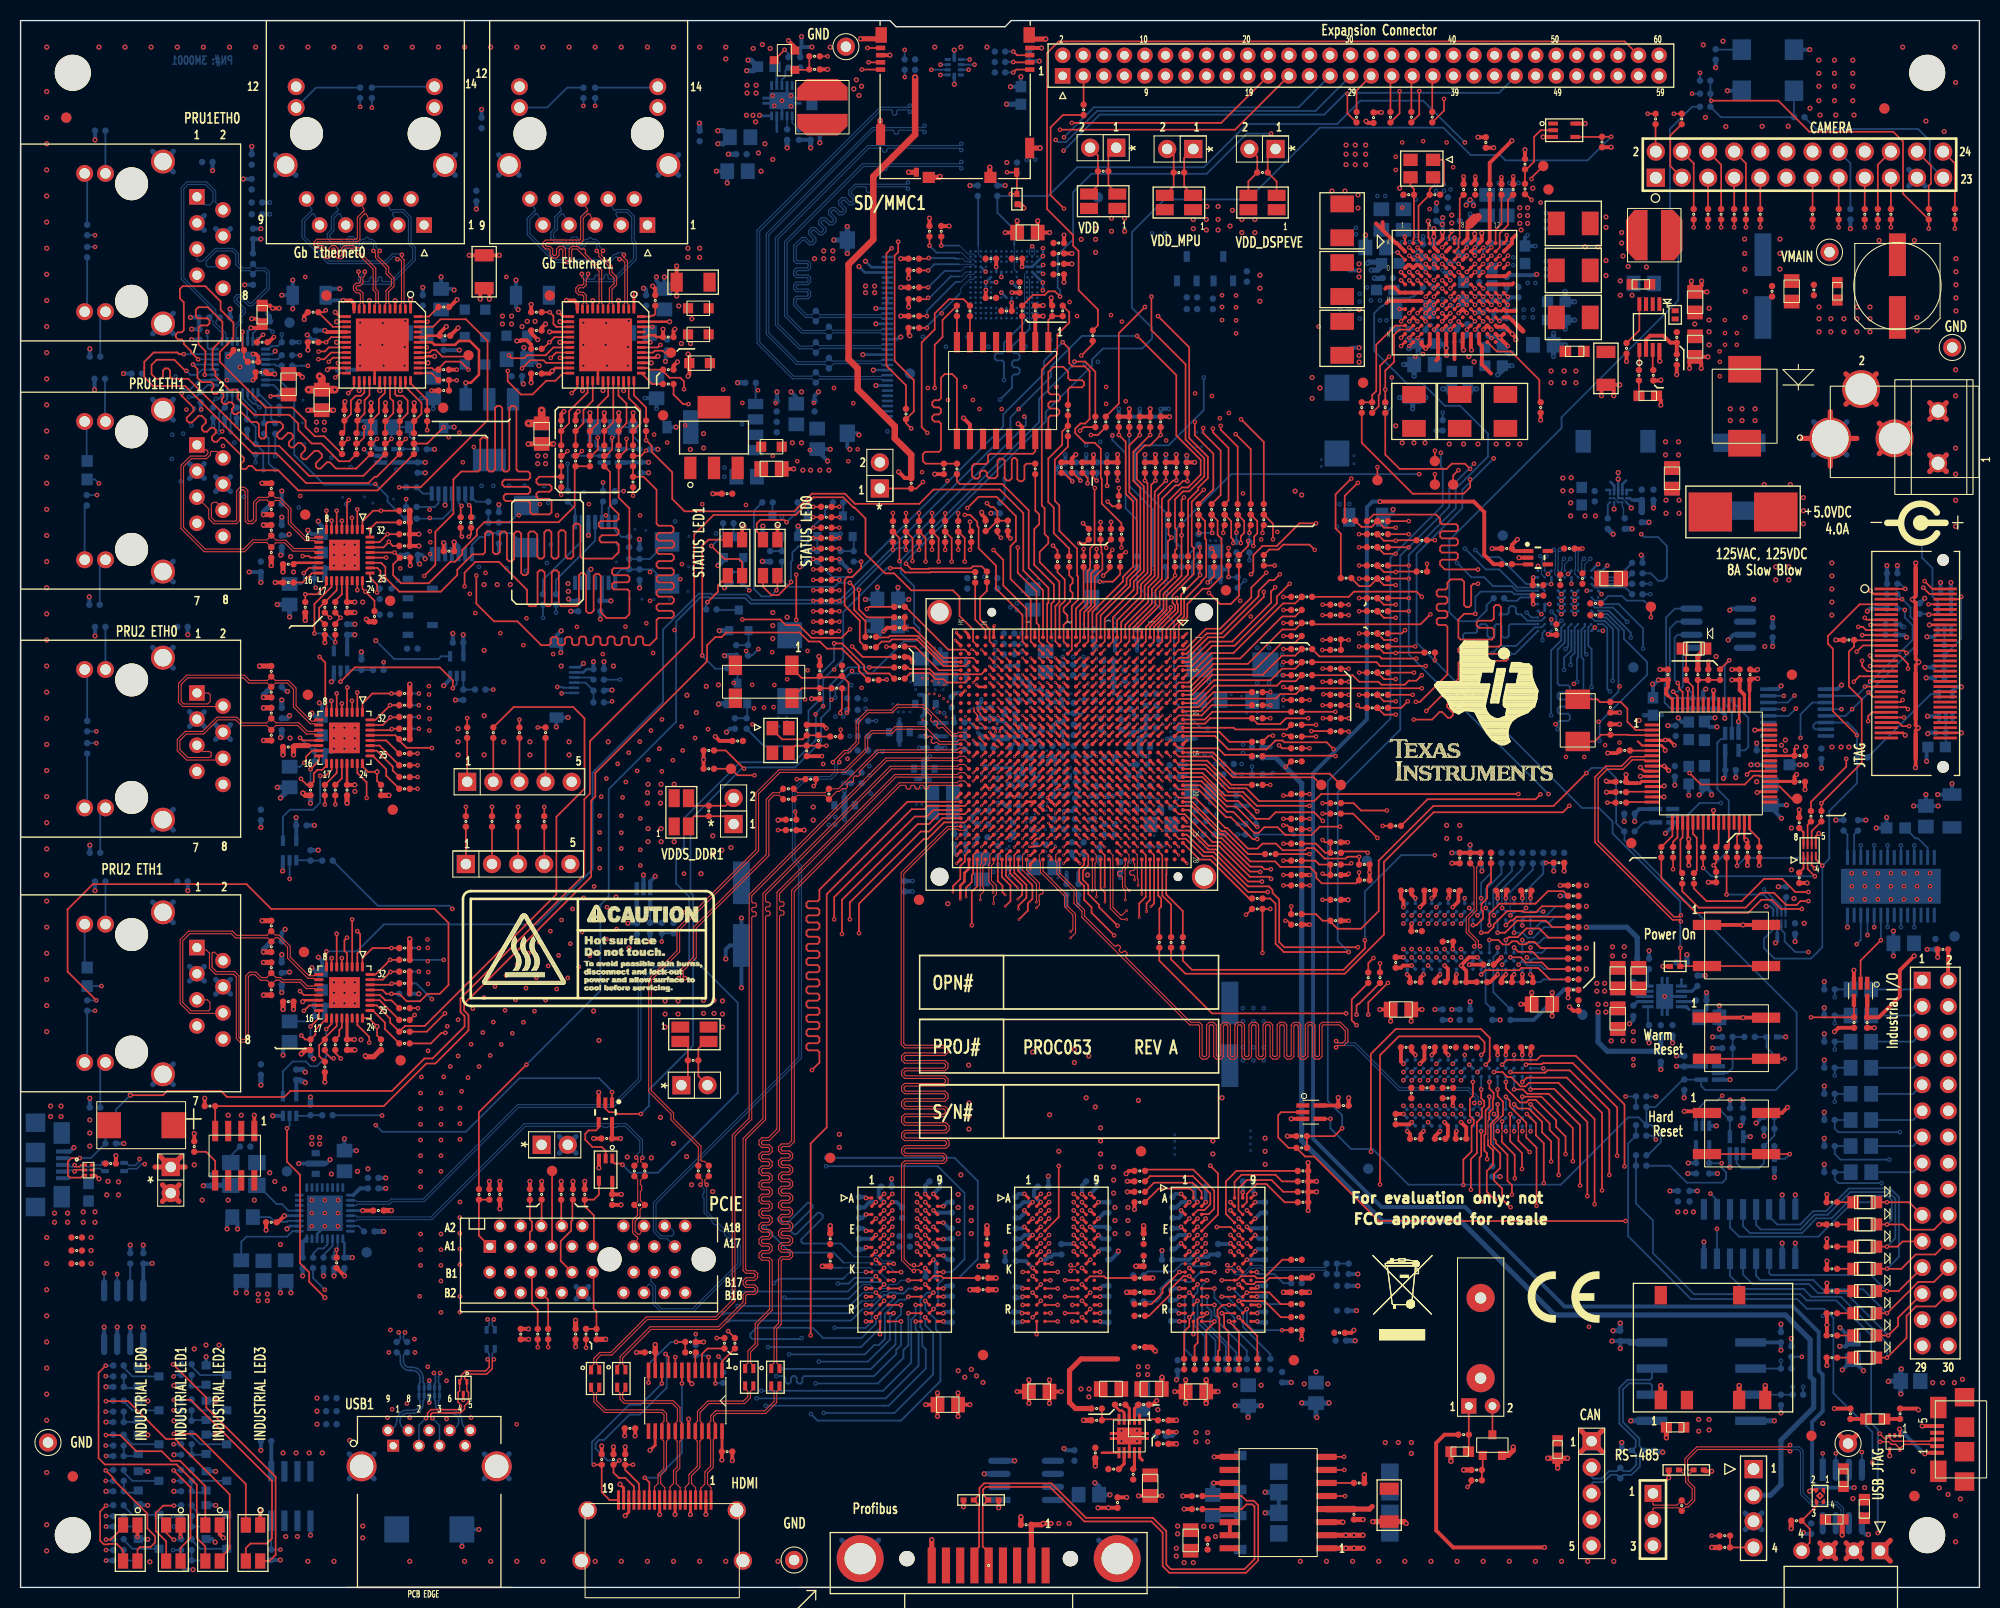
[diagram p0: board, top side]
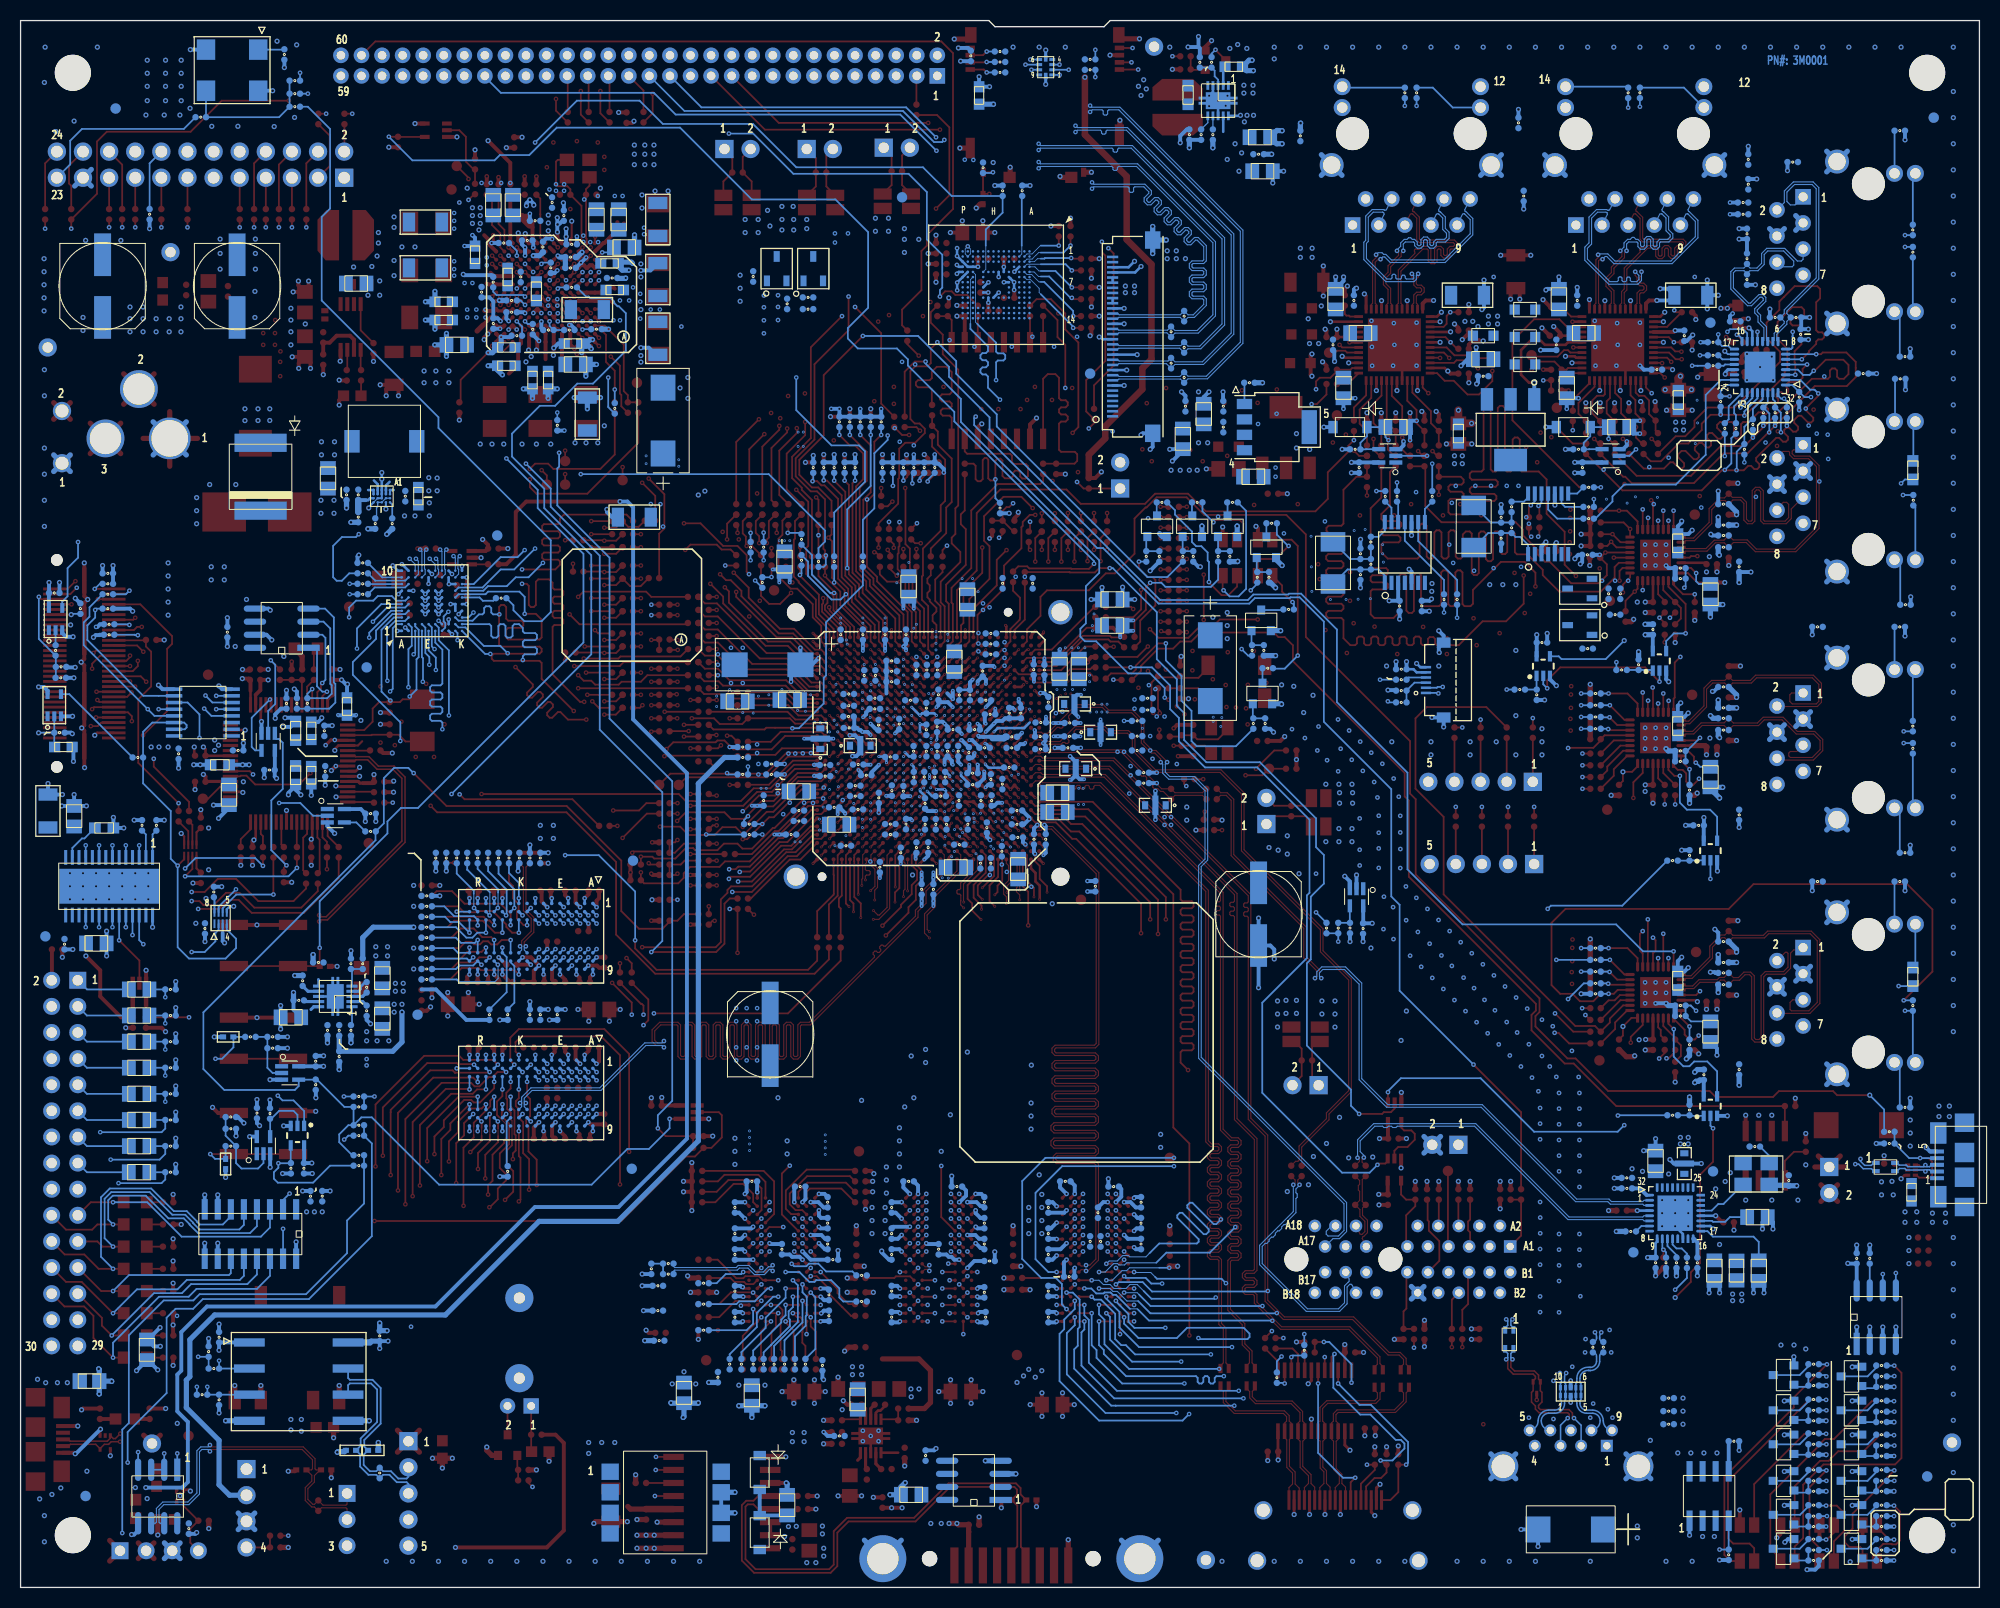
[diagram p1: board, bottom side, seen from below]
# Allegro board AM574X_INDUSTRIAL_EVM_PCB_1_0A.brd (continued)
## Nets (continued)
DGND: C1_1.2 C2_1.2 C3.2 C4.2 C5.2 C6.2 C7.2 C8.2 C9.2 C10.2 C11.2 C12.2 C13.2 C14.2 C15.2 C16.2 C17.2 C20.2 C21.2 C22.2 C23.2 C24.2(NEG) C25.1 C26.1 C27.1 C28.2 C29.2 C30.2 C31.2 C32.2 C33.2 C34.2 C35.2 C36.2 C37.2 C38.2 C39.2 C40.2 C41.2 C42.2 C43.2 C45.2 C46.2 C48.2 C49.2 C50.2 C51.2 C52.2 C53.2 C54.2 C55.2 C56.2 C57.2 C58.2 C59.2 C60.2 C61.2 C62.2 C63.2 C64.2 C65.2 C66.2 C67.2 C68.2 C69.2 C70.2 C71.2 C72.2 C73.2 C74.2 C75.2 C76.2 C77.2 C78.2 C79.2 C81.2 C82.2 C83.2 C84.2 C86.2 C88.2 C90.2 C91.2 C92.2 C93.2 C94.2 C95.2 C96.2 C97.2 C98.2 C99.2 C100.2 C101.2 C102.2 C103.2 C104.2 C105.2 C106.1 C107.2 C108.2 C109.2 C110.2 C111.2 C112.2 C113.2 C114.2 C115.2 C116.2 C117.2 C118.2 C119.2 C120.2 C121.1 C122.2 C123.2 C124.2 C125.2 C126.2 C127.2 C128.2 C129.2 C130.2 C131.1 C132.2 C133.2 C134.2 C135.2 C136.2 C137.2 C138.2 C139.2 C140.2 C141.2 C142.2 C143.2 C144.2 C145.2 C146.1 C147.2 C148.2 C149.2 C150.2 C151.2 C152.2 C153.2 C154.2 C155.2 C156.2 C157.2 C158.2 C159.2 C160.2 C161.2 C162.2 C163.2 C164.2 C165.2 C166.1 C167.1 C168.2 C169.2 C170.2 C171.2 C172.1 C173.1 C174.2 C175.2 C176.2 C177.2 C178.2 C179.2 C180.2 C181.2 C182.2 C183.2 C184.2 C185.2 C186.2 C187.1 C188.1 C189.2 C190.2 C191.2 C192.2 C193.1 C194.1 C195.2 C196.2 C197.2 C198.2 C199.2 C200.2 C201.2 C202.2 C203.2 C204.2 C205.2 C206.2 C207.2 C208.2 C209.2 C210.2 C211.2 C212.2 C213.2 C214.2 C215.2 C216.2 C217.2 C218.2 C219.2 C220.2 C221.2 C222.2 C223.2 C224.2 C225.2 C226.2 C227.2 C228.1 C229.2 C230.1 C231.1 C232.2 C233.2 C234.1 C235.2 C236.2 C237.1 C238.2 C239.2 C240.1 C241.2 C242.1 C243.2 C244.2 C245.2 C246.2 C247.2 C248.2 C249.2 C251.2 C253.2 C254.2 C255.2 C256.2 C257.2 C258.2 C261.2 C262.2 C263.2 C264.2 C265.2 C266.2 C267.2 C268.2 C269.2 C270.2 C271.2 C272.2 C273.2 C274.2 C275.2 C276.2 C277.2 C278.2 C279.2 C280.2 C281.2 C282.2 C283.2 C284.2 C285.2 C286.2 C287.2 C288.2 C289.2 C290.2 C291.2 C292.2 C293.2 C294.2 C295.2 C296.2 C297.2 C298.2 C299.2 C300.2 C301.2 C302.2 C303.2 C304.2 C305.2 C306.2 C307.2 C308.2 C309.2 C310.2 C311.2 C313.2 C315.2 C316.2 C317.2 C318.2 C319.2 C320.2 C321.2 C322.2 C324.2 C326.2 C327.2 C328.2 C329.2 C330.2 C331.2 C332.2 C333.2 C334.2 C335.2 C336.2 C337.2 C338.2 C339.2 C340.2 C341.2 C342.2 C343.2 C344.2 C345.2 C346.2 C347.2 C348.2 C349.2 C350.2 C351.2 C352.2 C353.2 C354.2 C355.2 C356.2 C357.2 C358.2 C359.2 C360.2 C361.2 C362.2 C363.2 C364.2 C365.2 C367.2 C368.2 C369.2 C370.2 C371.2 C372.2 C373.2 C374.2 C375.2 C376.2 C377.2 C378.2 C379.2 C380.2 C381.2 C382.2 C383.2 C384.2 C385.2 C386.2 C387.2 C388.2 C389.2 C390.2 C391.2 C392.2 C393.2 C394.2 C395.2 C396.2 C399.2 C400.2 C401.2 C402.2 C403.2 C404.2 C405.2 C406.2 C407.2 C408.2 C409.2 C410.2 C411.2(NEG) C412.2(NEG) C413.2 C414.2 C415.2 C416.2 C417.2 C418.2 C419.2 C420.2 C421.2 C422.2 C423.2 C424.2 C425.2 C426.2 C427.2 C428.2 C429.2 C432.2 C435.2 C440.2(NEG) C441.2(NEG) C442.2 C443.2 C444.2 C445.2 C446.2 C447.2 C448.2 C449.2 C450.2 C451.2 C452.2 C453.2 C458.2 C459.2 C460.2 C461.2 C462.2 C463.2 C464.2 C465.2 C466.1 C467.1 C468.2 C469.2 C470.2 C471.2 C472.2 C473.2 C474.2 C475.2 C476.2 C479.2 C480.2 C481.2 C482.2 C483.2 C484.2 C485.2 C486.2 C487.2 C488.2 C489.2 C490.2 C491.2 C492.2 C493.2 C494.2 C495.2 C496.2 C497.2 C498.2 C499.2 C500.2 C501.2 C502.2 C504.2 C505.2 C506.2 C507.2 C508.2 C509.2 C510.2 C511.2 C512.2 C513.2 C514.2 C515.2 C516.2 C517.2 C518.2 C519.2 C520.2 C522.2 C523.2 C524.2 C525.2 C527.2 C528.2 C530.2 C531.2 C532.2 C533.2 C534.2 C535.2 C536.2 C537.2 C540.2 C541.2 C542.2 C543.2 C544.2 C545.2 C546.2 C547.2 C548.2 C550.2 C551.2 C552.2 C553.2 C556.2 C557.1 C558.1 C559.1 C560.1 C562.2 C563.2 C564.2 C565.2 C566.2 C567.2 C568.2 C569.2 C570.2 C571.2 C572.2 C573.2 C574.2 C575.2 C576.2 C577.2 C578.2 D2.2 FB12.2 J1.2 J1.3 J1_1.1 J2.2 J3.8 J4.5 J5.8 J6.8 J7.5 J8.8 J9.11 J9.12 J9.21 J10.1 J10.12 J10.13 J12.1 J12.12 J12.13 J15.6(VSS) J15.9(GND) J15.11(GND3) J15.12(GND4) J15.13(GND5) J15.14(GND6) J15.15(GND7) J15.16(GND8) J16.7 J16.10 J16.13 J16.16 J16.19 J16.22 J16.MNT1 J16.MNT2 J17.6 J17.MNT1 J17.MNT2 J18.16(GND#16) J18.57(GND#57) J18.61(GND#61) J18.62(GND#62) J18.63(GND#63) J18.64(GND#64) J19.5(GND) J21.22 J21.39 J21.40 J21.59 J21.60 J22.A4 J22.A12 J22.A15 J22.A18 J22.B4 J22.B7 J22.B13 J22.B16 J22.B17 J22.B18 J23.4(GND) J23.7(GND_DRAIN) J24.2(DAT2_S) J24.5(DAT1_S) J24.8(DAT0_S) J24.11(CLK_S) J24.17(DDC/CEC GND) J24.MTG1 J24.MTG2 J24.MTG3 J24.MTG4 J37.17 J37.29 J37.30 J39.3 J44.2 J45.5(GND) J46.1 L3.2(GND) L21.2(GND) L24.2(GND) L25.2(GND) L26.2(GND) L34.2(GND) L35.2(GND) Q1.S(SOURCE) Q2.S(SOURCE) Q3.S(SOURCE) Q4.S(SOURCE) Q5.S(SOURCE) Q6.S(SOURCE) Q9.S(SOURCE) Q10.S(SOURCE) Q11.S(SOURCE) Q12.S(SOURCE) Q13.S(SOURCE) Q14.S(SOURCE) Q15.S(SOURCE) Q16.S(SOURCE) Q20.S(SOURCE) Q21.S(SOURCE) Q22.S(SOURCE) Q23.S(SOURCE) Q24.S(SOURCE) Q25.S(SOURCE) R2_1.2 R13.2(P2) R16.2(P2) R32.2 R33.2 R34.2 R35.2 R37.2 R38.2 R39.2 R40.2 R41.1(P1) R42.1(P1) R44.1(P1) R48.1 R103.1(P1) R104.1(P1) R108.1(P1) R109.1(P1) R110.1(P1) R111.1(P1) R116.1(P1) R147.1(P1) R155.1(P1) R156.1(P1) R157.1(P1) R158.1(P1) R186.1(P1) R187.1(P1) R191.1(P1) R192.1(P1) R193.1(P1) R194.1(P1) R228.1(P1) R235.1(P1) R236.1(P1) R237.1(P1) R238.1(P1) R245.1(P1) R246.1(P1) R251.1(P1) R252.1(P1) R255.1(P1) R256.1(P1) R298.2 R304.1(P1) R317.1(P1) R319.1(P1) R321.1(P1) R341.2 R348.1(P1) R361.1(P1) R363.1(P1) R380.1(P1) R381.1(P1) R382.1(P1) R414.1(P1) R415.1 R417.1 R425.2 R427.1(P1) R430.2 R431.2 R432.2 R433.1(P1) R453.1 R454.1 R455.1 R456.1 R457.1 R458.1 R459.1 R460.1 R461.1 R462.1 R463.1 R464.1 R465.1 R466.1 R467.1 R468.1 R479.2(P2) R484.1(P1) R489.1(P1) R494.1 R515.1(P1) R539.1 R542.1 R547.2(P2) R550.2(P2) R553.2 R561.1 R569.2(P2) R570.2 R571.2 R579.1(P1) R587.2(P2) R591.1(P1) R592.1(P1) R595.1(P1) R597.1(P1) R599.1(P1) R643.2(P2) R648.1(P1) R680.1 R695.1(P1) R697.1(P1) R700.1(P1) R704.1(P1) R706.1(P1) R709.1(P1) R754.1(P1) R755.1(P1) R785.1 R791.2 R793.1(P1) R798.1 R810.2 R812.2(P2) R813.2(P2) R912.1 R913.1 R923.2(P2) R924.2(P2) R925.2(P2) R927.1(P1) R928.1(P1) R934.2(P2) SCKT1.MCH2 SCKT1.MCH4 SW1.1 SW1.2 SW2.1 SW2.2 SW3.1 SW3.2 TP1_1.1 TP8.1 TP9.1 TP10.1 TP11.1 U1.A1(VSS#A1) U1.A2(VSS#A2) U1.A6(VSS#A6) U1.A14(VSS#A14) U1.A23(VSS#A23) U1.A28(VSS#A28) U1.AA8(VSS#AA8) U1.AA9(VSS#AA9) U1.AA10(VSS#AA10) U1.AA11(VSSA_USB#AA11) U1.AA14(VSS#AA14) U1.AA15(VSS#AA15) U1.AA20(VSS#AA20) U1.AB11(VSSA_USB#AB11) U1.AB14(VSS#AB14) U1.AB20(VSS#AB20) U1.AC14(VSSA_OSC1) U1.AD1(VSS#AD1) U1.AD10(VSSA_USB3) U1.AD13(VSSA_PCIE#AD13) U1.AD19(VSSA_HDMI#AD19) U1.AD24(VSS#AD24) U1.AE10(VSSA_SATA) U1.AE13(VSSA_PCIE#AE13) U1.AE19(VSSA_HDMI#AE19) U1.AG1(VSS#AG1) U1.AH1(VSS#AH1) U1.AH2(VSS#AH2) U1.AH8(VSS#AH8) U1.AH20(VSS#AH20) U1.AH28(VSS#AH28) U1.B1(VSS#B1) U1.D13(VSS#D13) U1.D19(VSS#D19) U1.E13(VSS#E13) U1.E19(VSS#E19) U1.F1(VSS#F1) U1.F7(VSS#F7) U1.G7(VSS#G7) U1.G8(VSS#G8) U1.G9(VSS#G9) U1.H12(VSS#H12) U1.J12(VSS#J12) U1.J15(VSS#J15) U1.J28(VSS#J28) U1.K1(VSS#K1) U1.K4(VSS#K4) U1.K5(VSS#K5) U1.K15(VSS#K15) U1.K24(VSS#K24) U1.K25(VSS#K25) U1.L13(VSS#L13) U1.L14(VSS#L14) U1.M19(VSS#M19) U1.N14(VSS#N14) U1.N15(VSS#N15) U1.N19(VSS#N19) U1.N24(VSS#N24) U1.N25(VSS#N25) U1.P28(VSS#P28) U1.R1(VSS#R1) U1.R12(VSS#R12) U1.R13(VSS#R13) U1.R15(VSS#R15) U1.R21(VSS#R21) U1.T10(VSS#T10) U1.T11(VSS#T11) U1.T12(VSS#T12) U1.T14(VSS#T14) U1.T15(VSS#T15) U1.T17(VSS#T17) U1.T18(VSS#T18) U1.T21(VSS#T21) U1.U14(VSSA_VIDEO) U1.U15(VSS#U15) U1.U17(VSS#U17) U1.U20(VSS#U20) U1.U21(VSS#U21) U1.V15(VSS#V15) U1.V17(VSS#V17) U1.W1(VSS#W1) U1.W15(VSS#W15) U1.W24(VSS#W24) U1.W25(VSS#W25) U1.W28(VSS#W28) U1_1.2(GND) U1_1.TPAD U2.3(GND) U3.A1(PKG_GND_A1) U3.A4(REFGND1) U3.A7(GNDANA#A7) U3.A13(PKG_GND#A13) U3.B2(GPADC_IN0) U3.B8(SYNCDCDC) U3.B10(PKG_GND#B10) U3.B11(PKG_GND#B11) U3.C2(GPADC_IN1) U3.C3(GPADC_IN2) U3.C12(SMPS12_FBK_GND) U3.D4(SMPS7_GND#D4) U3.D5(SMPS7_GND#D5) U3.D6(PKG_GND#D6) U3.D7(PKG_GND#D7) U3.D10(SMPS1_GND#D10) U3.E4(SMPS7_GND#E4) U3.E7(GNDANA#E7) U3.E8(PKG_GND#E8) U3.E9(SMPS1_GND#E9) U3.E10(SMPS1_GND#E10) U3.F4(SMPS4_GND#F4) U3.F5(GNDANA#F5) U3.F6(PKG_GND#F6) U3.F7(PKG_GND#F7) U3.F9(SMPS2_GND#F9) U3.F10(SMPS2_GND#F10) U3.G4(SMPS4_GND#G4) U3.G5(SMPS4_GND#G5) U3.G7(PKG_GND#G7) U3.G10(SMPS2_GND#G10) U3.H4(SMPS5_GND#H4) U3.H5(SMPS5_GND#H5) U3.H6(PKG_GND#H6) U3.H7(PKG_GND#H7) U3.H10(SMPS3_GND#H10) U3.J4(SMPS5_GND#J4) U3.J6(PKG_GND#J6) U3.J9(SMPS3_GND#J9) U3.J10(SMPS3_GND#J10) U3.K3(SMPS45_FDBK_GND) U3.L5(SMPS6_GND#L5) U3.L6(SMPS6_GND#L6) U3.L7(SMPS9_GND#L7) U3.L8(SMPS9_GND#L8) U3.L9(SMPS8_GND#L9) U3.L10(SMPS8_GND#L10) U3.M1(PKG_GND#M1) U3.M2(PKG_GND#M2) U3.M12(GNDDIG) U3.M13(GNDANA#M13) U3.N1(PKG_GND#N1) U3.N2(VIO_GND) U3.N13(PKG_GND#N13) U4.10(VSS) U5.A9(VSS#A9) U5.B1(VSSQ#B1) U5.B3(VSS#B3) U5.B9(VSSQ#B9) U5.D1(VSSQ#D1) U5.D8(VSSQ#D8) U5.E1(VSS#E1) U5.E2(VSSQ#E2) U5.E8(VSSQ#E8) U5.F9(VSSQ#F9) U5.G1(VSSQ#G1) U5.G8(VSS#G8) U5.G9(VSSQ#G9) U5.J2(VSS#J2) U5.J8(VSS#J8) U5.M1(VSS#M1) U5.M9(VSS#M9) U5.P1(VSS#P1) U5.P9(VSS#P9) U5.T1(VSS#T1) U5.T9(VSS#T9) U6.A9(VSS#A9) U6.B1(VSSQ#B1) U6.B3(VSS#B3) U6.B9(VSSQ#B9) U6.C7(UDQS) U6.D1(VSSQ#D1) U6.D3(UDM) U6.D8(VSSQ#D8) U6.E1(VSS#E1) U6.E2(VSSQ#E2) U6.E8(VSSQ#E8) U6.F9(VSSQ#F9) U6.G1(VSSQ#G1) U6.G8(VSS#G8) U6.G9(VSSQ#G9) U6.J2(VSS#J2) U6.J8(VSS#J8) U6.M1(VSS#M1) U6.M9(VSS#M9) U6.P1(VSS#P1) U6.P9(VSS#P9) U6.T1(VSS#T1) U6.T9(VSS#T9) U7.A9(VSS#A9) U7.B1(VSSQ#B1) U7.B3(VSS#B3) U7.B9(VSSQ#B9) U7.D1(VSSQ#D1) U7.D8(VSSQ#D8) U7.E1(VSS#E1) U7.E2(VSSQ#E2) U7.E8(VSSQ#E8) U7.F9(VSSQ#F9) U7.G1(VSSQ#G1) U7.G8(VSS#G8) U7.G9(VSSQ#G9) U7.J2(VSS#J2) U7.J8(VSS#J8) U7.M1(VSS#M1) U7.M9(VSS#M9) U7.P1(VSS#P1) U7.P9(VSS#P9) U7.T1(VSS#T1) U7.T9(VSS#T9) U8.4(PGND) U8.8(GND) U8.11(PWRPD) U9.TPAD U13.TPAD U15.TPAD U17.TPAD U18.M1 U18.M2 U19.3(GND) U21.13(VSS_PS) U21.29(VSS) U21.49(P_GND) U22.3(GND) U23.5(GND1) U23.10(GND2) U24.13(VSS_PS) U24.29(VSS) U24.49(P_GND) U25.5(GND1) U25.10(GND2) U26.3(GND) U28.3(GND) U30.5(GND) U32.4(GND) U32.8(PGND) U32.PAD(TPAD) U33.1(A0) U33.2(A1) U33.3(A2) U33.4(VSS) U34.3(GND) U35.3(GND) U36.4(GND) U37.1(GND.1) U37.5(GND.2) U37.10(AGND) U37.11(GND.3) U37.13(TEST) U37.15(GND.4) U37.25(GND.5) U37.35(GND.6) U37.47(GND.7) U37.51(GND.8) U38.5(VSS) U38.7(NC1) U39.3(GND) U40.1(VIN-) U41.4(GND1) U43.C4(VSSQ#C4) U43.E7(VSS#E7) U43.G5(VSS#G5) U43.H10(VSS#H10) U43.K8(VSS#K8) U43.N2(VSSQ#N2) U43.N5(VSSQ#N5) U43.P4(VSSQ#P4) U43.P6(VSSQ#P6) U44.3(GND) U45.14(GND#14) U45.22(GND#22) U45.TPAD(PWRPAD) U46.6(GND#6) U46.14(GND#14) U46.19(GND#19) U47.3(GND) U48.2 U49.2 U50.2 U62.B4(SYNC) U62.C1(PGND#C1) U62.C2(PGND#C2) U62.C3(GND#C3) U62.D3(GND#D3) U62.E4(GND#E4) U63.8(GND#8) U63.9(GND#9) U64.3(GND) U65.5(GND) U66.1(GND) U68.3(GND) U69.3(GND) U70.3(GND) U71.3(GND) U72.28(GND) U72.TH_PD(THRM) U73.7(A2) U73.8(G\) U73.9(A0) U73.10(A1) U73.16(GND) U74.3(GND1) U75.5(GND) U76.2(GND) U77.5(GND) U78.3(GND) U79.4(GND) U82.2 U83.2 U84.2 U85.3(GND) U86.5(GND) U89.A1(VSS#A1) U89.A10(VSS#A10) U89.B7(VSS#B7) U89.D4(VSS#D4) U89.D5(VSS#D5) U89.D6(VSS#D6) U89.D7(VSS#D7) U89.E4(VSS#E4) U89.E5(VSS#E5) U89.E6(VSS#E6) U89.E7(VSS#E7) U89.E9(VSS#E9) U89.F4(VSS#F4) U89.F5(VSS#F5) U89.F6(VSS#F6) U89.F7(VSS#F7) U89.G4(VSS#G4) U89.G5(VSS#G5) U89.G6(VSS#G6) U89.G7(VSS#G7) U89.H2(VSS#H2) U89.H9(VSS#H9) U89.J4(VSS#J4) U89.J5(VSS#J5) U89.J8(CS) U89.K10(VSS#K10) U90.A9(VSS#A9) U90.B1(VSSQ#B1) U90.B3(VSS#B3) U90.B9(VSSQ#B9) U90.D1(VSSQ#D1) U90.D8(VSSQ#D8) U90.E1(VSS#E1) U90.E2(VSSQ#E2) U90.E8(VSSQ#E8) U90.F9(VSSQ#F9) U90.G1(VSSQ#G1) U90.G8(VSS#G8) U90.G9(VSSQ#G9) U90.J2(VSS#J2) U90.J8(VSS#J8) U90.M1(VSS#M1) U90.M9(VSS#M9) U90.P1(VSS#P1) U90.P9(VSS#P9) U90.T1(VSS#T1) U90.T9(VSS#T9) U91.A9(VSS#A9) U91.B1(VSSQ#B1) U91.B3(VSS#B3) U91.B9(VSSQ#B9) U91.D1(VSSQ#D1) U91.D8(VSSQ#D8) U91.E1(VSS#E1) U91.E2(VSSQ#E2) U91.E8(VSSQ#E8) U91.F9(VSSQ#F9) U91.G1(VSSQ#G1) U91.G8(VSS#G8) U91.G9(VSSQ#G9) U91.J2(VSS#J2) U91.J8(VSS#J8) U91.M1(VSS#M1) U91.M9(VSS#M9) U91.P1(VSS#P1) U91.P9(VSS#P9) U91.T1(VSS#T1) U91.T9(VSS#T9) U92.4(PGND) U92.8(GND) U92.11(PWRPD) U93.4(GND) U94.1(GND) U95.3(GND#3) U95.8(GND#8) U96.3(GND) U97.3(GND) U98.3(GND) X1.2(GND) Y7.2(GND)
GND_CAN1: C250.2 C252.2 J38.4 U40.4(VOUT-#4) U40.5(VOUT-#5) U41.5(GND2) U87.2 U88.2
GND_OSC0: C1.2 C2.2 R13.1(P1) U1.AF15(VSSA_OSC0)
GNDPROFI: C323.2(NEG) C325.2(NEG) C430.2 C431.2 C433.2 C434.2 J14.5 L2.6 L2.7 R573.1(P1) R578.1(P1) U52.3(GND) U52.4(E\N\) U74.9(GND2#9) U74.11(GND2#11) U74.14(GND2#14) U74.15(GND2#15) U80.2 U81.2
GNDUSB1: C557.2 C558.2 J23.S1 J23.S2 R812.1(P1)
GNDUSB2: C559.2 C560.2 J45.S1 J45.S2 J45.S3 J45.S4 R813.1(P1)
GNDUSBJ: FB12.1 J19.S1 J19.S2 J19.S3 J19.S4
V1_2D: C480.1 C481.1 C484.1 FB19.1 U76.5(OUT) U89.A7(VDDC#A7) U89.B1(VDDC#B1) U89.K4(VDDC#K4)
V1_2D_EN: R451.1(P1) U76.3(EN)
V1_8D: C1_1.1 C169.1 C190.1 C368.1 C372.1 C373.1 C374.1 C375.1 C376.1 C377.1 C378.1 C379.1 C405.1 C406.1 D24.3(ANODE) D25.3(ANODE) Q26.3(COLLECTOR) Q27.3(COLLECTOR) R1_1.2(P2) R451.2(P2) R658.1(P1) R897.1 R901.1 R933.1(P1) U1.AA7(VDDS_MLBP#AA7) U1.AA18(VDDS18V_DDR1#AA18) U1.AA19(VDDS18V_DDR1#AA19) U1.G18(VDDS18V#G18) U1.H17(VDDS18V#H17) U1.J21(VDDS18V_DDR2#J21) U1.J22(VDDS18V_DDR2#J22) U1.M8(VDDS18V#M8) U1.M9(VDDS18V#M9) U1.N8(VDDS18V#N8) U1.N21(VDDS18V_DDR2#N21) U1.P8(VDDS18V#P8) U1.P20(VDDS18V_DDR2#P20) U1.P21(VDDS18V_DDR2#P21) U1.R8(VDDS18V#R8) U1.T8(VDDS18V#T8) U1.V21(VDDS18V#V21) U1.V22(VDDS18V#V22) U1.W17(VDDS18V#W17) U1.W18(VDDS18V#W18) U1.W21(VDDS18V_DDR1#W21) U1.Y7(VDDS_MLBP#Y7) U1.Y21(VDDS18V_DDR1#Y21) U1_1.1(OUT) U23.3(VDD) U25.3(VDD)
V1_8D_OUT: J1_1.2 R1_1.1(P1)
V1_8FTDI: C227.1 C232.1 C235.1 C238.1 C241.1 U37.12(VCORE.1) U37.37(VCORE.2) U37.49(VREGOUT) U37.64(VCORE.3)
V1_8PHY_HDMI: C566.1 C567.1 C568.1 L35.3(OUT) U1.Y17(VDDA_HDMI)
V1_8PHY_LDO3: C392.1 L25.1(IN) L34.1(IN) U3.K11(LDO3_OUT)
V1_8PHY_LDO4: L26.1(IN) L35.1(IN) R854.1(P1)
V1_8PHY_PCIE: C393.1 C394.1 C447.1 L26.3(OUT) U1.AA16(VDDA_PCIE1) U1.AA17(VDDA_PCIE0) U1.W14(VDDA_PCIE)
V1_8PHY_SATA: C563.1 C564.1 C565.1 L34.3(OUT) U1.V13(VDDA_SATA)
V1_8PHY_USB: C390.1 C391.1 C446.1 L25.3(OUT) U1.AA13(VDDA_USB1) U1.AB12(VDDA_USB2) U1.W12(VDDA_USB3)
V1_8PLL: C382.1 L21.1(IN) L24.1(IN) U1.AD16(VDDA_OSC#AD16) U1.AE16(VDDA_OSC#AE16) U3.B5(LDOLN_OUT)
V1_8PLLA: C380.1 C381.1 C442.1 L21.3(OUT) U1.M14(VDDA_ABE_PER) U1.N16(VDDA_MPU) U1.R14(VDDA_GPU) U1.R17(VDDA_IVA)
V1_8PLLB: C388.1 C389.1 C445.1 L24.3(OUT) U1.N11(VDDA_DEBUG) U1.N12(VDDA_DSP_EVE) U1.P14(VDDA_VIDEO) U1.P15(VDDA_GMAC_CORE) U1.P16(VDDA_DDR)
V3_3ACDCM: C320.1 C321.1 C322.1 C324.1 L3.3(OUT) U45.1(VDD2_OUT1) U45.4(VDD1_OUT0)
V3_3APCIE: C307.1 C308.1 C309.1 C310.1 C326.1 FB13.1 R546.2 R548.2 R549.2 U45.9(VDD#9) U45.16(VDD#16) U45.18(VDD#18) U45.20(VDD#20) Y7.4(VCC)
V3_3AUX_PCIE: C556.1 J22.B10 J49.2 R654.2
V3_3D: C2_1.1 C3.1 C28.1 C88.1 C104.1 C105.1 C107.1 C113.1 C119.1 C120.1 C122.1 C127.1 C130.1 C132.1 C133.1 C139.1 C143.1 C144.1 C145.1 C151.1 C170.1 C191.1 C209.1 C210.1 C211.1 C212.1 C214.1 C219.1 C220.1 C221.1 C248.1 C249.1 C251.1 C255.1 C256.1 C257.1 C258.1 C261.1 C262.1 C263.1 C264.1 C319.1 C350.1 C360.1 C361.1 C362.1 C363.1 C364.1 C365.1 C367.1 C384.1 C385.1 C386.1 C408.1 C409.1 C410.1 C420.1 C426.1 C428.1 C432.1 C435.1 C444.1 C449.1 C450.1 C451.1 C469.1 C470.1 C479.1 C532.1 C569.1 C571.1 D16.1(A) D17.1(A) D18.1(A) D19.1(A) D22.1(A) D23.1(A) FB1.1 FB5.1 FB13.2 J1_1.3 J15.4(VDD) J17.5 J21.1 J22.A9 J22.A10 J22.B8 J46.3 J49.1 L2.2 L2.3 L3.1(IN) Q26.2(EMMITTER) R2.2 R8.2(P2) R10.2 R18.2 R22.2 R56.2(P2) R67.2(P2) R76.2(P2) R77.2(P2) R78.2(P2) R89.2(P2) R97.1(P1) R99.1(P1) R100.1(P1) R101.1(P1) R102.1(P1) R107.2 R120.2(P2) R121.2(P2) R122.2(P2) R131.2(P2) R134.2(P2) R141.1(P1) R143.1(P1) R144.1(P1) R145.1(P1) R146.1(P1) R149.2 R152.2(P2) R153.2 R159.2(P2) R160.2(P2) R161.2(P2) R172.2(P2) R180.1(P1) R182.1(P1) R183.1(P1) R184.1(P1) R185.1(P1) R190.2 R200.2(P2) R201.2(P2) R202.2(P2) R203.2(P2) R214.2(P2) R222.1(P1) R224.1(P1) R225.1(P1) R226.1(P1) R227.1(P1) R232.2(P2) R233.2 R259.2 R278.2(P2) R322.2(P2) R366.2 R383.2(P2) R384.2(P2) R410.2(P2) R412.2 R417.2 R419.2(P2) R420.1 R421.2 R422.2(P2) R423.2(P2) R434.2(P2) R435.2(P2) R436.2(P2) R437.2(P2) R438.2(P2) R439.2(P2) R440.2(P2) R441.2(P2) R442.2(P2) R443.2(P2) R444.2(P2) R445.2(P2) R446.2(P2) R447.2(P2) R448.2(P2) R449.2(P2) R450.2(P2) R472.2(P2) R498.2 R505.2(P2) R506.2(P2) R507.2(P2) R508.2(P2) R509.2(P2) R510.2(P2) R511.2(P2) R512.2(P2) R513.2(P2) R543.1 R544.1 R545.2 R551.2 R556.2(P2) R559.2(P2) R563.2(P2) R637.1 R649.2 R678.2(P2) R679.2(P2) R730.2(P2) R731.2(P2) R741.2 R742.1(P1) R782.2(P2) R783.2(P2) R790.2 R799.2 R800.2 R804.2 R805.2 R808.2 R811.1 R814.1 R894.2 R896.2 R902.2 R914.2 R917.2 U1.AB6(VDDSHV7#AB6) U1.AB7(VDDSHV7#AB7) U1.AD5(VDDSHV6#AD5) U1.AD7(VDDSHV6#AD7) U1.AE7(VDDSHV6#AE7) U1.AF5(VDDSHV6#AF5) U1.B6(VDDSHV2#B6) U1.B23(VDDSHV3#B23) U1.C24(VDDSHV4) U1.D10(VDDSHV2#D10) U1.D16(VDDSHV3#D16) U1.D22(VDDSHV3#D22) U1.E3(VDDSHV1#E3) U1.E5(VDDSHV1#E5) U1.E10(VDDSHV2#E10) U1.E16(VDDSHV3#E16) U1.E22(VDDSHV3#E22) U1.G4(VDDSHV1#G4) U1.G5(VDDSHV1#G5) U1.G15(VDDSHV3#G15) U1.H8(VDDSHV1#H8) U1.H9(VDDSHV1#H9) U1.H10(VDDSHV2#H10) U1.H11(VDDSHV2#H11) U1.H15(VDDSHV3#H15) U1.H16(VDDSHV3#H16) U1.H18(VDDSHV3#H18) U1.H19(VDDSHV3#H19) U1.J8(VDDSHV11#J8) U1.K8(VDDSHV11#K8) U1.N4(VDDSHV10#N4) U1.N5(VDDSHV10#N5) U1.P10(VDDSHV10#P10) U1.R7(VDDSHV10#R7) U1.R10(VDDSHV10#R10) U1.T4(VDDSHV10#T4) U1.T5(VDDSHV10#T5) U1.U10(VDDSHV9#U10) U1.V12(VDDSHV5) U1.W4(VDDSHV9#W4) U1.W5(VDDSHV9#W5) U1_1.4(IN) U2.5(VCC) U3.D9(VIO_IN) U3.J8(SMPS9_FBK) U4.2(VCC) U4.14(VIO/RFU) U8.10(VIN) U9.21(VDD33_IO) U13.21(VDD33_IO) U15.21(VDD33_IO) U17.21(VDD33_IO) U19.5(VCC) U23.6(VDDOUT1) U23.7(VDDOUT2) U25.6(VDDOUT1) U25.7(VDDOUT2) U30.10(VCC) U33.8(VCC) U39.2(A) U39.5(VCC) U40.2(VIN+) U41.1(VCC1) U43.C6(VCCQ#C6) U43.E6(VCC#E6) U43.F5(VCC#F5) U43.J10(VCC#J10) U43.K9(VCC#K9) U43.M4(VCCQ#M4) U43.N4(VCCQ#N4) U43.P3(VCCQ#P3) U43.P5(VCCQ#P5) U44.5(VCC) U46.24(VCCA) U47.5(VCC) U63.16(VCCB) U65.8(VCCB) U68.5(VCC) U69.5(VCC) U70.5(VCC) U71.5(VCC) U73.1(VCC) U74.4(VCC1) U75.1(VCCA) U75.3(A2) U77.8(VCC) U78.5(VCC) U85.5(VCC) U89.B10(VDDIO#B10) U89.H1(VDDIO#H1) U89.K5(VDDIO#K5) U89.K9(VDDIO#K9) U92.10(VIN) U97.5(VCC) U98.5(VCC) X1.4(VCC)
V3_3D_PROFIA: L2.4 U74.1(D1)
V3_3D_PROFIB: L2.1 U74.2(D2)
V3_3D_PRU1ETH0JCK: C102.1 C103.1 J3.3 J3.4 R77.1(P1)
V3_3D_PRU1ETH1JCK: C116.1 C117.1 J5.3 J5.4 R121.1(P1)
V3_3D_PRU2ETH0JCK: C128.1 C129.1 J6.3 J6.4 R160.1(P1)
V3_3D_PRU2ETH1JCK: C140.1 C141.1 J8.3 J8.4 R202.1(P1)
V3_3FTDI: C224.1 C228.2 C229.1 C230.2 C233.1 C236.1 C239.1 C242.2 C245.1 C425.1 C443.1 C448.1 FB10.2 FB11.2 R472.1(P1) R485.2 R496.2 U34.5(VCC) U35.5(VCC) U37.20(VCCIO.1) U37.31(VCCIO.2) U37.42(VCCIO.3) U37.50(VREGIN) U37.56(VCCIO.4) U38.6(NC2) U38.8(VCC) U63.1(VCCA) U63.2(1DIR) U63.3(2DIR) U65.1(VCCA) U75.8(VCCB)
V3_3USB: C399.1 C400.1 C401.1 U1.AA12(VDDA33V_USB1) U1.Y12(VDDA33V_USB2) U3.B9(LDOUSB_OUT)
V3_7LCD: C222.1 C315.1 C472.1 J16.3 J16.4 J16.5 R681.1 U86.3(VOUT)
V5_0D: C208.1 C418.1 C419.1 C427.1 C476.1 J21.2 J37.27 J37.28 R386.1(P1) R388.1(P1) R389.1(P1) R390.1(P1) R391.1(P1) R392.1(P1) R395.1(P1) R396.1(P1) R424.2(P2) R560.2(P2) R562.2(P2) U46.11(VCC5V) U62.E1(VOUT#E1) U62.E2(VOUT#E2) U66.2(IN#2) U66.3(IN#3) U94.2(IN#2) U94.3(IN#3)
V5_0D_EN: R419.1(P1) U62.A4(EN)
V5_0DFB: R424.1(P1) R427.2(P2) U62.E3(FB)
V5_0HDMICONN: C429.1 J24.18(+5V) U46.13(5V_OUT)
V5_0VOP: C195.1 C205.1 C207.1 U28.5(VCC) U72.15(5VOP)
V12_0D: C196.1 C303.1 C304.1 C461.1 C462.1 D20.1(CATHODE) J22.A2 J22.A3 J22.B1 J22.B2 J22.B3 J37.2 J37.4 J37.6 J37.8 J37.10 J37.12 J37.14 J37.16 R379.1 R647.2(P2)
VDD_CORE: C339.1 C340.1 C341.1 C342.1 C343.1 C344.1 C345.1 C387.1 C473.1 C572.1 C573.1 C574.1 C575.1 C576.1 C577.1 R640.2(I2) R931.1(P1) U1.H13(VDD#H13) U1.H14(VDD#H14) U1.J17(VDD#J17) U1.J18(VDD#J18) U1.L7(VDD#L7) U1.L8(VDD#L8) U1.N10(VDD#N10) U1.N13(VDD#N13) U1.P11(VDD#P11) U1.P12(VDD#P12) U1.P13(VDD#P13) U1.R11(VDD#R11) U1.R16(VDD#R16) U1.R19(VDD#R19) U1.T13(VDD#T13) U1.T16(VDD#T16) U1.T19(VDD#T19) U1.U8(VDD#U8) U1.U9(VDD#U9) U1.U13(VDD#U13) U1.U16(VDD#U16) U1.V8(VDD#V8) U1.V16(VDD#V16) U3.B1(SMPS7_FDBK)
VDD_DSPEVE: C353.1 C354.1 C355.1 C356.1 C357.1 C358.1 C359.1 C414.1 C422.1 C423.1 C475.1 R642.2(I2) U1.J13(VDD_DSPEVE#J13) U1.K10(VDD_DSPEVE#K10) U1.K11(VDD_DSPEVE#K11) U1.K12(VDD_DSPEVE#K12) U1.K13(VDD_DSPEVE#K13) U1.L10(VDD_DSPEVE#L10) U1.L11(VDD_DSPEVE#L11) U1.L12(VDD_DSPEVE#L12) U1.M10(VDD_DSPEVE#M10) U1.M11(VDD_DSPEVE#M11) U1.M12(VDD_DSPEVE#M12) U1.M13(VDD_DSPEVE#M13) U3.K2(SMPS45_FDBK)
VDD_GPU: C266.1 C267.1 C268.1 C327.1 C328.1 C329.1 C330.1 C331.1 C396.1 L17.2 U1.U11(VDD_GPU#U11) U1.U12(VDD_GPU#U12) U1.V10(VDD_GPU#V10) U1.V11(VDD_GPU#V11) U1.V14(VDD_GPU#V14) U1.W10(VDD_GPU#W10) U1.W11(VDD_GPU#W11) U1.W13(VDD_GPU#W13) U3.K6(SMPS6_FBK)
VDD_IVA: C270.1 C346.1 C347.1 C348.1 C349.1 C351.1 C413.1 L19.2 U1.U18(VDD_IVA#U18) U1.U19(VDD_IVA#U19) U1.V18(VDD_IVA#V18) U1.V19(VDD_IVA#V19) U3.L11(SMPS8_FDBK)
VDD_MIPI: C424.1 C482.1 FB19.2 U89.E10(VDD_MIPI#E10) U89.H10(VDD_MIPI#H10)
VDD_MPU: C332.1 C333.1 C334.1 C335.1 C336.1 C337.1 C338.1 C352.1 C369.1 C370.1 C371.1 C395.1 C474.1 R641.2(I2) U1.K17(VDD_MPU#K17) U1.K18(VDD_MPU#K18) U1.L15(VDD_MPU#L15) U1.L16(VDD_MPU#L16) U1.L17(VDD_MPU#L17) U1.L18(VDD_MPU#L18) U1.L19(VDD_MPU#L19) U1.M15(VDD_MPU#M15) U1.M16(VDD_MPU#M16) U1.M17(VDD_MPU#M17) U1.M18(VDD_MPU#M18) U1.N17(VDD_MPU#N17) U1.N18(VDD_MPU#N18) U1.P17(VDD_MPU#P17) U1.P18(VDD_MPU#P18) U1.R18(VDD_MPU#R18) U3.B13(SMPS12_FBK)
VDD_RTC: C402.1 R930.1(P1) U3.A5(LDO9_OUT)
VDDR2_VREF: C503.2 C504.1 C505.1 C521.2 C522.1 C523.1 C524.1 C531.1 U1.N22(DDR2_VREF) U90.H1(VREFDQ) U90.M8(VREFCA) U91.H1(VREFDQ) U91.M8(VREFCA) U92.6(REFOUT)
VDDR2_VTT: C525.1 C526.1 C527.1 C528.1 C530.1 C534.1 C535.1 C536.1 C537.1 C538.1 C539.1 R756.1(P1) R757.1(P1) R758.1(P1) R759.1(P1) R760.1(P1) R761.1(P1) R762.1(P1) R763.1(P1) R764.1(P1) R765.1(P1) R766.1(P1) R767.1(P1) R768.1(P1) R769.1(P1) R770.1(P1) R771.1(P1) R772.1(P1) R773.1(P1) R774.1(P1) R775.1(P1) R776.1(P1) R777.1(P1) R778.1(P1) R779.1(P1) R784.2(P2) R807.1(P1) U92.3(VO)
VDDR_VREF: C44.2 C45.1 C46.1 C47.2 C53.1 C54.1 C80.2 C81.1 C82.1 C83.1 C99.1 U1.Y18(DDR1_VREF) U5.H1(VREFDQ) U5.M8(VREFCA) U6.H1(VREFDQ) U6.M8(VREFCA) U7.H1(VREFDQ) U7.M8(VREFCA) U8.6(REFOUT)
VDDR_VTT: C87.1 C89.1 C93.1 C94.1 C95.1 C96.1 C97.1 C98.1 C100.1 C313.1 C314.1 R49.1(P1) R50.1(P1) R51.1(P1) R52.1(P1) R53.1(P1) R54.1(P1) R55.1(P1) R57.1(P1) R58.1(P1) R59.1(P1) R60.1(P1) R61.1(P1) R62.1(P1) R63.1(P1) R64.1(P1) R65.1(P1) R66.1(P1) R68.1(P1) R69.2(P2) R70.1(P1) R71.1(P1) R72.1(P1) R73.1(P1) R74.1(P1) R75.1(P1) R806.1(P1) U8.3(VO)
VDDS_DDR: C29.1 C30.1 C31.1 C32.1 C33.1 C34.1 C35.1 C36.1 C37.1 C38.1 C39.1 C40.1 C41.1 C42.1 C43.1 C44.1 C47.1 C48.1 C49.1 C50.1 C51.1 C52.1 C55.1 C56.1 C57.1 C58.1 C59.1 C60.1 C61.1 C62.1 C63.1 C64.1 C65.1 C66.1 C67.1 C68.1 C69.1 C70.1 C71.1 C72.1 C73.1 C74.1 C75.1 C76.1 C77.1 C78.1 C79.1 C80.1 C84.1 C85.2 C87.2 C89.2 C90.1 C91.1 C92.1 C314.2 C488.1 C489.1 C490.1 C491.1 C492.1 C493.1 C494.1 C495.1 C496.1 C497.1 C498.1 C499.1 C500.1 C501.1 C502.1 C503.1 C506.1 C507.1 C508.1 C509.1 C510.1 C511.1 C512.1 C513.1 C514.1 C515.1 C516.1 C517.1 C518.1 C519.1 C520.1 C521.1 C526.2 C529.2 C538.2 C539.2 C540.1 C541.1 C542.1 C543.1 R45.2 R639.1(I1) R656.1(P1) R786.2 R801.1(I1) U3.K13(SMPS3_FDBK) U5.A1(VDDQ#A1) U5.A8(VDDQ#A8) U5.B2(VDD#B2) U5.C1(VDDQ#C1) U5.C9(VDDQ#C9) U5.D2(VDDQ#D2) U5.D9(VDD#D9) U5.E9(VDDQ#E9) U5.F1(VDDQ#F1) U5.G7(VDD#G7) U5.H2(VDDQ#H2) U5.H9(VDDQ#H9) U5.K2(VDD#K2) U5.K8(VDD#K8) U5.N1(VDD#N1) U5.N9(VDD#N9) U5.R1(VDD#R1) U5.R9(VDD#R9) U6.A1(VDDQ#A1) U6.A8(VDDQ#A8) U6.B2(VDD#B2) U6.B7(UDQSN) U6.C1(VDDQ#C1) U6.C9(VDDQ#C9) U6.D2(VDDQ#D2) U6.D9(VDD#D9) U6.E9(VDDQ#E9) U6.F1(VDDQ#F1) U6.G7(VDD#G7) U6.H2(VDDQ#H2) U6.H9(VDDQ#H9) U6.K2(VDD#K2) U6.K8(VDD#K8) U6.N1(VDD#N1) U6.N9(VDD#N9) U6.R1(VDD#R1) U6.R9(VDD#R9) U7.A1(VDDQ#A1) U7.A8(VDDQ#A8) U7.B2(VDD#B2) U7.C1(VDDQ#C1) U7.C9(VDDQ#C9) U7.D2(VDDQ#D2) U7.D9(VDD#D9) U7.E9(VDDQ#E9) U7.F1(VDDQ#F1) U7.G7(VDD#G7) U7.H2(VDDQ#H2) U7.H9(VDDQ#H9) U7.K2(VDD#K2) U7.K8(VDD#K8) U7.N1(VDD#N1) U7.N9(VDD#N9) U7.R1(VDD#R1) U7.R9(VDD#R9) U8.2(VLDOIN) U90.A1(VDDQ#A1) U90.A8(VDDQ#A8) U90.B2(VDD#B2) U90.C1(VDDQ#C1) U90.C9(VDDQ#C9) U90.D2(VDDQ#D2) U90.D9(VDD#D9) U90.E9(VDDQ#E9) U90.F1(VDDQ#F1) U90.G7(VDD#G7) U90.H2(VDDQ#H2) U90.H9(VDDQ#H9) U90.K2(VDD#K2) U90.K8(VDD#K8) U90.N1(VDD#N1) U90.N9(VDD#N9) U90.R1(VDD#R1) U90.R9(VDD#R9) U91.A1(VDDQ#A1) U91.A8(VDDQ#A8) U91.B2(VDD#B2) U91.C1(VDDQ#C1) U91.C9(VDDQ#C9) U91.D2(VDDQ#D2) U91.D9(VDD#D9) U91.E9(VDDQ#E9) U91.F1(VDDQ#F1) U91.G7(VDD#G7) U91.H2(VDDQ#H2) U91.H9(VDDQ#H9) U91.K2(VDD#K2) U91.K8(VDD#K8) U91.N1(VDD#N1) U91.N9(VDD#N9) U91.R1(VDD#R1) U91.R9(VDD#R9) U92.2(VLDOIN)
AM57XX_CLKOUT3: R905.2(P2) U1.C23(XREF_CLK3/CLKOUT3)
AM57XX_GPIO6_14: R685.2(P2) U1.E21(GPIO6_14)
AM57XX_GPIO6_15: R661.2(P2) U1.F20(GPIO6_15)
AM57XX_GPIO6_16: R666.2(P2) U1.F21(GPIO6_16)
AM57XX_GPIO_IND_LDN: R371.2(P2) R800.1 U1.AF4(VIN1A_D15/GPIO)
AM57XX_GPIO_RS485: R584.2(P2) U1.AA3(MCASP5_ACLKX/PR2_PRU1_R30_1)
AM57XX_GPMC_AD0: R434.1(P1) R453.2 R861.2(P2) U1.M6(GPMC_AD0/GPIO)
AM57XX_GPMC_AD1: R435.1(P1) R454.2 R862.2(P2) U1.M2(GPMC_AD1/GPIO)
AM57XX_GPMC_AD2: R436.1(P1) R455.2 R863.2(P2) U1.L5(GPMC_AD2/GPIO)
AM57XX_GPMC_AD3: R437.1(P1) R456.2 R864.2(P2) U1.M1(GPMC_AD3/GPIO)
AM57XX_GPMC_AD4: J21.51 R438.1(P1) R457.2 U1.L6(GPMC_AD4/GPIO)
AM57XX_GPMC_AD5: J21.53 R439.1(P1) R458.2 U1.L4(GPMC_AD5/GPIO)
AM57XX_GPMC_AD6: J21.55 R440.1(P1) R459.2 U1.L3(GPMC_AD6/GPIO)
AM57XX_GPMC_AD7: J21.57 R441.1(P1) R460.2 U1.L2(GPMC_AD7/GPIO)
AM57XX_GPMC_AD8: J21.32 R442.1(P1) R461.2 U1.L1(GPMC_AD8)
AM57XX_GPMC_AD9: J21.34 R443.1(P1) R462.2 U1.K2(GPMC_AD9)
AM57XX_GPMC_AD10: J21.36 R444.1(P1) R463.2 U1.J1(GPMC_AD10)
AM57XX_GPMC_AD11: J21.38 R445.1(P1) R464.2 U1.J2(GPMC_AD11)
AM57XX_GPMC_AD12: J21.42 R446.1(P1) R465.2 U1.H1(GPMC_AD12)
AM57XX_GPMC_AD13: J21.44 R447.1(P1) R466.2 U1.J3(GPMC_AD13)
AM57XX_GPMC_AD14: J21.46 R448.1(P1) R467.2 U1.H2(GPMC_AD14)
AM57XX_GPMC_AD15: J21.48 R449.1(P1) R468.2 U1.H3(GPMC_AD15)
AM57XX_HDMI_CLK+: L29.4 U1.AH16(HDMI1_CLOCKY)
AM57XX_HDMI_CLK-: L29.1 U1.AG16(HDMI1_CLOCKX)
AM57XX_HDMI_TX0+: L30.4 U1.AH17(HDMI1_DATA0Y)
AM57XX_HDMI_TX0-: L30.1 U1.AG17(HDMI1_DATA0X)
AM57XX_HDMI_TX1+: L31.4 U1.AH18(HDMI1_DATA1Y)
AM57XX_HDMI_TX1-: L31.1 U1.AG18(HDMI1_DATA1X)
AM57XX_HDMI_TX2+: L32.4 U1.AH19(HDMI1_DATA2Y)
AM57XX_HDMI_TX2-: L32.1 U1.AG19(HDMI1_DATA2X)
AM57XX_I2C1_SCL: R384.1(P1) R385.2(P2) R393.2(P2) U1.C20(I2C1_SCL)
AM57XX_I2C1_SDA: R383.1(P1) R387.2(P2) R394.2(P2) U1.C21(I2C1_SDA)
AM57XX_INDETHER_LED0_GRN: R247.1(P1) R803.2(P2)
AM57XX_INDETHER_LED0_RED: R241.2(P2) U1.B26(XREF_CLK2)
AM57XX_INDETHER_LED0_YEL: R253.1(P1) U1.D15(MCASP2_AXR4)
AM57XX_INDETHER_LED1_GRN: R248.1(P1) U1.B17(MCASP2_AXR6)
AM57XX_INDETHER_LED1_RED: R243.2(P2) U1.B16(MCASP2_AXR5)
AM57XX_INDETHER_LED1_YEL: R254.1(P1) U1.A17(MCASP2_AXR7)
AM57XX_INDETHER_LED2_GRN: R590.1(P1) U1.F16(SPI1_D1)
AM57XX_INDETHER_LED2_RED: R600.2(P2) U1.B25(SPI1_D0)
AM57XX_INDETHER_LED2_YEL: R594.1(P1) U1.A24(SPI1_CS0)
AM57XX_INDETHER_LED3_GRN: R593.1(P1) U1.AF6(VIN1A_D13)
AM57XX_INDETHER_LED3_RED: R514.2(P2) U1.A22(SPI1_CS1)
AM57XX_INDETHER_LED3_YEL: R598.1(P1) U1.AF3(VIN1A_D14)
AM57XX_LCD_DE: R634.2(P2) U1.B10(VOUT1_DE)
AM57XX_LCD_HSYNC: R636.2(P2) U1.C11(VOUT1_HSYNC)
AM57XX_LCD_PCLK: R565.2(P2) U1.D11(VOUT1_CLK)
AM57XX_LCD_VSYNC: R635.2(P2) U1.E11(VOUT1_VSYNC)
AM57XX_MCASP1_AXR4: R673.2(P2) U1.E12(MCASP1_AXR4)
AM57XX_MCASP1_AXR5: R674.2(P2) U1.F13(MCASP1_AXR5)
AM57XX_MCASP1_AXR6: R675.2(P2) U1.C12(MCASP1_AXR6)
AM57XX_MCASP1_AXR7: R676.2(P2) U1.D12(MCASP1_AXR7)
AM57XX_MMC1_CLK: R405.2(P2) U1.W6(MMC1_CLK)
AM57XX_MMC1_CMD: R404.2(P2) U1.Y6(MMC1_CMD)
AM57XX_MMC1_DAT0: R406.2(P2) U1.AA6(MMC1_DAT0)
AM57XX_MMC1_DAT1: R407.2(P2) U1.Y4(MMC1_DAT1)
AM57XX_MMC1_DAT2: R402.2(P2) U1.AA5(MMC1_DAT2)
AM57XX_MMC1_DAT3: R403.2(P2) U1.Y3(MMC1_DAT3)
AM57XX_MMC1_SDCD: R409.2(P2) U1.W7(MMC1_SDCD)
AM57XX_MMC1_SDWP: J44.1 R644.1 U1.Y9(MMC1_SDWP)
AM57XX_OSC0_IN: C2.1 R4.2(P2) U1.AE15(XI_OSC0) Y1.3
AM57XX_OSC0_OUT: R5.1(P1) U1.AD15(XO_OSC0)
AM57XX_PCIE_PERN0: J22.A17 U1.AG13(PCIE_RXN0)
AM57XX_PCIE_PERP0: J22.A16 U1.AH13(PCIE_RXP0)
AM57XX_PCIE_PETN0: C477.1 U1.AG14(PCIE_TXN0)
AM57XX_PCIE_PETP0: C478.1 U1.AH14(PCIE_TXP0)
AM57XX_PCIE_REF_CLKN: C438.2 R581.1(P1) U1.AH15(LJCB_CLKN)
AM57XX_PCIE_REF_CLKP: C439.2 R581.2(P2) U1.AG15(LJCB_CLKP)
AM57XX_PORZN: R6.1(P1) U1.F22(PORZ)
AM57XX_PR1_UART0_RXD: J21.47 R575.2(P2) U1.F2(VIN2A_D0/PR1_UART0_RXD)
AM57XX_PR1_UART0_TXD: J21.45 R199.2(P2) R574.2(P2) U1.F3(VIN2A_D1/PR1_UART0_TXD)
AM57XX_PR2_PROFI_TXEN: J21.49 U1.U3(RMII50MHZCLK/PR2_GPIO)
AM57XX_PRU1ETH0_MRCLK: R83.2(P2) U1.Y1(UART3_TXD/PR1_MII0_MR0CLK)
AM57XX_PRU1ETH0_RXDV: R86.2(P2) U1.V2(UART3_RXD/PR1_MII0_RXDV)
AM57XX_PRU1ETH1_MRCLK: R129.2(P2) R332.2 U1.C3(VIN2A_D14/RGMII1_TXD3)
AM57XX_PRU1ETH1_TXCLK: R123.2(P2) R746.2(P2) U1.C1(VIN2A_D6/PR1_MII_MT1_CLK)
AM57XX_PRU1ETH1_TXD0: R125.2(P2) R326.2 U1.C2(VIN2A_D13/RGMII1_TXCTL)
AM57XX_PRU1ETH1_TXD1: R126.2(P2) R325.2 U1.D5(VIN2A_D12/RGMII1_TXC)
AM57XX_PRU1ETH1_TXD2: R127.2(P2) U1.E6(VIN2A_D9/PR1_MII1_TXD2)
AM57XX_PRU1ETH1_TXD3: R128.2(P2) R747.2(P2) U1.F5(VIN2A_D8/PR1_MII1_TXD3)
AM57XX_PRU1ETH1_TXEN: R124.2(P2) U1.E4(VIN2A_D7/PR1_MII1_TXEN)
AM57XX_PRU1ETH_MDCLK: R96.2(P2) R140.2(P2) R748.2(P2) U1.D3(VIN2A_D10/PR1_MDIO_MDCLK)
AM57XX_PRU1ETH_MDDATA: R98.2(P2) R142.2(P2) U1.F6(VIN2A_D11/PR1_MDIO_DATA)
AM57XX_PRU2ETH0_COL: R178.2(P2) U1.F15(MCASP3_FSX/PR2_MII0_COL)
AM57XX_PRU2ETH0_CRS: R177.2(P2) U1.B18(MCASP3_ACLKX/PR2_MII0_CRS)
AM57XX_PRU2ETH0_MRCLK: R165.2(P2) U1.A13(MCASP1_AXR13/PR2_MII_MR0_CLK)
AM57XX_PRU2ETH0_RXD0: R171.2(P2) U1.C15(MCASP2_AXR2/PR2_MII0_RXD0)
AM57XX_PRU2ETH0_RXD1: R173.2(P2) U1.A18(MCASP2_FSX/PR2_MII0_RXD1)
AM57XX_PRU2ETH0_RXD2: R174.2(P2) U1.A19(MCASP2_ACLKX/PR2_MII0_RXD2)
AM57XX_PRU2ETH0_RXD3: R175.2(P2) U1.F14(MCASP1_AXR15/PR2_MII0_RXD3)
AM57XX_PRU2ETH0_RXDV: R166.2(P2) R197.2(P2) U1.G14(MCASP1_AXR14/PR2_MII0_RXDV)
AM57XX_PRU2ETH0_RXER: R170.2(P2) U1.G12(MCASP1_AXR0/PR2_MII0_RXER)
AM57XX_PRU2ETH0_RXLINK: R188.2(P2) U1.A16(MCASP2_AXR3/PR2_MII0_RXLINK)
AM57XX_PRU2ETH0_TXCLK: R162.2(P2) U1.F12(MCASP1_AXR1/PR2_MII_MT0_CLK)
AM57XX_PRU2ETH0_TXD0: R163.2(P2) U1.E14(MCASP1_AXR12/PR2_MII0_TXD0)
AM57XX_PRU2ETH0_TXD1: R164.2(P2) U1.A12(MCASP1_AXR11/PR2_MII0_TXD1)
AM57XX_PRU2ETH0_TXD2: R168.2(P2) U1.B13(MCASP1_AXR10/PR2_MII0_TXD2)
AM57XX_PRU2ETH0_TXD3: R169.2(P2) U1.A11(MCASP1_AXR9/PR2_MII0_TXD3)
AM57XX_PRU2ETH0_TXEN: R167.2(P2) R196.2(P2) U1.B12(MCASP1_AXR8/PR2_MII0_TXEN)
AM57XX_PRU2ETH1_MRCLK: R209.2(P2) U1.AC9(MMC3_DAT2/PR2_MII_MR1_CLK)
AM57XX_PRU2ETH1_RXD0: R213.2(P2) U1.AB5(MMC3_DAT7/PR2_MII1_RXD0)
AM57XX_PRU2ETH1_RXD1: R215.2(P2) U1.AB8(MMC3_DAT6/PR2_MII1_RXD1)
AM57XX_PRU2ETH1_RXD2: R216.2(P2) U1.AD6(MMC3_DAT5/PR2_MII1_RXD2)
AM57XX_PRU2ETH1_RXD3: R217.2(P2) U1.AC8(MMC3_DAT4/PR2_MII1_RXD3)
AM57XX_PRU2ETH1_RXDV: R211.2(P2) U1.AC3(MMC3_DAT3/PR2_MII1_RXDV)
AM57XX_PRU2ETH1_RXER: R212.2(P2) U1.B19(MCASP3_AXR0/PR2_MII1_RXER)
AM57XX_PRU2ETH1_TXCLK: R204.2(P2) U1.AC5(GPIO6_10/PR2_MII_MT1_CLK)
AM57XX_PRU2ETH1_TXD0: R206.2(P2) U1.AC6(MMC3_DAT1/PR2_MII1_TXD0)
AM57XX_PRU2ETH1_TXD1: R208.2(P2) U1.AC7(MMC3_DAT0/PR2_MII1_TXD1)
AM57XX_PRU2ETH1_TXD2: R210.2(P2) U1.AC4(MMC3_CMD/PR2_MII1_TXD2)
AM57XX_PRU2ETH1_TXD3: R207.2(P2) U1.AD4(MMC3_CLK/PR2_MII1_TXD3)
AM57XX_PRU2ETH1_TXEN: R205.2(P2) U1.AB4(GPIO6_11/PR2_MII1_TXEN)
AM57XX_PRU2ETH_MDCLK: R179.2(P2) R221.2(P2) U1.C14(MCASP1_ACLKX/PR2_MDIO_MDCLK)
AM57XX_PRU2ETH_MDDATA: R181.2(P2) R223.2(P2) U1.D14(MCASP1_FSX/PR2_MDIO_DATA)
AM57XX_RGMII0_RD0: R81.2(P2) R289.2 U1.W2(RGMII0_RXD0)
AM57XX_RGMII0_RD1: R84.2(P2) R290.2 U1.Y2(RGMII0_RXD1)
AM57XX_RGMII0_RD2: R80.2(P2) R291.2 U1.V3(RGMII0_RXD2)
AM57XX_RGMII0_RD3: R85.2(P2) R292.2 U1.V4(RGMII0_RXD3)
AM57XX_RGMII0_RXCLK: R79.2(P2) R288.2 U1.U5(RGMII0_RXC)
AM57XX_RGMII0_RXCTL: R82.2(P2) R285.2 U1.V5(RGMII0_RXCTL)
AM57XX_RGMII0_TD0: R88.2(P2) R282.2 U1.U6(RGMII0_TXD0)
AM57XX_RGMII0_TD1: R90.2(P2) R287.2 U1.V6(RGMII0_TXD1)
AM57XX_RGMII0_TD2: R87.2(P2) R283.2 U1.U7(RGMII0_TXD2)
AM57XX_RGMII0_TD3: R94.2(P2) R284.2 U1.V7(RGMII0_TXD3)
AM57XX_RGMII0_TXCLK: R92.2(P2) R281.2 U1.W9(RGMII0_TXC)
AM57XX_RGMII0_TXCTL: R91.2(P2) R286.2 U1.V9(RGMII0_TXCTL)
AM57XX_RGMII1_RD0: R139.2(P2) R333.2 U1.A4(VIN2A_D23/RGMII1_RXD0)
AM57XX_RGMII1_RD1: R148.2(P2) R334.2 U1.B5(VIN2A_D22/RGMII1_RXD1)
AM57XX_RGMII1_RD2: R150.2(P2) R335.2 U1.B4(VIN2A_D21/RGMII1_RXD2)
AM57XX_RGMII1_RD3: R132.2(P2) R336.2 U1.B3(VIN2A_D20/RGMII1_RXD3)
AM57XX_RGMII1_RXCLK: R135.2(P2) R328.2 U1.C5(VIN2A_D18/RGMII1_RXC)
AM57XX_RGMII1_RXCTL: R133.2(P2) R329.2 U1.A3(VIN2A_D19/RGMII1_RXCTL)
AM57XX_RGMII1_TD0: R136.2(P2) R330.2 U1.D6(VIN2A_D17/RGMII1_TXD0)
AM57XX_RGMII1_TD1: R137.2(P2) R331.2 U1.B2(VIN2A_D16/RGMII1_TXD1)
AM57XX_RGMII1_TD2: R130.2(P2) R327.2 U1.C4(VIN2A_D15/RGMII1_TXD2)
AM57XX_RSTOUTN: R36.2(P2) R922.2(P2) U1.F23(RSTOUTN) U47.2(A)
AM57XX_RTCK: R426.2 U1.E18(RTCK)
AM57XX_SPI1_CS0: R369.2(P2) U1.D17(MCASP4_AXR1/SPI3_CS0)
AM57XX_SPI1_D1: R377.2(P2) U1.A21(MCASP4_FSX/SPI3_D1)
AM57XX_SPI1_SCLK: R367.2(P2) U1.C18(MCASP4_ACLKX/SPI3_SCLK)
AM57XX_SPI2_SCLK: R684.1(P1) U1.A26(SPI2_SCLK)
AM57XX_STATUSLED0_GRN: R701.1(P1) R736.2(P2)
AM57XX_STATUSLED0_RED: R698.2(P2) R735.2(P2)
AM57XX_STATUSLED0_YEL: R694.1(P1) R737.2(P2)
AM57XX_STATUSLED1_GRN: R710.1(P1) R739.2(P2)
AM57XX_STATUSLED1_RED: R707.2(P2) R738.2(P2)
AM57XX_STATUSLED1_YEL: R703.1(P1) R740.2(P2)
AM57XX_UART2_RXD: R583.2(P2) U1.D28(UART2_RXD)
AM57XX_UART2_TXD: R582.2(P2) U1.D26(UART2_TXD)
AM57XX_UART3_RXD: R487.1(P1) U1.D27(UART2_CTSN/UART3_RXD)
AM57XX_UART3_TXD: R486.1(P1) U1.C28(UART2_RTSN/UART3_TXD)
AM57XX_VIN2A_CLK0: R669.1(P1) U1.E1(VIN2A_CLK0)
AM57XX_VIN2A_DE0: R119.2(P2) R670.1(P1) U1.G2(VIN2A_DE0)
AM57XX_VIN2A_FLD0: R671.1(P1) U1.H7(VIN2A_FLD0)
AM57XX_VIN2A_HSYNC0: R118.2(P2) R672.1(P1) U1.G1(VIN2A_HSYNC0)
AM57XX_VIN2A_VSYNC0: R198.2(P2) R735.1(P1) U1.G6(VIN2A_VSYNC0)
AM57XX_VOUT1_D0: R605.2(P2) U1.F11(VOUT1_D0)
AM57XX_VOUT1_D1: R606.2(P2) U1.G10(VOUT1_D1)
AM57XX_VOUT1_D2: R607.2(P2) R711.2(P2) U1.F10(VOUT1_D2)
AM57XX_VOUT1_D3: R608.2(P2) R714.2(P2) U1.G11(VOUT1_D3)
AM57XX_VOUT1_D4: R609.2(P2) R715.2(P2) U1.E9(VOUT1_D4)
AM57XX_VOUT1_D5: R610.2(P2) R716.2(P2) R910.2(P2) U1.F9(VOUT1_D5)
AM57XX_VOUT1_D6: R612.2(P2) R717.2(P2) R911.2(P2) U1.F8(VOUT1_D6)
AM57XX_VOUT1_D7: R611.2(P2) R718.2(P2) R908.2(P2) U1.E7(VOUT1_D7)
AM57XX_VOUT1_D8: R613.2(P2) R909.2(P2) U1.E8(VOUT1_D8)
AM57XX_VOUT1_D9: R614.2(P2) U1.D9(VOUT1_D9)
AM57XX_VOUT1_D10: R616.2(P2) R712.2(P2) U1.D7(VOUT1_D10)
AM57XX_VOUT1_D11: R615.2(P2) R719.2(P2) U1.D8(VOUT1_D11)
AM57XX_VOUT1_D12: R617.2(P2) R720.2(P2) U1.A5(VOUT1_D12)
AM57XX_VOUT1_D13: R619.2(P2) R721.2(P2) R906.2(P2) U1.C6(VOUT1_D13)
AM57XX_VOUT1_D14: R620.2(P2) R722.2(P2) R907.2(P2) U1.C8(VOUT1_D14)
AM57XX_VOUT1_D15: R618.2(P2) R723.2(P2) U1.C7(VOUT1_D15)
AM57XX_VOUT1_D16: R621.2(P2) U1.B7(VOUT1_D16)
AM57XX_VOUT1_D17: R622.2(P2) U1.B8(VOUT1_D17)
AM57XX_VOUT1_D18: R624.2(P2) R713.2(P2) U1.A7(VOUT1_D18)
AM57XX_VOUT1_D19: R623.2(P2) R724.2(P2) U1.A8(VOUT1_D19)
AM57XX_VOUT1_D20: R625.2(P2) R725.2(P2) U1.C9(VOUT1_D20)
AM57XX_VOUT1_D21: R627.2(P2) R726.2(P2) U1.A9(VOUT1_D21)
AM57XX_VOUT1_D22: R628.2(P2) R727.2(P2) U1.B9(VOUT1_D22)
AM57XX_VOUT1_D23: R626.2(P2) R728.2(P2) U1.A10(VOUT1_D23)
AM57XX_VOUT1_FLD: R564.1(P1) U1.B11(VOUT1_FLD)
AM572X_DCAN1_RX: C253.1 R502.1 U1.G19(DCAN1_RX)
AM572X_DCAN1_TX: R504.1 U1.G20(DCAN1_TX)
AM572X_HAPTICS_TRIG: R114.1(P1) U1.A25(SPI1_SCLK)
AM572X_HDMI_CEC: R683.2(P2) R805.1 U1.B20(SPI1_CS3/HDMI_CEC)
AM572X_HDMI_DDC_SCL: R358.2(P2) R556.1(P1) R795.2(P2) U1.C25(I2C2_SDA/HDMI1_DDC_SCL)
AM572X_HDMI_DDC_SDA: R356.2(P2) R563.1(P1) R796.2(P2) U1.F17(I2C2_SCL/HDMI1_DDC_SDA)
AM572X_HDMI_HPD: R682.2(P2) R804.1 U1.B21(SPI1_CS2/HDMI_HPD)
AM572X_QSPI_CLK: R24.2(P2) U1.R2(GPMC_A18/QSPI1_SCLK)
AM572X_QSPI_CSN: R30.2(P2) U1.P2(GPMC_CS2/QSPI1_CS0)
AM572X_QSPI_D0: R25.2(P2) U1.U1(GPMC_A16/QSPI1_D0)
AM572X_QSPI_D1: R26.2(P2) U1.P3(GPMC_A17/QSPI1_D1)
AM572X_QSPI_D2: R27.2(P2) U1.U2(GPMC_A15/QSPI_D2)
AM572X_QSPI_D3: R28.2(P2) U1.T2(GPMC_A14/QSPI_D3)
AM572X_QSPI_RTCLK: R23.2(P2) U1.R3(GPMC_A13/QSPI_RTCLK)
AM572X_USB1_3_0_STDA_SSTX+: C555.1 U1.AD11(USB_TXP0)
AM572X_USB1_3_0_STDA_SSTX-: C554.1 U1.AC11(USB_TXN0)
AM572X_USB1_DM: L11.1 U1.AC12(USB1_DM)
AM572X_USB1_DP: L11.2 U1.AD12(USB1_DP)
AM572X_USB1_DRVVBUS: R557.2(P2) U1.AB10(USB1_DRVVBUS)
AM572X_USB2_DM: L33.2 U1.AF11(USB2_DM)
AM572X_USB2_DP: L33.1 U1.AE11(USB2_DP)
AM572X_USB2_DRVVBUS: R787.2(P2) U1.AC10(USB2_DRVVBUS)
AM572X_VIN4B_DATA0: R260.2(P2) U1.R6(GPMC_A0/VIN4B_D0)
AM572X_VIN4B_DATA1: R261.2(P2) U1.T9(GPMC_A1/VIN4B_D1)
AM572X_VIN4B_DATA2: R263.2(P2) U1.T6(GPMC_A2/VIN4B_D2)
AM572X_VIN4B_DATA3: R267.2(P2) U1.T7(GPMC_A3/VIN4B_D3)
AM572X_VIN4B_DATA4: R269.2(P2) U1.P6(GPMC_A4/VIN4B_D4)
AM572X_VIN4B_DATA5: R271.2(P2) U1.R9(GPMC_A5/VIN4B_D5)
AM572X_VIN4B_DATA6: R262.1(P1) U1.R5(GPMC_A6/VIN4B_D6)
AM572X_VIN4B_DATA7: R264.1(P1) U1.P5(GPMC_A7/VIN4B_D7)
AM572X_VIN4B_DE: R273.2(P2) U1.P9(GPMC_A11/VIN4B_DE1)
AM572X_VIN4B_FLD: R274.1(P1) U1.P4(GPMC_A12/VIN4B_FLD1)
AM572X_VIN4B_HSYNC: R258.1(P1) U1.N7(GPMC_A8/VIN4B_HSYNC1)
AM572X_VIN4B_PCLK: R265.2(P2) U1.N9(GPMC_A10/VIN4B_CLK1)
AM572X_VIN4B_VSYNC: R257.1(P1) U1.R4(GPMC_A9/VIN4B_VSYNC1)
BKLT_EN: Q9.G(GATE) R412.1 R416.1(P1)
BKLT_L: L1.1 U32.1(L)
BKLT_SW: L1.2 U32.10(SW)
CAM1_DATA0: J9.3 R260.1(P1)
CAM1_DATA1: J9.5 R261.1(P1)
CAM1_DATA2: J9.7 R263.1(P1)
CAM1_DATA3: J9.13 R267.1(P1)
CAM1_DATA4: J9.15 R269.1(P1)
CAM1_DATA5: J9.17 R271.1(P1)
CAM1_DATA6: J9.6 R262.2(P2)
CAM1_DATA7: J9.8 R264.2(P2)
CAM1_FIELD: J9.20 R274.2(P2)
CAM1_GIO0: J9.16 R259.1
CAM1_HSYNC: J9.4 R258.2(P2)
CAM1_PCLK: J9.9 R265.1(P1)
CAM1_VSYNC: J9.2 R257.2(P2)
CAM1_WEN: J9.19 R273.1(P1)
CAM_ENN: J9.18 R685.1(P1)
CAN1_H: J38.2 R503.2(P2) U41.7(CANH) U88.1
CAN1_L: J38.3 R503.1(P1) U41.6(CANL) U87.1
CAN1_RXDF: J21.41 R502.2 U41.2(RXD)
CAN1_TXDF: C254.1 J21.43 R504.2 U41.3(TXD)
DDR2_A0: R761.2(P2) U1.R25(DDR2_A0) U90.N3(A0) U91.N3(A0)
DDR2_A1: R763.2(P2) U1.R26(DDR2_A1) U90.P7(A1) U91.P7(A1)
DDR2_A2: R762.2(P2) U1.R28(DDR2_A2) U90.P3(A2) U91.P3(A2)
DDR2_A3: R765.2(P2) U1.R27(DDR2_A3) U90.N2(A3) U91.N2(A3)
DDR2_A4: R764.2(P2) U1.P23(DDR2_A4) U90.P8(A4) U91.P8(A4)
DDR2_A5: R766.2(P2) U1.P22(DDR2_A5) U90.P2(A5) U91.P2(A5)
DDR2_A6: R768.2(P2) U1.P25(DDR2_A6) U90.R8(A6) U91.R8(A6)
DDR2_A7: R767.2(P2) U1.N20(DDR2_A7) U90.R2(A7) U91.R2(A7)
DDR2_A8: R770.2(P2) U1.P27(DDR2_A8) U90.T8(A8) U91.T8(A8)
DDR2_A9: R769.2(P2) U1.N27(DDR2_A9) U90.R3(A9) U91.R3(A9)
DDR2_A10: R771.2(P2) U1.N23(DDR2_A10) U90.L7(A10/AP) U91.L7(A10/AP)
DDR2_A11: R773.2(P2) U1.P26(DDR2_A11) U90.R7(A11) U91.R7(A11)
DDR2_A12: R772.2(P2) U1.N28(DDR2_A12) U90.N7(A12/B\C\) U91.N7(A12/B\C\)
DDR2_A13: R775.2(P2) U1.T22(DDR2_A13) U90.T3(A13) U91.T3(A13)
DDR2_A14: R774.2(P2) U1.R22(DDR2_A14) U90.T7(A14) U91.T7(A14)
DDR2_A15: R807.2(P2) U1.U22(DDR2_A15) U90.M7(NU4) U91.M7(NU4)
DDR2_BA0: R777.2(P2) U1.U23(DDR2_BA0) U90.M2(BA0) U91.M2(BA0)
DDR2_BA1: R776.2(P2) U1.U27(DDR2_BA1) U90.N8(BA1) U91.N8(BA1)
DDR2_BA2: R779.2(P2) U1.U26(DDR2_BA2) U90.M3(BA2) U91.M3(BA2)
DDR2_CASN: R759.2(P2) U1.U28(DDR2_CASN) U90.K3(CASN) U91.K3(CASN)
DDR2_CKE: R756.2(P2) U1.U24(DDR2_CKE) U90.K9(CKE) U91.K9(CKE)
DDR2_CLK: R780.2(P2) U1.T28(DDR2_CK) U90.J7(CK) U91.J7(CK)
DDR2_CLKN: R781.2(P2) U1.T27(DDR2_CKN) U90.K7(CKN) U91.K7(CKN)
DDR2_CS0N: R757.2(P2) U1.P24(DDR2_CSN0) U90.L2(CSN) U91.L2(CSN)
DDR2_D0: U1.E26(DDR2_D0) U90.E3(DQ0)
DDR2_D1: U1.G25(DDR2_D1) U90.F2(DQ2)
DDR2_D2: U1.F25(DDR2_D2) U90.G2(DQ6)
DDR2_D3: U1.F24(DDR2_D3) U90.H3(DQ4)
DDR2_D4: U1.F26(DDR2_D4) U90.F7(DQ1)
DDR2_D5: U1.F27(DDR2_D5) U90.H8(DQ5)
DDR2_D6: U1.E27(DDR2_D6) U90.F8(DQ3)
DDR2_D7: U1.E28(DDR2_D7) U90.H7(DQ7)
DDR2_D8: U1.H23(DDR2_D8) U90.D7(DQ8)
DDR2_D9: U1.H25(DDR2_D9) U90.A2(DQ13)
DDR2_D10: U1.H24(DDR2_D10) U90.C3(DQ9)
DDR2_D11: U1.H26(DDR2_D11) U90.A3(DQ15)
DDR2_D12: U1.G26(DDR2_D12) U90.C2(DQ11)
DDR2_D13: U1.J25(DDR2_D13) U90.B8(DQ14)
DDR2_D14: U1.J26(DDR2_D14) U90.A7(DQ12)
DDR2_D15: U1.J24(DDR2_D15) U90.C8(DQ10)
DDR2_D16: U1.L22(DDR2_D16) U91.E3(DQ0)
DDR2_D17: U1.K20(DDR2_D17) U91.H8(DQ5)
DDR2_D18: U1.K21(DDR2_D18) U91.H3(DQ4)
DDR2_D19: U1.L23(DDR2_D19) U91.F7(DQ1)
DDR2_D20: U1.L24(DDR2_D20) U91.F8(DQ3)
DDR2_D21: U1.J23(DDR2_D21) U91.F2(DQ2)
DDR2_D22: U1.K22(DDR2_D22) U91.G2(DQ6)
DDR2_D23: U1.J20(DDR2_D23) U91.H7(DQ7)
DDR2_D24: U1.L27(DDR2_D24) U91.D7(DQ8)
DDR2_D25: U1.L26(DDR2_D25) U91.A3(DQ15)
DDR2_D26: U1.L25(DDR2_D26) U91.C2(DQ11)
DDR2_D27: U1.L28(DDR2_D27) U91.A7(DQ12)
DDR2_D28: U1.M23(DDR2_D28) U91.C8(DQ10)
DDR2_D29: U1.M24(DDR2_D29) U91.A2(DQ13)
DDR2_D30: U1.M25(DDR2_D30) U91.C3(DQ9)
DDR2_D31: U1.M26(DDR2_D31) U91.B8(DQ14)
DDR2_DQM0: U1.F28(DDR2_DQM0) U90.E7(LDM)
DDR2_DQM1: U1.G24(DDR2_DQM1) U90.D3(UDM)
DDR2_DQM2: U1.K23(DDR2_DQM2) U91.E7(LDM)
DDR2_DQM3: U1.M22(DDR2_DQM3) U91.D3(UDM)
DDR2_DQS0: U1.G28(DDR2_DQS0) U90.F3(LDQS)
DDR2_DQS1: U1.H27(DDR2_DQS1) U90.C7(UDQS)
DDR2_DQS2: U1.K27(DDR2_DQS2) U91.F3(LDQS)
DDR2_DQS3: U1.M28(DDR2_DQS3) U91.C7(UDQS)
DDR2_DQSN0: U1.G27(DDR2_DQS0N) U90.G3(LDQSN)
DDR2_DQSN1: U1.H28(DDR2_DQS1N) U90.B7(UDQSN)
DDR2_DQSN2: U1.K28(DDR2_DQS2N) U91.G3(LDQSN)
DDR2_DQSN3: U1.M27(DDR2_DQS3N) U91.B7(UDQSN)
DDR2_ODT: R778.2(P2) U1.R23(DDR2_ODT0) U90.K1(ODT) U91.K1(ODT)
DDR2_RASN: R758.2(P2) U1.T23(DDR2_RASN) U90.J3(RASN) U91.J3(RASN)
DDR2_RESETN: R913.2 U1.R24(DDR2_RST) U90.T2(RESETN) U91.T2(RESETN)
DDR2_WEN: R760.2(P2) U1.U25(DDR2_WEN) U90.L3(WEN) U91.L3(WEN)
DDR_A0: R54.2(P2) U1.AD20(DDR1_A0) U5.N3(A0) U6.N3(A0) U7.N3(A0)
DDR_A1: R57.2(P2) U1.AC19(DDR1_A1) U5.P7(A1) U6.P7(A1) U7.P7(A1)
DDR_A2: R55.2(P2) U1.AC20(DDR1_A2) U5.P3(A2) U6.P3(A2) U7.P3(A2)
DDR_A3: R58.2(P2) U1.AB19(DDR1_A3) U5.N2(A3) U6.N2(A3) U7.N2(A3)
DDR_A4: R59.2(P2) U1.AF21(DDR1_A4) U5.P8(A4) U6.P8(A4) U7.P8(A4)
DDR_A5: R60.2(P2) U1.AH22(DDR1_A5) U5.P2(A5) U6.P2(A5) U7.P2(A5)
DDR_A6: R61.2(P2) U1.AG23(DDR1_A6) U5.R8(A6) U6.R8(A6) U7.R8(A6)
DDR_A7: R62.2(P2) U1.AE21(DDR1_A7) U5.R2(A7) U6.R2(A7) U7.R2(A7)
DDR_A8: R63.2(P2) U1.AF22(DDR1_A8) U5.T8(A8) U6.T8(A8) U7.T8(A8)
DDR_A9: R64.2(P2) U1.AE22(DDR1_A9) U5.R3(A9) U6.R3(A9) U7.R3(A9)
DDR_A10: R66.2(P2) U1.AD21(DDR1_A10) U5.L7(A10/AP) U6.L7(A10/AP) U7.L7(A10/AP)
DDR_A11: R65.2(P2) U1.AD22(DDR1_A11) U5.R7(A11) U6.R7(A11) U7.R7(A11)
DDR_A12: R68.2(P2) U1.AC21(DDR1_A12) U5.N7(A12/B\C\) U6.N7(A12/B\C\) U7.N7(A12/B\C\)
DDR_A13: R70.2(P2) U1.AF18(DDR1_A13) U5.T3(A13) U6.T3(A13) U7.T3(A13)
DDR_A14: R71.2(P2) U1.AE17(DDR1_A14) U5.T7(A14) U6.T7(A14) U7.T7(A14)
DDR_A15: R806.2(P2) U1.AD18(DDR1_A15) U5.M7(NU4) U6.M7(NU4) U7.M7(NU4)
DDR_BA0: R72.2(P2) U1.AF17(DDR1_BA0) U5.M2(BA0) U6.M2(BA0) U7.M2(BA0)
DDR_BA1: R73.2(P2) U1.AE18(DDR1_BA1) U5.N8(BA1) U6.N8(BA1) U7.N8(BA1)
DDR_BA2: R74.2(P2) U1.AB18(DDR1_BA2) U5.M3(BA2) U6.M3(BA2) U7.M3(BA2)
DDR_CASN: R52.2(P2) U1.AC18(DDR1_CASN) U5.K3(CASN) U6.K3(CASN) U7.K3(CASN)
DDR_CKE: R49.2(P2) U1.AG22(DDR1_CKE) U5.K9(CKE) U6.K9(CKE) U7.K9(CKE)
DDR_CLK: R46.2(P2) U1.AG24(DDR1_CK) U5.J7(CK) U6.J7(CK) U7.J7(CK)
DDR_CLKN: R47.2(P2) U1.AH24(DDR1_CKN) U5.K7(CKN) U6.K7(CKN) U7.K7(CKN)
DDR_CS0N: R50.2(P2) U1.AH23(DDR1_CSN0) U5.L2(CSN) U6.L2(CSN) U7.L2(CSN)
DDR_D0: U1.AF25(DDR1_D0) U5.E3(DQ0)
DDR_D1: U1.AF26(DDR1_D1) U5.F7(DQ1)
DDR_D2: U1.AG26(DDR1_D2) U5.F8(DQ3)
DDR_D3: U1.AH26(DDR1_D3) U5.H8(DQ5)
DDR_D4: U1.AF24(DDR1_D4) U5.F2(DQ2)
DDR_D5: U1.AE24(DDR1_D5) U5.G2(DQ6)
DDR_D6: U1.AF23(DDR1_D6) U5.H3(DQ4)
DDR_D7: U1.AE23(DDR1_D7) U5.H7(DQ7)
DDR_D8: U1.AC23(DDR1_D8) U5.D7(DQ8)
DDR_D9: U1.AF27(DDR1_D9) U5.C3(DQ9)
DDR_D10: U1.AG27(DDR1_D10) U5.A3(DQ15)
DDR_D11: U1.AF28(DDR1_D11) U5.A7(DQ12)
DDR_D12: U1.AE26(DDR1_D12) U5.A2(DQ13)
DDR_D13: U1.AC25(DDR1_D13) U5.C8(DQ10)
DDR_D14: U1.AC24(DDR1_D14) U5.B8(DQ14)
DDR_D15: U1.AD25(DDR1_D15) U5.C2(DQ11)
DDR_D16: U1.V20(DDR1_D16) U7.E3(DQ0)
DDR_D17: U1.W20(DDR1_D17) U7.H8(DQ5)
DDR_D18: U1.AB28(DDR1_D18) U7.H3(DQ4)
DDR_D19: U1.AC28(DDR1_D19) U7.G2(DQ6)
DDR_D20: U1.AC27(DDR1_D20) U7.F2(DQ2)
DDR_D21: U1.Y19(DDR1_D21) U7.F7(DQ1)
DDR_D22: U1.AB27(DDR1_D22) U7.H7(DQ7)
DDR_D23: U1.Y20(DDR1_D23) U7.F8(DQ3)
DDR_D24: U1.AA23(DDR1_D24) U7.D7(DQ8)
DDR_D25: U1.Y22(DDR1_D25) U7.C3(DQ9)
DDR_D26: U1.Y23(DDR1_D26) U7.B8(DQ14)
DDR_D27: U1.AA24(DDR1_D27) U7.A2(DQ13)
DDR_D28: U1.Y24(DDR1_D28) U7.C2(DQ11)
DDR_D29: U1.AA26(DDR1_D29) U7.A7(DQ12)
DDR_D30: U1.AA25(DDR1_D30) U7.C8(DQ10)
DDR_D31: U1.AA28(DDR1_D31) U7.A3(DQ15)
DDR_DQM0: U1.AD23(DDR1_DQM0) U5.E7(LDM)
DDR_DQM1: U1.AB23(DDR1_DQM1) U5.D3(UDM)
DDR_DQM2: U1.AC26(DDR1_DQM2) U7.E7(LDM)
DDR_DQM3: U1.AA27(DDR1_DQM3) U7.D3(UDM)
DDR_DQS0: U1.AH25(DDR1_DQS0) U5.F3(LDQS)
DDR_DQS1: U1.AE27(DDR1_DQS1) U5.C7(UDQS)
DDR_DQS2: U1.AD27(DDR1_DQS2) U7.F3(LDQS)
DDR_DQS3: U1.Y28(DDR1_DQS3) U7.C7(UDQS)
DDR_DQSN0: U1.AG25(DDR1_DQS0N) U5.G3(LDQSN)
DDR_DQSN1: U1.AE28(DDR1_DQS1N) U5.B7(UDQSN)
DDR_DQSN2: U1.AD28(DDR1_DQS2N) U7.G3(LDQSN)
DDR_DQSN3: U1.Y27(DDR1_DQS3N) U7.B7(UDQSN)
DDR_ODT: R75.2(P2) U1.AE20(DDR1_ODT0) U5.K1(ODT) U6.K1(ODT) U7.K1(ODT)
DDR_RASN: R51.2(P2) U1.AF20(DDR1_RASN) U5.J3(RASN) U6.J3(RASN) U7.J3(RASN)
DDR_RESETN: R912.2 U1.AG21(DDR1_RST) U5.T2(RESETN) U6.T2(RESETN) U7.T2(RESETN)
DDR_WEN: R53.2(P2) U1.AH21(DDR1_WEN) U5.L3(WEN) U6.L3(WEN) U7.L3(WEN)
DDRECC_D0: U1.W22(DDR1_ECC_D0) U6.E3(DQ0)
DDRECC_D1: U1.V23(DDR1_ECC_D1) U6.F7(DQ1)
DDRECC_D2: U1.W19(DDR1_ECC_D2) U6.H8(DQ5)
DDRECC_D3: U1.W23(DDR1_ECC_D3) U6.F8(DQ3)
DDRECC_D4: U1.Y25(DDR1_ECC_D4) U6.F2(DQ2)
DDRECC_D5: U1.V24(DDR1_ECC_D5) U6.H7(DQ7)
DDRECC_D6: U1.V25(DDR1_ECC_D6) U6.H3(DQ4)
DDRECC_D7: U1.Y26(DDR1_ECC_D7) U6.G2(DQ6)
DDRECC_DQM: U1.V26(DDR1_ECC_DQM) U6.E7(LDM)
DDRECC_DQS: U1.V27(DDR1_ECC_DQS) U6.F3(LDQS)
DDRECC_DQSN: U1.V28(DDR1_ECC_DQSN) U6.G3(LDQSN)
DRAIN0: D5.1(CATHODE) J37.19 U73.3(DRAIN0)
DRAIN1: D6.1(CATHODE) J37.20 U73.4(DRAIN1)
DRAIN2: D7.1(CATHODE) J37.21 U73.5(DRAIN2)
DRAIN3: D8.1(CATHODE) J37.22 U73.6(DRAIN3)
DRAIN4: D9.1(CATHODE) J37.23 U73.11(DRAIN4)
DRAIN5: D10.1(CATHODE) J37.24 U73.12(DRAIN5)
DRAIN6: D11.1(CATHODE) J37.25 U73.13(DRAIN6)
DRAIN7: D12.1(CATHODE) J37.26 U73.14(DRAIN7)
EECS: U37.63(EECS) U38.1(CS)
EEDATA: R495.1(P1) U37.61(EEDATA) U38.3(DI)
EESK: U37.62(EESK) U38.2(CLK)
EMMC_RSTN: R564.2(P2) R741.1 U43.K5(RSTN)
EMU2: J18.13(TR_CLK0) R711.1(P1)
EMU3: J18.17(TRD0.0) R712.1(P1)
EMU4: J18.23(TRD0.3) R713.1(P1)
EMU5: J18.25(TRD0.4) R714.1(P1)
EMU6: J18.27(TRD0.5) R715.1(P1)
EMU7: J18.29(TRD0.6) R716.1(P1)
EMU8: J18.31(TRD0.7) R717.1(P1)
EMU9: J18.33(TRD0.8) R718.1(P1)
EMU10: J18.35(TRD0.9) R719.1(P1)
EMU11: J18.37(TRD3.0) R720.1(P1)
EMU12: J18.39(TRD3.1) R721.1(P1)
EMU13: J18.41(TRD3.2) R722.1(P1)
EMU14: J18.43(TRD3.3) R723.1(P1)
EMU15: J18.45(TRD3.4) R724.1(P1)
EMU16: J18.47(TRD3.5) R725.1(P1)
EMU17: J18.49(TRD3.6) R726.1(P1)
EMU18: J18.51(TRD3.7) R727.1(P1)
EMU19: J18.53(TRD3.8) R728.1(P1)
EMU_RSTN: C223.1 J18.6(RESETN) R429.2(P2) R450.1(P1)
EMU_USB_DM: J19.2(DM) U36.5(IO2) U37.7(DM)
EMU_USB_DP: J19.3(DP) U36.3(IO1) U37.8(DP)
ETH0_LDO_O: Q7.G(GATE) U21.43(LDO_O)
ETH0_MDC: R294.1(P1) U21.36(MDC)
ETH0_MDIO: R295.1(P1) U21.37(MDIO)
ETH0_RXCLK: R288.1 R317.2(P2) U21.35(RX_CLK)
ETH0_RXD0: R289.1 R299.2 U21.32(RXD0)
ETH0_RXD1: R290.1 R301.2 U21.31(RXD1)
ETH0_RXD2: R291.1 R306.2 U21.28(RXD2)
ETH0_RXD3: R292.1 R309.2 U21.27(RXD3)
ETH0_RXDV: R285.1 R304.2(P2) U21.33(RX_DV)
ETH0_TXCLK: R281.1 U21.24(GTX_CLK)
ETH0_TXD0: R282.1 U21.19(TXD0)
ETH0_TXD1: R287.1 U21.20(TXD1)
ETH0_TXD2: R283.1 U21.21(TXD2)
ETH0_TXD3: R284.1 U21.22(TXD3)
ETH0_TXEN: R286.1 U21.25(TX_EN)
ETH0GB_25MHZCLK: R315.2 U21.46(XI)
ETH1_LDO_O: Q8.G(GATE) U24.43(LDO_O)
ETH1_MDC: R338.1(P1) U24.36(MDC)
ETH1_MDIO: R339.1(P1) U24.37(MDIO)
ETH1_RESETN: C189.1 D4.2(ANODE) R324.1(P1) U24.42(RESET_N) U26.4(Y)
ETH1_RXCLK: R328.1 R361.2(P2) U24.35(RX_CLK)
ETH1_RXD0: R333.1 R343.2 U24.32(RXD0)
ETH1_RXD1: R334.1 R345.2 U24.31(RXD1)
ETH1_RXD2: R335.1 R352.2 U24.28(RXD2)
ETH1_RXD3: R336.1 R353.2 U24.27(RXD3)
ETH1_RXDV: R329.1 R348.2(P2) U24.33(RX_DV)
ETH1_TXCLK: R325.1 U24.24(GTX_CLK)
ETH1_TXD0: R330.1 U24.19(TXD0)
ETH1_TXD1: R331.1 U24.20(TXD1)
ETH1_TXD2: R327.1 U24.21(TXD2)
ETH1_TXD3: R332.1 U24.22(TXD3)
ETH1_TXEN: R326.1 U24.25(TX_EN)
ETH1GB_25MHZCLK: R359.2 U24.46(XI)
ETH_MDIO_CLK: R95.2(P2) R294.2(P2) R338.2(P2) U1.V1(MDIO_MCLK)
ETH_MDIO_DATA: R105.2(P2) R279.1 R295.2(P2) R339.2(P2) U1.U4(MDIO_D)
ETHER0_D0N: J10.10 U21.3(TXRXM_A)
ETHER0_D0P: J10.9 U21.2(TXRXP_A)
ETHER0_D1N: J10.8 U21.6(TXRXM_B)
ETHER0_D1P: J10.7 U21.5(TXRXP_B)
ETHER0_D2N: J10.6 U21.8(TXRXM_C)
ETHER0_D2P: J10.5 U21.7(TXRXP_C)
ETHER0_D3N: J10.4 U21.11(TXRXM_D)
ETHER0_D3P: J10.3 U21.10(TXRXP_D)
ETHER1_D0N: J12.10 U24.3(TXRXM_A)
ETHER1_D0P: J12.9 U24.2(TXRXP_A)
ETHER1_D1N: J12.8 U24.6(TXRXM_B)
ETHER1_D1P: J12.7 U24.5(TXRXP_B)
ETHER1_D2N: J12.6 U24.8(TXRXM_C)
ETHER1_D2P: J12.5 U24.7(TXRXP_C)
ETHER1_D3N: J12.4 U24.11(TXRXM_D)
ETHER1_D3P: J12.3 U24.10(TXRXP_D)
F_ADBUS0: R474.2(P2) U37.16(ADBUS0)
F_ADBUS1: R475.2(P2) U37.17(ADBUS1)
F_ADBUS2: R480.2(P2) U37.18(ADBUS2)
F_ADBUS3: R481.2(P2) U37.19(ADBUS3)
F_ADBUS4: R476.2(P2) U37.21(ADBUS4)
F_ADBUS5: R478.2(P2) U37.26(ACBUS0)
F_ADBUS6: R477.2(P2) U37.23(ADBUS6)
F_ADBUS7: R483.2(P2) U37.30(ACBUS4)
FT_SRESET: R478.1(P1) R484.2(P2) U34.1(A)
FT_SRESETB: R473.2(P2) U35.4(Y)
FT_SRESETN: U34.4(Y) U35.2(A)
FT_VBUS: R492.1(P1) U34.2(B)
FTDI_REF: R479.1(P1) U37.6(REF)
FTDI_VPHY: C231.2 C234.2 FB10.1 U37.4(VPHY)
FTDI_VPLL: C237.2 C240.2 FB11.1 U37.9(VPLL)
GB_ETH0_INTN: R297.1(P1) R662.1(P1) U21.38(INT_N / PME_N2)
GB_ETH1_INTN: R342.1(P1) R663.1(P1) U24.38(INT_N / PME_N2)
GBETH0_RESETN: C168.1 D3.2(ANODE) R280.1(P1) U21.42(RESET_N) U22.4(Y)
GPIO_AM572X_USB2_ID: R788.2(P2) U1.AF2(VIN1A_D12/GPIO)
GPIO_PCIE_RSTDRVN: R659.1(P1) U44.1(O\E\)
GPIO_PCIE_SWRSTN: R660.1(P1) U85.2(B)
GPIO_PRU1_ETH0_RESETN: R112.2(P2) R673.1(P1)
GPIO_PRU1_ETH1_RESETN: R154.2(P2) R674.1(P1)
GPIO_PRU2_ETH0_RESETN: R195.2(P2) R675.1(P1)
GPIO_PRU2_ETH1_RESETN: R234.2(P2) R676.1(P1)
GPIO_TOUCH_RESETN: R661.1(P1) R792.2(P2)
GPIO_USB2_VBUS_DET: R809.1(P1) R811.2 U96.4(Y)
GPIO_VPP_PWR_EN: R638.2(P2) U1.AE3(VIN1A_D17)
GPMC_CLK: J21.58 R689.1(P1)
GPMC_CS0: J21.4 R686.1(P1)
GPMC_CS3: J21.6 R688.1(P1)
HAPTICS_N: Q16.D(DRAIN) U18.2(N-)
HAPTICS_P: C316.1 R113.1 U18.1(P+)
HDMI_CEC: R683.1(P1) U46.1(CEC_A)
HDMI_CLK+: J24.10(CLK+) L29.3 U46.16(TMDS_CK+)
HDMI_CLK-: J24.12(CLK-) L29.2 U46.15(TMDS_CK-)
HDMI_CT_HPD: R558.2(P2) R559.1(P1) U46.12(CT_HPD)
HDMI_DDC_SCL: R795.1(P1) U46.2(SCL_A)
HDMI_DDC_SDA: R796.1(P1) U46.3(SDA_A)
HDMI_HPLG: R682.1(P1) U46.4(HPD_A)
HDMI_LSOE: R558.1(P1) U46.5(LS_OE)
HDMI_TX0+: J24.7(DAT0+) L30.3 U46.18(TMDS_D0+)
HDMI_TX0-: J24.9(DAT0-) L30.2 U46.17(TMDS_D0-)
HDMI_TX1+: J24.4(DAT1+) L31.3 U46.21(TMDS_D1+)
HDMI_TX1-: J24.6(DAT1-) L31.2 U46.20(TMDS_D1-)
HDMI_TX2+: J24.1(DAT2+) L32.3 U46.23(TMDS_D2+)
HDMI_TX2-: J24.3(DAT2-) L32.2 U46.22(TMDS_D2-)
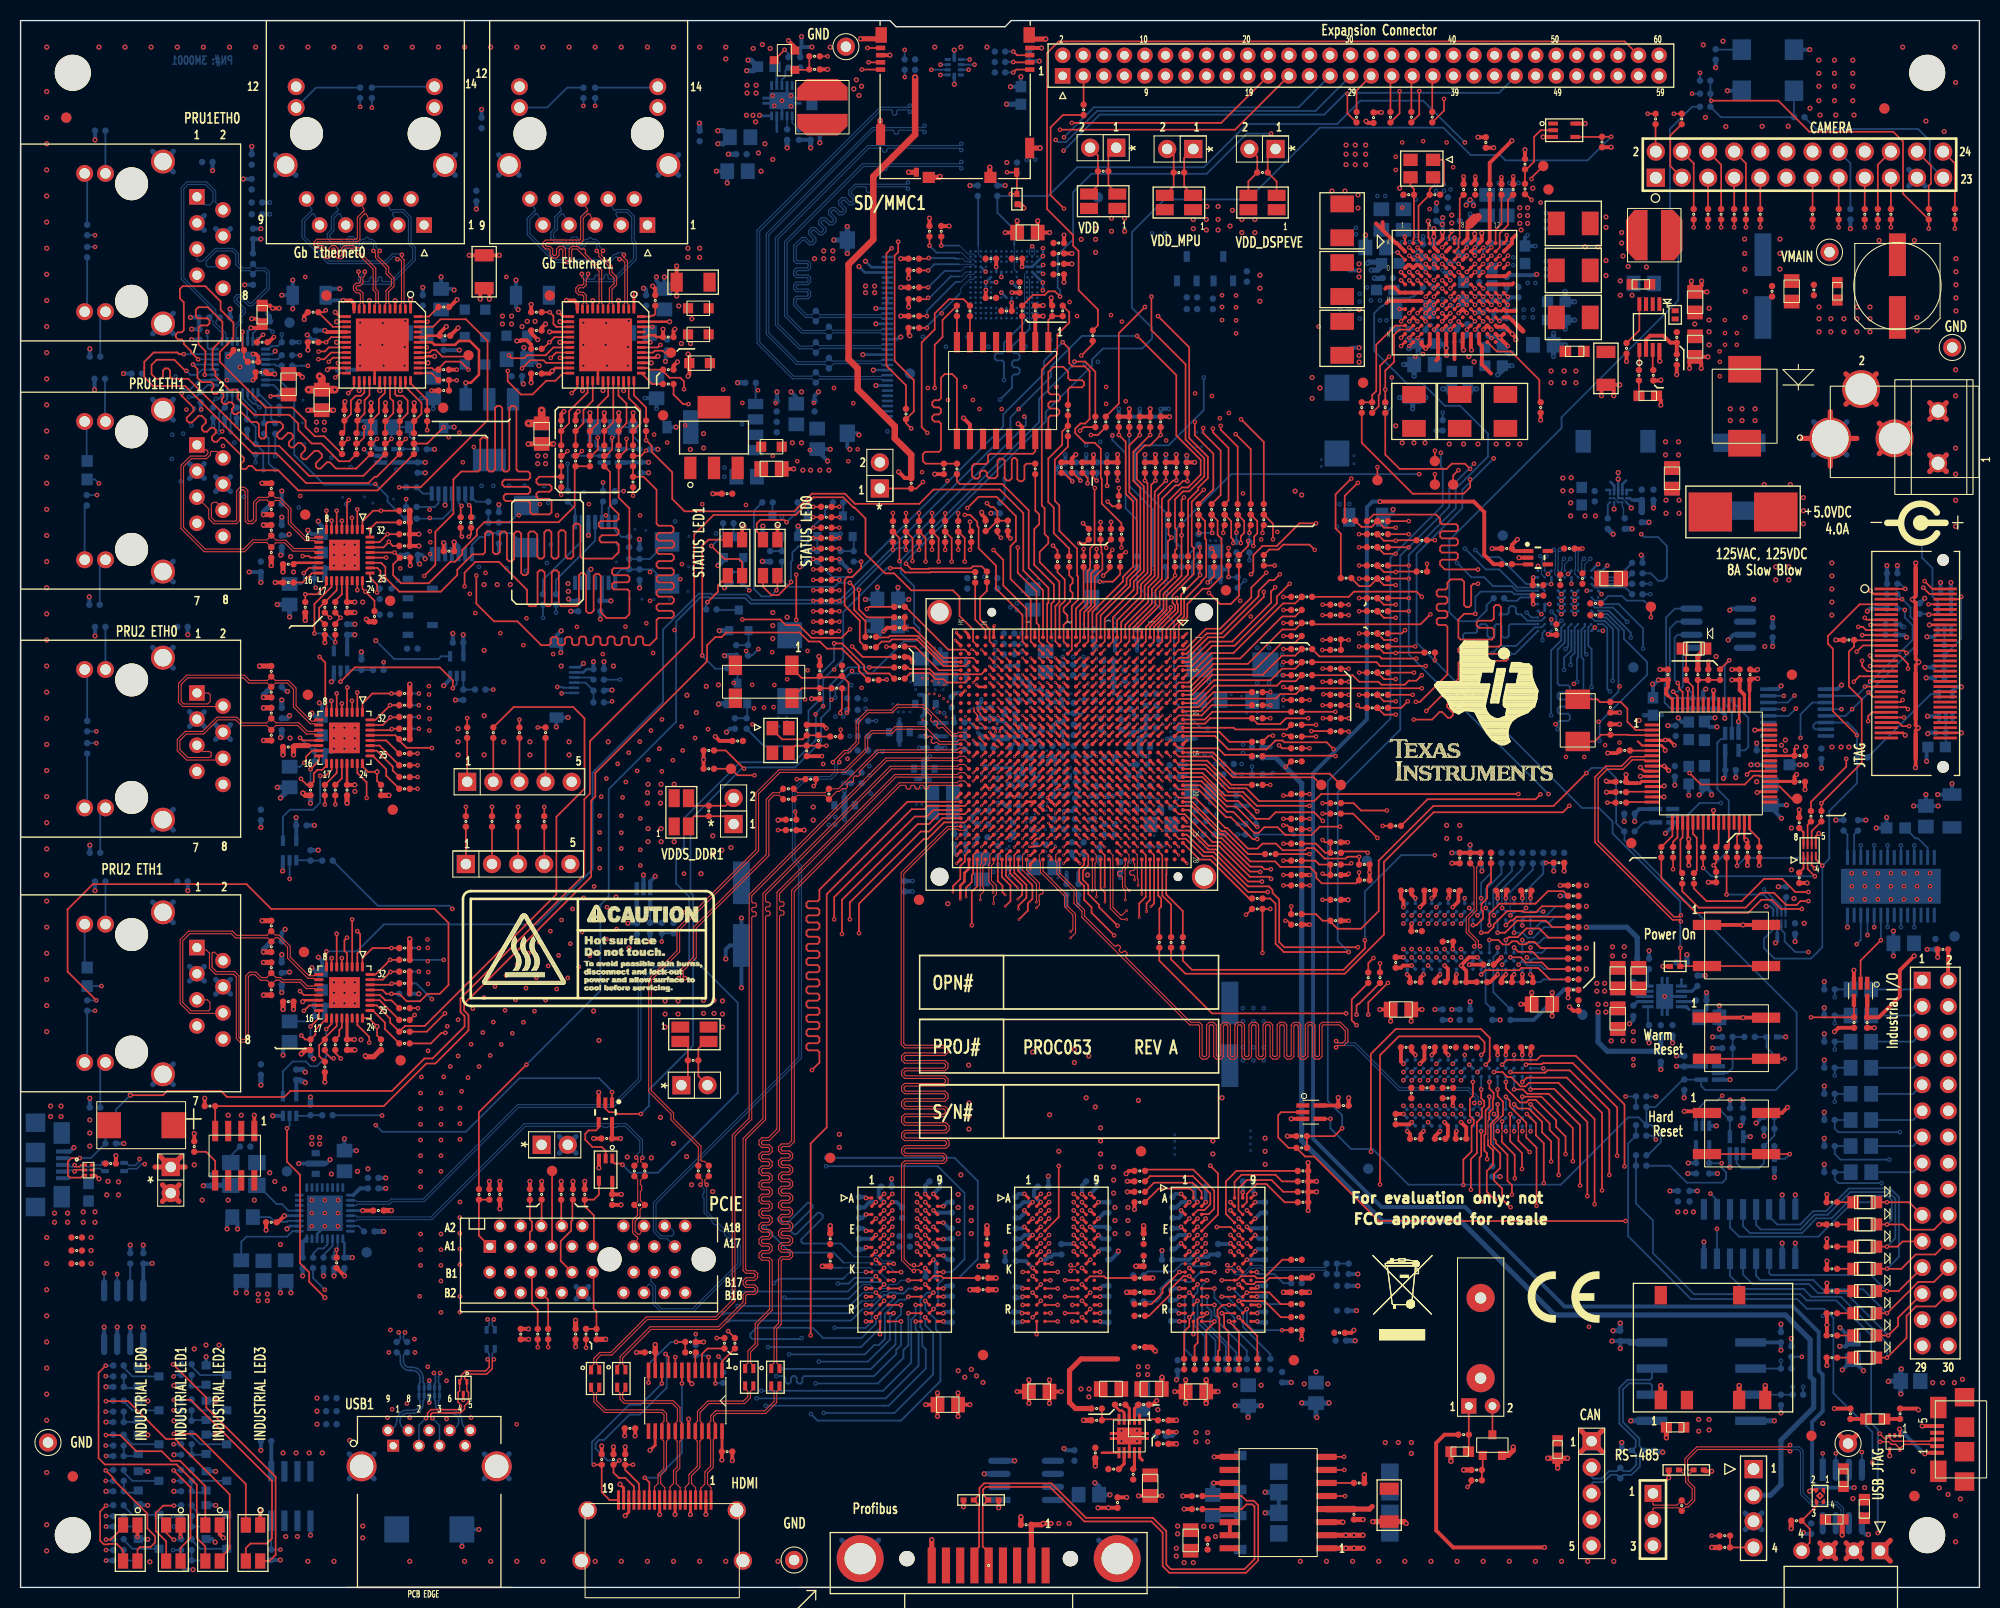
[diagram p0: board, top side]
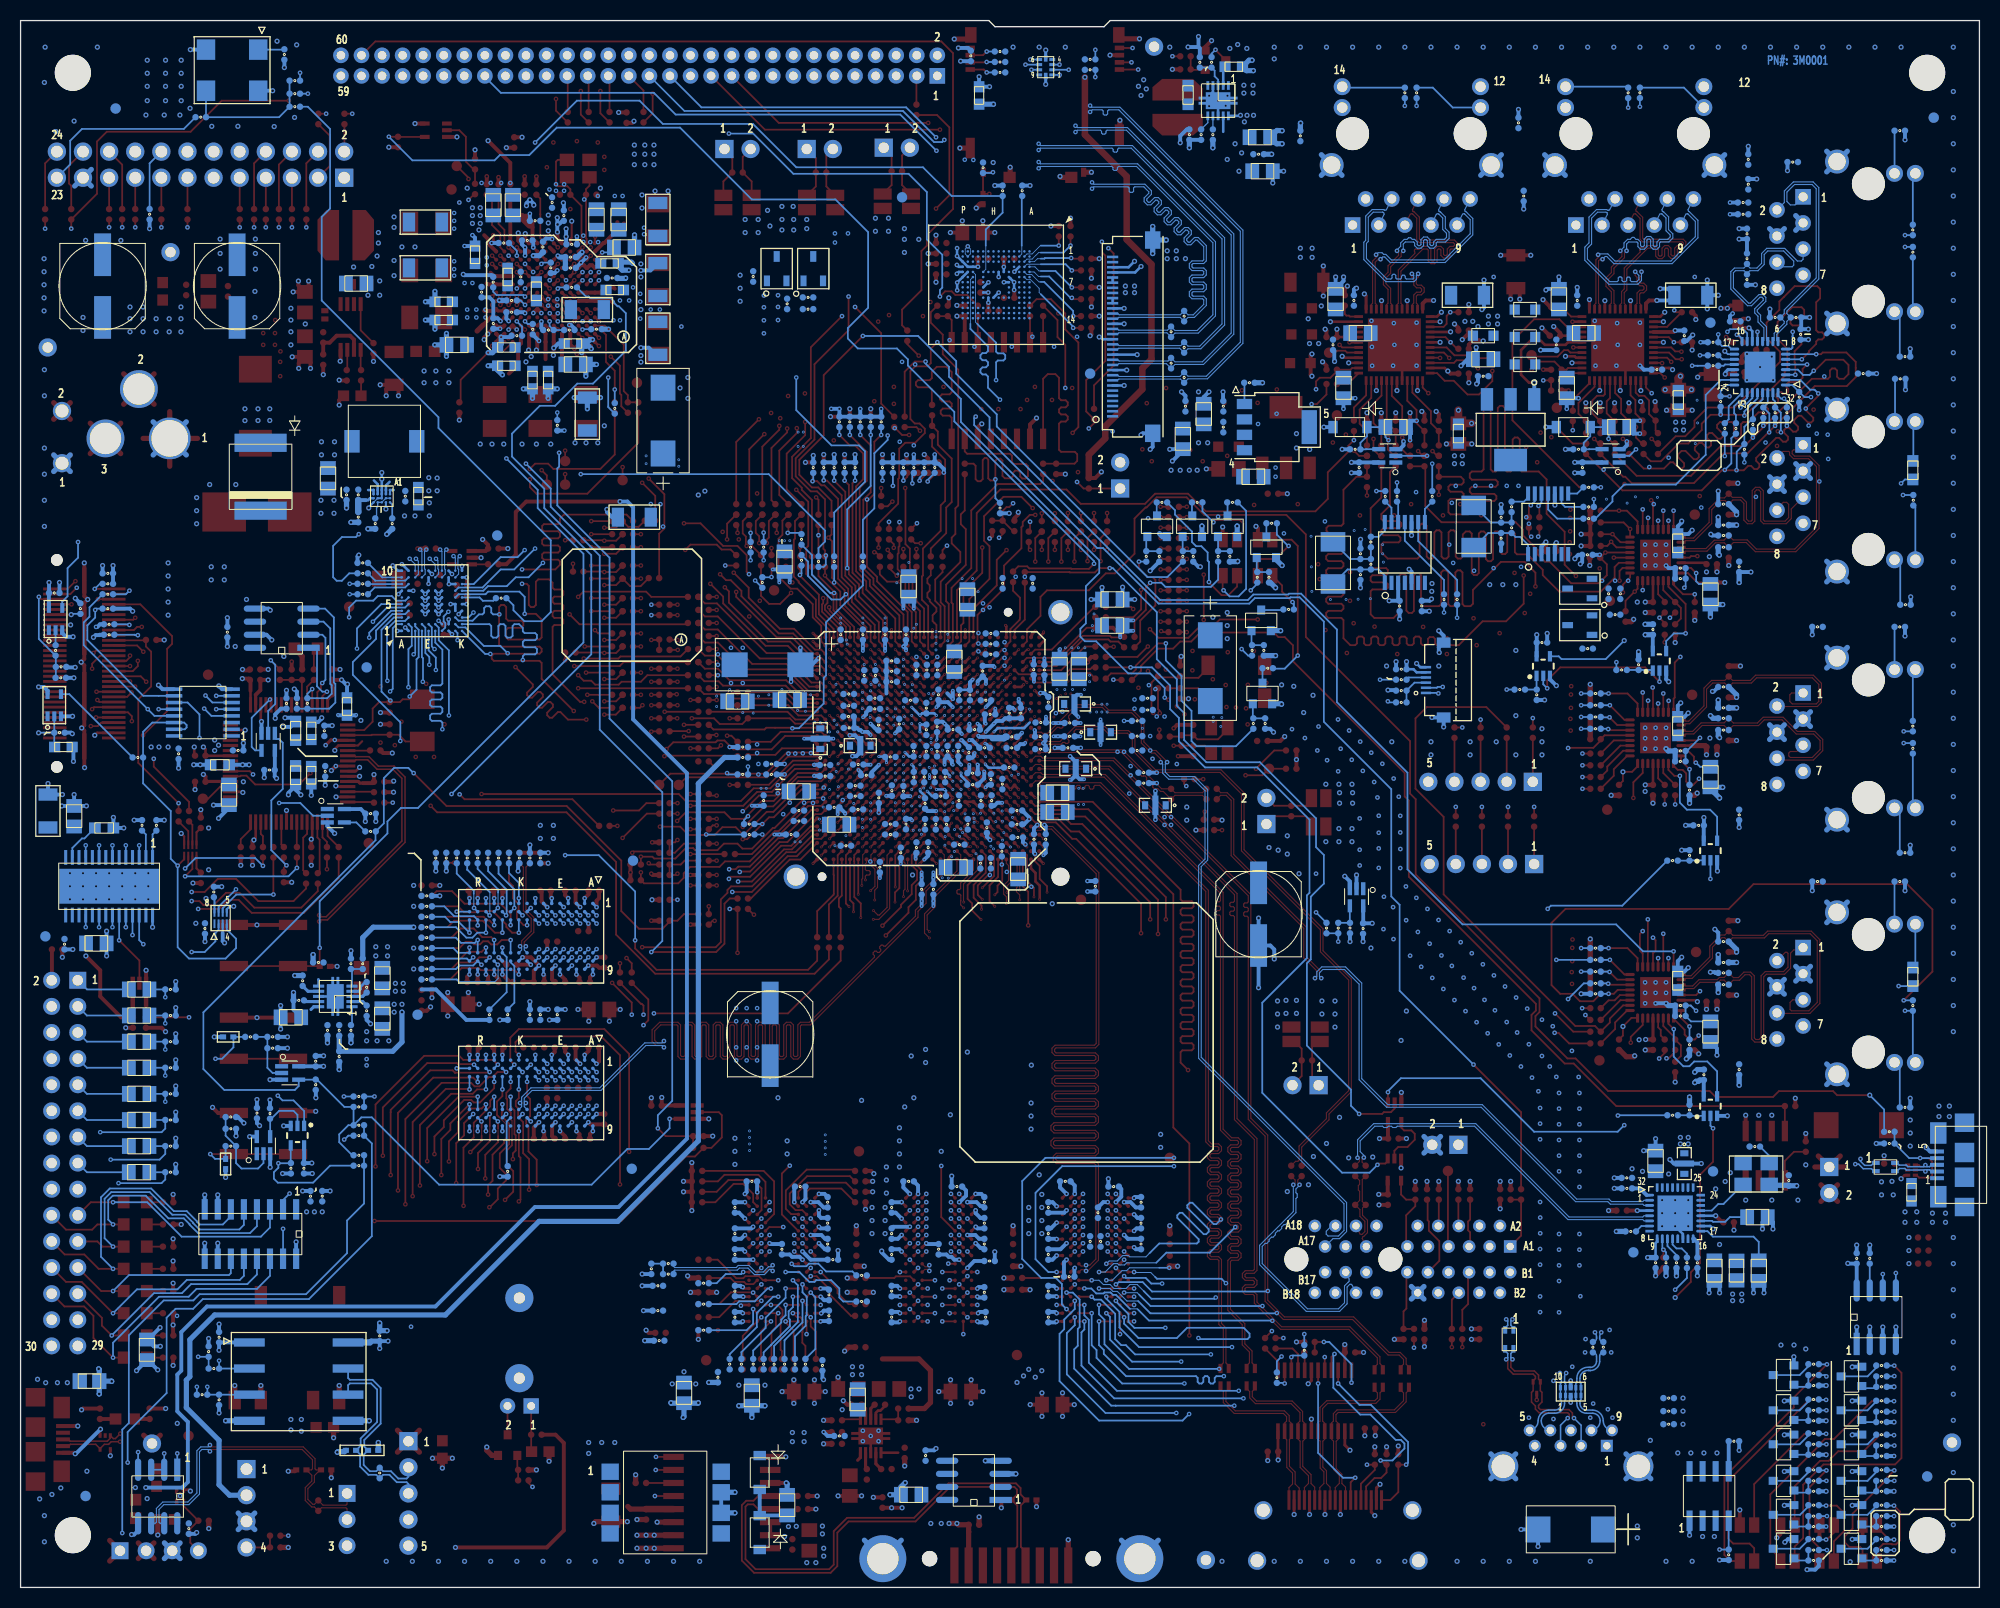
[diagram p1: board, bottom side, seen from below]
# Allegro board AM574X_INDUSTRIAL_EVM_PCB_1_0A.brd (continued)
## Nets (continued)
HDMICONN_CEC: J24.13(CEC) U46.7(CEC_B)
HDMICONN_HPLG: J24.19(HPLG) R561.2 U46.10(HPD_B)
HDMICONN_I2CSCL: J24.15(SCL) R560.1(P1) U46.8(SCL_B)
HDMICONN_I2CSDA: J24.16(SDA) R562.1(P1) U46.9(SDA_B)
HDQ: J21.50 R300.1(P1)
IND_I2C_SCL: J17.2 J21.27 R14.2(P2) R275.1(P1) R314.2(P2) R393.1(P1) R567.2(P2) R652.2(P2) U33.6(SCL)
IND_I2C_SDA: J17.1 J21.29 R15.2(P2) R277.1(P1) R312.2(P2) R394.1(P1) R585.2(P2) R653.2(P2) U33.5(SDA)
INDUS_INPUT0: J37.1 R368.2
INDUS_INPUT1: J37.3 R370.2
INDUS_INPUT2: J37.5 R372.2
INDUS_INPUT3: J37.7 R374.2
INDUS_INPUT4: J37.9 R373.2
INDUS_INPUT5: J37.11 R375.2
INDUS_INPUT6: J37.13 R376.2
INDUS_INPUT7: J37.15 R378.2
INDUS_INPUTCLK: R367.1(P1) U72.25(CLK)
INDUS_INPUTCSN: R369.1(P1) U72.24(C\E\)
INDUS_INPUTLDN: R371.1(P1) U72.26(L\D\)
INDUS_INPUTSO: U28.2(A) U72.23(SOP)
JTAG_EMU0: J18.19(TRD0.1) R422.1(P1) R554.1(P1) U1.G21(EMU0)
JTAG_EMU1: J18.21(TRD0.2) R423.1(P1) R555.1(P1) U1.D24(EMU1)
JTAG_TCK: R3.2 U1.E20(TCK) U63.13(1B1)
JTAG_TDI: J18.5(TDI) U1.D23(TDI) U63.12(1B2)
JTAG_TDO: J18.4(TDO) U1.F19(TDO) U75.2(A1)
JTAG_TMS: J18.2(TMS) U1.F18(TMS) U63.11(2B1)
JTAG_TRSTN: J18.8(TRSTPD) R433.2(P2) U1.D20(TRSTN) U63.10(2B2)
JTAGPOD_PRES: R677.1(P1) U19.4(Y)
LCD_B0: R605.1(P1) U89.J3(PD0)
LCD_B1: R606.1(P1) U89.K3(PD1)
LCD_B2: R607.1(P1) U89.J2(PD2)
LCD_B3: R608.1(P1) U89.K2(PD3)
LCD_B4: R609.1(P1) U89.J1(PD4)
LCD_B5: R610.1(P1) U89.K1(PD5)
LCD_B6: R612.1(P1) U89.G2(PD6)
LCD_B7: R611.1(P1) U89.G1(PD7)
LCD_BACKLIGHT: R416.2(P2) U1.D1(VIN2A_D2/ECAP1_IN_PWM1)
LCD_CLKN: J16.20 R632.1(P1) U89.F10(MIPI_CN)
LCD_CLKP: J16.21 R632.2(P2) U89.F9(MIPI_CP)
LCD_DEN: R634.1(P1) U89.J7(DE)
LCD_G0: R613.1(P1) U89.F2(PD8)
LCD_G1: R614.1(P1) U89.F1(PD9)
LCD_G2: R616.1(P1) U89.E2(PD10)
LCD_G3: R615.1(P1) U89.E1(PD11)
LCD_G4: R617.1(P1) U89.D2(PD12)
LCD_G5: R619.1(P1) U89.D1(PD13)
LCD_G6: R620.1(P1) U89.C2(PD14)
LCD_G7: R618.1(P1) U89.C1(PD15)
LCD_HS: R636.1(P1) U89.K8(HSYNC)
LCD_MIPI0N: J16.17 R630.2(P2) U89.J10(MIPI_D0N)
LCD_MIPI0P: J16.18 R630.1(P1) U89.J9(MIPI_D0P)
LCD_MIPI1N: J16.14 R631.2(P2) U89.G10(MIPI_D1N)
LCD_MIPI1P: J16.15 R631.1(P1) U89.G9(MIPI_D1P)
LCD_MIPI2N: J16.11 R633.1(P1) U89.D10(MIPI_D2N)
LCD_MIPI2P: J16.12 R633.2(P2) U89.D9(MIPI_D2P)
LCD_MIPI3N: J16.8 R687.1(P1) U89.C10(MIPI_D3N)
LCD_MIPI3P: J16.9 R687.2(P2) U89.C9(MIPI_D3P)
LCD_PCLK: R565.1(P1) U89.J6(PCLK)
LCD_R0: R621.1(P1) U89.B2(PD16)
LCD_R1: R622.1(P1) U89.A2(PD17)
LCD_R2: R624.1(P1) U89.B3(PD18)
LCD_R3: R623.1(P1) U89.A3(PD19)
LCD_R4: R625.1(P1) U89.B4(PD20)
LCD_R5: R627.1(P1) U89.A4(PD21)
LCD_R6: R628.1(P1) U89.B5(PD22)
LCD_R7: R626.1(P1) U89.A5(PD23)
LCD_VS: R635.1(P1) U89.K7(VSYNC)
MMC2_CLK: U1.J7(GPMC_A23/MMC2_CLK) U43.M6(CLK)
MMC2_CMD: R513.1(P1) U1.H6(GPMC_CS1/MMC2_CMD) U43.M5(CMD)
MMC2_DAT0: R505.1(P1) U1.J4(GPMC_A24/MMC2_DAT0) U43.A3(DAT0)
MMC2_DAT1: R506.1(P1) U1.J6(GPMC_A25/MMC2_DAT1) U43.A4(DAT1)
MMC2_DAT2: R507.1(P1) U1.H4(GPMC_A26/MMC2_DAT2) U43.A5(DAT2)
MMC2_DAT3: R508.1(P1) U1.H5(GPMC_A27/MMC2_DAT3) U43.B2(DAT3)
MMC2_DAT4: R509.1(P1) U1.K7(GPMC_A19/MMC2_DAT4) U43.B3(DAT4)
MMC2_DAT5: R510.1(P1) U1.M7(GPMC_A20/MMC2_DAT5) U43.B4(DAT5)
MMC2_DAT6: R511.1(P1) U1.J5(GPMC_A21/MMC2_DAT6) U43.B5(DAT6)
MMC2_DAT7: R512.1(P1) U1.K6(GPMC_A22/MMC2_DAT7) U43.B6(DAT7)
MMC_CD: J15.10(CD) R408.1(P1) R409.1(P1) U84.1
MMC_CLK: J15.5(CLOCK) R405.1(P1) U30.1(IO1)
MMC_CMD: J15.3(CMD) R398.1 R404.1(P1) U30.7(IO5)
MMC_D0: J15.7(DAT0) R399.1 R406.1(P1) U30.2(IO2)
MMC_D1: J15.8(DAT1) R400.1 R407.1(P1) U30.3(IO3)
MMC_D2: J15.1(DAT2) R401.1 R402.1(P1) U30.6(IO4)
MMC_D3: J15.2(CD/DAT3) R397.1 R403.1(P1) U30.8(IO6)
OSC0_OUT: C1.1 R4.1(P1) R5.2(P2) Y1.1
PCI_CONN_REFN: C436.1 U45.5(OUT0N)
PCI_CONN_REFP: C437.1 U45.6(OUT0P)
PCIE_CRDPRESENT: R650.1(P1) R664.1(P1)
PCIE_PERSTN: J22.A11 R545.1 U44.4(Y)
PCIE_REFCLKN: C436.2 J22.A14 R580.2(P2)
PCIE_REFCLKP: C437.2 J22.A13 R580.1(P1)
PCIE_RESETN: R568.2(P2) R919.1(P1) R920.1(P1) U85.1(A)
PCIE_SMB_CLK: J22.B5 R652.1(P1)
PCIE_SMB_DATA: J22.B6 R653.1(P1)
PCIE_TCK: J22.A5 R542.2
PCIE_TDI: J22.A6 R543.2
PCIE_TDO: J22.A7 TP20.1
PCIE_TMS: J22.A8 R544.2
PCIE_TRSTN: J22.B9 R539.2
PCIE_WAKEN: R655.1(P1) R665.1(P1)
PCIECONN_PETN0: C477.2 J22.B15
PCIECONN_PETP0: C478.2 J22.B14
PHY0_LED_ACTN: R293.1 R321.2(P2) U21.17(LED1 / PME_N1)
PHY0_LED_LINKN: R296.1 R319.2(P2) U21.15(LED2)
PHY1_LED_ACTN: R337.1 R364.2 U24.17(LED1 / PME_N1)
PHY1_LED_LINKN: R340.1 R363.2(P2) U24.15(LED2)
PHY_RESETN: R915.1(P1) R921.1(P1) U22.2(A) U26.2(A) U68.2(B) U69.2(B) U70.2(B) U71.2(B)
PMIC_EN: R645.1 R928.2(P2) R929.1(P1) U3.E5(NSLEEP)
PMIC_INT: R666.1(P1) U3.K1(INT)
PMIC_RESET_IN: R794.1(P1) U3.K9(RESET_IN)
PMIC_RESET_OUTN: R9.1(P1) R814.2 U3.G6(RESET_OUT)
PORZN: C213.1 R6.2(P2) R499.1(P1) R920.2(P2) R921.2(P2) R926.1(P1) U98.4(Y)
PR1_EDC_LATCH0: R743.2(P2) U1.E2(VIN2A_D3)
PR1_EDC_SYNC0: R744.2(P2) U1.D2(VIN2A_D4)
PR1_EDIO_DATA_OUT1: J4.4 R119.1(P1)
PR1_EDIO_DATA_OUT3: J4.3 R118.1(P1)
PR1_EDIO_DATA_OUT4: J7.3 R198.1(P1)
PR1_EDIO_DATA_OUT6: J7.4 R199.1(P1)
PR2_EDC_LATCH0: J21.13 R748.1(P1) R910.1(P1)
PR2_EDC_LATCH1: J21.15 R749.1(P1) R911.1(P1)
PR2_EDC_SYNC0: J21.17 R750.1(P1) R908.1(P1)
PR2_EDC_SYNC1: J21.19 R751.1(P1) R909.1(P1)
PR2_MII0_RXDV: J7.2 R197.1(P1)
PR2_MII0_TXEN: J7.1 R196.1(P1)
PR2_MII1_RXDV: J4.2 R117.1(P1)
PR2_MII1_TXEN: J4.1 R115.1(P1)
PR2_UART0_RXD: J21.54 R906.1(P1)
PR2_UART0_TXD: J21.56 R907.1(P1)
PROFIBUS_A: J14.3 R577.1(P1) U74.12(A) U81.1
PROFIBUS_B: J14.8 R578.2(P2) U74.13(B) U80.1
PRU1ETH0_25MHZCLK: R310.2 U9.23(XI)
PRU1ETH0_COL: R95.1(P1) R104.2(P2) R105.1(P1) R106.2(P2) U9.29(COL)
PRU1ETH0_CRS: R94.1(P1) U9.27(CRS)
PRU1ETH0_INTN: R669.2(P2) U9.8(PWRDNN/INTN)
PRU1ETH0_LINKLED: R76.1(P1) R93.2(P2) U9.17(LED_LINK)
PRU1ETH0_MDC: R96.1(P1) U9.20(MDC)
PRU1ETH0_MDIO: R98.1(P1) U9.19(MDIO)
PRU1ETH0_RESETN: U9.18(RESET_N) U68.4(Y)
PRU1ETH0_RXCLK: R83.1(P1) U9.25(RX_CLK)
PRU1ETH0_RXD0: R88.1(P1) R111.2(P2) U9.30(RXD_0)
PRU1ETH0_RXD1: R90.1(P1) R110.2(P2) U9.31(RXD_1)
PRU1ETH0_RXD2: R91.1(P1) R109.2(P2) U9.32(RXD_2)
PRU1ETH0_RXD3: R92.1(P1) R108.2(P2) U9.1(RXD_3)
PRU1ETH0_RXDV: R86.1(P1) U9.26(RX_DV)
PRU1ETH0_RXERR: R87.1(P1) U9.28(RX_ERR)
PRU1ETH0_TXCLK: R79.1(P1) U9.2(TX_CLK)
PRU1ETH0_TXD0: R81.1(P1) U9.4(TXD_0)
PRU1ETH0_TXD1: R84.1(P1) U9.5(TXD_1)
PRU1ETH0_TXD2: R85.1(P1) U9.6(TXD_2)
PRU1ETH0_TXD3: R82.1(P1) U9.7(TXD_3)
PRU1ETH0_TXEN: R80.1(P1) U9.3(TX_EN)
PRU1ETH1_25MHZCLK: R313.2 U13.23(XI)
PRU1ETH1_COL: R148.1(P1) R150.1(P1) R151.2(P2) R152.1(P1) U13.29(COL)
PRU1ETH1_CRS: R139.1(P1) U13.27(CRS)
PRU1ETH1_INTN: R670.2(P2) U13.8(PWRDNN/INTN)
PRU1ETH1_LINKLED: R131.1(P1) R138.2(P2) U13.17(LED_LINK)
PRU1ETH1_MDC: R140.1(P1) U13.20(MDC)
PRU1ETH1_MDIO: R120.1(P1) R142.1(P1) U13.19(MDIO)
PRU1ETH1_RESETN: U13.18(RESET_N) U69.4(Y)
PRU1ETH1_RXCLK: R129.1(P1) R750.2(P2) U13.25(RX_CLK)
PRU1ETH1_RXD0: R133.1(P1) R158.2(P2) U13.30(RXD_0)
PRU1ETH1_RXD1: R135.1(P1) R157.2(P2) R752.2(P2) U13.31(RXD_1)
PRU1ETH1_RXD2: R136.1(P1) R156.2(P2) U13.32(RXD_2)
PRU1ETH1_RXD3: R137.1(P1) R155.2(P2) R751.2(P2) U13.1(RXD_3)
PRU1ETH1_RXDV: R130.1(P1) U13.26(RX_DV)
PRU1ETH1_RXERR: R132.1(P1) R753.2(P2) U13.28(RX_ERR)
PRU1ETH1_TXCLK: R123.1(P1) U13.2(TX_CLK)
PRU1ETH1_TXD0: R125.1(P1) U13.4(TXD_0)
PRU1ETH1_TXD1: R126.1(P1) R749.2(P2) U13.5(TXD_1)
PRU1ETH1_TXD2: R127.1(P1) U13.6(TXD_2)
PRU1ETH1_TXD3: R128.1(P1) U13.7(TXD_3)
PRU1ETH1_TXEN: R124.1(P1) U13.3(TX_EN)
PRU1ETHER0_RDN: J3.2 R99.2(P2) U9.9(RD-)
PRU1ETHER0_RDP: J3.1 R100.2(P2) U9.10(RD+)
PRU1ETHER0_TDN: J3.6 R101.2(P2) U9.11(TD-)
PRU1ETHER0_TDP: J3.5 R102.2(P2) U9.12(TD+)
PRU1ETHER1_RDN: J5.6 R143.2(P2) U13.9(RD-)
PRU1ETHER1_RDP: J5.5 R144.2(P2) U13.10(RD+)
PRU1ETHER1_TDN: J5.2 R145.2(P2) U13.11(TD-)
PRU1ETHER1_TDP: J5.1 R146.2(P2) U13.12(TD+)
PRU2ETH0_25MHZCLK: R354.2 U15.23(XI)
PRU2ETH0_COL: R187.2(P2) R188.1(P1) R189.2(P2) U15.29(COL)
PRU2ETH0_CRS: R177.1(P1) U15.27(CRS)
PRU2ETH0_INTN: R671.2(P2) U15.8(PWRDNN/INTN)
PRU2ETH0_LINKLED: R159.1(P1) R176.2(P2) U15.17(LED_LINK)
PRU2ETH0_MDC: R179.1(P1) U15.20(MDC)
PRU2ETH0_MDIO: R181.1(P1) U15.19(MDIO)
PRU2ETH0_RESETN: U15.18(RESET_N) U70.4(Y)
PRU2ETH0_RXCLK: R165.1(P1) U15.25(RX_CLK)
PRU2ETH0_RXD0: R171.1(P1) R194.2(P2) U15.30(RXD_0)
PRU2ETH0_RXD1: R173.1(P1) R193.2(P2) U15.31(RXD_1)
PRU2ETH0_RXD2: R174.1(P1) R192.2(P2) U15.32(RXD_2)
PRU2ETH0_RXD3: R175.1(P1) R191.2(P2) U15.1(RXD_3)
PRU2ETH0_RXDV: R166.1(P1) U15.26(RX_DV)
PRU2ETH0_RXERR: R170.1(P1) U15.28(RX_ERR)
PRU2ETH0_TXCLK: R162.1(P1) U15.2(TX_CLK)
PRU2ETH0_TXD0: R163.1(P1) U15.4(TXD_0)
PRU2ETH0_TXD1: R164.1(P1) U15.5(TXD_1)
PRU2ETH0_TXD2: R168.1(P1) U15.6(TXD_2)
PRU2ETH0_TXD3: R169.1(P1) U15.7(TXD_3)
PRU2ETH0_TXEN: R167.1(P1) U15.3(TX_EN)
PRU2ETH1_25MHZCLK: R357.2 U17.23(XI)
PRU2ETH1_COL: R220.1(P1) R231.1(P1) R232.1(P1) U17.29(COL)
PRU2ETH1_CRS: R219.1(P1) U17.27(CRS)
PRU2ETH1_INTN: R672.2(P2) U17.8(PWRDNN/INTN)
PRU2ETH1_LINKLED: R200.1(P1) R218.2(P2) U17.17(LED_LINK)
PRU2ETH1_MDC: R221.1(P1) U17.20(MDC)
PRU2ETH1_MDIO: R201.1(P1) R223.1(P1) U17.19(MDIO)
PRU2ETH1_RESETN: U17.18(RESET_N) U71.4(Y)
PRU2ETH1_RXCLK: R209.1(P1) U17.25(RX_CLK)
PRU2ETH1_RXD0: R213.1(P1) R238.2(P2) U17.30(RXD_0)
PRU2ETH1_RXD1: R215.1(P1) R237.2(P2) U17.31(RXD_1)
PRU2ETH1_RXD2: R216.1(P1) R236.2(P2) U17.32(RXD_2)
PRU2ETH1_RXD3: R217.1(P1) R235.2(P2) U17.1(RXD_3)
PRU2ETH1_RXDV: R117.2(P2) R211.1(P1) U17.26(RX_DV)
PRU2ETH1_RXERR: R212.1(P1) U17.28(RX_ERR)
PRU2ETH1_TXCLK: R204.1(P1) U17.2(TX_CLK)
PRU2ETH1_TXD0: R206.1(P1) U17.4(TXD_0)
PRU2ETH1_TXD1: R208.1(P1) U17.5(TXD_1)
PRU2ETH1_TXD2: R210.1(P1) U17.6(TXD_2)
PRU2ETH1_TXD3: R207.1(P1) U17.7(TXD_3)
PRU2ETH1_TXEN: R115.2(P2) R205.1(P1) U17.3(TX_EN)
PRU2ETHER0_RDN: J6.2 R182.2(P2) U15.9(RD-)
PRU2ETHER0_RDP: J6.1 R183.2(P2) U15.10(RD+)
PRU2ETHER0_TDN: J6.6 R184.2(P2) U15.11(TD-)
PRU2ETHER0_TDP: J6.5 R185.2(P2) U15.12(TD+)
PRU2ETHER1_RDN: J8.6 R224.2(P2) U17.9(RD-)
PRU2ETHER1_RDP: J8.5 R225.2(P2) U17.10(RD+)
PRU2ETHER1_TDN: J8.2 R226.2(P2) U17.11(TD-)
PRU2ETHER1_TDP: J8.1 R227.2(P2) U17.12(TD+)
QSPI_CLK: R23.1(P1) R24.1(P1) R31.2(P2)
RS485_A: J39.1 R729.2(P2) U77.6(A) U82.1
RS485_B: J39.2 R729.1(P1) U77.7(B) U83.1
RSTOUTTOPMIC: R36.1(P1) R793.2(P2) U3.E6(NRESWARM)
RTCK: J18.7(RTCK) R426.1
SERDES_REF_CLKN: C438.1 U45.2(OUT1N)
SERDES_REF_CLKP: C439.1 U45.3(OUT1P)
SPI2_CS0N: J21.30 U1.B24(SPI2_CS0)
SPI2_DIN: J21.26 U1.G17(SPI2_D0)
SPI2_DOUT: J21.28 U1.B22(SPI2_D1)
SPI2_SCLK: J21.24 R684.2(P2)
SPIMEM_CLK: R31.1(P1) U4.16(SCK)
SPIMEM_CSN: R30.1(P1) U4.7(C\S\)
SPIMEM_D0: R25.1(P1) U4.15(SI/IO0)
SPIMEM_D1: R26.1(P1) U4.8(SO/IO1)
SPIMEM_D2: R22.1 R27.1(P1) U4.9(W\P\/IO2)
SPIMEM_D3: R28.1(P1) R799.1 U4.1(H\O\L\D\/IO3)
SRCCLK: R276.1 R586.2(P2)
SYS_RESETN: J21.25 R29.2(P2) R566.2(P2) R918.1(P1) R922.1(P1)
SYS_WARMRESETN: C570.1 R2.1 R7.2(P2) R473.1(P1) R915.2(P2) R918.2(P2) R919.2(P2) U47.4(Y) U78.4(Y) U97.4(Y)
TCK: J18.3(TCK) R3.1
TOUCH_INT: R418.2(P2) R802.2(P2)
TSC_INT: J17.4 R418.1(P1)
TSC_RESETN: J17.3 R420.2 R792.1(P1)
UARTX_RXD: R487.2(P2) U37.38(BDBUS0)
UARTX_TXD: R486.2(P2) U37.39(BDBUS1)
USB1_3_0_STDA_SSRX+: J23.6(STDA_SSRX+) U1.AE12(USB_RXP0) U95.2(D1-)
USB1_3_0_STDA_SSRX-: J23.5(STDA_SSRX-) U1.AF12(USB_RXN0) U95.1(D1+)
USB1_3_0_STDA_SSTX+: C555.2 J23.9(STDA_SSTX+) U95.5(D2-)
USB1_3_0_STDA_SSTX-: C554.2 J23.8(STDA_SSTX-) U95.4(D2+)
USB1_CONN_DM: J23.2(DM) L11.4 U64.2(D-)
USB1_CONN_DP: J23.3(DP) L11.3 U64.1(D+)
USB1_OVRCURN: R551.1 U66.5(O\C\)
USB1_VBUS_EN: R553.1 R557.1(P1) U66.4(EN)
USB2_CONN_DM: J45.2(DM) L33.3 U93.2(D-)
USB2_CONN_DP: J45.3(DP) L33.4 U93.1(D+)
USB2_ID: J45.4(ID) R788.1(P1) R808.1 U93.3(ID)
USB2_OVRCURN: R790.1 U94.5(O\C\)
USB2_VBUS_EN: R787.1(P1) R791.1 U94.4(EN)
USBJTAG_ENN: R677.2(P2) U63.14(2O\E\) U63.15(1O\E\) U65.4(O\E\) U75.4(O\E\)
VADD33_PRU1ETH0: C112.1 R97.2(P2) U9.14(AVDD33)
VADD33_PRU1ETH1: C118.1 R141.2(P2) U13.14(AVDD33)
VADD33_PRU2ETH0: C137.1 R180.2(P2) U15.14(AVDD33)
VADD33_PRU2ETH1: C142.1 R222.2(P2) U17.14(AVDD33)
VAM572X_DDR1: C6.1 C7.1 C8.1 C9.1 C10.1 C11.1 C12.1 C114.1 C115.1 C441.1(POS) R639.2(I2) U1.AA21(VDDS_DDR1#AA21) U1.AA22(VDDS_DDR1#AA22) U1.AB21(VDDS_DDR1#AB21) U1.AB22(VDDS_DDR1#AB22) U1.AB24(VDDS_DDR1#AB24) U1.AB25(VDDS_DDR1#AB25) U1.AC22(VDDS_DDR1#AC22) U1.AD26(VDDS_DDR1#AD26) U1.AG20(VDDS_DDR1#AG20) U1.AG28(VDDS_DDR1#AG28) U1.AH27(VDDS_DDR1#AH27) U1.W16(VDDS_DDR1#W16) U1.W27(VDDS_DDR1#W27)
VAM572X_DDR2: C13.1 C14.1 C15.1 C16.1 C17.1 C440.1(POS) C550.1 C551.1 C552.1 C553.1 R801.2(I2) U1.E24(VDDS_DDR2#E24) U1.G22(VDDS_DDR2#G22) U1.G23(VDDS_DDR2#G23) U1.H20(VDDS_DDR2#H20) U1.H21(VDDS_DDR2#H21) U1.H22(VDDS_DDR2#H22) U1.J27(VDDS_DDR2#J27) U1.L20(VDDS_DDR2#L20) U1.L21(VDDS_DDR2#L21) U1.M20(VDDS_DDR2#M20) U1.M21(VDDS_DDR2#M21) U1.T24(VDDS_DDR2#T24) U1.T25(VDDS_DDR2#T25)
VANA_OUT: C302.1 U3.C8(LDOVANA_OUT)
VCAN1: C250.1 C252.1 J38.1 U40.7(VOUT+) U41.8(VCC2)
VETH0_AVDDH: C153.1 C154.1 C157.1 FB1.2 Q7.S(SOURCE) U21.1(AVDDH#1) U21.12(AVDDH#12) U21.47(AVDDH#47)
VETH0_AVDDL: C161.1 C162.1 FB4.2 U21.4(AVDDL#4) U21.9(AVDDL#9)
VETH0_AVDDL_PLL: C163.1 C164.1 C165.1 FB2.2 U21.44(AVDDL_PLL)
VETH0_AVDDL_PMOS: C158.1 FB2.1 FB3.1 FB4.1 Q7.D1(DRAIN1) Q7.D2(DRAIN2)
VETH0_DVDDH: C155.1 C156.1 C171.1 D3.1(CATHODE) R278.1(P1) R279.2 R280.2(P2) R297.2(P2) R299.1 R301.1 R306.1 R309.1 U21.16(DVDDH#16) U21.34(DVDDH#34) U21.40(DVDDH#40) U22.5(VCC)
VETH0_DVDDL: C159.1 C160.1 FB3.2 U21.14(DVDDL#14) U21.18(DVDDL#18) U21.23(DVDDL#23) U21.26(DVDDL#26) U21.30(DVDDL#30) U21.39(DVDDL#39)
VETH1_AVDDH: C176.1 C177.1 C178.1 FB5.2 Q8.S(SOURCE) U24.1(AVDDH#1) U24.12(AVDDH#12) U24.47(AVDDH#47)
VETH1_AVDDL: C182.1 C183.1 FB8.2 U24.4(AVDDL#4) U24.9(AVDDL#9)
VETH1_AVDDL_PLL: C184.1 C185.1 C186.1 FB6.2 U24.44(AVDDL_PLL)
VETH1_AVDDL_PMOS: C179.1 FB6.1 FB7.1 FB8.1 Q8.D1(DRAIN1) Q8.D2(DRAIN2)
VETH1_DVDDH: C174.1 C175.1 C192.1 D4.1(CATHODE) R322.1(P1) R324.2(P2) R342.2(P2) R343.1 R345.1 R352.1 R353.1 R364.1 U24.16(DVDDH#16) U24.34(DVDDH#34) U24.40(DVDDH#40) U26.5(VCC)
VETH1_DVDDL: C180.1 C181.1 FB7.2 U24.14(DVDDL#14) U24.18(DVDDL#18) U24.23(DVDDL#23) U24.26(DVDDL#26) U24.30(DVDDL#30) U24.39(DVDDL#39)
VLDO1_OUT: C383.1 R657.2(P2) U3.C6(LDO1_OUT)
VLDO2_OUT: C318.1 R658.2(P2) U3.B6(LDO2_OUT)
VLED+: C215.1 C216.1 C218.1 J16.29 J16.30 U32.9(OUT)
VLED-: J16.23 J16.24 J16.25 J16.26 J16.27 J16.28 R415.2 U32.5(FB)
VMAIN: C20.1 C21.1 C22.1 C23.1 C24.1(POS) C152.1 C217.1 C272.1 C273.1 C274.1 C275.1 C281.1 C282.1 C283.1 C284.1 C285.1 C317.1 C407.1 C411.1(POS) C412.1(POS) C415.1 C416.1 C452.1 C453.1 C458.1 C459.1 C464.1 C465.1 C466.2 C467.2 C468.1 C471.1 D2.1 F1.2 J9.1 L28.1 R19.2(P2) R20.2(P2) R113.2 R411.2(P2) TP1.1 U3.A6(LDO12_IN) U3.A9(LDOUSB_IN2) U3.A10(LDO7_LDOUSB_IN) U3.C4(LDO9_IN) U3.C5(LDOLN_IN) U3.C7(VCC1) U3.D11(SMPS1_IN_1) U3.D12(SMPS1_IN_2) U3.D13(SMPS1_IN_3) U3.E1(SMPS7_IN_B1_1) U3.E2(SMPS7_IN_B1_2) U3.E3(SMPS7_IN_B1_3) U3.F1(SMPS4_IN1) U3.F2(SMPS4_IN2) U3.F3(SMPS4_IN3) U3.G11(SMPS2_IN_1) U3.G12(SMPS2_IN_2) U3.G13(SMPS2_IN_3) U3.H11(SMPS3_IN1) U3.H12(SMPS3_IN2) U3.H13(SMPS3_IN3) U3.J1(SMPS5_IN1) U3.J2(SMPS5_IN2) U3.J3(SMPS5_IN3) U3.L12(LDO34_IN) U3.L13(LDO34_IN1) U3.M4(LDO58_IN#M4) U3.M6(SMPS6_IN#M6) U3.M8(SMPS9_IN#M8) U3.M9(SMPS8_IN#M9) U3.N3(LDO6_IN) U3.N4(LDO58_IN#N4) U3.N6(SMPS6_IN#N6) U3.N8(SMPS9_IN#N8) U3.N9(SMPS8_IN#N9) U32.2(VIN) U62.A1(VIN#A1) U62.A2(VIN#A2) U76.1(IN) U79.6(IN) U79.7(FREQ) U86.4(VIN) U96.5(VCC)
VPP_CONN: J46.2 R797.1(P1)
VPP_EN: J1_1.4 R2_1.1 U1_1.3(EN)
VPROFI: C323.1(POS) C325.1(POS) C430.1 C431.1 J14.6 R577.2(P2) U52.7(OUT#7) U52.8(OUT#8) U74.16(VCC2)
VPROFI_SRC: C433.1 C434.1 D14.1(CATHODE) D15.1(CATHODE) U52.5(IN#5) U52.6(IN#6)
VPROFI_TRANSA: D15.2(ANODE) L2.8
VPROFI_TRANSB: D14.2(ANODE) L2.5
VPWRIN_JCK: D1.2(ANODE) J1.1 J2.1
VPWRIN_PREFUSE: D1.1(CATHODE) F1.1
VRTC_OUT: C301.1 R17.2(P2) R645.2 R794.2(P2) R932.1(P1) U3.A8(LDOVRTC_OUT)
VSDMMC: C483.1 C485.1 C486.1 C487.1 Q27.2(EMMITTER) R397.2 R398.2 R399.2 R400.2 R401.2 R408.2(P2) R644.2 R657.1(P1) R898.2 R900.2 U1.W8(VDDSHV8#W8) U1.Y8(VDDSHV8#Y8)
VSMPS1_2: C276.1 C277.1 L12.2 L13.2 R641.1(I1)
VSMPS1_SW: L12.1 U3.E11(SMPS1_SW_1) U3.E12(SMPS1_SW_2) U3.E13(SMPS1_SW_3)
VSMPS2_SW: L13.1 U3.F11(SMPS2_SW1) U3.F12(SMPS2_SW2) U3.F13(SMPS2_SW3)
VSMPS3: C278.1 L14.2 R656.2(P2)
VSMPS3_SW: L14.1 U3.J11(SMPS3_SW1) U3.J12(SMPS3_SW2) U3.J13(SMPS3_SW3)
VSMPS4_5: C279.1 C280.1 L15.2 L16.2 R642.1(I1)
VSMPS4_SW: L15.1 U3.G1(SMPS4_SW1) U3.G2(SMPS4_SW2) U3.G3(SMPS4_SW3)
VSMPS5_SW: L16.1 U3.H1(SMPS5_SW1) U3.H2(SMPS5_SW2) U3.H3(SMPS5_SW3)
VSMPS6_SW: L17.1 U3.M5(SMPS6_SW#M5) U3.N5(SMPS6_SW#N5)
VSMPS7: C269.1 L18.2 R640.1(I1)
VSMPS7_SW: L18.1 U3.D1(SMPS7_SW1) U3.D2(SMPS7_SW2) U3.D3(SMPS7_SW3)
VSMPS8_SW: L19.1 U3.M10(SMPS8_SW#M10) U3.N10(SMPS8_SW#N10)
VSMPS9: C271.1 L20.2 R742.2(P2)
VSMPS9_SW: L20.1 U3.M7(SMPS9_SW#M7) U3.N7(SMPS9_SW#N7)
VUSB_FTDI: C226.1 D13.2(ANODE) FB9.2 R491.2(P2)
VUSB_JTAG: C225.1 FB9.1 J19.1(VBUS) U36.1(VCC)
VUSB_VBUS1: C311.1 J23.1(VBUS) U66.6(OUT#6) U66.7(OUT#7) U66.8(OUT#8)
VUSB_VBUS2: C546.1 C547.1 J45.1(VBUS) J50.2 R21.2(P2) U93.6(VBUS) U94.6(OUT#6) U94.7(OUT#7) U94.8(OUT#8)
XTIN: C243.1 U37.2(XTIN) Y5.1
XTOUT: C244.1 U37.3(XTOUT) Y5.2
N10692191: R11.2(P2) SW2.3 SW2.4 U48.1
N10692247: C5.1 R11.1(P1) R914.1 U97.2(A)
N11217419: C85.1 R46.1(P1) R47.1(P1)
N11219802: R67.1(P1) U8.7(EN)
N11219922: R56.1(P1) U8.9(PGOOD)
N11219986: C101.1 R69.1(P1) U8.5(VOSNS)
N11220684: C86.1 R45.1 R48.2 U8.1(REFIN)
N12123192: J10.11 R293.2
N12123204: J10.14 R296.2
N12138943: R298.1 U21.48(ISET)
N12139138: TP16.1 U21.41(CLK125_NDO)
N12220066: C108.1 C109.1 C110.1 C111.1 U9.13(PFBIN1) U9.15(PFBOUT) U9.24(PFBIN2)
N12225140: J5.11 R122.1(P1)
N12225158: C123.1 C124.1 C125.1 C126.1 U13.13(PFBIN1) U13.15(PFBOUT) U13.24(PFBIN2)
N12225278: J5.10 R151.1(P1)
N12226470: J5.9 R134.1(P1)
N12226568: R153.1 R154.1(P1) U69.1(A)
N12957779: R482.2(P2) U37.28(ACBUS2)
N12957783: R482.1(P1) U75.6(B2)
N12957791: R489.2(P2) U37.32(ACBUS5)
N12957851: R491.1(P1) R492.2(P2) R494.2 U37.59(BCBUS7)
N12958009: R485.1 U37.14(RESET#)
N12958129: D13.1(CATHODE) R493.2
N12958219: R495.2(P2) R496.1 U38.4(DO)
N12958339: TP18.1 U37.36(SUSPEND#)
N12958347: R493.1 U37.60(PWREN#)
N12958879: R474.1(P1) U63.4(1A1)
N12958935: R476.1(P1) U63.7(2A2)
N12958939: R481.1(P1) U63.6(2A1)
N12958943: R480.1(P1) U75.7(B1)
N12958955: R475.1(P1) U63.5(1A2)
N15911835: R147.2(P2) U13.16(RBIAS)
N16251668: R385.1(P1) U73.15(SCL)
N16251678: R387.1(P1) U73.2(SDA)
N16700927: J5.12 R138.1(P1)
N16818596: J3.9 R89.1(P1)
N16818719: R107.1 R112.1(P1) U68.1(A)
N16819128: R103.2(P2) U9.16(RBIAS)
N16839102: C206.1 R379.2 U72.14(VCC)
N16839202: R382.2(P2) U72.13(RLIM)
N16839209: R381.2(P2) U72.2(DB1)
N16839216: R380.2(P2) U72.1(DB0)
N16844891: D6.2(ANODE) R388.2(P2)
N16844892: D11.2(ANODE) R395.2(P2)
N16844893: D12.2(ANODE) R396.2(P2)
N16844894: D9.2(ANODE) R391.2(P2)
N16844899: D10.2(ANODE) R392.2(P2)
N16844909: D5.2(ANODE) R386.2(P2)
N16844924: D8.2(ANODE) R390.2(P2)
N16844930: D7.2(ANODE) R389.2(P2)
N17007255: R366.1 R377.1(P1) U28.4(Y)
N17074741: J3.10 R106.1(P1)
N17120040: J21.3 R743.1(P1)
N17120055: J21.5 R744.1(P1)
N17120061: J21.9 R746.1(P1)
N17120072: J21.11 R747.1(P1)
N17120087: J21.21 R752.1(P1)
N17120090: J21.23 R753.1(P1)
N17144335: R29.1(P1) U4.3(R\E\S\E\T\)
N17156111: C172.2 R305.2(P2) U23.1(XIN/CLK) Y3.2
N17156113: C173.2 R305.1(P1) R308.2(P2) Y3.1
N17156222: R308.1(P1) U23.14(XOUT)
N17156522: R310.1 U23.11(Y1)
N17156525: R313.1 U23.9(Y2)
N17156528: R315.1 U23.8(Y3)
N17156983: R314.1(P1) U23.12(S2/SCL)
N17156986: R312.1(P1) U23.13(S1/SDA)
N17569906: J12.11 R337.2
N17569909: J12.14 R340.2
N17569918: R341.1 U24.48(ISET)
N17569921: TP17.1 U24.41(CLK125_NDO)
N17570093: C193.2 R349.2(P2) U25.1(XIN/CLK) Y4.2
N17570094: C194.2 R349.1(P1) R351.2(P2) Y4.1
N17570107: R351.1(P1) U25.14(XOUT)
N17570112: R354.1 U25.11(Y1)
N17570113: R357.1 U25.9(Y2)
N17570114: R359.1 U25.8(Y3)
N17570122: R358.1(P1) U25.12(S2/SCL)
N17570123: R356.1(P1) U25.13(S1/SDA)
N17594977: C134.1 C135.1 C136.1 C138.1 U15.13(PFBIN1) U15.15(PFBOUT) U15.24(PFBIN2)
N17595008: J6.9 R172.1(P1)
N17595032: R190.1 R195.1(P1) U70.1(A)
N17595048: R186.2(P2) U15.16(RBIAS)
N17595072: J6.10 R189.1(P1)
N17595076: J6.11 R161.1(P1)
N17595078: J6.12 R176.1(P1)
N17596821: J8.11 R203.1(P1)
N17596823: C147.1 C148.1 C149.1 C150.1 U17.13(PFBIN1) U17.15(PFBOUT) U17.24(PFBIN2)
N17596838: J8.10 R230.1(P1) R231.2(P2)
N17596842: R220.2(P2) U1.D18(XREF_CLK0/PR2_MII1_COL)
N17596847: R230.2(P2) U1.C17(MCASP3_AXR1/PR2_MII1_RXLINK)
N17596886: J8.9 R214.1(P1)
N17596899: R233.1 R234.1(P1) U71.1(A)
N17596973: R219.2(P2) U1.E17(XREF_CLK1/PR2_MII1_CRS)
N17596976: R228.2(P2) U17.16(RBIAS)
N17596979: J8.12 R218.1(P1)
N17731118: Q1.G(GATE) R241.1(P1) R245.2(P2)
N17731139: Q5.G(GATE) R253.2(P2) R255.2(P2)
N17732522: R410.1(P1) U32.6(EN)
N17732526: R413.2(P2) R414.2(P2) U32.3(SS)
N17732536: Q9.D(DRAIN) R413.1(P1)
N17732560: R411.1(P1) U32.7(FSW)
N17745676: J9.22 R275.2(P2)
N17745678: J9.24 R277.2(P2)
N17745710: J9.23 R903.1
N17863265: J3.11 R78.1(P1)
N17863276: J3.12 R93.1(P1)
N18733248: R497.1(P1) U1.AD14(RTC_OSC_XO)
N18733249: C247.1 R497.2(P2) Y6.4
N18733252: C246.1 R927.2(P2) U1.AE14(RTC_OSC_XI) Y6.1
N18733262: R499.2(P2) U1.AF14(RTC_ISO)
N18733263: R498.1 R500.1(P1) U39.4(Y)
N18733273: R500.2(P2) R926.2(P2) U1.AB17(RTC_PORZ)
N18733274: R929.2(P2) U1.Y11(ON_OFF)
N18733276: R923.1(P1) TP19.1 U1.AD17(WAKEUP0)
N18868530: R14.1(P1) R572.2(P2) U3.L1(I2C1_SCL_SCK)
N18868533: R15.1(P1) R588.2(P2) U3.L2(I2C1_SDA_SDI)
N18913166: TP7.1 U3.J5(ENABLE1)
N18913202: R17.1(P1) R934.1(P1) U3.K7(BOOT1)
N18913205: R16.1(P1) U3.L3(BOOT0)
N18913322: R18.1 U3.G9(GPIO_7)
N18913403: C26.2 U3.A3(OSC16MIN) Y2.1
N18913412: C25.2 U3.A2(OSC16MOUT) Y2.3
N18913758: C27.2 U3.B7(VBG)
N18914093: C578.1 U3.C1(OSC16MCAP)
N18914190: TP2.1 U3.M11(CLK32KGO)
N18914214: TP3.1 U3.J7(POWERGOOD)
N18914339: SW3.3 SW3.4 U3.G8(PWRON) U50.1
N18914524: TP6.1 U3.C11(RPWRON)
N18915671: R19.1(P1) U3.B3(VCC_SENSE)
N18915723: R20.1(P1) U3.A11(VCC_SENSE2)
N18915943: R21.1(P1) U3.D8(VBUS)
N19120663: R41.2(P2) U5.L8(ZQ)
N19120749: R44.2(P2) U7.L8(ZQ)
N19127709: R42.2(P2) U6.L8(ZQ)
N19139994: R32.1 U6.D7(DQ8)
N19139997: R33.1 U6.C3(DQ9)
N19140025: R34.1 U6.C8(DQ10)
N19140027: R35.1 U6.C2(DQ11)
N19140065: R37.1 U6.A7(DQ12)
N19140067: R38.1 U6.A2(DQ13)
N19140105: R39.1 U6.B8(DQ14)
N19140107: R40.1 U6.A3(DQ15)
N19258097: R546.1 U45.7(OE)
N19258128: U45.21(XIN) Y7.3(CLK)
N19258198: R547.1(P1) Y7.1(OE)
N19258383: R548.1 U45.11(OS0)
N19258403: R549.1 R550.1(P1) U45.10(OS1)
N19258622: C305.1 U45.17(REG_CAP2)
N19258627: C306.1 U45.19(REG_CAP1)
N19290398: R421.1 U33.7(WP)
N19388440: R566.1(P1) U89.B9(RESXN)
N19415733: R568.1(P1) U45.12(RSTN)
N19425975: R7.1(P1) U1.E23(RESETN)
N19426030: R8.1(P1) U1.D21(NMI_DSP)
N19426454: R569.1(P1) U1.AC15(XI_OSC1)
N19438966: R582.1(P1) U1.AB9(MCASP5_FSX/PR2_PRU1_R31_2) U77.4(D)
N19438972: R583.1(P1) U77.1(R)
N19438984: R584.1(P1) U77.2(R\E\) U77.3(DE)
N19634423: R579.2(P2) U74.6(R\E\)
N19634430: R574.1(P1) U74.8(D)
N19634431: R575.1(P1) U74.5(R)
N19634433: R576.1(P1) U74.7(DE)
N19700674: J18.1(VREF_DBG) R730.1(P1)
N19700725: J18.12(VREF_TR) R731.1(P1)
N19707292: J18.15(TGT_DETECT) R587.1(P1)
N19708748: R429.1(P1) U78.2(A)
N19795587: R425.1 U3.B12(GPIO_0)
N19795594: R428.1(P1) U3.C13(GPIO_1)
N19795604: R430.1 U3.A12(GPIO_2)
N19795606: R431.1 U3.H9(GPIO_3)
N19795618: R570.1 U3.C10(GPIO_5)
N19795620: R571.1 U3.N11(GPIO_6)
N19795629: R432.1 U3.K10(GPIO_4)
N19796448: R572.1(P1) U3.M3(I2C2_SCL_SCE)
N19796451: R588.1(P1) U3.H8(I2C2_SDA_SDO)
N19923823: C286.1 U1.J10(CAP_VDDRAM_DSPEVE1)
N19923824: C287.1 U1.J9(CAP_VDDRAM_DSPEVE2)
N19923825: C288.1 U1.J16(CAP_VBBLDO_MPU)
N19923831: C292.1 U1.K19(CAP_VDDRAM_MPU2)
N19923832: C291.1 U1.K16(CAP_VDDRAM_MPU1)
N19923833: C290.1 U1.K9(CAP_VBBLDO_DSPEVE)
N19923834: C289.1 U1.J19(CAP_VDDRAM_CORE2)
N19923844: C293.1 U1.L9(CAP_VDDRAM_CORE1)
N19923845: C294.1 U1.P19(CAP_VDDRAM_CORE4)
N19923846: C295.1 U1.R20(CAP_VBBLDO_IVA)
N19923850: C299.1 U1.Y15(CAP_VDDRAM_CORE3)
N19923851: C298.1 U1.Y14(CAP_VBBLDO_GPU)
N19923852: C297.1 U1.Y13(CAP_VDDRAM_GPU)
N19923853: C296.1 U1.T20(CAP_VDDRAM_IVA)
N19923865: C300.1 U1.Y16(CAP_VDDRAM_CORE5)
N20127658: C403.1 R930.2(P2) R931.2(P2) U1.AB15(VDD_RTC)
N20128389: C404.1 R932.2(P2) R933.2(P2) U1.AB13(VDDA_RTC)
N20144297: R637.2 U89.A9(MSEL)
N20190363: C454.2 J40.2 R639.4(SENS2)
N20190375: C454.1 J40.1 R639.3(SENS1)
N20190748: C455.2 J41.1 R640.3(SENS1)
N20190772: C455.1 J41.2 R640.4(SENS2)
N20190931: C456.2 J42.1 R641.3(SENS1)
N20190955: C456.1 J42.2 R641.4(SENS2)
N20191205: C457.2 J43.1 R642.3(SENS1)
N20191229: C457.1 J43.2 R642.4(SENS2)
N20202943: TP21.1 U3.F8(REGEN1)
N20204523: R643.1(P1) U1.AC17(WAKEUP1)
N20275163: C460.1 U79.8(SS)
N20287248: R647.1(P1) R648.2(P2) U79.2(FB)
N20287275: R646.2(P2) U79.1(COMP)
N20287568: C463.1 R646.1(P1)
N20287584: D20.2(ANODE) L28.2 U79.5(SW)
N20301491: J22.A1 R649.1 R650.2(P2)
N20338433: J22.B11 R654.1 R655.2(P2)
N20537306: U44.2(A) U85.4(Y)
N20594970: R678.1(P1) U86.1(VEN)
N20595300: R679.1(P1) U79.3(EN)
N20619479: R680.2 R681.2 U86.2(ADJ)
N20631200: Q16.G(GATE) R114.2(P2) R116.2(P2)
N20664562: L22.1 U62.B1(L1#B1) U62.B2(L1#B2)
N20664572: C417.1 U62.A3(VINA) U62.B3(VINA1) U62.C4(P\S\) U62.D4(VSEL)
N20665027: L22.2 U62.D1(L2#D1) U62.D2(L2#D2)
N20706534: R554.2(P2) U65.7(B1)
N20706536: R555.2(P2) U65.6(B2)
N20706626: R477.1(P1) U65.2(A1)
N20706635: R483.1(P1) U65.3(A2)
N20721609: Q3.G(GATE) R247.2(P2) R251.2(P2)
N20721766: Q3.D(DRAIN) R242.1(P1)
N20721850: Q1.D(DRAIN) R239.1(P1)
N20722196: D16.3(G) R242.2(P2)
N20722199: Q5.D(DRAIN) R249.1(P1)
N20722204: D16.4(B) R249.2(P2)
N20722213: D16.2(R) R239.2(P2)
N20722605: Q2.G(GATE) R243.1(P1) R246.2(P2)
N20722618: Q6.G(GATE) R254.2(P2) R256.2(P2)
N20722739: Q4.G(GATE) R248.2(P2) R252.2(P2)
N20722773: Q4.D(DRAIN) R244.1(P1)
N20722790: Q2.D(DRAIN) R240.1(P1)
N20722809: D17.3(G) R244.2(P2)
N20722811: Q6.D(DRAIN) R250.1(P1)
N20722815: D17.4(B) R250.2(P2)
N20722821: D17.2(R) R240.2(P2)
N20723137: Q11.G(GATE) R599.2(P2) R600.1(P1)
N20723150: Q10.G(GATE) R594.2(P2) R595.2(P2)
N20723271: Q15.G(GATE) R590.2(P2) R591.2(P2)
N20723305: Q15.D(DRAIN) R589.1(P1)
N20723322: Q11.D(DRAIN) R596.1(P1)
N20723341: D18.3(G) R589.2(P2)
N20723343: Q10.D(DRAIN) R601.1(P1)
N20723347: D18.4(B) R601.2(P2)
N20723353: D18.2(R) R596.2(P2)
N20723697: Q13.G(GATE) R514.1(P1) R597.2(P2)
N20723710: Q12.G(GATE) R515.2(P2) R598.2(P2)
N20723831: Q14.G(GATE) R592.2(P2) R593.2(P2)
N20723865: Q14.D(DRAIN) R603.1(P1)
N20723882: Q13.D(DRAIN) R604.1(P1)
N20723901: D19.3(G) R603.2(P2)
N20723903: Q12.D(DRAIN) R602.1(P1)
N20723907: D19.4(B) R602.2(P2)
N20723913: D19.2(R) R604.2(P2)
N20729664: Q20.D(DRAIN) R699.1(P1)
N20729666: D22.4(B) R699.2(P2)
N20729672: D22.2(R) R696.2(P2)
N20729903: Q21.G(GATE) R697.2(P2) R698.1(P1)
N20729915: Q20.G(GATE) R694.2(P2) R695.2(P2)
N20730029: Q22.G(GATE) R700.2(P2) R701.2(P2)
N20730054: Q22.D(DRAIN) R693.1(P1)
N20730079: Q21.D(DRAIN) R696.1(P1)
N20730095: D22.3(G) R693.2(P2)
N20730773: Q23.D(DRAIN) R708.1(P1)
N20730775: D23.4(B) R708.2(P2)
N20730781: D23.2(R) R705.2(P2)
N20730789: Q24.G(GATE) R706.2(P2) R707.1(P1)
N20730805: Q23.G(GATE) R703.2(P2) R704.2(P2)
N20730910: Q25.G(GATE) R709.2(P2) R710.2(P2)
N20730936: Q25.D(DRAIN) R702.1(P1)
N20730961: Q24.D(DRAIN) R705.1(P1)
N20730985: D23.3(G) R702.2(P2)
N20825141: R690.2(P2) U1.N1(GPMC_ADVN_ALE)
N20825143: R691.2(P2) U1.M5(GPMC_OEN_REN)
N20825145: R692.2(P2) U1.M3(GPMC_WEN)
N20825147: R732.2(P2) U1.N6(GPMC_BEN0)
N20825149: R733.2(P2) U1.M4(GPMC_BEN1)
N20825151: R734.2(P2) U1.N2(GPMC_WAIT0)
N20962931: C421.1 J18.58(GND#58) R149.1 U19.2(A)
N21013400: R662.2(P2) U1.B14(MCASP1_ACLKR)
N21013403: R663.2(P2) U1.J14(MCASP1_FSR)
N21013406: R664.2(P2) U1.G13(MCASP1_AXR2)
N21013409: R665.2(P2) U1.J11(MCASP1_AXR3)
N21036279: J21.8 R690.1(P1)
N21036281: J21.10 R691.1(P1)
N21036293: J21.12 R692.1(P1)
N21036295: J21.14 R732.1(P1)
N21036304: J21.16 R733.1(P1)
N21036390: R686.2(P2) U1.T1(GPMC_CS0)
N21036392: R688.2(P2) U1.P1(GPMC_CS3/GPIO)
N21036394: R689.2(P2) U1.P7(GPMC_CLK)
N21036619: J21.52 R734.1(P1)
N21099488: C265.1 U43.C2(VDDI)
N21180149: TP22.1 U1.B15(MCASP2_AXR0)
N21180152: TP23.1 U1.A15(MCASP2_AXR1)
N21306186: TP24.1 U89.B6(GPIO1)
N21306311: R567.1(P1) U89.A8(I2C_SCL)
N21306314: R585.1(P1) U89.B8(I2C_SDA)
N21307911: R586.1(P1) U89.K6(REFCLK)
N21519094: R754.2(P2) U90.L8(ZQ)
N21519152: R755.2(P2) U91.L8(ZQ)
N21552786: C544.1 R785.2 R786.1 U92.1(REFIN)
N21553219: C529.1 R780.1(P1) R781.1(P1)
N21553307: R783.1(P1) U92.7(EN)
N21553371: R782.1(P1) U92.9(PGOOD)
N21553379: C533.1 R784.1(P1) U92.5(VOSNS)
N21605448: C545.1 J50.1
N21620210: C197.1 R368.1 U72.3(IP0)
N21620213: C198.1 R370.1 U72.5(IP1)
N21620216: C199.1 R372.1 U72.7(IP2)
N21620219: C200.1 R374.1 U72.9(IP3)
N21620222: C201.1 R373.1 U72.11(IP4)
N21620225: C202.1 R375.1 U72.18(IP5)
N21620228: C203.1 R376.1 U72.20(IP6)
N21620231: C204.1 R378.1 U72.22(IP7)
N21685968: C548.1 R797.2(P2) U1.K14(RSVK14)
N21685998: J46.4 R638.1(P1) R798.2
N21823186: C549.2 J47.2 R801.4(SENS2)
N21823194: C549.1 J47.1 R801.3(SENS1)
N21877717: R659.2(P2) U1.AE5(VIN1A_D18)
N21877759: R660.2(P2) U1.AE1(VIN1A_D19)
N21905162: R802.1(P1) U1.AG3(VIN1A_D10)
N21905296: R803.1(P1) U1.AH5(VIN1A_D5)
N22373548: R809.2(P2) U1.AD2(VIN1A_D22)
N22373612: R428.2(P2) R810.1 U96.2(A)
N22427447: R739.1(P1) U1.C26(UART1_TXD/GPIO)
N22427459: R740.1(P1) U1.B27(UART1_RXD/GPIO)
N22641301: D24.2(CATHODE) Q26.1(BASE) R894.1 R895.1
N22641309: D24.1(REF) R895.2 R896.1 R897.2
N22641383: D25.2(CATHODE) Q27.1(BASE) R898.1 R899.1
N22641391: D25.1(REF) R899.2 R900.1 R901.2
N22642197: R276.2 R300.2(P2) R903.2 R905.1(P1) X1.3(OUT)
N22644059: C562.1 R854.2(P2) U3.K12(LDO4_OUT)
N22691021: R576.2(P2) U1.F4(VIN2A_D5/PR1_PRU1_R30_2)
N22729003: J21.31 R861.1(P1)
N22729012: J21.33 R862.1(P1)
N22729021: J21.35 R863.1(P1)
N22729030: J21.37 R864.1(P1)
N22729576: R738.1(P1) U1.AG6(VIN1A_D6)
N22730116: R737.1(P1) U1.AG4(VIN1A_D8)
N22730128: R736.1(P1) U1.AH4(VIN1A_D7)
N22734288: R917.1 U2.4(Y) U98.2(B)
N22734327: C4.1 R10.1 R916.1(P1) U2.2(A)
N22734777: R916.2(P2) SW1.3 SW1.4 U49.1
N22735118: R9.2(P2) U98.1(A)
N22762383: R925.1(P1) U1.AC16(WAKEUP3)
N22762388: R924.1(P1) U1.AB16(WAKEUP2)
N24440306: R902.1 X1.1(EN)

Pads without a net: J3 7; J5 7; J6 7; J8 7; J9 10 14; J10 2; J12 2; J14 1 2 4 7 9; J16 1 2 6 31 32; J18 9 10 11 14 18 20 22 24 26 28 30 32 34 36 38 40 42 44 46 48 50 52 54 55 56 59 60; J19 4; J21 7 18 20; J22 B12; J24 14; J37 18; J38 5; NOREF#3 1; NOREF#5 1; NOREF#6 1; NOREF#8 1; NOREF#9 1; NOREF#10 1; NOREF#13 1; NOREF#14 1; NOREF#15 1; NOREF#16 1; NOREF#17 1; NOREF#19 1; NOREF#20 1; NOREF#21 1; NOREF#22 1; NOREF#24 1; NOREF#26 1; NOREF#27 1; NOREF#30 1; NOREF#31 1; NOREF#32 1; NOREF#33 1; NOREF#35 1; NOREF#36 1; NOREF#37 1; NOREF#41 1; NOREF#42 1; NOREF#43 1; NOREF#44 1; NOREF#45 1; NOREF#46 1; NOREF#47 1; NOREF#48 1; NOREF#49 1; NOREF#50 1; NOREF#51 1; NOREF#52 1; NOREF#53 1; NOREF#54 1; NOREF#55 1; R178 1; U1 A20 A27 AA1 AA2 AA4 AB1 AB2 AB3 AC1 AC2 AC13 AD3 AD8 AD9 AE2 AE6 AE8 AE9 AF1 AF8 AF9 AG2 AG5 AG7 AG8 AG9 AG10 AG11 AG12 AH3 AH6 AH7 AH9 AH10 AH11 AH12 B28 C27 E15 E25 G16 Y5 Y10; U2 1; U3 B4 C9 K4 K5 K8 L4 N12; U4 4 5 6 11 12 13; U5 J1 J9 L1 L9; U6 J1 J9 L1 L9; U7 J1 J9 L1 L9; U9 22; U13 22; U15 22; U17 22; U19 1; U21 45; U22 1; U23 2 4; U24 45; U25 2 4; U26 1; U28 1; U30 4 9; U35 1; U36 2; U37 22 24 27 29 33 34 40 41 43 44 45 46 48 52 53 54 55 57 58; U39 1; U40 10; U43 A1 A2 A6 A7 A8 A9 A10 A11 A12 A13 A14 B1 B7 B8 B9 B10 B11 B12 B13 B14 C1 C3 C5 C7 C8 C9 C10 C11 C12 C13 C14 D1 D2 D3 D4 D12 D13 D14 E1 E2 E3 E5 E8 E9 E10 E12 E13 E14 F1 F2 F3 F10 F12 F13 F14 G1 G2 G3 G10 G12 G13 G14 H1 H2 H3 H5 H12 H13 H14 J1 J2 J3 J5 J12 J13 J14 K1 K2 K3 K6 K7 K10 K12 K13 K14 L1 L2 L3 L12 L13 L14 M1 M2 M3 M7 M8 M9 M10 M11 M12 M13 M14 N1 N3 N6 N7 N8 N9 N10 N11 N12 N13 N14 P1 P2 P7 P8 P9 P10 P11 P12 P13 P14; U45 8 13 15 23 24 25 26 27 28 29 30 31 32; U47 1; U52 1 2; U72 4 6 8 10 12 16 17 19 21 27; U74 10; U76 4; U78 1; U89 A6; U90 J1 J9 L1 L9; U91 J1 J9 L1 L9; U93 5; U95 6 7 9 10; U96 1; U97 1; Y1 2 4; Y2 2 4; Y6 2 3

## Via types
v1: diameter 0.457, hole 0.203, TOP to BOTTOM, 1201 vias
v2: diameter 0.457, hole 0.203, TOP to L2_GND1, 613 vias
v3: diameter 0.279, hole 0.127, TOP to L2_GND1, 620 vias
v4: diameter 0.279, hole 0.127, L2_GND1 to L3_SIG1, 621 vias
v5: diameter 0.457, hole 0.203, L2_GND1 to L3_SIG1, 614 vias
v6: diameter 0.457, hole 0.203, L3_SIG1 to L10_SIG4, 917 vias
v7: diameter 0.508, hole 0.254, TOP to BOTTOM, 1510 vias
v8: diameter 0.457, hole 0.203, L10_SIG4 to L11_GND4, 421 vias
v9: diameter 0.457, hole 0.203, L11_GND4 to BOTTOM, 422 vias
v10: diameter 0.279, hole 0.127, L10_SIG4 to L11_GND4, 377 vias
v11: diameter 0.279, hole 0.127, L11_GND4 to BOTTOM, 377 vias

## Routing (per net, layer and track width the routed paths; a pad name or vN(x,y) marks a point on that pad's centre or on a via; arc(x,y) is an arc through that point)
AGND_GBETH0: length 8.5
  BOTTOM w0.508: 24.77,137.35 J10.SHLD2 ; J10.SHLD2 26.78,137.35 ; J10.SHLD2 24.77,139.35 ; J10.SHLD1 42.28,137.35 ; J10.SHLD1 42.28,139.35 ; J10.SHLD1 40.28,137.35
AGND_GBETH1: length 8.5
  BOTTOM w0.508: J12.SHLD2 48.5,137.35 ; J12.SHLD2 46.49,139.35 ; J12.SHLD2 46.49,137.35 ; J12.SHLD1 64,139.35 ; J12.SHLD1 61.99,137.35 ; J12.SHLD1 64,137.35
AGND_PROFI: length 12
  TOP w0.381: R573.2 v7(105.79,7.75) v7(104.77,7.75)
  BOTTOM w0.508: 83.44,4.59 J14.11 79.86,4.59 ; 108.44,4.59 J14.10 104.85,4.59
AGNDFRAME_PRU1ETH0: length 8.5
  BOTTOM w0.508: J3.SHLD2 14.85,121.93 ; J3.SHLD2 14.85,123.94 ; J3.SHLD2 12.85,121.93 ; 12.85,139.69 J3.SHLD1 ; J3.SHLD1 14.85,139.69 ; J3.SHLD1 14.85,137.68
AGNDFRAME_PRU1ETH1: length 8.5
  BOTTOM w0.508: 12.85,115.56 J5.SHLD1 ; J5.SHLD1 14.85,113.55 ; J5.SHLD1 14.85,115.56 ; 12.85,97.8 J5.SHLD2 ; J5.SHLD2 14.85,97.8 ; J5.SHLD2 14.85,99.81
AGNDFRAME_PRU2ETH0: length 8.5
  BOTTOM w0.508: 12.85,91.43 J6.SHLD1 ; J6.SHLD1 14.85,89.42 ; J6.SHLD1 14.85,91.43 ; 12.85,73.67 J6.SHLD2 ; J6.SHLD2 14.85,73.67 ; J6.SHLD2 14.85,75.68
AGNDFRAME_PRU2ETH1: length 8.5
  BOTTOM w0.508: J8.SHLD2 14.85,48.91 ; J8.SHLD2 14.85,50.91 ; J8.SHLD2 12.85,48.91 ; J8.SHLD1 14.85,66.66 ; J8.SHLD1 12.85,66.66 ; J8.SHLD1 14.85,64.66
DGND: length 2618.6
  TOP w0.203: U37.5 157.69,81.89 157.28,82.3 ; U3.A1 134.65,131.14 134.62,131.17 v5(134.62,131.4) ; U65.5 174.59,73.05 v7(174.88,73.33) ; v7(136.9,132.89) 136.9,132.78 136.91,132.77 136.91,131.28 137.05,131.14 U3.A4 ; U3.A7 v5(139.45,131.29)
  TOP w0.254: U21.13 31.03,123.61 v7(30.61,124.03) ; U37.11 v7(157.53,78.89) ; v7(167.07,84.22) 167.14,84.29 U37.51 ; U7.E1 97.62,35.08 v1(97.61,35.08) ; U1.W28 98.2,70.38 v4(98.2,69.87) ; U1.AC14 v4(95.04,82.41) ; U3.C12 v5(143.84,129.53) ; U37.35 168.95,77.39 v7(168.88,77.32) ; v7(173.61,81.74) 173.61,80.98 C233.2 ; U1.G9 v4(108.63,86.41) ; U3.E7 v5(139.05,127.93) ; U1.J12 v4(107.03,84.01) ; U1.K4 v4(106.23,90.41) ; U1.M19 v4(104.63,77.62) ; U5.D1 v1(83.18,35.88) ; U3.L7 v5(139.05,122.34) ; U1.T18 v4(100.64,78.42) ; U6.G9 v1(119.26,33.48) ; U1.N19 v11(103.83,77.62) ; U37.10 157.9,79.39 v7(157.53,79.76) ; U5.E2 v1(83.98,35.08) ; U3.C2 v5(135.05,129.53) ; U1.AH8 91.84,87.22 v4(91.89,87.22) ; U1.G8 v4(108.63,87.21) ; U7.E8 v1(103.22,35.08) ; U3.C3 v5(135.85,129.53) ; U3.E9 v5(141.44,127.93) ; v4(93.48,85.56) 93.49,85.56 U1.AE10 ; U5.A9 v1(88.78,38.28) ; U6.D1 v1(113.66,35.88) ; U1.E19 v4(110.23,77.62) ; U36.4 v7(181.77,12.81) ; U1_1.2 174.59,9.5 174.12,9.5 v7(173.99,9.37) ; U24.29 56.15,120.11 v1(56.9,120.86) ; U1.N14 v4(103.83,82.41) ; U1.A28 v4(113.43,70.42) ; U8.4 107.32,16.98 107.11,17.2 106.88,17.2 106.43,17.65 C100.2 ; v4(95.84,76.82) U1.AB20 96.63,76.82 v4(96.64,76.82) U1.AA20 ; U3.L5 v5(137.45,122.34) ; U3.K3 v5(136.64,123.14) ; U1.A23 v4(113.43,74.42) ; U1.L14 v4(105.43,82.41) ; U7.D8 v1(103.22,35.88) ; U5.E1 v1(82.21,34.68) ; U1.K1 105.83,93.13 v4(105.79,93.17) ; U1.AH20 v4(91.04,76.82) ; v4(91.01,92.94) 91.01,92.84 U1.AH1 ; U1.AB14 v4(95.86,81.64) ; U1.AD19 v4(94.24,77.62) 94.23,77.62 U1.AE19 v4(93.44,77.62) ; U1.N15 v4(103.83,80.82) ; U1.T21 v4(100.64,76.02) U1.U21 v4(99.84,76.82) U1.U20 ; U3.G4 v5(136.65,125.54) ; v7(7.62,39.75) 7.28,40.09 U93.4 ; U3.F4 v5(136.65,127.13) ; v1(120.45,27.41) 120.38,27.48 U6.P9 ; U1.H12 v4(107.83,84.01) ; U1.AA11 v4(96.64,84.81) ; U1.AG1 92.24,92.49 92.15,92.58 92.15,92.71 92.04,92.82 92.04,92.83 v4(91.82,93.05) ; U6.A9 v1(120.06,38.28) ; U1.A1 v4(113.43,92.81) ; U3.D5 v5(137.45,128.73) ; U1.N25 v4(103.83,72.82) ; U5.G1 v1(82.21,33.08) ; U3.B10 v5(142.24,130.33) ; U3.N1 v5(134.25,120.74) ; U1.AA8 v4(96.64,87.21) ; U5.E8 v1(87.98,35.08) ; U1.D19 v4(111.03,77.62) ; U5.T1 v1(82.21,25.88) ; 83.32,150.63 J15.14 ; U7.A9 v1(104.02,38.28) ; U7.E2 v1(99.22,35.08) ; U1.J28 106.71,70.74 v4(106.71,70.34) ; U3.H6 v5(138.25,124.74) ; U3.J10 v5(142.24,123.94) ; J18.16 v7(185.63,93.62) ; U5.B9 v1(89.74,37.08) ; U7.J8 v1(104.02,31.88) ; U6.E8 v1(118.46,35.08) ; U1.T17 v4(100.64,79.22) ; U1.R15 v4(101.44,80.82) ; U1.AD10 v4(94.24,85.61) ; U1.V15 v4(99.04,80.82) ; U5.B3 v1(84.78,37.48) ; U3.E10 v5(142.24,127.93) ; U1.K15 v4(106.23,80.82) ; U1.AE13 94.06,82.59 94.08,82.59 v4(94.16,82.51) ; U5.G8 v1(87.98,33.48) ; U1.W25 v4(98.24,72.82) ; U1.V17 v11(99.04,79.22) ; J18.57 183.05,83.12 v7(183.29,82.89) ; U3.M1 v5(134.25,121.54) ; U1.AD1 94.64,93.49 94.7,93.55 v4(94.7,93.58) ; U6.E1 v1(112.86,35.08) ; U5.J8 v1(88.78,31.88) ; U1.L13 v4(105.43,83.21) ; U37.13 159.78,77.89 v7(159.84,77.96) ; U7.T1 v1(97.45,25.88) ; U1.K5 v4(106.23,89.61) ; U1.AH28 v4(91.04,70.42) ; U6.D8 v1(118.46,35.88) ; U1.D13 v4(111.03,83.21) ; U7.J2 v1(99.22,31.88) ; U3.F5 v5(137.45,126.34) ; U5.G9 v1(88.78,33.48) ; U1.A6 v4(113.43,88.81) ; U5.M1 v1(82.21,29.08) ; U5.J2 v1(83.18,31.88) ; v7(159.94,81.41) 159.94,81.54 159.59,81.89 U37.5 ; U6.J2 v1(114.46,31.88) ; U1.AA10 v4(96.64,85.61) ; U1.AA14 v4(96.64,82.41) ; U5.T9 v1(89.74,25.88) ; U1.K24 v4(106.23,73.62) ; U3.G7 v5(139.05,125.54) ; U21.29 34.43,120.11 v1(35.18,120.86) ; U5.D8 v1(87.98,35.88) ; U64.3 v5(43.05,18.24) ; U5.P1 v1(82.21,27.48) ; U1.K25 v4(106.23,72.82) ; U1.G7 v4(108.63,88.01) ; U1.U15 v4(99.84,80.82) ; U1.E13 v4(110.23,83.21) ; U6.J8 v1(119.26,31.88) ; U6.B9 v1(120.06,37.48) ; U3.H7 v5(139.84,125.53) ; U7.M1 v1(97.45,29.08) ; U1.T11 v4(100.64,84.81) ; v1(120.27,29.21) 120.14,29.08 U6.M9 ; U3.J4 v5(136.65,123.94) ; U1.AA9 v4(96.64,86.41) ; U37.25 v7(164.64,75.57) ; U1.AD24 v4(94.24,73.62) ; U3.F9 v1(141.44,126.34) ; U3.B11 v5(143.04,130.33) ; U1.U14 v4(99.84,82.41) ; U5.F9 v1(89.74,33.88) ; U3.D10 v5(142.24,128.73) ; U1.AA15 v4(96.64,80.82) ; U6.P1 v1(112.69,27.48) ; v1(107.82,14.73) U8.8 ; U1.A2 v4(113.43,92.01) ; U7.G8 v1(103.22,33.48) ; U7.D1 v1(98.42,35.88) ; U6.G1 v1(112.86,33.48) ; U3.A13 144.53,131.02 v5(144.53,131.53) ; U3.J6 v5(139.04,124.73) ; U7.B3 v1(100.02,37.48) ; U3.B8 v1(140.64,130.33) ; U1.T15 v4(100.64,80.82) ; U3.B2 v5(135.05,130.33) ; U3.F10 v1(142.24,126.34) ; U1.AD13 94.58,82.87 94.55,82.87 94.33,83.08 94.33,83.12 v4(94.24,83.21) ; U7.P9 v1(104.98,27.48) ; U3.M2 v5(135.05,121.54) ; U7.M9 v1(104.98,29.08) ; U1.N24 v4(103.83,73.62) ; U6.D3 v1(115.26,35.88) ; U3.L6 v5(138.25,122.34) ; U3.L8 v1(139.85,123.13) ; U3.E4 v5(136.65,127.93) ; U3.H10 v5(142.24,124.74) ; U1.AB11 v4(95.84,84.81) ; U5.B1 v1(83.18,37.48) ; U1.P28 v4(103.03,70.42) ; U1.W15 v4(98.24,80.82) ; U1.J15 v11(107.03,80.82) ; U5.M9 v1(89.74,29.08) ; U3.D7 v5(139.05,128.73) ; U3.D4 v5(136.65,128.73) ; U6.C7 v1(117.66,36.68) ; U1.R13 v4(101.44,83.21) ; U7.B9 v1(104.82,37.48) ; U1.W24 v4(98.24,73.62) ; U6.T9 v1(120.27,25.88) ; U3.E8 v5(139.85,127.93) ; U3.N2 v5(135.05,120.74) ; U1.A14 v4(113.43,82.41) ; U1.R1 v4(101.83,93.15) ; U6.G8 v1(118.46,33.48) ; U1.AH2 v4(90.91,92.14) ; U1.T10 v4(100.64,85.61) ; U1.W1 v4(98.64,93.15) ; U7.P1 v1(97.45,27.48) ; U24.13 52.75,123.61 v7(52.32,124.03) ; U3.G10 v5(142.24,125.54) ; U1.B1 v4(112.23,92.98) ; U3.L9 v5(140.65,122.34) ; U1.T12 v4(100.64,84.01) ; U6.B1 v1(113.66,37.48) ; U1.T14 v4(100.64,82.41) ; U1.F7 v4(109.43,88.01) ; U3.F7 v5(139.05,126.34) ; 98.49,150.6 J15.13 ; U1.U17 v11(99.84,79.22) ; U6.M1 v1(112.69,29.08) ; U3.H4 v5(136.65,124.74) ; U7.G1 v1(97.62,33.48) ; U1.R21 v4(101.44,76.02) ; U3.L10 v5(141.45,122.34) ; U5.P9 v1(89.74,27.48) ; U7.B1 v1(98.42,37.48) ; U3.F6 v5(138.25,127.13) ; U1.F1 v4(109.04,93.15) ; U3.G5 v5(137.45,125.54) ; U37.47 v7(168.66,83.39) ; U3.J9 v1(141.44,123.94) ; U6.T1 v1(112.69,25.88) ; U6.F9 v1(120.06,34.28) ; U6.B3 v1(115.26,37.48) ; U1.R12 v4(101.44,84.01) ; U3.H5 v5(137.45,124.74) ; U7.G9 v1(104.02,33.48) ; U3.D6 v5(138.25,128.73) ; U7.T9 v1(104.98,25.88) ; U7.F9 v1(104.82,34.28) ; U37.15 v7(159.82,76.89) ; U6.E2 v1(114.46,35.08)
  TOP w0.279: J24.5 v7(65.15,7.09) ; J24.2 v7(66.65,7.09) ; U46.6 64.97,20.12 v7(65.28,19.81) ; v7(58.8,6.99) 59.15,7.33 J24.17 ; v7(61.21,13.34) 61.72,13.85 U46.14 ; U46.19 v7(64.97,16.37) ; J24.8 v7(63.65,7.09) ; J24.11 v7(62.15,7.09)
  TOP w0.381: R363.1 v7(49.66,124.8) ; C261.2 v7(102.23,128.73) ; U44.3 v7(56.25,40.8) ; v1(143.64,67.04) 143.64,67.64 C512.2 ; U3.M12 v5(143.84,121.54) ; v5(143.84,121.54) U3.N13 v5(144.64,120.74) ; v5(143.84,121.54) 144.23,121.94 U3.M13 ; 20.7,120.35 20.7,120.22 v1(20.19,119.72) ; C460.2 v7(156.18,119.25) ; C109.2 23.11,119.72 22.86,119.97 v1(22.61,119.97) ; v7(31.5,30.31) R550.2 ; v1(134.84,59.62) 135.13,59.33 C514.2 ; U28.3 v7(178.29,60.03) ; R928.1 96.01,102.29 v1(96.27,102.03) ; v7(153.75,115.91) 153.75,116.54 C278.2 154.51,116.97 ; v7(184.3,99.65) J18.61 184.3,96.42 v7(183.97,96.09) 184.3,95.76 J18.62 184.3,90.3 v7(184.61,90) 184.3,89.69 J18.63 184.3,83.85 v7(184.56,83.6) 184.3,83.34 J18.64 184.3,79.76 v7(184.28,79.74) ; C461.2 163.45,119.09 v7(163.45,118.57) ; C461.2 v7(164.08,119.69) ; C461.2 162.31,119.15 v7(162.31,118.57) ; SW2.2 v7(167.51,55.42) SW2.1 ; v1(22.61,117.43) 22.86,117.68 C105.2 ; C519.2 142.91,58.88 v1(143.64,59.62) ; R157.1 R156.1 ; R157.1 v7(38.73,102.44) ; R157.1 R158.1 v7(38.73,101.3) ; v7(126.03,38.48) R34.2 ; R34.2 R39.2 v7(125.22,36.66) ; R34.2 R37.2 ; v1(137.24,67.04) 137.54,67.33 C516.2 ; v7(171.83,46.69) 171.29,46.15 SW1.2 ; v7(132.18,56.22) C510.2 v7(133.24,55.07) ; v7(67.56,82.76) 67.98,82.34 69.22,82.34 R13.2 ; 77.72,89.62 C246.2 77.72,90.47 v7(77.64,90.56) ; R494.1 v5(164.13,90.05) ; C33.2 v7(92.31,17.78) ; C33.2 v7(91.17,16.64) ; C33.2 v7(91.17,18.92) ; R924.2 73.71,74.68 v7(73.66,74.63) ; v1(135.28,60.49) 134.45,60.49 134.24,60.28 C506.2 ; C238.2 154.28,78.36 v7(154.22,78.43) ; R298.2 41.73,124.54 v7(42.44,125.25) ; R913.1 v7(150.11,69.68) ; 177.95,17.4 v7(176.39,17.4) ; v7(100.06,20.19) C52.2 ; C52.2 v7(100.06,17.91) ; C52.2 v7(101.2,19.05) ; 124.59,25.02 v7(124.59,24.13) ; C90.2 110.11,17.78 v7(110.49,18.16) ; C500.2 138.81,43.9 138.81,44.92 v1(138.48,45.25) ; C110.2 27.09,118.02 v7(27.41,117.71) ; v1(138.48,60.49) 138.81,60.16 138.81,59.14 C507.2 ; C429.2 v7(58.76,14.75) ; v7(162.49,127.06) 162.49,126.37 C462.2 ; v7(159.51,115) 159.51,115.48 C463.2 ; C243.2 v7(155.5,85.09) ; C511.2 135.26,67.42 v1(135.64,67.04) ; v1(146.84,51.8) 146.84,52.44 C488.2 ; v7(63.81,125.61) C179.2 v7(63.81,128.53) ; R304.1 v7(36.88,115.22) ; v7(46.56,129.57) C158.2 v7(43.64,129.57) ; C501.2 135.13,44.09 v1(134.84,44.38) ; SW1.1 163.84,46.31 v7(161.8,46.31) ; R923.2 v7(66.42,80.52) R925.2 ; C176.2 v7(67.31,106.38) ; v7(154.94,115.91) 154.94,116.54 154.51,116.97 ; v1(135.64,51.8) 135.26,52.18 C494.2 ; C174.2 49.66,122 v7(50.29,121.37) ; C427.2 v7(59.89,22.86) ; 92.33,111.71 92.33,113.11 v7(91.7,113.74) ; U85.3 v7(56.22,48.15) ; C515.2 139.83,67.65 139.83,66.71 v1(139.28,66.17) ; SW3.1 v7(167.51,64.44) SW3.2 ; v1(146.84,59.62) 147.07,59.4 C517.2 ; C425.2 v7(173.74,68.51) ; v1(139.64,59.62) 139.57,59.55 C508.2 ; C407.2 v7(143.11,101.05) ; J19.5 v7(184.94,15.7) ; C462.2 163.48,126.64 v7(163.48,127.06) ; C462.2 v7(163.99,126.01) ; U79.4 159.38,119.36 159.42,119.32 v7(159.42,119.27) ; C469.2 v7(58.39,37.21) ; J15.6 v7(84.55,149.04) ; C556.2 v7(53.98,23.42) ; v7(168.92,89.29) 168.83,89.2 168.29,89.2 C232.2 ; C509.2 145.03,59.41 v1(145.24,59.62) ; C493.2 137.54,52.09 v1(137.24,51.8) ; v7(99.44,124.69) 99.42,124.67 C28.2 ; v7(63.63,122.38) 63.5,122.25 C186.2 ; v1(146.84,67.04) 146.84,67.68 C513.2 ; C262.2 v7(102.23,129.75) ; v1(139.64,44.38) 139.57,44.31 C499.2 ; v7(150.63,56.46) 151,56.09 C528.2 ; R35.2 v7(107.63,39.5) ; R648.1 161.07,117.97 v7(161.06,117.96) ; 154.51,116.97 v7(155.52,116.97) ; C547.2 v7(9.27,41.99) ; v7(49.4,24.13) C303.2 ; v1(135.28,64.57) 135.26,64.54 135.26,63.84 ; C308.2 v7(23.88,34.75) ; U76.2 v7(145.72,100.16) ; U47.3 v7(123.57,45.58) ; v7(108.71,8.91) C88.2 v7(111,8.91) ; C264.2 v7(101.47,126.95) ; R542.1 v7(49.53,39.5) ; R348.1 v7(58.17,114.25) ; C214.2 v7(129.16,47.62) ; R103.1 24.13,121.11 v5(24.64,121.62) ; v7(100.08,131.78) C479.2 v7(98.92,132.92) ; C244.2 v7(155.5,83.95) ; v1(143.64,51.8) 143.64,52.4 C490.2 ; C470.2 v7(55.73,43.66) ; C420.2 v7(172.97,75.65) ; v7(42.55,122.51) C165.2 ; R37.2 R32.2 v7(125.22,41.32) ; R37.2 v7(126.03,39.5) ; R484.1 v7(164.13,68.58) ; C195.2 v7(180.28,54.44) ; R810.2 v7(146.3,139.83) ; v1(135.28,45.25) 135.08,45.04 C502.2 ; R425.2 v5(145.16,137.24) ; Q9.S 75.3,149.83 v7(74.68,150.45) ; R38.2 v7(108.33,36.77) ; v7(154.35,81.15) 154.36,81.15 154.36,81.16 155.24,81.16 R479.2 ; R793.1 v7(123.19,43.9) ; C181.2 v7(49.66,117.18) ; v7(184.57,17.27) 184.56,17.27 184.43,17.4 182.78,17.4 ; R489.1 v7(169.09,70.24) ; C525.2 v7(149.73,68.28) ; C229.2 v7(167.94,70.24) ; v7(148.95,55.58) C492.2 v7(148.95,57.87) ; R361.1 v7(59.56,114.25) ; v7(27.58,123.32) 27.58,123.68 R319.1 ; C263.2 v7(101.47,131.53) ; U96.3 v7(148.07,141.08) ; v5(141.48,137.24) C301.2 ; R321.1 v7(27.94,120.35) ; C304.2 v7(46.61,39.5) ; C484.2 v5(151.89,101.05) ; v7(107.52,40.25) 107.79,40.51 R33.2 ; R643.2 v7(76.2,73.66) ; R430.2 v5(144.02,137.16) ; R561.1 v7(56.52,13.76) ; R317.1 v7(38.28,115.22) ; C239.2 v7(162.23,70.24) ; C227.2 v7(173.53,77.6) ; C428.2 v7(69.22,12.34) ; v7(166.42,89.29) C242.1 ; C523.2 140.9,60.58 v1(140.88,60.57) ; C247.2 v7(76.92,86.44) ; C152.2 v7(132.33,143.46) ; C196.2 v7(186.44,61.3) ; U50.2 v7(159.72,60.41) ; v7(159.44,89.29) C235.2 ; U82.2 v7(160.28,10.67) ; R341.2 61.72,126.32 v7(61.47,126.57) ; C169.2 v7(41.15,101.61) ; R147.1 v7(24.77,97.74) ; U83.2 163.82,11.3 v7(164.47,11.3) ; R791.2 v7(17.91,47.58) ; R571.2 v7(147.83,113.54) ; R40.2 v7(107.63,38.48) ; U94.1 v7(22.73,45.93) ; C27.1 v5(140.34,137.24) ; R539.1 v7(53.72,39.5) ; C177.2 v7(75.18,108.79)
  TOP w0.508: v7(94.26,138.13) 94.26,137.2 J15.15 ; U74.3 v7(128.6,6.35) ; v7(97.56,134.17) 97.19,134.54 U84.2 ; 181.83,4.57 J1_1.1 181.83,2.57 ; C142.2 v7(25.53,56.23) ; C45.2 v7(77.98,31.24) ; v7(134.75,6.22) 134.57,6.4 C435.2 v7(131.5,6.4) ; v7(81.69,150.63) 83.32,150.63 ; C53.2 v7(108.46,31.24) ; C118.2 v7(25.53,98.77) ; R192.1 R191.1 v7(37.85,87.84) ; J15.11 v7(99.15,140) ; v7(51.84,111.22) C175.2 v7(49.37,111.22) ; R579.1 v7(130.68,10.95) ; R193.1 R194.1 R187.1 ; C64.2 v7(115.3,17.91) ; C64.2 v7(115.3,20.19) ; C64.2 v7(116.44,19.05) ; v7(111,20.45) 111,19.32 C91.2 ; v7(110.36,22.99) 109.98,23.37 C93.2 ; R48.1 v7(112.41,13.97) ; R44.1 v7(110.11,30.1) ; 124.59,30.1 125.43,30.1 v7(125.63,30.3) ; C101.2 v7(103.37,16.26) ; J1.2 180.47,115.08 ; J1.2 177.51,118.04 ; J1.2 177.51,115.08 ; J1.2 180.47,118.04 ; C82.2 v7(93.22,31.24) ; R237.1 R238.1 37.85,57.74 ; v7(37.85,63.07) R235.1 R236.1 ; J15.16 89.31,137.15 v7(89.41,137.24) ; C83.2 v7(110.11,28.7) ; 180.76,113.24 J1.3 ; J1.3 183.72,110.28 ; J1.3 180.76,110.28 ; J1.3 183.72,113.24 ; C86.2 v7(112.41,16.26) ; R798.1 v7(164.47,3.89) ; J15.9 v7(86.36,137.65) ; R116.1 v7(140.34,11.43) ; R41.1 v7(94.87,30.1) ; 178.53,14.81 TP1_1.1 176.92,14.81 ; C147.2 35,52.28 34.34,51.62 33.62,51.62 v7(33.53,51.71) ; J15.12 83.59,141.35 v7(83.59,142.7) ; C120.2 v7(32.5,94.82) ; C144.2 v7(32.5,52.28) ; v7(30.43,114.5) C156.2 v7(27.94,114.5) ; v7(160.06,14.56) C249.2 ; C46.2 v7(94.87,28.96) ; 124.59,28.7 v7(125.35,28.7) ; R2_1.2 v7(172.19,5.73) ; v7(99.69,150.6) 98.49,150.6 ; C99.2 v7(104.52,11.81) ; v7(145.16,13.65) 145.16,13.34 144.67,12.84 Q16.S ; v7(35.81,77.04) C135.2 ; 185.67,115.23 J2.2 ; J2.2 187.28,113.62 ; J2.2 187.28,115.23 ; J2.2 185.67,113.62 ; C123.2 33.86,93.93 v7(33.63,94.16) ; C130.2 v7(31.75,76.28) ; v7(177.15,5.1) 177.15,6.54 C2_1.2 ; C137.2 v7(25.53,80.99) ; U40.1 v7(159.51,19.64) ; C432.2 v7(130.56,6.6) ; C316.2 v7(139.1,12.27) ; C321.2 v7(36.07,36.66) ; R156.1 R155.1
  L2_GND1 w0.381: 4.21,43.18 4.22,43.18
  L2_GND1 w0.508: J22.A12 59.24,35.77 ; J22.A12 59.24,34.55 ; J22.A12 58.02,34.55 ; J22.A12 58.02,35.77 ; 61.21,144.7 J12.13 ; J12.13 62.73,144.7 ; J12.13 62.73,143.18 ; 48.02,28.05 J22.B4 ; J22.B4 48.02,29.27 ; J22.B4 49.24,29.27 ; J22.B4 49.24,28.05 ; 140.84,19.2 U18.M1 ; U18.M1 140.84,21.5 ; U18.M1 143.14,21.5 ; U18.M1 143.14,19.2 ; J23.4 43.83,13.19 ; J23.4 42.65,13.19 ; J23.4 42.65,14.37 ; 68.84,6.69 J24.MTG2 ; J24.MTG2 68.84,8.31 ; J24.MTG2 70.45,8.31 ; J24.MTG2 70.45,6.69 ; J22.B13 60.24,31.27 ; J22.B13 59.02,30.05 ; J22.B13 60.24,30.05 ; J12.1 61.68,131.79 ; J12.1 61.68,133.23 ; J12.1 60.24,131.79 ; J12.1 60.24,133.23 ; 52.79,79.16 J4.5 ; J4.5 54.4,77.55 ; J4.5 52.79,77.55 ; J4.5 54.4,79.16 ; 69.44,1.79 J24.MTG4 ; J24.MTG4 71.05,3.41 ; J24.MTG4 69.44,3.41 ; J24.MTG4 71.05,1.79 ; 79.46,149.05 TP8.1 ; TP8.1 81.07,149.05 ; TP8.1 79.46,150.67 ; TP8.1 81.07,150.67 ; J21.59 160.06,147.74 ; J21.59 160.06,146.3 ; J21.59 158.63,147.74 ; J21.59 158.63,146.3 ; J8.8 20.41,52.63 ; J8.8 18.97,54.06 ; J8.8 18.97,52.63 ; J8.8 20.41,54.06 ; SCKT1.MCH2 116.1,68.13 ; SCKT1.MCH2 116.1,70.13 ; SCKT1.MCH2 114.1,68.13 ; SCKT1.MCH2 114.1,70.13 ; J37.30 188.24,24.26 ; J37.30 188.24,22.73 ; J37.30 186.72,24.26 ; J37.30 186.72,22.73 ; 47.76,145.21 J12.12 ; J12.12 49.28,146.73 ; J12.12 49.28,145.21 ; J12.12 47.76,146.73 ; 38.53,131.79 J10.1 ; J10.1 39.96,133.23 ; J10.1 38.53,133.23 ; J10.1 39.96,131.79 ; J22.B18 65.24,28.05 ; J22.B18 64.02,29.27 ; J22.B18 64.02,28.05 ; J22.B18 65.24,29.27 ; 184.18,22.73 J37.29 ; J37.29 184.18,24.26 ; J37.29 185.7,22.73 ; J37.29 185.7,24.26 ; 158.63,149.74 J21.60 ; J21.60 160.06,149.74 ; J21.60 160.06,148.3 ; J21.60 158.63,148.3 ; 18.97,77.39 J6.8 ; J6.8 20.41,78.82 ; J6.8 20.41,77.39 ; J6.8 18.97,78.82 ; J46.1 169.33,10.71 ; J46.1 167.72,10.71 ; J46.1 169.33,12.32 ; J46.1 167.72,12.32 ; J44.2 84.37,108.62 ; J44.2 84.37,110.23 ; J44.2 82.76,110.23 ; J44.2 82.76,108.62 ; 180.76,113.24 J1.3 ; J1.3 183.72,110.28 ; J1.3 183.72,113.24 ; J1.3 180.76,110.28 ; J22.B7 52.24,30.05 ; J22.B7 51.02,30.05 ; J22.B7 51.02,31.27 ; J22.B7 52.24,31.27 ; J10.12 27.57,146.73 ; J10.12 27.57,145.21 ; J10.12 26.04,146.73 ; J10.12 26.04,145.21 ; 39.49,144.7 J10.13 ; J10.13 41.01,144.7 ; J10.13 41.01,143.18 ; J21.22 122.06,148.3 ; J21.22 122.06,149.74 ; J21.22 120.63,149.74 ; J21.22 120.63,148.3 ; SCKT1.MCH4 90.37,93.85 ; SCKT1.MCH4 88.37,95.86 ; SCKT1.MCH4 90.37,95.86 ; SCKT1.MCH4 88.37,93.85 ; J1_1.1 181.59,2.81 ; J1_1.1 181.59,4.33 ; J1_1.1 180.07,4.33 ; J1_1.1 180.07,2.81 ; 177.51,118.04 J1.2 ; J1.2 180.47,115.08 ; J1.2 180.47,118.04 ; J1.2 177.51,115.08 ; 170.92,136.31 J9.11 ; J9.11 170.92,137.92 ; J9.11 172.54,137.92 ; J9.11 172.54,136.31 ; 157.99,3.3 J39.3 ; J39.3 159.51,4.82 ; J39.3 159.51,3.3 ; J39.3 157.99,4.82 ; 138.63,149.74 J21.40 ; J21.40 138.63,148.3 ; J21.40 140.06,148.3 ; J21.40 140.06,149.74 ; 54.34,6.69 J24.MTG1 ; J24.MTG1 54.34,8.31 ; J24.MTG1 55.95,8.31 ; J24.MTG1 55.95,6.69 ; 63.02,30.05 J22.B17 ; J22.B17 63.02,31.27 ; J22.B17 64.24,30.05 ; J22.B17 64.24,31.27 ; J5.8 20.41,102.95 ; J5.8 18.97,102.95 ; J5.8 18.97,101.52 ; J5.8 20.41,101.52 ; 187.05,121.41 TP9.1 ; TP9.1 188.66,119.8 ; TP9.1 188.66,121.41 ; TP9.1 187.05,119.8 ; 140.84,27 U18.M2 ; U18.M2 143.14,27 ; U18.M2 140.84,29.3 ; U18.M2 143.14,29.3 ; 52.66,71.16 J7.5 ; J7.5 54.27,71.16 ; J7.5 54.27,69.55 ; J7.5 52.66,69.55 ; 138.63,147.74 J21.39 ; J21.39 140.06,146.3 ; J21.39 138.63,146.3 ; J21.39 140.06,147.74 ; J22.A18 65.24,35.77 ; J22.A18 64.02,34.55 ; J22.A18 65.24,34.55 ; J22.A18 64.02,35.77 ; 1.86,13.29 TP11.1 ; TP11.1 1.86,14.9 ; TP11.1 3.47,14.9 ; TP11.1 3.47,13.29 ; J22.A4 49.24,34.55 ; J22.A4 48.02,34.55 ; J22.A4 48.02,35.77 ; J22.A4 49.24,35.77 ; J2.2 187.28,115.23 ; J2.2 187.28,113.62 ; J2.2 185.67,113.62 ; J2.2 185.67,115.23 ; 183.62,137.92 J9.21 ; J9.21 185.24,136.31 ; J9.21 185.24,137.92 ; J9.21 183.62,136.31 ; 19.69,126.36 20.41,125.65 ; 19.69,126.36 18.97,125.65 ; 19.69,126.36 20.41,127.08 ; 19.69,126.36 18.97,127.08 ; 62.02,28.05 J22.B16 ; J22.B16 63.24,28.05 ; J22.B16 62.02,29.27 ; J22.B16 63.24,29.27 ; 176.65,14 TP1_1.1 ; TP1_1.1 178.79,14 ; TP1_1.1 177.72,12.93 ; TP1_1.1 177.72,15.07 ; 61.02,32.55 J22.A15 ; J22.A15 62.24,32.55 ; J22.A15 61.02,33.77 ; J22.A15 62.24,33.77 ; 38.97,15.28 J23.7 39.74,14.52 ; J9.12 172.54,140.46 ; J9.12 172.54,138.85 ; J9.12 170.92,138.85 ; J9.12 170.92,140.46 ; 74.42,1.86 TP10.1 ; TP10.1 74.42,3.47 ; TP10.1 76.03,1.86 ; TP10.1 76.03,3.47 ; J24.MTG3 55.35,1.79 ; J24.MTG3 53.74,3.41 ; J24.MTG3 55.35,3.41 ; J24.MTG3 53.74,1.79 ; J37.17 185.7,39.5 ; J37.17 184.18,39.5 ; J37.17 185.7,37.97 ; J37.17 184.18,37.97
  L3_SIG1 w0.203: v4(94.24,73.62) v6(93.84,73.37)
  L3_SIG1 w0.254: v4(91.04,70.42) 91.04,69.95 v6(91.03,69.95) ; 80.57,110.63 78.81,110.63 v7(78.74,110.7) 78.67,110.63 v5(76.76,110.63) 73.72,110.63 v5(73.15,110.06) 72.47,110.06 68.13,105.72 66.69,105.72 66.34,105.36 v5(66.29,105.36) v5(55.27,105.36) v5(50.5,105.36) 49.64,105.36 v5(44.07,110.93) v5(42.68,112.32) ; 80.57,110.63 81.34,110.63 v5(81.41,110.7) 81.72,110.7 82.11,111.08 84.25,111.08 86.85,108.48 v5(87.67,108.48) 88.52,107.62 v5(90.14,107.62) ; 80.57,110.63 v7(80.64,110.7) ; v11(107.03,80.82) v6(107.43,80.57) ; v4(96.64,86.41) 96.24,86.66 v6(96.24,86.66) ; v6(113.83,82.66) v4(113.43,82.41) ; v6(91.42,93.29) v4(91.82,93.05) ; v4(109.04,93.15) v6(109.04,93.62) ; v4(100.64,84.81) 100.24,85.06 v6(100.24,85.06) ; v4(96.64,76.82) v6(96.24,76.57) ; v4(103.83,72.82) 104.19,72.46 v6(104.2,72.46) ; v6(105.83,82.66) v4(105.43,82.41) ; v4(100.64,76.02) 100.9,75.75 100.99,75.75 v6(101.02,75.72) ; v4(101.44,76.02) 101.68,75.77 v6(101.85,75.77) ; v4(95.84,84.81) v6(95.44,85.06) ; v4(93.44,77.62) v6(93.04,77.37) ; v4(101.44,80.82) v6(101.04,80.57) ; v4(94.24,77.62) v6(93.84,77.37) ; v6(109.83,88.26) v4(109.43,88.01) ; v4(96.64,84.81) 96.24,85.06 v6(96.24,85.06) ; v4(103.83,73.62) 104.19,73.26 v6(104.2,73.26) ; v6(104.23,82.66) 104.23,82.66 v4(103.83,82.41) ; 83.46,109.54 v5(80.49,109.54) 78.5,109.54 v7(78.49,109.56) 78.47,109.54 v5(75.54,109.54) 74.79,109.54 v5(70.54,105.28) 69.44,105.28 68.43,104.27 v5(60.25,104.27) v5(56.92,104.27) v5(52.17,104.27) 48.47,104.27 v5(48.45,104.29) 46.82,105.92 46.53,105.92 v5(43.01,109.44) 41.63,110.81 v5(41.63,111.88) ; v4(96.64,85.61) 96.24,85.86 v6(96.24,85.86) ; v11(103.83,77.62) v6(104.23,77.37) ; v4(94.24,85.61) v6(93.84,85.93) ; v6(93.77,82.88) 93.95,82.7 93.96,82.7 94.14,82.51 v4(94.16,82.51) ; v4(104.63,77.62) v6(105.03,77.37) ; v6(100.24,84.26) 100.24,84.26 v4(100.64,84.01) ; v6(94.24,93.4) 94.53,93.4 v4(94.7,93.58) ; v6(93.26,85.97) 93.26,85.86 93.48,85.64 v4(93.48,85.56) ; v6(96.24,87.46) 96.24,87.46 v4(96.64,87.21) ; v6(105.83,83.46) v4(105.43,83.21) ; v6(90.51,92.39) v4(90.91,92.14) ; v4(107.83,84.01) 108.23,84.26 v6(108.23,84.26) ; v4(96.64,80.82) v6(96.24,80.57) ; v4(91.04,76.82) v6(90.64,76.57) ; v4(106.23,80.82) v6(106.63,80.57) ; v4(113.43,70.42) v6(112.96,70.42) ; v4(100.64,82.41) 100.24,82.66 v6(100.24,82.66) ; v4(103.83,80.82) v6(104.23,80.57) ; v4(100.64,80.82) v6(100.24,80.57) ; v4(113.43,74.42) 113.68,74.17 v6(113.84,74.17) ; v4(111.03,77.62) v6(111.43,77.37) ; v6(99.44,82.66) v4(99.84,82.41) ; v4(91.01,92.94) 90.61,93.19 v6(90.51,93.19) ; v4(101.44,83.21) v6(101.04,83.46) ; v4(99.84,80.82) v6(99.44,80.57) ; v6(100.24,85.86) 100.24,85.86 v4(100.64,85.61) ; v6(99.44,78.97) v11(99.84,79.22) v4(100.64,79.22) ; v6(113.83,89.06) v4(113.43,88.81) ; v4(101.44,84.01) v6(101.04,84.26) ; v6(110.63,83.46) v4(110.23,83.21) ; v4(100.64,78.42) v6(100.24,78.17) ; v4(101.83,93.15) v6(101.83,93.62) ; v4(94.24,83.21) 94.24,83.1 v6(94.51,82.83) 94.92,82.41 v4(95.04,82.41) ; v4(95.84,76.82) v6(95.44,76.57) ; v4(98.64,93.15) v6(98.64,93.62) ; v6(111.43,83.46) v4(111.03,83.21) ; v6(109.03,87.46) v4(108.63,87.21) ; v4(99.04,80.82) v6(98.64,80.57) ; v4(110.23,77.62) v6(110.63,77.37) ; v11(99.04,79.22) v6(98.64,78.97) ; v6(109.03,88.26) v4(108.63,88.01) ; v6(109.03,86.66) v4(108.63,86.41) ; v4(98.2,69.87) v6(97.84,70.17) ; v6(113.83,92.26) v4(113.43,92.01) ; v6(112.63,93.23) v4(112.23,92.98) ; v6(107.43,84.26) v4(107.03,84.01) ; v6(113.83,93.06) v4(113.43,92.81) ; v4(99.84,76.82) 100.14,76.51 100.23,76.51 100.23,76.52 v6(100.26,76.52) ; v4(98.24,73.62) v6(97.84,73.37) ; v4(98.24,72.82) v6(97.84,72.57) ; v4(98.24,80.82) v6(97.84,80.57)
  L3_SIG1 w0.381: v6(36.93,99.7) v5(36.93,99.12) ; J44.2 83.46,109.54
  L3_SIG1 w0.508: 52.66,71.16 J7.5 ; J7.5 52.66,69.55 ; J7.5 54.27,71.16 ; 18.97,54.06 J8.8 ; J8.8 20.41,52.63 ; J8.8 18.97,52.63 ; J8.8 20.41,54.06 ; 18.97,77.39 J6.8 ; J6.8 20.41,78.82 ; J6.8 20.41,77.39 ; J6.8 18.97,78.82 ; J37.29 185.7,22.73 ; J37.29 185.7,24.26 ; J37.29 184.18,22.73 ; J37.29 184.18,24.26 ; 52.79,77.55 J4.5 52.79,79.16 ; 170.92,136.31 J9.11 ; J9.11 172.54,136.31 ; J9.11 172.54,137.92 ; J9.11 170.92,137.92 ; J10.12 27.57,146.73 ; J10.12 26.04,145.21 ; J10.12 26.04,146.73 ; J10.12 27.57,145.21 ; 61.21,144.7 J12.13 ; J12.13 62.73,143.18 ; J12.13 62.73,144.7 ; 39.49,144.7 J10.13 ; J10.13 41.01,143.18 ; J10.13 41.01,144.7 ; 180.07,4.33 J1_1.1 ; J1_1.1 181.59,4.33 ; J1_1.1 180.07,2.81 ; J1_1.1 181.59,2.81 ; J10.1 39.96,133.23 ; J10.1 38.53,133.23 ; J10.1 39.96,131.79 ; J10.1 38.53,131.79 ; J37.30 188.24,22.73 ; J37.30 188.24,24.26 ; J37.30 186.72,24.26 ; J37.30 186.72,22.73 ; 176.65,14 TP1_1.1 177.72,12.93 ; 79.46,149.05 TP8.1 ; TP8.1 81.07,150.67 ; TP8.1 79.46,150.67 ; TP8.1 81.07,149.05 ; 184.18,39.5 J37.17 ; J37.17 185.7,37.97 ; J37.17 184.18,37.97 ; J37.17 185.7,39.5 ; J12.12 49.28,145.21 ; J12.12 49.28,146.73 ; J12.12 47.76,146.73 ; J12.12 47.76,145.21 ; 170.92,140.46 J9.12 ; J9.12 172.54,140.46 ; J9.12 170.92,138.85 ; J9.12 172.54,138.85
  L4_SIG2 w0.508: 19.69,126.36 20.41,125.65 ; 19.69,126.36 18.97,127.08 ; 19.69,126.36 18.97,125.65 ; 19.69,126.36 20.41,127.08 ; J12.1 61.68,131.79 ; J12.1 60.24,133.23 ; J12.1 60.24,131.79 ; J12.1 61.68,133.23 ; TP8.1 81.07,149.05 ; TP8.1 81.07,150.67 ; TP8.1 79.46,150.67 ; TP8.1 79.46,149.05 ; J1.2 180.47,115.08 ; J1.2 180.47,118.04 ; J1.2 177.51,115.08 ; J10.12 27.57,146.73 ; J10.12 27.57,145.21 ; J10.12 26.04,145.21 ; J10.12 26.04,146.73 ; J22.A15 62.24,32.55 ; J22.A15 61.02,32.55 ; J22.A15 62.24,33.77 ; J22.A15 61.02,33.77 ; J22.B4 49.24,29.27 ; J22.B4 49.24,28.05 ; J22.B4 48.02,28.05 ; J22.B4 48.02,29.27 ; J10.13 41.01,144.7 ; J10.13 41.01,143.18 ; J10.13 39.49,144.7 ; J5.8 20.41,101.52 ; J5.8 18.97,102.95 ; J5.8 20.41,102.95 ; J5.8 18.97,101.52 ; J10.1 39.96,133.23 ; J10.1 38.53,133.23 ; J10.1 38.53,131.79 ; J10.1 39.96,131.79 ; 47.76,146.73 J12.12 ; J12.12 47.76,145.21 ; J12.12 49.28,146.73 ; J12.12 49.28,145.21 ; J22.B16 63.24,29.27 ; J22.B16 62.02,29.27 ; J22.B16 63.24,28.05 ; J22.B16 62.02,28.05 ; J12.13 62.73,144.7 ; J12.13 62.73,143.18 ; J12.13 61.21,144.7 ; 185.67,115.23 J2.2 ; J2.2 187.28,113.62 ; J2.2 185.67,113.62 ; J2.2 187.28,115.23 ; 58.02,34.55 J22.A12 ; J22.A12 58.02,35.77 ; J22.A12 59.24,34.55 ; J22.A12 59.24,35.77 ; 64.02,28.05 J22.B18 ; J22.B18 64.02,29.27 ; J22.B18 65.24,29.27 ; J22.B18 65.24,28.05 ; 59.02,30.05 J22.B13 ; J22.B13 60.24,30.05 ; J22.B13 60.24,31.27 ; J22.B17 64.24,31.27 ; J22.B17 63.02,31.27 ; J22.B17 63.02,30.05 ; J22.B17 64.24,30.05 ; J22.B7 52.24,30.05 ; J22.B7 52.24,31.27 ; J22.B7 51.02,31.27 ; J22.B7 51.02,30.05 ; 64.02,34.55 J22.A18 ; J22.A18 65.24,35.77 ; J22.A18 64.02,35.77 ; J22.A18 65.24,34.55 ; J22.A4 49.24,35.77 ; J22.A4 48.02,34.55 ; J22.A4 48.02,35.77 ; J22.A4 49.24,34.55 ; 180.76,113.24 J1.3 ; J1.3 180.76,110.28 ; J1.3 183.72,110.28 ; J1.3 183.72,113.24
  L5_GND2 w0.508: J21.22 122.06,149.74 ; J21.22 120.63,149.74 ; J21.22 122.06,148.3 ; J21.22 120.63,148.3 ; 26.04,145.21 J10.12 ; J10.12 27.57,145.21 ; J10.12 27.57,146.73 ; J10.12 26.04,146.73 ; 61.02,32.55 J22.A15 ; J22.A15 61.02,33.77 ; J22.A15 62.24,32.55 ; J22.A15 62.24,33.77 ; SCKT1.MCH4 90.37,95.86 ; SCKT1.MCH4 88.37,93.85 ; SCKT1.MCH4 90.37,93.85 ; SCKT1.MCH4 88.37,95.86 ; 184.18,24.26 J37.29 ; J37.29 184.18,22.73 ; J37.29 185.7,22.73 ; J37.29 185.7,24.26 ; 138.63,147.74 J21.39 ; J21.39 140.06,146.3 ; J21.39 140.06,147.74 ; J21.39 138.63,146.3 ; 170.92,136.31 J9.11 ; J9.11 170.92,137.92 ; J9.11 172.54,136.31 ; J9.11 172.54,137.92 ; 170.92,138.85 J9.12 ; J9.12 172.54,140.46 ; J9.12 170.92,140.46 ; J9.12 172.54,138.85 ; 180.76,113.24 J1.3 ; J1.3 183.72,113.24 ; J1.3 183.72,110.28 ; J1.3 180.76,110.28 ; J22.A12 59.24,34.55 ; J22.A12 58.02,34.55 ; J22.A12 58.02,35.77 ; J22.A12 59.24,35.77 ; 186.72,24.26 J37.30 ; J37.30 188.24,22.73 ; J37.30 186.72,22.73 ; J37.30 188.24,24.26 ; 180.07,2.81 J1_1.1 ; J1_1.1 180.07,4.33 ; J1_1.1 181.59,4.33 ; J1_1.1 181.59,2.81 ; 47.76,146.73 J12.12 ; J12.12 47.76,145.21 ; J12.12 49.28,145.21 ; J12.12 49.28,146.73 ; 74.42,1.86 TP10.1 ; TP10.1 76.03,3.47 ; TP10.1 74.42,3.47 ; TP10.1 76.03,1.86 ; 1.86,14.9 TP11.1 ; TP11.1 1.86,13.29 ; TP11.1 3.47,14.9 ; TP11.1 3.47,13.29 ; 82.76,108.62 J44.2 ; J44.2 84.37,110.23 ; J44.2 82.76,110.23 ; J44.2 84.37,108.62 ; J22.A4 49.24,35.77 ; J22.A4 48.02,34.55 ; J22.A4 49.24,34.55 ; J22.A4 48.02,35.77 ; J22.B16 63.24,29.27 ; J22.B16 63.24,28.05 ; J22.B16 62.02,28.05 ; J22.B16 62.02,29.27 ; 52.66,69.55 J7.5 ; J7.5 54.27,69.55 ; J7.5 52.66,71.16 ; J7.5 54.27,71.16 ; J22.B4 49.24,28.05 ; J22.B4 48.02,28.05 ; J22.B4 49.24,29.27 ; J22.B4 48.02,29.27 ; 38.53,133.23 J10.1 ; J10.1 39.96,133.23 ; J10.1 38.53,131.79 ; J10.1 39.96,131.79 ; J37.17 185.7,39.5 ; J37.17 184.18,39.5 ; J37.17 185.7,37.97 ; J37.17 184.18,37.97 ; 64.02,29.27 J22.B18 ; J22.B18 64.02,28.05 ; J22.B18 65.24,28.05 ; J22.B18 65.24,29.27 ; 114.1,68.13 SCKT1.MCH2 ; SCKT1.MCH2 116.1,68.13 ; SCKT1.MCH2 114.1,70.13 ; SCKT1.MCH2 116.1,70.13 ; 51.02,30.05 J22.B7 ; J22.B7 52.24,30.05 ; J22.B7 51.02,31.27 ; J22.B7 52.24,31.27 ; J21.40 140.06,149.74 ; J21.40 138.63,149.74 ; J21.40 140.06,148.3 ; J21.40 138.63,148.3 ; J6.8 20.41,78.82 ; J6.8 18.97,77.39 ; J6.8 18.97,78.82 ; J6.8 20.41,77.39 ; TP1_1.1 177.72,15.07 ; TP1_1.1 177.72,12.93 ; TP1_1.1 176.65,14 ; TP1_1.1 178.79,14 ; 157.99,4.82 J39.3 ; J39.3 159.51,3.3 ; J39.3 157.99,3.3 ; J39.3 159.51,4.82 ; 68.84,8.31 J24.MTG2 ; J24.MTG2 70.45,6.69 ; J24.MTG2 70.45,8.31 ; J24.MTG2 68.84,6.69 ; 52.79,79.16 J4.5 ; J4.5 52.79,77.55 ; J4.5 54.4,79.16 ; J4.5 54.4,77.55 ; 187.05,119.8 TP9.1 ; TP9.1 187.05,121.41 ; TP9.1 188.66,121.41 ; TP9.1 188.66,119.8 ; J21.59 160.06,147.74 ; J21.59 160.06,146.3 ; J21.59 158.63,147.74 ; J21.59 158.63,146.3 ; 63.02,31.27 J22.B17 ; J22.B17 63.02,30.05 ; J22.B17 64.24,31.27 ; J22.B17 64.24,30.05 ; J24.MTG3 55.35,1.79 ; J24.MTG3 53.74,3.41 ; J24.MTG3 53.74,1.79 ; J24.MTG3 55.35,3.41 ; J8.8 20.41,52.63 ; J8.8 18.97,52.63 ; J8.8 20.41,54.06 ; J8.8 18.97,54.06 ; 19.69,126.36 20.41,127.08 ; 19.69,126.36 20.41,125.65 ; 19.69,126.36 18.97,127.08 ; 19.69,126.36 18.97,125.65 ; J12.13 62.73,143.18 ; J12.13 62.73,144.7 ; J12.13 61.21,144.7 ; J21.60 160.06,149.74 ; J21.60 160.06,148.3 ; J21.60 158.63,148.3 ; J21.60 158.63,149.74 ; U18.M1 143.14,19.2 ; U18.M1 140.84,21.5 ; U18.M1 143.14,21.5 ; U18.M1 140.84,19.2 ; J24.MTG1 55.95,6.69 ; J24.MTG1 54.34,8.31 ; J24.MTG1 54.34,6.69 ; J24.MTG1 55.95,8.31 ; J12.1 61.68,131.79 ; J12.1 60.24,133.23 ; J12.1 61.68,133.23 ; J12.1 60.24,131.79 ; J9.21 185.24,136.31 ; J9.21 185.24,137.92 ; J9.21 183.62,137.92 ; J9.21 183.62,136.31 ; 140.84,27 U18.M2 ; U18.M2 143.14,29.3 ; U18.M2 143.14,27 ; U18.M2 140.84,29.3 ; 39.49,144.7 J10.13 ; J10.13 41.01,144.7 ; J10.13 41.01,143.18 ; 18.97,102.95 J5.8 ; J5.8 18.97,101.52 ; J5.8 20.41,102.95 ; J5.8 20.41,101.52 ; 64.02,35.77 J22.A18 ; J22.A18 64.02,34.55 ; J22.A18 65.24,35.77 ; J22.A18 65.24,34.55 ; 42.65,13.19 J23.4 ; J23.4 43.83,13.19 ; J23.4 42.65,14.37 ; 185.67,113.62 J2.2 ; J2.2 185.67,115.23 ; J2.2 187.28,113.62 ; J2.2 187.28,115.23 ; 79.46,149.05 TP8.1 ; TP8.1 79.46,150.67 ; TP8.1 81.07,149.05 ; TP8.1 81.07,150.67 ; J1.2 180.47,115.08 ; J1.2 177.51,118.04 ; J1.2 180.47,118.04 ; J1.2 177.51,115.08 ; J24.MTG4 71.05,1.79 ; J24.MTG4 69.44,1.79 ; J24.MTG4 69.44,3.41 ; J24.MTG4 71.05,3.41 ; 38.97,15.28 J23.7 39.74,14.52 ; J22.B13 60.24,30.05 ; J22.B13 60.24,31.27 ; J22.B13 59.02,30.05 ; 167.72,10.71 J46.1 ; J46.1 169.33,10.71 ; J46.1 167.72,12.32 ; J46.1 169.33,12.32
  L6_PWR1 w0.508: 38.53,133.23 J10.1 ; J10.1 39.96,131.79 ; J10.1 39.96,133.23 ; J10.1 38.53,131.79 ; 61.21,144.7 J12.13 ; J12.13 62.73,143.18 ; J12.13 62.73,144.7 ; J8.8 20.41,52.63 ; J8.8 18.97,52.63 ; J8.8 18.97,54.06 ; J8.8 20.41,54.06 ; 52.79,77.55 J4.5 ; J4.5 52.79,79.16 ; J4.5 54.4,77.55 ; J4.5 54.4,79.16 ; 47.76,146.73 J12.12 ; J12.12 49.28,146.73 ; J12.12 47.76,145.21 ; J12.12 49.28,145.21 ; J10.13 41.01,144.7 ; J10.13 39.49,144.7 ; J10.13 41.01,143.18 ; 18.97,102.95 J5.8 ; J5.8 18.97,101.52 ; J5.8 20.41,101.52 ; J5.8 20.41,102.95 ; J12.1 61.68,131.79 ; J12.1 60.24,133.23 ; J12.1 60.24,131.79 ; J12.1 61.68,133.23 ; J10.12 27.57,145.21 ; J10.12 26.04,146.73 ; J10.12 26.04,145.21 ; J10.12 27.57,146.73 ; J44.2 84.37,108.62 ; J44.2 82.76,110.23 ; J44.2 82.76,108.62 ; J44.2 84.37,110.23 ; 90.37,95.86 SCKT1.MCH4 88.37,95.86 ; 19.69,126.36 20.41,127.08 ; 19.69,126.36 18.97,127.08 ; 19.69,126.36 18.97,125.65 ; 19.69,126.36 20.41,125.65 ; J6.8 20.41,78.82 ; J6.8 18.97,77.39 ; J6.8 20.41,77.39 ; J6.8 18.97,78.82
  L8_GND3 w0.508: 59.02,30.05 J22.B13 ; J22.B13 60.24,30.05 ; J22.B13 60.24,31.27 ; J21.22 122.06,149.74 ; J21.22 120.63,149.74 ; J21.22 122.06,148.3 ; J21.22 120.63,148.3 ; J9.21 185.24,136.31 ; J9.21 183.62,137.92 ; J9.21 183.62,136.31 ; J9.21 185.24,137.92 ; 58.02,34.55 J22.A12 ; J22.A12 59.24,34.55 ; J22.A12 59.24,35.77 ; J22.A12 58.02,35.77 ; 180.07,2.81 J1_1.1 ; J1_1.1 181.59,4.33 ; J1_1.1 180.07,4.33 ; J1_1.1 181.59,2.81 ; J46.1 169.33,10.71 ; J46.1 169.33,12.32 ; J46.1 167.72,10.71 ; J46.1 167.72,12.32 ; 114.1,70.13 SCKT1.MCH2 ; SCKT1.MCH2 116.1,70.13 ; SCKT1.MCH2 114.1,68.13 ; SCKT1.MCH2 116.1,68.13 ; J8.8 20.41,52.63 ; J8.8 20.41,54.06 ; J8.8 18.97,54.06 ; J8.8 18.97,52.63 ; 62.02,28.05 J22.B16 ; J22.B16 63.24,28.05 ; J22.B16 63.24,29.27 ; J22.B16 62.02,29.27 ; J22.B17 64.24,31.27 ; J22.B17 64.24,30.05 ; J22.B17 63.02,30.05 ; J22.B17 63.02,31.27 ; J22.B7 52.24,30.05 ; J22.B7 51.02,30.05 ; J22.B7 52.24,31.27 ; J22.B7 51.02,31.27 ; J10.1 39.96,133.23 ; J10.1 38.53,133.23 ; J10.1 39.96,131.79 ; J10.1 38.53,131.79 ; J9.12 172.54,138.85 ; J9.12 172.54,140.46 ; J9.12 170.92,138.85 ; J9.12 170.92,140.46 ; 19.69,126.36 20.41,125.65 ; 19.69,126.36 20.41,127.08 ; 19.69,126.36 18.97,125.65 ; 19.69,126.36 18.97,127.08 ; J24.MTG2 70.45,8.31 ; J24.MTG2 68.84,8.31 ; J24.MTG2 70.45,6.69 ; J24.MTG2 68.84,6.69 ; J37.30 188.24,24.26 ; J37.30 186.72,24.26 ; J37.30 186.72,22.73 ; J37.30 188.24,22.73 ; J6.8 20.41,78.82 ; J6.8 20.41,77.39 ; J6.8 18.97,78.82 ; J6.8 18.97,77.39 ; 60.24,131.79 J12.1 ; J12.1 60.24,133.23 ; J12.1 61.68,133.23 ; J12.1 61.68,131.79 ; 187.05,119.8 TP9.1 ; TP9.1 188.66,121.41 ; TP9.1 188.66,119.8 ; TP9.1 187.05,121.41 ; 54.34,6.69 J24.MTG1 ; J24.MTG1 55.95,6.69 ; J24.MTG1 55.95,8.31 ; J24.MTG1 54.34,8.31 ; J22.A4 49.24,35.77 ; J22.A4 49.24,34.55 ; J22.A4 48.02,35.77 ; J22.A4 48.02,34.55 ; J24.MTG4 71.05,3.41 ; J24.MTG4 71.05,1.79 ; J24.MTG4 69.44,3.41 ; J24.MTG4 69.44,1.79 ; TP11.1 3.47,13.29 ; TP11.1 3.47,14.9 ; TP11.1 1.86,14.9 ; TP11.1 1.86,13.29 ; J22.B18 65.24,29.27 ; J22.B18 64.02,28.05 ; J22.B18 65.24,28.05 ; J22.B18 64.02,29.27 ; J21.40 140.06,148.3 ; J21.40 140.06,149.74 ; J21.40 138.63,149.74 ; J21.40 138.63,148.3 ; 42.65,14.37 J23.4 ; J23.4 43.83,13.19 ; J23.4 42.65,13.19 ; 52.66,69.55 J7.5 ; J7.5 54.27,71.16 ; J7.5 54.27,69.55 ; J7.5 52.66,71.16 ; J22.B4 49.24,28.05 ; J22.B4 49.24,29.27 ; J22.B4 48.02,28.05 ; J22.B4 48.02,29.27 ; 64.02,35.77 J22.A18 ; J22.A18 64.02,34.55 ; J22.A18 65.24,34.55 ; J22.A18 65.24,35.77 ; TP10.1 76.03,3.47 ; TP10.1 74.42,3.47 ; TP10.1 76.03,1.86 ; TP10.1 74.42,1.86 ; J22.A15 62.24,33.77 ; J22.A15 61.02,33.77 ; J22.A15 62.24,32.55 ; J22.A15 61.02,32.55 ; 157.99,3.3 J39.3 ; J39.3 157.99,4.82 ; J39.3 159.51,4.82 ; J39.3 159.51,3.3 ; 26.04,145.21 J10.12 ; J10.12 27.57,146.73 ; J10.12 26.04,146.73 ; J10.12 27.57,145.21 ; 170.92,136.31 J9.11 ; J9.11 172.54,136.31 ; J9.11 172.54,137.92 ; J9.11 170.92,137.92 ; 158.63,148.3 J21.60 ; J21.60 160.06,149.74 ; J21.60 160.06,148.3 ; J21.60 158.63,149.74 ; 184.18,24.26 J37.29 ; J37.29 185.7,22.73 ; J37.29 184.18,22.73 ; J37.29 185.7,24.26 ; 158.63,147.74 J21.59 ; J21.59 160.06,147.74 ; J21.59 160.06,146.3 ; J21.59 158.63,146.3 ; 140.84,21.5 U18.M1 ; U18.M1 140.84,19.2 ; U18.M1 143.14,21.5 ; U18.M1 143.14,19.2 ; 79.46,150.67 TP8.1 ; TP8.1 81.07,150.67 ; TP8.1 81.07,149.05 ; TP8.1 79.46,149.05 ; J1.2 180.47,115.08 ; J1.2 177.51,115.08 ; J1.2 180.47,118.04 ; J1.2 177.51,118.04 ; J5.8 20.41,102.95 ; J5.8 18.97,101.52 ; J5.8 20.41,101.52 ; J5.8 18.97,102.95 ; 180.76,110.28 J1.3 ; J1.3 183.72,110.28 ; J1.3 183.72,113.24 ; J1.3 180.76,113.24 ; 38.97,15.28 J23.7 39.74,14.52 ; J2.2 187.28,113.62 ; J2.2 185.67,115.23 ; J2.2 187.28,115.23 ; J2.2 185.67,113.62 ; J12.12 49.28,145.21 ; J12.12 47.76,145.21 ; J12.12 47.76,146.73 ; J12.12 49.28,146.73 ; 177.72,12.93 TP1_1.1 ; TP1_1.1 177.72,15.07 ; TP1_1.1 176.65,14 ; TP1_1.1 178.79,14 ; 61.21,144.7 J12.13 ; J12.13 62.73,144.7 ; J12.13 62.73,143.18 ; J37.17 185.7,37.97 ; J37.17 185.7,39.5 ; J37.17 184.18,39.5 ; J37.17 184.18,37.97 ; 140.84,27 U18.M2 ; U18.M2 143.14,27 ; U18.M2 143.14,29.3 ; U18.M2 140.84,29.3 ; J10.13 41.01,144.7 ; J10.13 39.49,144.7 ; J10.13 41.01,143.18 ; 52.79,77.55 J4.5 ; J4.5 54.4,77.55 ; J4.5 54.4,79.16 ; J4.5 52.79,79.16 ; J24.MTG3 55.35,1.79 ; J24.MTG3 53.74,3.41 ; J24.MTG3 55.35,3.41 ; J24.MTG3 53.74,1.79 ; 138.63,146.3 J21.39 ; J21.39 140.06,147.74 ; J21.39 138.63,147.74 ; J21.39 140.06,146.3
  L9_SIG3 w0.508: J12.13 62.73,144.7 ; J12.13 61.21,144.7 ; J12.13 62.73,143.18 ; 64.02,29.27 J22.B18 ; J22.B18 65.24,29.27 ; J22.B18 64.02,28.05 ; J22.B18 65.24,28.05 ; J12.1 61.68,133.23 ; J12.1 61.68,131.79 ; J12.1 60.24,133.23 ; J12.1 60.24,131.79 ; J22.B4 49.24,28.05 ; J22.B4 48.02,29.27 ; J22.B4 49.24,29.27 ; J22.B4 48.02,28.05 ; 47.76,146.73 J12.12 ; J12.12 49.28,146.73 ; J12.12 47.76,145.21 ; J12.12 49.28,145.21 ; J22.B13 60.24,30.05 ; J22.B13 59.02,30.05 ; J22.B13 60.24,31.27 ; J24.MTG4 71.05,1.79 ; J24.MTG4 69.44,1.79 ; J24.MTG4 71.05,3.41 ; J24.MTG4 69.44,3.41 ; J22.B17 64.24,31.27 ; J22.B17 64.24,30.05 ; J22.B17 63.02,30.05 ; J22.B17 63.02,31.27 ; J10.12 27.57,145.21 ; J10.12 26.04,146.73 ; J10.12 27.57,146.73 ; J10.12 26.04,145.21 ; 54.34,6.69 J24.MTG1 ; J24.MTG1 55.95,6.69 ; J24.MTG1 54.34,8.31 ; J24.MTG1 55.95,8.31 ; 18.97,52.63 J8.8 ; J8.8 18.97,54.06 ; J8.8 20.41,52.63 ; J8.8 20.41,54.06 ; J24.MTG2 70.45,8.31 ; J24.MTG2 68.84,6.69 ; J24.MTG2 70.45,6.69 ; J24.MTG2 68.84,8.31 ; 53.74,3.41 J24.MTG3 ; J24.MTG3 55.35,3.41 ; J24.MTG3 55.35,1.79 ; J24.MTG3 53.74,1.79 ; 39.74,14.52 J23.7 38.97,15.28 ; 52.66,69.55 J7.5 ; J7.5 54.27,71.16 ; J7.5 52.66,71.16 ; J7.5 54.27,69.55 ; 159.51,4.82 J39.3 157.99,4.82 ; 64.02,34.55 J22.A18 ; J22.A18 65.24,35.77 ; J22.A18 64.02,35.77 ; J22.A18 65.24,34.55 ; TP10.1 76.03,3.47 ; TP10.1 74.42,3.47 ; TP10.1 74.42,1.86 ; TP10.1 76.03,1.86 ; J22.B16 63.24,29.27 ; J22.B16 62.02,28.05 ; J22.B16 63.24,28.05 ; J22.B16 62.02,29.27 ; 140.84,29.3 U18.M2 ; U18.M2 143.14,29.3 ; U18.M2 140.84,27 ; U18.M2 143.14,27 ; U18.M1 143.14,21.5 ; U18.M1 143.14,19.2 ; U18.M1 140.84,21.5 ; U18.M1 140.84,19.2 ; 18.97,78.82 J6.8 ; J6.8 18.97,77.39 ; J6.8 20.41,77.39 ; J6.8 20.41,78.82 ; J46.1 169.33,12.32 ; J46.1 167.72,10.71 ; J46.1 169.33,10.71 ; J46.1 167.72,12.32 ; J23.4 43.83,13.19 ; J23.4 42.65,13.19 ; J23.4 42.65,14.37 ; 177.72,12.93 TP1_1.1 ; TP1_1.1 176.65,14 ; TP1_1.1 177.72,15.07 ; 52.79,77.55 J4.5 ; J4.5 54.4,77.55 ; J4.5 54.4,79.16 ; J4.5 52.79,79.16 ; J5.8 20.41,102.95 ; J5.8 18.97,102.95 ; J5.8 20.41,101.52 ; J5.8 18.97,101.52 ; 1.86,14.9 TP11.1 ; TP11.1 3.47,13.29 ; TP11.1 3.47,14.9 ; TP11.1 1.86,13.29 ; 51.02,30.05 J22.B7 ; J22.B7 52.24,30.05 ; J22.B7 52.24,31.27 ; J22.B7 51.02,31.27 ; J10.13 41.01,144.7 ; J10.13 41.01,143.18 ; J10.13 39.49,144.7 ; J22.A12 59.24,35.77 ; J22.A12 58.02,34.55 ; J22.A12 58.02,35.77 ; J22.A12 59.24,34.55 ; 38.53,133.23 J10.1 ; J10.1 39.96,131.79 ; J10.1 38.53,131.79 ; J10.1 39.96,133.23 ; J22.A4 49.24,34.55 ; J22.A4 48.02,34.55 ; J22.A4 48.02,35.77 ; J22.A4 49.24,35.77 ; 61.02,33.77 J22.A15 ; J22.A15 62.24,32.55 ; J22.A15 62.24,33.77 ; J22.A15 61.02,32.55
  L10_SIG4 w0.254: v6(106.63,80.57) 106.61,80.46 106.43,80.35 106.41,80.29 v11(106.3,80.22) ; v11(110.23,88.02) v6(109.83,88.26) ; v6(113.83,82.66) 114.19,82.66 v11(114.3,82.55) ; v11(99.8,81.39) 99.8,80.93 v6(99.44,80.57) ; v11(107.03,80.82) v6(107.43,80.57) ; v11(100.63,75.45) 100.64,75.45 100.65,75.47 100.76,75.47 v6(101.02,75.72) ; v11(100.84,81.44) 100.56,81.16 100.56,80.89 v6(100.24,80.57) ; v11(103.83,77.62) v6(104.23,77.37) ; v11(107.83,84.02) v6(107.43,84.26) ; v6(96.24,80.57) 96.35,80.54 96.47,80.61 v11(96.65,80.8) ; v11(111.03,83.22) v6(110.63,83.46) ; v11(99.04,79.22) v6(98.64,78.97) ; v11(95.85,87.08) v6(96.24,87.46) ; v11(100.64,84.82) v6(100.24,85.06) ; v6(104.23,80.57) 104.23,80.97 v11(104.5,81.23) ; v11(99.84,82.42) v6(99.44,82.66) ; v11(99.84,76.32) 100.05,76.32 v6(100.26,76.52) ; v11(101.9,81.51) 101.9,81.43 v6(101.04,80.57) ; v11(101.99,77.78) 102.32,77.45 v11(102.34,77.45) ; v6(93.84,85.93) 93.84,85.86 93.83,85.86 v11(93.83,85.35) ; v11(100.64,84.02) v6(100.24,84.26) ; v11(97.71,81.16) 97.84,81.04 v6(97.84,80.57) ; v11(100.64,85.62) v6(100.24,85.86) ; v6(105.83,83.46) 105.51,83.26 v11(105.46,83.06) ; v11(99.84,79.22) v6(99.44,78.97) ; v6(101.85,75.77) 101.6,75.52 v11(101.45,75.52) ; v11(95.04,76.32) v6(95.44,76.57) ; v11(111.83,77.62) v6(111.43,77.37) ; v11(93.43,86.41) 93.26,86.23 v6(93.26,85.97) ; v11(96.64,85.62) v6(96.24,85.86) ; v11(100.64,82.42) v6(100.24,82.66) ; v11(98.86,81.39) 98.64,81.17 v6(98.64,80.57) ; v11(111.83,83.22) v6(111.43,83.46) ; v11(109.43,88.02) v6(109.03,88.26) ; v6(110.63,77.37) 110.63,77.33 v11(111,76.97) ; v11(107.88,84.62) v6(108.23,84.26) ; v11(101.96,82.58) v11(101.96,82.19) ; v11(105.43,82.42) v6(105.83,82.66)
  L10_SIG4 w0.381: v9(36.93,100.44) v6(36.93,99.7) ; v9(87.4,81.66) v6(88.14,81.66) ; v9(86.74,67.69) v6(86.16,67.69) ; v9(103.63,110.19) v9(103.63,111.08)
  L10_SIG4 w0.508: 186.72,24.26 J37.30 ; J37.30 186.72,22.73 ; J37.30 188.24,22.73 ; J37.30 188.24,24.26 ; 177.51,115.08 J1.2 ; J1.2 180.47,115.08 ; J1.2 177.51,118.04 ; J1.2 180.47,118.04 ; 18.97,77.39 J6.8 ; J6.8 20.41,78.82 ; J6.8 20.41,77.39 ; J6.8 18.97,78.82 ; TP9.1 188.66,119.8 ; TP9.1 187.05,119.8 ; TP9.1 188.66,121.41 ; TP9.1 187.05,121.41 ; 184.18,37.97 J37.17 ; J37.17 185.7,39.5 ; J37.17 184.18,39.5 ; J37.17 185.7,37.97 ; 51.02,30.05 J22.B7 ; J22.B7 52.24,31.27 ; J22.B7 52.24,30.05 ; J22.B7 51.02,31.27 ; J10.13 41.01,144.7 ; J10.13 39.49,144.7 ; J10.13 41.01,143.18 ; J22.A15 62.24,32.55 ; J22.A15 61.02,33.77 ; J22.A15 62.24,33.77 ; J22.A15 61.02,32.55 ; 48.02,29.27 J22.B4 ; J22.B4 49.24,29.27 ; J22.B4 49.24,28.05 ; J22.B4 48.02,28.05 ; J10.1 39.96,133.23 ; J10.1 38.53,133.23 ; J10.1 38.53,131.79 ; J10.1 39.96,131.79 ; J44.2 84.37,110.23 ; J44.2 82.76,110.23 ; J44.2 84.37,108.62 ; J10.12 27.57,146.73 ; J10.12 26.04,145.21 ; J10.12 27.57,145.21 ; J10.12 26.04,146.73 ; 58.02,35.77 J22.A12 ; J22.A12 59.24,34.55 ; J22.A12 58.02,34.55 ; J22.A12 59.24,35.77 ; TP1_1.1 177.72,15.07 ; TP1_1.1 177.72,12.93 ; TP1_1.1 178.79,14 ; 69.44,3.41 J24.MTG4 ; J24.MTG4 71.05,1.79 ; J24.MTG4 71.05,3.41 ; J24.MTG4 69.44,1.79 ; 1.86,14.9 TP11.1 ; TP11.1 3.47,13.29 ; TP11.1 1.86,13.29 ; TP11.1 3.47,14.9 ; J22.A4 49.24,34.55 ; J22.A4 48.02,34.55 ; J22.A4 48.02,35.77 ; J22.A4 49.24,35.77 ; 62.02,29.27 J22.B16 ; J22.B16 62.02,28.05 ; J22.B16 63.24,29.27 ; J22.B16 63.24,28.05 ; 60.24,131.79 J12.1 ; J12.1 60.24,133.23 ; J12.1 61.68,133.23 ; J12.1 61.68,131.79 ; J22.B13 60.24,30.05 ; J22.B13 60.24,31.27 ; J22.B13 59.02,30.05 ; 180.76,113.24 J1.3 ; J1.3 180.76,110.28 ; J1.3 183.72,113.24 ; J1.3 183.72,110.28 ; J12.12 49.28,145.21 ; J12.12 47.76,145.21 ; J12.12 49.28,146.73 ; J12.12 47.76,146.73 ; 64.02,34.55 J22.A18 ; J22.A18 65.24,35.77 ; J22.A18 64.02,35.77 ; J22.A18 65.24,34.55 ; 20.41,127.08 19.69,126.36 18.97,127.08 ; J22.B18 65.24,29.27 ; J22.B18 64.02,28.05 ; J22.B18 65.24,28.05 ; J22.B18 64.02,29.27 ; 180.07,4.33 J1_1.1 ; J1_1.1 181.59,4.33 ; J1_1.1 180.07,2.81 ; J1_1.1 181.59,2.81 ; J12.13 62.73,143.18 ; J12.13 62.73,144.7 ; J12.13 61.21,144.7 ; 70.45,6.69 J24.MTG2 68.84,6.69 ; 74.42,1.86 TP10.1 ; TP10.1 76.03,3.47 ; TP10.1 74.42,3.47 ; TP10.1 76.03,1.86 ; 184.18,24.26 J37.29 ; J37.29 184.18,22.73 ; J37.29 185.7,22.73 ; J37.29 185.7,24.26 ; 167.72,12.32 J46.1 ; J46.1 169.33,10.71 ; J46.1 167.72,10.71 ; J46.1 169.33,12.32 ; 18.97,54.06 J8.8 18.97,52.63 ; J2.2 187.28,115.23 ; J2.2 187.28,113.62 ; J2.2 185.67,115.23 ; J2.2 185.67,113.62 ; 54.34,6.69 J24.MTG1 ; J24.MTG1 54.34,8.31 ; J24.MTG1 55.95,6.69 ; J22.B17 64.24,30.05 ; J22.B17 63.02,30.05 ; J22.B17 63.02,31.27 ; J22.B17 64.24,31.27 ; 53.74,1.79 J24.MTG3 ; J24.MTG3 55.35,3.41 ; J24.MTG3 53.74,3.41 ; J24.MTG3 55.35,1.79 ; 157.99,4.82 J39.3 ; J39.3 159.51,4.82 ; J39.3 157.99,3.3 ; J39.3 159.51,3.3
  L11_GND4 w0.508: 69.44,3.41 J24.MTG4 ; J24.MTG4 71.05,1.79 ; J24.MTG4 71.05,3.41 ; J24.MTG4 69.44,1.79 ; J1.3 183.72,113.24 ; J1.3 180.76,110.28 ; J1.3 180.76,113.24 ; J1.3 183.72,110.28 ; 51.02,30.05 J22.B7 ; J22.B7 51.02,31.27 ; J22.B7 52.24,30.05 ; J22.B7 52.24,31.27 ; 18.97,77.39 J6.8 ; J6.8 18.97,78.82 ; J6.8 20.41,77.39 ; J6.8 20.41,78.82 ; 186.72,22.73 J37.30 ; J37.30 186.72,24.26 ; J37.30 188.24,22.73 ; J37.30 188.24,24.26 ; J10.13 41.01,143.18 ; J10.13 41.01,144.7 ; J10.13 39.49,144.7 ; 180.07,4.33 J1_1.1 ; J1_1.1 180.07,2.81 ; J1_1.1 181.59,2.81 ; J1_1.1 181.59,4.33 ; J9.11 172.54,136.31 ; J9.11 172.54,137.92 ; J9.11 170.92,136.31 ; J9.11 170.92,137.92 ; J39.3 159.51,3.3 ; J39.3 157.99,3.3 ; J39.3 159.51,4.82 ; J39.3 157.99,4.82 ; 79.46,150.67 TP8.1 ; TP8.1 79.46,149.05 ; TP8.1 81.07,150.67 ; TP8.1 81.07,149.05 ; 48.02,29.27 J22.B4 ; J22.B4 49.24,28.05 ; J22.B4 48.02,28.05 ; J22.B4 49.24,29.27 ; 1.86,13.29 TP11.1 ; TP11.1 3.47,13.29 ; TP11.1 3.47,14.9 ; TP11.1 1.86,14.9 ; J10.12 27.57,145.21 ; J10.12 26.04,145.21 ; J10.12 27.57,146.73 ; J10.12 26.04,146.73 ; 47.76,145.21 J12.12 ; J12.12 49.28,145.21 ; J12.12 49.28,146.73 ; J12.12 47.76,146.73 ; SCKT1.MCH2 116.1,68.13 ; SCKT1.MCH2 114.1,68.13 ; SCKT1.MCH2 116.1,70.13 ; SCKT1.MCH2 114.1,70.13 ; 183.62,136.31 J9.21 ; J9.21 185.24,136.31 ; J9.21 183.62,137.92 ; J9.21 185.24,137.92 ; 82.76,108.62 J44.2 ; J44.2 84.37,110.23 ; J44.2 84.37,108.62 ; J44.2 82.76,110.23 ; J10.1 39.96,131.79 ; J10.1 39.96,133.23 ; J10.1 38.53,133.23 ; J10.1 38.53,131.79 ; J22.B16 63.24,29.27 ; J22.B16 62.02,28.05 ; J22.B16 63.24,28.05 ; J22.B16 62.02,29.27 ; 120.63,149.74 J21.22 ; J21.22 120.63,148.3 ; J21.22 122.06,148.3 ; J21.22 122.06,149.74 ; J37.17 185.7,37.97 ; J37.17 185.7,39.5 ; J37.17 184.18,39.5 ; J37.17 184.18,37.97 ; J22.A18 65.24,34.55 ; J22.A18 65.24,35.77 ; J22.A18 64.02,35.77 ; J22.A18 64.02,34.55 ; SCKT1.MCH4 90.37,95.86 ; SCKT1.MCH4 88.37,95.86 ; SCKT1.MCH4 88.37,93.85 ; SCKT1.MCH4 90.37,93.85 ; J7.5 54.27,71.16 ; J7.5 52.66,71.16 ; J7.5 54.27,69.55 ; J7.5 52.66,69.55 ; J21.60 160.06,148.3 ; J21.60 160.06,149.74 ; J21.60 158.63,148.3 ; J21.60 158.63,149.74 ; J24.MTG2 70.45,8.31 ; J24.MTG2 68.84,8.31 ; J24.MTG2 70.45,6.69 ; J24.MTG2 68.84,6.69 ; 18.97,102.95 J5.8 ; J5.8 18.97,101.52 ; J5.8 20.41,102.95 ; J5.8 20.41,101.52 ; J21.40 140.06,149.74 ; J21.40 138.63,149.74 ; J21.40 138.63,148.3 ; J21.40 140.06,148.3 ; 58.02,34.55 J22.A12 ; J22.A12 58.02,35.77 ; J22.A12 59.24,34.55 ; J22.A12 59.24,35.77 ; J22.B17 64.24,31.27 ; J22.B17 63.02,30.05 ; J22.B17 63.02,31.27 ; J22.B17 64.24,30.05 ; J12.1 61.68,131.79 ; J12.1 61.68,133.23 ; J12.1 60.24,133.23 ; J12.1 60.24,131.79 ; TP10.1 76.03,1.86 ; TP10.1 74.42,1.86 ; TP10.1 74.42,3.47 ; TP10.1 76.03,3.47 ; J22.A15 62.24,33.77 ; J22.A15 61.02,32.55 ; J22.A15 62.24,32.55 ; J22.A15 61.02,33.77 ; 138.63,146.3 J21.39 ; J21.39 138.63,147.74 ; J21.39 140.06,146.3 ; J21.39 140.06,147.74 ; 42.65,14.37 J23.4 ; J23.4 43.83,13.19 ; J23.4 42.65,13.19 ; J2.2 187.28,113.62 ; J2.2 185.67,113.62 ; J2.2 185.67,115.23 ; J2.2 187.28,115.23 ; 54.34,8.31 J24.MTG1 ; J24.MTG1 55.95,6.69 ; J24.MTG1 54.34,6.69 ; J24.MTG1 55.95,8.31 ; 19.69,126.36 20.41,125.65 ; 19.69,126.36 18.97,127.08 ; 19.69,126.36 18.97,125.65 ; 19.69,126.36 20.41,127.08 ; 177.51,115.08 J1.2 ; J1.2 177.51,118.04 ; J1.2 180.47,115.08 ; J1.2 180.47,118.04 ; 170.92,140.46 J9.12 ; J9.12 170.92,138.85 ; J9.12 172.54,140.46 ; J9.12 172.54,138.85 ; 48.02,34.55 J22.A4 ; J22.A4 49.24,34.55 ; J22.A4 48.02,35.77 ; J22.A4 49.24,35.77 ; 52.79,77.55 J4.5 ; J4.5 54.4,79.16 ; J4.5 54.4,77.55 ; J4.5 52.79,79.16 ; 158.63,146.3 J21.59 ; J21.59 158.63,147.74 ; J21.59 160.06,147.74 ; J21.59 160.06,146.3 ; TP9.1 188.66,121.41 ; TP9.1 187.05,121.41 ; TP9.1 188.66,119.8 ; TP9.1 187.05,119.8 ; J22.B13 60.24,30.05 ; J22.B13 60.24,31.27 ; J22.B13 59.02,30.05 ; U18.M1 143.14,21.5 ; U18.M1 143.14,19.2 ; U18.M1 140.84,21.5 ; U18.M1 140.84,19.2 ; J8.8 20.41,54.06 ; J8.8 18.97,52.63 ; J8.8 20.41,52.63 ; J8.8 18.97,54.06 ; J22.B18 65.24,28.05 ; J22.B18 64.02,28.05 ; J22.B18 64.02,29.27 ; J22.B18 65.24,29.27 ; J12.13 62.73,144.7 ; J12.13 61.21,144.7 ; J12.13 62.73,143.18 ; U18.M2 143.14,27 ; U18.M2 140.84,27 ; U18.M2 143.14,29.3 ; U18.M2 140.84,29.3 ; J37.29 185.7,24.26 ; J37.29 184.18,24.26 ; J37.29 185.7,22.73 ; J37.29 184.18,22.73 ; 177.72,12.93 TP1_1.1 ; TP1_1.1 178.79,14 ; TP1_1.1 176.65,14 ; TP1_1.1 177.72,15.07 ; J46.1 169.33,10.71 ; J46.1 167.72,12.32 ; J46.1 167.72,10.71 ; J46.1 169.33,12.32 ; 53.74,3.41 J24.MTG3 ; J24.MTG3 55.35,3.41 ; J24.MTG3 53.74,1.79 ; J24.MTG3 55.35,1.79 ; 39.74,14.52 J23.7 38.97,15.28
  BOTTOM w0.083: 98.13,129.7 U43.N2 98.63,129.7 98.63,130.19 v1(98.38,130.44) 98.13,130.19 98.13,129.7
  BOTTOM w0.102: U62.D3 U62.E4
  BOTTOM w0.203: U62.C2 U62.C3 U62.D3 ; U62.B4 v7(154.97,104.89) ; U75.5 170.44,65.96 170.15,66.25 v7(169.77,66.25) ; v7(156.64,105) 156.64,105.07 U62.E4
  BOTTOM w0.254: U89.D5 v1(151.15,95.32) U89.E5 ; U91.M1 v1(143.64,67.04) ; U89.G6 v1(149.85,95.97) 150.17,96.29 U89.F6 ; J16.19 v7(83.18,122.9) ; C388.2 104.09,80.83 v11(104.5,81.23) ; v1(148.68,95.64) U89.J5 U89.J4 ; C327.2 C267.2 ; U90.T1 v1(146.84,51.8) ; U91.M9 v1(143.64,59.62) ; U89.A10 153.8,98.89 v1(154.31,99.4) ; U91.G8 v1(139.28,61.29) ; U89.E6 v1(151.15,95.97) 151.47,96.29 U89.D6 ; v1(93.85,127.97) 93.85,127.98 U43.C4 ; C566.2 98.42,78.33 99.04,78.94 v11(99.04,79.22) ; v11(102.34,77.45) 101.85,76.97 C339.2 ; U91.J8 v1(140.88,60.57) ; U45.14 28.84,34.38 v1(29.59,35.13) ; U91.T9 v1(146.84,59.62) ; U91.T1 v1(146.84,67.04) ; U92.4 157.64,57.99 157.43,58.2 157.43,58.42 156.97,58.88 156.85,58.88 C537.2 ; U89.G5 149.52,95.64 v1(149.85,95.32) U89.F5 ; U90.G8 v1(139.28,46.05) ; U89.B7 v1(152.31,96.94) ; U89.F4 v1(149.85,94.67) 149.52,94.99 U89.G4 ; U90.G1 v1(139.28,50.93) ; v11(107.03,80.82) 106.46,80.82 C338.2 106.3,80.65 v11(106.3,80.22) ; U90.P9 v1(145.24,44.38) ; U90.M9 v1(143.64,44.38) ; U89.J8 v1(148.84,97.59) 148.87,97.62 U89.H9 ; J16.7 v7(83.18,116.9) ; U91.P1 v1(145.24,67.04) ; U90.F9 v1(138.48,45.25) ; U89.F7 150.17,96.94 v1(149.85,96.62) U89.G7 ; v1(96.38,126.94) 96.39,126.94 U43.K8 ; U32.8 v1(74.04,144.61) ; U91.B1 v1(135.64,67.04) ; U43.N5 U43.P6 v1(99.42,126.92) v1(99.42,126.16) ; v1(159.89,57.49) U92.8 ; U90.E1 v1(137.68,50.93) ; U89.A1 v1(153.88,93.04) ; U89.K10 v1(147.57,99.35) ; C394.2 96.49,81.92 96.49,81.97 96.57,82.05 96.66,82.05 96.68,82.07 v11(96.72,82.07) ; U72.28 v7(177.66,64.22) ; U90.B9 v1(135.28,45.25) ; v1(99.44,128.63) 99.26,128.45 U43.P4 ; U43.H10 95.39,125.94 v1(95.38,125.94) ; U91.B9 v1(135.28,60.49) ; v7(54.74,89.87) 54.37,89.51 J17.6 ; v1(74.91,145.09) 74.54,145.46 U32.4 ; U89.E7 v1(151.15,96.62) 151.47,96.94 U89.D7 ; v7(85.6,121.62) 85.47,121.62 85.26,121.4 J16.16 ; U43.G5 v1(95.38,127.46) ; U91.A9 v1(134.84,59.62) ; U62.C2 U62.C1 v7(155.37,107.8) v7(155.37,108.44) ; U91.E2 v1(137.68,65.37) ; U90.B1 v1(135.64,51.8) ; U90.B3 v1(135.28,49.33) ; U89.D4 v1(151.15,94.67) U89.E4 ; U90.D8 v1(136.88,46.05) ; U90.M1 v1(143.64,51.8) ; U91.P9 v1(145.24,59.62) ; U89.E9 v1(150.82,97.62) ; U90.T9 v1(146.84,44.38) ; U43.E7 v1(94.87,126.95) ; U90.J2 v1(140.88,50.85) ; v7(81.91,119.9) J16.13 ; U90.D1 v1(137.24,51.8) ; J16.22 v7(83.18,124.4) ; U91.G9 v1(139.64,59.62) ; U91.G1 v1(139.28,66.17) ; v7(82.93,118.4) J16.10 ; U90.E2 v1(137.68,50.13) ; U90.E8 v1(137.68,46.05) ; U91.F9 v1(138.48,60.49) ; U91.B3 v1(135.28,64.57) ; U90.G9 v1(139.64,44.38) ; U91.D8 v1(136.88,61.29) ; U90.J8 v1(140.88,45.33) ; U91.E8 v1(137.68,61.29) ; U90.A9 v1(134.84,44.38) ; U91.E1 v1(137.68,66.17) ; U91.D1 v1(137.24,67.04) ; U90.P1 v1(145.24,51.8) ; U91.J2 v1(140.88,66.09) ; U89.H2 v1(148.87,94.15)
  BOTTOM w0.305: U30.5 90.8,149.53 v7(90.8,149.53)
  BOTTOM w0.381: v1(83.18,37.48) 82.56,37.48 82.04,36.96 C31.2 ; v11(92.8,82.14) 92.92,82.02 93.27,82.02 93.6,81.69 C447.2 ; v7(62.71,119.24) 62.67,119.24 62.67,119.27 62.74,119.27 62.74,120.22 C185.2 ; C449.2 173.5,5.21 v7(173.38,5.34) ; R934.2 139.85,122.48 v1(139.85,123.13) ; v7(25.73,64.01) 25.4,63.68 C145.2 ; v11(119.38,76.03) v11(118.87,76.03) C292.2 ; v7(185.19,89.49) 186.01,89.49 C223.2 ; U78.3 186.45,92.83 186.08,92.46 v7(185.39,92.46) ; v7(76.96,149.82) 75.95,149.82 ; 75.95,149.82 75.82,149.7 R414.1 ; 75.95,149.82 v7(75.95,150.84) ; 90.8,81.53 90.8,81.87 v11(91.06,82.12) 90.83,82.35 C298.2 ; J45.5 4.81,42.4 v7(5.18,42.78) ; R570.2 v9(144.69,130.76) ; v1(97.45,29.08) 97.32,29.21 C57.2 ; v11(113.33,78.94) 113.3,78.94 113.3,78.94 112.79,78.94 C364.2 ; C204.2 v7(175.41,41.15) ; U48.2 v7(171.66,53.55) ; C55.2 105.08,25.78 v1(104.98,25.88) ; C253.2 v7(172.21,24.21) ; R468.1 R466.1 ; R466.1 R455.1 R458.1 ; R466.1 v9(105.66,110.19) ; C58.2 100.46,32.38 100.24,32.16 99.97,32.16 99.69,31.88 v1(99.22,31.88) ; R515.1 v7(14.91,16.21) ; C331.2 96.11,86.14 v11(96.64,85.62) ; C166.1 v7(22.48,140.16) ; v7(60.18,101.94) 60.2,101.93 C194.1 ; C441.2 68.96,62.44 68.58,62.05 v7(68.58,61.12) ; C441.2 v7(70.1,58.33) ; C441.2 v7(70.1,65.11) ; C327.2 98.17,88.04 v11(97.9,88.31) ; v11(101.73,66.27) v11(101.73,66.76) C296.2 ; U95.8 v1(39.75,20.12) ; 112.01,32.89 112.28,32.89 v1(112.86,33.48) ; R417.1 77.09,141.81 77.72,141.18 v7(77.72,140.52) ; C191.2 v7(53.5,94.95) ; C37.2 90,29.34 v1(89.74,29.08) ; U68.3 41.77,88.33 v7(41.15,87.71) ; v1(140.64,130.33) 140.64,130.94 C399.2 ; C65.2 106.05,31.88 106.76,32.59 v7(106.76,32.72) ; C551.2 v11(106.93,68.99) ; C533.2 v7(158.37,61.93) ; U73.9 v7(172.59,33.48) ; v1(120.27,25.88) 120.37,25.78 C70.2 ; C113.2 v7(42.04,92.79) ; v9(91.62,74.17) 91.95,73.84 C573.2 ; v9(183.16,93.43) 183.03,93.43 182.78,93.68 R587.2 ; v9(146.56,131.53) 146.3,131.27 C281.2 v9(147.32,130.47) ; v9(61.85,114.64) C180.2 v9(60.71,115.67) ; C294.2 102.31,75.52 v11(101.45,75.52) ; U19.3 v7(185.45,84.73) ; v7(175.41,56.39) C198.2 ; R256.1 v9(14.91,5.92) ; v9(92.79,72.27) 93.01,72.5 C7.2 ; v11(103.98,76.96) 104.63,76.96 C335.2 ; v7(175.41,58.93) C197.2 ; v9(33.02,112.22) 33.69,112.22 34.05,112.59 C168.2 34.05,113.11 33.69,113.48 v9(33.02,113.48) ; v9(109.6,80.85) 109.22,80.85 108.84,81.23 L24.2 108.84,82.38 109.35,82.89 v9(109.86,82.89) ; v9(106.81,114.64) R456.1 R457.1 R454.1 ; v7(55.23,102.33) U25.10 ; Q15.S 12.34,18.17 v7(12.37,18.14) ; 81.53,34.92 81.97,34.92 v1(82.21,34.68) ; Q5.S 12.34,8.01 v7(12.37,7.98) ; U97.3 v7(166.24,49.39) ; C448.2 v7(170.94,68.15) ; v7(20.08,34.86) 20.08,35.51 C306.2 21.1,35.51 v7(21.1,34.86) ; C309.2 v7(27.43,30.31) ; C160.2 32.64,118.45 v1(33.02,118.83) ; 9.02,16.08 v7(8.31,16.08) ; v7(27.88,121.82) 28.46,121.24 C155.2 ; v7(21.97,28.66) 21.97,29.31 C305.2 21.46,29.82 20.95,29.31 v7(20.95,28.66) ; v7(25.53,51.77) 25.53,52.42 C149.2 ; C203.2 v7(175.41,43.69) ; 96.77,34.92 97.46,34.92 v1(97.61,35.08) ; Q1.S 12.34,4.7 v7(12.37,4.68) ; C265.2 v7(92.33,136.35) ; C322.2 v7(35.51,38.82) ; C505.2 v7(137.54,56.22) ; v7(156.46,54.82) 156.84,55.2 C542.2 ; U23.5 41.29,101.47 v7(41.15,101.61) ; R597.1 v7(14.91,12.91) ; C548.2 v9(121.54,81.74) ; C391.2 93.22,85.93 93.43,86.15 93.43,86.41 v11(93.43,86.41) ; R453.1 R459.1 R458.1 ; R453.1 v9(101.6,110.19) ; R453.1 101.6,109.3 101.23,109.3 100.71,108.78 v9(100.71,108.44) ; C504.2 v7(140.97,56.98) ; v7(78.74,110.7) 78.72,110.71 C222.2 77.47,110.57 v7(78.49,109.56) ; v7(31.5,43.64) C320.2 v7(32.66,42.48) ; v7(12.37,11.28) 12.34,11.31 Q3.S ; C360.2 112.8,80.01 113.31,80.01 113.31,80.02 v11(113.33,80.02) ; v9(55.37,111.59) 55.37,112.19 55.77,112.59 C189.2 55.77,113.11 55.4,113.48 v9(54.74,113.48) ; C361.2 83.57,93.32 v11(83.57,92.41) ; C361.2 83.33,93.79 83.06,94.06 v11(82.3,94.06) ; C361.2 83.33,93.32 83.06,93.05 v11(82.3,93.05) ; v7(18.05,22.43) Q14.S ; U33.2 v7(10.67,25.32) ; v7(44.58,5.64) C311.2 v7(42.93,3.99) ; U66.1 v7(28.19,5.08) ; U33.3 v7(9.4,25.32) ; v1(120.27,29.21) 120.36,29.21 120.48,29.34 C75.2 ; C302.2 139.4,131.19 138.86,131.19 v9(138.81,131.15) ; v9(96.22,72.7) 96.53,73.01 C376.2 ; 9.02,2.62 v1(8.31,2.62) ; v11(114.3,82.55) L21.2 v11(111.46,82.55) ; 97.41,79.2 97.41,80.01 v11(97.43,80.04) ; v11(88.46,78.55) 88.33,78.55 87.88,78.99 ; v1(30.48,99.4) 30.23,99.14 C124.2 ; v9(34.29,111.46) 34.29,111.08 34.66,110.71 U22.3 ; v7(52.54,90.93) 52.58,90.98 52.58,91.42 J17.MNT2 52.1,92.57 v7(52.58,93.05) ; v7(42.16,126.19) 42.05,126.3 C161.2 v7(40.89,127.46) ; v7(137.71,134.67) 137.67,134.63 C402.2 ; C199.2 v7(175.41,53.85) ; U38.7 166.58,92.66 v7(166.07,92.16) ; v7(25.27,2.67) 24.38,2.67 ; v7(166.22,95.05) 166.37,95.2 U38.5 ; 9.02,12.78 v1(8.31,12.78) ; C140.2 25.68,59.77 25.76,59.85 v7(26.16,59.85) ; v1(104.82,34.28) 105.19,33.91 C68.2 ; v7(111.38,110.19) R464.1 R465.1 ; C443.2 v7(168.83,82.12) ; C190.2 v7(56.39,94.19) ; v7(18.97,11.28) 18.95,11.31 Q4.S ; C56.2 v7(95.76,32.64) ; v1(89.74,25.88) 89.84,25.78 C35.2 ; Q11.S 12.34,14.86 v7(12.37,14.84) ; v1(89.74,37.08) 90.13,37.46 C32.2 ; v1(97.45,25.88) 97.36,25.78 C51.2 ; C210.2 v7(163.07,38.56) ; C170.2 v9(36.93,100.44) ; 89.03,30.23 89.03,31.63 v1(88.78,31.88) ; C231.1 161.56,84.17 161.21,84.52 v7(161.21,84.59) ; v11(109.02,79.51) 108.76,79.25 C291.2 ; v7(60.58,126.37) 60.71,126.37 60.83,126.24 C183.2 ; v7(182.13,63.84) C205.2 v7(182.13,61.42) ; R458.1 v9(103.63,110.19) ; v9(17.53,114.51) R108.1 ; C329.2 97.94,80.7 97.79,80.85 97.79,81.08 v11(97.71,81.16) ; v7(68.72,136.61) C215.2 v7(67.67,137.75) ; C310.2 v7(31.5,30.31) ; C406.2 95.9,89.63 v11(95.78,89.51) ; v7(83.33,97.29) C483.2 v7(82.16,96.09) ; v1(88.78,38.28) 89.41,38.91 C34.2 ; C30.2 v7(84.71,39.75) ; C94.2 112.52,20.32 v7(112.41,20.21) ; U73.8 v7(172.59,38.18) ; v7(25.48,69.68) 25.51,69.71 U70.3 ; C133.2 25.84,87.15 v7(25.96,87.15) ; v7(25.4,125.68) C157.2 ; C157.2 v7(26.47,124.36) ; C157.2 v7(26.47,127.16) ; v7(74.93,116.29) 75.44,115.78 C472.2 ; C390.2 94.03,85.55 v11(93.83,85.35) ; v9(56.01,111.46) 56.01,111.08 56.37,110.71 U26.3 ; v7(26.12,102.43) 26.01,102.32 C116.2 ; C112.2 24.26,123.65 v9(24,123.91) ; v1(114.46,31.88) 114.74,32.16 115.48,32.16 115.7,32.38 C62.2 ; C562.2 v9(143.87,122.43) ; v7(159.96,73.34) 160.67,74.05 U35.3 ; U2.3 v7(166.23,40.86) ; v1(97.62,33.48) 97.6,33.48 97.14,33.02 96.9,33.02 96.77,32.89 ; v1(104.02,38.28) 104.65,38.91 C50.2 ; C173.1 46.51,105.32 v7(46.52,105.32) ; C444.2 v7(172.57,62.82) ; v1(120.06,34.28) 120.43,33.91 C73.2 ; C211.2 v7(99.08,148.45) ; R463.1 R462.1 v7(109.35,110.19) ; C392.2 141.53,124.03 v1(141.44,123.94) ; v11(93.12,83.13) 93.12,83.11 93.5,82.73 C297.2 ; v7(30.1,41.61) 29.72,41.23 L3.2 v7(27.05,41.23) ; C121.1 v7(10.01,118.06) ; v9(143.76,121.62) 142.88,121.62 R432.2 ; C251.2 v7(171.2,25.61) ; v6(88.14,81.66) v9(87.4,81.66) ; C220.2 v7(11.94,33.3) ; v11(159.63,84.87) 159.59,84.83 C241.2 157.93,84.83 157.91,84.82 v11(157.86,84.87) ; v11(95.04,76.32) 95.51,76.32 95.8,76.03 C351.2 ; U39.3 61.23,68.68 v7(61.72,69.17) ; v11(87.63,84.66) 88.01,85.04 L25.2 88.01,86.57 87.76,86.82 v11(87.38,86.82) ; C12.2 90.8,74.04 v9(90.93,74.17) ; R454.1 v9(108.84,114.64) ; R454.1 R461.1 R460.1 v9(110.87,114.64) v9(111.66,114.64) ; v1(84.78,37.48) 85.21,37.48 C41.2 ; Q2.S 18.62,4.7 v7(18.92,4.4) ; C8.2 92.91,74.22 v9(92.41,74.73) 92.41,74.88 C11.2 ; C230.1 v7(155.96,74.5) ; v7(73.56,116.29) 73.56,115.42 R680.1 ; C266.2 89.46,91.22 v11(89.41,91.27) ; v1(112.69,29.08) 112.01,29.08 C79.2 ; C207.2 v7(185.42,62.06) ; 162.94,40.26 v7(162.13,40.26) ; v1(88.78,33.48) 89.36,32.89 C36.2 ; v7(62.61,127.46) C182.2 61.84,127.07 v7(61.84,127.46) ; U34.3 v7(167.07,84.22) ; v11(85.47,84.43) L34.2 v11(85.47,81.94) ; v7(81.53,112.1) 81.37,112.25 J16.MNT1 80.4,110.94 v7(80.64,110.7) ; v1(104.82,37.48) 104.83,37.46 C48.2 ; U69.3 30.47,88.33 v7(30.23,88.09) ; C527.2 v7(150.11,69.68) ; C382.2 v9(136.4,131.4) ; v7(41.29,105.27) 41.29,105.28 U23.10 ; v7(48.94,120.6) 48.95,120.6 48.95,119.78 C154.2 49.78,119.46 v7(50.42,118.83) ; C146.1 v7(16.26,67.77) ; C17.2 102.23,71.17 v11(102.62,70.79) ; v7(12.37,21.44) 12.34,21.47 Q10.S ; C221.2 v7(182.52,99.4) ; v1(112.69,25.88) 112.66,25.91 C72.2 ; C103.2 v9(24.26,133.56) ; C404.2 v11(90.78,84.69) ; C202.2 v7(175.41,46.23) ; v9(91.31,87) 90.93,87 C446.2 ; U33.4 v7(8.13,25.32) ; 9.02,5.92 v1(8.31,5.92) ; C193.1 v7(60.2,97.22) ; R381.1 v7(179.45,74.63) ; R754.1 v7(143.89,39.96) ; v1(31.5,56.82) v1(30.48,56.82) ; v7(55.46,99.03) 55.23,98.79 U25.5 ; v7(18.97,7.98) 18.95,8.01 Q6.S ; C66.2 105.24,29.34 v1(104.98,29.08) ; C119.2 v7(25.4,106.63) ; v7(171.25,74.81) 170.23,75.82 C224.2 v7(171.74,76.09) ; C289.2 v11(116.71,73.23) v11(117.2,73.23) ; C572.2 v9(86.74,67.69) ; C131.1 v7(16.26,92.66) ; U95.3 v1(39.75,17.98) ; v7(165.21,54.31) C532.2 v7(165.21,56.6) ; C522.2 v7(140.97,72.22) ; U77.5 179.07,5.53 179.45,5.14 v7(179.7,5.14) ; v7(165.74,84.54) 165.74,84.92 165.18,85.48 C236.2 ; C49.2 96.9,37.08 97.14,37.08 97.53,37.48 v1(98.42,37.48) ; C106.1 v7(18.67,137.8) ; v11(98.23,84.01) 98.22,84 C401.2 ; C139.2 v7(28.58,74.12) ; Q12.S 18.95,18.17 v7(18.97,18.14) ; R592.1 v7(14.91,19.64) ; C74.2 112.39,36.96 112.91,37.48 v1(113.66,37.48) ; U63.8 170.9,87.37 v7(171.22,87.69) ; C38.2 89.78,33.91 v1(89.74,33.88) ; 9.02,9.35 v7(8.31,9.35) ; 87.88,78.99 L26.2 87.88,80.29 v9(88.43,80.84) ; 87.88,78.99 87.5,78.61 v11(87.07,78.61) ; C102.2 v9(24.26,134.7) ; C299.2 v11(87.4,84.08) ; C172.1 46.51,100.81 46.51,100.81 ; R104.1 v9(22.03,111.84) ; U73.16 v7(163.7,33.61) ; C107.2 v7(23.37,132.16) ; v7(18.97,14.84) 18.95,14.86 Q13.S ; 9.02,19.51 v7(8.31,19.51) ; C315.2 77.22,115.91 v7(77.6,116.29) ; C550.2 v11(104.9,70.39) ; C104.2 v7(16.64,121.37) ; U33.1 v7(11.94,25.32) ; R697.1 75.95,99.27 v7(75.77,99.27) ; v1(112.86,35.08) 112.71,34.92 112.01,34.92 ; v1(119.26,31.88) 119.26,31.88 C61.2 ; C228.1 v7(166.8,78.77) ; v7(44.83,143.76) 44.83,143.75 C187.1 ; C200.2 v7(175.41,51.31) ; v7(186.44,77.12) C206.2 v7(187.83,78.19) ; C219.2 v7(56.73,90.05) ; C319.2 v7(186.72,97.74) ; C530.2 v7(149.73,67.26) ; v7(175.13,79.68) C426.2 ; v7(176.91,23.45) 177.54,23.45 C208.2 178.1,24.11 v7(176.94,25.27) ; v1(120.06,37.48) 120.07,37.46 C76.2 ; v7(16.76,1.73) 15.97,1.73 15.62,2.08 R246.1 ; R467.1 v7(113.41,110.1) ; C164.2 v7(42.67,120.35) ; 164.21,40.26 v7(165.02,40.26) ; v9(80.14,74.68) L35.2 v9(80.14,77.47) ; R110.1 v9(19.87,112.98) ; C353.2 107.2,83.37 107.83,84 v11(107.83,84.02) ; C324.2 v7(35.51,39.83) ; R109.1 v9(18.73,112.98) ; C237.1 v7(162.23,77.04) ; v7(26.29,28.66) 26.29,29.31 25.78,29.82 C307.2 25.27,29.31 v7(25.27,28.66) ; C153.2 48.77,117.19 v7(48.9,117.05) ; C330.2 v11(90.93,90.38) ; C14.2 103.45,71.38 v11(103.45,70.87) ; C564.2 100.33,83.71 v11(100.64,84.02) 100.83,84.21 C380.2 ; X1.2 v7(173.99,149.57) ; C254.2 v7(171.2,16.97) ; C63.2 119.89,38.45 v1(120.06,38.28) ; R380.1 v7(176.53,74.63) ; C240.1 v7(160.87,78.02) ; C171.2 v7(39.36,108.41) ; C4.2 v7(169.55,43.91) ; C69.2 v7(99.95,40) ; C3.2 v7(167.51,47.45) ; 81.53,32.89 82.03,32.89 v1(82.21,33.08) ; v7(52.1,83.7) J17.MNT1 v7(53.25,84.62) ; C569.2 161.78,51.7 v7(161.04,51.7) ; C400.2 v11(95.71,85.48) ; v11(102.87,66.27) v11(102.87,66.76) C295.2 ; C318.2 v9(140.97,133.61) ; v9(40.13,114.64) C159.2 v9(38.99,115.67) ; R111.1 v9(21.02,112.98) ; C167.1 v7(44.32,134.07) ; v11(108.56,84.64) 108.26,84.93 108.26,85.11 C356.2 108.03,85.45 ; C71.2 115.26,38.92 v1(115.26,37.48) ; C162.2 v7(39.12,126.45) ; C421.2 185.36,81.62 v7(185.36,80.35) ; 161.8,48.39 161.78,48.37 v7(161.78,47.62) ; C108.2 v9(25.17,114.08) ; v7(80.64,98.89) R695.1 ; R433.1 179.86,95.2 v7(179.6,94.95) ; U63.9 176.7,87.37 v7(177.09,87.76) ; v7(68.65,83.18) 68.99,83.52 R706.1 ; C328.2 91.95,89.79 v11(91.95,90.38) ; C209.2 v7(160.4,38.56) ; R252.1 v7(14.91,9.35) ; v7(180.47,73.87) R382.1 v7(181.47,74.89) ; C567.2 v9(80.01,79.25) ; C337.2 v11(106.32,76.99) ; C245.2 v7(170.39,94.32) ; C568.2 v9(80.01,78.23) ; C201.2 v7(175.41,48.77) ; C60.2 v7(111,32.77) ; U71.3 v7(24.52,45.87) ; C403.2 v11(87.43,82.78) ; U98.3 v7(164.91,44.89) ; R755.1 v7(143.89,55.2) ; C192.2 v7(61.07,108.41) ; C5.2 v7(164.55,53.55) ; v7(48.18,127.16) C178.2 48.18,124.49 v7(48.39,124.29) ; C355.2 v11(105.46,83.06) ; C234.1 v7(160.2,83.82) ; U73.10 v7(171.32,33.48) ; U49.2 v7(170.56,39.88) ; C248.2 v7(59.94,62.82) ; C371.2 v9(107.04,75.37) ; U73.7 v7(171.32,38.18)
  BOTTOM w0.508: R700.1 72.16,99.78 v7(72.14,99.8) ; v9(151.13,125.05) C283.2 v9(150.2,126.07) ; C212.2 v7(95.89,144.27) ; C317.2 v9(149.08,121.98) ; C317.2 v9(149.08,119.74) ; C317.2 v9(150.22,120.86) ; J16.MNT2 v7(80.4,132.37) ; J16.MNT2 v7(79.08,131.05) ; J16.MNT2 v7(80.4,129.74) ; R228.1 28.19,51.72 v7(28.5,51.41) ; v7(67.82,99.4) 68.4,99.98 Q25.S ; v1(30.48,81.58) 30.26,81.36 C138.2 C134.2 ; R431.2 143.92,125.18 v9(143.94,125.19) ; v9(141.61,116.58) C285.2 v9(140.72,115.65) ; v7(26.16,94.39) C125.2 v7(24.97,95.6) ; C132.2 v7(25.4,86.31) ; C453.2 132.42,127.32 131.69,127.32 v9(131.65,127.36) ; v9(139.19,115.65) C452.2 v9(138.3,116.58) ; C96.2 v7(120.65,17.67) ; C96.2 v7(119.38,16.54) ; C96.2 v7(118.11,17.67) ; C95.2 124.62,17.92 v7(124.59,17.96) ; C95.2 125.98,16.61 v7(126.06,16.54) ; C95.2 127.22,17.92 v7(127.25,17.96) ; v7(25.27,76.79) 25.27,76.79 26.16,77.68 C136.2 v7(24.97,77.82) ; v7(67.82,141.69) 68.32,141.71 C218.2 68.34,140.42 v7(67.82,140.42) ; C127.2 v7(32.51,93.68) ; R785.1 v7(160.66,52.98) ; C151.2 27.43,50.37 v7(27.69,50.12) ; C122.2 v7(25.4,104.09) ; v9(143.76,121.62) 143.76,120.95 C274.2 144.61,120.1 v9(145.03,120.1) ; C150.2 C148.2 30.26,56.6 v1(30.48,56.82) ; v7(67.87,85.91) 67.91,85.95 Q24.S ; Q21.S 75.61,103.22 v7(75.62,103.23) ; v7(181.64,20.04) 181.66,20.07 FB12.2 ; v7(72.19,103.23) 72.18,103.22 Q22.S ; FB12.2 182.84,18.83 v7(182.85,18.82) ; FB12.2 182.84,21.2 v7(182.91,21.26) ; C544.2 v7(158.37,52.98) ; v9(135.53,117.81) C468.2 v9(134.49,118.95) ; Q20.S 79.45,102.21 v11(79.73,102.49) ; v9(135,120.48) 135.51,120.99 ; 135.51,120.99 135.13,121.37 v9(134.87,121.37) ; 135.51,120.99 C272.2 v9(135.93,120.1) ; C129.2 25.4,82.78 v7(25.27,82.66) ; C268.2 v9(135.38,114.64) ; C268.2 v9(134.1,115.73) ; C268.2 v9(136.66,115.73) ; v7(26.16,84.79) 25.91,84.54 C128.2 ; v9(131.34,128.12) 131.98,128.12 132.37,128.51 C284.2 132.25,128.9 131.11,128.9 v9(130.99,128.78) ; C417.2 v7(156.72,102.96) ; R16.2 v9(133.31,122.38) ; v9(150.2,122.38) C282.2 v9(151.13,123.27) ; C383.2 136.37,129.39 v9(135.89,129.88) ; J9.21 185.24,136.31 ; J9.21 183.62,136.31 ; J9.21 183.62,137.92 ; v7(70.61,147.53) 71.29,147.53 C217.2 71.03,148.54 v7(70.74,148.54) ; C98.2 v7(129.79,24) ; R704.1 v7(68.45,90.63) ; C216.2 v7(68.83,139.4) ; C141.2 v7(25.4,57.87) ; C188.1 66.04,142.4 v7(66.01,142.42) ; C531.2 v7(162.05,61.55) ; Q23.S v7(67.96,93.06) ; C126.2 C124.2 ; R709.1 68.96,97.74 v7(68.45,97.24) ; v9(143.64,117.94) 144.11,118.41 C275.2 v9(145.03,118.83) ; U41.4 v7(170.56,16.21) ; C543.2 v7(159.51,50.37) ; C476.2 v7(158.8,105) ; C313.2 v7(123.57,19.94) ; C117.2 25.4,100.51 v7(25.3,100.41) ; C578.2 v7(130.79,131.55) ; R427.1 v7(158.37,103.6) ; v7(28.19,76.28) R186.1 ; C143.2 v7(25.4,61.55)
  vias: v1(20.07,117.43) v1(21.34,118.7) v1(28.32,37.67) v1(28.32,36.4) v1(28.32,35.13) v1(29.59,37.67) v1(29.59,36.4) v1(30.48,101.43) v1(30.48,100.41) v1(30.48,83.61) v1(30.48,82.6) v1(30.48,58.85) v1(30.48,57.83) v1(30.86,37.67) v1(30.86,36.4) v1(30.86,35.13) v1(31.5,101.43) v1(31.5,100.41) v1(31.5,99.4) v1(31.5,83.61) v1(31.5,82.6) v1(31.5,81.58) v1(31.5,58.85) v1(31.5,57.83) v1(32.51,101.43) v1(32.51,100.41) v1(32.51,99.4) v1(32.51,83.61) v1(32.51,82.6) v1(32.51,81.58) v1(32.51,58.85) v1(32.51,57.83) v1(32.51,56.82) v1(33.02,123.02) v1(33.02,120.86) v1(35.23,122.97) v1(35.31,118.83) v1(35.69,16.51) v1(35.81,22.86) v1(35.97,25.04) v1(36.14,17.33) v1(37.41,123.19) v1(37.36,120.65) v1(37.34,118.83) v1(37.57,17.88) v1(37.85,16.51) v1(38.3,24.16) v1(38.35,22.86) v1(38.81,28.32) v1(38.9,48.09) v1(38.9,46.57) v1(38.9,45.04) v1(38.9,43.52) v1(38.9,42) v1(38.9,40.47) v1(38.9,38.95) v1(38.9,34.38) v1(38.9,32.85) v1(38.9,31.33) v1(38.98,49.65) v1(39.6,21.46) v1(39.63,52.19) v1(40.88,48.09) v1(40.88,46.57) v1(40.88,45.04) v1(40.88,43.52) v1(40.88,42) v1(40.88,40.47) v1(40.88,34.38) v1(40.88,32.85) v1(40.88,31.33) v1(40.88,29.8) v1(40.88,26.76) v1(41.15,49.66) v1(41.43,20.1) v1(41.43,16.38) v1(41.49,54.58) v1(41.78,50.67) v1(42.55,55.22) v1(42.55,51.69) v1(42.73,46.63) v1(42.73,45.11) v1(42.73,43.59) v1(42.73,37.49) v1(42.72,35.97) v1(42.72,34.45) v1(42.73,32.92) v1(42.73,31.39) v1(42.73,28.3) v1(42.73,26.78) v1(42.89,48.26) v1(43.51,49.59) v1(43.81,52.83) v1(43.81,16.51) v1(43.98,56.3) v1(44.59,50.66) v1(44.96,53.98) v1(45.06,57.37) v1(45.67,51.74) v1(45.97,54.99) v1(46.14,58.45) v1(46.75,52.82) v1(47.12,56.13) v1(47.21,59.53) v1(47.82,53.9) v1(48.13,57.15) v1(48.29,60.61) v1(48.9,54.97) v1(49.15,58.29) v1(49.37,61.68) v1(49.98,56.05) v1(50.16,59.31) v1(50.45,62.76) v1(51.06,57.13) v1(51.31,60.45) v1(51.53,63.84) v1(52.13,58.21) v1(52.32,61.47) v1(52.6,64.92) v1(53.21,59.29) v1(53.47,62.61) v1(53.68,65.99) v1(54.29,60.36) v1(54.61,63.75) v1(54.74,123.02) v1(54.74,120.86) v1(54.74,118.83) v1(54.76,67.07) v1(55.37,61.44) v1(55.78,68.18) v1(55.75,64.9) v1(56.33,75.05) v1(56.33,73.43) v1(56.31,71.82) v1(56.33,69.97) v1(56.47,76.91) v1(56.95,122.97) v1(57.02,118.83) v1(56.97,78.67) v1(57.02,66.17) v1(56.98,63.06) v1(57.91,67.18) v1(57.96,64.03) v1(58.07,80.11) v1(58.42,75.06) v1(58.42,73.41) v1(58.42,71.88) v1(58.42,69.98) v1(58.55,76.83) v1(58.86,78.34) v1(59.08,120.65) v1(59.05,118.83) v1(59.13,123.19) v1(59.14,81.19) v1(59.97,79.42) v1(60.22,82.27) v1(60.27,74.8) v1(60.27,71.75) v1(60.27,70.22) v1(61.04,80.5) v1(61.3,83.35) v1(62.12,81.58) v1(62.38,84.42) v1(62.36,79.38) v1(63.44,80.46) v1(64.28,83.73) v1(64.39,81.41) v1(64.52,69.42) v1(65.6,82.62) v1(66.86,83.48) v1(73.13,145.09) v1(73.3,144.12) v1(74.91,144.07) v1(78.05,80.09) v1(80.42,80.59) v1(107.06,15.24) v1(107.06,14.22) v1(108.58,15.24) v1(108.58,14.22) v1(126.24,122.64) v1(152.53,25.35) v1(174.99,8.9) v1(178.08,69.47) v1(178.08,68.2) v1(178.08,66.93) v1(179.35,69.47) v1(179.35,68.2) v1(179.35,66.93) v1(180.62,69.47) v1(180.62,68.2) v1(180.62,66.93) v1(181.89,69.47) v1(181.89,68.2) v1(181.89,66.93) v1(183.16,69.47) v1(183.16,68.2) v1(183.16,66.93) v1(184.43,69.47) v1(184.43,68.2) v1(184.43,66.93) v1(185.7,69.47) v1(185.7,68.2) v1(185.7,66.93) v2(16.13,114.56) v2(17.58,114.58) v2(19.61,112.45) v2(19.69,111.03) v2(27.2,106.15) v2(34.52,107.32) v2(39.57,63.02) v2(39.6,62.21) v2(39.6,60.91) v2(39.62,58.7) v2(39.7,87.66) v2(39.73,86.85) v2(39.73,85.55) v2(39.65,59.85) v2(39.78,104.83) v2(39.8,104.02) v2(39.8,102.72) v2(39.83,100.51) v2(39.78,84.49) v2(39.75,83.34) v2(39.85,101.66) v2(43.69,96.65) v2(44.22,94.77) v2(45.21,98.68) v2(46.66,92.82) v2(48.25,15.87) v2(48.89,91.65) v2(49.2,94.26) v2(51.79,90.78) v2(54.1,93.43) v2(56.62,90.78) v2(58.83,93.45) v2(60.86,93.78) v2(61.21,98.76) v2(61.21,95.97) v2(61.52,90.89) v2(61.61,112.13) v2(62.88,111.36) v2(63.6,93.12) v2(64.16,98.07) v2(64.31,99.52) v2(64.64,113.04) v2(68.33,116.52) v2(69.35,87.99) v2(70.2,115.22) v2(70.56,91.09) v2(71.15,87.79) v2(71.17,83.94) v2(71.32,85.5) v2(71.72,116.44) v2(72.31,85.58) v2(73.1,90.96) v2(73.23,85.63) v2(73.3,87.77) v2(73.43,115.2) v2(74.55,88.33) v2(76.3,86.39) v2(76.53,91.09) v2(76.54,89.2) v2(77.14,115.22) v2(77.31,84.92) v2(78.05,85.71) v2(78.86,86.34) v2(79.1,116.66) v2(79.12,89.28) v2(80.86,89.13) v2(80.98,115.18) v2(81.79,87.5) v2(88.23,116.67) v2(89.58,123.92) v2(90.2,115.5) v2(91.86,116.77) v2(92.62,115.5) v2(93.25,114.61) v2(95.41,114.61) v2(97.06,114.61) v2(100.75,116.77) v2(102.02,125.03) v2(102.74,123.65) v2(105.57,116.77) v2(105.57,115.12) v2(106.05,123.75) v2(107.1,123.12) v2(107.48,115.37) v2(111.41,111.56) v2(114.22,116.13) v2(115.86,115.88) v2(116.62,113.72) v2(117.51,114.23) v2(118.61,95.97) v2(118.87,106.41) v2(119.63,94.44) v2(120.65,101.94) v2(122.22,102.67) v2(133.73,139.15) v2(133.73,137.88) v2(134.37,140.54) v2(134.37,134.19) v2(136.4,140.67) v2(137.03,134.07) v2(138.68,140.54) v2(139.32,138.13) v2(149.28,83.95) v2(150.29,80.78) v2(151.05,87.89) v2(152.07,80.78) v2(153.47,84.21) v2(154.1,81.92) v2(155.5,87.63) v2(155.5,82.17) v2(158.67,86.36) v2(165.23,120.22) v2(165.25,119.21) v2(165.25,117.81) v2(165.74,123.27) v2(165.76,122) v2(165.76,120.86) v2(166.9,122) v2(166.9,120.86) v3(87.7,88.44) v3(87.74,84.39) v3(88.21,88.4) v3(88.36,86.91) v3(88.63,88.16) v3(88.8,85.51) v3(88.86,86.92) v3(89.27,88.02) v3(89.36,86.74) v3(89.41,85.11) v3(89.76,86.46) v3(89.83,87.8) v3(90.01,84.66) v3(90.18,86.16) v3(90.57,85.83) v3(90.66,84.55) v3(90.93,86.9) v3(91.88,84.71) v3(94.23,84.18) v3(94.97,83.98) v4(87.7,88.44) v4(87.74,84.39) v4(88.21,88.4) v4(88.36,86.91) v4(88.63,88.16) v4(88.8,85.51) v4(88.86,86.92) v4(89.27,88.02) v4(89.36,86.74) v4(89.41,85.11) v4(89.76,86.46) v4(89.83,87.8) v4(90.01,84.66) v4(90.18,86.16) v4(90.57,85.83) v4(90.66,84.55) v4(90.93,86.9) v4(91.88,84.71) v4(94.23,84.18) v4(94.97,83.98) v4(107.83,76.82) v5(16.13,114.56) v5(17.58,114.58) v5(19.61,112.45) v5(19.69,111.03) v5(27.2,106.15) v5(34.52,107.32) v5(39.57,63.02) v5(39.6,62.21) v5(39.6,60.91) v5(39.62,58.7) v5(39.7,87.66) v5(39.73,86.85) v5(39.73,85.55) v5(39.65,59.85) v5(39.78,104.83) v5(39.8,104.02) v5(39.8,102.72) v5(39.83,100.51) v5(39.78,84.49) v5(39.75,83.34) v5(39.85,101.66) v5(43.69,96.65) v5(44.22,94.77) v5(45.21,98.68) v5(46.66,92.82) v5(48.25,15.87) v5(48.89,91.65) v5(49.2,94.26) v5(51.79,90.78) v5(54.1,93.43) v5(56.62,90.78) v5(58.83,93.45) v5(60.86,93.78) v5(61.21,98.76) v5(61.21,95.97) v5(61.52,90.89) v5(61.61,112.13) v5(62.88,111.36) v5(63.6,93.12) v5(64.16,98.07) v5(64.31,99.52) v5(64.64,113.04) v5(68.33,116.52) v5(69.35,87.99) v5(70.2,115.22) v5(70.56,91.09) v5(71.15,87.79) v5(71.17,83.94) v5(71.32,85.5) v5(71.72,116.44) v5(72.31,85.58) v5(73.1,90.96) v5(73.23,85.63) v5(73.3,87.77) v5(73.43,115.2) v5(74.55,88.33) v5(76.3,86.39) v5(76.53,91.09) v5(76.54,89.2) v5(77.14,115.22) v5(77.31,84.92) v5(78.05,85.71) v5(78.86,86.34) v5(79.1,116.66) v5(79.12,89.28) v5(80.86,89.13) v5(80.98,115.18) v5(81.79,87.5) v5(88.23,116.67) v5(89.58,123.92) v5(90.2,115.5) v5(91.86,116.77) v5(92.62,115.5) v5(93.25,114.61) v5(95.41,114.61) v5(97.06,114.61) v5(100.75,116.77) v5(102.02,125.03) v5(102.74,123.65) v5(105.57,116.77) v5(105.57,115.12) v5(106.05,123.75) v5(107.1,123.12) v5(107.48,115.37) v5(111.41,111.56) v5(114.22,116.13) v5(115.86,115.88) v5(116.62,113.72) v5(117.51,114.23) v5(118.61,95.97) v5(118.87,106.41) v5(119.63,94.44) v5(120.65,101.94) v5(122.22,102.67) v5(133.73,139.15) v5(133.73,137.88) v5(134.37,140.54) v5(134.37,134.19) v5(136.4,140.67) v5(136.65,129.53) v5(137.03,134.07) v5(138.68,140.54) v5(139.32,138.13) v5(149.28,83.95) v5(150.29,80.78) v5(151.05,87.89) v5(152.07,80.78) v5(153.47,84.21) v5(154.1,81.92) v5(155.5,87.63) v5(155.5,82.17) v5(158.67,86.36) v5(165.23,120.22) v5(165.25,119.21) v5(165.25,117.81) v5(165.74,123.27) v5(165.76,122) v5(165.76,120.86) v5(166.9,122) v5(166.9,120.86) v6(115.32,53.17) v6(116.33,53.17) v6(116.33,52.28) v6(117.47,52.28) v6(117.47,51.26) v6(126.87,36.02) v7(2.54,149.81) v7(2.54,145.5) v7(2.54,142.96) v7(2.54,140.42) v7(2.54,137.88) v7(2.54,135.34) v7(2.54,132.8) v7(2.54,130.26) v7(2.54,127.72) v7(2.54,125.18) v7(2.54,122.64) v7(2.54,120.1) v7(2.54,117.56) v7(2.54,115.02) v7(2.54,112.48) v7(2.54,109.94) v7(2.54,107.4) v7(2.54,104.86) v7(2.54,102.32) v7(2.54,99.78) v7(2.54,97.24) v7(2.54,94.7) v7(2.54,92.16) v7(2.54,89.62) v7(2.54,87.08) v7(2.54,84.54) v7(2.54,82) v7(2.54,79.46) v7(2.54,76.92) v7(2.54,74.38) v7(2.54,71.84) v7(2.54,69.3) v7(2.54,66.76) v7(2.54,64.22) v7(2.54,61.68) v7(2.54,59.14) v7(2.54,56.6) v7(2.54,54.06) v7(2.54,34.04) v7(2.54,31.5) v7(2.54,28.96) v7(2.54,26.42) v7(2.54,23.88) v7(2.54,21.34) v7(2.54,18.8) v7(2.54,16.26) v7(2.54,11.18) v7(2.54,6.1) v7(2.54,3.56) v7(6.1,36.53) v7(6.1,35.51) v7(6.73,45.47) v7(6.73,44.2) v7(6.73,42.93) v7(6.86,34.04) v7(6.86,32.77) v7(6.86,31.5) v7(7.24,36.53) v7(7.24,35.51) v7(7.62,149.81) v7(10.16,149.81) v7(12.57,2.49) v7(12.7,149.81) v7(15.24,149.81) v7(16.89,41.1) v7(16.89,23.2) v7(17.65,37.67) v7(17.78,149.81) v7(18.03,23.58) v7(19.3,23.58) v7(20.19,37.67) v7(20.32,149.81) v7(22.73,37.67) v7(22.86,149.81) v7(24.23,40.34) v7(24.73,39.48) v7(25.4,149.81) v7(27.94,149.81) v7(27.94,2.54) v7(28.83,18.41) v7(28.83,17.14) v7(28.83,15.88) v7(30.48,149.81) v7(30.48,2.54) v7(32,14.31) v7(33.02,149.81) v7(35.56,149.81) v7(38.1,149.81) v7(40.64,149.81) v7(42.55,83.52) v7(42.55,82.25) v7(42.55,80.98) v7(43.18,149.81) v7(43.18,2.54) v7(45.09,91.14) v7(45.09,84.79) v7(45.09,80.98) v7(45.72,149.81) v7(45.72,2.54) v7(46.99,82.25) v7(48.26,149.81) v7(48.26,2.54) v7(49.53,82.25) v7(49.53,80.98) v7(50.8,149.81) v7(50.8,2.54) v7(52.58,89.62) v7(53.34,149.81) v7(53.34,82.25) v7(53.34,80.98) v7(55.73,56.06) v7(55.88,149.81) v7(55.88,2.54) v7(56.25,53.2) v7(57.15,82.25) v7(57.66,89.62) v7(58.42,149.81) v7(58.42,2.54) v7(59,41.86) v7(59.18,62.19) v7(60.96,149.81) v7(60.96,2.54) v7(61.34,41.78) v7(62.23,45.72) v7(63.5,149.81) v7(63.5,43.18) v7(63.5,2.54) v7(64.81,86.77) v7(64.77,41.91) v7(65.25,39.17) v7(65.72,85.09) v7(66.04,149.81) v7(66.04,2.54) v7(66.42,112.22) v7(66.42,110.83) v7(66.68,87.64) v7(67.31,73.11) v7(67.31,38.51) v7(67.86,87.79) v7(68.58,149.81) v7(68.58,148.67) v7(68.58,2.54) v7(73.66,2.54) v7(75.95,116.29) v7(77.09,75.9) v7(77.09,74.63) v7(78.74,149.81) v7(79.63,44.07) v7(79.63,42.8) v7(88.9,149.81) v7(90.17,66.5) v7(91.19,38.23) v7(91.19,36.96) v7(91.19,35.69) v7(91.19,34.42) v7(91.44,149.81) v7(91.44,40.13) v7(92.2,50.8) v7(92.23,47.12) v7(92.23,45.85) v7(92.23,44.58) v7(92.46,36.96) v7(92.46,35.69) v7(92.46,34.42) v7(93.98,149.81) v7(98.42,52.07) v7(100.08,45.97) v7(100.97,42.42) v7(102.49,52.32) v7(102.49,51.05) v7(103.12,19.3) v7(103.63,47.62) v7(103.76,69.3) v7(103.89,51.69) v7(103.91,19.3) v7(103.89,18.54) v7(104.52,46.74) v7(105.03,44.7) v7(105.03,43.43) v7(105.03,42.16) v7(105.03,40.89) v7(106.3,40.89) v7(106.3,39.62) v7(106.3,38.35) v7(106.43,36.96) v7(106.43,35.69) v7(106.43,34.42) v7(107.7,36.96) v7(107.7,35.69) v7(107.7,34.42) v7(108.71,47.37) v7(110.6,17.29) v7(115.95,43.43) v7(115.95,42.16) v7(116.84,47.62) v7(121.03,43.69) v7(121.03,42.42) v7(121.03,41.15) v7(124.46,2.54) v7(125.6,117.68) v7(125.6,115.65) v7(126.36,116.67) v7(127,2.54) v7(129.54,2.54) v7(130.18,124.29) v7(132.08,2.54) v7(134.11,136.1) v7(134.62,2.54) v7(137.16,2.54) v7(139.7,2.54) v7(142.24,2.54) v7(144.78,2.54) v7(147.07,136.1) v7(147.32,2.54) v7(149.86,2.54) v7(150.75,105.49) v7(150.75,104.22) v7(152.15,104.22) v7(152.4,2.54) v7(153.16,104.22) v7(154.69,53.17) v7(154.81,62.31) v7(154.81,61.42) v7(154.94,2.54) v7(155.58,127.08) v7(155.58,125.68) v7(155.83,53.17) v7(155.96,62.31) v7(155.96,61.42) v7(156.72,125.68) v7(156.84,54.06) v7(156.84,53.17) v7(157.4,84.33) v7(159.97,111.43) v7(159.97,110.16) v7(161.24,111.43) v7(161.24,110.16) v7(163.65,150.04) v7(163.86,142.98) v7(165.56,150.39) v7(165.84,142.09) v7(167.67,131.15) v7(167.67,129.75) v7(167.67,128.22) v7(167.71,126.06) v7(167.71,123.52) v7(169.37,142.11) v7(171.09,131.15) v7(171.09,129.75) v7(171.09,128.22) v7(171.91,142.11) v7(174.02,143.87) v7(180.75,131.02) v7(183.03,149.81) v7(184.05,11.3) v7(184.18,131.02) v7(185.29,142.62) v7(187.07,141.61) v7(188.11,149.81) v7(188.18,146.38) v7(188.18,118.44) v7(188.18,115.9) v7(188.18,110.82) v7(188.18,108.28) v7(188.18,105.74) v7(188.18,103.2) v7(188.18,6.98) v7(188.18,4.44) v8(14.71,109.76) v8(14.76,112.12) v8(15.09,117.78) v8(15.57,107.57) v8(15.82,112.22) v8(16.61,113.01) v8(16.89,114.66) v8(20.8,111.36) v8(21.74,106.08) v8(27.05,105.03) v8(30.23,109.89) v8(31.67,105.36) v8(32.11,108.97) v8(36.55,108.72) v8(43.81,103.46) v8(44.07,104.09) v8(44.58,99.27) v8(44.83,107.14) v8(45.97,107.14) v8(47.24,99.14) v8(47.5,107.14) v8(49.02,107.14) v8(49.15,98.89) v8(50.93,107.14) v8(51.18,99.65) v8(51.31,105.49) v8(51.56,101.43) v8(54.79,106.53) v8(63.65,103.69) v8(67.64,102.52) v8(68.35,114.15) v8(68.45,108.92) v8(68.45,108.03) v8(70.15,113.16) v8(74.04,104.14) v8(80.64,82.8) v8(80.64,81.41) v8(80.85,103.99) v8(82.68,77.22) v8(84.3,112.45) v8(87.76,121.65) v8(89.99,120.68) v8(92.1,121.65) v8(92.2,68.15) v8(94.11,120.68) v8(94.59,69.6) v8(95.07,70.31) v8(96.24,69.29) v8(97.35,92.83) v8(97.35,91.81) v8(97.35,91.05) v8(97.74,120.68) v8(100.15,121.32) v8(101.35,90.51) v8(102.36,90.51) v8(103.38,90.51) v8(103.5,118.95) v8(104.77,119.21) v8(105,111.43) v8(105.49,112.76) v8(108.18,105.82) v8(110.54,76.59) v8(115.7,76.33) v8(116.33,75.21) v8(116.87,78.03) v8(116.87,77.24) v8(118.75,80.09) v8(118.75,79.08) v8(118.87,52.53) v8(118.87,51.26) v8(119.89,52.53) v8(119.89,51.26) v8(120.27,91.39) v8(120.27,87.97) v8(120.9,52.53) v8(120.9,51.26) v8(121.41,91.39) v8(121.41,87.97) v8(122.68,90.76) v8(122.68,89.74) v8(122.68,88.73) v8(128.02,103.18) v8(128.27,105.36) v8(128.33,124.3) v8(129.22,124.3) v8(129.21,105.37) v8(129.87,132.25) v8(129.87,131.62) v8(130.24,125.82) v8(130.24,125.06) v8(130.24,123.41) v8(130.94,126.45) v8(131.32,125.18) v8(131.95,135.34) v8(132.21,125.18) v8(132.21,123.25) v8(132.72,135.34) v8(132.84,123.25) v8(134.37,135.34) v8(135.69,135) v8(142.88,136.61) v8(143.76,136.61) v8(144.78,136.61) v8(145.67,136.61) v8(148.34,133.69) v8(148.34,132.92) v8(148.34,132.16) v8(148.34,128.99) v8(148.34,128.22) v8(148.34,127.59) v8(175.29,26.42) v9(14.71,109.76) v9(14.76,112.12) v9(15.09,117.78) v9(15.57,107.57) v9(15.82,112.22) v9(16.61,113.01) v9(16.89,114.66) v9(20.8,111.36) v9(21.74,106.08) v9(27.05,105.03) v9(30.23,109.89) v9(31.67,105.36) v9(32.11,108.97) v9(36.55,108.72) v9(43.81,103.46) v9(44.07,104.09) v9(44.58,99.27) v9(44.83,107.14) v9(45.97,107.14) v9(47.24,99.14) v9(47.5,107.14) v9(49.02,107.14) v9(49.15,98.89) v9(50.93,107.14) v9(51.18,99.65) v9(51.31,105.49) v9(51.56,101.43) v9(54.79,106.53) v9(63.65,103.69) v9(67.64,102.52) v9(68.35,114.15) v9(68.45,108.92) v9(68.45,108.03) v9(70.15,113.16) v9(74.04,104.14) v9(80.64,82.8) v9(80.64,81.41) v9(80.85,103.99) v9(82.68,77.22) v9(84.3,112.45) v9(87.76,121.65) v9(89.99,120.68) v9(92.1,121.65) v9(92.2,68.15) v9(94.11,120.68) v9(94.59,69.6) v9(95.07,70.31) v9(96.24,69.29) v9(97.35,92.83) v9(97.35,91.81) v9(97.35,91.05) v9(97.74,120.68) v9(100.15,121.32) v9(101.35,90.51) v9(102.36,90.51) v9(103.38,90.51) v9(103.5,118.95) v9(104.77,119.21) v9(105,111.43) v9(105.49,112.76) v9(108.18,105.82) v9(110.54,76.59) v9(115.7,76.33) v9(116.33,75.21) v9(116.87,78.03) v9(116.87,77.24) v9(118.75,80.09) v9(118.75,79.08) v9(118.87,52.53) v9(118.87,51.26) v9(119.89,52.53) v9(119.89,51.26) v9(120.27,91.39) v9(120.27,87.97) v9(120.9,52.53) v9(120.9,51.26) v9(121.41,91.39) v9(121.41,87.97) v9(122.68,90.76) v9(122.68,89.74) v9(122.68,88.73) v9(128.02,103.18) v9(128.27,105.36) v9(128.33,124.3) v9(129.22,124.3) v9(129.21,105.37) v9(129.87,132.25) v9(129.87,131.62) v9(130.24,125.82) v9(130.24,125.06) v9(130.24,123.41) v9(130.94,126.45) v9(131.32,125.18) v9(131.95,135.34) v9(132.21,125.18) v9(132.21,123.25) v9(132.72,135.34) v9(132.84,123.25) v9(134.37,135.34) v9(135.69,135) v9(142.88,136.61) v9(143.76,136.61) v9(144.78,136.61) v9(145.67,136.61) v9(148.34,133.69) v9(148.34,132.92) v9(148.34,132.16) v9(148.34,128.99) v9(148.34,128.22) v9(148.34,127.59) v9(175.29,26.42) v10(27.41,113.26) v10(27.46,115.47) v10(27.64,111.26) v10(31.32,106.02) v10(33.45,106.08) v10(34.26,105.47) v10(36.27,105.85) v10(57.96,99.73) v10(58.04,101.43) v10(58.04,100.54) v10(59.23,96.17) v10(59.74,102.9) v10(60.43,96.12) v10(60.81,102.8) v10(61.59,96.09) v10(63.12,96.09) v10(64.92,96.88) v10(65,102.24) v10(64.97,99.27) v10(73.68,84.61) v10(73.78,83.74) v10(74.51,84.64) v10(74.52,84.23) v10(81.41,83.57) v10(87,91.39) v10(87.12,76.15) v10(87.16,77.73) v10(87.63,91.39) v10(87.59,77.73) v10(87.63,76.15) v10(88.27,91.39) v10(88.9,91.39) v10(92.38,85.43) v10(93.47,79.08) v10(94.11,78.99) v10(94.82,88.24) v10(97.38,96.86) v10(97.92,98.13) v10(98.89,73.41) v10(98.93,98.13) v10(99.06,73.79) v10(99.19,73.06) v10(99.67,73.72) v10(99.69,71.58) v10(99.75,75.56) v10(99.95,71.07) v10(100.33,92.71) v10(100.33,92.08) v10(100.28,68.99) v10(100.6,76.19) v10(100.86,69.02) v10(101.47,92.96) v10(101.47,92.46) v10(101.47,91.82) v10(101.47,91.19) v10(101.73,86.95) v10(101.98,86.44) v10(102.18,86.95) v10(102.67,77.75) v10(102.9,73.26) v10(103.1,73.66) v10(103.38,93.68) v10(103.63,93.3) v10(103.68,73.64) v10(104.11,99.69) v10(104.65,90.25) v10(104.65,89.62) v10(104.65,88.73) v10(105.18,98.57) v10(105.28,97.72) v10(106.43,94.29) v10(106.43,93.78) v10(107.37,89.77) v10(108.46,89.77) v10(108.58,94.29) v10(108.58,93.78) v10(109.47,76.26) v10(109.99,79.6) v10(110.74,94.29) v10(110.74,93.78) v10(110.97,77.88) v10(111.12,83.9) v10(111.2,87.84) v10(111.2,87.08) v10(111.3,72.14) v10(111.38,84.33) v10(112.24,44.02) v10(112.24,43.38) v10(112.24,42.75) v10(112.24,42.11) v10(112.45,75.9) v10(112.81,74.73) v10(112.81,73.66) v10(114.38,112.37) v10(114.38,110.98) v10(114.88,112.37) v10(114.88,110.98) v10(115.7,101.81) v10(116.2,101.81) v10(116.46,87.33) v10(116.71,101.81) v10(117.73,86.82) v10(117.73,85.81) v10(119.61,44.4) v10(119.61,43.76) v10(119.61,43.13) v10(119.61,42.49) v10(121.54,87.33) v10(122.81,86.7) v10(122.81,85.68) v11(27.41,113.26) v11(27.46,115.47) v11(27.64,111.26) v11(31.32,106.02) v11(33.45,106.08) v11(34.26,105.47) v11(36.27,105.85) v11(57.96,99.73) v11(58.04,101.43) v11(58.04,100.54) v11(59.23,96.17) v11(59.74,102.9) v11(60.43,96.12) v11(60.81,102.8) v11(61.59,96.09) v11(63.12,96.09) v11(64.92,96.88) v11(65,102.24) v11(64.97,99.27) v11(73.68,84.61) v11(73.78,83.74) v11(74.51,84.64) v11(74.52,84.23) v11(81.41,83.57) v11(87,91.39) v11(87.12,76.15) v11(87.16,77.73) v11(87.63,91.39) v11(87.59,77.73) v11(87.63,76.15) v11(88.27,91.39) v11(88.9,91.39) v11(92.38,85.43) v11(93.47,79.08) v11(94.11,78.99) v11(94.82,88.24) v11(97.38,96.86) v11(97.92,98.13) v11(98.89,73.41) v11(98.93,98.13) v11(99.06,73.79) v11(99.19,73.06) v11(99.67,73.72) v11(99.69,71.58) v11(99.75,75.56) v11(99.95,71.07) v11(100.33,92.71) v11(100.33,92.08) v11(100.28,68.99) v11(100.6,76.19) v11(100.86,69.02) v11(101.47,92.96) v11(101.47,92.46) v11(101.47,91.82) v11(101.47,91.19) v11(101.73,86.95) v11(101.98,86.44) v11(102.18,86.95) v11(102.67,77.75) v11(102.9,73.26) v11(103.1,73.66) v11(103.38,93.68) v11(103.63,93.3) v11(103.68,73.64) v11(104.11,99.69) v11(104.65,90.25) v11(104.65,89.62) v11(104.65,88.73) v11(105.18,98.57) v11(105.28,97.72) v11(106.43,94.29) v11(106.43,93.78) v11(107.37,89.77) v11(108.46,89.77) v11(108.58,94.29) v11(108.58,93.78) v11(109.47,76.26) v11(109.99,79.6) v11(110.74,94.29) v11(110.74,93.78) v11(110.97,77.88) v11(111.12,83.9) v11(111.2,87.84) v11(111.2,87.08) v11(111.3,72.14) v11(111.38,84.33) v11(112.24,44.02) v11(112.24,43.38) v11(112.24,42.75) v11(112.24,42.11) v11(112.45,75.9) v11(112.81,74.73) v11(112.81,73.66) v11(114.38,112.37) v11(114.38,110.98) v11(114.88,112.37) v11(114.88,110.98) v11(115.7,101.81) v11(116.2,101.81) v11(116.46,87.33) v11(116.71,101.81) v11(117.73,86.82) v11(117.73,85.81) v11(119.61,44.4) v11(119.61,43.76) v11(119.61,43.13) v11(119.61,42.49) v11(121.54,87.33) v11(122.81,86.7) v11(122.81,85.68)
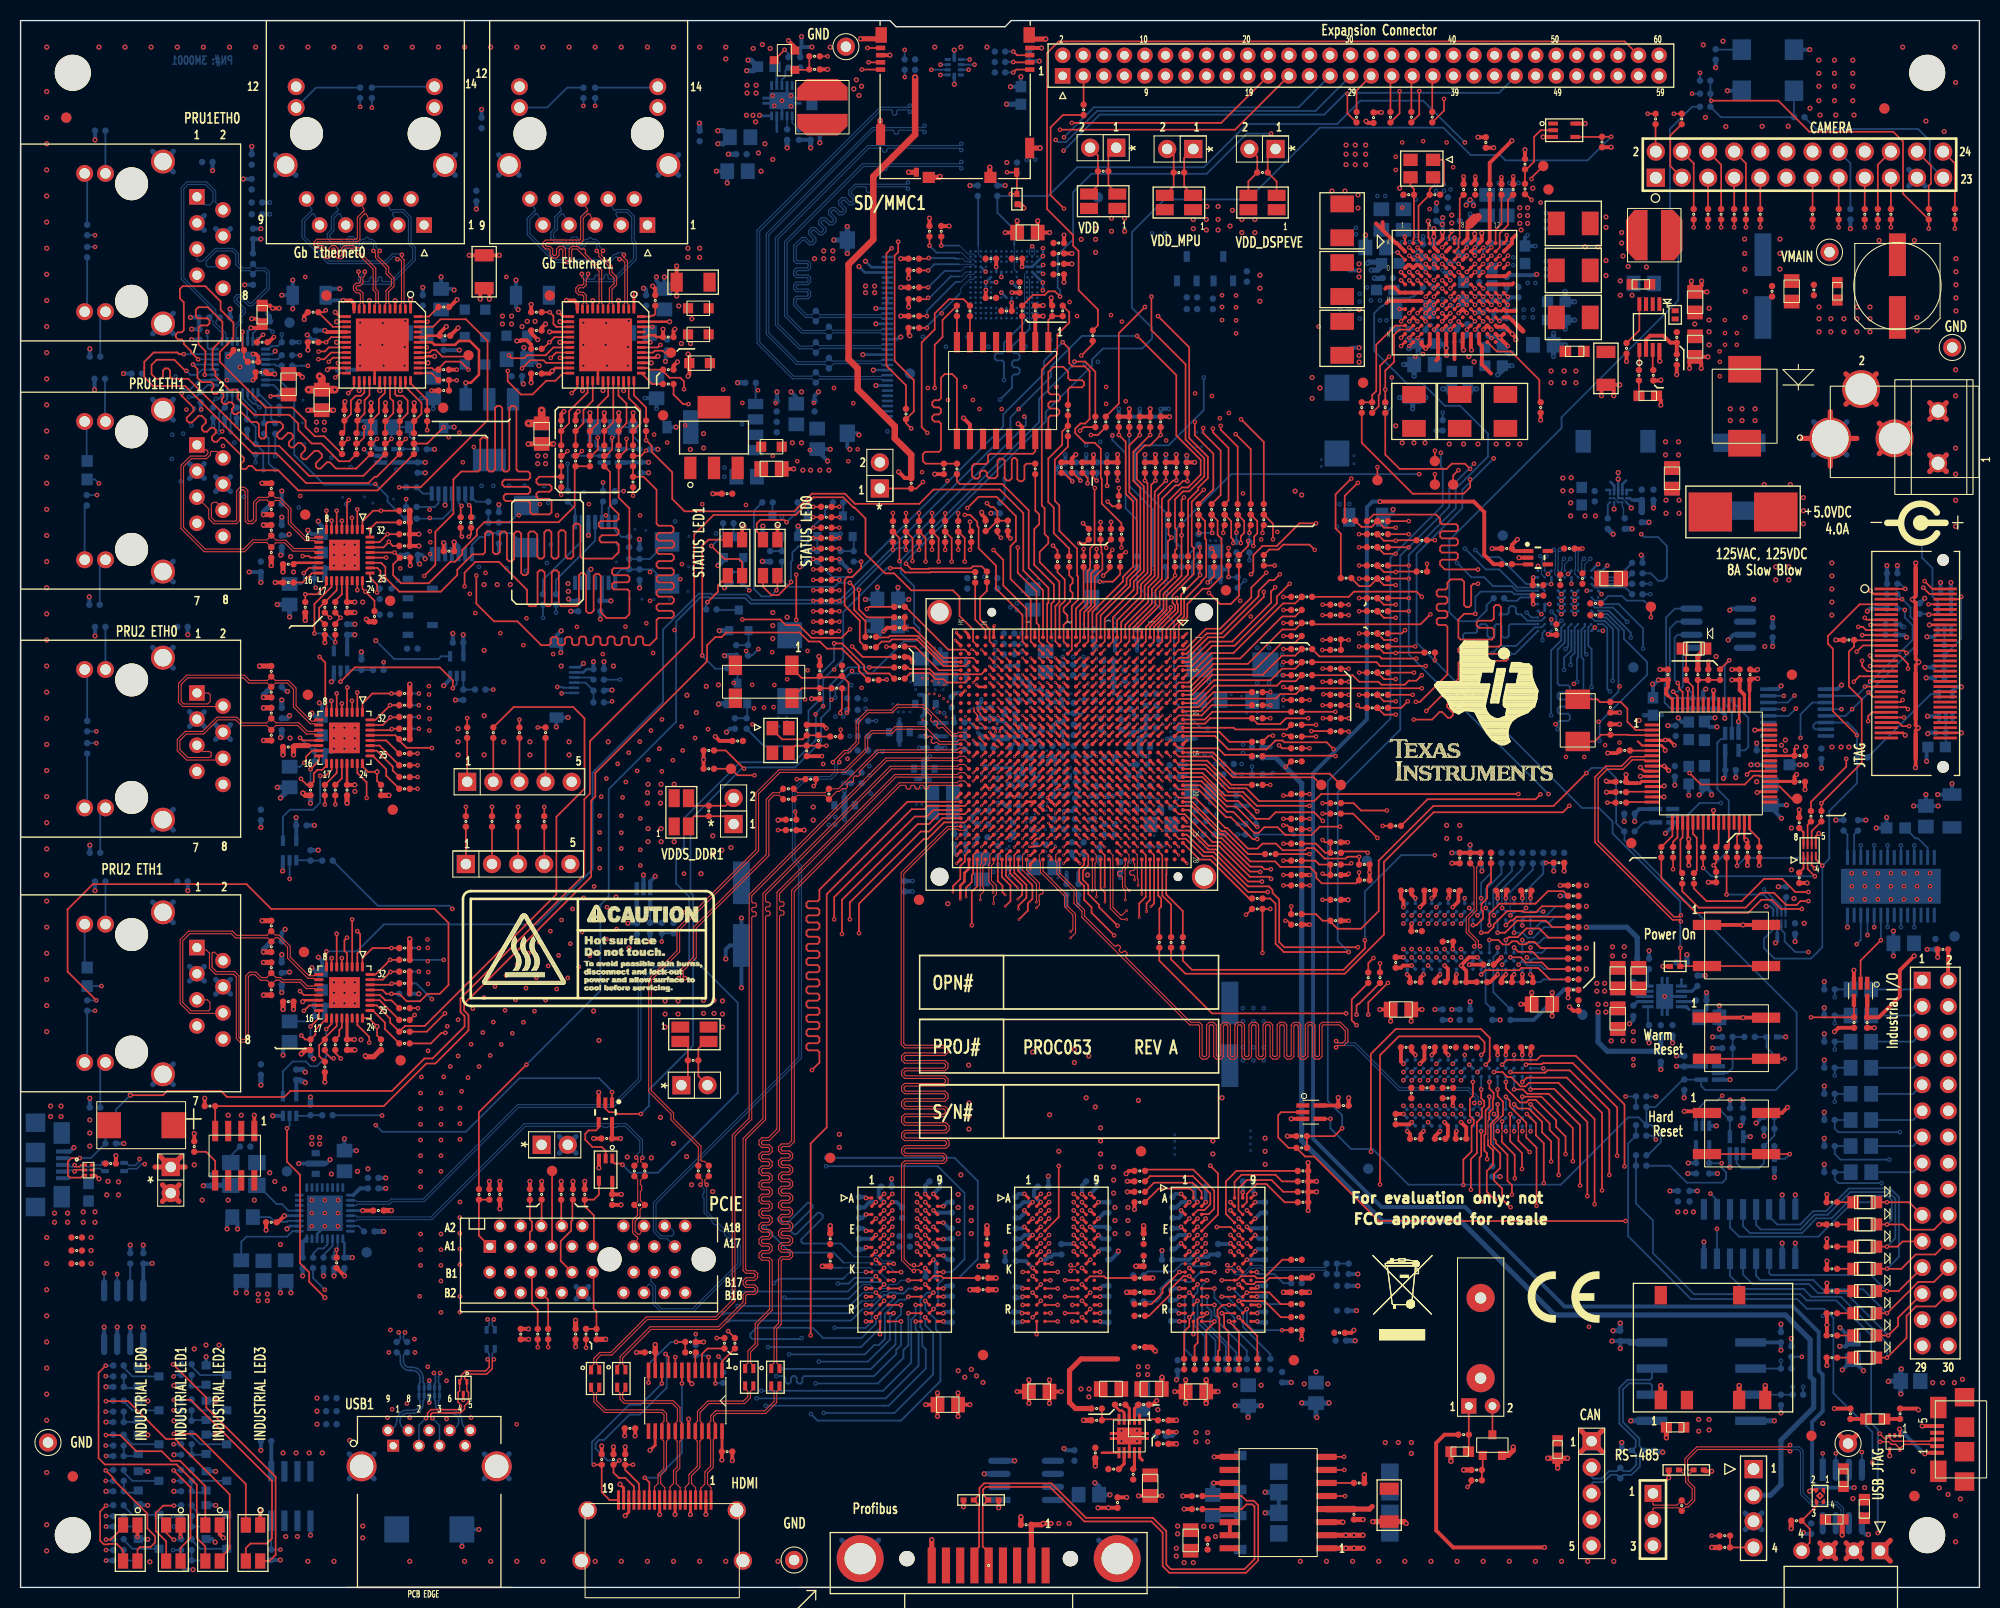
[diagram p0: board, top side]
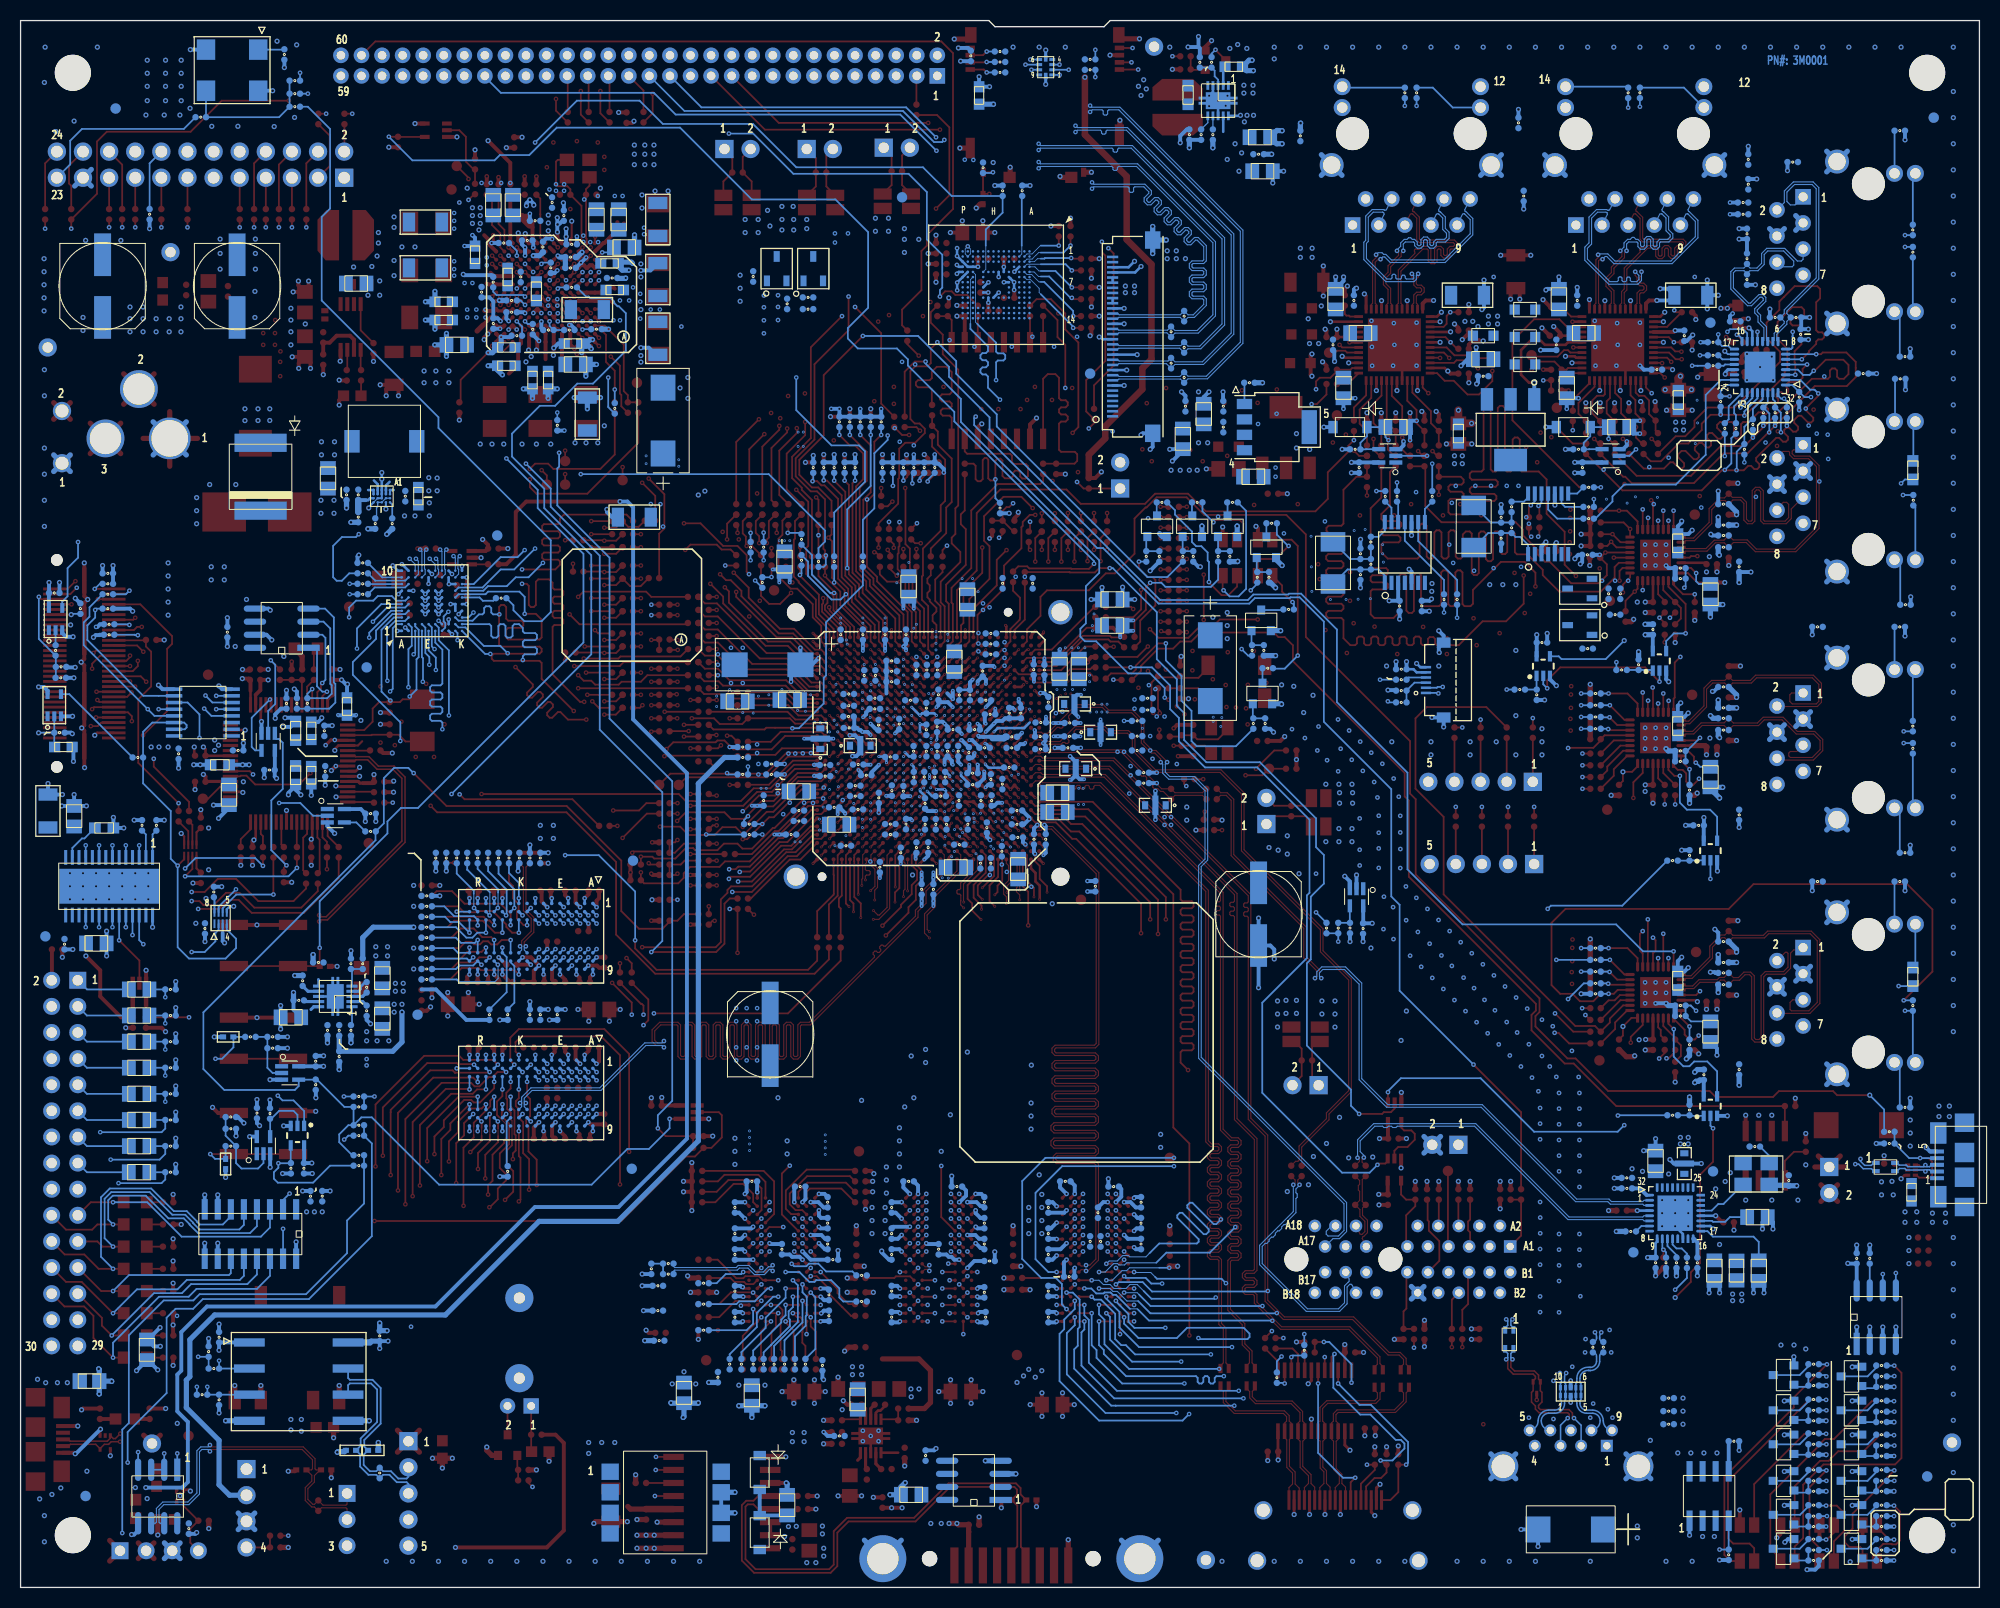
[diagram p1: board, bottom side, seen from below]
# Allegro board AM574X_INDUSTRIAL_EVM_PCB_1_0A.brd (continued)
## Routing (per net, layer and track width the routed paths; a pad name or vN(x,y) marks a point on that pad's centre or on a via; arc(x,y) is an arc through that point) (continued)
GND_CAN1: length 15.5
  TOP w0.508: C250.2 v7(150.44,12.57) ; C250.2 v7(149.48,11.61) ; C250.2 v7(148.51,12.57) ; U40.4 v7(167.13,19.64) ; U40.5 v7(169.67,19.64)
  L3_SIG1 w0.508: J38.4 153.59,7.41 ; J38.4 153.59,5.8 ; J38.4 151.98,7.41 ; J38.4 151.98,5.8
  BOTTOM w0.508: v7(155.58,25.71) C252.2 v7(154.86,24.97) ; U88.2 v7(155.71,14.1) ; U87.2 159,13.21 159.64,13.21 v7(159.7,13.14) ; v7(156.59,16.21) U41.5
GND_OSC0: length 14
  TOP w0.254: U1.AF15 v4(92.64,80.82)
  TOP w0.381: v5(78.36,83.57) 78.02,83.9 C1.2 ; C2.2 v5(77.93,80.85)
  L3_SIG1 w0.381: v4(92.64,80.82) 92.06,80.82 91.84,80.59 87.66,80.59 87.28,80.97 87.24,80.93 84.57,80.93 84.53,80.97 ; 79.2,80.95 79.17,80.98 78.65,80.98 78.53,80.85 v5(77.93,80.85) 77.93,81.03
GNDPROFI: length 23
  TOP w0.381: U74.15 U74.14 ; U81.2 95.12,7.88 95.12,7.87 v7(95.12,7.75) ; R578.1 v7(113.16,7.62) ; U80.2 v7(91.7,7.85) ; U74.9 v7(116.08,12.7) ; R573.1 v7(107.57,8.76) ; U74.11 v7(116.03,10.16)
  TOP w0.508: J14.5 v7(88.61,4.64) ; C430.2 v7(97.28,6.86)
  BOTTOM w0.381: 102.49,13.34 101.65,13.34 v7(101.47,13.51) ; L2.6 L2.7
  BOTTOM w0.508: C433.2 115.95,10.08 v7(116.03,10.16) ; U52.3 v7(93.71,11.05) ; U52.4 v7(96.67,12.32) ; L2.7 v7(121.03,9.25) ; v7(105.94,9.02) C325.2 104.89,9.77 v7(104.47,10.19) ; v7(121.03,7.26) L2.6
  vias: v7(112.52,5.97) v7(112.52,5.21) v7(115.06,5.94) v7(115.82,5.92) v7(116.2,4.95)
GNDUSB1: length 13.7
  BOTTOM w0.508: J23.S1 34.38,12.99 ; J23.S1 31.96,12.99 ; J23.S1 31.96,10.57 ; J23.S1 34.38,10.57 ; 45.1,12.99 J23.S2 ; J23.S2 47.52,10.57 ; J23.S2 47.52,12.99 ; J23.S2 45.1,10.57
GNDUSB2:
  vias: v7(2.92,46.82) v7(2.92,45.8) v7(3.3,36.4) v7(3.3,35.51) v7(3.94,46.82) v7(3.94,45.8) v7(4.57,36.4) v7(4.57,35.51)
GNDUSBJ:
  vias: v7(185.95,19.91) v7(186.59,9.68) v7(186.92,19.91) v7(187.45,9.04) v7(188.06,19.91) v7(188.65,8.61) v7(188.85,20.24)
V1_2D: length 1.4
  BOTTOM w0.254: U89.B1 v1(153.1,93.37) ; U89.K4 v1(147.9,94.67) ; U89.A7 v1(153.75,96.62)
V1_2D_EN: length 1.6
  TOP w0.173: R451.1 145.05,99.51 U76.3
V1_8D: length 197.9
  TOP w0.254: U1.Y7 v4(97.44,88.01) ; U1.N21 v11(103.83,76.02) ; U1.P8 v4(103.03,87.21) ; U1.V22 v4(99.04,76.02) U1.V21 ; v4(98.24,76.02) U1.W21 U1.Y21 v4(97.44,76.02) ; U1.M9 v4(104.63,86.41) ; U1.W17 v4(98.24,79.22) ; U1.J22 v4(107.03,75.22) ; U1.H17 v4(107.83,79.22) ; U1.AA19 v4(96.64,77.62) ; U1.T8 v4(100.64,87.21) ; U1.M8 v4(104.63,87.21) ; U1.R8 v4(101.44,87.21) ; U1.G18 v4(108.63,78.42) ; U1.W18 v4(98.24,78.42) ; U1.P20 v4(103.03,76.82) ; U1.N8 v4(103.83,87.21) ; U1.P21 v11(103.03,76.02) ; U1.J21 v4(107.03,76.02) ; U1.AA7 v4(96.64,88.01) ; U1.AA18 v4(96.64,78.42)
  TOP w0.381: v7(132.21,105.62) 141.32,105.62 142.34,104.6 142.34,100.44 143.26,99.52 R451.2 ; C169.1 v7(42.16,101.68)
  L3_SIG1 w0.254: v4(100.64,87.21) 100.24,87.46 v6(100.24,87.46) ; v4(104.63,87.21) v6(105.03,87.46) ; v4(96.64,78.42) v6(96.24,78.17) ; v4(103.03,76.82) v6(103.43,76.57) ; v6(97.84,75.77) v4(98.24,76.02) ; v4(107.03,75.22) v6(107.43,74.97) ; v4(107.83,79.22) v6(108.23,78.97) ; v6(104.23,87.46) 104.23,87.46 v4(103.83,87.21) ; v4(104.63,86.41) v6(105.03,86.66) ; v4(99.04,76.02) v6(98.64,75.77) ; v4(96.64,77.62) v6(96.24,77.37) ; v11(103.03,76.02) v6(103.43,75.77) ; v4(101.44,87.21) v6(101.04,87.46) ; v11(103.83,76.02) v6(104.23,75.77) ; v4(98.24,78.42) v6(97.84,78.17) ; v4(103.03,87.21) v6(103.43,87.46) ; v4(108.63,78.42) v6(109.03,78.17) ; v6(96.24,88.26) 96.24,88.26 v4(96.64,88.01) ; v4(97.44,88.01) v6(97.04,88.26) ; v4(98.24,79.22) v6(97.84,78.97) ; v4(97.44,76.02) v6(97.04,75.77) ; v4(107.03,76.02) v6(107.43,75.77)
  L4_SIG2 w0.381: v6(107.43,75.77) v6(107.43,74.97)
  L10_SIG4 w0.254: v11(103.83,87.22) v6(104.23,87.46) ; v11(104.78,87.06) v6(105.03,86.66) ; v6(103.43,76.57) 103.43,76.58 v11(103.1,76.92) ; v11(103.83,76.02) v6(104.23,75.77) ; v11(96.62,87.88) v6(96.24,88.26) ; v11(103.77,87.8) v6(103.43,87.46) ; v11(104.54,87.83) 104.66,87.83 105.02,87.46 v6(105.03,87.46) ; v6(98.64,75.77) 98.65,75.75 v11(98.65,75.24) ; v6(97.84,75.77) 97.85,75.76 v11(97.85,75.25) 97.85,74.89 v11(97.76,74.81) v11(97.76,74.43) ; v11(97.42,87.88) v6(97.04,88.26) ; v6(97.04,75.77) 97.04,75.41 v11(97.15,75.3) ; v11(103.03,76.02) v6(103.43,75.77)
  L10_SIG4 w0.381: v6(97.84,78.97) v6(97.84,78.17)
  BOTTOM w0.381: v7(178.32,9.71) 174.76,9.71 174.23,10.25 174.23,16.1 175.26,17.13 175.26,20.7 174.87,21.09 174.87,24.84 172.38,27.33 150.15,27.33 140.48,37 132.35,37 125.69,43.65 125.69,79.2 130.93,84.44 130.93,105.06 131.48,105.62 v7(132.21,105.62) ; U23.3 42.59,101.25 v7(42.16,101.68) ; v11(97.42,87.88) 97.42,88.13 C406.1 96.62,88.31 v11(96.62,87.88) ; v7(57.4,95.97) C190.1 56.53,96.11 U25.3
  vias: v6(92.61,97.66) v6(93.62,97.33) v6(136.53,135.72) v6(137.03,136.23) v6(138.05,135.34) v6(138.84,135.13) v6(139.57,135.08) v7(45.09,97.54) v7(46.35,97.54) v7(47.62,97.54) v7(120.52,127.64) v7(120.52,126.36) v7(120.52,125.09) v7(178.19,8.64) v7(179.34,9.71) v8(92.84,98.3) v8(93.73,98.3) v8(137.64,136.48) v8(137.64,135.84) v8(138.43,136.48) v8(138.43,135.84) v8(139.07,135.97) v9(92.84,98.3) v9(93.73,98.3) v9(137.64,136.48) v9(137.64,135.84) v9(138.43,136.48) v9(138.43,135.84) v9(139.07,135.97)
V1_8D_OUT: length 4.3
  TOP w0.508: J1_1.2 179.05,4.33 ; J1_1.2 177.53,2.81 ; J1_1.2 179.05,2.81 ; J1_1.2 177.53,4.33
V1_8FTDI: length 15.6
  TOP w0.203: 160.2,86.75 160.64,86.3 U37.64
  TOP w0.254: 168.14,87.21 U37.49
  TOP w0.305: 157.2,78.23 157.5,78.23 157.66,78.39 U37.12 ; U37.37 172.49,78.39 C227.1
  TOP w0.381: v7(172.72,79.08) 172.52,78.87 C227.1 ; 160.2,86.75 160.03,86.91 160.03,87.41 160.2,87.57 C235.1 v7(159.28,88.27) ; v7(168.94,88.4) 168.33,88.4 C232.1 168.14,88.21 168.14,87.21 ; v7(156.13,79.06) C238.1 156.27,78.23 157.2,78.23
  BOTTOM w0.381: C241.1 158.75,87.81 v7(158.71,87.85) 158.87,87.85 v7(159.28,88.27)
V1_8PHY_HDMI: length 3
  TOP w0.254: U1.Y17 v4(97.44,79.22)
  L3_SIG1 w0.254: v4(97.44,79.22) v6(97.04,78.97)
  L10_SIG4 w0.254: v11(96.79,79.37) v6(97.04,78.97)
  BOTTOM w0.381: 97.41,78.08 96.79,78.7 v11(96.79,79.37)
  vias: v6(81.15,78.49) v6(81.53,79.38) v8(82.55,79.88) v8(82.55,78.99) v9(82.55,79.88) v9(82.55,78.99)
V1_8PHY_LDO3: length 2.9
  TOP w0.254: U3.K11 143.01,123.17 v1(143.03,123.17)
  L10_SIG4 w0.381: v6(86.45,82.58) 85.84,82.58 v6(85.83,82.57) 85.1,82.57 v6(85.09,82.58)
  BOTTOM w0.381: C392.1 143.26,123.4 v1(143.03,123.17)
  vias: v6(86.01,84.29) v6(86.89,84.23) v10(84.84,85.91) v10(84.84,85.15) v10(85.34,85.91) v10(85.34,85.15) v10(85.85,85.15) v10(86.49,85.15) v11(84.84,85.91) v11(84.84,85.15) v11(85.34,85.91) v11(85.34,85.15) v11(85.85,85.15) v11(86.49,85.15)
V1_8PHY_LDO4:
  vias: v6(78.61,78.61) v6(78.61,77.6) v6(79.38,78.11) v6(87.35,85.78) v6(88.16,85.78) v6(145.03,126.87) v6(145.8,127.38) v8(78.61,74.93) v8(78.61,74.17) v8(79.25,74.93) v8(79.25,74.17) v8(146.56,126.87) v8(147.32,126.87) v9(78.61,74.93) v9(78.61,74.17) v9(79.25,74.93) v9(79.25,74.17) v9(146.56,126.87) v9(147.32,126.87)
V1_8PHY_PCIE: length 6.2
  TOP w0.254: U1.AA16 v4(96.64,80.02) ; U1.W14 v4(98.24,82.41) ; U1.AA17 v4(96.64,79.22)
  L3_SIG1 w0.254: v4(98.24,82.41) v6(97.84,82.66) ; v4(96.64,79.22) v6(96.24,78.97) ; v4(96.64,80.02) v6(96.24,79.77)
  L4_SIG2 w0.381: v6(96.24,78.97) v6(96.24,79.77)
  L10_SIG4 w0.254: v11(98.24,82.42) v6(97.84,82.66) ; v6(96.24,79.77) 96.22,79.77 v11(95.89,80.1)
  BOTTOM w0.381: v11(98.24,82.42) 97.96,82.42 97.26,81.72 C394.1
V1_8PHY_SATA: length 15.2
  TOP w0.254: U1.V13 v4(99.04,83.21)
  L3_SIG1 w0.254: v4(99.04,83.21) v6(98.64,83.46)
  L10_SIG4 w0.254: v11(98.96,83.01) 98.71,83.16 v6(98.64,83.46)
  L10_SIG4 w0.381: v9(83.19,81.28) v9(83.82,81.28) 84.07,81.28 84.84,80.52
  L10_SIG4 w0.508: v6(94.82,80.44) 94.79,80.41 92.4,80.41
  L10_SIG4 w0.635: 84.84,80.52 86.29,80.52 86.73,80.08 87.54,80.08 88.35,79.27 91.26,79.27 92.4,80.41
  BOTTOM w0.381: C564.1 99.31,83.36 v11(98.96,83.01)
V1_8PHY_USB: length 8
  TOP w0.254: U1.W12 v4(98.24,84.01) ; U1.AA13 v4(96.64,83.21) ; U1.AB12 v4(95.84,84.01)
  L3_SIG1 w0.254: v4(95.84,84.01) v6(95.44,84.26) ; v4(96.64,83.21) 96.24,83.46 v6(96.24,83.46) ; v6(97.84,84.26) v4(98.24,84.01)
  L10_SIG4 w0.254: v11(95.84,84.02) v6(95.44,84.26) ; v11(96.64,83.22) v6(96.24,83.46)
  BOTTOM w0.381: C391.1 C390.1 94.77,84.54 95.02,84.28 95.57,84.28 v11(95.84,84.02) v11(96.64,83.22)
  vias: v8(89.18,85.19) v8(89.81,85.04) v9(89.18,85.19) v9(89.81,85.04)
V1_8PLL: length 6
  TOP w0.152: 137.45,130.34 v7(137.45,131.39)
  TOP w0.254: U1.AD16 v4(94.24,80.02) ; U1.AE16 v4(93.44,80.02)
  TOP w0.381: U3.B5 137.45,130.34 ; v7(137.45,131.39) v7(137.45,132.15)
  L3_SIG1 w0.254: v4(94.24,80.02) v6(93.84,79.77) ; v4(93.44,80.02) v6(93.04,79.77)
  BOTTOM w0.381: C382.1 137.45,130.67 v7(137.45,131.39) v7(137.45,132.15)
  vias: v6(112.73,81.79) v6(113.61,81.79) v6(114.5,81.79) v6(115.39,81.79) v7(123.95,106.63) v7(124.59,106.25) v8(113.64,81.16) v8(114.43,81.13) v8(115.16,81.11) v8(115.82,81.11) v9(113.64,81.16) v9(114.43,81.13) v9(115.16,81.11) v9(115.82,81.11)
V1_8PLLA: length 7.8
  TOP w0.254: U1.R17 v4(101.44,79.22) ; U1.M14 v4(104.63,82.41) ; U1.N16 v11(103.83,80.02) ; U1.R14 v4(101.44,82.41)
  L3_SIG1 w0.254: v4(101.44,79.22) v6(101.04,78.97) ; v11(103.83,80.02) v6(104.23,79.77) ; v4(101.44,82.41) v6(101.04,82.66)
  L10_SIG4 w0.254: v6(101.04,78.97) 100.22,78.97 v11(100.13,78.87) ; v11(103.83,80.02) v6(104.23,79.77) ; v11(101.44,82.42) v6(101.04,82.66)
  BOTTOM w0.254: v11(101.44,82.42) 101.37,82.48 C380.1 ; v11(103.83,80.02) 103.63,79.81 C442.1 ; C381.1 100.51,79.33 100.13,78.95 v11(100.13,78.87)
  vias: v6(106.43,81.49) v6(107.31,81.49) v6(108.2,81.49) v6(109.09,81.49) v10(112.17,84.1) v10(112.73,84.11) v10(113.26,84.16) v11(112.17,84.1) v11(112.73,84.11) v11(113.26,84.16)
V1_8PLLB: length 7.5
  TOP w0.254: U1.P16 v11(103.03,80.02) ; U1.P14 v4(103.03,82.41) ; U1.N12 v4(103.83,84.01) ; U1.P15 v11(103.03,80.82) ; U1.N11 v4(103.83,84.81)
  L3_SIG1 w0.254: v6(104.23,85.06) 104.23,85.06 v4(103.83,84.81) ; v6(104.23,84.26) 104.23,84.26 v4(103.83,84.01) ; v11(103.03,80.02) v6(103.43,79.77) ; v11(103.03,80.82) v6(103.43,80.57) ; v6(103.43,82.66) v4(103.03,82.41)
  L10_SIG4 w0.254: v11(103.83,84.02) v6(104.23,84.26) ; v11(103.03,80.82) v6(103.43,80.57) ; v11(103.03,82.42) v6(103.43,82.66) ; v11(103.83,84.82) v6(104.23,85.06) ; v11(103.03,80.02) v6(103.43,79.77)
V3_3ACDCM: length 4.2
  TOP w0.381: C321.1 33.28,36.66 v7(33.27,36.65)
  BOTTOM w0.254: U45.4 v7(33.27,36.65) ; 32.36,38.15 U45.1
  BOTTOM w0.381: C322.1 33.02,38.82 32.36,38.15
  vias: v7(30.23,40.21) v7(32.77,40.47) v7(33.78,40.72)
V3_3APCIE: length 13.6
  TOP w0.381: C308.1 25.01,35.51 v7(25.65,36.15)
  BOTTOM w0.254: U45.20 v7(25.65,36.15) ; U45.9 31.34,33.64 31.5,33.48 C310.1 ; v7(25.91,34.88) 26.18,35.15 U45.18
  BOTTOM w0.381: U45.16 27.78,33.93 27.43,33.58 C309.1
  BOTTOM w0.508: v7(17.78,39.07) C326.1 18.58,39.11 Y7.4 ; C310.1 v7(32.26,32.09) ; R548.2 v7(29.46,30.31) ; R546.2 v7(35.31,34.63) ; R549.2 v7(30.48,30.31)
  vias: v7(25.27,33.36)
V3_3AUX_PCIE: length 9.7
  TOP w0.508: R654.2 v7(56.9,24.13) ; C556.1 v7(53.98,25.98)
  BOTTOM w0.508: J49.2 54.02,43.86 ; J49.2 52.41,43.86 ; J49.2 54.02,42.25 ; J49.2 52.41,42.25 ; J22.B10 55.24,28.05 ; J22.B10 55.24,29.27 ; J22.B10 54.02,28.05 ; J22.B10 54.02,29.27
V3_3D: length 322
  TOP w0.203: C420.1 173.39,73.45 U65.8
  TOP w0.254: U1.AF5 v4(92.64,89.61) ; U1.AD7 v4(94.24,88.01) ; U1.U10 v4(99.84,85.61) ; U1.H15 v4(107.83,80.82) ; U1.H8 v4(107.83,87.21) ; U1.H10 v4(107.83,85.61) ; U1.E16 v4(110.23,80.02) ; C130.1 31.75,78.06 U15.21 ; U1.H9 v4(107.83,86.41) ; U1.E3 v4(110.23,91.21) ; U1.N5 v4(103.83,89.61) ; U1.H19 v4(107.83,77.62) ; v4(92.95,87.8) 92.96,87.8 93.18,87.58 93.8,87.58 U1.AE7 ; U1.D22 v11(111.03,75.22) ; U1.H16 v4(107.83,80.02) ; v1(140.65,127.94) U3.D9 v1(141.44,128.73) ; U1.N4 v4(103.83,90.41) ; U1.E22 v4(110.23,75.22) ; U1.G4 v4(108.63,90.41) ; U1.B6 v4(112.63,88.81) ; U1.D16 v4(111.03,80.02) ; C120.1 31.75,95.84 U13.21 ; U1.J8 v4(107.03,87.21) ; U1.G15 v4(108.63,80.82) ; U1.AB7 v4(95.84,88.01) ; U1.C24 v4(111.83,73.62) ; U1.W5 v4(98.24,89.61) ; U1.D10 v4(111.03,85.61) ; U1.E10 v4(110.23,85.61) ; U1.R7 v4(101.44,88.01) ; U1.V12 v4(99.04,84.01) ; U1.P10 v4(103.03,85.61) ; U1.G5 v4(108.63,89.61) ; U1.B23 v4(112.63,74.42) ; U1.R10 v4(101.44,85.61) ; U1.T4 v4(100.64,90.41) ; U1.H11 v4(107.83,84.81) ; U1.T5 v4(100.64,89.61) ; U1.AD5 v4(94.24,89.61) ; U1.K8 v4(106.23,87.21) ; U1.W4 v4(98.24,90.41) ; U1.AB6 v4(95.84,88.81) ; U1.E5 v4(110.23,89.61) ; U1.H18 v4(107.83,78.42)
  TOP w0.279: C428.1 68.22,13.23 U46.24
  TOP w0.305: C144.1 31.75,53.3 U17.21 ; U8.10 108.82,12.64 109.09,12.37
  TOP w0.381: v1(97.39,128.45) 97.41,128.47 C350.1 ; v6(124.59,64.47) v5(125.35,64.47) ; R97.1 24.25,124.68 v7(24.51,124.41) v7(25.15,124.41) ; C144.1 v7(32.46,53.29) ; v7(112.39,110.19) R446.2 R445.2 ; R790.2 v7(16.89,44.15) ; R22.2 v7(88.9,108.29) ; R559.2 v7(66.42,23.88) ; C409.1 147.07,98.2 v1(147.11,98.24) ; R120.2 v7(29.59,91.9) ; C408.1 147.07,95.69 v1(147.11,95.64) ; v7(24.71,118.01) 24.05,118.01 C105.1 ; v6(128.4,72.47) v5(129.07,72.47) ; R435.2 R442.2 v7(109.86,114.64) ; R545.2 v7(54.86,39.5) ; v5(129.16,69.42) 129.03,69.3 R383.2 ; R506.2 v7(85.6,126.45) ; R366.2 176.78,54.44 v7(176.4,54.06) ; R543.1 v7(50.67,39.5) ; U85.5 57.52,43.68 C470.1 v7(58.34,43.66) ; R811.1 v7(154.69,140.08) ; v7(19.71,4.83) 19.37,5.17 D18.1 ; R441.2 v7(111.73,113.87) ; C428.1 v7(68.2,12.4) ; v7(110.36,110.19) R444.2 R443.2 ; v7(100.23,125.43) 100.23,124.77 R799.2 ; 131.19,70.31 v5(131.19,69.55) 131.19,68.79 ; v7(99.44,123.65) C28.1 U4.2 ; v5(83.92,92.99) 84.28,93.34 R800.2 ; v7(86.49,121.75) 86.36,121.87 R512.2 ; R507.2 v7(86.36,124.54) ; R510.2 v7(86.36,127.34) ; v7(106.68,110.19) R449.2 R447.2 ; v7(70.36,103.21) 70.17,103.02 D23.1 ; v7(58.42,38.23) C469.1 57.55,38.24 U44.5 ; R423.2 v7(176.53,92.16) ; R439.2 R436.2 104.34,109.5 v7(104.34,110.16) ; R679.2 159.47,117.39 v7(159.51,117.43) ; U47.5 128.13,46.88 C214.1 v7(128.14,47.66) ; R505.2 v7(85.6,129.24) ; v6(124.59,69.3) v5(125.35,69.3) ; v7(107.82,114.64) R438.2 R437.2 ; R544.1 v7(52.58,39.5) ; v7(96.92,132.92) C479.1 v7(95.76,131.78) ; R649.2 v7(45.59,39.5) ; R448.2 v7(114.17,109.43) ; C410.1 148.6,92.66 v1(148.54,92.72) ; R563.2 v7(129.1,66.88) ; v1(96.39,125.95) 96.4,125.94 C258.1 ; R412.2 v7(78.49,147.66) ; R509.2 v7(88.39,133.18) ; D17.1 v5(15.56,4.91) ; D16.1 v5(11.37,4.91) ; v1(93.88,126.19) 93.85,126.17 93.85,125.43 ; R201.2 v7(29.59,49.15) ; R152.2 v7(37.9,99.4) ; D19.1 v7(23.31,7.54) ; R511.2 v7(85.6,123.65) ; R434.2 R440.2 102.23,109.81 v7(102.62,110.19) ; R508.2 v7(90.3,132.42) ; v1(94.88,128.44) 94.88,129.23 C257.1 ; v1(139.85,123.94) U3.J8 140.26,124.34 v1(140.64,123.96) ; v7(97.02,113.17) 97.09,113.17 97.41,112.85 97.41,111.71 ; D22.1 v7(73.6,103.14) ; C130.1 v7(32.5,78.06) ; v1(96.38,124.96) 96.39,124.95 C256.1 ; J15.4 v7(99.29,149.74) ; v6(128.4,64.85) v5(129.16,64.85) ; C120.1 v7(32.5,95.84)
  TOP w0.508: v7(27.45,77.26) 27.49,77.26 27.7,77.04 R159.2 ; v7(23.49,107.4) R143.1 ; R145.1 v7(23.62,103.33) ; C432.1 131.19,7.62 131.44,7.87 ; R183.1 v7(23.62,86.57) ; v7(23.49,64.85) R224.1 ; J1_1.3 176.51,2.81 ; J1_1.3 174.99,2.81 ; J1_1.3 174.99,4.33 ; J1_1.3 176.51,4.33 ; R184.1 v7(23.62,85.55) ; R144.1 v7(23.62,104.35) ; v7(27.3,51.9) 27.69,52.28 R200.2 ; R185.1 v7(23.62,82.38) ; v7(24.38,99.4) 24.38,99.41 R146.1 ; R227.1 v7(23.62,57.61) ; R225.1 v7(23.62,61.8) ; v7(23.24,89.62) R182.1 ; R131.2 v7(27.69,94.06) ; R226.1 v7(23.62,60.79)
  TOP w0.635: U74.4 C432.1
  L3_SIG1 w0.254: v4(92.95,87.8) 92.96,87.81 92.96,87.82 92.96,87.82 92.96,87.84 93.04,87.95 v6(93.04,88.26) ; v6(97.84,90.66) v4(98.24,90.41) ; v4(100.64,90.41) 100.24,90.66 v6(100.24,90.66) ; v6(108.23,87.46) 108.23,87.46 v4(107.83,87.21) ; v4(95.84,88.01) v6(95.44,88.26) ; v6(104.23,90.66) 104.23,90.66 v4(103.83,90.41) ; v4(108.63,80.82) v6(109.03,80.57) ; v11(111.03,75.22) v6(111.43,74.97) ; v6(108.23,85.86) 108.23,85.86 v4(107.83,85.61) ; v4(110.23,80.02) v6(110.63,79.77) ; v4(94.24,89.61) v6(93.84,89.86) ; v4(103.83,89.61) 104.23,89.86 v6(104.23,89.86) ; v4(111.03,80.02) v6(111.43,79.77) ; v6(110.64,74.91) 110.63,74.97 v4(110.23,75.22) ; v6(100.24,89.86) 100.24,89.86 v4(100.64,89.61) ; v4(94.24,88.01) v6(93.84,88.26) ; v4(92.64,89.61) 92.24,89.86 v6(92.24,89.86) ; v4(111.83,73.62) v6(112.23,73.37) ; v4(106.23,87.21) v6(106.63,87.46) ; v4(107.03,87.21) v6(107.43,87.46) ; v4(110.23,85.61) v6(110.63,85.86) ; v6(98.64,84.26) v4(99.04,84.01) ; v4(108.63,90.41) v6(109.03,90.66) ; v4(107.83,77.62) v6(108.23,77.37) ; v6(108.23,85.06) 108.23,85.06 v4(107.83,84.81) ; v6(97.84,89.86) v4(98.24,89.61) ; v6(101.04,85.86) v4(101.44,85.61) ; v6(99.44,85.86) v4(99.84,85.61) ; v4(107.83,80.82) v6(108.23,80.57) ; v4(112.63,88.81) v6(113.03,89.06) ; v6(108.23,86.66) 108.23,86.66 v4(107.83,86.41) ; v4(111.03,85.61) v6(111.43,85.86) ; v4(112.63,74.42) v6(113.03,74.17) ; v4(107.83,80.02) v6(108.23,79.77) ; v6(103.43,85.86) v4(103.03,85.61) ; v4(110.23,89.61) v6(110.63,89.86) ; v4(101.44,88.01) v6(101.04,88.26) ; v4(95.84,88.81) v6(95.44,89.06) ; v4(110.23,91.21) v6(110.63,91.46) ; v4(108.63,89.61) v6(109.03,89.86) ; v4(107.83,78.42) v6(108.23,78.17)
  L3_SIG1 w0.381: v5(125.35,64.47) v6(124.59,64.47) ; v5(125.35,69.3) v6(124.59,69.3) ; v5(83.92,92.99) 83.97,92.94 84.61,92.94 v6(84.66,92.99) ; v5(129.07,72.47) v6(128.4,72.47) ; v5(11.37,4.91) v6(11.37,4.15) ; v5(15.56,4.91) v6(15.56,4.15) ; v5(131.19,69.55) 131.73,69.55 v6(131.95,69.77) ; v5(129.16,64.85) v6(128.4,64.85) ; v5(129.16,69.42) v6(128.4,69.42)
  L7_PWR2 w0.381: v6(108.23,79.77) v6(108.23,80.57)
  L7_PWR2 w0.508: J22.A10 55.24,35.77 ; J22.A10 55.24,34.55 ; J22.A10 54.02,35.77 ; J22.A10 54.02,34.55 ; 49.87,42.25 J49.1 ; J49.1 51.48,43.86 ; J49.1 49.87,43.86 ; J49.1 51.48,42.25 ; 52.02,29.27 J22.B8 ; J22.B8 53.24,28.05 ; J22.B8 52.02,28.05 ; J22.B8 53.24,29.27 ; 53.02,32.55 J22.A9 ; J22.A9 54.24,33.77 ; J22.A9 54.24,32.55 ; J22.A9 53.02,33.77 ; 100.63,147.74 J21.1 ; J21.1 102.06,146.3 ; J21.1 100.63,146.3 ; J21.1 102.06,147.74
  L10_SIG4 w0.254: v11(107.79,87.82) v6(107.43,87.46) ; v11(111.03,75.22) 111.16,75.14 v6(111.43,74.97) ; v11(106.99,87.77) 106.96,87.77 106.93,87.74 106.91,87.74 v6(106.63,87.46) ; v11(99.84,85.62) v6(99.44,85.86) ; v11(108.64,85.47) v6(108.23,85.06) ; v6(108.23,87.46) 107.97,87.2 v11(107.84,87.2) ; v11(111.18,79.37) v6(111.43,79.77) ; v11(108.63,87.06) v6(108.23,86.66) ; v11(101.44,85.62) v6(101.04,85.86) ; v6(110.64,74.91) 110.64,74.96 110.31,75.23 v11(110.31,75.26) ; v11(108.63,86.27) v6(108.23,85.86) ; v11(110.99,80.12) v6(110.63,79.77)
  L10_SIG4 w0.381: v9(27.11,121.11) v6(26.42,121.11) ; v9(137.62,112.52) v6(138.3,112.52)
  BOTTOM w0.203: U75.3 170.84,63.64
  BOTTOM w0.254: U89.K9 v1(147.11,98.24) ; U43.K9 v1(96.39,125.95) ; C219.1 55.04,89.31 54.74,89.01 J17.5 ; U43.J10 v1(96.38,124.96) ; v1(97.39,128.45) U43.M4 U43.N4 U43.P3 v1(99.42,129.49) v1(99.42,130.26) ; v1(99.44,127.77) 99.26,127.95 U43.P5 ; v1(93.88,126.19) v1(93.88,126.95) 94.23,127.3 94.24,127.3 U43.E6 ; v1(153.42,99.52) 153.4,99.52 U89.B10 ; U43.F5 v1(94.88,128.44) ; U89.K5 v1(147.11,95.64) ; U89.H1 v1(148.54,92.72)
  BOTTOM w0.305: U9.21 24.46,118.45 24.71,118.19 v7(24.71,118.01) ; v7(90.81,146.2) 90.8,146.2 U30.10 ; U92.10 161.99,56.49 162.26,56.22
  BOTTOM w0.381: C127.1 31.75,92.5 31.76,92.49 U69.5 ; U71.5 26.81,49.26 26.8,49.28 C151.1 ; v7(28.32,60.28) 28.69,59.91 R222.1 29.34,60.91 v7(28.96,61.3) ; v7(185.18,96.21) R731.2 ; C219.1 v7(55.72,90.05) ; R18.2 144.7,127.64 147.37,127.64 v7(147.45,127.72) ; v7(28.32,85.04) 28.69,84.67 R180.1 29.34,85.75 v7(29.05,86.04) ; R782.2 163.96,56.2 C532.1 ; v7(59.05,64.6) C248.1 59.93,64.61 U39.5 ; R498.2 v7(61.21,62.82) ; v7(39.34,100.06) 39.34,100.11 39.01,100.44 C170.1 38.63,99.73 v7(38.81,99.55) ; v11(101.44,85.62) 101.24,85.81 C363.1 101.04,86.11 100.33,86.11 v11(99.84,85.62) ; v7(167.26,44.91) 167.51,45.17 C3.1 ; R121.2 v7(22.23,98.76) ; v7(168.78,45.17) 169.37,45.76 R10.2 ; R917.2 v7(166.24,47.42) ; R551.2 v7(23.37,13.34) ; v7(26.8,74.88) 26.8,74.12 26.81,74.11 U70.5 ; v7(173.66,80.01) v7(173.02,80.01) R472.2 ; v7(99.29,149.74) 98.35,149.74 C211.1 ; v6(138.3,112.52) v9(137.62,112.52) ; v7(27.94,102.82) 28.31,102.45 R141.1 29.34,103.21 28.96,103.59 v7(28.96,103.71) ; v11(110.31,75.26) 110.31,75.27 110.31,75.32 C385.1 111.03,75.71 v11(111.03,75.22) ; R422.2 182.79,92.66 182.83,92.63 183.2,92.63 v7(183.41,92.41) ; R107.2 v7(42.29,86.31) ; R902.2 v7(164.85,147.83) ; R808.2 v7(10.03,43.18) ; v7(57.52,87.28) 56.78,87.28 R420.1 ; R259.2 v7(177.95,132.16) ; v7(188.75,87.58) 188.24,87.58 187.87,87.22 U19.5 ; U41.1 C251.1 v7(171.2,23.07) ; R149.2 185.57,83.14 v7(185.47,83.04) ; R421.2 v7(10.67,33.3) ; C191.1 53.47,95.97 v7(53.29,96.14) ; v7(96.27,145.96) C212.1 v7(97.28,146.94) ; U33.8 C220.1 12.78,31.5 v7(12.8,31.52) ; R100.1 v7(20.38,124.34) ; R102.1 C107.1 v7(23.37,131.15) ; v7(187.73,97.74) C319.1 187.75,96.71 U78.5 ; v7(161.04,50.69) 161.78,50.69 C569.1 161.81,50.69 U97.5 ; 6.73,46.69 v7(6.73,47.58) ; v7(16.64,122.38) C104.1 17.33,122.45 R99.1 v7(16.52,123.53) ; R741.2 v7(95.76,136.35) ; X1.4 v7(165.99,145.57) ; U39.2 v7(60.58,69.3) ; R450.2 v7(185.32,88.47) ; R122.2 v7(7.19,116.49) ; 170.84,63.64 170.84,62.87 v7(170.66,62.69) ; R160.2 v7(23.37,73.92) ; 6.73,119.72 v7(6.73,120.48) ; U68.5 43.05,90.58 v7(43.05,92.66) ; R190.2 v7(28.96,71.71) ; R232.2 v7(38.73,57.74) ; R410.2 R417.2 ; U2.5 v7(168.22,43.84) ; U98.5 162.93,41.29 C571.1 v7(162.18,41.27) ; v7(181.51,99.4) C221.1 R730.2 ; R161.2 v7(7.24,92.54) ; R101.1 v7(21.79,126.7) ; v6(26.42,121.11) v9(27.11,121.11) ; R513.2 v7(94.36,104.48) ; R914.2 v7(164.55,52.45) ; v7(157.61,100.41) 157.73,100.28 R637.1 ; R78.2 v7(7.24,140.8) ; R77.2 v7(21.67,136.99) ; 6.73,71.46 v7(6.73,72.19) ; R203.2 v7(7.24,67.77) ; R134.2 v7(6.69,96.35)
  BOTTOM w0.508: 174.99,2.81 J1_1.3 ; J1_1.3 176.51,2.81 ; J1_1.3 176.51,4.33 ; J1_1.3 174.99,4.33 ; v7(23.62,61.8) 23.62,62.06 C145.1 ; R419.2 v7(154.88,102.44) ; R184.1 v7(23.62,85.55) ; C133.1 23.62,86.82 v7(23.62,86.57) ; J46.3 169.33,5.63 ; J46.3 167.72,7.24 ; J46.3 169.33,7.24 ; J46.3 167.72,5.63 ; R153.2 v7(33.15,91) ; R782.2 v7(163.96,57.87) ; R233.2 v7(28.19,47.69) ; R417.2 v7(76.83,140.03) ; C119.1 23.62,104.6 v7(23.62,104.35) ; R678.2 v7(69.72,117.18) ; R783.2 v7(163.83,59.52) ; v7(27.69,49.1) 27.56,49.23 27.32,49.23 27.19,49.36 C151.1 ; R202.2 v7(23.37,48.85) ; R145.1 v7(23.62,103.33) ; R226.1 v7(23.62,60.79) ; v7(23.37,97.74) R121.2 ; C127.1 v7(32.5,92.66)
  vias: v6(34.04,97.28) v6(35.18,97.28) v6(37.08,97.28) v6(86.73,94.91) v6(87.31,94.34) v6(87.81,93.7) v6(118.87,86.06) v6(119.63,86.06) v6(120.4,86.06) v7(23.11,28.53) v7(23.11,27.89) v7(24,28.53) v7(24,27.89) v7(28.32,43.77) v7(28.32,43.13) v7(28.78,113.34) v7(28.78,112.58) v7(29.08,43.77) v7(29.08,43.13) v7(29.54,113.34) v7(29.54,112.58) v7(32.51,77.42) v7(33.1,53.27) v7(33.27,95.84) v7(48.77,122.64) v7(49.28,123.14) v7(50.04,123.14) v7(50.29,110.06) v7(50.29,109.3) v7(51.05,110.06) v7(51.05,109.3) v7(53.24,97.64) v7(53.26,96.88) v7(75.06,111.33) v7(75.95,111.33) v7(114.3,15.07) v7(114.3,14.18) v7(115.44,15.07) v7(115.44,14.18) v7(132.72,14.1) v7(133.99,14.1) v7(135.26,14.1) v7(135.26,13.04) v7(161.16,36.53) v7(161.93,36.53) v7(162.69,36.53) v7(163.2,16.34) v7(163.2,15.19) v7(164.21,16.34) v7(164.21,15.32) v7(172.21,73.87) v7(173.46,64.6) v7(176.15,99.65) v7(176.15,98.38) v7(176.15,97.11) v7(176.15,95.84) v7(176.15,94.57) v7(176.15,81.74) v7(177.04,81.74) v7(177.8,81.74) v8(34.16,97.92) v8(35.43,97.92) v8(36.7,97.92) v9(34.16,97.92) v9(35.43,97.92) v9(36.7,97.92) v10(86.11,94.68) v10(86.27,93.55) v10(86.27,93.05) v10(118.75,86.7) v10(119.25,85.04) v10(120.27,85.09) v11(86.11,94.68) v11(86.27,93.55) v11(86.27,93.05) v11(118.75,86.7) v11(119.25,85.04) v11(120.27,85.09)
V3_3D_PROFIA: length 3.6
  TOP w0.508: v7(130.56,3.81) v7(129.67,3.81) v7(128.87,3.81) U74.1
V3_3D_PROFIB: length 3.6
  TOP w0.508: v7(130.56,5.08) v7(129.67,5.08) v7(128.87,5.08) U74.2
V3_3D_PRU1ETH0JCK: length 4.1
  BOTTOM w0.508: 20.41,132.16 19.69,131.44 18.97,132.16 ; 17.87,132 J3.3 17.87,133.43
V3_3D_PRU1ETH1JCK: length 8.1
  BOTTOM w0.508: J5.4 20.41,108.03 ; J5.4 18.97,108.03 ; J5.4 20.41,106.6 ; J5.4 18.97,106.6 ; 16.43,107.87 J5.3 ; J5.3 17.87,107.87 ; J5.3 17.87,109.3 ; J5.3 16.43,109.3
V3_3D_PRU2ETH0JCK: length 8.1
  BOTTOM w0.508: J6.4 20.41,82.47 ; J6.4 20.41,83.9 ; J6.4 18.97,83.9 ; J6.4 18.97,82.47 ; 16.43,83.74 J6.3 ; J6.3 16.43,85.17 ; J6.3 17.87,83.74 ; J6.3 17.87,85.17
V3_3D_PRU2ETH1JCK: length 8.1
  BOTTOM w0.508: 16.43,60.41 J8.3 ; J8.3 17.87,60.41 ; J8.3 17.87,58.98 ; J8.3 16.43,58.98 ; 18.97,59.14 J8.4 ; J8.4 20.41,59.14 ; J8.4 18.97,57.71 ; J8.4 20.41,57.71
V3_3FTDI: length 32.7
  TOP w0.203: U65.1 173.39,69.94 C425.1
  TOP w0.254: U37.42 172.5,80.89 C233.1 172.52,81.54 v7(172.72,81.74) ; U37.31 167.64,72.87 v7(167.81,72.7) ; v7(162.23,72.78) 162.14,72.87 U37.20
  TOP w0.305: 164.64,87.13 U37.56 ; 167.64,86.82 U37.50
  TOP w0.381: 164.64,87.13 164.64,87.25 v7(164.64,87.25) ; R485.2 v7(154.23,77.35) ; C239.1 v7(162.23,72.78) ; 167.64,86.82 167.18,87.27 C242.2 v7(166.42,88.27) ; C229.1 167.94,72.56 v7(167.81,72.7)
  BOTTOM w0.203: C448.1 171.64,67.08 U75.8
  BOTTOM w0.381: 163.75,77.98 FB11.2 ; 163.75,77.98 164.45,77.28 v7(164.45,77.09) ; 163.75,77.98 163.75,77.6 v7(163.25,77.09) ; C245.1 v7(170.39,91.52) ; v7(164.97,83.7) 164.26,83.7 163.75,84.21 FB10.2 164.12,84.59 v7(164.78,84.59) ; U34.5 165.77,79.52 C228.2 165.79,78.87 v7(165.61,78.69) ; R496.2 163.63,87.13 v7(163.88,87.38) ; C236.1 v7(164.64,87.25) ; v7(168.28,80.01) v7(168.91,80.01) R472.1 ; U35.5 157.41,75.71 C230.2 v7(156.97,74.5)
  vias: v7(168.83,78.36) v7(169.63,91.52) v7(171.25,81.92) v7(171.63,82.43) v7(171.63,81.4) v7(172.21,69.8) v7(172.47,67.01)
V3_3USB: length 7.3
  TOP w0.254: U1.Y12 v4(97.44,84.01) ; v1(141.44,129.54) U3.B9 v1(141.44,130.33) ; U1.AA12 v4(96.64,84.01)
  L3_SIG1 w0.254: v6(96.24,84.26) 96.24,84.26 v4(96.64,84.01) ; v4(97.44,84.01) v6(97.04,84.26)
  L10_SIG4 w0.254: v11(97.44,84.02) v6(97.04,84.26) ; v11(96.64,84.02) v6(96.24,84.26)
  BOTTOM w0.381: v11(97.44,84.02) 97.21,83.79 C401.1 ; C400.1 96.72,84.1 v11(96.64,84.02) ; C399.1 141.73,130.62 v1(141.44,130.33) v1(141.44,129.54)
  vias: v6(82.66,93.53) v6(83.39,93.55) v6(84.3,93.57) v6(85.33,93.57) v6(85.67,91.86)
V5_0D: length 27.2
  TOP w0.279: U46.11 61.72,22.86
  TOP w0.381: R386.1 175.67,37.49 v7(175.67,38.23) ; v7(175.67,21.59) 175.67,22.33 R396.1 ; R392.1 175.67,26.64 v7(175.67,25.53) 175.67,24.54 R395.1 ; R562.2 v7(57.66,13.68) ; R390.1 175.67,31.01 v7(175.67,31.75) ; R389.1 175.67,33.17 v7(175.67,33.91) ; 61.72,22.86 C427.1 ; R388.1 v7(174.88,35.31) ; R560.2 v7(58.8,13.68) ; R391.1 175.67,28.85 v7(175.67,29.59)
  TOP w0.508: C427.1 v7(61.72,23.62)
  L6_PWR1 w0.508: J37.27 185.7,26.8 ; J37.27 184.18,26.8 ; J37.27 184.18,25.27 ; J37.27 185.7,25.27 ; 186.72,26.8 J37.28 ; J37.28 188.24,25.27 ; J37.28 188.24,26.8 ; J37.28 186.72,25.27
  L9_SIG3 w0.508: 100.63,149.74 J21.2 ; J21.2 102.06,148.3 ; J21.2 102.06,149.74 ; J21.2 100.63,148.3
  BOTTOM w0.254: U62.E2 U62.E1 156.69,106.74
  BOTTOM w0.381: v7(177.17,21.16) 178.12,22.11 C208.1 178.21,22.1 v7(179.22,21.08)
  vias: v7(20.19,45.93) v7(21.46,45.93) v7(25.78,4.95) v7(26.92,4.95) v7(160.02,105.75) v7(160.02,104.48) v7(161.29,105.75) v7(161.29,104.48) v7(170.69,99.27) v7(170.69,98) v7(171.96,99.27) v7(171.96,98) v7(174.88,148.54) v7(174.88,147.27) v7(174.88,146) v7(174.88,144.61) v7(175.01,143.21) v7(176.4,148.54) v7(176.4,147.27) v7(176.4,146) v7(176.4,144.61) v7(176.53,143.21) v7(178.18,148.54) v7(178.18,147.27) v7(178.18,146) v7(178.18,144.61) v7(178.31,143.21)
V5_0D_EN: length 1.6
  BOTTOM w0.173: R419.1 154.36,105.32 U62.A4
V5_0DFB: length 2.7
  BOTTOM w0.254: 156.91,105.76 156.7,105.76 156.51,105.94 U62.E3
  BOTTOM w0.381: 156.91,105.76 R424.1
  BOTTOM w0.635: R424.1 R427.2
V5_0HDMICONN: length 2.4
  TOP w0.279: v7(58.29,10.03) 58.65,9.68 J24.18
  TOP w0.381: C429.1 v7(59.77,14.75)
V5_0VOP: length 10.2
  TOP w0.381: v7(184.15,61.42) 182.75,60.03 182.75,57.49 180.72,55.45 C195.1 179.58,57.09 U28.5
V12_0D: length 59.9
  TOP w0.381: C196.1 187.45,59.08 J37.2 ; C303.1 v7(49.4,25.15) ; 46.61,37.72 v7(46.61,36.83)
  L7_PWR2 w0.508: J37.16 188.24,42.04 ; J37.16 186.72,40.51 ; J37.16 188.24,40.51 ; J37.16 186.72,42.04 ; J37.8 188.24,52.2 ; J37.8 186.72,52.2 ; J37.8 186.72,50.67 ; J37.8 188.24,50.67 ; 46.02,28.05 J22.B2 ; J22.B2 47.24,28.05 ; J22.B2 46.02,29.27 ; J22.B2 47.24,29.27 ; J37.6 188.24,53.21 ; J37.6 188.24,54.74 ; J37.6 186.72,54.74 ; J37.6 186.72,53.21 ; 186.72,45.59 J37.12 ; J37.12 188.24,45.59 ; J37.12 188.24,47.12 ; J37.12 186.72,47.12 ; J22.A3 48.24,33.77 ; J22.A3 48.24,32.55 ; J22.A3 47.02,33.77 ; J22.A3 47.02,32.55 ; 186.72,59.82 J37.2 ; J37.2 188.24,59.82 ; J37.2 186.72,58.29 ; J37.2 188.24,58.29 ; 46.02,34.55 J22.A2 ; J22.A2 46.02,35.77 ; J22.A2 47.24,34.55 ; J22.A2 47.24,35.77 ; 186.72,57.28 J37.4 ; J37.4 188.24,57.28 ; J37.4 186.72,55.75 ; J37.4 188.24,55.75 ; J22.B3 48.24,31.27 ; J22.B3 48.24,30.05 ; J22.B3 47.02,30.05 ; J22.B3 47.02,31.27 ; 186.72,44.58 J37.14 ; J37.14 188.24,43.05 ; J37.14 186.72,43.05 ; J37.14 188.24,44.58 ; J22.B1 46.24,31.27 ; J22.B1 45.02,31.27 ; J22.B1 45.02,30.05 ; J22.B1 46.24,30.05 ; 186.72,48.13 J37.10 ; J37.10 188.24,49.66 ; J37.10 188.24,48.13 ; J37.10 186.72,49.66
  BOTTOM w0.381: v7(185.29,77.12) R379.1 ; R379.1 v7(184.1,76.01) ; R379.1 v7(186.49,76.01)
  vias: v7(162.81,122.89) v7(164.21,124.41) v7(164.21,123.27) v7(164.21,122.13) v7(164.21,120.86) v7(188.21,129.24) v7(188.21,127.97) v7(188.21,126.7) v7(188.21,125.43) v7(188.21,124.16)
VDD_CORE: length 52.9
  TOP w0.254: U1.U16 v11(99.84,80.02) ; U1.V8 v4(99.04,87.21) ; U1.P13 v4(103.03,83.21) ; U1.H13 v4(107.83,83.21) ; U1.N13 v4(103.83,83.21) ; U1.U8 v4(99.84,87.21) ; U1.T19 v11(100.64,77.62) ; U1.L7 v4(105.43,88.01) ; U1.V16 v11(99.04,80.02) ; U1.U9 v4(99.84,86.41) ; U1.T13 v4(100.64,83.21) ; U1.R19 v11(101.44,77.62) ; U1.H14 v4(107.83,82.41) ; U1.T16 v11(100.64,80.02) ; U1.N10 v4(103.83,85.61) ; U1.L8 v4(105.43,87.21) ; U1.J17 v4(107.03,79.22) ; U1.P12 v4(103.03,84.01) ; U1.R16 v4(101.44,80.02) ; U1.P11 v4(103.03,84.81) ; U1.J18 v4(107.03,78.42) ; U1.U13 v4(99.84,83.21) ; U1.R11 v4(101.44,84.81)
  TOP w0.381: U3.B1 133.82,130.76 133.73,130.76 132.46,132.03 ; 132.46,132.8 132.46,132.03 ; 132.46,132.03 131.83,132.67
  L3_SIG1 w0.203: v11(101.44,77.62) v6(101.04,77.37) ; v11(100.64,77.62) v6(100.24,77.37)
  L3_SIG1 w0.254: v4(105.43,87.21) v6(105.83,87.46) ; v4(101.44,80.02) v6(101.04,79.77) ; v4(99.84,86.41) v6(99.44,86.66) ; v6(101.04,85.06) v4(101.44,84.81) ; v4(100.64,83.21) 100.24,83.46 v6(100.24,83.46) ; v4(103.83,83.21) 104.23,83.46 v6(104.23,83.46) ; v6(108.23,82.66) 108.23,82.66 v4(107.83,82.41) ; v4(103.03,83.21) v6(103.43,83.46) ; v4(99.04,87.21) v6(98.64,87.46) ; v4(103.03,84.01) v6(103.43,84.26) ; v4(99.84,87.21) v6(99.44,87.46) ; v4(105.43,88.01) v6(105.83,88.26) ; v6(103.43,85.06) v4(103.03,84.81) ; v4(99.84,83.21) v6(99.44,83.46) ; v6(108.23,83.46) 108.23,83.46 v4(107.83,83.21) ; v11(99.84,80.02) v6(99.44,79.77) ; v6(104.23,85.86) 104.23,85.86 v4(103.83,85.61) ; v11(100.64,80.02) v6(100.24,79.77) ; v4(107.03,78.42) v6(107.43,78.17) ; v4(107.03,79.22) v6(107.43,78.97) ; v11(99.04,80.02) v6(98.64,79.77)
  L10_SIG4 w0.254: v11(108.63,83.22) v6(108.23,83.46) ; v11(99.84,86.42) v6(99.44,86.66) ; v11(100.64,80.02) v6(100.24,79.77) ; v11(103.83,85.62) v6(104.23,85.86) ; v11(99.04,80.02) v6(98.64,79.77) ; v11(99.84,80.02) v6(99.44,79.77) ; v11(101.44,77.62) 101.4,77.6 101.19,77.39 101.07,77.39 v6(101.04,77.37) ; v11(107.83,82.91) v6(108.23,82.66) ; v11(101.44,84.82) v6(101.04,85.06) ; v11(99.84,87.22) v6(99.44,87.46) ; v11(103.03,84.02) v6(103.43,84.26) ; v11(103.03,84.82) v6(103.43,85.06) ; v11(103.03,83.22) v6(103.43,83.46) ; v11(100.64,77.62) v6(100.24,77.37)
  L10_SIG4 w0.381: v9(91.85,71.35) v6(91.85,70.76) ; v9(89.92,81.66) v6(89.15,81.66) ; v9(86.74,68.71) v6(86.16,68.71)
  BOTTOM w0.254: v11(101.44,77.62) v11(100.64,77.62) 100.51,77.49 C339.1 ; v11(103.83,85.62) v11(103.03,84.82) 102.83,85.02 C341.1 101.64,85.02 v11(101.44,84.82) ; v11(103.03,83.22) v11(103.03,84.02) 102.95,83.93 C343.1
  BOTTOM w0.381: v11(107.83,82.91) 108.14,83.22 v11(108.63,83.22) 108.8,83.38 108.93,83.38 109.15,83.6 C342.1 109.42,84.66 C574.1 ; v11(99.04,80.02) 99.31,80.29 C345.1 ; C573.1 91.95,71.45 v9(91.85,71.35) ; v11(100.64,80.02) 100.64,80.55 C344.1 99.93,80.4 99.93,80.11 v11(99.84,80.02) ; v9(86.74,68.71) C572.1 ; v6(89.15,81.66) v9(89.92,81.66) ; 99.84,86.42 100.38,86.97 ; 99.84,86.42 v11(99.84,86.42) ; 99.84,86.42 v11(99.84,87.22)
  vias: v6(79.25,84.07) v6(80.01,84.07) v6(112.14,77.22) v6(112.75,77.25) v6(113.46,77.24) v7(73.15,94.82) v7(73.15,93.55) v7(73.15,92.28) v7(74.55,94.37) v7(103.15,131.12) v7(104.55,132.16) v7(104.55,131.12) v7(104.55,129.85) v7(128.91,140.29) v7(128.91,139.4) v7(128.91,138.38) v7(129.79,140.29) v7(129.79,139.4) v7(129.79,138.38) v7(130.81,140.29) v7(130.81,139.4) v7(130.81,138.38) v8(79.25,84.71) v8(80.01,84.71) v8(112.39,77.81) v8(112.45,76.73) v8(113.44,76.3) v8(114.3,76.33) v9(79.25,84.71) v9(80.01,84.71) v9(112.39,77.81) v9(112.45,76.73) v9(113.44,76.3) v9(114.3,76.33)
VDD_DSPEVE: length 25.7
  TOP w0.254: U1.K13 v4(106.23,83.21) ; U1.K10 v4(106.23,85.61) ; U1.L12 v4(105.43,84.01) ; U1.K12 v4(106.23,84.01) ; U1.M12 v4(104.63,84.01) ; U1.L10 v4(105.43,85.61) ; U1.L11 v4(105.43,84.81) ; U1.K11 v4(106.23,84.81) ; U1.M10 v4(104.63,85.61) ; U1.J13 v4(107.03,83.21) ; v1(135.84,123.14) U3.K2 v1(135.05,123.14) ; U1.M13 v4(104.63,83.21) ; U1.M11 v4(104.63,84.81)
  L3_SIG1 w0.254: v6(105.83,85.06) v4(105.43,84.81) ; v6(105.83,85.86) v4(105.43,85.61) ; v6(105.03,84.26) v4(104.63,84.01) ; v6(106.63,83.46) v4(106.23,83.21) ; v6(105.03,85.86) v4(104.63,85.61) ; v6(106.63,85.86) v4(106.23,85.61) ; v6(105.83,84.26) v4(105.43,84.01) ; v6(106.63,84.26) v4(106.23,84.01) ; v6(105.03,83.46) v4(104.63,83.21) ; v6(105.03,85.06) v4(104.63,84.81) ; v4(107.03,83.21) v6(107.43,83.46) ; v6(106.63,85.06) v4(106.23,84.81)
  L10_SIG4 w0.254: v11(104.63,84.02) v6(105.03,84.26) ; v11(106.23,84.82) v6(106.63,85.06) ; v6(127,109.81) 126.87,109.68 v11(126.49,109.68) ; v11(129.67,109.3) v6(129.03,109.3) ; v11(126.49,109.05) v6(127.3,109.05) ; v11(106.23,84.02) v6(106.63,84.26) ; v11(106.23,83.22) v6(106.63,83.46) ; v11(104.63,85.62) v6(105.03,85.86) ; v11(129.67,110.06) v6(129.03,110.06)
  BOTTOM w0.381: C422.1 C423.1 C358.1 106.3,86.95 ; v11(115.7,97.74) 115.7,98.51 115.97,98.78 C354.1 ; v11(116.71,97.74) 116.71,98.51 116.44,98.78 C354.1 ; v11(117.35,99.01) 116.44,99.01 C354.1
  vias: v6(113.41,86.06) v6(114.17,86.06) v6(114.94,86.06) v6(115.44,98.63) v6(116.03,105.59) v6(116.03,104.83) v6(116.03,98.63) v6(116.2,97.87) v6(116.79,105.59) v6(116.79,104.83) v6(116.79,104.07) v6(117.55,104.83) v7(117.62,132.42) v7(117.86,133.94) v7(118.77,133.05) v7(118.77,131.78) v7(120.04,133.05) v7(120.04,131.78) v10(104.54,84.69) v10(105.41,85.45) v10(105.59,84.66) v10(105.58,83.87) v10(106.22,85.48) v10(113.66,86.82) v10(114.17,85.22) v10(114.94,85.3) v11(104.54,84.69) v11(105.41,85.45) v11(105.59,84.66) v11(105.58,83.87) v11(106.22,85.48) v11(113.66,86.82) v11(114.17,85.22) v11(114.94,85.3)
VDD_GPU: length 15.6
  TOP w0.254: U3.K6 v1(139.04,123.93) ; U3.K6 v1(138.25,123.93) ; U3.K6 v1(138.25,123.14) ; U1.W11 v4(98.24,84.81) ; U1.W13 v4(98.24,83.21) ; U1.U12 v4(99.84,84.01) ; U1.W10 v4(98.24,85.61) ; U1.V10 v4(99.04,85.61) ; U1.U11 v4(99.84,84.81) ; U1.V11 v4(99.04,84.81) ; U1.V14 v4(99.04,82.41)
  L3_SIG1 w0.254: v6(97.84,85.06) v4(98.24,84.81) ; v6(97.84,83.46) v4(98.24,83.21) ; v6(98.64,85.86) v4(99.04,85.61) ; v6(98.64,85.06) v4(99.04,84.81) ; v6(97.84,85.86) v4(98.24,85.61) ; v6(99.44,84.26) v4(99.84,84.01) ; v6(98.64,82.66) v4(99.04,82.41) ; v6(99.44,85.06) v4(99.84,84.81)
  L10_SIG4 w0.254: v11(98.24,84.82) v6(97.84,85.06) ; v11(99.04,85.62) v6(98.64,85.86) ; v11(99.84,84.82) v6(99.44,85.06) ; v11(99.04,84.82) v6(98.64,85.06) ; v11(99.84,84.02) v6(99.44,84.26) ; v11(98.24,85.62) v6(97.84,85.86) ; v11(99.04,82.42) v6(98.64,82.66)
  BOTTOM w0.381: v11(99.04,82.42) 98.97,82.42 C329.1 ; v11(91.95,88.09) 91.95,88.73 C328.1 ; C330.1 v11(90.93,88.09)
  vias: v6(89.04,88.45) v6(89.61,88.35) v6(90.17,88.34) v6(90.42,87.76) v6(90.86,87.41) v7(133.73,112.98) v7(134.37,111.33) v7(135.51,111.33) v7(136.58,111.33) v10(86.54,88.73) v10(86.54,88.09) v10(87.05,87.33) v10(88.19,87.33) v10(88.95,87.33) v10(89.71,87.33) v11(86.54,88.73) v11(86.54,88.09) v11(87.05,87.33) v11(88.19,87.33) v11(88.95,87.33) v11(89.71,87.33)
VDD_IVA: length 8.7
  TOP w0.254: U1.V18 v11(99.04,78.42) ; U1.U19 v11(99.84,77.62) ; U1.U18 v11(99.84,78.42) ; U1.V19 v11(99.04,77.62)
  TOP w0.381: v1(143.04,122.34) U3.L11 v1(142.25,122.34)
  L3_SIG1 w0.203: v11(99.84,77.62) v6(99.44,77.37) ; v11(99.04,77.62) v6(98.64,77.37)
  L3_SIG1 w0.254: v11(99.04,78.42) v6(98.64,78.17) ; v11(99.84,78.42) v6(99.44,78.17)
  L10_SIG4 w0.254: v11(99.04,78.42) v6(98.64,78.17) ; v11(99.84,78.42) v6(99.44,78.17) ; v11(99.84,77.62) v6(99.44,77.37) ; v11(99.04,77.62) v6(98.64,77.37)
  BOTTOM w0.381: v7(133.48,104.86) 133.48,104.6 132.97,104.09 C270.1
  vias: v7(143.51,111.21) v7(144.65,111.21) v7(145.8,111.21)
VDD_MIPI: length 0.9
  BOTTOM w0.254: U89.H10 v1(148.54,98.57) ; U89.E10 v1(150.5,98.57)
VDD_MPU: length 39.7
  TOP w0.254: U1.M16 v11(104.63,80.02) ; U1.M15 v11(104.63,80.82) ; U1.R18 v4(101.44,78.42) ; U1.L17 v11(105.43,79.22) ; U1.K18 v11(106.23,78.42) ; U1.N17 v4(103.83,79.22) ; U1.M18 v4(104.63,78.42) ; U1.K17 v11(106.23,79.22) ; U1.L16 v11(105.43,80.02) ; U1.M17 v11(104.63,79.22) ; U1.P18 v4(103.03,78.42) ; U1.L19 v4(105.43,77.62) ; U1.P17 v4(103.03,79.22) ; U1.L15 v4(105.43,80.82) ; U1.N18 v4(103.83,78.42) ; U1.L18 v4(105.43,78.42)
  TOP w0.381: 145.42,131.53 145.03,131.15 145.03,130.73 U3.B13
  L3_SIG1 w0.254: v11(105.43,80.02) v6(105.83,79.77) ; v11(104.63,79.22) v6(105.03,78.97) ; v11(104.63,80.02) v6(105.03,79.77) ; v4(105.43,77.62) v6(105.83,77.37) ; v11(106.23,79.22) v6(106.63,78.97) ; v11(104.63,80.82) v6(105.03,80.57) ; v4(103.83,79.22) v6(104.23,78.97) ; v4(103.83,78.42) v6(104.23,78.17) ; v4(105.43,78.42) v6(105.83,78.17) ; v4(104.63,78.42) v6(105.03,78.17) ; v4(105.43,80.82) v6(105.83,80.57) ; v11(105.43,79.22) v6(105.83,78.97) ; v4(103.03,78.42) v6(103.43,78.17) ; v11(106.23,78.42) v6(106.63,78.17) ; v4(103.03,79.22) v6(103.43,78.97) ; v4(101.44,78.42) v6(101.04,78.17)
  L10_SIG4 w0.254: v11(105.41,78.52) 105.81,78.27 v6(105.83,78.17) ; v11(105.43,79.22) v6(105.83,78.97) ; v11(104.63,80.02) v6(105.03,79.77) ; v11(106.23,79.22) v6(106.63,78.97) ; v6(104.23,78.17) 104.59,78.39 v11(104.62,78.52) 104.65,78.41 v6(105.03,78.17) ; v11(105.43,80.02) v6(105.83,79.77) ; v6(104.23,78.97) v11(104.63,79.22) v6(105.03,78.97) ; v11(104.63,80.82) v6(105.03,80.57) ; v11(106.23,78.42) v6(106.63,78.17)
  L10_SIG4 w0.381: v9(112.9,90.38) 113.16,90.38 v6(113.44,90.66) ; v6(115.06,91.9) 114.66,91.5 v9(114.66,91.39) ; v9(116.2,80.09) v6(115.57,80.09) ; v11(103.63,95.2) v6(103.63,94.47) ; v9(115.57,88.09) v6(116.46,88.09) ; v9(116.2,79.08) v6(115.57,79.08) ; v11(104.65,95.2) v6(104.65,94.44)
  BOTTOM w0.254: v11(102.11,79.05) v11(102.11,78.67)
  BOTTOM w0.381: v11(104.65,95.2) 104.65,95.86 C395.1 103.63,95.86 v11(103.63,95.2) ; C474.1 115.19,89.74 115.57,89.36 v9(115.57,88.09) ; C474.1 v9(114.66,91.39) ; C474.1 113.54,89.74 v9(112.9,90.38) ; C369.1 v9(116.2,79.08) ; C370.1 v9(116.2,80.09)
  vias: v1(116.84,125.68) v1(116.84,124.54) v1(116.84,123.27) v1(118.21,125.66) v1(118.21,124.52) v1(118.21,123.25) v1(118.21,121.98) v6(97.26,94.62) v6(97.26,94.06) v6(97.26,93.5) v7(145.8,134.19) v7(145.8,133.43) v7(145.8,132.67) v7(145.92,132.03) v7(146.56,134.19) v7(146.56,133.43) v7(146.56,132.67) v8(96.27,95.33) v8(96.9,95.71) v8(96.9,95.08) v9(96.27,95.33) v9(96.9,95.71) v9(96.9,95.08) v10(101.63,79.89) v10(102.13,79.76) v11(101.63,79.89) v11(102.13,79.76)
VDD_RTC: length 3.5
  TOP w0.381: v7(138.29,131.83) 138.29,131.18 U3.A5
  BOTTOM w0.381: v7(138.3,133.23) 138.3,132.62 138.28,132.59 v7(138.28,132.57) ; C402.1 137.8,132.92 138.07,132.66 138.19,132.66 v7(138.28,132.57) ; v7(138.28,132.57) 138.3,132.54 138.3,131.84 v7(138.29,131.83)
  vias: v6(79.91,86.44) v6(80.67,86.44) v8(80.14,87.38) v8(80.77,87.76) v9(80.14,87.38) v9(80.77,87.76)
VDDR2_VREF: length 6.7
  TOP w0.173: U1.N22 v4(103.83,75.22)
  TOP w0.381: v1(144,61.29) 143.3,60.58 C523.1
  L3_SIG1 w0.254: v4(103.83,75.22) 104.19,74.86 v6(104.2,74.86)
  L10_SIG4 w0.254: v11(103.8,74.61) v6(104.2,74.86)
  BOTTOM w0.254: U92.6 161.52,59.11 161.54,59.14 ; U91.M8 v1(144,61.29) ; U90.H1 v1(140.44,51.8) ; U90.M8 v1(143.28,46.05) ; U91.H1 v1(140.44,67.04)
  BOTTOM w0.381: C524.1 103.95,74.76 v11(103.8,74.61) ; C505.1 v7(139.07,55.2)
  vias: v7(138.68,74.12) v7(138.68,72.85) v7(139.95,74.12) v7(139.95,72.85)
VDDR2_VTT: length 16.8
  BOTTOM w0.305: U92.3 157.23,57.49 C537.1
  BOTTOM w0.381: R807.1 147.15,55.2 150.11,58.17 151.51,58.17
  BOTTOM w0.508: R784.2 157.23,63.2 156.21,64.22 v7(152.27,64.22)
  vias: v7(152.27,68.28) v7(152.27,66.25) v7(152.27,62.18) v7(152.27,60.15) v7(153.29,58.76) v7(153.29,57.99) v7(154.05,58.76) v7(154.05,57.99)
VDDR_VREF: length 9.5
  TOP w0.254: U7.M8 v1(103.22,29.48) ; U8.6 105.15,13.11 ; U6.M8 v1(118.46,29.48) ; U5.H1 v1(83.18,32.68) ; U6.H1 v1(113.66,32.68) ; U5.M8 v1(87.98,29.48) ; U1.Y18 v4(97.44,78.42) ; U7.H1 v1(98.42,32.68)
  TOP w0.508: C46.1 v7(92.33,28.96) ; C54.1 v7(122.81,28.7) ; C83.1 v7(107.57,28.7)
  L3_SIG1 w0.254: v4(97.44,78.42) v6(97.04,78.17)
  L10_SIG4 w0.254: v11(96.66,77.82) 96.81,77.97 97.01,78.17 v6(97.04,78.17)
  BOTTOM w0.381: C81.1 96.39,78.08 v11(96.66,77.82)
  vias: v7(91.19,21.08) v7(91.82,20.45) v7(92.46,21.21) v7(92.96,20.57) v7(93.6,19.94)
VDDR_VTT: length 12.2
  TOP w0.305: U8.3 107.82,17.4 C100.1
  TOP w0.508: 106.68,22.23 103.13,22.23 102.01,21.11 102.01,17.98 102.6,17.4 R69.2
  vias: v7(118.11,19.67) v7(120.65,19.67) v7(124.84,19.8) v7(125.98,20.98) v7(127.13,19.8)
VDDS_DDR: length 177.3
  TOP w0.254: U6.D2 v1(114.46,35.88) ; U6.R1 112.65,26.68 v1(112.64,26.66) ; U7.H9 v1(104.82,32.68) ; U7.E9 v1(104.02,35.08) ; U7.F1 v1(98.42,34.28) ; U5.C1 v1(82.21,36.28) ; U5.H9 v1(89.74,32.28) ; U7.N1 v1(97.45,28.28) ; U6.R9 v1(120.27,26.68) ; U5.R1 v1(82.21,26.68) ; U6.E9 v1(119.26,35.08) ; U6.K8 v1(118.46,31.08) ; U6.N1 v1(112.69,28.28) ; U5.A1 v1(82.21,37.88) ; U7.K8 v1(103.22,31.08) ; U7.A1 v1(97.62,38.28) ; U6.H2 v1(114.46,32.68) ; U7.B2 v1(99.22,37.48) ; U6.B2 v1(114.46,37.48) ; U5.R9 v1(89.74,26.68) ; v1(97.38,26.68) U7.R1 ; U6.C9 v1(119.26,36.68) ; U6.G7 v1(117.66,33.48) ; U5.F1 v1(83.18,34.28) ; U7.C9 v1(104.02,36.68) ; U5.C9 v1(88.78,36.68) ; U5.A8 v1(87.98,38.28) ; U7.H2 v1(99.22,32.68) ; U6.K2 v1(113.66,31.08) ; U5.K8 v1(87.98,31.08) ; U7.D9 v1(104.82,35.88) ; U6.D9 v1(120.06,35.88) ; U5.D2 v1(83.98,35.88) ; U6.A1 v1(112.86,38.28) ; U5.D9 v1(89.74,35.48) ; U5.N9 v1(89.74,28.28) ; U5.H2 v1(83.98,32.68) ; U7.C1 v1(97.62,36.68) ; U5.B2 v1(83.98,37.48) ; U7.R9 v1(104.98,26.68) ; U7.N9 v1(104.98,28.28) ; U5.E9 v1(88.78,35.08) ; U7.K2 v1(98.42,31.08) ; U6.H9 v1(120.06,32.68) ; U7.A8 v1(103.22,38.28) ; U5.G7 v1(87.18,33.48) ; U7.D2 v1(99.22,35.88) ; U7.G7 v1(102.42,33.48) ; U5.K2 v1(83.98,31.08) ; U6.C1 v1(112.86,36.68) ; U6.B7 v1(117.66,37.48) ; U6.F1 v1(113.66,34.28) ; U6.N9 v1(120.22,28.28) ; U6.A8 v1(118.86,38.44) ; U5.N1 v1(82.21,28.28)
  TOP w0.305: U8.2 108.32,17.39 C90.1
  TOP w0.381: v7(129.67,25.02) 129.41,24.77 C89.2 ; C511.1 134.24,67.04 134.48,66.8 v1(134.48,66.17) ; C33.1 v7(89.17,16.64) ; C33.1 v7(88.03,17.78) ; C33.1 v7(89.17,18.92) ; v1(139.28,62.09) 139.28,62.78 C520.1 ; C512.1 144.44,67.69 v1(144.44,67.04) ; C52.1 v7(98.06,20.19) ; C52.1 v7(98.06,17.91) ; C52.1 v7(96.92,19.05) ; C515.1 138.94,67.13 v1(138.84,67.04) ; C64.1 v7(113.3,17.91) ; C64.1 v7(112.24,19.05) ; C64.1 v7(113.3,20.19) ; C516.1 136.53,66.61 v1(136.08,66.17) ; C499.1 140.59,44.74 v1(140.08,45.25) ; v1(144.44,51.8) 144.44,52.45 C490.1 ; v7(136.29,56.22) C510.1 v7(135.24,55.07) ; C488.1 146.04,52.41 v1(146.04,51.8) ; v7(146.96,57.87) C492.1 v7(145.9,56.72) ; R45.2 v1(112.39,15.11) ; C500.1 137.54,43.88 v1(138.04,44.38) ; C514.1 136.14,59.32 v1(136.44,59.62) ; C539.2 v7(150.5,57.36) ; C509.1 144.02,59.19 v1(144.44,59.62) ; v1(146.04,67.04) 146.04,67.65 C513.1 ; v1(141.68,61.29) 140.87,61.29 140.08,60.5 v1(140.08,60.49) 140.59,59.98 C508.1 C519.1 ; C494.1 134.24,51.17 v1(134.48,50.93) ; C493.1 136.53,51.37 v1(136.08,50.93) ; v1(134.48,61.29) 134.47,61.3 C506.1 ; v1(139.28,46.85) 139.28,47.54 C496.1 ; v1(134.48,46.05) 134.47,46.06 C502.1 ; C529.2 v7(139.19,70.44) ; C517.1 146.05,59.61 v1(146.04,59.62) ; U3.K13 144.77,123.54 145.54,122.76 ; C507.1 137.54,59.12 v1(138.04,59.62) ; v1(136.44,44.38) 136.14,44.08 C501.1 ; v1(138.84,51.8) 138.56,52.08 C491.1
  TOP w0.508: C80.1 v7(93.98,35.18) ; C47.1 v7(109.22,35.18) ; 146.1,122.2 145.54,122.76 ; C44.1 v7(78.74,35.18)
  L3_SIG1 w0.381: v7(109.6,20.7) 108.97,20.07 108.97,17.1 110.95,15.11 v1(112.39,15.11)
  BOTTOM w0.254: U90.K2 v1(141.68,50.13) ; U90.H2 v1(140.08,50.13) ; U90.N9 v1(144.44,44.38) ; U90.N1 v1(144.44,51.8) ; U90.F1 v1(138.84,51.8) ; U91.D2 v1(136.88,65.37) ; U91.N1 v1(144.44,67.04) ; U91.R9 v1(146.04,59.62) ; U90.A8 v1(134.48,46.05) ; U90.B2 v1(135.28,50.13) ; U91.E9 v1(138.04,59.62) ; U91.H9 v1(140.08,60.49) ; U90.C9 v1(136.44,44.38) ; U91.D9 v1(136.88,60.49) ; U90.R9 v1(146.04,44.38) ; U90.E9 v1(138.04,44.38) ; U91.R1 v1(146.04,67.04) ; U90.A1 v1(134.48,50.93) ; U91.K8 v1(141.68,61.29) ; U91.G7 v1(139.28,62.09) ; U91.C1 v1(136.08,66.17) ; U90.G7 v1(139.28,46.85) ; U90.D2 v1(136.88,50.13) ; U91.N9 v1(144.44,59.62) ; U90.D9 v1(136.88,45.25) ; U91.C9 v1(136.44,59.62) ; U90.K8 v1(141.68,46.05) ; U91.A1 v1(134.48,66.17) ; U91.H2 v1(140.08,65.37) ; U91.F1 v1(138.84,67.04) ; U90.C1 v1(136.08,50.93) ; U91.B2 v1(135.28,65.37) ; U91.A8 v1(134.48,61.29) ; U91.K2 v1(141.68,65.37) ; U90.H9 v1(140.08,45.25) ; U90.R1 v1(146.04,51.8)
  BOTTOM w0.305: U92.2 157.23,56.98 C542.1
  BOTTOM w0.381: C29.1 81.88,35.94 v1(82.21,36.28) ; C51.1 97.26,26.8 v1(97.38,26.68) ; v1(89.74,32.28) 90.14,31.88 C36.1 ; C60.1 113.66,31.88 v1(114.46,32.68) ; v1(83.98,37.48) 83.46,38 83.46,38.75 C30.1 ; v1(120.22,28.28) 120.27,28.32 C75.1 ; v1(83.18,34.28) 82.81,33.91 C42.1 ; C57.1 97.37,28.19 v1(97.45,28.28) ; v1(97.62,36.68) 97.62,36.41 97.16,35.94 C67.1 ; C37.1 89.79,28.32 v1(89.74,28.28) ; C55.1 105.1,26.8 v1(104.98,26.68) ; v1(118.86,38.44) 118.87,38.46 C63.1 ; v1(98.42,34.28) 97.65,34.28 97.28,33.91 C59.1 ; C34.1 87.98,39.08 v1(87.98,38.28) ; C35.1 89.86,26.8 v1(89.74,26.68) ; v1(104.02,35.08) 105.64,35.08 C68.1 ; C79.1 112.36,27.94 v1(112.69,28.28) ; v1(112.86,36.68) 112.86,36.15 112.65,35.94 C77.1 ; v1(114.46,37.48) 114.17,37.76 C71.1 ; C521.1 v7(139.19,71.46) ; v1(88.78,36.68) 89.01,36.45 C32.1 ; C526.2 v7(149.1,69.68) ; C76.1 120.63,36.45 v1(120.06,35.88) ; C78.1 112.26,33.91 112.62,34.28 v1(113.66,34.28) ; 98.93,38.99 98.55,38.61 98.55,38.1 99.18,37.48 v1(99.22,37.48) ; C65.1 105.03,32.89 v1(104.82,32.68) ; C39.1 88.01,31.05 v1(87.98,31.08) ; v1(117.66,33.48) 117.58,33.4 C62.1 ; v1(112.86,38.28) 112.32,38.28 C74.1 ; v1(120.06,32.68) 120.27,32.89 C61.1 ; C70.1 120.39,26.8 v1(120.27,26.68) ; 111.38,14.73 112.01,14.73 v1(112.39,15.11) ; C49.1 97.08,38.28 v1(97.62,38.28) ; C72.1 112.38,26.92 v1(112.64,26.66) ; v1(119.26,35.08) 119.41,34.92 C73.1 ; C314.2 v7(129.92,26.92) ; v1(89.74,35.48) 90.3,34.92 C38.1 ; C503.1 v7(139.19,56.22) ; C538.2 142.11,70.31 v7(142.11,69.68) ; C48.1 105.39,36.45 v1(104.82,35.88) ; C87.2 v7(130.05,29.34) ; C50.1 103.22,39.08 v1(103.22,38.28) ; C56.1 97.75,31.75 v1(98.42,31.08) ; C66.1 105.03,28.32 v1(104.98,28.28) ; C31.1 82.12,37.97 v1(82.21,37.88) ; C85.2 v7(130.05,30.48) ; C58.1 102.34,33.4 v1(102.42,33.48)
  BOTTOM w0.508: v7(153.41,55.96) 153.41,53.05 154.31,52.15 C543.1 R786.2
  vias: v7(61.02,73.81) v7(61.02,72.54) v7(62.29,73.81) v7(62.29,72.54) v7(62.68,57.04) v7(62.68,55.77) v7(62.68,54.5) v7(63.56,72.54) v7(63.95,57.04) v7(63.95,55.77) v7(108.71,21.46) v7(108.71,20.7) v7(109.6,21.46) v7(148.84,118.32) v7(148.84,117.18) v7(150.11,118.32) v7(150.11,117.18) v7(151.26,118.32) v7(151.26,117.18) v7(153.41,56.72) v7(154.17,56.72) v7(154.17,55.96)
AM57XX_CLKOUT3: length 166.4
  TOP w0.173: U1.C23 v4(111.83,74.42)
  L3_SIG1 w0.109: v1(163.32,147.32) 163.32,147.96 164.21,148.84 174.12,148.84 174.83,149.56 177.89,149.56 180.79,146.66 180.79,143.7 183.1,141.38 183.1,135.09 181.61,133.6 176.48,133.6 172.72,129.85 172.72,116.29 v6(166.12,109.68) ; v6(167.39,80.11) 167.36,80.09 164.54,80.09 160.32,75.87 155.57,75.87 154.48,74.78 137.85,74.78 135.66,72.59 135.66,71.63 131.04,67.01 129.74,67.01 129.01,67.74 126.47,67.74 125.91,67.18 122.38,67.18 121.44,68.13 120.19,68.13 119.08,69.25 119.08,70.79 114.83,75.04 112.46,75.04 v4(111.83,74.42)
  L10_SIG4 w0.109: v6(166.12,109.68) 166.12,102.82 166.88,102.06 166.88,92.15 168.07,90.96 168.07,80.8 v6(167.39,80.11)
  BOTTOM w0.173: R905.2 v1(163.32,147.32)
AM57XX_GPIO6_14: length 17.7
  TOP w0.173: U1.E21 v4(110.23,76.02) ; R685.2 v5(122.81,68.28)
  L3_SIG1 w0.109: v5(122.81,68.28) 122.35,68.74 122.35,69.37 122.05,69.68 122.05,70.03 121.01,71.07 119.91,71.07 115.7,75.29 111.76,75.29 111.35,75.7 110.9,75.7 110.58,76.02 v4(110.23,76.02)
AM57XX_GPIO6_15: length 11.5
  TOP w0.173: U1.F20 v4(109.43,76.82)
  L3_SIG1 w0.109: v4(109.43,76.82) v6(109.83,76.57)
  L10_SIG4 w0.109: v6(109.83,76.57) 110.25,76.15 111.76,76.15 112.32,75.6 117.02,75.6 117.4,75.21 117.83,75.21 118.36,74.68 v9(118.36,74.25)
  BOTTOM w0.173: R661.2 v9(118.36,74.25)
AM57XX_GPIO6_16: length 11.5
  TOP w0.173: U1.F21 v4(109.43,76.02)
  L3_SIG1 w0.109: v4(109.43,76.02) v6(109.83,75.77)
  L10_SIG4 w0.109: v9(118.36,73.23) 117.32,74.27 116.71,74.27 115.62,75.37 112.17,75.37 111.61,75.93 109.99,75.93 v6(109.83,75.77)
  BOTTOM w0.173: R666.2 v9(118.36,73.23)
AM57XX_GPIO_IND_LDN: length 9.5
  TOP w0.173: R371.2 R800.1 86.82,93.34 89.75,90.41 92.64,90.41 U1.AF4
AM57XX_GPIO_RS485: length 13.3
  TOP w0.173: U1.AA3 v4(96.64,91.21) ; R584.2 92.46,101.05 v5(92.33,100.92)
  L3_SIG1 w0.109: v4(96.64,91.21) 96.64,95.22 96.77,95.36 96.77,96.93 94.31,99.4 93.85,99.4 v5(92.33,100.92)
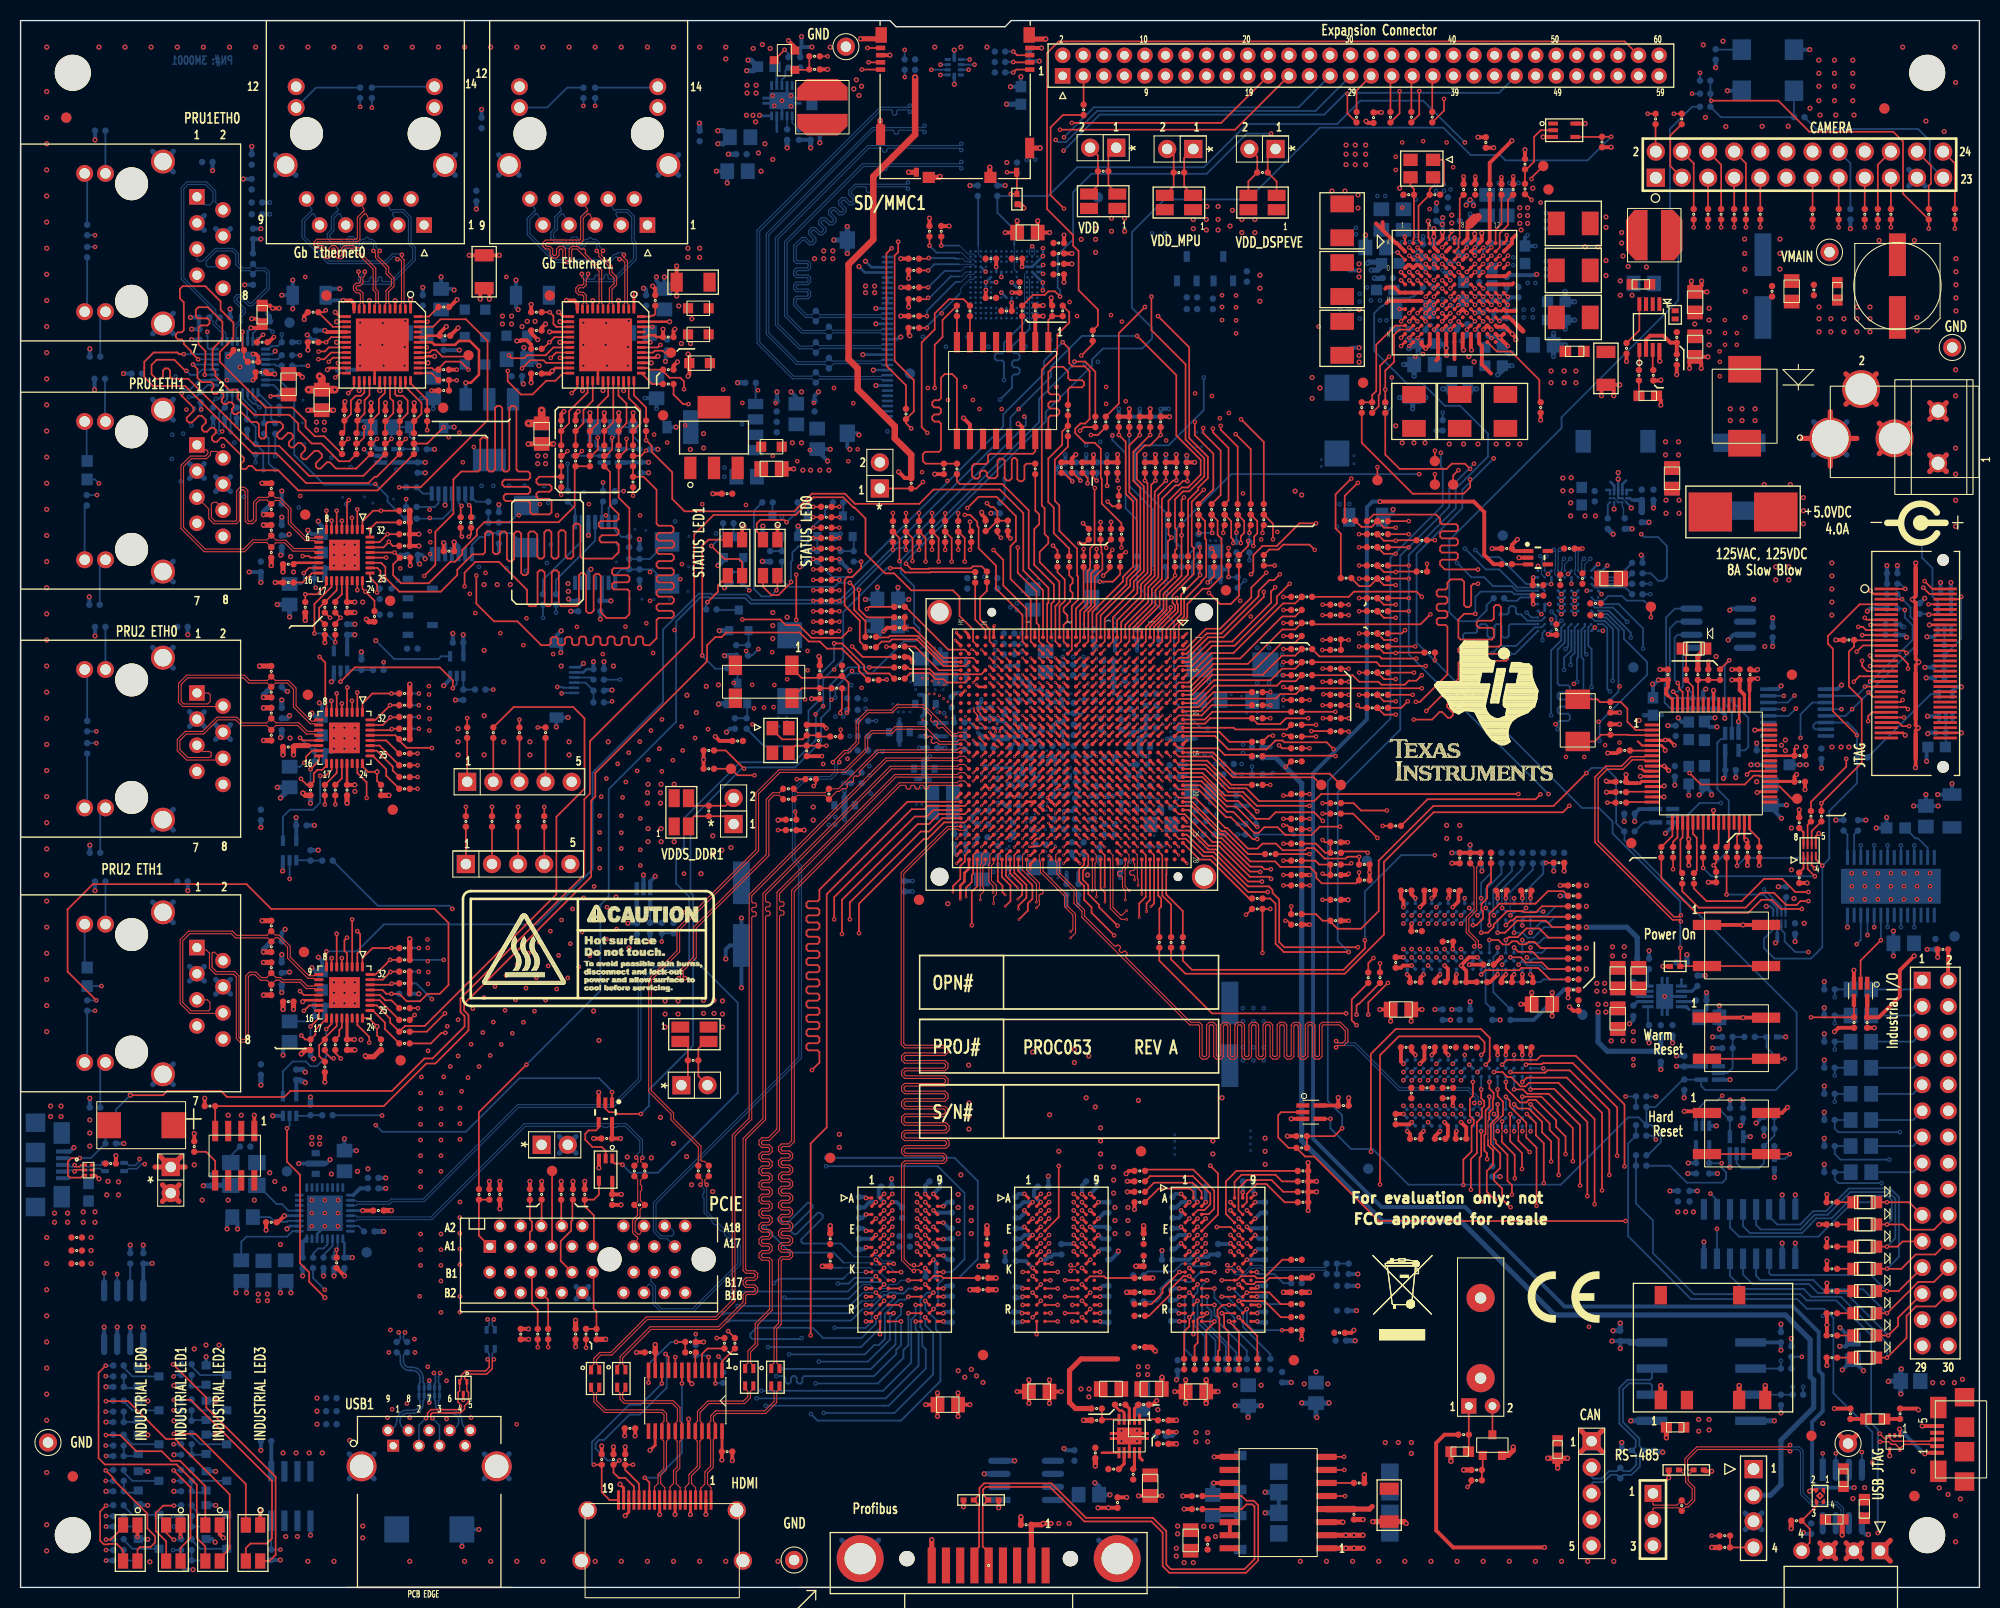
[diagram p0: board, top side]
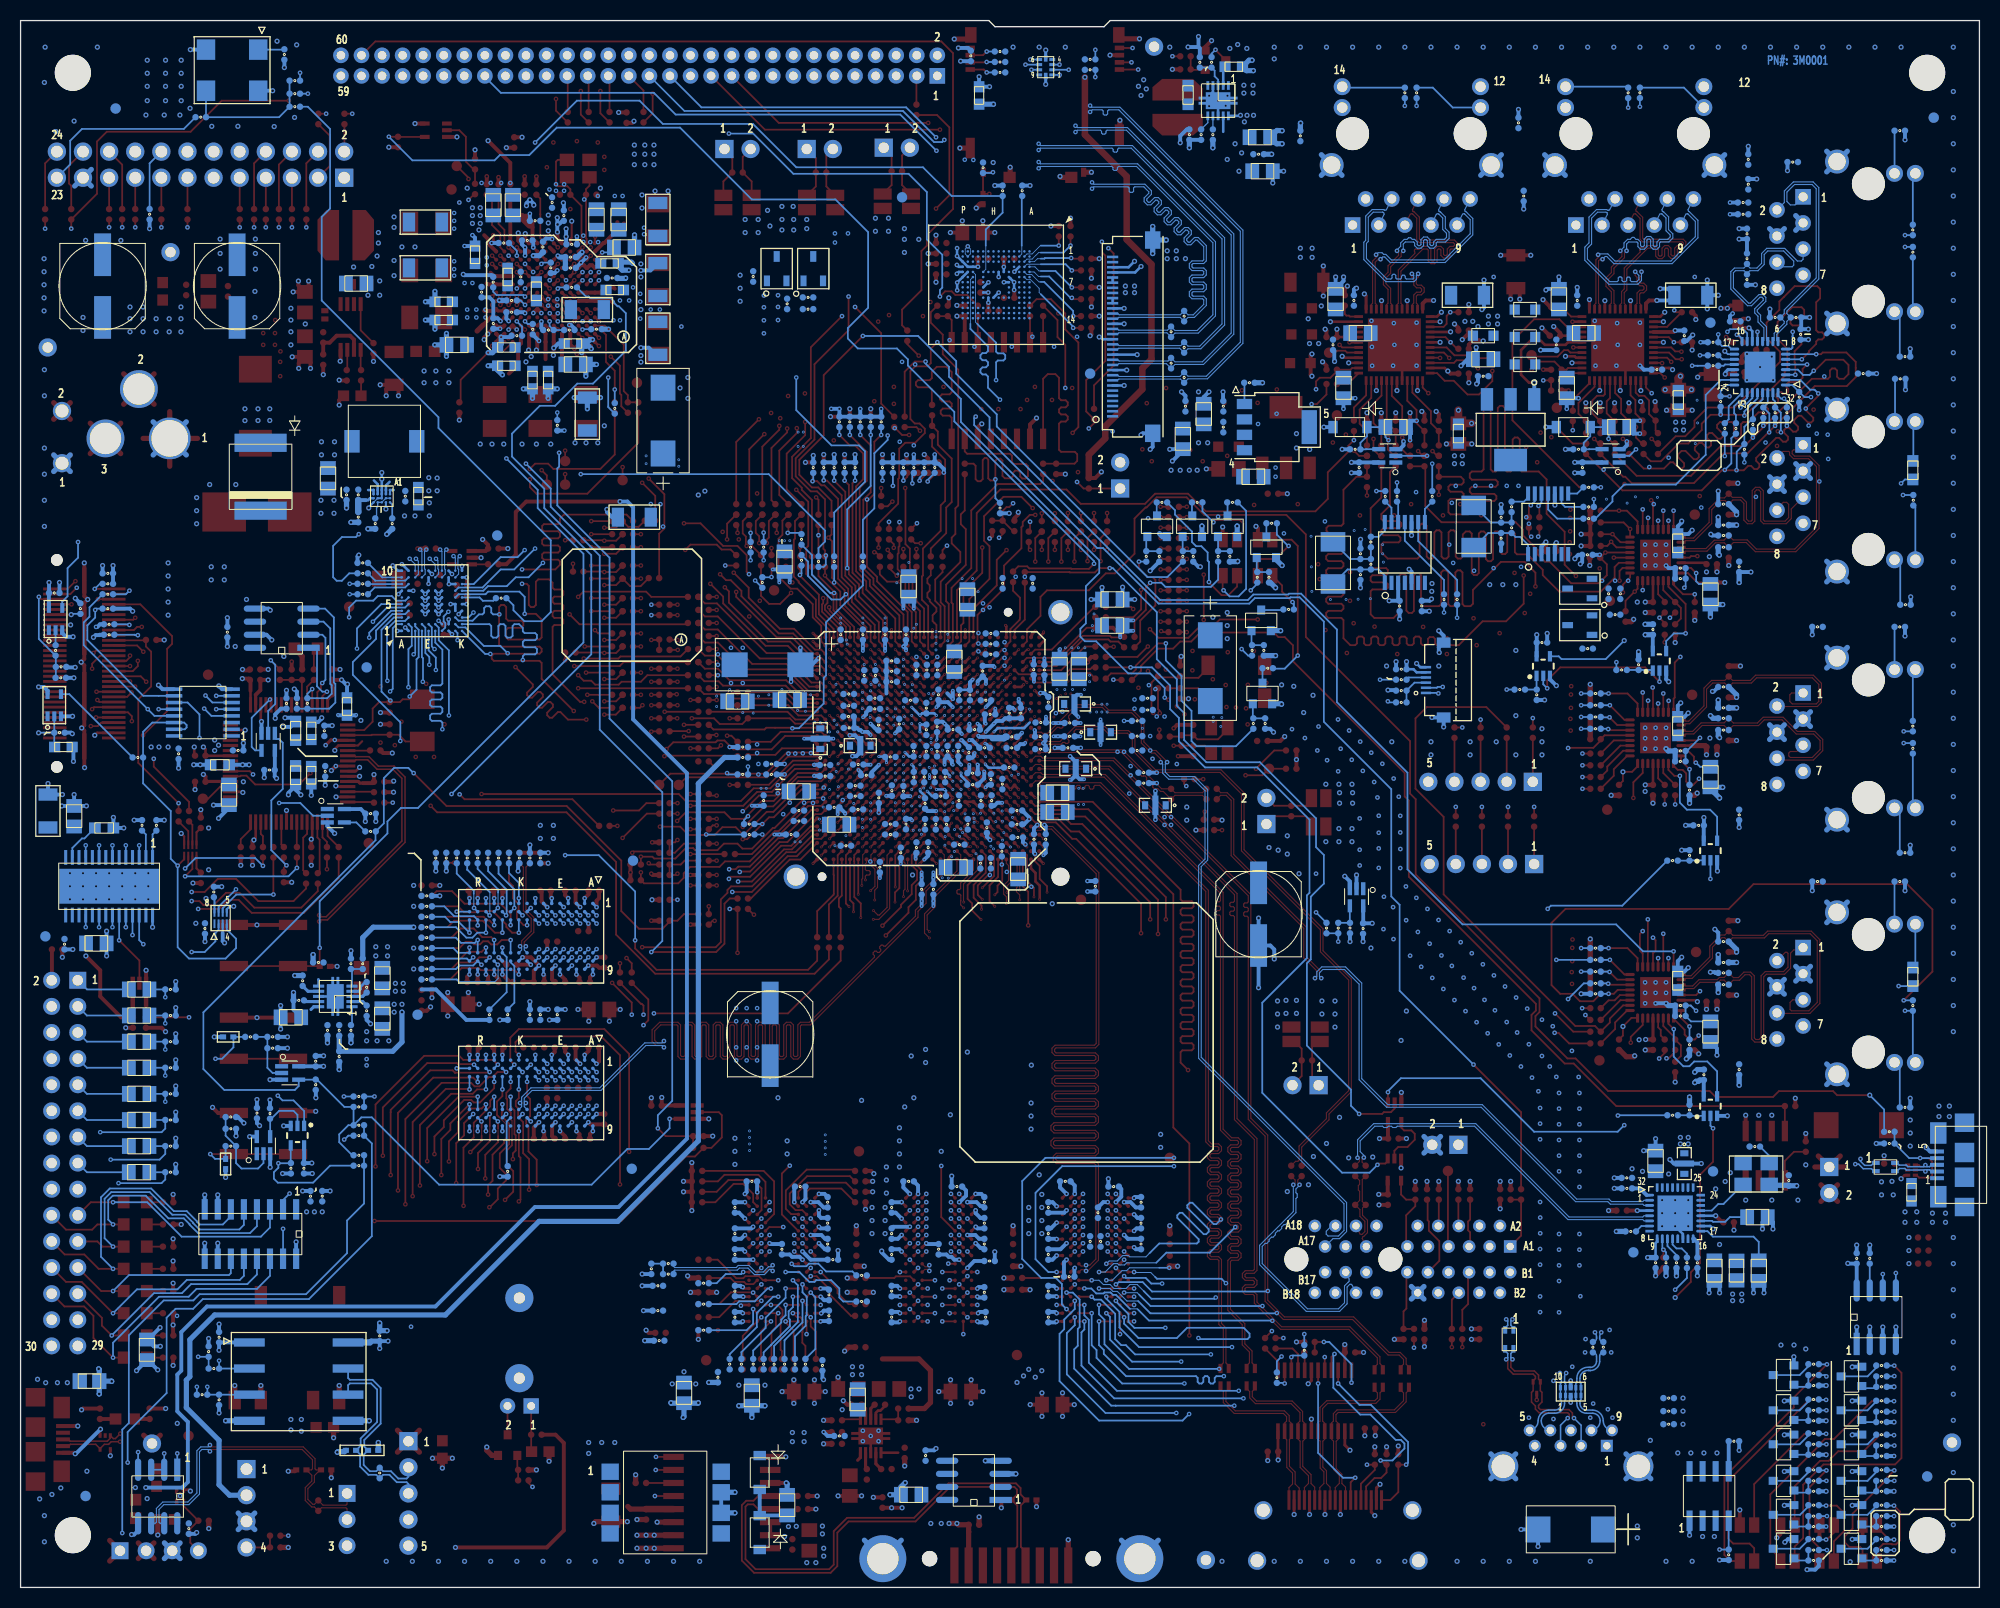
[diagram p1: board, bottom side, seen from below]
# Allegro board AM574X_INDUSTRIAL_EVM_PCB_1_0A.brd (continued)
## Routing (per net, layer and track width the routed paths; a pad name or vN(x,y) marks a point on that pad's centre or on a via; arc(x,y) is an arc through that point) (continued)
AM57XX_GPMC_AD0: length 92.6
  TOP w0.173: v5(129.03,145.29) 129.03,143.38 R861.2 ; v1(102.29,107.57) 101.45,108.41 R434.1 ; U1.M6 v4(104.63,88.81)
  L3_SIG1 w0.109: v5(129.03,145.29) v6(128.14,145.29) ; v6(105.03,89.06) 105.03,89.06 104.64,88.81 v4(104.63,88.81)
  L4_SIG2 w0.114: v6(128.14,145.29) 127.77,144.91 126.99,144.91 126.19,145.71 124.82,145.71 124.69,145.83 124.33,145.83 123.78,145.28 117.41,145.28 115.21,143.08 111.07,143.08 109.68,141.69 109.68,139.41 107.13,136.87 106,136.87 104.03,134.9 104.03,126.16 104.59,125.61 104.59,124.94 103.83,124.19 103.83,123.47 104.62,122.67 104.62,118.72 103.71,117.81 103.71,109.73 102.29,108.31 v1(102.29,107.57) 103.37,106.49 104.43,106.49 105.59,105.33 106.65,105.33 107.51,104.48 107.51,102.53 108.72,101.31 108.72,99.22 107.79,98.29 106.24,98.29 104.77,96.83 104.77,95.48 105.33,94.92 105.33,93.57 105.03,93.27 v6(105.03,89.06)
  BOTTOM w0.173: R453.2 102.29,107.73 v1(102.29,107.57)
AM57XX_GPMC_AD1: length 81.3
  TOP w0.173: U1.M2 104.64,92.02 104.64,94.63 107.56,97.55 107.56,98.14 108.54,99.13 108.54,105.79 107.82,106.51 107.82,111.08 v1(108.84,112.1) R435.1 ; v5(134.11,145.54) 134.11,143.38 R862.2
  L3_SIG1 w0.109: v5(134.11,145.54) 133.99,145.42 132.3,145.42 131.64,144.75 130.07,144.75 129.92,144.91 v6(129.54,144.91)
  L4_SIG2 w0.114: v1(108.84,112.1) 108.84,113.47 108.48,113.83 108.48,120.22 107.85,120.85 107.85,127.92 109.05,129.12 109.05,134.15 111.33,136.43 113.86,136.43 115.61,138.18 123.6,138.18 129.54,144.12 v6(129.54,144.91)
  BOTTOM w0.173: R435.1 v1(108.84,112.1)
AM57XX_GPMC_AD2: length 93.6
  TOP w0.173: R863.2 136.02,143.26 v5(136.02,145.54) ; v1(104.65,107.65) 104.27,108.03 R436.1 ; U1.L5 v4(105.43,89.61)
  L3_SIG1 w0.099: 105.5,96.65 104.92,96.07 104.92,95.47 105.23,95.16 105.23,94.16 104.7,93.63 104.7,92.15 104.93,91.92 104.93,90.12 ; 105.58,96.65 106.06,97.13 v6(106.54,97.13)
  L3_SIG1 w0.109: 105.58,96.65 105.5,96.65 ; v5(136.02,145.54) 135.56,145.09 132.38,145.09 131.74,144.45 128.88,144.45 v6(128.63,144.71) ; 104.93,90.12 v4(105.43,89.61)
  L4_SIG2 w0.114: v6(128.63,144.71) 128.32,144.4 117.83,144.4 114.43,141.01 113.59,141.01 112.75,140.17 112.75,138.74 111.91,137.91 110.67,137.91 106.61,133.85 106.61,128.75 106.39,128.53 106.39,127.12 105.5,126.23 105.5,118.35 104.61,117.46 104.61,111.62 105.77,110.47 105.77,108.77 v1(104.65,107.65) 104.65,107.54 105.48,106.7 106.68,106.7 108.39,105 108.39,103.09 109.63,101.85 109.63,98.6 108.16,97.13 v6(106.54,97.13)
  BOTTOM w0.173: R455.2 v1(104.65,107.65)
AM57XX_GPMC_AD3: length 84.5
  TOP w0.173: R864.2 138.43,143.64 v5(138.43,144.78) ; R437.1 v1(106.81,112.1) 107.47,111.43 107.47,106.36 108.19,105.64 108.19,99.28 107.21,98.29 107.21,97.86 104.23,94.88 U1.M1
  L3_SIG1 w0.109: v6(125.81,141.99) 125.81,142.58 127.2,143.97 131.88,143.97 132.69,144.78 138.43,144.78 v5(138.43,144.78)
  L4_SIG2 w0.114: v6(125.81,141.99) 125.32,142.47 120.52,142.47 116.81,138.77 115.37,138.77 113.62,137.02 111.21,137.02 111.21,137.02 111.09,137.02 108.46,134.39 108.46,129.36 107.27,128.16 107.27,126.76 106.43,125.92 106.43,113.08 106.81,112.7 v1(106.81,112.1)
  BOTTOM w0.173: R437.1 v1(106.81,112.1)
AM57XX_GPMC_AD4: length 107.4
  TOP w0.173: R438.1 v1(107.82,112.1) ; U1.L6 v4(105.43,88.81)
  L3_SIG1 w0.109: v6(124.74,141.81) 125.73,140.82 133.83,140.82 135.28,142.27 146.6,142.27 J21.51 ; v4(105.43,88.81) 105.44,88.81 105.83,89.06 v6(105.83,89.06)
  L4_SIG2 w0.114: v6(124.74,141.81) 124.74,140 123.22,138.47 115.49,138.47 113.74,136.72 111.21,136.72 108.76,134.27 108.76,129.24 107.56,128.04 107.56,126.64 106.81,125.89 106.81,113.11 v1(107.82,112.1) ; v6(111.68,99.61) 112.85,98.44 112.85,96.88 112.5,96.52 110.52,96.52 108.56,94.57 106.96,94.57 105.83,93.44 v6(105.83,89.06)
  L10_SIG4 w0.109: v9(110.11,99.14) 110.58,99.61 v6(111.68,99.61)
  BOTTOM w0.173: v9(110.11,99.14) 110.11,104.86 107.82,107.14 v1(107.82,112.1) R438.1
AM57XX_GPMC_AD5: length 120.5
  TOP w0.173: v1(103.77,107.38) 103.78,107.4 103.78,107.88 R439.1 ; U1.L4 v4(105.43,90.41)
  L3_SIG1 w0.099: 105.14,90.71 105.14,92.3 104.9,92.54 104.9,93.54 105.43,94.07 105.43,95.24 105.17,95.51 105.17,95.95 105.51,96.29 105.79,96.29
  L3_SIG1 w0.109: v6(106.09,96.6) 105.79,96.29 ; J21.53 150.72,144.4 149.4,144.4 146.69,141.69 138.58,141.69 135.33,138.43 132.89,138.43 131.95,137.5 128.14,137.5 124.13,141.51 124.13,143.44 v6(125.6,144.91) ; 105.14,90.71 v4(105.43,90.41)
  L4_SIG2 w0.114: v6(106.09,96.6) 106.09,97.31 106.48,97.7 108.22,97.7 109.3,98.79 109.3,101.72 108.09,102.93 108.09,104.83 106.68,106.25 105.51,106.25 104.64,107.12 104.04,107.12 v1(103.77,107.38) 103.78,107.4 103.78,107.88 104.27,108.36 104.74,108.36 105.46,109.08 105.46,110.34 105.19,110.61 105.19,110.62 104.32,111.49 104.32,117.59 105.21,118.47 105.21,126.35 105.58,126.73 105.58,135.54 106.32,136.28 107.77,136.28 110.29,138.79 110.29,140.44 111.25,141.41 114.37,141.41 117.66,144.69 125.38,144.69 v6(125.6,144.91)
  BOTTOM w0.173: R458.2 103.78,108.26 103.78,107.4 v1(103.77,107.38)
AM57XX_GPMC_AD6: length 122.1
  TOP w0.173: R440.1 102.31,108.41 v1(103.07,107.65) ; U1.L3 v4(105.43,91.21)
  L3_SIG1 w0.099: v6(105.66,95.87) 105.66,94.02 105.1,93.46 105.1,92.63 105.43,92.29 v4(105.43,91.21)
  L3_SIG1 w0.109: J21.55 150.31,141.99 147.53,141.99 146.94,141.4 142.8,141.4 141.94,140.54 141.52,140.54 140.66,141.4 138.7,141.4 134.41,137.11 127.89,137.11 123.62,141.38 123.62,144.51 v6(124.51,145.39)
  L4_SIG2 w0.114: v6(105.66,95.87) 105.66,97.3 106.36,98 107.98,98 109.01,99.03 109.01,101.56 107.8,102.77 107.8,104.65 106.5,105.94 105.39,105.94 104.55,106.79 103.65,106.79 103.07,107.36 v1(103.07,107.65) 104.9,109.48 104.9,110.49 104.01,111.39 104.01,117.69 104.91,118.6 104.91,126.47 105.29,126.85 105.29,135.66 105.46,135.83 105.46,135.83 106.2,136.57 107.61,136.57 109.98,138.94 109.98,140.67 111.05,141.74 114.29,141.74 117.54,144.99 124.1,144.99 v6(124.51,145.39)
  BOTTOM w0.173: v1(103.07,107.65) 103.07,107.93 102.62,108.39 R459.2
AM57XX_GPMC_AD7: length 106.3
  TOP w0.173: U1.L2 105.43,92.01 105.43,94.24 108.26,97.06 108.26,97.85 109.25,98.84 109.25,107.09 108.56,107.77 108.56,110.29 109.35,111.08 109.86,111.08 v1(110.87,112.1) R441.1
  L3_SIG1 w0.109: v6(133.37,144.33) 133.38,144.33 140.21,144.33 142.37,146.49 142.37,149.48 142.93,150.04 155.75,150.04 156.36,149.43 156.36,148.06 157.35,147.08 J21.57
  L4_SIG2 w0.114: v6(133.37,144.33) 133.35,144.3 130.96,144.3 123.97,137.3 115.97,137.3 114.22,135.55 111.7,135.55 109.98,133.83 109.98,128.38 108.73,127.13 108.73,123.12 109.36,122.49 109.36,116.16 110.42,115.1 110.42,112.54 v1(110.87,112.1)
  BOTTOM w0.173: R441.1 v1(110.87,112.1)
AM57XX_GPMC_AD8: length 77.9
  TOP w0.173: U1.L1 105.04,94.53 107.91,97.41 107.91,98 108.89,98.98 108.89,106.95 108.21,107.63 108.21,110.45 v1(109.86,112.1) R442.1
  L4_SIG2 w0.114: v1(109.86,112.1) 109.86,113.59 109.07,114.38 109.07,122.25 108.44,122.88 108.44,127.65 109.63,128.84 109.63,133.9 111.58,135.84 114.1,135.84 115.85,137.6 123.84,137.6 130.86,144.61 131.06,144.61 132.32,145.87 132.32,148.05 J21.32
  BOTTOM w0.173: v1(109.86,112.1) R442.1
AM57XX_GPMC_AD9: length 80.4
  TOP w0.173: U1.K2 106.24,92.02 106.24,94.35 108.61,96.73 108.61,97.71 109.6,98.69 109.6,107.4 v1(109.35,107.65) R443.1
  L3_SIG1 w0.109: J21.34 134.32,148.05 134.32,146.54 133.57,145.8 131.63,145.8 v6(131.09,145.26)
  L4_SIG2 w0.114: v1(109.35,107.65) 108.41,108.59 108.41,111.03 109.28,111.9 109.28,113.45 108.77,113.95 108.77,120.61 108.14,121.24 108.14,127.76 109.34,128.96 109.34,134.02 111.45,136.14 111.7,136.14 113.98,136.14 115.73,137.89 123.72,137.89 v6(131.09,145.26)
  BOTTOM w0.173: R443.1 v1(109.35,107.65)
AM57XX_GPMC_AD10: length 80.1
  TOP w0.173: U1.J1 106.64,94.07 108.96,96.39 108.96,97.56 109.95,98.55 109.95,107.23 v1(110.36,107.65) R444.1
  L4_SIG2 w0.114: J21.36 134.37,148.05 134.37,143.98 132.02,141.63 128.71,141.63 124.09,137.01 116.09,137.01 114.33,135.25 111.82,135.25 110.46,133.9 110.46,128.45 109.54,127.52 109.54,124.97 110.18,124.33 110.18,115.76 110.72,115.22 110.72,113.01 111.38,112.35 111.38,111.98 109.86,110.46 109.86,108.16 v1(110.36,107.65)
  BOTTOM w0.173: R444.1 v1(110.36,107.65)
AM57XX_GPMC_AD11: length 80.7
  TOP w0.173: U1.J2 107.03,92.01 107.03,93.88 109.31,96.16 109.31,97.42 110.3,98.4 110.3,106.57 v1(111.38,107.65) R445.1
  L4_SIG2 w0.114: J21.38 136.37,148.05 136.37,144.84 132.56,141.02 128.52,141.02 124.09,136.59 116.09,136.59 114.45,134.96 113.14,134.96 111.42,133.23 111.42,129.76 111.96,129.22 111.96,123.34 111.31,122.69 111.31,115.49 112.27,114.53 112.27,111.31 111.91,110.95 111.91,109.07 111.38,108.54 v1(111.38,107.65)
  BOTTOM w0.173: R445.1 v1(111.38,107.65)
AM57XX_GPMC_AD12: length 85.4
  TOP w0.173: R446.1 v1(112.39,107.68) 112.37,107.65 112.07,107.65 110.65,106.23 110.65,98.26 109.66,97.27 109.66,95.85 107.43,93.62 U1.H1
  L4_SIG2 w0.114: J21.42 142.32,148.05 142.32,146.62 132.98,137.27 125.19,137.27 124.22,136.3 116.21,136.3 114.48,134.57 113.41,134.57 112.16,133.32 112.16,131.55 113.03,130.68 113.03,123.58 111.89,122.45 111.89,116.17 113.93,114.14 113.93,109.85 113.02,108.94 113.02,108.27 112.42,107.68 v1(112.39,107.68)
  BOTTOM w0.173: R446.1 v1(112.39,107.68)
AM57XX_GPMC_AD13: length 97.3
  TOP w0.173: U1.J3 v4(107.03,91.21) ; R447.1 v1(105.66,107.14)
  L3_SIG1 w0.099: v4(107.03,91.21) 107.03,91.5 107.28,91.74 107.28,94.92
  L3_SIG1 w0.109: J21.44 144.32,148.04 144.32,146.36 141.5,143.54 134.19,143.54 133.55,142.91 132.1,142.91 131.49,143.51 v6(127.53,143.51) ; v6(108.4,96.03) 107.28,94.92
  L4_SIG2 w0.114: v6(127.53,143.51) 120.5,143.51 116.34,139.35 115.12,139.35 113.38,137.61 111.01,137.61 111.01,137.61 110.97,137.61 110.96,137.6 110.77,137.6 107.88,134.71 107.88,129.6 106.68,128.41 106.68,127 105.79,126.11 105.79,118.23 104.9,117.34 104.9,111.79 106.07,110.62 106.07,109.96 106.55,109.48 106.55,108.14 106.24,107.83 106.24,107.72 v1(105.66,107.14) 106.7,107.14 108.68,105.16 108.68,103.3 109.98,102.01 109.98,98.48 108.97,97.46 108.97,96.6 v6(108.4,96.03)
  BOTTOM w0.173: R447.1 v1(105.66,107.14)
AM57XX_GPMC_AD14: length 88.1
  TOP w0.173: R448.1 113.48,108.35 v1(113.48,107.6) 113.03,107.6 112.62,107.19 112.32,107.19 111,105.87 111,98.11 110.01,97.13 110.01,95.69 107.83,93.51 107.83,92.01 U1.H2
  L4_SIG2 w0.114: v1(113.48,107.6) 114.4,107.6 115.07,108.28 115.07,114.34 113.41,116 113.41,130.81 112.9,131.32 112.9,133.18 113.66,133.94 114.26,133.94 116.32,136 125.35,136 125.98,136.63 133.05,136.63 134.43,138 135.7,138 144.37,146.67 144.37,148.05 J21.46
  BOTTOM w0.173: R448.1 113.41,107.67 v1(113.48,107.6)
AM57XX_GPMC_AD15: length 98.4
  TOP w0.173: U1.H3 v4(107.83,91.21) ; R449.1 v1(106.68,107.65)
  L3_SIG1 w0.099: 107.94,94.14 107.94,91.32 v4(107.83,91.21)
  L3_SIG1 w0.109: v6(109.57,96.43) 109.57,95.77 107.94,94.14 ; v6(127.25,142.55) 129.81,142.55 130.43,141.94 131.47,141.94 132.08,142.55 134.22,142.55 134.72,143.06 143.06,143.06 146.33,146.33 146.33,148 J21.48
  L4_SIG2 w0.114: v6(109.57,96.43) 109.57,97.56 110.31,98.3 110.31,102.16 109.02,103.45 109.02,106.22 107.59,107.65 v1(106.68,107.65) 107.44,108.41 107.44,110.34 106.34,111.45 105.73,111.45 105.19,111.98 105.19,117.22 106.08,118.11 106.08,125.99 106.97,126.88 106.97,128.28 108.17,129.48 108.17,134.51 110.97,137.31 111.08,137.31 111.09,137.31 111.38,137.31 111.38,137.32 113.5,137.32 115.24,139.06 116.48,139.06 120.56,143.14 126.67,143.14 v6(127.25,142.55)
  BOTTOM w0.173: R449.1 v1(106.68,107.65)
AM57XX_HDMI_CLK+: length 84.1
  TOP w0.108: L29.4 56.28,21.44 56.01,21.72 56.01,22.18 56.44,22.61 57.51,22.61 60.96,26.06 67.7,26.06 69.47,27.83 69.47,43.9 71.11,45.53 71.11,65.17 71.22,65.28 71.44,65.28 71.55,65.39 71.55,65.61 71.44,65.71 71.22,65.71 71.11,65.82 71.11,66.04 71.22,66.15 71.44,66.15 71.55,66.25 71.55,66.47 71.44,66.58 71.22,66.58 71.11,66.69 71.11,67.28 84.25,80.42 U1.AH16
AM57XX_HDMI_CLK-: length 84.3
  TOP w0.108: L29.1 55.48,21.44 55.75,21.72 55.75,22.28 56.33,22.86 57.4,22.86 60.86,26.32 67.59,26.32 69.22,27.94 69.22,44 70.85,45.64 70.85,67.38 84.14,80.67 91.11,80.67 91.28,80.84 91.81,80.84 U1.AG16
AM57XX_HDMI_TX0+: length 85
  TOP w0.108: L30.4 58.82,21.44 58.56,21.71 58.56,22.33 61.32,25.1 67.97,25.1 70.52,27.65 70.52,28.37 70.64,28.5 71.4,28.5 71.68,28.77 71.68,29.16 71.4,29.44 70.64,29.44 70.52,29.56 70.52,29.74 70.64,29.87 71.4,29.87 71.68,30.14 71.68,30.53 71.4,30.81 70.64,30.81 70.52,30.93 70.52,43.56 72.45,45.5 72.45,65.24 72.56,65.34 72.79,65.34 72.9,65.45 72.9,65.67 72.79,65.78 72.56,65.78 72.45,65.88 72.45,66.1 72.56,66.21 72.79,66.21 72.9,66.31 72.9,66.53 72.79,66.64 72.56,66.64 72.45,66.75 72.45,67.38 84.68,79.62 U1.AH17
AM57XX_HDMI_TX0-: length 85.2
  TOP w0.108: U1.AG17 91.81,80.04 91.28,80.04 91.11,79.87 84.58,79.87 72.2,67.49 72.2,45.6 70.26,43.67 70.26,30.83 70.54,30.55 71.3,30.55 71.42,30.43 71.42,30.25 71.3,30.12 70.54,30.12 70.26,29.85 70.26,29.46 70.54,29.18 71.3,29.18 71.42,29.05 71.42,28.88 71.3,28.75 70.54,28.75 70.26,28.47 70.26,27.76 67.86,25.35 61.22,25.35 58.3,22.44 58.3,21.77 58.02,21.49 L30.1
AM57XX_HDMI_TX1+: length 85.4
  TOP w0.108: L31.4 71.27,21.57 70.99,21.84 70.99,22.89 71.69,23.59 71.69,25.55 73.09,26.95 73.09,31.8 72.82,32.08 72.19,32.08 72.06,32.2 72.06,32.38 72.19,32.51 72.82,32.51 73.09,32.78 73.09,33.17 72.82,33.45 72.19,33.45 72.06,33.57 72.06,33.75 72.19,33.88 72.82,33.88 73.09,34.16 73.09,34.54 72.82,34.82 72.19,34.82 72.06,34.95 72.06,35.13 72.19,35.25 72.82,35.25 73.09,35.53 73.09,35.92 72.82,36.19 72.19,36.19 72.06,36.32 72.06,36.5 72.19,36.62 72.82,36.62 73.09,36.9 73.09,37.29 72.82,37.56 72.19,37.56 72.06,37.69 72.06,37.87 72.19,37.99 72.82,37.99 73.09,38.27 73.09,38.66 72.82,38.93 72.19,38.93 72.06,39.06 72.06,39.24 72.19,39.37 72.82,39.37 73.09,39.64 73.09,40.03 72.82,40.31 72.19,40.31 72.06,40.43 72.06,40.61 72.19,40.74 72.82,40.74 73.09,41.01 73.09,41.4 72.82,41.68 72.19,41.68 72.06,41.8 72.06,41.98 72.19,42.11 72.82,42.11 73.09,42.38 73.09,42.77 72.82,43.05 72.19,43.05 72.06,43.18 72.06,43.35 72.19,43.48 72.82,43.48 73.81,44.47 73.81,65.29 73.92,65.4 74.14,65.4 74.24,65.5 74.24,65.72 74.14,65.83 73.92,65.83 73.81,65.94 73.81,66.15 73.92,66.26 74.14,66.26 74.24,66.37 74.24,66.58 74.14,66.69 73.92,66.69 73.81,66.8 73.81,67.51 85.12,78.81 U1.AH18
AM57XX_HDMI_TX1-: length 85.7
  TOP w0.108: L31.1 70.47,21.57 70.74,21.84 70.74,23 71.44,23.7 71.44,25.66 72.84,27.06 72.84,31.7 72.71,31.82 72.08,31.82 71.81,32.1 71.81,32.49 72.08,32.76 72.71,32.76 72.84,32.89 72.84,33.07 72.71,33.19 72.08,33.19 71.81,33.47 71.81,33.86 72.08,34.13 72.71,34.13 72.84,34.26 72.84,34.44 72.71,34.57 72.08,34.57 71.81,34.84 71.81,35.23 72.08,35.51 72.71,35.51 72.84,35.63 72.84,35.81 72.71,35.94 72.08,35.94 71.81,36.21 71.81,36.6 72.08,36.88 72.71,36.88 72.84,37 72.84,37.18 72.71,37.31 72.08,37.31 71.81,37.58 71.81,37.97 72.08,38.25 72.71,38.25 72.84,38.38 72.84,38.55 72.71,38.68 72.08,38.68 71.81,38.96 71.81,39.35 72.08,39.62 72.71,39.62 72.84,39.75 72.84,39.93 72.71,40.05 72.08,40.05 71.81,40.33 71.81,40.72 72.08,40.99 72.71,40.99 72.84,41.12 72.84,41.3 72.71,41.42 72.08,41.42 71.81,41.7 71.81,42.09 72.08,42.36 72.71,42.36 72.84,42.49 72.84,42.67 72.71,42.8 72.08,42.8 71.81,43.07 71.81,43.46 72.08,43.74 72.71,43.74 73.55,44.58 73.55,67.61 85.01,79.07 91.11,79.07 91.28,79.24 91.81,79.24 U1.AG18
AM57XX_HDMI_TX2+: length 83.6
  TOP w0.108: L32.4 73.81,21.57 73.53,21.84 73.53,25.15 73.96,25.58 73.96,31.79 74.09,31.91 74.81,31.91 75.08,32.19 75.08,32.58 74.81,32.85 74.09,32.85 73.96,32.98 73.96,33.16 74.09,33.29 74.81,33.29 75.08,33.56 75.08,33.95 74.81,34.23 74.09,34.23 73.96,34.35 73.96,34.53 74.09,34.66 74.81,34.66 75.08,34.93 75.08,35.32 74.81,35.6 74.09,35.6 73.96,35.72 73.96,35.9 74.09,36.03 74.81,36.03 75.08,36.3 75.08,36.69 74.81,36.97 74.09,36.97 73.96,37.1 73.96,37.27 74.09,37.4 74.81,37.4 75.08,37.68 75.08,38.07 74.81,38.34 74.09,38.34 73.96,38.47 73.96,38.65 74.09,38.77 74.81,38.77 75.08,39.05 75.08,39.44 74.81,39.71 74.09,39.71 73.96,39.84 73.96,40.02 74.09,40.14 74.81,40.14 75.08,40.42 75.08,40.81 74.81,41.08 74.09,41.08 73.96,41.21 73.96,41.39 74.09,41.52 74.81,41.52 75.08,41.79 75.08,42.18 74.81,42.46 74.09,42.46 73.96,42.58 73.96,42.76 74.09,42.89 74.78,42.89 75.24,43.35 75.24,67.7 85.55,78.02 86.02,78.02 86.13,77.91 86.13,77.76 86.23,77.65 86.45,77.65 86.56,77.76 86.56,77.91 86.67,78.02 86.88,78.02 86.99,77.91 86.99,77.76 87.1,77.65 87.31,77.65 87.42,77.76 87.42,77.91 87.53,78.02 87.74,78.02 87.85,77.91 87.85,77.76 87.96,77.65 88.18,77.65 88.28,77.76 88.28,77.91 88.39,78.02 U1.AH19
AM57XX_HDMI_TX2-: length 83.7
  TOP w0.108: L32.1 73.01,21.57 73.28,21.84 73.28,25.25 73.71,25.68 73.71,31.89 73.99,32.17 74.7,32.17 74.83,32.29 74.83,32.47 74.7,32.6 73.99,32.6 73.71,32.88 73.71,33.26 73.99,33.54 74.7,33.54 74.83,33.67 74.83,33.85 74.7,33.97 73.99,33.97 73.71,34.25 73.71,34.64 73.99,34.91 74.7,34.91 74.83,35.04 74.83,35.22 74.7,35.34 73.99,35.34 73.71,35.62 73.71,36.01 73.99,36.28 74.7,36.28 74.83,36.41 74.83,36.59 74.7,36.71 73.99,36.71 73.71,36.99 73.71,37.38 73.99,37.65 74.7,37.65 74.83,37.78 74.83,37.96 74.7,38.09 73.99,38.09 73.71,38.36 73.71,38.75 73.99,39.03 74.7,39.03 74.83,39.15 74.83,39.33 74.7,39.46 73.99,39.46 73.71,39.73 73.71,40.12 73.99,40.4 74.7,40.4 74.83,40.52 74.83,40.7 74.7,40.83 73.99,40.83 73.71,41.1 73.71,41.49 73.99,41.77 74.7,41.77 74.83,41.9 74.83,42.07 74.7,42.2 73.99,42.2 73.71,42.48 73.71,42.87 73.99,43.14 74.68,43.14 74.99,43.45 74.99,67.81 85.45,78.27 91.11,78.27 91.28,78.44 91.81,78.44 U1.AG19
AM57XX_I2C1_SCL: length 22.3
  TOP w0.173: 124.59,72.34 125.98,72.34 126.87,71.46 R385.2 R384.1 126.85,72.47 v5(126.62,72.7) ; U1.C20 v4(111.83,76.82)
  L3_SIG1 w0.109: v4(111.83,76.82) 116,76.82 116.28,77.09 117.96,77.09 120.02,75.04 121.26,75.04 122.63,73.66 124.81,73.66 125.19,73.29 126.03,73.29 v5(126.62,72.7)
AM57XX_I2C1_SDA: length 22.9
  TOP w0.173: 124.59,70.69 125.92,70.69 126.3,70.31 R387.2 R383.1 126.75,69.3 v5(126.62,69.42) ; U1.C21 v4(111.83,76.02)
  L3_SIG1 w0.109: v4(111.83,76.02) 112.05,75.8 116,75.8 119.48,72.32 121.13,72.32 122.28,71.18 123.75,71.18 124.53,70.39 125.65,70.39 v5(126.62,69.42)
AM57XX_INDETHER_LED0_GRN: length 164.5
  TOP w0.173: R803.2 84.94,91.5 v5(84.2,91.5)
  L3_SIG1 w0.109: v1(8.28,10.37) 6.65,11.99 6.65,29.97 4.19,32.44 4.19,33.61 2.79,35.01 2.79,42.16 4.45,43.82 4.45,47.65 3.91,48.19 3.91,82.66 6.14,84.88 12.85,84.88 16.53,88.56 28.75,88.56 29.66,89.46 32.77,89.46 36.73,93.43 48.39,93.43 50.04,91.78 58.21,91.78 58.69,92.26 68.33,92.26 68.67,92.6 70.46,92.6 71.93,94.06 73.49,94.06 75.36,92.2 77.6,92.2 77.7,92.29 80.07,92.29 80.28,92.09 81.24,92.09 81.83,91.5 v5(84.2,91.5)
  BOTTOM w0.173: 9.02,10.37 v1(8.28,10.37)
AM57XX_INDETHER_LED0_RED: length 237.1
  TOP w0.173: U1.B26 v4(112.63,72.02)
  L3_SIG1 w0.109: v1(8.31,3.64) 8.7,3.25 25.45,3.25 25.68,3.48 49.68,3.48 50.86,4.65 69.98,4.65 v6(86.87,21.54) ; v4(112.63,72.02) v6(113.03,71.77)
  L4_SIG2 w0.114: v6(86.87,21.54) 87.61,22.28 126.09,22.28 136.9,33.09 143.88,33.09 145.12,34.32 152.73,34.32 156.12,37.71 156.12,39.14 157.61,40.63 157.61,51.05 157.36,51.3 157.36,57.83 147.76,67.42 135.19,67.42 132.98,65.21 132.98,65.07 132.75,64.84 129.67,64.84 129.03,65.49 123.25,65.49 122.3,66.43 121.02,66.43 115.69,71.77 v6(113.03,71.77)
  BOTTOM w0.173: 9.02,3.64 v1(8.31,3.64)
AM57XX_INDETHER_LED0_YEL: length 272.4
  TOP w0.173: U1.D15 v4(111.03,80.82)
  L3_SIG1 w0.109: v6(128.02,78.69) 128.01,78.7 127.05,78.7 126.72,79.03 121.15,79.03 120.48,79.7 117.18,79.7 116.4,80.48 111.73,80.48 111.39,80.82 v4(111.03,80.82) ; v1(8.31,6.94) 9.32,5.92 17.64,5.92 18.37,6.65 49.69,6.65 50.63,5.71 65.99,5.71 68.32,8.05 68.32,8.05 69.88,9.61 v6(72.77,9.61)
  L4_SIG2 w0.114: v6(128.02,78.69) 128.07,78.64 129.47,78.64 130.14,79.31 150.49,79.31 153.13,76.67 153.13,76.19 161.07,68.25 161.87,68.25 170.35,59.76 170.35,43.17 169.73,42.54 169.73,35.95 154.56,20.78 153.67,20.78 141.82,8.93 134.53,8.93 133.01,7.41 128.52,7.41 127.85,6.74 119.67,6.74 119.21,7.2 114.3,7.2 113.37,8.13 112.07,8.13 111.16,7.23 104.56,7.23 103.84,7.96 98.66,7.96 97.54,9.07 92.89,9.07 92.36,9.61 v6(72.77,9.61)
  BOTTOM w0.173: 9.02,6.94 v1(8.31,6.94)
AM57XX_INDETHER_LED1_GRN: length 274.8
  TOP w0.173: U1.B17 112.64,79.21 114.93,79.21 117.12,77.02 118.69,77.02 120.22,75.49 v1(120.27,75.49)
  L3_SIG1 w0.109: v6(59.71,7.65) 56.88,7.65 55.7,8.82 54.34,8.82 52.75,7.23 24.9,7.23 21.65,10.48 15,10.48 v1(14.88,10.37)
  L4_SIG2 w0.114: v1(120.27,75.49) 123.64,78.87 125.38,78.87 126.54,80.04 132.28,80.04 133.86,81.62 152,81.62 158.93,74.68 158.93,72.66 163.63,67.97 164.71,67.97 168.03,64.65 168.03,63.84 172.46,59.4 172.46,46.18 171.61,45.33 171.61,39.28 170.76,38.43 170.76,34.39 152.71,16.34 151.26,16.34 139.36,4.44 114.78,4.44 112.74,6.48 112.31,6.48 111.9,6.07 105.29,6.07 104.63,5.42 92.2,5.42 91.67,5.94 61.41,5.94 v6(59.71,7.65)
  BOTTOM w0.173: R248.1 v1(14.88,10.37)
AM57XX_INDETHER_LED1_RED: length 265
  TOP w0.173: U1.B16 112.64,80.01 115.29,80.01 117.58,77.72 119.21,77.72 120.45,76.48 125.15,76.48 125.16,76.49 125.82,76.49 126.49,77.17 v5(145.67,77.17)
  L3_SIG1 w0.109: v5(145.67,77.17) v6(146.56,77.17) ; v6(74.42,12.34) 74.42,10.4 69.21,5.19 50.49,5.19 49.33,6.35 42.46,6.35 41.5,5.38 31.02,5.38 30.48,5.92 22.56,5.92 20.17,3.53 14.83,3.53 v6(14.22,4.15)
  L4_SIG2 w0.114: v6(146.56,77.17) 147,77.61 149.21,77.61 160.03,66.79 161.19,66.79 161.26,66.79 168.03,60.02 168.03,47.21 166.24,45.42 166.24,42.63 166.77,42.1 166.77,35.69 158.38,27.3 153.58,27.3 148.81,22.53 147.67,22.53 147.67,22.52 141.6,22.52 134.61,15.54 134.61,13.58 131.19,10.16 117.4,10.16 116.59,9.35 114.95,9.35 113.73,10.57 105.51,10.57 105.33,10.74 103.86,10.74 103.13,10.01 98.78,10.01 98.07,10.72 96.88,10.72 95.26,12.34 v6(74.42,12.34)
  L10_SIG4 w0.109: v6(14.22,4.15) 14.73,3.64 v9(14.83,3.64)
  BOTTOM w0.173: R243.2 v9(14.83,3.64)
AM57XX_INDETHER_LED1_YEL: length 251
  TOP w0.173: U1.A17 115.2,79.62 117.44,77.37 118.87,77.37 120.22,76.03 v5(125.35,76.03)
  L3_SIG1 w0.109: v6(15.57,7.09) 17.2,8.72 22.91,8.72 24.68,6.94 50.29,6.94 51.06,6.18 65.02,6.18 66.14,7.3 66.14,7.31 66.44,7.61 66.45,7.61 v6(73.15,14.31) ; v5(125.35,76.03) 125.65,75.72 127.28,75.72 v6(127.38,75.62)
  L4_SIG2 w0.114: v6(73.15,14.31) 104.4,14.31 106.53,12.19 116.3,12.19 117.54,13.43 128.64,13.43 139.66,24.46 145.48,24.46 150.56,29.54 156.42,29.54 163.2,36.32 163.2,37.54 162.55,38.19 162.55,38.83 163.45,39.72 163.45,55.56 164.47,56.58 164.47,61.1 160.53,65.03 159.31,65.03 149.36,74.98 145.94,74.98 144.24,76.68 132.23,76.68 131.17,75.62 v6(127.38,75.62)
  L10_SIG4 w0.109: v6(15.57,7.09) 15.42,6.94 v9(14.83,6.94)
  BOTTOM w0.173: R254.1 v9(14.83,6.94)
AM57XX_INDETHER_LED2_GRN: length 275.4
  TOP w0.173: U1.F16 v4(109.43,80.02)
  L3_SIG1 w0.109: v6(127.08,78.26) 126.6,78.74 121.01,78.74 120.33,79.41 116.7,79.41 116.42,79.69 112.18,79.69 111.56,80.32 109.74,80.32 v4(109.43,80.02) ; v1(8.28,17.1) 8.59,16.79 15.31,16.79 18.24,13.86 19.79,13.86 25.25,8.41 52.45,8.41 55.37,11.33 62.89,11.33 v6(63.5,10.72)
  L4_SIG2 w0.114: v6(63.5,10.72) 68.39,10.72 69.29,9.82 72.37,9.82 72.59,10.04 92.34,10.04 93.02,9.37 97.66,9.37 98.69,8.34 106.6,8.34 106.85,8.08 111,8.08 112.32,9.4 113.24,9.4 114.49,8.16 132.34,8.16 138.9,14.71 145.7,14.71 153.29,22.31 155.45,22.31 169.14,36 169.14,42.37 170.06,43.29 170.06,59.64 161.75,67.96 160.95,67.96 152.84,76.07 152.84,76.55 150.37,79.02 130.37,79.02 129.61,78.26 127.83,78.26 127.83,78.26 v6(127.08,78.26)
  BOTTOM w0.173: 9.02,17.1 v1(8.28,17.1)
AM57XX_INDETHER_LED2_RED: length 253.2
  TOP w0.173: U1.B25 112.63,72.82 113.31,72.82 115,71.12 115.9,71.12 119.38,67.65 v1(121.28,67.65)
  L3_SIG1 w0.109: v1(8.28,13.8) 12.7,13.8 13.31,14.4 15.51,14.4 17.34,12.57 20.58,12.57 25.04,8.1 52.55,8.1 55.24,10.79 58.93,10.79 59.87,9.86 64,9.86 70.08,15.94 v6(70.08,20.22)
  L4_SIG2 w0.114: v6(70.08,20.22) 90.91,20.22 91.99,19.13 93.93,19.13 94.48,19.68 100.27,19.68 100.41,19.82 112.07,19.82 112.21,19.68 117.39,19.68 117.9,20.18 120.86,20.18 121.76,19.28 127.62,19.28 140.32,31.98 144.7,31.98 146.09,33.37 155.81,33.37 157.89,35.46 157.89,39.01 159.53,40.65 159.53,48.32 158.9,48.95 158.9,51.81 159.47,52.37 159.47,54.51 159.13,54.85 159.13,59.39 157.56,60.96 157.56,62.62 154.44,65.75 152.5,65.75 152.49,65.73 151.68,65.73 150.75,66.66 150.75,68.15 149.64,69.26 148.5,69.26 147.33,70.43 140.94,70.43 139.41,71.97 138.98,71.97 138.69,71.68 136.14,71.68 131.95,67.49 128.97,67.49 128.82,67.34 121.59,67.34 v1(121.28,67.65)
  BOTTOM w0.173: 9.02,13.8 v1(8.28,13.8)
AM57XX_INDETHER_LED2_YEL: length 253.7
  TOP w0.173: U1.A24 113.67,74.02 115.54,72.14 116.54,72.14 119.55,69.12 121.44,69.12 121.61,68.95 v1(121.61,68.92)
  L3_SIG1 w0.109: v6(59.69,19.77) 59.69,18.14 50.52,8.97 26.01,8.97 16.92,18.05 16.92,19.11 15.06,20.96 13.9,20.96 13.49,20.55 v1(8.28,20.55)
  L4_SIG2 w0.114: v6(59.69,19.77) 60.27,19.19 63.66,19.19 64.44,18.41 97.83,18.41 97.85,18.42 100.27,18.42 100.67,18.03 106.21,18.03 107.19,19 110.87,19 111.34,18.54 127.65,18.54 140.65,31.53 145.03,31.53 146.47,32.97 155.82,32.97 158.18,35.34 158.18,38.89 159.82,40.53 159.82,48.63 160.07,48.87 160.07,50.98 159.76,51.29 159.76,54.12 160.46,54.82 160.46,58.93 157.85,61.54 157.85,62.75 153.42,67.18 151.82,67.18 151.17,67.82 151.17,69.34 149.39,71.13 140.66,71.13 139.53,72.26 138.86,72.26 138.57,71.97 135.72,71.97 131.78,68.03 122.5,68.03 v1(121.61,68.92)
  BOTTOM w0.173: 9.02,20.53 8.31,20.53 v1(8.28,20.55)
AM57XX_INDETHER_LED3_GRN: length 169.3
  TOP w0.173: U1.AF6 v4(92.64,88.02)
  L3_SIG1 w0.109: v4(92.64,88.02) 90.57,90.08 89.88,90.08 89.17,90.79 85.68,90.79 85.48,90.59 84.61,90.59 84.29,90.91 78.01,90.91 77.34,91.58 72.06,91.58 71.94,91.7 69.06,91.7 68.5,91.14 63.1,91.14 62.08,90.12 58.17,90.12 56.8,91.49 49.92,91.49 49.25,92.15 39.61,92.15 38.63,93.14 36.85,93.14 32.89,89.18 29.78,89.18 28.87,88.28 16.65,88.28 12.97,84.6 6.26,84.6 4.2,82.54 4.2,48.31 4.74,47.77 4.74,43.7 4.06,43.03 4.06,34.55 4.57,34.04 4.57,32.69 7.37,29.9 7.37,20.85 8.1,20.12 14.47,20.12 v1(14.88,20.53)
  BOTTOM w0.173: R593.1 15.01,20.66 v1(14.88,20.53)
AM57XX_INDETHER_LED3_RED: length 248
  TOP w0.173: v1(121.59,69.86) 120.96,69.86 120.76,70.06 120.74,70.06 120.69,70.11 119.58,70.11 116.81,72.88 116.35,72.88 113.61,75.62 U1.A22
  L3_SIG1 w0.109: v1(14.88,13.92) 14.95,13.92 17,11.87 20.77,11.87 24.84,7.8 52.86,7.8 55.01,9.95 57.49,9.95 58.62,8.82 66.43,8.82 71.94,14.34 v6(71.94,17.37)
  L4_SIG2 w0.114: v6(71.94,17.37) 72.04,17.27 88.24,17.27 88.84,17.86 91.44,17.86 92.33,16.97 102.11,16.97 102.49,17.35 105.92,17.35 106.5,16.77 110.81,16.77 111.4,17.35 116.58,17.35 116.78,17.15 118.42,17.15 118.61,17.35 120.15,17.35 120.34,17.15 124.51,17.15 124.8,17.44 127.48,17.44 141.14,31.1 145.42,31.1 146.9,32.59 155.85,32.59 158.48,35.21 158.48,38.77 160.12,40.41 160.12,48.4 160.4,48.69 160.4,51.08 160.05,51.43 160.05,54 161.11,55.05 161.11,59.92 153.55,67.47 152.35,67.47 151.47,68.36 151.47,69.47 149.23,71.7 143.94,71.7 142.28,73.37 138.47,73.37 137.37,72.26 135.41,72.26 131.48,68.33 123.12,68.33 v1(121.59,69.86)
  BOTTOM w0.173: R514.2 v1(14.88,13.92)
AM57XX_INDETHER_LED3_YEL: length 176.8
  TOP w0.173: v4(92.48,91.22) 92.63,91.22 U1.AF3
  L3_SIG1 w0.109: v6(5.94,17.2) 5.94,30.1 3.86,32.17 3.86,33.53 2.32,35.07 2.32,47.59 3.59,48.86 3.59,83.15 5.83,85.39 12.18,85.39 17.01,90.22 24.77,90.22 25.26,89.74 29.34,89.74 29.84,90.24 31.26,90.24 34.73,93.71 48.51,93.71 50.16,92.06 58.07,92.06 58.55,92.54 68.17,92.54 68.65,93.03 70.22,93.03 72.53,95.33 75.04,95.33 75.96,94.42 77.57,94.42 78.54,93.45 80.11,93.45 81.03,94.37 86.08,94.37 87.96,92.49 89.72,92.49 90.41,91.8 91.9,91.8 v4(92.48,91.22)
  L9_SIG3 w0.114: v1(14.88,17.23) 14.57,17.54 6.27,17.54 v6(5.94,17.2)
  BOTTOM w0.173: R598.1 v1(14.88,17.23)
AM57XX_LCD_DE: length 8.3
  TOP w0.173: U1.B10 112.63,85.61 114.54,85.61 116,87.08 R634.2
AM57XX_LCD_HSYNC: length 12.9
  TOP w0.173: U1.C11 v4(111.83,84.81) ; R636.2 v5(122.81,86.31)
  L3_SIG1 w0.109: v4(111.83,84.81) 112.03,85.01 116.48,85.01 116.67,85.19 120.77,85.19 120.92,85.35 121.84,85.35 v5(122.81,86.31)
AM57XX_LCD_PCLK: length 18.3
  TOP w0.173: v5(126.7,86.87) 127.33,86.87 R565.2 ; U1.D11 v4(111.03,84.81)
  L3_SIG1 w0.109: v5(126.7,86.87) 126.39,87.18 125.07,87.18 124.71,86.82 123.8,86.82 123.49,87.13 122.22,87.13 120.7,85.6 116.61,85.6 116.28,85.27 111.79,85.27 111.61,85.09 111.31,85.09 v4(111.03,84.81)
AM57XX_LCD_VSYNC: length 19.1
  TOP w0.173: R635.2 v5(126.62,88.09) ; U1.E11 v4(110.23,84.81)
  L3_SIG1 w0.109: v4(110.23,84.81) 110.72,85.3 111.52,85.3 111.86,85.63 115.8,85.63 116.13,85.96 117.87,85.96 118.15,85.96 118.69,86.5 120.3,86.5 121.89,88.09 v5(126.62,88.09)
AM57XX_MCASP1_AXR4: length 18.5
  TOP w0.173: U1.E12 v4(110.23,84.01) ; R673.2 v5(126.62,85.81)
  L3_SIG1 w0.109: v4(110.23,84.01) 110.73,84.51 111.94,84.51 111.95,84.52 111.96,84.52 112.14,84.7 116.64,84.7 116.79,84.85 121.12,84.85 121.26,84.99 122.86,84.99 123.67,85.81 v5(126.62,85.81)
AM57XX_MCASP1_AXR5: length 21.3
  TOP w0.173: U1.F13 v4(109.43,83.21)
  L3_SIG1 w0.109: v4(109.43,83.21) v6(109.83,83.46)
  L4_SIG2 w0.114: v6(123.44,83.39) 123.17,83.67 120.4,83.67 119.79,84.28 110.65,84.28 v6(109.83,83.46)
  L10_SIG4 w0.109: v9(121.79,79.2) 123.44,80.85 v6(123.44,83.39)
  BOTTOM w0.173: R674.2 121.67,79.08 v9(121.79,79.2)
AM57XX_MCASP1_AXR6: length 16.6
  TOP w0.173: R675.2 127.36,83.29 v5(125.53,83.29) ; U1.C12 v4(111.83,84.01)
  L3_SIG1 w0.109: v4(111.83,84.01) 112.18,84.01 112.31,84.15 120.3,84.15 120.65,83.79 123.21,83.79 123.34,83.93 124.89,83.93 v5(125.53,83.29)
AM57XX_MCASP1_AXR7: length 17.9
  TOP w0.173: R676.2 v5(126.64,84.54) ; U1.D12 v4(111.03,84.01)
  L3_SIG1 w0.099: 112.16,84.31 111.33,84.31 v4(111.03,84.01)
  L3_SIG1 w0.109: 112.16,84.31 112.28,84.43 116.79,84.43 116.9,84.54 120.52,84.54 120.96,84.1 123.01,84.1 123.9,84.99 126.19,84.99 v5(126.64,84.54)
AM57XX_MMC1_CLK: length 33.6
  TOP w0.173: U1.W6 v4(98.24,88.81) ; 78.87,105.11 v5(79.63,105.11)
  L3_SIG1 w0.109: v6(97.84,89.06) 97.84,89.06 98.23,88.81 v4(98.24,88.81) ; v5(79.63,105.11) 81.61,103.13 92.79,103.13 93.4,102.52 94.28,102.52 97.54,99.27 v6(97.54,98.61)
  L10_SIG4 w0.109: v6(97.54,98.61) 98.02,98.61 98.37,98.25 98.37,94.47 97.97,94.06 97.97,93.25 97.79,93.07 97.79,91.29 98.25,90.84 98.25,89.47 v6(97.84,89.06)
AM57XX_MMC1_CMD: length 32.3
  TOP w0.173: 78.87,104.09 v5(79.63,104.09) ; U1.Y6 v4(97.44,88.81)
  L3_SIG1 w0.109: v6(97.04,89.06) v4(97.44,88.81) ; v5(79.63,104.09) 80.95,102.77 92.51,102.77 93.32,101.96 94.18,101.96 v6(97.03,99.12)
  L10_SIG4 w0.109: v6(97.03,99.12) 97.03,97.56 95.81,96.34 95.81,90.29 v6(97.04,89.06)
AM57XX_MMC1_DAT0: length 28.4
  TOP w0.173: U1.AA6 v4(96.64,88.81) ; 78.87,101.05 v5(79.63,101.05)
  L3_SIG1 w0.109: v6(95.91,97.11) 94.13,98.89 93.38,98.89 93.09,98.6 83.72,98.6 81.28,101.05 v5(79.63,101.05) ; v4(96.64,88.81) 96.64,88.82 v6(96.24,89.06)
  L10_SIG4 w0.109: v6(95.91,97.11) 95.58,96.78 95.58,90.22 96.24,89.56 v6(96.24,89.06)
AM57XX_MMC1_DAT1: length 28
  TOP w0.173: 78.87,102.06 v5(79.63,102.06) ; U1.Y4 v4(97.44,90.41)
  L3_SIG1 w0.109: v4(97.44,90.41) 97.03,90.82 97.03,92.57 96.85,92.75 96.85,94.98 97.21,95.33 97.21,97.11 94.36,99.95 94.03,99.95 91.92,102.06 v5(79.63,102.06)
AM57XX_MMC1_DAT2: length 25.9
  TOP w0.173: 78.87,100.03 v5(79.63,100.03) ; U1.AA5 v4(96.64,89.61)
  L3_SIG1 w0.102: 96.14,91.93 96.14,91.93 96.14,90.11 v4(96.64,89.61)
  L3_SIG1 w0.109: v5(79.63,100.03) 80.26,100.03 82.04,98.25 92.76,98.25 93.09,97.92 93.96,97.92 96.14,95.74 96.14,91.93
AM57XX_MMC1_DAT3: length 28
  TOP w0.173: U1.Y3 v4(97.44,91.21) ; 78.87,103.08 v5(79.63,103.08)
  L3_SIG1 w0.109: v4(97.44,91.21) 97.44,92.74 97.69,92.99 97.69,94.59 97.92,94.82 97.92,96.22 97.56,96.58 97.56,97.24 92.38,102.42 80.29,102.42 v5(79.63,103.08)
AM57XX_MMC1_SDCD: length 36.8
  TOP w0.173: v5(75.44,94.11) v5(75.44,98.51) ; 78.87,99.01 v5(79.63,99.01) ; U1.W7 v4(98.24,88.01)
  L3_SIG1 w0.099: 94.87,87.72 95.16,87.72 95.28,87.84 95.58,87.84 95.61,87.83 95.71,87.72 95.96,87.72 96.07,87.84 96.08,87.84 96.38,87.84 96.41,87.83 96.51,87.72 96.76,87.72 96.88,87.84 96.88,87.84 97.18,87.84 97.21,87.83 97.31,87.72 97.56,87.72 97.85,88.01 v4(98.24,88.01)
  L3_SIG1 w0.109: v5(79.63,99.01) 79.12,98.51 v5(75.44,98.51) ; v5(75.44,94.11) 76.07,93.47 77.22,93.47 77.85,92.84 79.14,92.84 79.4,92.58 80.19,92.58 80.4,92.37 82.25,92.37 82.68,91.95 84.84,91.95 85.24,92.35 86.08,92.35 86.9,91.54 89.45,91.54 90.07,90.91 91.09,90.91 91.76,90.25 92.48,90.25 93.61,89.12 94.35,89.12 94.54,88.93 94.54,88.05 94.87,87.72
AM57XX_MMC1_SDWP: length 40.5
  TOP w0.173: v1(87.76,107.52) 87.12,106.89 R644.1 J44.1 ; U1.Y9 v4(97.44,86.41)
  L3_SIG1 w0.109: v6(97.04,86.66) v4(97.44,86.41)
  L4_SIG2 w0.114: v1(87.76,107.52) 88.88,106.4 91.97,106.4 92.33,106.05 94.28,106.05 94.75,105.58 95.31,105.58 97.92,102.97 97.92,100.94 99.64,99.22 99.64,93.9 101.73,91.82 101.73,86.57 101.41,86.25 97.45,86.25 v6(97.04,86.66)
AM57XX_OSC0_IN: length 20.3
  TOP w0.173: Y1.3 74.71,81.27 75.31,81.87 C2.1 R4.2 v5(78.36,81.87) ; U1.AE15 v4(93.44,80.82)
  L3_SIG1 w0.109: v5(78.36,81.87) 78.43,81.94 82.73,81.94 83.05,81.62 87.29,81.62 87.96,80.95 91.7,80.95 91.92,81.16 92.78,81.16 92.86,81.08 93.17,81.08 v4(93.44,80.82)
AM57XX_OSC0_OUT: length 17
  TOP w0.173: U1.AD15 v4(94.24,80.82) ; v5(79.76,83.43) R5.1
  L3_SIG1 w0.109: v5(79.76,83.43) 80.75,82.43 82.86,82.43 83.21,82.08 87.13,82.08 88.04,81.18 91.57,81.18 91.77,81.38 93.67,81.38 v4(94.24,80.82)
AM57XX_PCIE_PERN0: length 75.8
  TOP w0.108: v1(79,80.27) 79,80.32 80.09,81.41 80.42,81.41 81.25,82.24 81.25,84.24 82.34,85.33 84.67,85.33 85.2,85.86 87.84,85.86 90.63,83.07 91.12,83.07 91.23,83.18 91.87,83.18 U1.AG13
  BOTTOM w0.108: v1(79,80.27) 79.17,80.09 79.17,79.3 78.74,78.87 76.33,78.87 75.06,77.6 75.06,70.74 75.68,70.11 75.68,51.57 61.54,37.44 61.54,34.61 62.23,33.92 62.87,33.92 J22.A17
AM57XX_PCIE_PERP0: length 75.7
  TOP w0.108: v1(79.62,80.26) 79.62,80.58 80.19,81.15 80.53,81.15 81.51,82.13 81.51,84.14 82.44,85.07 84.77,85.07 85.3,85.6 87.73,85.6 88.58,84.76 88.58,84.58 88.5,84.5 88.5,84.32 88.63,84.19 88.81,84.19 88.88,84.27 89.06,84.27 89.19,84.15 89.19,83.97 89.11,83.89 89.11,83.71 89.24,83.58 89.42,83.58 89.5,83.66 89.67,83.66 90.52,82.81 U1.AH13
  BOTTOM w0.108: J22.A16 63.01,35.16 63.52,34.65 63.52,34.35 63.35,34.18 62.34,34.18 61.8,34.72 61.8,37.33 75.94,51.47 75.94,70.22 75.31,70.84 75.31,77.49 76.43,78.61 78.85,78.61 79.43,79.2 79.43,80.07 v1(79.62,80.26)
AM57XX_PCIE_PETN0: length 67.5
  TOP w0.108: U1.AG14 91.81,82.44 91.23,82.44 91.06,82.27 89.42,82.27 87.96,83.72 85.04,83.72 84.66,83.34 82.75,83.34 82.13,82.72 82.13,81.53 80.13,79.53 73.75,79.53 71.52,77.29 71.52,71.75 63.84,64.07 63.84,61.93 61.09,59.18 61.09,48.21 63.25,46.05 63.25,45.48 65.91,42.82 C477.1
AM57XX_PCIE_PETP0: length 67.5
  TOP w0.108: C478.1 66.5,41.45 66.27,41.45 66.17,41.56 66.17,42.93 63.51,45.59 63.51,46.15 61.34,48.32 61.34,59.07 64.09,61.82 64.09,63.97 71.77,71.64 71.77,77.18 73.86,79.27 80.24,79.27 82.39,81.42 82.39,82.61 82.86,83.08 84.77,83.08 85.15,83.47 87.86,83.47 88.04,83.29 88.04,83.11 87.94,83.01 87.94,82.83 88.06,82.7 88.24,82.7 88.35,82.8 88.53,82.8 88.65,82.68 88.65,82.5 88.55,82.39 88.55,82.22 88.68,82.09 88.85,82.09 88.96,82.19 89.14,82.19 89.31,82.02 U1.AH14
AM57XX_PCIE_REF_CLKN: length 19.2
  TOP w0.108: U1.AH15 83.43,81.21 81.6,79.38 81.6,79.23 81.62,79.21 81.62,79.06 81.46,78.9 81.31,78.9 81.29,78.92 81.14,78.92 80.99,78.77 80.99,78.62 81.01,78.6 81.01,78.45 80.85,78.29 80.7,78.29 80.68,78.31 80.53,78.31 80.37,78.16 80.37,78.01 80.4,77.99 80.4,77.84 80.24,77.68 80.09,77.68 80.07,77.7 79.92,77.7 79.64,77.42 79.38,77.42 R581.1 78.23,77.04 75.56,77.04 C438.2
AM57XX_PCIE_REF_CLKP: length 19.2
  TOP w0.108: U1.AG15 91.81,81.64 91.28,81.64 91.11,81.47 83.32,81.47 79.53,77.68 R581.2 78.23,77.3 75.56,77.3 C439.2
AM57XX_PORZN: length 30.9
  TOP w0.173: R6.1 v5(132.46,74.07) ; U1.F22 v4(109.43,75.22)
  L3_SIG1 w0.109: v5(132.46,74.07) v6(133.07,73.46) ; v4(109.43,75.22) v6(109.83,74.97)
  L4_SIG2 w0.114: v6(133.07,73.46) 133.07,72.28 131.79,71 123.97,71 123.7,71.28 119.02,71.28 116.26,74.04 116.26,75.36 115.65,75.97 110.82,75.97 109.83,74.99 v6(109.83,74.97)
AM57XX_PR1_UART0_RXD: length 92.8
  TOP w0.173: U1.F2 109.43,92.01 109.43,93.41 111.15,95.13 111.15,96.63 112.9,98.38 v1(112.9,102.34) R575.2
  L4_SIG2 w0.114: v1(112.9,102.34) 115.15,100.1 124.14,100.1 125.35,98.89 132.72,98.89 142.44,108.61 142.44,110.89 143.64,112.1 143.64,122.05 144.22,122.63 144.22,123.63 143.64,124.21 143.64,129.75 142.62,130.76 142.62,136.48 140.02,139.08 140.02,140.74 142.16,142.88 143.2,142.88 J21.47
AM57XX_PR1_UART0_TXD: length 237.9
  TOP w0.173: U1.F3 v4(109.43,91.21) ; R199.2 v1(50.93,75.92)
  L3_SIG1 w0.099: 109.43,94.17 v4(109.43,91.21)
  L3_SIG1 w0.109: 109.43,94.17 111.25,95.99 111.25,96.61 111.48,96.84 111.48,98.77 112.27,99.56 112.27,100.11 v6(111.69,100.69)
  L4_SIG2 w0.114: v1(50.93,75.92) 49.61,77.23 49.61,79.05 51.26,80.69 51.26,81.28 52.83,82.85 56.61,82.85 56.82,83.06 56.84,83.06 65.44,91.66 65.44,92.6 70.43,97.59 73.89,97.59 74.22,97.26 75.18,97.26 75.46,97.54 77.67,97.54 78.46,98.32 78.46,99.73 80.59,101.86 80.59,109.35 79.62,110.33 79.62,111.64 84.18,116.2 84.18,128.86 87.55,132.23 88.72,132.23 89.92,133.43 95.12,133.43 v1(101.43,139.74) ; v6(111.69,100.69) 111.69,101.85 112.67,102.83 114.01,102.83 116.08,100.76 125.22,100.76 126.67,99.31 128.52,99.31 129.31,100.1 132.66,100.1 137.54,104.98 137.54,110.08 137.09,110.54 137.09,111.12 137.09,111.12 137.09,111.55 137.09,111.55 137.09,111.71 136.91,111.89 136.91,113.49 135.66,114.74 135.66,117.72 137.59,119.66 137.59,123.82 136.78,124.64 136.78,131.33 136.39,131.72 136.39,134.37 138.79,136.77 138.79,140.47 J21.45
  L10_SIG4 w0.109: v9(112.19,100.38) 111.88,100.69 v6(111.69,100.69)
  BOTTOM w0.173: v1(101.43,139.74) 104.95,143.26 126.79,143.26 128.91,145.37 143.79,145.37 145.35,146.93 J21.45 ; v9(112.19,100.38) 112.19,99.48 112.39,99.27 R574.2
AM57XX_PR2_PROFI_TXEN: length 120.3
  TOP w0.173: U1.U3 v4(99.84,91.21)
  L3_SIG1 w0.109: v6(126.97,145.55) 125.25,143.82 125.25,141.86 125.91,141.2 133.55,141.2 135,142.65 144.98,142.65 J21.49 ; v6(101.98,101.1) 101.98,99.98 100.3,98.3 100.3,96.68 99.77,96.14 99.77,92.23 100,92 100,91.38 v4(99.84,91.21)
  L4_SIG2 w0.114: v6(126.97,145.55) 126.52,146 124.94,146 124.82,146.13 124.21,146.13 123.8,145.72 116.76,145.72 114.63,143.59 111.17,143.59 109.22,141.65 109.22,139.37 107.01,137.16 105.88,137.16 103.91,135.19 103.91,135.19 103.74,135.02 103.74,126.1 102.58,124.93 102.58,120.8 103.23,120.15 103.23,120.15 103.34,120.03 103.34,118.68 102.57,117.91 102.57,111.1 100.94,109.47 100.94,106.38 101.98,105.33 103.41,105.33 104.48,104.27 106.04,104.27 106.48,103.82 106.48,102.11 107.8,100.79 107.8,99.84 107.45,99.49 104.79,99.49 103.19,101.1 v6(101.98,101.1)
AM57XX_PRU1ETH0_MRCLK: length 136
  TOP w0.173: v5(94.61,100.89) 95.56,99.94 95.56,97.46 97.83,95.19 U1.Y1
  L3_SIG1 w0.109: v5(94.61,100.89) v6(94.18,101.33)
  L10_SIG4 w0.109: v9(24.77,110.04) 25.88,110.04 27.69,108.23 28.6,108.23 28.71,108.13 28.71,107.73 28.82,107.62 29.03,107.62 29.14,107.73 29.14,108.13 29.25,108.23 29.47,108.23 29.58,108.13 29.58,107.73 29.69,107.62 29.91,107.62 30.02,107.73 30.02,108.13 30.13,108.23 30.34,108.23 30.45,108.13 30.45,107.73 30.56,107.62 30.78,107.62 30.89,107.73 30.89,108.13 31,108.23 31.22,108.23 31.33,108.13 31.33,107.73 31.44,107.62 31.66,107.62 31.76,107.73 31.76,108.13 31.87,108.23 32.09,108.23 32.2,108.13 32.2,107.73 32.31,107.62 32.53,107.62 32.64,107.73 32.64,108.13 32.75,108.23 32.97,108.23 33.08,108.13 33.08,107.73 33.18,107.62 33.4,107.62 33.51,107.73 33.51,108.13 33.62,108.23 33.84,108.23 33.95,108.13 33.95,107.73 34.06,107.62 34.28,107.62 34.39,107.73 34.39,108.13 34.5,108.23 34.71,108.23 34.82,108.13 34.82,107.73 34.93,107.62 35.15,107.62 35.26,107.73 35.26,108.13 35.37,108.23 36.3,108.23 41.71,102.82 44.81,102.82 44.92,102.93 44.92,104.04 45.03,104.14 45.25,104.14 45.36,104.04 45.36,102.93 45.47,102.82 45.68,102.82 45.79,102.93 45.79,104.04 45.9,104.14 46.12,104.14 46.23,104.04 46.23,102.93 46.34,102.82 46.56,102.82 46.67,102.93 46.67,104.04 46.78,104.14 46.99,104.14 47.1,104.04 47.1,102.93 47.21,102.82 47.43,102.82 47.54,102.93 47.54,104.04 47.65,104.14 47.87,104.14 47.98,104.04 47.98,102.93 48.09,102.82 48.3,102.82 48.41,102.93 48.41,104.04 48.52,104.14 48.74,104.14 48.85,104.04 48.85,102.93 48.96,102.82 49.18,102.82 49.29,102.93 49.29,104.04 49.4,104.14 49.62,104.14 49.72,104.04 49.72,102.93 49.83,102.82 50.05,102.82 50.16,102.93 50.16,104.04 50.27,104.14 50.49,104.14 50.6,104.04 50.6,102.93 50.71,102.82 50.93,102.82 51.04,102.93 51.04,104.04 51.14,104.14 51.36,104.14 51.47,104.04 51.47,102.93 51.58,102.82 51.8,102.82 51.91,102.93 51.91,104.04 52.02,104.14 52.24,104.14 52.35,104.04 52.35,102.93 52.46,102.82 52.67,102.82 52.78,102.93 52.78,104.04 52.89,104.14 53.11,104.14 53.22,104.04 53.22,102.93 53.33,102.82 53.55,102.82 53.66,102.93 53.66,104.04 53.77,104.14 53.98,104.14 54.09,104.04 54.09,102.93 54.2,102.82 54.42,102.82 54.53,102.93 54.53,104.04 54.64,104.14 54.86,104.14 54.97,104.04 54.97,102.93 55.08,102.82 55.3,102.82 55.4,102.93 55.4,104.04 55.51,104.14 55.73,104.14 55.84,104.04 55.84,102.93 55.95,102.82 56.17,102.82 56.28,102.93 56.28,104.04 56.39,104.14 56.61,104.14 56.71,104.04 56.71,102.93 56.82,102.82 58.27,102.82 59.69,101.4 60.63,101.4 60.99,101.76 67.74,101.76 67.95,101.55 77.29,101.55 77.67,101.93 77.67,102.69 77.81,102.84 78.01,102.84 78.15,102.69 78.15,101.29 78.29,101.15 78.49,101.15 78.63,101.29 78.63,102.69 78.78,102.85 80.06,102.85 80.21,102.69 80.21,101.2 80.35,101.06 80.55,101.06 80.69,101.2 80.69,102.69 80.83,102.84 81.03,102.84 81.17,102.69 81.17,101.16 81.36,100.97 91.49,100.97 91.85,101.33 v6(94.18,101.33)
  BOTTOM w0.173: R83.2 v9(24.77,110.04)
AM57XX_PRU1ETH0_RXDV: length 135.6
  TOP w0.173: U1.V2 99.04,92.01 99.04,93.58 98.81,93.81 98.81,96.86 96.98,98.68 v5(96.98,101.15)
  L3_SIG1 w0.109: v5(96.98,101.15) v6(96.98,101.73)
  L10_SIG4 w0.109: v9(24.77,108.69) 25.68,108.69 27.23,107.14 35.59,107.14 40.31,102.42 40.31,101.6 40.98,100.93 44.6,100.93 44.72,101.05 44.72,102 44.83,102.12 45,102.12 45.11,102 45.11,101.05 45.23,100.93 45.39,100.93 45.51,101.05 45.51,102 45.63,102.12 45.79,102.12 45.91,102 45.91,101.05 46.02,100.93 46.19,100.93 46.3,101.05 46.3,102 46.42,102.12 46.58,102.12 46.7,102 46.7,101.05 46.81,100.93 46.98,100.93 47.1,101.05 47.1,102 47.21,102.12 47.38,102.12 47.49,102 47.49,101.05 47.61,100.93 47.77,100.93 47.89,101.05 47.89,102 48,102.12 48.17,102.12 48.28,102 48.28,101.05 48.4,100.93 48.56,100.93 48.68,101.05 48.68,102 48.8,102.12 48.96,102.12 49.08,102 49.08,101.05 49.19,100.93 49.36,100.93 49.47,101.05 49.47,102 49.59,102.12 49.75,102.12 49.87,102 49.87,101.05 49.98,100.93 50.15,100.93 50.27,101.05 50.27,102 50.38,102.12 50.55,102.12 50.66,102 50.66,101.05 50.78,100.93 52.33,100.93 52.44,101.04 52.44,101.72 52.55,101.83 52.76,101.83 52.87,101.72 52.87,101.04 52.98,100.93 53.2,100.93 53.31,101.04 53.31,101.72 53.42,101.83 53.64,101.83 53.75,101.72 53.75,101.04 53.86,100.93 54.07,100.93 54.18,101.04 54.18,101.72 54.29,101.83 54.51,101.83 54.62,101.72 54.62,101.04 54.73,100.93 54.95,100.93 55.06,101.04 55.06,101.72 55.17,101.83 55.39,101.83 55.49,101.72 55.49,101.04 55.6,100.93 55.82,100.93 55.93,101.04 55.93,101.72 56.04,101.83 56.26,101.83 56.37,101.72 56.37,101.04 56.48,100.93 56.7,100.93 56.81,101.04 56.81,101.72 56.91,101.83 57.13,101.83 57.24,101.72 57.24,101.04 57.35,100.93 60.75,100.93 60.96,100.71 60.96,99.99 61.11,99.85 61.3,99.85 61.44,99.99 61.44,100.69 61.59,100.83 61.78,100.83 61.92,100.69 61.92,99.99 62.07,99.85 62.26,99.85 62.4,99.99 62.4,100.69 62.55,100.83 62.74,100.83 62.88,100.69 62.88,99.99 63.03,99.85 63.22,99.85 63.36,99.99 63.36,100.69 63.51,100.83 63.7,100.83 63.84,100.69 63.84,99.99 63.99,99.85 64.18,99.85 64.32,99.99 64.32,100.69 64.47,100.83 64.66,100.83 64.81,100.69 64.81,99.99 64.95,99.85 65.14,99.85 65.29,99.99 65.29,100.69 65.43,100.83 65.62,100.83 65.77,100.69 65.77,99.99 65.91,99.85 66.1,99.85 66.25,99.99 66.25,100.69 66.39,100.83 66.58,100.83 66.73,100.69 66.73,99.99 66.87,99.85 67.06,99.85 67.21,99.99 67.21,100.69 67.35,100.83 67.54,100.83 67.69,100.69 67.69,100.02 67.83,99.88 68.02,99.88 68.17,100.02 68.17,100.69 68.31,100.83 68.5,100.83 68.65,100.69 68.65,99.99 68.79,99.85 68.98,99.85 69.13,99.99 69.13,100.69 69.27,100.83 69.46,100.83 69.61,100.69 69.61,99.99 69.75,99.85 69.94,99.85 70.09,99.99 70.09,100.69 70.23,100.83 70.43,100.83 70.57,100.69 70.57,99.99 70.71,99.85 70.91,99.85 71.05,99.99 71.05,100.69 71.19,100.83 74.69,100.83 74.98,100.54 89.99,100.54 90.12,100.67 94.46,100.67 95,101.21 96.46,101.21 v6(96.98,101.73)
  BOTTOM w0.173: R86.2 24.13,111.77 24.13,109.33 v9(24.77,108.69)
AM57XX_PRU1ETH1_MRCLK: length 20.9
  TOP w0.173: v5(118.67,101.58) 118.67,102.24 119,102.57 119,103.71 R332.2 ; U1.C3 v4(111.83,91.21)
  L3_SIG1 w0.099: 111.96,90.12 111.65,90.12 111.52,90.25 111.52,90.57 111.83,90.89 v4(111.83,91.21)
  L3_SIG1 w0.109: v5(118.67,101.58) 118.39,101.3 118.39,97.62 117.68,96.91 117.68,93.55 115.56,91.43 113.27,91.43 111.96,90.12
AM57XX_PRU1ETH1_TXCLK: length 9.2
  TOP w0.173: R123.2 114.68,98.51 v1(114.71,98.48) 114.71,98.4 112.86,96.56 112.86,94.66 111.43,93.23 U1.C1
  BOTTOM w0.173: v1(114.71,98.48) 114.55,98.63 R746.2
AM57XX_PRU1ETH1_TXD0: length 14.6
  TOP w0.173: R326.2 115.19,103.71 115.19,102.01 115.3,101.9 115.3,98.32 114.83,97.85 114.83,97.75 113.16,96.08 113.16,94.44 111.83,93.12 111.83,92.01 U1.C2
AM57XX_PRU1ETH1_TXD1: length 21.4
  TOP w0.173: U1.D5 v4(111.03,89.61) ; v5(119.89,101.3) 119.96,101.38 119.96,102.21 120.27,102.52 120.27,103.71 R126.2
  L3_SIG1 w0.099: v4(111.03,89.61) 111.34,89.92 112.06,89.92
  L3_SIG1 w0.109: v5(119.89,101.3) 118.75,100.16 118.75,97.41 118.05,96.72 118.05,93.24 115.96,91.14 113.28,91.14 112.06,89.92
AM57XX_PRU1ETH1_TXD2: length 14.4
  TOP w0.173: R127.2 116.08,98.38 v5(115.44,97.74) ; U1.E6 v4(110.23,88.81)
  L3_SIG1 w0.099: 111.33,92.99 111.33,91.09 111.16,90.92 110.33,90.92 109.94,90.54 109.94,89.49 110.23,89.2 v4(110.23,88.81)
  L3_SIG1 w0.109: v5(115.44,97.74) 114.99,97.29 114.55,97.29 112.57,95.3 112.57,94.24 111.33,92.99
AM57XX_PRU1ETH1_TXD3: length 18.9
  TOP w0.173: v1(117.47,98.28) R128.2 ; U1.F5 v4(109.43,89.61)
  L3_SIG1 w0.099: v4(109.43,89.61) 109.74,89.92 109.74,90.62 109.94,90.82 109.94,94
  L3_SIG1 w0.109: 109.94,94 111.77,95.83 111.77,96.22 112.19,96.64 112.42,96.64 112.73,96.94 112.73,98.46 113.11,98.85 113.25,98.85 114.18,99.78 116.08,99.78 117.47,98.38 v1(117.47,98.28)
  BOTTOM w0.173: R747.2 117.5,98.25 v1(117.47,98.28)
AM57XX_PRU1ETH1_TXEN: length 16.9
  TOP w0.173: U1.E4 v4(110.23,90.41) ; R124.2 118.49,96.45 117.71,95.66 116.64,95.66 v5(115.57,96.73)
  L3_SIG1 w0.099: 111.54,92.7 111.54,90.97 110.98,90.41 v4(110.23,90.41)
  L3_SIG1 w0.109: v5(115.57,96.73) 114.35,96.73 113.03,95.41 113.03,94.19 111.54,92.7
AM57XX_PRU1ETH_MDCLK: length 231.4
  TOP w0.173: R748.2 30.61,93.81 v1(31.12,94.32) R140.2 ; U1.D3 v4(111.03,91.21)
  L3_SIG1 w0.099: 111.03,93.59 v4(111.03,91.21)
  L3_SIG1 w0.109: v6(126.31,102.77) 126.75,103.21 126.75,104.83 123.65,107.93 123.65,111.62 112.17,123.1 112.17,125.43 106.2,131.4 105.88,131.4 105.44,131.84 105.44,133.3 103.91,134.83 94.56,134.83 94.01,135.38 61.57,135.38 60.76,136.2 49.25,136.2 43.19,130.14 35.95,130.14 35.08,129.27 26.1,129.27 20.61,123.78 18.8,123.78 17.73,122.71 17.73,121.17 18.34,120.55 18.34,114.66 15.88,112.19 15.88,103.02 25.07,93.83 26.39,93.83 27.32,94.76 30.67,94.76 v1(31.12,94.32) ; v6(111.76,94.32) 111.03,93.59
  L9_SIG3 w0.114: v1(31.12,94.32) 31.12,97.79 29.82,99.09 29.82,103.63 26.99,106.47 26.99,107.24 26.29,107.94 26.29,117.94 27.18,118.83 v1(27.94,118.83)
  L10_SIG4 w0.109: v6(126.31,102.77) 124.64,101.1 124.64,99.5 122.45,97.31 120.93,97.31 116.23,92.61 115.01,92.61 114.12,91.72 113.11,91.72 111.76,93.07 v6(111.76,94.32)
  BOTTOM w0.173: v1(27.94,118.83) 27.41,118.83 R96.2
AM57XX_PRU1ETH_MDDATA: length 232.8
  TOP w0.173: U1.F6 v4(109.43,88.81) ; v1(30.1,94.32) R142.2
  L3_SIG1 w0.109: v1(30.1,94.32) 28.73,94.32 27.89,93.48 25.03,93.48 24.96,93.55 24.95,93.55 15.49,103 15.49,113.24 17.19,114.93 17.19,118.25 17.99,119.05 17.99,120.49 17.44,121.05 17.44,125.81 19.19,127.56 22.46,127.56 25.43,130.54 43.15,130.54 49.11,136.49 60.97,136.49 61.8,135.67 70.29,135.67 71.12,136.5 90.83,136.5 91.51,137.19 103.15,137.19 106.73,133.61 106.73,131.27 112.75,125.25 112.75,123.27 124.03,111.99 124.03,108 127.25,104.77 v6(127.25,102.7) ; v4(109.43,88.81) 109.43,88.82 v6(109.83,89.06)
  L9_SIG3 w0.114: v1(27.18,119.84) 25.91,118.57 25.91,107.9 26.69,107.12 26.69,105.21 29.46,102.44 29.46,98.93 30.1,98.3 v1(30.1,94.32)
  L10_SIG4 w0.109: v6(109.83,89.06) 111.31,89.06 112.12,89.87 114.15,89.87 121.29,97.01 122.63,97.01 125.07,99.45 125.07,100.87 126.29,102.09 126.64,102.09 v6(127.25,102.7)
  BOTTOM w0.173: R98.2 v1(27.18,119.84)
AM57XX_PRU2ETH0_COL: length 15.8
  TOP w0.173: U1.F15 v4(109.43,80.82) ; v5(123.04,79.81) R178.2
  L3_SIG1 w0.109: v4(109.43,80.82) 109.79,80.82 110.28,81.31 110.81,81.31 110.82,81.32 112.04,81.32 112.21,81.16 119.58,81.16 119.69,81.05 120.55,81.05 121.79,79.81 v5(123.04,79.81)
AM57XX_PRU2ETH0_CRS: length 324.7
  TOP w0.173: v5(120.27,73.98) 120.25,74 120.14,74 118.17,75.97 117.31,75.97 114.86,78.42 112.63,78.42 112.23,78.81 U1.B18 ; R177.2 v1(38.61,79.96)
  L3_SIG1 w0.109: v5(120.27,73.98) v6(119.68,73.98)
  L4_SIG2 w0.114: v6(119.68,73.98) 120.51,73.98 123.35,76.81 130.23,76.81 130.98,77.56 145.14,77.56 146.56,76.14 149.44,76.14 159.67,65.91 160.9,65.91 166.31,60.5 166.31,51.07 164.64,49.4 164.64,46.43 165.52,45.55 165.52,43.73 164.67,42.88 164.67,41.35 165.56,40.46 165.56,36.22 157.13,27.79 152.52,27.79 147.55,22.81 141.06,22.81 133.23,14.99 133.23,13.88 132.13,12.78 130.93,12.78 129.14,10.99 106.07,10.99 105.89,11.17 98.96,11.17 97.22,12.91 64.16,12.91 64.07,12.83 57.26,12.83 55.93,11.5 55.32,11.5 50.6,6.78 28.86,6.78 24.51,11.13 24.51,24.5 27.95,27.94 27.95,30.52 27.81,30.66 27.81,41.13 30.41,43.73 30.41,47.41 35.24,52.25 35.24,73.34 37.15,75.25 37.15,78.51 v1(38.61,79.96)
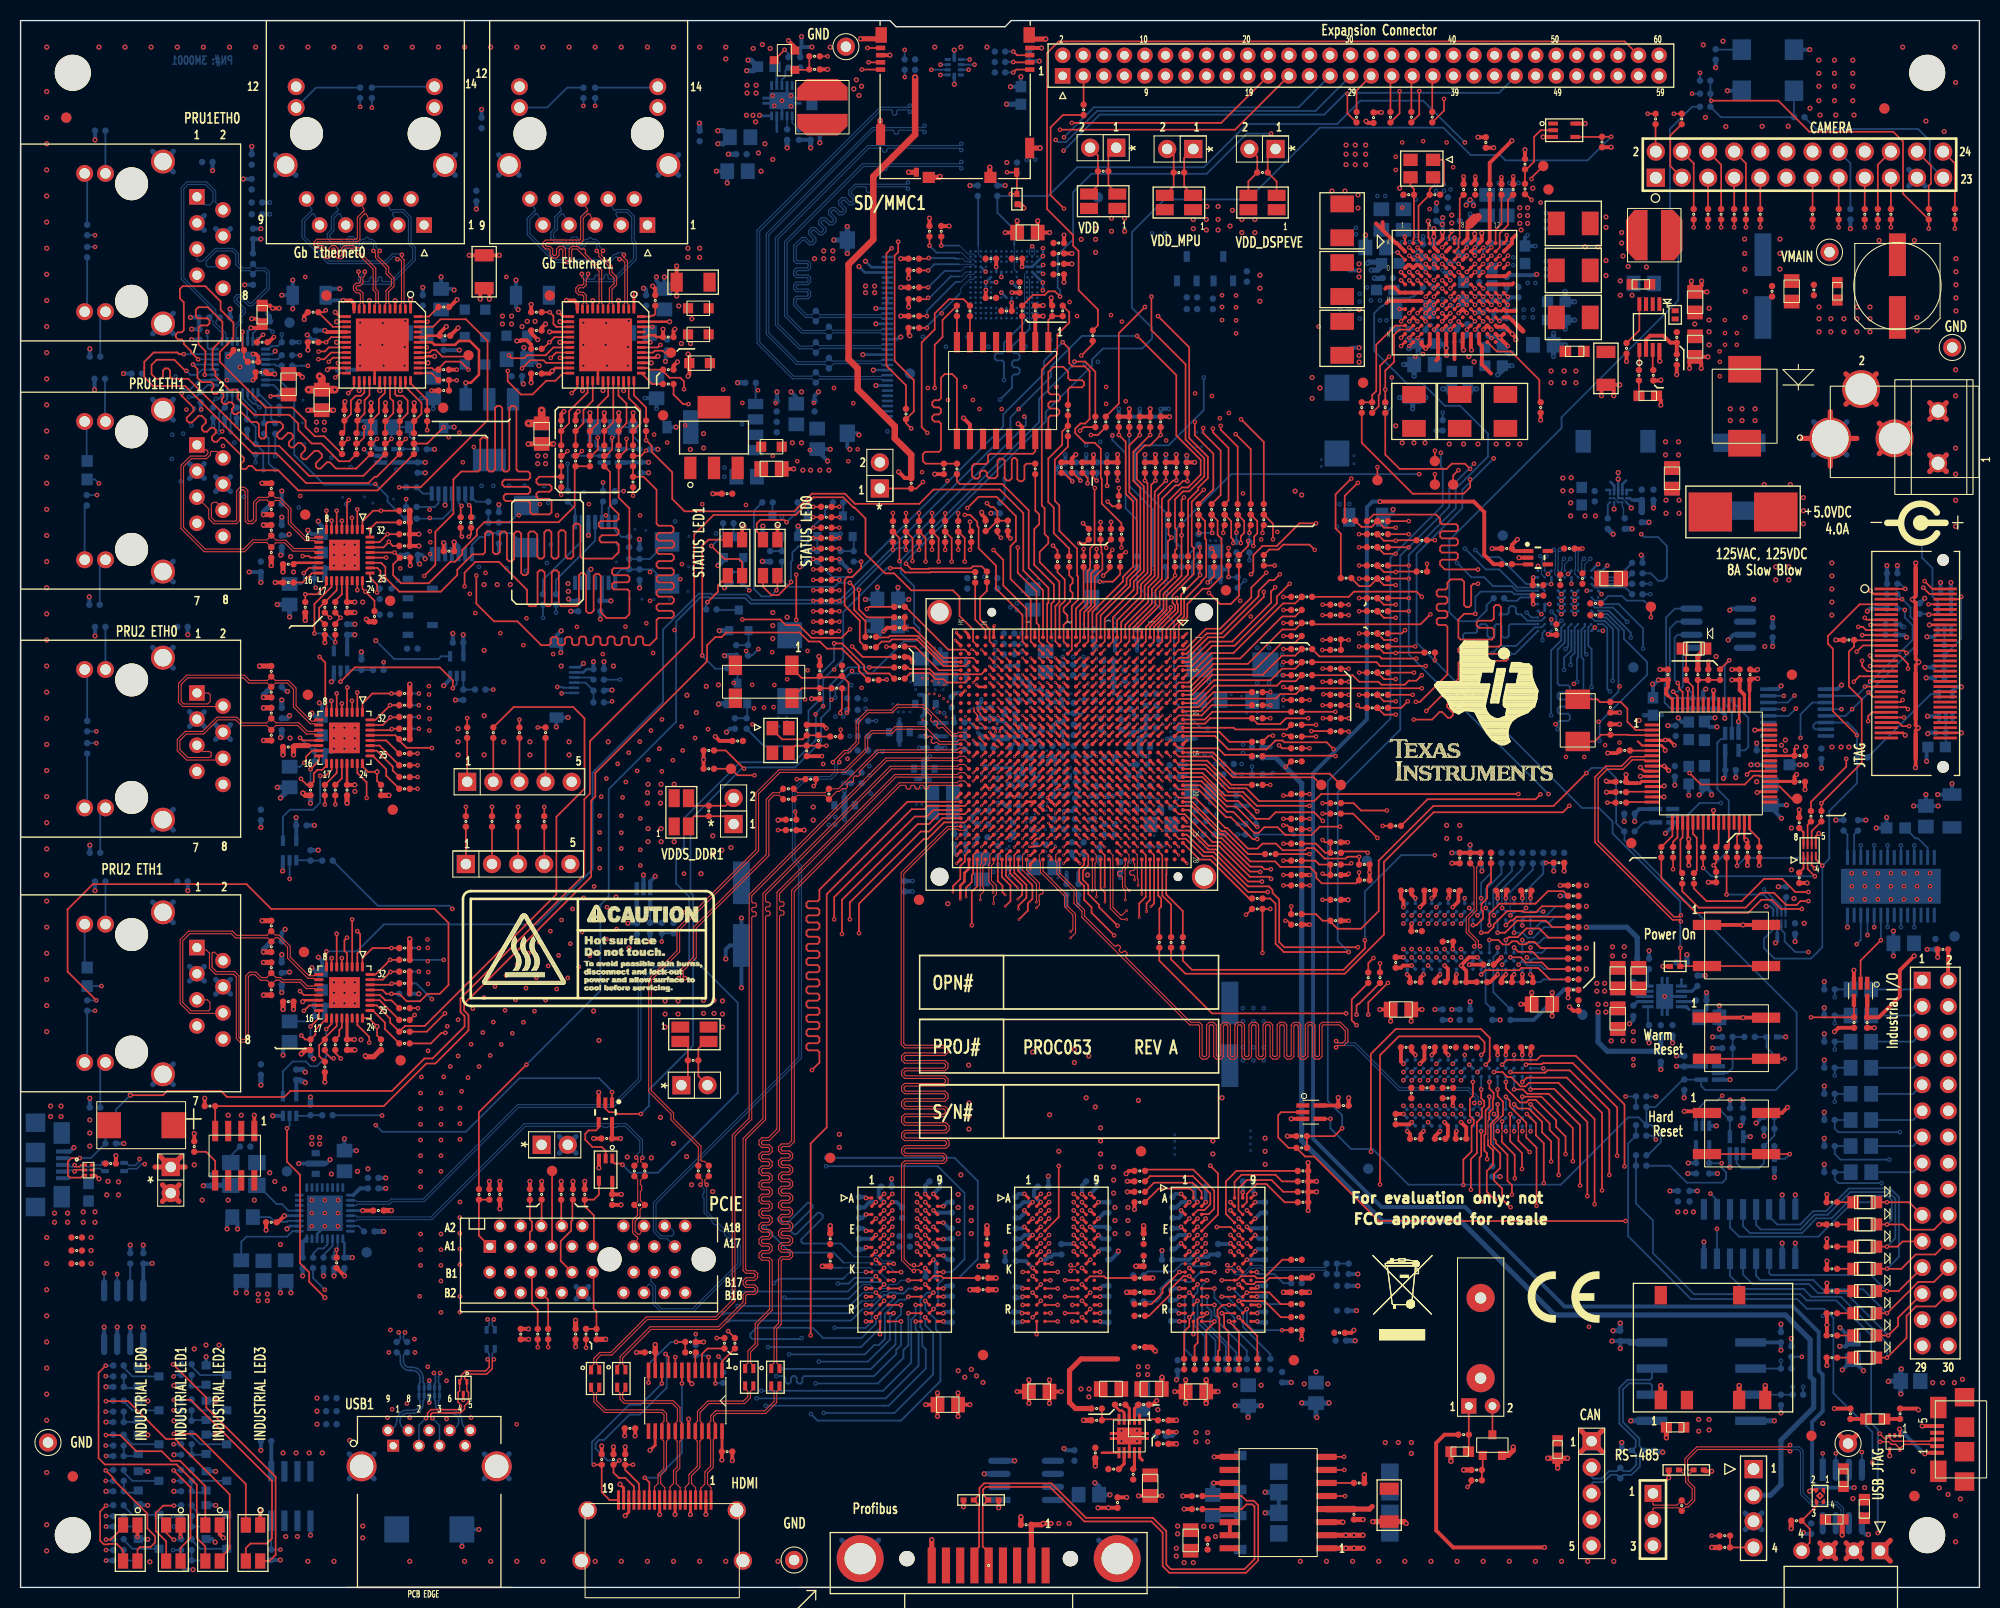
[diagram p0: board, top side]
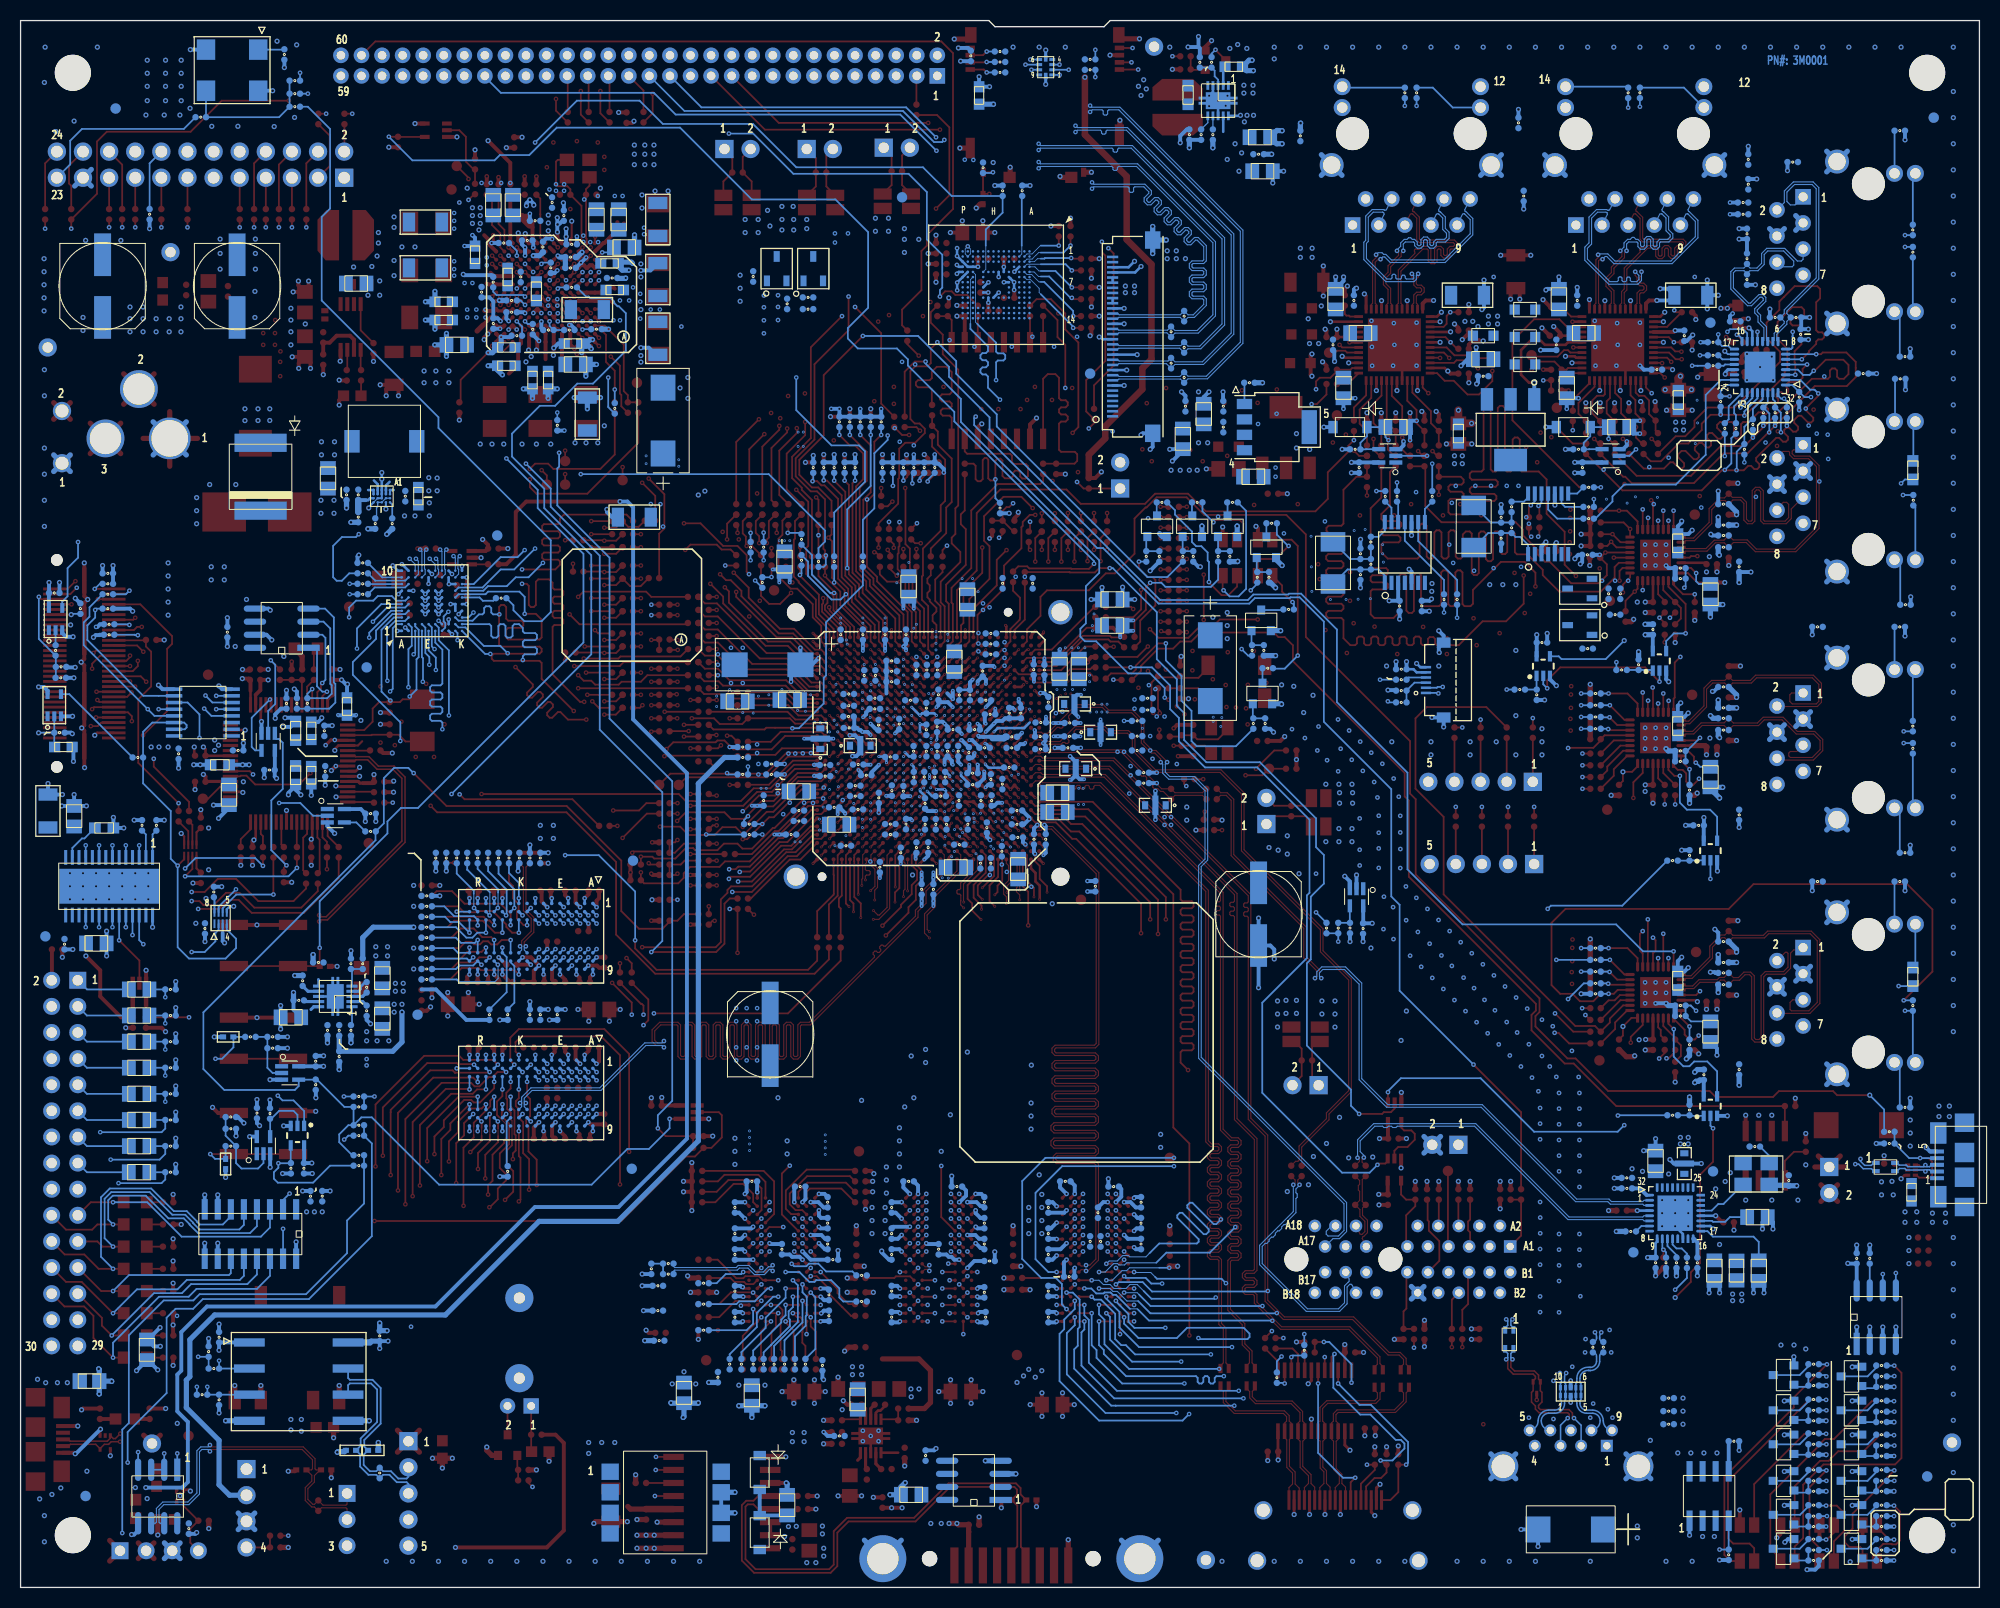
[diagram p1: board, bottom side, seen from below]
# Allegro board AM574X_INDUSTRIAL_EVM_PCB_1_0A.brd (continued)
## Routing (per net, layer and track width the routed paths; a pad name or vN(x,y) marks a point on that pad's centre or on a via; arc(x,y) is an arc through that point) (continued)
AM57XX_PRU2ETH0_MRCLK: length 309.5
  TOP w0.173: v5(127.69,81.54) 127.02,82.2 122.91,82.2 122.73,82.38 122.05,82.38 121.18,81.51 117.45,81.51 116.15,82.81 U1.A13 ; R165.2 v1(38.61,77.68)
  L3_SIG1 w0.109: v5(127.69,81.54) v6(127.27,81.12)
  L10_SIG4 w0.109: v6(127.27,81.12) 128.52,82.38 128.52,84.09 128.34,84.28 124.91,84.28 124.71,84.08 124.71,80.12 123.34,78.74 123.34,73.38 122.4,72.45 122.4,70.95 123.5,69.85 125.2,69.85 126.85,68.2 128.98,68.2 129.26,68.48 131.47,68.48 131.55,68.56 148.37,68.56 148.89,69.09 152.78,69.09 156.79,65.08 156.79,56.72 153.49,53.42 153.49,41.13 154.31,40.31 154.31,38.18 150.88,34.75 149.83,34.75 149.72,34.86 149.72,35.73 149.61,35.84 149.39,35.84 149.28,35.73 149.28,34.86 149.17,34.75 148.95,34.75 148.84,34.86 148.84,35.73 148.74,35.84 148.52,35.84 148.41,35.73 148.41,34.86 148.3,34.75 148.08,34.75 147.97,34.86 147.97,35.73 147.86,35.84 147.64,35.84 147.53,35.73 147.53,34.86 147.42,34.75 147.21,34.75 147.1,34.86 147.1,35.73 146.99,35.84 146.77,35.84 146.66,35.73 146.66,34.86 146.55,34.75 146.33,34.75 146.22,34.86 146.22,35.73 146.11,35.84 145.9,35.84 145.79,35.73 145.79,34.86 145.68,34.75 145.46,34.75 145.35,34.86 145.35,35.73 145.24,35.84 145.02,35.84 144.91,35.73 144.91,34.86 144.8,34.75 144.58,34.75 144.48,34.86 144.48,35.73 144.37,35.84 144.15,35.84 144.04,35.73 144.04,34.86 143.93,34.75 143.71,34.75 143.6,34.86 143.6,35.73 143.49,35.84 143.27,35.84 143.17,35.73 143.17,34.86 143.06,34.75 142.84,34.75 142.73,34.86 142.73,35.73 142.62,35.84 142.4,35.84 142.29,35.73 142.29,34.86 142.18,34.75 141.96,34.75 141.85,34.86 141.85,35.73 141.75,35.84 141.53,35.84 141.42,35.73 141.42,34.86 141.31,34.75 140.08,34.75 130.91,25.58 125.3,25.58 117.15,17.43 111.69,17.43 111.02,16.76 105.63,16.76 104.6,15.73 92.2,15.73 91.59,15.11 71.44,15.11 67.95,18.6 64.92,18.6 62.2,21.32 54.88,21.32 50.59,25.61 47.51,25.61 45.99,27.13 45.12,27.13 42.27,29.98 42.27,32.33 38.07,36.53 38.07,42.27 29.26,51.08 29.26,60.15 28.47,60.94 28.47,62.97 38.61,73.11 v1(38.61,77.68)
AM57XX_PRU2ETH0_RXD0: length 309.6
  TOP w0.173: U1.C15 v4(111.83,80.82)
  L3_SIG1 w0.109: v4(111.83,80.82) 111.96,80.69 116.88,80.69 117.53,80.04 120.62,80.04 121.28,79.38 126.92,79.38 v6(127.13,79.58)
  L10_SIG4 w0.109: v1(38.73,83.52) 39.34,82.91 39.34,80.85 39.04,80.55 38.53,80.55 37.29,79.3 37.29,73.49 26.72,62.92 26.72,59.09 26.06,58.42 26.06,50.42 26.82,49.66 26.82,47.48 31.22,43.08 33.15,43.08 36.7,39.53 36.7,32.66 42.17,27.2 42.17,25.75 44.02,23.9 46.6,23.9 47.39,23.11 50.56,23.11 53.96,19.72 58.9,19.72 63.35,15.27 68.63,15.27 70.36,13.54 92.35,13.54 93.19,14.38 105.9,14.38 106.54,13.74 109.66,13.74 110.36,13.04 115.32,13.04 116.46,14.18 119.73,14.18 121.67,16.12 121.67,18.76 124.35,21.43 125.79,21.43 125.79,21.44 126.18,21.44 126.18,21.43 130.45,21.43 138.14,29.13 138.29,29.13 138.61,28.81 138.77,28.81 138.92,28.96 138.92,29.12 138.6,29.44 138.6,29.59 138.76,29.75 138.91,29.75 139.23,29.43 139.38,29.43 139.54,29.58 139.54,29.74 139.22,30.06 139.22,30.21 139.83,30.82 142.23,30.82 142.34,30.92 142.34,31.72 142.45,31.83 142.66,31.83 142.77,31.72 142.77,30.92 142.88,30.82 143.1,30.82 143.21,30.92 143.21,31.72 143.32,31.83 143.54,31.83 143.65,31.72 143.65,30.92 143.76,30.82 143.97,30.82 144.08,30.92 144.08,31.72 144.19,31.83 144.41,31.83 144.52,31.72 144.52,30.92 144.63,30.82 144.85,30.82 144.96,30.92 144.96,31.72 145.07,31.83 145.29,31.83 145.39,31.72 145.39,30.92 145.5,30.82 145.72,30.82 145.83,30.92 145.83,31.72 145.94,31.83 146.16,31.83 146.27,31.72 146.27,30.92 146.38,30.82 146.6,30.82 146.71,30.92 146.71,31.72 146.81,31.83 147.03,31.83 147.14,31.72 147.14,30.92 147.25,30.82 147.47,30.82 147.58,30.92 147.58,31.72 147.69,31.83 147.91,31.83 148.02,31.72 148.02,30.92 148.13,30.82 148.34,30.82 148.45,30.92 148.45,31.72 148.56,31.83 148.78,31.83 148.89,31.72 148.89,30.92 149,30.82 149.76,30.82 156.44,37.5 156.44,46.99 156.97,47.52 156.97,50.29 157.89,51.2 157.89,66.27 153.01,71.15 147.29,71.15 146.53,70.39 141.78,70.39 141.33,69.93 133.48,69.93 132.72,70.69 127.41,70.69 126.92,71.18 126.91,71.18 126.8,71.29 126.8,77.35 127.56,78.11 127.56,79.15 v6(127.13,79.58)
  BOTTOM w0.173: R171.2 v1(38.73,83.52)
AM57XX_PRU2ETH0_RXD1: length 309.5
  TOP w0.173: U1.A18 114.94,78.81 117.26,76.49 118.4,76.49 120.14,74.76 121.41,74.76 122.05,75.39 125.81,75.39 v5(126.64,74.55)
  L3_SIG1 w0.109: v6(126.06,74.2) 126.42,74.55 v5(126.64,74.55)
  L10_SIG4 w0.109: v1(38.73,84.66) 40.56,82.83 40.56,80.88 39.07,79.38 38.53,79.38 37.64,78.49 37.64,73.28 27.23,62.87 27.23,59.67 28.04,58.86 28.04,55.86 26.67,54.49 26.67,50.6 27.2,50.07 27.2,47.88 29.77,45.32 32.49,45.32 37.26,40.54 37.26,33.62 39.61,31.27 39.61,30.31 40.74,29.18 40.94,29.18 43.16,26.96 43.16,25.24 44.14,24.26 46.73,24.26 47.53,23.45 51.73,23.45 54.91,20.27 59.92,20.27 64.39,15.8 68.61,15.8 70.53,13.88 92.18,13.88 93.04,14.73 105.28,14.73 106.33,15.78 111.23,15.78 112.17,16.72 113.16,16.72 114.18,15.7 120.71,15.7 121.3,16.28 121.3,18.92 124.16,21.78 129.72,21.78 140.41,32.47 140.9,32.47 141.01,32.58 141.01,33.24 141.12,33.35 141.34,33.35 141.45,33.24 141.45,32.58 141.56,32.47 141.78,32.47 141.89,32.58 141.89,33.24 142,33.35 142.21,33.35 142.32,33.24 142.32,32.58 142.43,32.47 142.65,32.47 142.76,32.58 142.76,33.24 142.87,33.35 143.09,33.35 143.2,33.24 143.2,32.58 143.31,32.47 143.52,32.47 143.63,32.58 143.63,33.24 143.74,33.35 143.96,33.35 144.07,33.24 144.07,32.58 144.18,32.47 144.4,32.47 144.51,32.58 144.51,33.24 144.62,33.35 144.83,33.35 144.94,33.24 144.94,32.58 145.05,32.47 145.27,32.47 145.38,32.58 145.38,33.24 145.49,33.35 145.71,33.35 145.82,33.24 145.82,32.58 145.93,32.47 146.15,32.47 146.25,32.58 146.25,33.24 146.36,33.35 146.58,33.35 146.69,33.24 146.69,32.58 146.8,32.47 147.02,32.47 147.13,32.58 147.13,33.24 147.24,33.35 147.46,33.35 147.57,33.24 147.57,32.58 147.67,32.47 147.89,32.47 148,32.58 148,33.24 148.11,33.35 148.33,33.35 148.44,33.24 148.44,32.58 148.55,32.47 148.77,32.47 148.88,32.58 148.88,33.24 148.99,33.35 149.2,33.35 149.31,33.24 149.31,32.58 149.42,32.47 149.64,32.47 149.75,32.58 149.75,33.24 149.86,33.35 150.08,33.35 150.19,33.24 150.19,32.58 150.3,32.47 150.62,32.47 155.8,37.65 155.8,46.76 155.32,47.24 155.32,50.96 157.51,53.14 157.51,66.15 152.93,70.72 148.03,70.72 146.48,69.17 133.3,69.17 132.28,70.19 129.84,70.19 128.57,68.92 127.64,68.92 126.34,70.21 125.94,70.21 125.68,70.47 125.68,70.83 125.54,70.97 125.23,70.97 125.09,71.11 125.09,71.31 125.23,71.45 125.54,71.45 125.68,71.59 125.68,73.38 126.06,73.77 v6(126.06,74.2)
  BOTTOM w0.173: R173.2 v1(38.73,84.66)
AM57XX_PRU2ETH0_RXD2: length 308.8
  TOP w0.173: U1.A19 114.72,78.02 117.29,75.44 117.94,75.44 120.02,73.36 120.37,73.36 120.95,73.94 122.24,73.94 123,73.18 125.54,73.18 126.35,74 v5(128.32,74)
  L3_SIG1 w0.109: v5(128.32,74) v6(129.03,74)
  L10_SIG4 w0.109: v6(129.03,74) 129.92,73.11 131.5,73.11 132.66,71.94 140.23,71.94 140.59,71.58 141.48,71.58 142.19,72.29 152.83,72.29 159.23,65.89 159.23,51.21 158.15,50.13 158.15,46.95 157.18,45.97 157.18,36.86 155.45,35.14 155.45,34.98 155.93,34.5 155.93,34.35 155.78,34.19 155.62,34.19 155.14,34.67 154.99,34.67 154.83,34.52 154.83,34.36 155.31,33.88 155.31,33.73 155.16,33.57 155,33.57 154.52,34.05 154.37,34.05 154.21,33.9 154.21,33.75 154.7,33.27 154.7,33.11 154.54,32.96 154.39,32.96 153.91,33.44 153.75,33.44 153.6,33.28 153.6,33.13 154.08,32.65 154.08,32.49 153.92,32.34 153.77,32.34 153.29,32.82 153.13,32.82 152.98,32.66 152.98,32.51 153.46,32.03 153.46,31.87 153.3,31.72 153.15,31.72 152.67,32.2 152.51,32.2 152.36,32.05 152.36,31.89 152.84,31.41 152.84,31.26 152.69,31.1 152.53,31.1 152.05,31.58 151.9,31.58 151.74,31.43 151.74,31.27 152.22,30.79 152.22,30.64 152.07,30.48 151.91,30.48 151.43,30.96 151.28,30.96 151.12,30.81 151.12,30.65 151.6,30.17 151.6,30.02 151.45,29.87 151.3,29.87 150.81,30.35 150.66,30.35 150.51,30.19 150.51,30.04 150.99,29.56 150.99,29.4 150.83,29.25 150.68,29.25 150.2,29.73 150.04,29.73 149.89,29.57 149.89,29.42 150.37,28.94 150.37,28.78 150.21,28.63 150.06,28.63 149.58,29.11 149.42,29.11 149.27,28.95 149.27,28.8 149.75,28.32 149.75,28.17 149.59,28.01 149.44,28.01 148.96,28.49 148.81,28.49 148.65,28.34 148.65,28.18 149.13,27.7 149.13,27.55 148.98,27.39 148.82,27.39 148.34,27.87 148.19,27.87 146.35,26.04 138.1,26.04 131.39,19.33 126.65,19.33 119.08,11.77 109.35,11.77 108.36,12.75 106.15,12.75 105.87,13.04 93.37,13.04 93.11,12.77 70.03,12.77 68.5,14.31 62.94,14.31 58.47,18.78 53.95,18.78 53.16,19.56 47.02,19.56 41.48,25.09 41.48,26.77 35.77,32.49 35.77,35.36 33.68,37.44 33.68,38.56 31.39,40.85 29.52,40.85 27.81,42.55 27.81,44.23 26.09,45.95 26.09,49.03 24.51,50.6 24.51,59.85 25.91,61.24 25.91,63.35 36.3,73.74 36.3,80.91 37.53,82.15 37.53,84.6 v1(38.73,85.81)
  BOTTOM w0.173: R174.2 v1(38.73,85.81)
AM57XX_PRU2ETH0_RXD3: length 307.7
  TOP w0.173: U1.F14 v4(109.43,82.41)
  L3_SIG1 w0.109: v4(109.43,82.41) 109.75,82.1 112.27,82.1 113.22,83.05 116.7,83.05 117.3,82.45 119.42,82.45 119.75,82.12 120.45,82.12 121.79,80.78 124.41,80.78 125.03,80.17 127.28,80.17 127.59,79.86 127.59,79.73 128.24,79.08 v6(129.29,79.08)
  L10_SIG4 w0.109: v1(38.73,86.95) 36.83,85.04 36.83,82.4 35.15,80.73 35.15,74.1 24.13,63.07 24.13,50.32 25.73,48.72 25.73,45.6 27.13,44.2 27.13,42.55 30.1,39.57 31.5,39.57 32.69,38.38 32.69,36.52 35.02,34.2 35.02,31.07 47.04,19.05 53.19,19.05 53.87,18.37 57.12,18.37 62.25,13.25 69.03,13.25 70.37,11.9 92.75,11.9 93.24,12.4 95.86,12.4 96.45,11.81 102.38,11.81 103.25,12.68 105.61,12.68 106.1,12.2 108.23,12.2 109.09,11.33 119.26,11.33 124.92,17 124.92,17.01 125.59,17.67 125.6,17.67 126.72,18.79 131.66,18.79 138.35,25.48 147.6,25.48 149.36,27.24 149.51,27.24 149.72,27.02 149.88,27.02 150.03,27.18 150.03,27.33 149.82,27.55 149.82,27.7 149.97,27.86 150.13,27.86 150.34,27.64 150.5,27.64 150.65,27.8 150.65,27.95 150.44,28.16 150.44,28.32 150.59,28.47 150.75,28.47 150.96,28.26 151.11,28.26 151.27,28.41 151.27,28.57 151.06,28.78 151.06,28.94 151.21,29.09 151.36,29.09 151.58,28.88 151.73,28.88 151.89,29.03 151.89,29.19 151.67,29.4 151.67,29.56 151.83,29.71 151.98,29.71 152.2,29.5 152.35,29.5 152.51,29.65 152.51,29.81 152.29,30.02 152.29,30.17 157.53,35.41 157.53,45.52 161.54,49.53 161.54,59.62 160.02,61.14 160.02,65.89 153.19,72.73 140.82,72.73 140.47,72.37 132.82,72.37 129.32,75.87 129.32,79.05 v6(129.29,79.08)
  BOTTOM w0.173: R175.2 v1(38.73,86.95)
AM57XX_PRU2ETH0_RXDV: length 309.9
  TOP w0.173: R166.2 v1(38.61,78.82) ; R197.2 v1(45.85,75.92) ; U1.G14 v4(108.63,82.41)
  L3_SIG1 w0.109: v4(108.63,82.41) 109,82.41 109.72,81.7 112.24,81.7 112.57,81.37 117.08,81.37 117.22,81.51 119.81,81.51 119.92,81.41 120.68,81.41 121.75,80.35 v6(124.23,80.35)
  L10_SIG4 w0.109: v6(124.23,80.35) 122.96,79.08 122.96,73.77 122.03,72.83 122.03,70.82 124.08,68.76 125.63,68.76 126.54,67.85 129.16,67.85 129.44,68.13 131.65,68.13 131.72,68.2 148.78,68.2 149.16,67.82 150.37,67.82 150.9,67.29 153.52,67.29 156.44,64.37 156.44,57.21 153.14,53.9 153.14,38.87 150.85,36.58 150.05,36.58 149.94,36.69 149.94,38.22 149.83,38.33 149.62,38.33 149.51,38.22 149.51,36.69 149.4,36.58 149.18,36.58 149.07,36.69 149.07,38.22 148.96,38.33 148.74,38.33 148.63,38.22 148.63,36.69 148.52,36.58 148.3,36.58 148.2,36.69 148.2,38.22 148.09,38.33 147.87,38.33 147.76,38.22 147.76,36.69 147.65,36.58 147.43,36.58 147.32,36.69 147.32,38.22 147.21,38.33 146.99,38.33 146.88,38.22 146.88,36.69 146.78,36.58 146.56,36.58 146.45,36.69 146.45,38.22 146.34,38.33 146.12,38.33 146.01,38.22 146.01,36.69 145.9,36.58 145.68,36.58 145.57,36.69 145.57,38.22 145.46,38.33 145.25,38.33 145.14,38.22 145.14,36.69 145.03,36.58 144.39,36.58 144.2,36.39 140.58,36.39 130.35,26.16 125.27,26.16 117.63,18.52 111.58,18.52 111.22,18.88 106.32,18.88 104.24,16.79 92.46,16.79 91.21,15.54 71.51,15.54 67.87,19.18 66.85,19.18 64.23,21.8 54.91,21.8 49.91,26.8 46.86,26.8 46.08,27.58 45.88,27.58 43.23,30.23 43.23,33.25 38.46,38.03 38.46,44.25 31.7,51.01 31.7,53.93 29.69,55.94 29.69,61.24 29.26,61.68 29.26,63.17 41.45,75.37 45.3,75.37 v1(45.85,75.92) 44.78,76.99 44.78,79.13 44.27,79.63 41.22,79.63 40.41,78.82 v1(38.61,78.82)
AM57XX_PRU2ETH0_RXER: length 309.7
  TOP w0.173: R170.2 v1(38.61,81.11) ; U1.G12 v4(108.63,84.01)
  L3_SIG1 w0.109: v6(109.03,84.26) 109.03,84.26 108.63,84.02 v4(108.63,84.01)
  L10_SIG4 w0.109: v6(109.03,84.26) 110.02,84.26 110.41,84.66 113.5,84.66 114.09,84.08 123.04,84.08 123.61,84.65 129.86,84.65 130.2,84.31 130.2,83.77 129.39,82.96 129.39,80.57 128.6,79.79 128.6,75.67 127.61,74.68 127.61,74.02 129.21,72.42 131.55,72.42 133.65,70.31 137.69,70.31 138.33,70.95 142.01,70.95 142.88,71.81 152.83,71.81 158.88,65.77 158.88,51.64 157.57,50.33 157.57,47.23 156.82,46.48 156.82,37.29 149.58,30.05 148.68,30.05 148.57,29.94 148.57,29.19 148.46,29.08 148.25,29.08 148.14,29.19 148.14,29.94 148.03,30.05 147.81,30.05 147.7,29.94 147.7,29.19 147.59,29.08 147.37,29.08 147.26,29.19 147.26,29.94 147.15,30.05 146.93,30.05 146.83,29.94 146.83,29.19 146.72,29.08 146.5,29.08 146.39,29.19 146.39,29.94 146.28,30.05 146.06,30.05 145.95,29.94 145.95,29.19 145.84,29.08 145.62,29.08 145.51,29.19 145.51,29.94 145.41,30.05 145.19,30.05 145.08,29.94 145.08,29.19 144.97,29.08 144.75,29.08 144.64,29.19 144.64,29.94 144.53,30.05 140.94,30.05 131.19,20.3 126.28,20.3 124.4,18.42 124.4,18.42 124.13,18.15 124.13,18.14 122.01,16.03 122.01,15.98 118.18,12.15 109.6,12.15 108.53,13.21 106.32,13.21 105.54,14 93.5,14 92.7,13.2 70.14,13.2 68.61,14.74 63.17,14.74 58.65,19.26 53.94,19.26 50.47,22.73 47.29,22.73 46.48,23.55 43.9,23.55 41.83,25.61 41.83,26.95 36.17,32.62 36.17,35.63 34.87,36.92 34.87,40.43 33.95,41.35 32.22,41.35 26.47,47.1 26.47,49.26 24.92,50.8 24.92,59.47 26.29,60.84 26.29,63.1 36.7,73.51 36.7,79.2 v1(38.61,81.11)
AM57XX_PRU2ETH0_RXLINK: length 7.7
  TOP w0.173: R188.2 119.75,78.07 117.73,78.07 115.39,80.42 U1.A16
AM57XX_PRU2ETH0_TXCLK: length 15.6
  TOP w0.173: v5(122.83,82.91) 123.42,82.91 R162.2 ; U1.F12 v4(109.43,84.01)
  L3_SIG1 w0.099: v4(109.43,84.01) 109.82,84.01 110.11,83.72 110.36,83.72 110.48,83.84 110.79,83.84 110.91,83.72 111.16,83.72 111.28,83.84 111.59,83.84 111.71,83.72 111.96,83.72
  L3_SIG1 w0.109: 111.96,83.72 112.64,83.72 112.81,83.89 117.13,83.89 117.21,83.81 119.9,83.81 120.27,83.44 122.31,83.44 v5(122.83,82.91)
AM57XX_PRU2ETH0_TXD0: length 15.3
  TOP w0.173: U1.E14 v4(110.23,82.41) ; R163.2 122.68,81.62 v5(122.39,81.91)
  L3_SIG1 w0.109: v4(110.23,82.41) 110.53,82.71 111.41,82.71 111.62,82.92 112.13,82.92 112.89,83.68 117.01,83.68 117.22,83.47 119.76,83.47 120.15,83.08 120.9,83.08 121.61,82.38 121.92,82.38 v5(122.39,81.91)
AM57XX_PRU2ETH0_TXD1: length 10.8
  TOP w0.173: U1.A12 117.13,83.62 117.13,83.62 117.98,83.62 118.15,83.45 123.12,83.45 R164.2
AM57XX_PRU2ETH0_TXD2: length 8.1
  TOP w0.173: R168.2 117.55,82.25 116.59,83.22 112.64,83.22 U1.B13
AM57XX_PRU2ETH0_TXD3: length 10.8
  TOP w0.173: U1.A11 115.15,84.42 115.91,85.17 R169.2
AM57XX_PRU2ETH0_TXEN: length 298.1
  TOP w0.173: R196.2 v1(43.31,75.92) ; v5(125.22,84.54) 123.06,84.54 122.51,83.98 120.32,83.98 R167.2 115.7,84.54 115.18,84.01 112.63,84.01 U1.B12
  L3_SIG1 w0.109: v6(129.72,84.1) 129.69,84.08 126.47,84.08 126.01,84.54 v5(125.22,84.54)
  L10_SIG4 w0.109: v6(129.72,84.1) 129.72,84.05 128.99,83.33 128.99,80.69 128.68,80.37 127.28,80.37 126.62,79.71 126.62,78.9 125.09,77.38 125.09,72.99 124.66,72.56 124.66,70.97 127.08,68.56 128.73,68.56 129.9,69.73 131.27,69.73 132.13,68.87 147.2,68.87 148.64,70.31 152.86,70.31 157.15,66.02 157.15,56.51 155.24,54.6 155.24,52.43 154,51.19 154,41.28 154.71,40.57 154.71,37.55 151.28,34.12 140.72,34.12 129.92,23.32 125.23,23.32 118.98,17.07 111.86,17.07 110.99,16.21 106.15,16.21 105.21,15.27 92.71,15.27 92.19,14.75 70.17,14.75 67.28,17.63 65.23,17.63 62.08,20.78 54.91,20.78 51.03,24.66 45.2,24.66 44.5,25.36 44.5,27.26 41.83,29.93 41.83,31.39 40.81,32.42 40.24,32.42 37.64,35.02 37.64,41.08 32.49,46.23 30.96,46.23 28.37,48.82 28.37,50.55 27.97,50.96 27.97,53.12 28.68,53.83 28.68,58.98 27.71,59.95 27.71,62.79 38.02,73.11 38.02,77.81 38.38,78.16 41.06,78.16 v1(43.31,75.92)
AM57XX_PRU2ETH1_MRCLK: length 132.1
  TOP w0.173: R209.2 39.9,52.91 40.92,53.93 41.3,53.93 v1(41.31,53.95) ; U1.AC9 v4(95.04,86.41)
  L3_SIG1 w0.109: v6(94.64,86.66) 95.03,86.42 v4(95.04,86.41)
  L10_SIG4 w0.109: v1(41.31,53.95) 41.45,53.95 41.47,53.93 43.2,53.93 43.34,54.07 43.34,55.83 43.49,55.97 43.68,55.97 43.82,55.83 43.82,54.07 43.97,53.93 44.16,53.93 44.3,54.07 44.3,55.83 44.45,55.97 44.64,55.97 44.78,55.83 44.78,54.55 44.93,54.41 45.12,54.41 45.26,54.55 45.26,56.95 45.41,57.09 45.6,57.09 45.74,56.95 45.74,55.57 45.89,55.43 46.08,55.43 46.22,55.57 46.22,57.46 46.37,57.6 46.56,57.6 46.7,57.46 46.7,56.71 46.85,56.57 47.04,56.57 47.18,56.71 47.18,57.46 47.33,57.6 47.52,57.6 47.66,57.46 47.66,54.6 47.81,54.46 48,54.46 48.14,54.6 48.14,56.59 48.29,56.73 48.48,56.73 48.62,56.59 48.62,55.57 48.77,55.43 48.96,55.43 49.11,55.57 49.11,57.46 49.25,57.6 49.44,57.6 49.59,57.46 49.59,56.66 49.75,56.49 49.95,56.49 50.07,56.61 50.07,57.46 50.21,57.6 50.4,57.6 50.55,57.46 50.55,54.07 50.69,53.93 50.88,53.93 51.03,54.07 51.03,56.54 51.17,56.68 51.36,56.68 51.51,56.54 51.51,54.07 51.65,53.93 51.87,53.93 52.01,54.07 52.01,57.27 52.15,57.41 52.35,57.41 52.49,57.27 52.49,54.07 52.63,53.93 54.98,53.93 55.09,54.04 55.09,54.53 55.2,54.64 55.42,54.64 55.53,54.53 55.53,54.04 55.64,53.93 55.86,53.93 55.96,54.04 55.96,54.53 56.07,54.64 56.29,54.64 56.4,54.53 56.4,54.04 56.51,53.93 56.73,53.93 56.84,54.04 56.84,54.53 56.95,54.64 57.17,54.64 57.28,54.53 57.28,54.04 57.38,53.93 57.61,53.93 58.14,54.45 58.14,54.61 57.71,55.04 57.71,55.19 57.86,55.35 58.02,55.35 58.45,54.92 58.6,54.92 58.75,55.07 58.75,55.23 58.32,55.66 58.32,55.81 58.48,55.96 58.63,55.96 59.06,55.54 59.22,55.54 59.37,55.69 59.37,55.84 58.94,56.27 58.94,56.43 59.1,56.58 59.25,56.58 59.68,56.15 59.84,56.15 60.02,56.33 60.02,56.49 59.65,56.86 59.65,57.01 59.81,57.16 59.96,57.16 60.33,56.8 60.48,56.8 60.64,56.95 60.64,57.11 60.27,57.47 60.27,57.63 60.42,57.78 60.58,57.78 60.94,57.42 61.1,57.42 77.72,74.04 77.72,78.23 77.55,78.41 77.55,85.62 80.19,88.27 83.57,88.27 84.22,88.92 86.17,88.92 86.44,89.19 91.16,89.19 91.26,89.08 93.62,89.08 94.26,88.45 94.26,87.04 v6(94.64,86.66)
AM57XX_PRU2ETH1_RXD0: length 131.8
  TOP w0.173: U1.AB5 v4(95.84,89.61)
  L3_SIG1 w0.102: 95.33,91.62 95.33,90.5 95.84,90 v4(95.84,89.61)
  L3_SIG1 w0.109: v6(92.79,96.21) 93.22,95.78 93.22,94.37 93.73,93.86 93.73,93.22 95.33,91.62
  L10_SIG4 w0.109: v1(40,57.23) 39.87,57.37 39.53,57.37 39.42,57.26 39.42,56.93 40.95,55.4 41.48,55.4 42.28,56.2 42.28,56.96 42.14,57.1 41.77,57.1 41.63,57.24 41.63,57.44 41.77,57.58 42.14,57.58 42.28,57.72 42.28,57.92 42.14,58.06 41.77,58.06 41.63,58.2 41.63,58.4 41.77,58.54 42.14,58.54 42.28,58.68 42.28,59.04 43.93,60.69 45.08,60.69 45.22,60.83 45.22,62.38 45.36,62.52 45.56,62.52 45.7,62.38 45.7,60.83 45.84,60.69 46.04,60.69 46.18,60.83 46.18,62.38 46.32,62.52 46.52,62.52 46.66,62.38 46.66,60.83 46.8,60.69 47,60.69 47.14,60.83 47.14,62.38 47.28,62.52 47.48,62.52 47.62,62.38 47.62,61.08 47.79,60.92 47.98,60.92 48.1,61.03 48.1,62.38 48.24,62.52 48.44,62.52 48.58,62.38 48.58,60.96 48.72,60.81 50.31,60.81 51.13,59.99 53.75,59.99 53.87,59.88 53.87,58.75 54,58.62 54.2,58.62 54.35,58.76 54.35,59.82 54.46,59.94 54.66,59.94 54.83,59.77 54.83,58.83 54.97,58.68 55.17,58.68 55.31,58.81 55.31,59.95 55.45,60.09 55.64,60.09 55.79,59.95 55.79,58.78 55.93,58.64 56.12,58.64 56.27,58.78 56.27,59.95 56.41,60.09 56.6,60.09 56.75,59.95 56.75,58.91 56.89,58.77 57.08,58.77 57.23,58.91 57.23,59.95 57.37,60.09 57.57,60.09 57.71,59.95 57.71,59.04 57.85,58.89 58.05,58.89 58.19,59.04 58.19,59.95 58.33,60.09 58.53,60.09 58.67,59.95 58.67,59.04 58.81,58.89 59.01,58.89 59.15,59.04 59.15,59.95 59.29,60.09 59.49,60.09 59.63,59.95 59.63,59.04 59.77,58.89 60.88,58.89 61.72,59.73 61.72,59.93 60.58,61.07 60.58,61.27 60.72,61.41 60.92,61.41 62.06,60.27 62.26,60.27 62.4,60.41 62.4,60.61 61.26,61.75 61.26,61.95 61.4,62.09 61.6,62.09 62.74,60.95 62.94,60.95 64.44,62.46 64.99,62.46 75.69,73.15 75.69,75.33 76.15,75.79 76.15,86.52 78.57,88.94 83.23,88.94 83.9,89.61 84.69,89.61 85.61,90.53 90.49,90.53 92.3,92.34 92.3,95.72 v6(92.79,96.21)
  BOTTOM w0.173: v1(40,57.23) 38.48,58.76 R213.2
AM57XX_PRU2ETH1_RXD1: length 131.7
  TOP w0.173: U1.AB8 v4(95.84,87.21)
  L3_SIG1 w0.109: v6(95.44,87.46) 95.83,87.22 v4(95.84,87.21)
  L10_SIG4 w0.109: v6(95.44,87.46) 94.99,87.91 94.69,87.91 94.51,88.09 94.51,88.55 93.73,89.33 91.71,89.33 91.43,89.61 86.36,89.61 86.02,89.27 84.1,89.27 83.43,88.6 79.91,88.6 76.5,85.2 76.5,74.5 76.71,74.3 76.71,73.51 61.37,58.17 59.49,58.17 59.35,58.03 59.35,57.19 59.21,57.05 59.01,57.05 58.87,57.19 58.87,58.03 58.73,58.17 58.45,58.17 58.31,58.03 58.31,56.69 58.17,56.55 57.97,56.55 57.83,56.69 57.83,58.03 57.69,58.17 57.49,58.17 57.35,58.03 57.35,55.53 57.21,55.39 57.01,55.39 56.87,55.53 56.87,58.03 56.73,58.17 56.53,58.17 56.39,58.03 56.39,56.69 56.25,56.55 56.05,56.55 55.91,56.69 55.91,58.03 55.77,58.17 55.57,58.17 55.43,58.03 55.43,56.69 55.29,56.55 55.09,56.55 54.95,56.69 54.95,58.03 54.81,58.17 54.58,58.17 54.44,58.03 54.44,54.67 54.3,54.53 54.1,54.53 53.96,54.67 53.96,58.03 53.82,58.17 53.62,58.17 53.48,58.03 53.48,54.67 53.34,54.53 53.14,54.53 53,54.67 53,57.62 52.86,57.76 51.42,57.76 50.58,58.6 49.5,58.6 49.36,58.74 49.36,60.1 49.22,60.24 49.02,60.24 48.88,60.1 48.88,58.64 48.74,58.5 48.54,58.5 48.4,58.64 48.4,60.03 48.26,60.17 48.06,60.17 47.92,60.03 47.92,58.71 47.81,58.6 46.62,58.6 46.48,58.74 46.48,60.1 46.34,60.24 46.14,60.24 46,60.1 46,58.95 45.86,58.81 45.66,58.81 45.52,58.95 45.52,60.1 45.38,60.24 45.18,60.24 45.04,60.1 45.04,58.31 44.9,58.17 44.7,58.17 44.56,58.31 44.56,60.1 44.42,60.24 44.22,60.24 44.08,60.1 44.08,58.31 43.94,58.17 43.35,58.17 42.65,57.47 42.65,55.96 41.73,55.04 40.67,55.04 38.25,57.46 38.25,59.42 v1(38.73,59.9)
  BOTTOM w0.173: R215.2 v1(38.73,59.9)
AM57XX_PRU2ETH1_RXD2: length 131.8
  TOP w0.173: U1.AD6 v4(94.24,88.81)
  L3_SIG1 w0.109: v4(94.24,88.81) 92.63,88.81 90.84,90.6 89.93,90.6 89.4,91.13 85.54,91.13 85.47,91.06 v6(84.87,91.06)
  L10_SIG4 w0.109: v6(84.87,91.06) 77.49,91.06 74.88,88.45 74.88,77.6 74.55,77.27 74.55,76.32 74.3,76.07 74.3,74.42 73.63,73.76 73.63,72.93 69.42,68.71 67.24,68.71 67.1,68.57 67.1,66.71 66.96,66.57 66.76,66.57 66.62,66.71 66.62,68.39 66.47,68.54 66.27,68.54 66.14,68.41 66.14,66.71 66,66.57 65.8,66.57 65.66,66.71 65.66,68.42 65.54,68.55 65.34,68.55 65.18,68.39 65.18,66.71 65.04,66.57 64.84,66.57 64.7,66.71 64.7,68.41 64.56,68.55 64.36,68.55 64.22,68.41 64.22,66.71 64.08,66.57 63.88,66.57 63.74,66.71 63.74,68.43 63.62,68.56 63.42,68.56 63.26,68.4 63.26,66.68 63.12,66.54 62.92,66.54 62.78,66.68 62.78,68.55 62.64,68.69 54.11,68.69 53.94,68.52 53.94,67.45 53.8,67.31 53.6,67.31 53.46,67.45 53.46,68.57 53.32,68.71 53.12,68.71 52.98,68.57 52.98,67.45 52.84,67.31 52.64,67.31 52.5,67.45 52.5,68.57 52.36,68.71 52.16,68.71 52.02,68.57 52.02,67.45 51.88,67.31 51.68,67.31 51.54,67.45 51.54,68.57 51.4,68.71 51.2,68.71 51.06,68.57 51.06,67.45 50.92,67.31 50.72,67.31 50.58,67.45 50.58,68.57 50.44,68.71 50.24,68.71 50.1,68.57 50.1,67.45 49.96,67.31 49.76,67.31 49.62,67.45 49.62,68.57 49.48,68.71 49.28,68.71 49.14,68.57 49.14,67.45 49,67.31 48.8,67.31 48.66,67.45 48.66,68.57 48.52,68.71 48.32,68.71 48.18,68.57 48.18,67.45 48.04,67.31 47.84,67.31 47.7,67.45 47.7,68.57 47.56,68.71 47.36,68.71 47.22,68.57 47.22,67.45 47.08,67.31 46.88,67.31 46.74,67.45 46.74,68.57 46.6,68.71 46.4,68.71 46.26,68.57 46.26,67.45 46.12,67.31 45.92,67.31 45.78,67.45 45.78,68.57 45.64,68.71 45.24,68.71 45.13,68.6 45.13,67.3 45.02,67.19 44.81,67.19 44.7,67.3 44.7,68.6 44.59,68.71 44.37,68.71 44.26,68.6 44.26,67.3 44.15,67.19 43.93,67.19 43.82,67.3 43.82,68.6 43.71,68.71 43.49,68.71 43.39,68.6 43.39,67.3 43.28,67.19 43.06,67.19 42.95,67.3 42.95,68.6 42.84,68.71 41.96,68.71 41.15,67.9 v1(41.15,61.04)
  BOTTOM w0.173: R216.2 v1(41.15,61.04)
AM57XX_PRU2ETH1_RXD3: length 130.5
  TOP w0.173: U1.AC8 v4(95.04,87.21)
  L3_SIG1 w0.109: v6(84.2,90.38) 84.33,90.26 85.62,90.26 85.82,90.45 88.92,90.45 89.68,89.69 90.53,89.69 92.71,87.51 93.07,87.51 93.08,87.51 94.74,87.51 v4(95.04,87.21)
  L10_SIG4 w0.109: v6(84.2,90.38) 84.13,90.32 78.68,90.32 75.44,87.08 75.44,77.59 74.89,77.04 74.89,73.32 67.78,66.21 64.11,66.21 63.97,66.07 63.97,64.23 63.83,64.09 63.63,64.09 63.49,64.23 63.49,66.05 63.35,66.19 63.15,66.19 63.01,66.05 63.01,64.23 62.87,64.09 62.67,64.09 62.53,64.23 62.53,66.07 62.39,66.21 62.19,66.21 62.05,66.07 62.05,64.23 61.91,64.09 61.71,64.09 61.57,64.23 61.57,66.07 61.43,66.21 61.23,66.21 61.09,66.07 61.09,64.23 60.95,64.09 60.75,64.09 60.61,64.23 60.61,66.07 60.47,66.21 60.27,66.21 60.13,66.07 60.13,64.23 59.99,64.09 59.79,64.09 59.65,64.23 59.65,66.07 59.51,66.21 58.35,66.21 58.21,66.07 58.21,65.33 57.12,64.24 55.55,64.24 54.85,64.94 54.85,66.07 54.71,66.21 54.51,66.21 54.37,66.07 54.37,64.13 54.23,63.99 54.03,63.99 53.89,64.13 53.89,65.41 53.75,65.55 53.55,65.55 53.41,65.41 53.41,64.13 53.27,63.99 52.11,63.99 51.97,64.13 51.97,66.07 51.83,66.21 51.63,66.21 51.49,66.07 51.49,64.36 51.37,64.25 51.17,64.25 51.01,64.41 51.01,66.07 50.87,66.21 50.28,66.21 50.17,66.1 50.17,65.09 50.06,64.98 49.84,64.98 49.73,65.09 49.73,66.1 49.62,66.21 49.4,66.21 49.29,66.1 49.29,65.09 49.19,64.98 48.97,64.98 48.86,65.09 48.86,66.1 48.75,66.21 48.53,66.21 48.42,66.1 48.42,65.09 48.31,64.98 48.09,64.98 47.98,65.09 47.98,66.1 47.87,66.21 47.66,66.21 47.55,66.1 47.55,65.09 47.44,64.98 47.22,64.98 47.11,65.09 47.11,66.1 47,66.21 46.78,66.21 46.67,66.1 46.67,65.09 46.56,64.98 46.35,64.98 46.24,65.09 46.24,66.1 46.13,66.21 45.91,66.21 45.8,66.1 45.8,65.09 45.69,64.98 45.47,64.98 45.36,65.09 45.36,66.1 45.25,66.21 45.04,66.21 44.93,66.1 44.93,65.09 44.82,64.98 44.6,64.98 44.49,65.09 44.49,66.1 44.38,66.21 44.02,66.21 42.02,64.21 42.02,60.75 41.57,60.3 40.62,60.3 v1(38.73,62.18)
  BOTTOM w0.173: R217.2 v1(38.73,62.18)
AM57XX_PRU2ETH1_RXDV: length 132.4
  TOP w0.173: v1(41.27,55.83) 39.5,54.06 R211.2 ; U1.AC3 v4(95.04,91.21)
  L3_SIG1 w0.109: v6(92.48,96.68) 92.41,96.6 92.41,94.77 93.47,93.71 93.47,93.1 95.04,91.53 v4(95.04,91.21)
  L10_SIG4 w0.109: v1(41.27,55.83) 41.27,57.69 41.17,57.8 40.69,57.8 40.58,57.91 40.58,58.12 40.69,58.23 41.17,58.23 41.27,58.34 41.27,59.14 42.56,60.43 42.56,62.49 42.73,62.66 42.96,62.66 43.12,62.49 43.12,61.24 43.26,61.1 43.46,61.1 43.6,61.24 43.6,62.82 43.74,62.96 43.94,62.96 44.08,62.82 44.08,61.24 44.22,61.1 44.42,61.1 44.56,61.24 44.56,62.82 44.7,62.96 44.93,62.96 45.07,63.1 45.07,64.14 45.21,64.28 45.41,64.28 45.55,64.14 45.55,63.1 45.69,62.96 45.89,62.96 46.03,63.1 46.03,64.14 46.17,64.28 46.37,64.28 46.51,64.14 46.51,63.1 46.65,62.96 46.85,62.96 46.99,63.1 46.99,64.14 47.13,64.28 47.33,64.28 47.47,64.14 47.47,63.1 47.61,62.96 47.81,62.96 47.95,63.1 47.95,64.14 48.09,64.28 48.29,64.28 48.43,64.14 48.43,63.1 48.57,62.96 48.77,62.96 48.91,63.1 48.91,64.14 49.05,64.28 49.25,64.28 49.39,64.14 49.39,63.1 49.53,62.96 49.73,62.96 49.87,63.1 49.87,64.14 50.01,64.28 50.21,64.28 50.35,64.14 50.35,63.35 50.49,63.21 50.63,63.21 50.98,62.86 51.77,62.86 51.94,63.03 51.94,63.47 52.08,63.61 52.28,63.61 52.42,63.47 52.42,62.93 52.56,62.79 52.76,62.79 52.9,62.93 52.9,63.47 53.04,63.61 53.24,63.61 53.38,63.47 53.38,63.19 53.52,63.05 53.72,63.05 53.86,63.19 53.86,63.4 54,63.54 54.2,63.54 54.34,63.4 54.34,61.99 54.48,61.85 54.68,61.85 54.82,61.99 54.82,63.35 54.96,63.49 55.16,63.49 55.3,63.35 55.3,62.02 55.44,61.88 55.64,61.88 55.78,62.02 55.78,63.47 55.92,63.61 56.12,63.61 56.26,63.47 56.26,61.23 56.4,61.09 56.6,61.09 56.74,61.23 56.74,62.46 56.88,62.6 57.08,62.6 57.22,62.46 57.22,61.23 57.36,61.09 57.56,61.09 57.7,61.23 57.7,62.36 57.84,62.5 58.04,62.5 58.18,62.36 58.18,61.23 58.32,61.09 59.67,61.09 60.46,61.88 60.46,62.95 61.03,63.52 65.57,63.52 66.09,64.04 66.09,64.19 65.66,64.62 65.66,64.77 65.81,64.93 65.97,64.93 66.4,64.5 66.55,64.5 75.26,73.21 75.26,75.38 75.79,75.91 75.79,86.67 79.07,89.95 84.55,89.95 85.54,90.94 90.19,90.94 92.02,92.77 92.02,96.22 v6(92.48,96.68)
AM57XX_PRU2ETH1_RXER: length 132.9
  TOP w0.173: v5(120.27,72.78) 119.84,72.78 117.7,74.91 117.25,74.91 114.54,77.62 112.63,77.62 112.23,78.01 U1.B19 ; R212.2 v1(38.64,56.34)
  L3_SIG1 w0.109: v6(121.06,72.78) v5(120.27,72.78)
  L9_SIG3 w0.114: v6(62.99,58.42) 62.99,59.06 70.42,66.49 72.73,66.49 80.01,73.77 98.48,73.77 99.95,75.25 104.26,75.25 104.65,75.63 104.65,75.93 104.87,76.15 105.17,76.15 105.42,76.41 105.42,76.7 105.67,76.95 105.97,76.95 106.22,77.21 106.22,77.5 106.47,77.75 106.77,77.75 107.02,78.01 107.02,78.3 107.3,78.58 107.59,78.58 107.82,78.81 107.82,79.1 108.07,79.35 108.89,79.35 110.06,80.52 112.37,80.52 114.48,78.41 119.66,78.41 121.06,77.02 v6(121.06,72.78)
  L10_SIG4 w0.109: v6(62.99,58.42) 56.49,51.92 55.59,51.92 55.48,52.03 55.48,53.16 55.37,53.27 55.15,53.27 55.04,53.16 55.04,52.03 54.94,51.92 54.72,51.92 54.61,52.03 54.61,53.16 54.5,53.27 54.28,53.27 54.17,53.16 54.17,52.03 54.06,51.92 53.84,51.92 53.73,52.03 53.73,53.16 53.62,53.27 53.41,53.27 53.3,53.16 53.3,52.03 53.19,51.92 52.97,51.92 52.86,52.03 52.86,53.16 52.75,53.27 52.53,53.27 52.42,53.16 52.42,52.03 52.31,51.92 52.1,51.92 51.99,52.03 51.99,53.16 51.88,53.27 51.66,53.27 51.55,53.16 51.55,52.03 51.44,51.92 51.22,51.92 51.11,52.03 51.11,53.16 51,53.27 50.78,53.27 50.68,53.16 50.68,52.03 50.57,51.92 50.35,51.92 50.24,52.03 50.24,53.16 50.13,53.27 49.91,53.27 49.8,53.16 49.8,52.03 49.69,51.92 46.35,51.92 46.08,52.2 41.08,52.2 39.5,53.78 39.5,55.48 v1(38.64,56.34)
AM57XX_PRU2ETH1_TXCLK: length 22.6
  TOP w0.173: 78.87,95.97 v5(79.63,95.97) ; U1.AC5 v4(95.04,89.61)
  L3_SIG1 w0.102: 94.44,91.47 94.54,91.38 94.54,90.96 94.74,90.76 94.74,89.91 v4(95.04,89.61)
  L3_SIG1 w0.109: 94.44,91.47 92.86,93.05 92.86,93.42 91.64,94.64 91.64,96.42 91.08,96.98 87.83,96.98 87.5,96.65 86.23,96.65 85.72,96.14 82.96,96.14 82.52,96.58 81.59,96.58 80.98,95.97 v5(79.63,95.97)
AM57XX_PRU2ETH1_TXD0: length 22.9
  TOP w0.173: 78.87,94.95 v5(79.63,94.95) ; U1.AC6 v4(95.04,88.81)
  L3_SIG1 w0.099: 94.24,90.71 93.94,91 93.94,91.56
  L3_SIG1 w0.102: 94.24,90.71 94.36,90.71 94.53,90.54 94.53,89.71 95.04,89.2 v4(95.04,88.81)
  L3_SIG1 w0.109: 93.94,91.56 92.46,93.05 92.46,93.26 91.39,94.33 91.39,95.94 90.73,96.6 87.96,96.6 86.97,95.61 86.08,95.61 85.9,95.79 83.29,95.79 83.11,95.61 80.29,95.61 v5(79.63,94.95)
AM57XX_PRU2ETH1_TXD1: length 19.6
  TOP w0.173: v5(79.58,93.02) 79.49,93.02 79.39,92.92 78.87,92.92 ; U1.AC7 v4(95.04,88.01)
  L3_SIG1 w0.099: v4(95.04,88.01) 94.74,88.31 94.74,89.05 94.47,89.32 93.84,89.32 93.68,89.48 93.46,89.71 93.46,89.71 93.44,89.72
  L3_SIG1 w0.109: 93.44,89.72 92.61,90.55 91.97,90.55 91.34,91.18 90.18,91.18 89.51,91.84 87.15,91.84 86.29,92.71 85.12,92.71 84.71,92.3 82.85,92.3 82.45,92.71 80.54,92.71 80.23,93.02 v5(79.58,93.02)
AM57XX_PRU2ETH1_TXD2: length 22.5
  TOP w0.173: 78.87,96.98 v5(79.63,96.98) ; U1.AC4 v4(95.04,90.41)
  L3_SIG1 w0.102: v4(95.04,90.41) 95.04,90.8 94.74,91.09 94.74,91.49
  L3_SIG1 w0.109: v5(79.63,96.98) 80.85,96.98 81.39,97.52 82.4,97.52 83.26,96.65 85.65,96.65 86.44,97.44 91.34,97.44 91.95,96.83 91.95,94.8 93.22,93.53 93.22,93.02 94.74,91.49
AM57XX_PRU2ETH1_TXD3: length 18.3
  TOP w0.173: 78.87,93.93 v5(79.63,93.93) ; U1.AD4 v4(94.24,90.41)
  L3_SIG1 w0.099: 93.73,91.39 93.73,90.92 94.23,90.41
  L3_SIG1 w0.109: 93.73,91.39 92.48,92.64 90.8,92.64 90.64,92.8 88.16,92.8 86.24,94.72 80.49,94.72 79.71,93.93 v5(79.63,93.93) ; v4(94.24,90.41) 94.23,90.41
AM57XX_PRU2ETH1_TXEN: length 23.7
  TOP w0.173: 78.87,98 v5(79.63,98) ; U1.AB4 v4(95.84,90.41)
  L3_SIG1 w0.102: v4(95.84,90.41) 95.54,90.71 95.54,91.34 95.58,91.37
  L3_SIG1 w0.109: 95.58,91.37 95.58,95.31 94.3,96.59 93.44,96.59 92.91,97.11 92.53,97.11 91.74,97.9 81.81,97.9 81.41,98.3 79.93,98.3 v5(79.63,98)
AM57XX_PRU2ETH_MDCLK: length 372.1
  TOP w0.173: R179.2 v1(30.61,76.15) ; v1(31.15,51.45) 30.61,51.99 R221.2 ; U1.C14 v4(111.83,82.41)
  L3_SIG1 w0.109: v4(111.83,82.41) 112.23,82.41 113.07,83.26 116.8,83.26 117.25,82.81 119.54,82.81 119.89,82.46 120.62,82.46 121.96,81.12 124.55,81.12 125.17,80.51 127.55,80.51 127.84,80.21 131.03,80.21 131.17,80.35 v6(135.64,80.35) ; v1(30.61,76.15) 29.59,75.14 28.58,75.14 22.03,68.59 22.03,53.14 16.89,48.01 15.62,48.01 10.29,42.67 10.29,37.98 v6(14.06,34.21)
  L4_SIG2 w0.114: v6(135.64,80.35) 149.87,80.35 153.42,76.79 153.42,76.31 161.19,68.54 161.99,68.54 170.64,59.88 170.64,43.04 170.02,42.42 170.02,35.83 152.81,18.62 152.27,18.62 140.77,7.12 128.64,7.12 127.97,6.45 118.98,6.45 118.68,6.75 113.3,6.75 112.98,7.07 112.07,7.07 111.94,6.94 104.44,6.94 103.81,7.57 98.62,7.57 97.42,8.78 92.77,8.78 92.39,9.17 69.12,9.17 68.18,10.1 58.95,10.1 58.51,10.55 56.64,10.55 56.42,10.33 56.05,10.33 50.29,4.57 42.67,4.57 41.91,3.81 28.58,3.81 27.58,4.8 27.58,5.21 25.04,7.75 24.13,7.75 20.95,10.92 20.95,24.8 16.01,29.75 16.01,33.78 15.47,34.31 14.17,34.31 v6(14.06,34.21)
  L9_SIG3 w0.114: v1(30.61,76.15) 30.61,69.46 33.27,66.79 33.27,56.01 31.15,53.88 v1(31.15,51.45)
AM57XX_PRU2ETH_MDDATA: length 309.2
  TOP w0.173: v1(30.43,51.46) 30.22,51.46 29.59,52.09 R223.2 ; R181.2 v1(29.59,76.15) ; U1.D14 v4(111.03,82.41)
  L3_SIG1 w0.109: v6(135,81.18) 128.85,81.18 128.04,82 127.51,82 126.49,80.98 125.1,80.98 124.67,81.41 122.1,81.41 120.76,82.75 120.01,82.75 119.64,83.11 117.25,83.11 116.89,83.47 112.98,83.47 112.22,82.71 111.71,82.71 111.42,82.41 v4(111.03,82.41)
  L4_SIG2 w0.114: v6(135,81.18) 150.91,81.18 153.09,79.01 153.09,78.83 154.05,77.86 154.75,77.86 157.78,74.84 157.78,73.4 172.17,59.01 172.17,51.43 171.23,50.48 171.23,39.78 170.47,39.02 170.47,34.62 152.82,16.97 151.26,16.97 139.99,5.71 119.21,5.71 118.47,6.46 113.18,6.46 112.86,6.78 112.19,6.78 111.81,6.39 104.57,6.39 103.78,7.19 98.59,7.19 97.29,8.49 92.65,8.49 92.27,8.88 69,8.88 68.97,8.9 68.35,9.52 v6(56.48,9.52)
  L9_SIG3 w0.114: v6(56.48,9.52) 56.34,9.52 37.43,28.44 37.43,44.47 v1(30.43,51.46) 30.43,55.97 27.02,59.39 27.02,67.96 29.59,70.53 v1(29.59,76.15)
AM57XX_RGMII0_RD0: length 101.7
  TOP w0.173: v5(36.07,111.71) 35.61,111.26 R289.2 ; U1.W2 98.24,92.01 98.24,96.13 96.27,98.09 96.27,101.27 96.8,101.8 96.8,104.19 94.91,106.08 93.17,106.08 v5(92.08,104.98)
  L3_SIG1 w0.109: v5(92.08,104.98) 91.52,105.54 90.85,105.54 90.55,105.24 90.55,104.32 90.26,104.04 82.76,104.04 80.42,106.38 76.14,106.38 72.95,103.19 72.95,102.16 71.42,100.64 68.73,100.64 68.63,100.75 68.63,101.24 68.52,101.35 68.3,101.35 68.19,101.24 68.19,100.75 68.08,100.64 66.46,100.64 66.35,100.75 66.35,101.72 66.24,101.83 66.02,101.83 65.91,101.72 65.91,100.75 65.8,100.64 65.59,100.64 65.48,100.75 65.48,101.72 65.37,101.83 65.15,101.83 65.04,101.72 65.04,100.75 64.93,100.64 64.71,100.64 64.6,100.75 64.6,101.72 64.49,101.83 64.27,101.83 64.17,101.72 64.17,100.75 64.06,100.64 63.84,100.64 63.73,100.75 63.73,101.72 63.62,101.83 63.4,101.83 63.29,101.72 63.29,100.75 63.18,100.64 62.96,100.64 62.85,100.75 62.85,101.72 62.75,101.83 62.53,101.83 62.42,101.72 62.42,100.75 62.31,100.64 62.09,100.64 61.98,100.75 61.98,101.72 61.87,101.83 61.65,101.83 61.54,101.72 61.54,100.75 61.43,100.64 51.43,100.64 50.35,101.72 45.5,101.72 42.44,104.78 42.44,105.41 41.58,106.28 39.94,106.28 36.07,110.15 v5(36.07,111.71)
AM57XX_RGMII0_RD1: length 101.6
  TOP w0.173: R84.2 34.21,111.26 v5(34.67,111.71) ; U1.Y2 97.43,92.02 97.43,94.59 94.86,97.17 94.86,99.38 93.17,101.07 93.17,103.12 93.04,103.25 93.04,103.63 92.35,104.32 v5(91.82,104.32)
  L3_SIG1 w0.109: v5(91.82,104.32) 91.79,104.32 91.06,103.59 82.17,103.59 79.98,105.77 76.35,105.77 75.44,104.86 75.44,103.84 70.41,98.81 69.2,98.81 69.09,98.92 69.09,99.49 68.98,99.6 68.76,99.6 68.65,99.49 68.65,98.92 68.54,98.81 67.33,98.81 67.22,98.92 67.22,99.72 67.11,99.83 66.89,99.83 66.78,99.72 66.78,98.92 66.67,98.81 66.45,98.81 66.34,98.92 66.34,99.72 66.23,99.83 66.02,99.83 65.91,99.72 65.91,98.92 65.8,98.81 65.58,98.81 65.47,98.92 65.47,99.72 65.36,99.83 65.14,99.83 65.03,99.72 65.03,98.92 64.92,98.81 63.5,98.81 62.74,99.57 61.85,99.57 61.74,99.68 61.74,100.07 61.63,100.18 61.41,100.18 61.3,100.07 61.3,99.68 61.19,99.57 60.97,99.57 60.87,99.68 60.87,100.07 60.76,100.18 60.54,100.18 60.43,100.07 60.43,99.68 60.32,99.57 60.1,99.57 59.99,99.68 59.99,100.07 59.88,100.18 59.66,100.18 59.55,100.07 59.55,99.68 59.45,99.57 59.23,99.57 59.12,99.68 59.12,100.07 59.01,100.18 58.79,100.18 58.68,100.07 58.68,99.68 58.57,99.57 58.35,99.57 58.24,99.68 58.24,100.07 58.13,100.18 57.92,100.18 57.81,100.07 57.81,99.68 57.7,99.57 57.48,99.57 57.37,99.68 57.37,100.07 57.26,100.18 57.04,100.18 56.93,100.07 56.93,99.68 56.82,99.57 56.61,99.57 56.5,99.68 56.5,100.07 56.39,100.18 56.17,100.18 56.06,100.07 56.06,99.68 55.95,99.57 55.73,99.57 55.62,99.68 55.62,100.07 55.51,100.18 55.29,100.18 55.19,100.07 55.19,99.68 55.08,99.57 54.86,99.57 54.75,99.68 54.75,100.07 54.64,100.18 54.42,100.18 54.31,100.07 54.31,99.68 54.2,99.57 53.98,99.57 53.87,99.68 53.87,100.07 53.77,100.18 53.55,100.18 53.44,100.07 53.44,99.68 53.33,99.57 53.11,99.57 53,99.68 53,100.07 52.89,100.18 52.67,100.18 52.56,100.07 52.56,99.68 52.46,99.57 51.71,99.57 50.02,101.27 45.31,101.27 41.88,104.69 41.88,105.34 41.4,105.82 39.65,105.82 34.67,110.8 v5(34.67,111.71)
AM57XX_RGMII0_RD2: length 101.9
  TOP w0.173: U1.V3 v4(99.04,91.21) ; v5(33.4,112.86) 33.4,111.84 32.82,111.26 R291.2
  L3_SIG1 w0.109: v5(33.4,112.86) 33.83,113.29 37.94,113.29 39.93,111.3 40.41,111.3 41,110.71 41,109.85 41.27,109.58 41.42,109.58 41.7,109.86 41.86,109.86 42.01,109.71 42.01,109.55 41.73,109.27 41.73,109.12 41.89,108.97 42.04,108.97 42.32,109.24 42.47,109.24 42.63,109.09 42.63,108.94 42.35,108.66 42.35,108.5 42.5,108.35 42.66,108.35 42.94,108.63 43.09,108.63 43.25,108.47 43.25,108.32 42.97,108.04 42.97,107.88 43.12,107.73 43.28,107.73 43.56,108.01 43.71,108.01 43.87,107.85 43.87,107.7 43.59,107.42 43.59,107.27 43.74,107.11 43.89,107.11 44.17,107.39 44.33,107.39 44.48,107.24 44.48,107.08 44.2,106.8 44.2,106.65 44.36,106.49 44.51,106.49 44.79,106.77 44.95,106.77 45.1,106.62 45.1,106.46 44.82,106.18 44.82,106.03 44.98,105.87 45.13,105.87 45.41,106.15 45.57,106.15 45.72,106 45.72,105.84 45.44,105.56 45.44,105.41 46.45,104.4 46.6,104.4 46.87,104.67 47.03,104.67 47.18,104.51 47.18,104.36 46.91,104.09 46.91,103.94 47.19,103.66 68.83,103.66 69.8,104.63 72.09,104.63 73.19,105.73 73.19,105.9 72.67,106.42 72.67,106.58 72.78,106.7 72.95,106.7 73.47,106.18 73.63,106.18 73.75,106.29 73.75,106.46 73.23,106.98 73.23,107.14 73.34,107.26 73.51,107.26 74.03,106.74 74.2,106.74 75.56,108.11 79.54,108.11 79.65,108.22 79.65,108.56 79.76,108.67 79.98,108.67 80.09,108.56 80.09,108.22 80.2,108.11 80.42,108.11 80.53,108.22 80.53,108.56 80.64,108.67 80.85,108.67 80.96,108.56 80.96,108.22 81.07,108.11 81.29,108.11 81.4,108.22 81.4,108.56 81.51,108.67 81.73,108.67 81.84,108.56 81.84,108.22 81.95,108.11 85.07,108.11 86.61,106.56 92.09,106.56 93.74,104.91 95,104.91 97.05,102.85 97.82,102.85 99.39,101.27 99.39,96.6 99.29,96.5 99.29,92.74 98.83,92.28 98.83,91.42 v4(99.04,91.21)
AM57XX_RGMII0_RD3: length 100.8
  TOP w0.173: U1.V4 v4(99.04,90.41) ; v5(31.88,111.71) 31.42,111.26 R85.2
  L3_SIG1 w0.099: v4(99.04,90.41) 99.04,90.75 98.55,91.23 98.55,91.5
  L3_SIG1 w0.109: 98.55,91.5 98.55,92.51 99.03,92.99 99.03,94.24 98.86,94.42 98.86,96.63 98.93,96.7 98.93,101.02 97.56,102.39 96.88,102.39 95.38,103.89 93.34,103.89 92.86,104.37 92.86,105.34 91.97,106.23 90.4,106.23 90.25,106.08 84.43,106.08 84.12,105.77 83.03,105.77 81.25,107.55 75.82,107.55 72.44,104.17 70.13,104.17 69.06,103.1 56.72,103.1 55.24,101.63 53.39,101.63 53.28,101.74 53.28,102.31 53.17,102.42 52.96,102.42 52.85,102.31 52.85,101.74 52.74,101.63 52.17,101.63 50.6,103.21 46.96,103.21 41.99,108.18 41.81,108.18 41.54,107.92 41.54,107.91 41.38,107.75 41.21,107.75 41.1,107.86 41.1,108.03 41.56,108.49 41.56,108.65 41.44,108.77 41.27,108.77 40.82,108.31 40.65,108.31 40.53,108.42 40.53,108.59 40.99,109.04 40.99,109.2 40.87,109.32 40.52,109.32 39.44,110.4 39.44,110.57 39.65,110.78 39.65,110.94 39.53,111.06 39.37,111.06 39.15,110.85 38.99,110.85 38.87,110.96 38.87,111.13 39.09,111.34 39.09,111.5 38.97,111.62 38.81,111.62 38.59,111.41 38.43,111.41 38.31,111.52 38.31,111.69 38.53,111.9 38.53,112.06 38.41,112.18 38.24,112.18 38.03,111.97 37.87,111.97 37.75,112.09 37.75,112.25 37.96,112.46 37.96,112.63 37.85,112.74 37.68,112.74 37.47,112.53 37.31,112.53 37.03,112.81 35.71,112.81 35.56,112.66 35.56,112.22 35.45,112.1 35.28,112.1 35.17,112.22 35.17,112.66 35.05,112.78 34.59,112.78 34.2,112.38 34.2,111.72 34.06,111.59 33.72,111.59 33.6,111.7 33.6,112.23 33.49,112.35 33.32,112.35 33.21,112.23 33.21,111.84 33.08,111.71 v5(31.88,111.71)
AM57XX_RGMII0_RXCLK: length 101.7
  TOP w0.173: R288.2 39.55,111.26 v5(41.15,112.86) ; U1.U5 v4(99.84,89.61)
  L3_SIG1 w0.099: v4(99.84,89.61) 99.33,90.12 99.33,91.33 99.11,91.55 99.11,91.7
  L3_SIG1 w0.109: v5(41.15,112.86) 41.65,112.36 41.83,112.36 42.92,111.27 42.92,111.1 42.64,110.83 42.64,110.66 42.76,110.55 42.92,110.55 43.2,110.82 43.37,110.82 43.48,110.71 43.48,110.54 43.2,110.27 43.2,110.1 43.32,109.98 43.49,109.98 43.76,110.26 43.93,110.26 44.04,110.15 44.04,109.98 43.77,109.7 43.77,109.54 43.88,109.42 44.05,109.42 44.32,109.7 44.49,109.7 44.6,109.59 44.6,109.42 44.33,109.14 44.33,108.98 44.44,108.86 44.61,108.86 44.89,109.14 45.05,109.14 45.17,109.02 45.17,108.86 44.89,108.58 44.89,108.42 45,108.3 45.17,108.3 45.45,108.58 45.61,108.58 45.73,108.46 45.73,108.3 45.45,108.02 45.45,107.86 45.56,107.74 45.73,107.74 46.01,108.02 46.17,108.02 46.29,107.9 46.29,107.74 46.01,107.46 46.01,107.3 46.13,107.18 46.29,107.18 46.57,107.46 46.73,107.46 46.85,107.34 46.85,107.18 46.57,106.9 46.57,106.74 46.68,106.63 46.86,106.63 47.13,106.9 47.29,106.9 47.47,106.72 47.47,106.57 47.27,106.36 47.27,106.21 47.42,106.05 47.57,106.05 47.78,106.26 47.93,106.26 48.09,106.1 48.09,105.95 47.88,105.74 47.88,105.59 48.04,105.43 48.19,105.43 48.4,105.64 48.55,105.64 48.71,105.48 48.71,105.33 48.5,105.12 48.5,104.97 48.66,104.82 48.81,104.82 49.02,105.02 49.17,105.02 49.38,104.81 68.09,104.81 69.7,106.43 69.86,106.43 70.31,105.98 70.5,105.98 70.63,106.1 70.63,106.26 70.13,106.76 70.13,106.91 70.28,107.07 70.44,107.07 70.94,106.57 71.09,106.57 71.25,106.72 71.25,106.88 70.75,107.38 70.75,107.53 70.9,107.68 71.05,107.68 71.55,107.18 71.71,107.18 71.86,107.34 71.86,107.49 71.36,107.99 71.36,108.15 71.52,108.3 71.67,108.3 72.17,107.8 72.33,107.8 72.48,107.96 72.48,108.11 71.98,108.61 71.98,108.77 72.14,108.92 72.29,108.92 72.79,108.42 72.95,108.42 74.59,110.06 81.88,110.06 82.37,110.55 84.05,110.55 87.53,107.07 90.82,107.07 91,106.89 92.33,106.89 93.19,106.02 93.95,106.02 94.61,105.36 95.17,105.36 97.23,103.31 98.15,103.31 99.85,101.6 99.85,96.68 99.54,96.37 99.54,92.66 99.11,92.23 99.11,91.7
AM57XX_RGMII0_RXCTL: length 100.3
  TOP w0.173: R285.2 37.01,111.26 v5(37.46,111.71) ; U1.V5 v4(99.04,89.61)
  L3_SIG1 w0.099: 98.09,91.48 98.09,91.32 98.74,90.67 98.74,89.91 v4(99.04,89.61)
  L3_SIG1 w0.109: v5(37.46,111.71) 37.46,109.4 40.12,106.74 42.77,106.74 44.47,105.04 44.47,104.88 43.84,104.25 43.84,104.09 43.96,103.97 44.12,103.97 44.72,104.57 44.89,104.57 45,104.46 45,104.29 44.38,103.67 44.38,103.5 44.49,103.38 44.66,103.38 45.26,103.99 45.45,103.99 45.56,103.88 45.56,103.73 44.92,103.08 44.92,102.93 45.03,102.82 45.22,102.82 45.82,103.43 45.98,103.43 46.1,103.31 46.1,103.14 45.57,102.62 45.57,102.46 45.81,102.23 46.41,102.23 46.52,102.34 46.52,102.59 46.63,102.7 46.85,102.7 46.96,102.59 46.96,102.34 47.07,102.23 47.28,102.23 47.39,102.34 47.39,102.59 47.5,102.7 47.72,102.7 47.83,102.59 47.83,102.34 47.94,102.23 48.16,102.23 48.27,102.34 48.27,102.59 48.38,102.7 48.6,102.7 48.7,102.59 48.7,102.34 48.81,102.23 49.03,102.23 49.14,102.34 49.14,102.59 49.25,102.7 49.47,102.7 49.58,102.59 49.58,102.34 49.69,102.23 49.91,102.23 50.01,102.34 50.01,102.59 50.12,102.7 50.34,102.7 50.45,102.59 50.45,102.34 50.56,102.23 50.71,102.23 51.82,101.12 56.23,101.12 56.34,101.23 56.34,101.75 56.45,101.86 56.66,101.86 56.77,101.75 56.77,101.23 56.88,101.12 57.1,101.12 57.21,101.23 57.21,101.75 57.32,101.86 57.54,101.86 57.65,101.75 57.65,101.23 57.76,101.12 57.97,101.12 58.08,101.23 58.08,101.75 58.19,101.86 58.41,101.86 58.52,101.75 58.52,101.23 58.63,101.12 58.85,101.12 58.96,101.23 58.96,101.55 59.07,101.66 59.28,101.66 59.39,101.55 59.39,101.23 59.5,101.12 60.25,101.12 61.52,102.39 70.64,102.39 71.96,103.71 72.72,103.71 75.97,106.96 81.14,106.96 82.82,105.29 84.3,105.29 84.6,105.58 90.33,105.58 90.64,105.9 91.77,105.9 92.51,105.16 92.51,104.15 93.23,103.43 94.87,103.43 95.78,102.52 95.78,101.71 98.48,99.01 98.48,94.52 98.25,94.29 98.25,92.61 98.09,92.46 98.09,91.48
AM57XX_RGMII0_TD0: length 30.3
  TOP w0.173: R282.2 86.74,102.06 v5(86.74,99.82) ; U1.U6 v4(99.84,88.81)
  L3_SIG1 w0.109: v6(99.44,89.06) 99.84,88.82 v4(99.84,88.81) ; v5(86.74,99.82) v6(86.74,99.14)
  L10_SIG4 w0.109: v6(86.74,99.14) 87.2,98.68 88.19,98.68 89.1,99.6 90.25,99.6 90.71,100.06 94.71,100.06 95.25,100.61 98.57,100.61 99.7,99.47 100,99.17 100,93.32 99.11,92.44 99.11,91.5 99.44,91.17 99.44,89.07 v6(99.44,89.06)
AM57XX_RGMII0_TD1: length 21
  TOP w0.173: R287.2 91.82,102.06 v5(91.82,99.78) ; U1.V6 v4(99.04,88.81)
  L3_SIG1 w0.099: v4(99.04,88.81) 98.54,89.31 98.54,90.59 97.84,91.29 97.84,91.42
  L3_SIG1 w0.109: v6(95.89,99.62) 98.02,97.49 98.02,96.6 98.17,96.45 98.17,94.57 98.02,94.42 98.02,92.84 97.84,92.66 97.84,91.42 ; v5(91.82,99.78) v6(91.82,99.14)
  L10_SIG4 w0.109: v6(95.89,99.62) 95.17,99.62 95.01,99.46 92.14,99.46 v6(91.82,99.14)
AM57XX_RGMII0_TD2: length 30.3
  TOP w0.173: v5(88.01,99.78) 88.01,102.06 R87.2 ; U1.U7 v4(99.84,88.01)
  L3_SIG1 w0.109: v6(99.44,88.26) v4(99.84,88.01) ; v5(88.01,99.78) v6(88.01,99.14)
  L10_SIG4 w0.109: v6(99.44,88.26) 99.89,88.71 99.89,89.68 99.74,89.83 99.74,90.93 99.97,91.17 99.97,91.88 99.69,92.16 99.69,92.71 100.3,93.32 100.3,99.29 98.69,100.91 95.13,100.91 94.58,100.37 90.38,100.37 90.07,100.06 88.93,100.06 v6(88.01,99.14)
AM57XX_RGMII0_TD3: length 27.3
  TOP w0.173: U1.V7 v4(99.04,88.01) ; v5(89.28,99.78) 89.28,102.06 R94.2
  L3_SIG1 w0.109: v5(89.28,99.78) v6(89.28,99.14) ; v6(98.64,88.26) v4(99.04,88.01)
  L10_SIG4 w0.109: v6(98.64,88.26) 98.78,88.41 98.78,91.06 98.48,91.37 98.48,92.46 99.49,93.48 99.49,98.5 97.99,100 96.9,100 95.99,99.09 93.92,99.09 93.9,99.11 92.38,99.11 91.98,98.71 89.71,98.71 v6(89.28,99.14)
AM57XX_RGMII0_TXCLK: length 32.7
  TOP w0.173: R92.2 85.47,102.06 v5(85.47,99.82) ; U1.W9 v4(98.24,86.41)
  L3_SIG1 w0.109: v6(97.84,86.66) v4(98.24,86.41) ; v5(85.47,99.82) v6(85.47,99.14)
  L10_SIG4 w0.109: v6(85.47,99.14) 86.49,98.13 92.03,98.13 92.71,98.81 93.93,98.81 94.11,98.63 95.91,98.63 96.93,99.65 97.66,99.65 98.6,98.71 98.6,98.02 99.06,97.57 99.06,93.4 98.06,92.4 98.06,91.4 98.5,90.96 98.5,89.21 98.22,88.93 98.22,87.05 v6(97.84,86.66)
AM57XX_RGMII0_TXCTL: length 28.1
  TOP w0.173: R286.2 90.55,102.06 v5(90.55,99.78) ; U1.V9 v4(99.04,86.41)
  L3_SIG1 w0.109: v6(98.64,86.66) v4(99.04,86.41) ; v5(90.55,99.78) v6(90.55,99.14)
  L10_SIG4 w0.109: v6(90.55,99.14) 91.17,99.76 94.83,99.76 95.38,100.3 98.44,100.3 99.77,98.97 99.77,93.43 98.78,92.44 98.78,91.39 99.03,91.14 99.03,87.06 v6(98.64,86.66)
AM57XX_RGMII1_RD0: length 115.8
  TOP w0.173: v5(57.53,111.84) 57.53,110.67 56.92,110.06 R333.2 ; U1.A4 113.68,90.02 115.67,92 117.83,92 121.61,95.78 121.61,96.88 v5(122.01,97.27)
  L3_SIG1 w0.109: v5(57.53,111.84) 56.91,112.47 54.98,112.47 54.74,112.7 54.74,115.25 54.96,115.47 55.84,115.47 55.96,115.35 55.96,114.98 56.07,114.86 56.24,114.86 56.35,114.98 56.35,115.35 56.47,115.47 59.12,115.47 59.35,115.24 59.51,115.24 59.63,115.36 59.63,115.52 59.19,115.96 59.19,116.12 59.31,116.24 59.47,116.24 59.91,115.8 60.07,115.8 60.19,115.92 60.19,116.08 59.75,116.52 59.75,116.68 59.87,116.8 60.03,116.8 60.47,116.36 60.63,116.36 60.75,116.48 60.75,116.64 60.32,117.08 60.32,117.24 60.48,117.4 63.09,117.4 63.93,118.24 64.53,118.24 65.51,119.22 65.67,119.22 65.79,119.1 65.96,119.1 66.07,119.21 66.07,119.38 65.96,119.49 65.96,119.65 66.08,119.77 66.24,119.77 66.45,119.56 66.62,119.56 66.73,119.67 66.73,119.84 66.52,120.05 66.52,120.24 67.09,120.81 75.25,120.81 75.36,120.7 75.36,120.33 75.46,120.22 75.68,120.22 75.79,120.33 75.79,120.7 75.9,120.81 76.12,120.81 76.23,120.7 76.23,120.33 76.34,120.22 76.56,120.22 76.67,120.33 76.67,120.7 76.78,120.81 78,120.81 79.43,119.38 101.44,119.38 102.1,118.72 107.7,118.72 113.23,113.19 113.23,112.65 114.2,111.69 116.87,111.69 124.49,104.07 124.49,99.75 v5(122.01,97.27)
AM57XX_RGMII1_RD1: length 114.8
  TOP w0.173: R334.2 55.52,110.06 56.13,110.67 v5(56.13,111.84) ; U1.B5 112.64,89.62 113.2,89.62 113.2,89.62 113.92,89.62 115.89,91.59 118.05,91.59 122.17,95.71 122.17,96.37 v5(123.42,97.62)
  L3_SIG1 w0.109: v5(123.42,97.62) 125.4,99.6 125.4,103.79 117.02,112.17 114.73,112.17 113.74,113.16 113.74,113.37 107.9,119.21 105.49,119.21 104.09,120.6 102.03,120.6 101.25,119.82 82.67,119.82 81.97,120.53 81.11,120.53 81,120.42 81,120 80.9,119.89 80.68,119.89 80.57,120 80.57,120.42 80.46,120.53 80.24,120.53 80.13,120.42 80.13,120 80.02,119.89 79.8,119.89 79.69,120 79.69,120.42 79.59,120.53 79.15,120.53 78.34,121.34 67,121.34 64.36,118.7 63.75,118.7 62.92,117.86 59.31,117.86 57.37,115.92 54.12,115.92 53.43,115.23 53.43,112.01 53.6,111.84 v5(56.13,111.84)
AM57XX_RGMII1_RD2: length 114.4
  TOP w0.173: v5(120.9,96.83) 120.9,96.35 116.97,92.41 115.47,92.41 113.48,90.41 112.63,90.41 U1.B4 ; R150.2 54.13,110.06 v5(54.58,110.52)
  L3_SIG1 w0.109: v5(120.9,96.83) 120.9,97.69 123.44,100.23 123.44,103.48 116.56,110.37 113.96,110.37 110.2,114.13 109.6,114.13 109.32,114.41 109.32,115.24 106.76,117.81 101.6,117.81 101.17,118.24 83.42,118.24 83.12,117.94 79.44,117.94 79,118.39 78.84,118.39 78.4,117.95 78.24,117.95 78.09,118.11 78.09,118.26 78.53,118.7 78.53,118.86 78.07,119.31 77.42,119.31 77.31,119.2 77.31,118.33 77.2,118.22 76.99,118.22 76.88,118.33 76.88,119.2 76.77,119.31 76.55,119.31 76.44,119.2 76.44,118.33 76.33,118.22 76.11,118.22 76,118.33 76,119.2 75.89,119.31 70.29,119.31 70.18,119.2 70.18,118.33 70.07,118.22 69.85,118.22 69.74,118.33 69.74,119.2 69.63,119.31 69.41,119.31 69.3,119.2 69.3,118.33 69.19,118.22 68.98,118.22 68.87,118.33 68.87,119.2 68.76,119.31 68.1,119.31 64.87,116.08 63.11,116.08 62.45,115.42 62.45,115.26 62.82,114.89 62.82,114.74 62.66,114.58 62.51,114.58 62.14,114.95 61.98,114.95 61.83,114.8 61.83,114.65 62.2,114.27 62.2,114.12 62.04,113.97 61.89,113.97 61.52,114.34 61.36,114.34 61.21,114.18 61.21,114.03 61.58,113.66 61.58,113.5 61.43,113.35 61.27,113.35 60.9,113.72 60.75,113.72 60.59,113.56 60.59,113.41 60.86,113.14 60.86,112.99 60.71,112.83 60.55,112.83 60.28,113.1 60.13,113.1 59.55,112.53 59.55,111.68 59,111.13 55.19,111.13 v5(54.58,110.52)
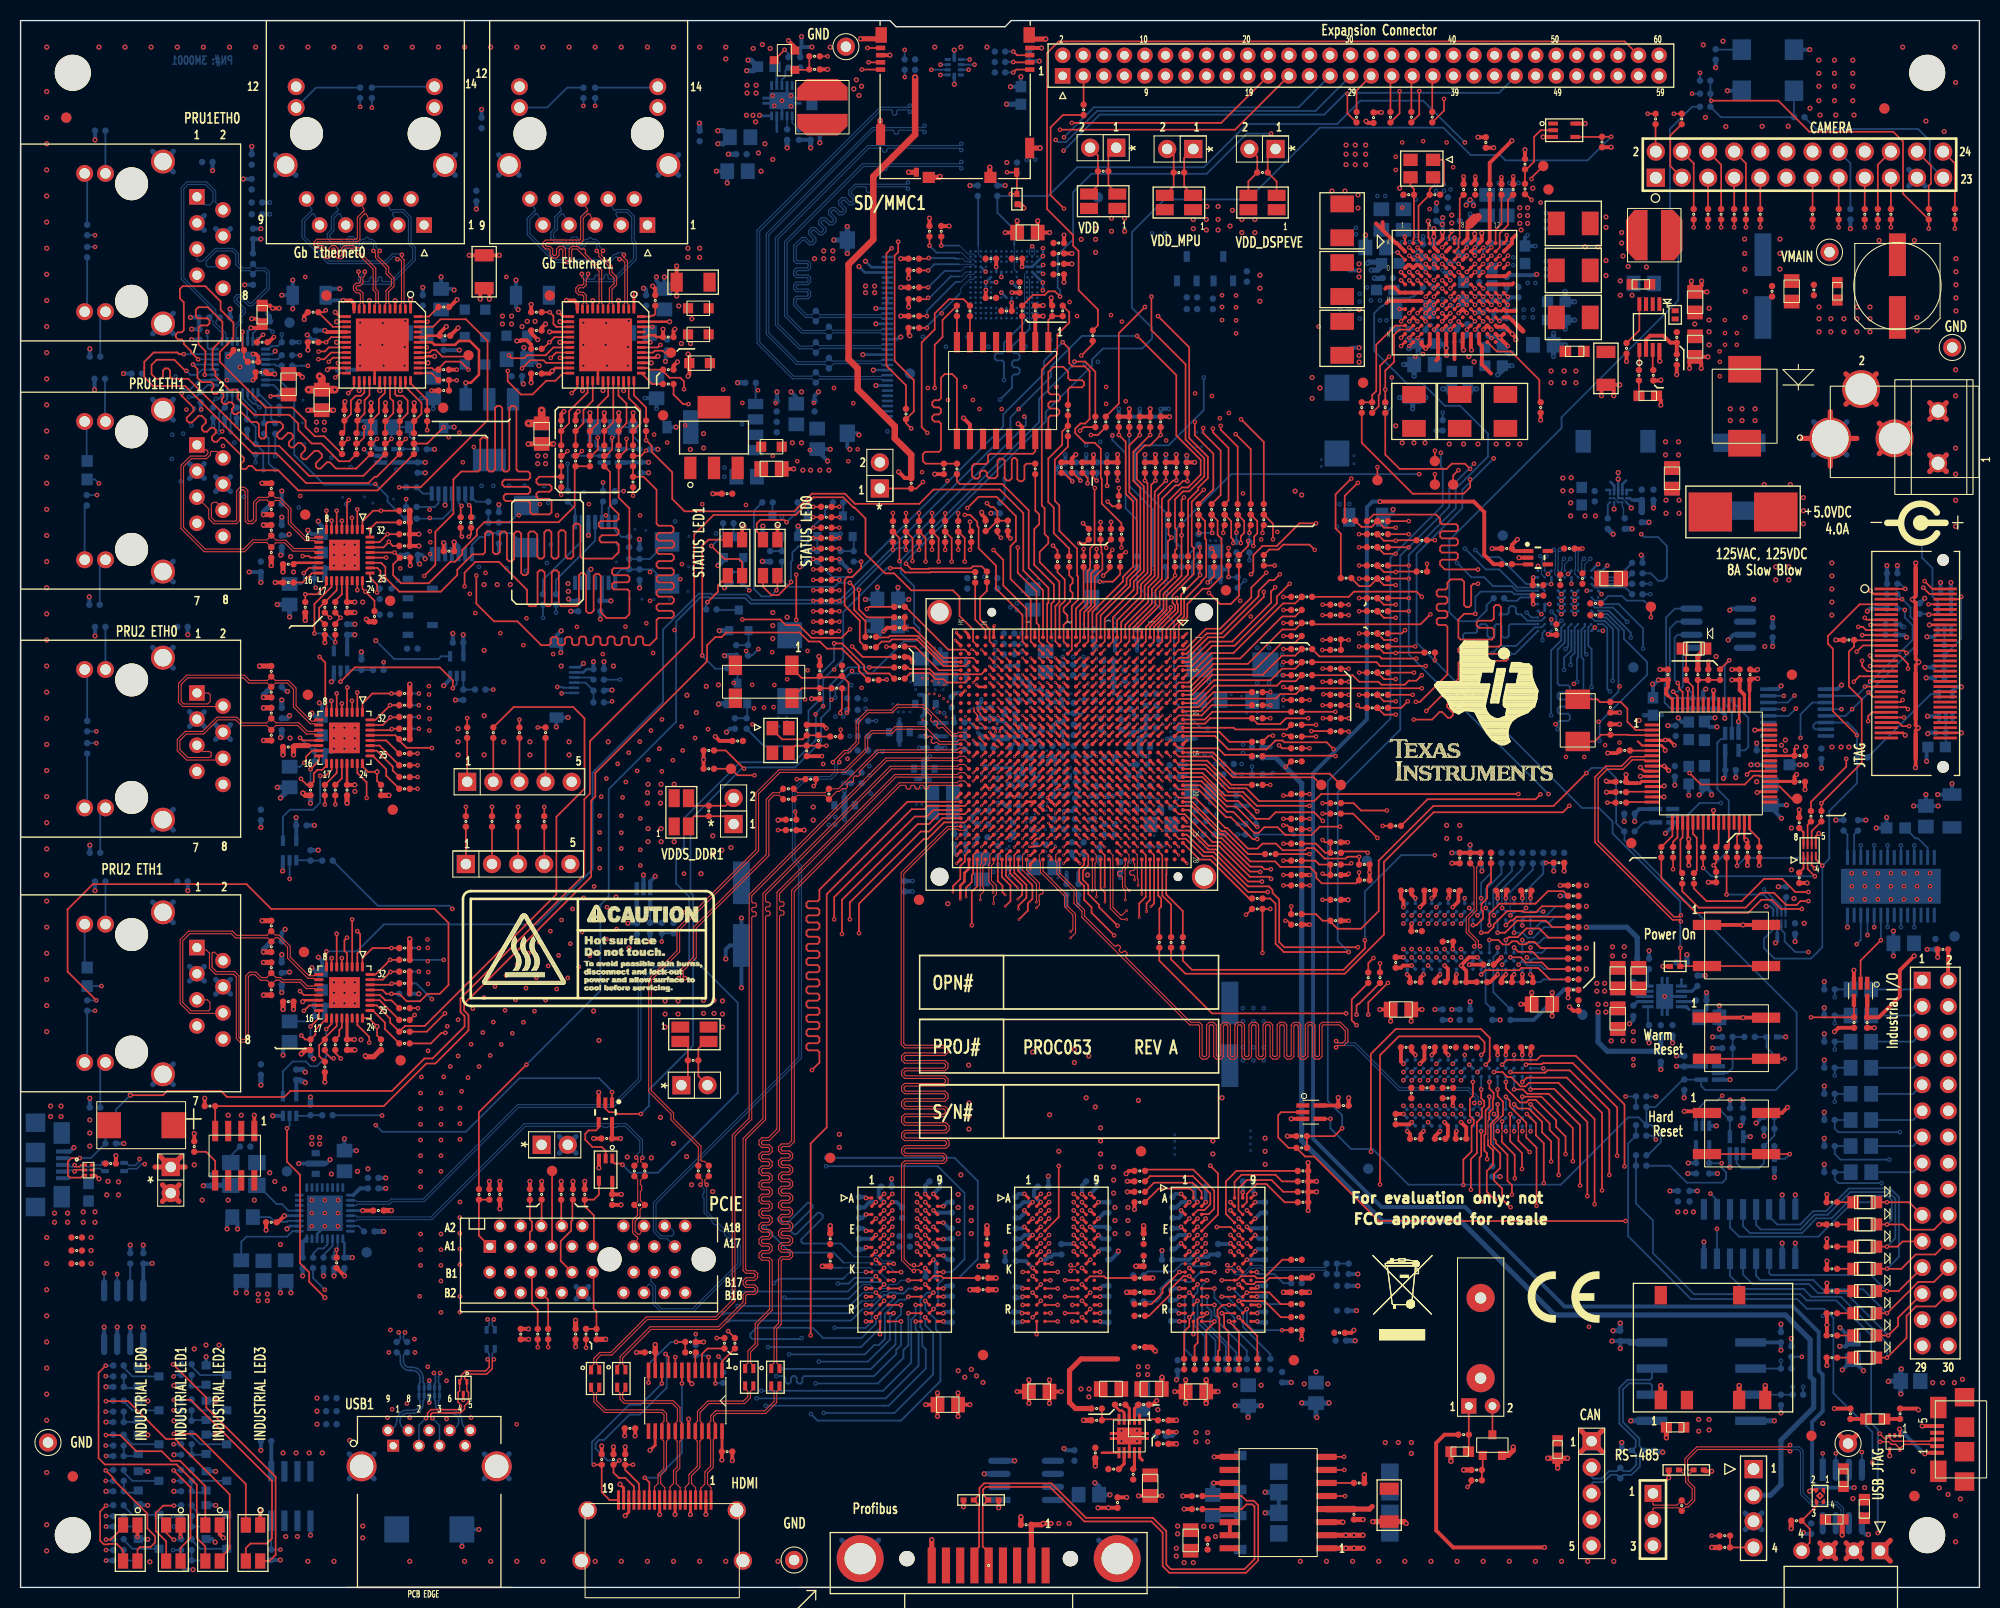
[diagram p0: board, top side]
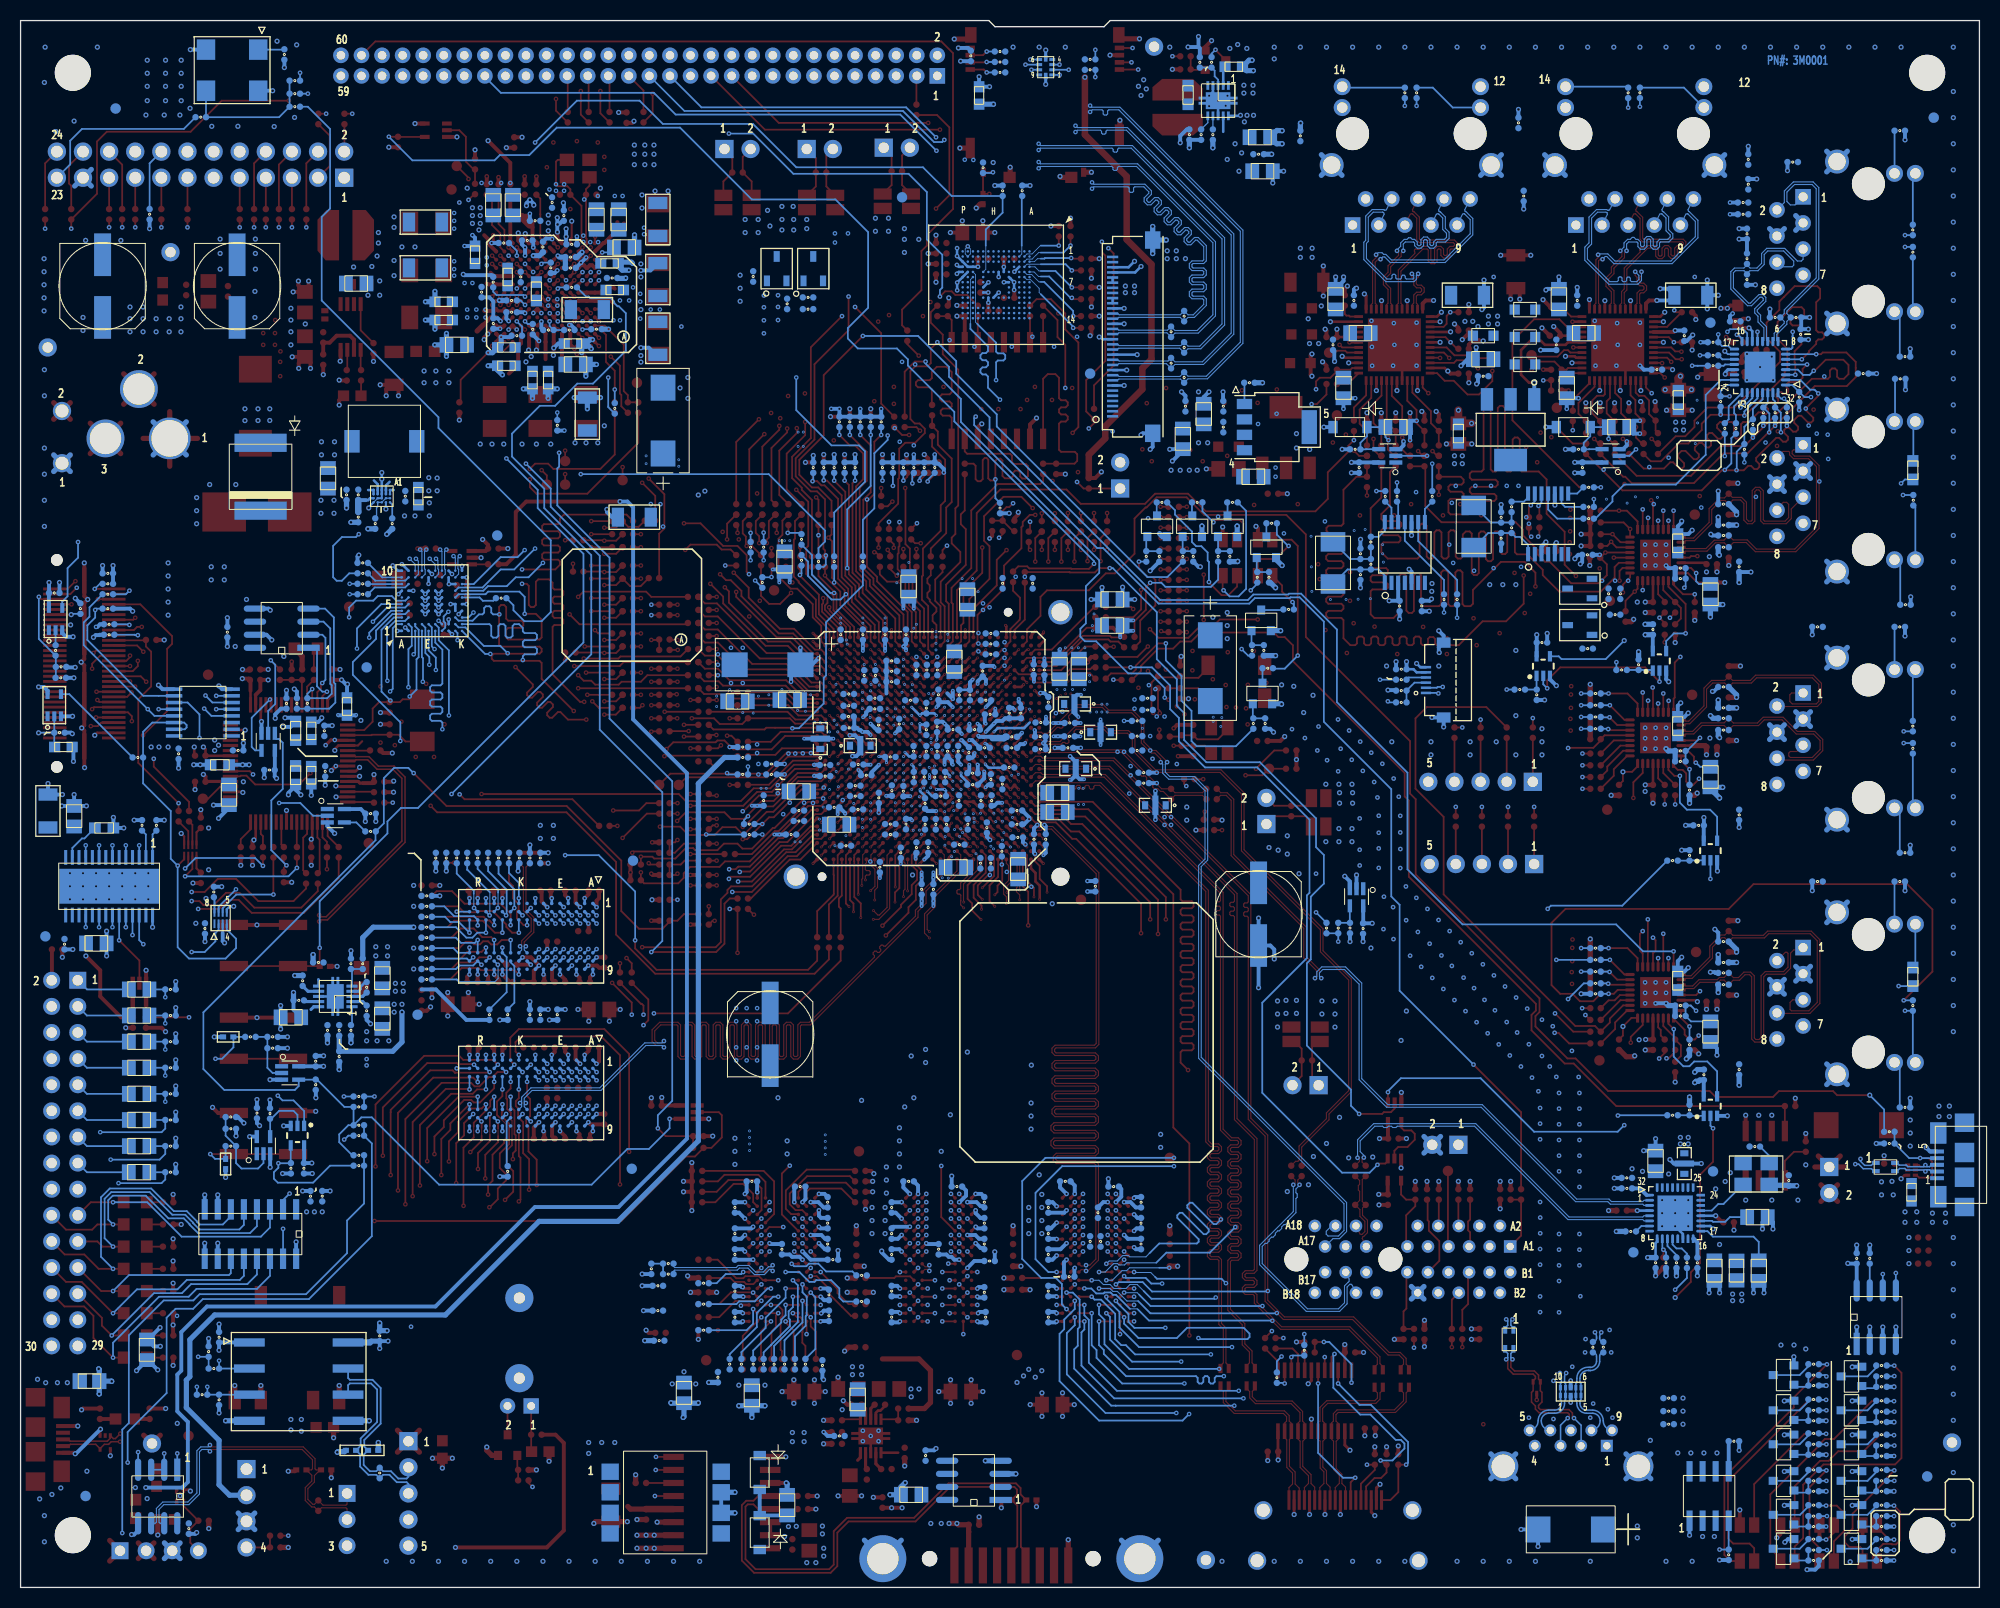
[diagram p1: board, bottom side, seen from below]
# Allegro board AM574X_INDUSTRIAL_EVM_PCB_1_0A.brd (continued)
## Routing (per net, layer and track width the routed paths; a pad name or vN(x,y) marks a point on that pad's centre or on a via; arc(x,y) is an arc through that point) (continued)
CAN1_H: length 19.1
  BOTTOM w0.173: U41.7 158.65,20.37 158.48,20.2 156.27,20.2 155.48,19.4 155.48,15.94 157.08,14.34 157.08,13.7 U88.1 157.13,12.92 157.13,11.91 156.52,11.31 155.91,11.31 R503.2 155.24,11.31 154.48,11.31 153.76,10.59 152.95,10.59 152.78,10.76 J38.2
CAN1_L: length 19.2
  BOTTOM w0.173: J38.3 152.78,10.07 152.95,10.24 153.91,10.24 154.63,10.95 155.24,10.95 R503.1 155.91,10.95 156.67,10.95 157.48,11.77 157.48,12.95 U87.1 157.43,13.78 157.43,14.48 155.83,16.08 155.83,19.26 156.42,19.84 158.48,19.84 158.65,19.67 U41.6
CAN1_RXDF: length 155.9
  L10_SIG4 w0.109: v9(171.2,22.05) 169.8,23.45 169.8,41.99 170.99,43.18 170.99,59.47 169.04,61.42 169.04,69.05 169.79,69.8 169.79,71.72 167.51,74 165.48,74 163.8,75.67 163.8,83.06 163.35,83.52 163.35,100.04 164.87,101.57 164.87,135.18 165.51,135.82 165.51,140.44 161.08,144.86 143.5,144.86 J21.41
  BOTTOM w0.173: U41.2 R502.2 v9(171.2,22.05)
CAN1_TXDF: length 161
  L10_SIG4 w0.109: v9(172.34,19.51) 174.37,21.54 174.37,25.61 173.29,26.69 173.29,57.61 172.5,58.41 172.5,62.17 171.58,63.09 171.58,71.32 171.57,72.98 166.24,78.31 166.24,80.47 167.59,81.82 167.59,89.69 165.48,91.8 165.48,130.89 165.89,131.3 165.89,133.91 167.86,135.88 167.86,142.4 164.54,145.72 162.38,145.72 162.07,145.41 144.95,145.41 J21.43
  BOTTOM w0.173: v9(172.34,19.51) R504.2 C254.1 U41.3
DDR2_A0: length 126
  TOP w0.173: v5(150.25,42.14) 150.25,43.86 149.34,44.77 149.34,45.43 147.36,47.41 146.67,47.41 146.43,47.17 145.82,47.17 144.44,48.55 v1(144.44,49.18) ; U1.R25 v4(101.44,72.82) ; R761.2 145.47,65.23 145.11,64.88 144.9,64.88 v1(144.44,64.42)
  L3_SIG1 w0.109: v1(144.44,49.18) 144.06,49.56 144.06,50.27 144.48,50.68 144.48,51.14 144.83,51.49 144.83,52.2 145.95,53.32 145.95,55.94 145.36,56.52 145.36,57.25 145.47,57.36 145.66,57.36 145.77,57.47 145.77,57.69 145.66,57.8 145.47,57.8 145.36,57.91 145.36,58.12 146.46,59.21 146.46,60.77 145.81,61.42 145.81,62.21 145.4,62.62 144.97,62.62 144.86,62.73 144.86,63.17 144.44,63.59 v1(144.44,64.42) ; v4(101.44,72.82) 101.75,72.5 101.76,72.5 v6(101.8,72.46) ; v5(150.25,42.14) v6(149.53,42.14)
  L9_SIG3 w0.114: v6(149.53,42.14) 147.6,42.14 147.35,41.89 141.59,41.89 141.59,41.9 141.27,41.9 141.26,41.89 140.87,41.89 140.47,41.49 129.33,41.49 126.94,43.88 126.94,46.43 123.18,50.19 114.61,50.19 114.3,50.5 114.3,50.66 114.63,51 114.63,51.16 114.47,51.32 114.31,51.32 113.98,50.98 113.82,50.98 113.65,51.15 113.65,51.31 113.99,51.64 113.99,51.8 113.83,51.97 113.66,51.97 113.33,51.63 113.17,51.63 113.01,51.79 113.01,51.95 113.34,52.29 113.34,52.45 113.18,52.61 113.02,52.61 112.68,52.28 112.52,52.28 112.36,52.44 112.36,52.6 112.69,52.94 112.69,53.1 112.53,53.26 112.37,53.26 112.04,52.92 111.88,52.92 111.71,53.09 111.71,53.25 112.05,53.58 112.05,53.74 111.89,53.91 111.72,53.91 111.39,53.57 111.23,53.57 111.07,53.73 111.07,53.89 111.4,54.23 111.4,54.39 111.24,54.55 111.08,54.55 110.74,54.22 110.58,54.22 110.42,54.38 110.42,54.54 110.75,54.88 110.75,55.04 110.59,55.2 110.43,55.2 110.1,54.87 109.94,54.87 109.77,55.03 109.77,55.19 110.11,55.52 110.11,55.68 109.95,55.85 109.78,55.85 109.45,55.51 109.29,55.51 109.13,55.67 109.13,55.84 109.46,56.17 109.46,56.33 109.3,56.49 109.14,56.49 108.8,56.16 108.64,56.16 108.48,56.32 108.48,56.48 108.81,56.82 108.81,56.98 108.65,57.14 108.49,57.14 108.16,56.81 107.99,56.81 107.83,56.97 107.83,57.13 108.17,57.46 108.17,57.62 108.01,57.79 107.84,57.79 107.51,57.45 107.35,57.45 107.19,57.61 107.19,57.78 107.52,58.11 107.52,58.27 107.36,58.43 107.2,58.43 106.86,58.1 106.7,58.1 106.54,58.26 106.54,58.42 106.87,58.76 106.87,58.92 106.71,59.08 106.55,59.08 106.22,58.75 106.05,58.75 105.89,58.91 105.89,59.07 106.23,59.4 106.23,59.56 106.07,59.73 105.9,59.73 105.57,59.39 105.41,59.39 105.25,59.55 105.25,59.72 105.58,60.05 105.58,60.21 105.42,60.37 105.26,60.37 104.92,60.04 104.76,60.04 104.6,60.2 104.6,60.36 104.93,60.7 104.93,60.86 104.77,61.02 104.61,61.02 104.28,60.69 104.11,60.69 103.95,60.85 103.95,61.01 104.29,61.34 104.29,61.5 104.13,61.67 103.96,61.67 103.63,61.33 103.47,61.33 103.27,61.53 103.27,66.1 103.27,66.1 103.27,66.7 103.13,66.84 103.13,69.25 103.64,69.76 103.64,70.1 102.6,71.14 102.6,71.66 v6(101.8,72.46)
  BOTTOM w0.173: U90.N3 v1(144.44,49.18) ; U91.N3 v1(144.44,64.42)
DDR2_A1: length 124.6
  TOP w0.173: v5(148.84,41.43) 148.84,43.39 147.97,44.26 147.97,45.28 146.67,46.58 145.66,46.58 v1(145.24,47) ; R763.2 147.7,61.17 147.05,61.82 145.66,61.82 v1(145.24,62.24) ; U1.R26 v4(101.44,72.02)
  L3_SIG1 w0.109: v5(148.84,41.43) v6(148.03,41.43) ; v4(101.44,72.02) 101.79,71.66 v6(101.8,71.66)
  L9_SIG3 w0.114: v6(101.8,71.66) 102.21,71.25 102.21,71.05 102.8,70.46 102.8,65.9 102.8,65.9 102.8,60.03 103.14,59.69 103.3,59.69 103.77,60.16 103.93,60.16 104.09,60 104.09,59.83 103.63,59.37 103.63,59.21 103.79,59.04 103.95,59.04 104.42,59.51 104.58,59.51 104.74,59.35 104.74,59.19 104.27,58.72 104.27,58.56 104.43,58.4 104.6,58.4 105.06,58.86 105.22,58.86 105.39,58.7 105.39,58.54 104.92,58.07 104.92,57.91 105.08,57.75 105.24,57.75 105.71,58.22 105.87,58.22 106.03,58.06 106.03,57.89 105.57,57.43 105.57,57.27 105.73,57.1 105.89,57.1 106.36,57.57 106.52,57.57 106.68,57.41 106.68,57.25 106.21,56.78 106.21,56.62 106.37,56.46 106.54,56.46 107,56.92 107.16,56.92 107.33,56.76 107.33,56.6 106.86,56.13 106.86,55.97 107.02,55.81 107.18,55.81 107.65,56.28 107.81,56.28 107.97,56.12 107.97,55.95 107.51,55.49 107.51,55.33 107.67,55.16 107.83,55.16 108.3,55.63 108.46,55.63 108.62,55.47 108.62,55.31 108.15,54.84 108.15,54.68 108.31,54.52 108.48,54.52 108.94,54.98 109.1,54.98 109.27,54.82 109.27,54.66 108.8,54.19 108.8,54.03 108.96,53.87 109.12,53.87 109.59,54.34 109.75,54.34 109.91,54.18 109.91,54.01 109.45,53.55 109.45,53.39 109.61,53.22 109.77,53.22 110.26,53.72 110.42,53.72 110.58,53.55 110.58,53.39 110.09,52.9 110.09,52.74 110.25,52.58 110.42,52.58 110.88,53.04 111.07,53.04 111.22,52.9 111.22,52.73 110.74,52.25 110.74,52.09 110.9,51.93 111.06,51.93 111.53,52.4 111.72,52.4 111.87,52.25 111.87,52.09 111.39,51.61 111.39,51.45 111.55,51.28 111.71,51.28 112.2,51.78 112.36,51.78 112.52,51.61 112.52,51.45 112.03,50.96 112.03,50.8 112.19,50.64 112.36,50.64 112.85,51.13 113.01,51.13 113.17,50.97 113.17,50.81 112.68,50.31 112.68,50.15 113.12,49.72 123.03,49.72 126.5,46.25 126.5,43.31 128.76,41.05 142.84,41.05 143.41,41.61 145.74,41.61 145.93,41.42 148.02,41.42 v6(148.03,41.43)
  L10_SIG4 w0.109: v1(145.24,47) 145.62,47.38 145.62,47.91 146.05,48.34 146.05,48.57 147.55,50.07 147.55,51.3 147.66,51.41 148.15,51.41 148.26,51.52 148.26,51.74 148.15,51.84 147.66,51.84 147.55,51.95 147.55,54.44 146.43,55.55 146.43,60.02 146.15,60.3 146.15,60.66 145.24,61.57 v1(145.24,62.24)
  BOTTOM w0.173: U91.P7 v1(145.24,62.24) ; U90.P7 v1(145.24,47)
DDR2_A2: length 127.4
  TOP w0.173: v1(145.24,48.44) 146.1,48.44 146.53,48.01 148.62,48.01 151.66,44.97 v5(151.66,39.1) ; U1.R28 v4(101.44,70.42)
  L3_SIG1 w0.109: v4(101.44,70.42) 101.44,70.42 101.79,70.06 v6(101.8,70.06) ; v1(145.24,48.44) 145.24,49.1 144.44,49.9 144.44,50.26 145.64,51.47 145.64,52.2 146.53,53.09 146.53,54.64 146.64,54.75 146.91,54.75 147.02,54.85 147.02,55.07 146.91,55.18 146.64,55.18 146.53,55.29 146.53,58.09 147.24,58.81 147.24,61.09 145.24,63.09 v1(145.24,63.68) ; v5(151.66,39.1) 151.66,39.1 v6(150.75,39.1)
  L4_SIG2 w0.114: v6(101.8,70.06) 101.8,69.3 101.19,68.69 101.19,61.4 101.73,60.86 101.73,60.7 101.34,60.32 101.34,60.16 101.5,59.99 101.67,59.99 102.05,60.38 102.21,60.38 102.37,60.22 102.37,60.06 101.99,59.67 101.99,59.51 102.15,59.35 102.31,59.35 102.7,59.73 102.86,59.73 103.02,59.57 103.02,59.41 102.64,59.02 102.64,58.86 102.8,58.7 102.96,58.7 103.34,59.09 103.5,59.09 103.67,58.92 103.67,58.76 103.28,58.38 103.28,58.22 103.44,58.05 103.61,58.05 103.99,58.44 104.15,58.44 104.31,58.28 104.31,58.12 103.93,57.73 103.93,57.57 104.09,57.41 104.25,57.41 104.64,57.79 104.8,57.79 104.96,57.63 104.96,57.47 104.58,57.08 104.58,56.92 104.74,56.76 104.9,56.76 105.28,57.15 105.44,57.15 105.61,56.98 105.61,56.82 105.22,56.44 105.22,56.28 105.38,56.11 105.55,56.11 105.93,56.5 106.09,56.5 106.25,56.34 106.25,56.18 105.87,55.79 105.87,55.63 106.03,55.47 106.19,55.47 106.58,55.85 106.74,55.85 106.9,55.69 106.9,55.53 106.52,55.14 106.52,54.98 106.68,54.82 106.84,54.82 107.22,55.21 107.38,55.21 107.55,55.04 107.55,54.88 107.16,54.5 107.16,54.34 107.32,54.17 107.49,54.17 107.87,54.56 108.03,54.56 108.19,54.4 108.19,54.24 107.81,53.85 107.81,53.69 107.97,53.53 108.13,53.53 108.52,53.91 108.68,53.91 108.94,53.65 108.94,50.47 114.86,44.56 118.16,44.56 118.58,44.14 118.74,44.14 118.91,44.31 119.07,44.31 119.23,44.14 119.23,43.98 119.06,43.81 119.06,43.65 121.05,41.66 124.1,41.66 124.96,40.81 126.66,40.81 129.24,38.23 139.78,38.23 140.23,38.69 150.34,38.69 v6(150.75,39.1)
  BOTTOM w0.173: U91.P3 v1(145.24,63.68) 146.08,63.68 146.56,63.2 147.15,63.2 148.16,64.22 R762.2 ; U90.P3 v1(145.24,48.44)
DDR2_A3: length 125.5
  TOP w0.173: v1(144.08,50.85) 144.55,51.31 147.45,51.31 147.84,51.7 151.25,51.7 155.98,46.97 v5(155.98,40.95) ; U1.R27 v4(101.44,71.22)
  L3_SIG1 w0.109: v4(101.44,71.22) 101.79,70.86 v6(101.8,70.86) ; v5(155.98,40.95) v6(155.17,40.95) ; v1(144.08,66.09) 144.04,66.05 144.04,62.76 145.3,61.51 145.3,60.29 145.64,59.95 145.64,59.09 144.91,58.35 144.91,56.27 145.49,55.68 145.49,55.49 145.38,55.38 145.17,55.38 145.06,55.27 145.06,55.05 145.17,54.94 145.38,54.94 145.49,54.83 145.49,54.62 145.38,54.51 145.17,54.51 145.06,54.4 145.06,54.18 145.17,54.07 145.38,54.07 145.49,53.96 145.49,53.75 144.04,52.3 144.04,50.89 v1(144.08,50.85)
  L9_SIG3 w0.114: v6(101.8,70.86) 102.32,70.34 102.32,65.71 102.33,65.71 102.33,59.88 112.96,49.24 122.85,49.24 122.87,49.22 122.9,49.22 126.05,46.06 126.05,43.13 128.61,40.57 143.11,40.57 143.67,41.14 145.55,41.14 145.73,40.95 149.45,40.95 149.56,40.83 149.56,40.12 149.68,40.01 149.9,40.01 150.02,40.12 150.02,40.83 150.13,40.95 150.36,40.95 150.48,40.83 150.48,40.12 150.59,40.01 150.82,40.01 150.93,40.12 150.93,40.83 151.05,40.95 151.28,40.95 151.39,40.83 151.39,40.12 151.5,40.01 151.73,40.01 151.85,40.12 151.85,40.83 151.96,40.95 155.17,40.95 v6(155.17,40.95)
  BOTTOM w0.102: 144.06,67.59 144.06,66.11 v1(144.08,66.09)
  BOTTOM w0.173: R765.2 146.05,69.89 144.06,67.9 144.06,67.59 ; U90.N2 v1(144.08,50.85) ; U91.N2 v1(144.08,66.09)
DDR2_A4: length 126
  TOP w0.102: 144.86,44.89 144.86,44.02
  TOP w0.173: v1(144.88,61.29) 145.89,61.29 146.39,60.79 147.96,60.79 148.59,60.15 R764.2 ; U1.P23 v4(103.03,74.42) ; v1(144.88,46.05) 144.86,46.03 144.86,44.89 ; v5(146.01,40.7) 146.01,42.26 144.86,43.41 144.86,44.02
  L3_SIG1 w0.109: v5(146.01,40.7) v6(145.36,40.7) ; v4(103.03,74.42) 103.04,74.42 103.4,74.06 v6(103.4,74.06)
  L4_SIG2 w0.114: v6(145.36,40.7) 144.73,41.33 142.75,41.33 141.99,40.57 129.41,40.57 124.95,45.04 122.15,45.04 121.83,45.36 121.83,45.52 121.88,45.58 121.88,45.74 121.72,45.9 121.56,45.9 121.5,45.85 121.34,45.85 120.65,46.54 117.2,46.54 116.33,47.41 116.33,48.43 116,48.75 115.84,48.75 115.2,48.11 115.04,48.11 114.88,48.27 114.88,48.43 115.52,49.08 115.52,49.24 115.36,49.4 115.2,49.4 114.55,48.76 114.39,48.76 114.23,48.92 114.23,49.08 114.87,49.72 114.87,49.88 114.71,50.05 114.55,50.05 113.91,49.4 113.75,49.4 113.58,49.57 113.58,49.73 114.23,50.37 114.23,50.53 114.06,50.69 113.9,50.69 113.26,50.05 113.1,50.05 112.94,50.21 112.94,50.37 113.58,51.02 113.58,51.18 113.42,51.34 113.26,51.34 112.61,50.7 112.45,50.7 112.29,50.86 112.29,51.02 112.93,51.66 112.93,51.82 112.77,51.99 112.61,51.99 111.97,51.34 111.81,51.34 111.64,51.51 111.64,51.67 112.29,52.31 112.29,52.47 111.94,52.82 111.94,55.78 111.49,56.23 111.33,56.23 110.95,55.84 110.79,55.84 110.62,56.01 110.62,56.17 111.01,56.55 111.01,56.71 110.85,56.87 110.69,56.87 110.3,56.49 110.14,56.49 109.98,56.65 109.98,56.81 110.36,57.2 110.36,57.36 110.2,57.52 110.04,57.52 109.65,57.14 109.49,57.14 109.33,57.3 109.33,57.46 109.72,57.84 109.72,58.01 109.55,58.17 109.39,58.17 109.01,57.78 108.85,57.78 108.68,57.95 108.68,58.11 109.07,58.49 109.07,58.65 108.91,58.81 108.75,58.81 108.36,58.43 108.2,58.43 108.04,58.59 108.04,58.75 108.42,59.14 108.42,59.3 108.26,59.46 108.1,59.46 107.71,59.08 107.55,59.08 107.39,59.24 107.39,59.4 107.77,59.78 107.77,59.95 107.61,60.11 107.45,60.11 107.07,59.72 106.91,59.72 106.74,59.89 106.74,60.05 107.13,60.43 107.13,60.59 106.97,60.75 106.8,60.75 106.42,60.37 106.26,60.37 106.1,60.53 106.1,60.69 106.48,61.08 106.48,61.24 106.32,61.4 106.16,61.4 105.77,61.02 105.61,61.02 105.45,61.18 105.45,61.34 105.83,61.72 105.83,61.89 105.67,62.05 105.51,62.05 105.13,61.66 104.97,61.66 104.8,61.83 104.8,61.99 105.19,62.37 105.19,62.53 105.03,62.69 104.86,62.69 104.48,62.31 104.32,62.31 104.16,62.47 104.16,62.63 104.54,63.02 104.54,63.18 104.38,63.34 104.22,63.34 103.83,62.96 103.67,62.96 103.51,63.12 103.51,63.28 103.89,63.66 103.89,63.83 103.15,64.57 103.15,69.27 103.64,69.76 103.64,70.31 102.91,71.04 102.91,73.58 103.39,74.06 v6(103.4,74.06)
  L10_SIG4 w0.109: v1(144.88,46.05) 144.53,46.4 144.53,47.25 144.83,47.55 144.83,48.62 145.31,49.1 145.31,51.32 145.63,51.64 145.63,52.09 144.97,52.74 144.97,53.07 145.14,53.23 145.46,53.23 145.57,53.34 145.57,53.56 145.46,53.67 144.94,53.67 144.83,53.78 144.83,54 144.94,54.11 145.46,54.11 145.57,54.22 145.57,54.43 145.46,54.54 145.03,54.54 144.86,54.72 144.86,59.78 144.92,59.84 144.92,61.25 v1(144.88,61.29)
  BOTTOM w0.173: U91.P8 v1(144.88,61.29) ; U90.P8 v1(144.88,46.05)
DDR2_A5: length 127.1
  TOP w0.173: v1(144.88,50.13) 144.94,50.07 148.23,50.07 148.24,50.07 148.26,50.07 148.48,50.29 150.66,50.29 154.5,46.45 154.5,46.24 154.51,46.23 v5(154.51,40.11) ; U1.P22 v4(103.03,75.22)
  L3_SIG1 w0.109: v1(144.88,50.13) 144.97,50.13 146.43,51.59 146.43,52.15 147.73,53.45 147.73,56.62 147.62,56.72 147.35,56.72 147.24,56.83 147.24,57.05 147.35,57.16 147.62,57.16 147.73,57.27 147.73,62.01 144.88,64.85 v1(144.88,65.37) ; v6(103.4,74.86) 103.39,74.86 103.03,75.21 v4(103.03,75.22) ; v5(154.51,40.11) v6(153.8,40.11)
  L4_SIG2 w0.114: v6(153.8,40.11) 153.2,40.11 153.08,40.23 153.08,41.04 152.97,41.15 152.74,41.15 152.62,41.04 152.62,40.23 152.51,40.11 152.28,40.11 152.17,40.23 152.17,41.04 152.05,41.15 151.82,41.15 151.71,41.04 151.71,40.23 151.59,40.11 151.37,40.11 151.25,40.23 151.25,41.04 151.14,41.15 150.91,41.15 150.79,41.04 150.79,40.23 150.68,40.11 149.99,40.11 149.5,40.59 148.84,40.59 148.11,39.86 146.51,39.86 146.39,39.97 146.39,40.4 146.28,40.52 146.05,40.52 145.94,40.4 145.94,39.97 145.82,39.86 145.44,39.86 144.55,40.75 143,40.75 142.36,40.1 129.25,40.1 124.82,44.53 122.02,44.53 120.6,45.95 116.56,45.95 111.18,51.34 111.18,54.72 102.69,63.21 102.69,74.17 103.38,74.86 v6(103.4,74.86)
  BOTTOM w0.102: v1(144.88,65.37) 144.86,65.39 144.86,67.62
  BOTTOM w0.173: U91.P2 v1(144.88,65.37) ; 144.86,67.62 147.05,69.8 147.07,69.8 R766.2 ; U90.P2 v1(144.88,50.13)
DDR2_A6: length 123.5
  TOP w0.102: 145.66,44.69 145.66,43.92
  TOP w0.173: v1(145.68,45.33) 145.66,45.31 145.66,44.69 ; 145.66,43.92 145.66,43.45 v5(146.76,42.35) ; U1.P25 v4(103.03,72.82)
  L3_SIG1 w0.109: v5(146.76,42.35) v6(145.77,42.35) ; v4(103.03,72.82) 103.03,72.81 103.39,72.46 v6(103.4,72.46)
  L9_SIG3 w0.114: v6(145.77,42.35) 132.28,42.35 131.63,43 131.63,43.16 132.22,43.75 132.22,43.91 132.05,44.07 131.89,44.07 131.31,43.49 131.14,43.49 130.98,43.65 130.98,43.81 131.57,44.4 131.57,44.56 131.41,44.72 131.25,44.72 130.66,44.13 130.5,44.13 130.34,44.29 130.34,44.46 130.92,45.04 130.92,45.21 130.76,45.37 130.6,45.37 130.01,44.78 129.85,44.78 129.69,44.94 129.69,45.1 130.28,45.69 130.28,45.85 130.11,46.01 129.95,46.01 129.36,45.43 129.2,45.43 129.04,45.59 129.04,45.75 129.63,46.34 129.63,46.5 129.47,46.66 129.31,46.66 128.72,46.07 128.56,46.07 126.68,47.95 126.68,48.11 127.25,48.69 127.25,48.85 127.09,49.01 126.93,49.01 126.35,48.44 126.19,48.44 126.03,48.6 126.03,48.76 126.61,49.34 126.61,49.5 126.44,49.66 126.28,49.66 125.71,49.08 125.55,49.08 125.38,49.25 125.38,49.41 125.96,49.98 125.96,50.14 125.8,50.31 125.64,50.31 125.06,49.73 124.9,49.73 124.74,49.89 124.74,50.05 125.31,50.63 125.31,50.79 125.15,50.95 124.99,50.95 124.41,50.38 124.25,50.38 124.09,50.54 124.09,50.7 124.67,51.28 124.67,51.44 124.5,51.6 124.34,51.6 123.77,51.02 123.61,51.02 123.44,51.19 123.44,51.35 124.02,51.92 124.02,52.08 123.86,52.25 123.7,52.25 123.12,51.67 122.96,51.67 122.52,52.11 122.36,52.11 121.73,51.49 121.57,51.49 121.41,51.65 121.41,51.81 122.03,52.43 122.03,52.6 121.87,52.76 121.71,52.76 121.08,52.13 120.92,52.13 120.76,52.29 120.76,52.46 121.39,53.08 121.39,53.24 121.22,53.41 121.06,53.41 120.44,52.78 120.28,52.78 120.11,52.94 120.11,53.1 120.74,53.73 120.74,53.89 120.58,54.05 120.42,54.05 119.79,53.43 119.63,53.43 119.47,53.59 119.47,53.75 120.09,54.38 120.09,54.54 119.93,54.7 119.77,54.7 119.14,54.07 118.98,54.07 118.82,54.23 118.82,54.4 119.45,55.02 119.45,55.18 119.07,55.56 117.38,55.56 117.26,55.45 117.26,54.5 117.15,54.39 116.92,54.39 116.81,54.5 116.81,55.45 116.69,55.56 116.46,55.56 116.35,55.45 116.35,54.5 116.24,54.39 116.01,54.39 115.89,54.5 115.89,55.45 115.78,55.56 112.82,55.56 104.22,64.17 104.22,68.53 104.65,68.97 104.65,71.21 v6(103.4,72.46)
  L10_SIG4 w0.109: v1(145.68,45.33) 145.68,45.89 144.83,46.74 144.83,47.17 145.19,47.53 145.19,47.78 145.64,48.24 145.64,50.85 146.43,51.64 146.43,52.43 146.18,52.68 146.18,52.97 146.29,53.08 146.6,53.08 146.71,53.19 146.71,53.41 146.6,53.52 146.29,53.52 146.18,53.63 146.18,53.84 146.29,53.95 146.6,53.95 146.71,54.06 146.71,54.28 146.6,54.39 146.29,54.39 146.18,54.5 146.18,54.97 145.33,55.82 145.33,57.29 145.64,57.61 145.64,60.53 v1(145.68,60.57)
  BOTTOM w0.173: v1(145.68,60.57) U91.R8 146.48,60.49 147.83,60.49 148.17,60.15 R768.2 ; U90.R8 v1(145.68,45.33)
DDR2_A7: length 125.9
  TOP w0.173: v1(146.4,50.85) 146.46,50.9 147.98,50.9 148.07,51 150.95,51 155.27,46.68 v5(155.27,41.99) ; U1.N20 v4(103.83,76.82)
  L3_SIG1 w0.109: v1(146.4,50.85) 146.47,50.85 148.44,52.81 148.44,61.92 148.55,62.02 148.81,62.02 148.92,62.13 148.92,62.35 148.81,62.46 148.55,62.46 148.44,62.57 148.44,62.79 148.55,62.9 148.81,62.9 148.92,63.01 148.92,63.23 148.81,63.33 148.55,63.33 148.44,63.44 148.44,64.05 v1(146.4,66.09) ; v5(155.27,41.99) v6(154.51,41.99) ; v4(103.83,76.82) v6(104.23,76.57)
  L4_SIG2 w0.114: v6(104.23,76.57) 104.64,76.15 104.64,75.34 104.6,75.29 104.6,71.33 105.03,70.89 105.03,68.41 104.57,67.95 104.57,65.23 113.41,56.39 113.41,54.28 119.63,48.06 127,48.06 132,43.06 147.83,43.06 147.94,43.17 147.94,44.04 148.06,44.15 148.28,44.15 148.4,44.04 148.4,43.17 148.51,43.06 148.74,43.06 148.86,43.17 148.86,44.04 148.97,44.15 149.2,44.15 149.31,44.04 149.31,43.17 149.43,43.06 149.66,43.06 149.77,43.17 149.77,44.04 149.88,44.15 150.11,44.15 150.23,44.04 150.23,43.17 150.34,43.06 150.57,43.06 150.68,43.17 150.68,44.04 150.8,44.15 151.03,44.15 151.14,44.04 151.14,43.17 151.26,43.06 151.48,43.06 151.6,43.17 151.6,44.04 151.71,44.15 151.94,44.15 152.06,44.04 152.06,43.17 152.17,43.06 152.4,43.06 152.51,43.17 152.51,44.09 152.63,44.2 152.86,44.2 152.97,44.09 152.97,43.17 153.09,43.06 153.44,43.06 v6(154.51,41.99)
  BOTTOM w0.102: 146.41,66.09 146.42,66.11 146.42,67.47
  BOTTOM w0.173: U91.R2 v1(146.4,66.09) 146.41,66.09 ; U90.R2 v1(146.4,50.85) ; 146.42,67.47 146.42,67.77 148.08,69.43 R767.2
DDR2_A8: length 129.3
  TOP w0.173: U1.P27 v4(103.03,71.22) ; v1(146.48,46.05) 147.37,45.16 147.37,43.97 148.13,43.21 v5(148.13,39.32)
  L3_SIG1 w0.109: v5(148.13,39.32) 148.13,39.32 142.32,39.32 139.95,41.69 139.52,41.69 139.41,41.58 139.41,40.07 139.3,39.96 139.08,39.96 138.97,40.07 138.97,41.58 138.86,41.69 138.64,41.69 138.53,41.58 138.53,40.07 138.42,39.96 138.21,39.96 138.1,40.07 138.1,41.58 137.99,41.69 137.77,41.69 137.66,41.58 137.66,40.07 137.55,39.96 137.33,39.96 137.22,40.07 137.22,41.58 137.11,41.69 136.9,41.69 136.79,41.58 136.79,40.07 136.68,39.96 136.46,39.96 136.35,40.07 136.35,41.58 136.24,41.69 136.02,41.69 135.91,41.58 135.91,40.07 135.8,39.96 135.58,39.96 135.48,40.07 135.48,41.58 135.37,41.69 135.15,41.69 135.04,41.58 135.04,40.07 134.93,39.96 134.71,39.96 134.6,40.07 134.6,41.58 134.49,41.69 134.27,41.69 134.16,41.58 134.16,40.07 134.06,39.96 133.84,39.96 133.73,40.07 133.73,41.58 133.62,41.69 133.4,41.69 133.29,41.58 133.29,40.07 133.18,39.96 132.96,39.96 132.85,40.07 132.85,41.58 132.74,41.69 132.53,41.69 132.42,41.58 132.42,40.07 132.31,39.96 132.09,39.96 131.98,40.07 131.98,41.58 131.87,41.69 131.65,41.69 131.54,41.58 131.54,40.07 131.43,39.96 131.22,39.96 131.11,40.07 131.11,41.58 131,41.69 130.48,41.69 130.1,42.07 129.95,42.07 129.49,41.61 129.34,41.61 129.18,41.77 129.18,41.92 129.64,42.38 129.64,42.53 129.48,42.68 129.33,42.68 128.87,42.23 128.72,42.23 128.56,42.38 128.56,42.54 129.02,42.99 129.02,43.15 128.86,43.3 128.71,43.3 128.25,42.85 128.1,42.85 127.95,43 127.95,43.16 128.4,43.61 128.4,43.77 128.25,43.92 128.09,43.92 127.64,43.47 127.48,43.47 127.33,43.62 127.33,43.77 127.78,44.23 127.78,44.38 107.82,64.34 107.49,64.34 106.98,64.85 106.98,68.36 104.13,71.22 v4(103.03,71.22)
  L10_SIG4 w0.109: v1(146.48,61.29) 148.44,59.33 148.44,58.62 148.33,58.51 148.17,58.51 148.06,58.4 148.06,58.18 148.17,58.07 148.33,58.07 148.44,57.96 148.44,55.3 149.5,54.23 149.5,50.42 146.41,47.32 146.41,46.12 v1(146.48,46.05)
  BOTTOM w0.173: U90.T8 v1(146.48,46.05) ; R770.2 147.08,61.17 U91.T8 v1(146.48,61.29)
DDR2_A9: length 130.6
  TOP w0.173: v5(153.8,38.61) 153.8,46.16 150.37,49.59 146.47,49.59 v1(146.04,49.15) ; v5(106.68,64.37) 104.88,66.17 104.88,66.4 103.83,67.44 103.83,68.31 103.32,68.82 103.32,69.72 103.83,70.24 103.83,71.22 U1.N27
  L3_SIG1 w0.109: v5(106.68,64.37) 107.16,63.89 107.65,63.89 122.96,48.57 122.96,45.45 128.43,39.98 128.59,39.98 128.94,40.33 129.09,40.33 129.25,40.17 129.25,40.02 128.89,39.67 128.89,39.51 129.05,39.36 129.2,39.36 129.56,39.71 129.71,39.71 129.87,39.56 129.87,39.4 129.51,39.05 129.51,38.89 129.67,38.74 129.82,38.74 130.18,39.09 130.33,39.09 130.48,38.94 130.48,38.78 130.13,38.43 130.13,38.28 131.47,36.94 131.96,36.94 132.07,37.05 132.07,37.89 132.18,38 132.37,38 132.51,37.87 132.51,37.05 132.62,36.94 132.84,36.94 132.95,37.05 132.95,37.87 133.06,37.98 133.27,37.98 133.38,37.87 133.38,37.05 133.49,36.94 133.71,36.94 133.82,37.05 133.82,37.87 133.93,37.98 134.15,37.98 134.26,37.87 134.26,37.05 134.37,36.94 134.58,36.94 134.69,37.05 134.69,37.87 134.8,37.98 135.02,37.98 135.13,37.87 135.13,37.05 135.24,36.94 135.46,36.94 135.57,37.05 135.57,37.87 135.68,37.98 135.89,37.98 136,37.87 136,37.05 136.11,36.94 136.33,36.94 136.44,37.05 136.44,37.87 136.55,37.98 136.77,37.98 136.88,37.87 136.88,37.05 136.99,36.94 137.21,36.94 137.31,37.05 137.31,37.87 137.42,37.98 137.64,37.98 137.75,37.87 137.75,37.05 137.86,36.94 138.08,36.94 138.19,37.05 138.19,37.87 138.3,37.98 138.52,37.98 138.63,37.87 138.63,37.05 138.73,36.94 138.95,36.94 139.06,37.05 139.06,37.87 139.17,37.98 139.39,37.98 139.5,37.87 139.5,37.05 139.61,36.94 139.85,36.94 141.07,38.15 143.15,38.15 143.84,38.84 146.13,38.84 146.35,38.61 v5(153.8,38.61)
  L4_SIG2 w0.114: v1(146.04,64.39) 147.02,64.39 147.98,63.43 147.98,51.14 146.04,49.2 v1(146.04,49.15)
  BOTTOM w0.173: U90.R3 v1(146.04,49.15) ; v1(146.04,64.39) U91.R3 146.41,65.29 148.34,65.29 149.29,66.25 R769.2
DDR2_A10: length 129.2
  TOP w0.173: v1(142.84,47.73) 142.84,46.76 142.47,46.39 142.47,44.1 142.35,43.98 142.35,42.49 142.62,42.22 v5(142.62,41.66) ; R771.2 147.83,62.18 147.22,62.79 146.66,62.79 146.42,62.56 145.81,62.56 145.52,62.84 145.03,62.84 144.73,62.54 144.15,62.54 143.71,62.97 v1(142.84,62.97) ; U1.N23 v4(103.83,74.42)
  L3_SIG1 w0.109: v6(141.43,41.51) 141.57,41.66 v5(142.62,41.66) ; v6(104.2,74.06) 104.2,74.06 103.84,74.42 v4(103.83,74.42)
  L4_SIG2 w0.114: v6(104.2,74.06) 103.81,73.67 103.81,71.58 104.81,70.59 104.81,68.79 104.06,68.04 104.06,64.93 112.9,56.09 112.9,54.13 113.39,53.65 113.39,53.49 113.04,53.14 113.04,52.98 113.2,52.82 113.36,52.82 113.71,53.16 113.87,53.16 114.03,53 114.03,52.84 113.69,52.49 113.69,52.33 113.85,52.17 114.01,52.17 114.36,52.52 114.52,52.52 114.68,52.35 114.68,52.19 114.33,51.85 114.33,51.69 114.5,51.52 114.66,51.52 115,51.87 115.17,51.87 115.33,51.71 115.33,51.55 114.98,51.2 114.98,51.04 115.14,50.88 115.3,50.88 115.65,51.22 115.81,51.22 115.97,51.06 115.97,50.9 115.63,50.55 115.63,50.39 115.79,50.23 115.95,50.23 116.3,50.58 116.46,50.58 116.62,50.41 116.62,50.25 116.27,49.91 116.27,49.75 116.44,49.58 116.6,49.58 116.94,49.93 117.11,49.93 117.27,49.77 117.27,49.61 116.92,49.26 116.92,49.1 117.08,48.94 117.24,48.94 117.59,49.28 117.75,49.28 117.91,49.12 117.91,48.96 117.57,48.61 117.57,48.45 117.73,48.29 117.89,48.29 118.24,48.64 118.4,48.64 118.56,48.47 118.56,48.31 118.21,47.97 118.21,47.81 118.38,47.64 118.54,47.64 118.88,47.99 119.05,47.99 119.46,47.58 126.85,47.58 127.04,47.39 127.04,47.23 126.77,46.96 126.77,46.79 126.93,46.63 127.09,46.63 127.36,46.9 127.52,46.9 127.69,46.74 127.69,46.58 127.41,46.31 127.41,46.15 127.58,45.99 127.74,45.99 128.01,46.26 128.17,46.26 128.4,46.02 128.4,45.86 127.94,45.4 127.94,45.24 128.1,45.08 128.27,45.08 128.73,45.54 128.89,45.54 129.42,45.01 129.42,44.85 129.02,44.45 129.02,44.29 129.18,44.13 129.34,44.13 129.74,44.52 129.9,44.52 130.06,44.36 130.06,44.2 129.67,43.8 129.67,43.64 129.83,43.48 129.99,43.48 130.39,43.88 130.55,43.88 130.71,43.72 130.71,43.55 130.31,43.16 130.31,42.99 130.48,42.83 130.64,42.83 131.03,43.23 131.2,43.23 131.95,42.47 132.23,42.47 132.34,42.36 132.34,41.62 132.46,41.51 132.68,41.51 132.8,41.62 132.8,42.36 132.91,42.47 133.14,42.47 133.26,42.36 133.26,41.62 133.37,41.51 133.6,41.51 133.71,41.62 133.71,42.36 133.83,42.47 134.06,42.47 134.17,42.36 134.17,41.62 134.28,41.51 134.51,41.51 134.63,41.62 134.63,42.36 134.74,42.47 134.97,42.47 135.09,42.36 135.09,41.62 135.2,41.51 135.43,41.51 135.54,41.62 135.54,42.36 135.66,42.47 135.89,42.47 136,42.36 136,41.62 136.11,41.51 136.34,41.51 136.46,41.62 136.46,42.36 136.57,42.47 136.8,42.47 136.91,42.36 136.91,41.62 137.03,41.51 137.26,41.51 137.37,41.62 137.37,42.36 137.49,42.47 137.71,42.47 137.83,42.36 137.83,41.62 137.94,41.51 138.17,41.51 138.29,41.62 138.29,42.36 138.4,42.47 138.63,42.47 138.74,42.36 138.74,41.62 138.86,41.51 139.09,41.51 139.2,41.62 139.2,42.36 139.31,42.47 139.54,42.47 139.66,42.36 139.66,41.62 139.77,41.51 140,41.51 140.11,41.62 140.11,42.36 140.23,42.47 140.78,42.47 141.43,41.83 v6(141.43,41.51)
  L10_SIG4 w0.109: v1(142.84,62.97) 142.84,63.33 142.71,63.47 142.52,63.47 142.28,63.23 142.28,62.88 142.61,62.55 142.61,61.51 142.17,61.07 142.17,60.2 142.44,59.92 142.44,59.16 141.97,58.69 141.97,56.1 141.49,55.61 141.49,54.04 142.9,52.63 142.9,50.55 142.46,50.11 142.46,49.02 142.84,48.63 v1(142.84,47.73)
  BOTTOM w0.173: U90.L7 v1(142.84,47.73) ; U91.L7 v1(142.84,62.97)
DDR2_A11: length 125.8
  TOP w0.173: v1(146.04,47.73) 147.9,47.73 150.96,44.68 v5(150.96,41.46) ; U1.P26 v4(103.03,72.02)
  L3_SIG1 w0.109: v6(103.4,71.66) 103.39,71.66 103.04,72.02 v4(103.03,72.02) ; v5(150.96,41.46) v6(150.27,41.46)
  L4_SIG2 w0.114: v6(150.27,41.46) 149.58,41.46 149.12,41.91 148.7,41.91 148.59,42.03 148.59,42.33 148.47,42.45 148.25,42.45 148.13,42.33 148.13,42.03 148.02,41.91 147.79,41.91 147.67,42.03 147.67,42.36 147.56,42.47 147.33,42.47 147.22,42.36 147.22,42.03 147.1,41.91 146.87,41.91 146.76,42.03 146.76,42.36 146.65,42.47 146.42,42.47 146.3,42.36 146.3,42.03 146.19,41.91 145.18,41.91 145.07,42.03 145.07,42.36 144.95,42.47 144.73,42.47 144.61,42.36 144.61,42.03 144.5,41.91 144.27,41.91 144.15,42.03 144.15,42.36 144.04,42.47 143.81,42.47 143.7,42.36 143.7,42.03 143.58,41.91 143.35,41.91 143.24,42.03 143.24,42.36 143.13,42.47 142.9,42.47 142.78,42.36 142.78,42.03 142.67,41.91 142.49,41.91 141.63,41.05 130.92,41.05 130.37,41.6 130.2,41.6 129.69,41.09 129.53,41.09 129.37,41.25 129.37,41.41 129.88,41.92 129.88,42.08 129.72,42.24 129.56,42.24 129.05,41.73 128.88,41.73 128.72,41.89 128.72,42.06 129.23,42.57 129.23,42.73 129.07,42.89 128.91,42.89 128.4,42.38 128.24,42.38 128.08,42.54 128.08,42.7 128.59,43.21 128.59,43.38 128.43,43.54 128.26,43.54 127.75,43.03 127.59,43.03 127.43,43.19 127.43,43.35 127.94,43.86 127.94,44.02 127.78,44.18 127.62,44.18 127.11,43.67 126.94,43.67 126.78,43.83 126.78,44 127.29,44.51 127.29,44.67 127.13,44.83 126.97,44.83 126.46,44.32 126.3,44.32 126.14,44.48 126.14,44.64 126.65,45.15 126.65,45.32 126.49,45.48 126.32,45.48 125.81,44.97 125.65,44.97 125.49,45.13 125.49,45.29 126,45.8 126,45.96 125.84,46.12 125.68,46.12 125.17,45.61 125,45.61 124.84,45.77 124.84,45.94 125.35,46.45 125.35,46.61 124.84,47.12 124.59,47.12 124.48,47.01 124.48,46.55 124.37,46.44 124.14,46.44 124.02,46.55 124.02,47.01 123.91,47.12 123.68,47.12 123.57,47.01 123.57,46.55 123.45,46.44 123.22,46.44 123.11,46.55 123.11,47.01 122.99,47.12 122.77,47.12 122.65,47.01 122.65,46.55 122.54,46.44 122.31,46.44 122.19,46.55 122.19,47.01 122.08,47.12 121.85,47.12 121.74,47.01 121.74,46.55 121.62,46.44 121.39,46.44 121.28,46.55 121.28,47.01 121.17,47.12 118.26,47.12 112.42,52.96 112.42,55.94 103.61,64.75 103.61,68.25 104.52,69.17 104.52,69.86 103.4,70.98 v6(103.4,71.66)
  L10_SIG4 w0.109: v1(146.04,47.73) 146.46,48.15 146.46,48.6 146.68,48.83 147.14,48.83 148.72,50.41 148.72,54.16 147.65,55.22 147.65,56.31 147.54,56.42 147.35,56.42 147.24,56.53 147.24,56.75 147.35,56.86 147.54,56.86 147.65,56.97 147.65,59.55 146.04,61.15 v1(146.04,62.97)
  BOTTOM w0.173: R773.2 148.17,63.2 147.66,62.69 146.32,62.69 v1(146.04,62.97) U91.R7 ; U90.R7 v1(146.04,47.73)
DDR2_A12: length 134.2
  TOP w0.102: 146.43,44.84 146.43,44.02
  TOP w0.173: v5(106.35,63.42) 106.35,63.42 104.15,65.62 104.15,66.16 103.43,66.88 103.43,68.22 102.95,68.71 102.95,69.83 103.43,70.32 U1.N28 ; 146.43,44.02 146.43,43.77 147.43,42.77 147.43,37.12 v5(147.42,37.12) ; 146.43,44.84 146.43,45.19 144.83,46.8 144.83,47.35 v1(144.44,47.73) ; R772.2 148.59,63.2 147.69,64.1 146.44,64.1 145.59,63.25 144.72,63.25 v1(144.44,62.97)
  L3_SIG1 w0.109: v5(147.42,37.12) 146.53,36.23 145.79,36.23 145.69,36.12 145.69,35.32 145.58,35.21 145.36,35.21 145.25,35.32 145.25,36.12 145.14,36.23 144.92,36.23 144.81,36.12 144.81,35.32 144.7,35.21 144.48,35.21 144.37,35.32 144.37,36.12 144.27,36.23 144.05,36.23 143.94,36.12 143.94,35.32 143.83,35.21 143.61,35.21 143.5,35.32 143.5,36.12 143.39,36.23 143.17,36.23 143.06,36.12 143.06,35.32 142.95,35.21 142.74,35.21 142.63,35.32 142.63,36.12 142.52,36.23 142.3,36.23 142.19,36.12 142.19,35.32 142.08,35.21 141.86,35.21 141.75,35.32 141.75,36.12 141.64,36.23 141.43,36.23 141.32,36.12 141.32,35.32 141.21,35.21 140.99,35.21 140.88,35.32 140.88,36.12 140.77,36.23 140.55,36.23 140.44,36.12 140.44,35.32 140.33,35.21 140.12,35.21 140.01,35.32 140.01,36.12 139.9,36.23 139.68,36.23 139.57,36.12 139.57,35.32 139.46,35.21 139.24,35.21 139.13,35.32 139.13,36.12 139.02,36.23 138.8,36.23 138.7,36.12 138.7,35.32 138.59,35.21 138.37,35.21 138.26,35.32 138.26,36.12 138.15,36.23 137.93,36.23 137.82,36.12 137.82,35.32 137.71,35.21 137.49,35.21 137.38,35.32 137.38,36.12 137.28,36.23 137.06,36.23 136.95,36.12 136.95,35.32 136.84,35.21 136.62,35.21 136.51,35.32 136.51,36.12 136.4,36.23 136.18,36.23 136.07,36.12 136.07,35.32 135.96,35.21 135.75,35.21 135.64,35.32 135.64,36.12 135.53,36.23 135.31,36.23 135.2,36.12 135.2,35.32 135.09,35.21 134.87,35.21 134.76,35.32 134.76,36.12 134.65,36.23 134.44,36.23 134.33,36.12 134.33,35.32 134.22,35.21 134,35.21 133.89,35.32 133.89,36.12 133.78,36.23 133.56,36.23 133.45,36.12 133.45,35.32 133.34,35.21 133.12,35.21 133.02,35.32 133.02,36.12 132.91,36.23 132.69,36.23 132.58,36.12 132.58,35.32 132.47,35.21 132.25,35.21 132.14,35.32 132.14,36.12 132.03,36.23 127.48,36.23 122.38,41.33 122.38,48.52 107.48,63.42 v5(106.35,63.42)
  L10_SIG4 w0.109: v1(144.44,47.73) 144.44,48.59 144.83,48.98 144.83,49.46 144.4,49.89 144.4,50.62 144.5,50.72 144.5,51.13 144.83,51.46 144.83,52.1 144.06,52.87 144.06,54.22 143.38,54.9 143.38,56.19 143.49,56.3 143.83,56.3 143.94,56.4 143.94,56.62 143.83,56.73 143.49,56.73 143.38,56.84 143.38,57.06 143.49,57.17 143.83,57.17 143.94,57.28 143.94,57.5 143.83,57.61 143.49,57.61 143.38,57.72 143.38,58 144.04,58.66 144.04,59.85 144.56,60.37 144.56,60.62 144.42,60.76 144.42,62.95 v1(144.44,62.97)
  BOTTOM w0.173: U91.N7 v1(144.44,62.97) ; U90.N7 v1(144.44,47.73)
DDR2_A13: length 124.9
  TOP w0.173: U1.T22 v4(100.64,75.22) ; v1(146.84,48.44) 146.88,48.48 149.15,48.48 152.37,45.26 v5(152.37,38.05)
  L3_SIG1 w0.109: v4(100.64,75.22) 100.99,74.86 v6(101,74.86) ; v5(152.37,38.05) v6(151,38.05)
  L4_SIG2 w0.114: v6(151,38.05) 150.67,37.72 143.48,37.72 143,38.21 140.59,38.21 140.13,37.75 129.09,37.75 126.48,40.36 124.51,40.36 124.16,40.72 120.78,40.72 120.34,41.16 120.18,41.16 119.64,40.62 119.48,40.62 119.33,40.77 119.33,40.96 119.85,41.48 119.85,41.64 119.69,41.81 119.53,41.81 118.9,41.18 118.74,41.18 118.58,41.34 118.58,41.5 119.21,42.13 119.21,42.29 119.05,42.45 118.88,42.45 118.26,41.83 118.1,41.83 117.93,41.99 117.93,42.15 118.56,42.78 118.56,42.94 118.4,43.1 118.24,43.1 117.61,42.47 117.45,42.47 117.29,42.64 117.29,42.8 117.91,43.42 117.91,43.58 117.53,43.97 114.55,43.97 108.48,50.04 108.48,52.38 100.74,60.13 100.74,68.84 101.41,69.51 101.41,74.45 v6(101,74.86) ; v1(146.84,48.44) 146.06,48.44 145.64,48.85 145.64,53.17 146.41,53.93 146.69,53.93 147.52,54.77 147.52,63 v1(146.84,63.68)
  BOTTOM w0.173: U91.T3 v1(146.84,63.68) 147.89,64.72 148.72,64.72 149.23,65.23 R775.2 ; U90.T3 v1(146.84,48.44)
DDR2_A14: length 124
  TOP w0.173: v5(149.58,40.11) 149.58,43.62 148.7,44.49 148.7,45.13 v1(146.84,47) ; U1.R22 v4(101.44,75.22)
  L3_SIG1 w0.109: v6(101.8,74.86) 101.79,74.86 v4(101.44,75.22) ; v5(149.58,40.11) v6(149,40.11)
  L4_SIG2 w0.114: v6(101.8,74.86) 101.83,74.86 102.46,74.22 102.46,69.62 102.46,69.06 102.21,68.81 102.21,63.02 110.72,54.51 110.72,51.08 110.97,50.83 110.97,50.67 110.61,50.31 110.61,50.15 110.77,49.99 110.93,49.99 111.29,50.35 111.46,50.35 111.62,50.19 111.62,50.02 111.26,49.67 111.26,49.5 111.42,49.34 111.58,49.34 111.94,49.7 112.1,49.7 112.26,49.54 112.26,49.38 111.9,49.02 111.9,48.86 112.07,48.7 112.23,48.7 112.59,49.05 112.75,49.05 112.91,48.89 112.91,48.73 112.55,48.37 112.55,48.21 112.71,48.05 112.87,48.05 113.23,48.41 113.4,48.41 113.56,48.25 113.56,48.08 113.2,47.73 113.2,47.56 113.36,47.4 113.52,47.4 113.88,47.76 114.04,47.76 114.2,47.6 114.2,47.44 113.84,47.08 113.84,46.92 114.01,46.76 114.17,46.76 114.53,47.11 114.69,47.11 114.85,46.95 114.85,46.79 114.49,46.43 114.49,46.27 114.65,46.11 114.81,46.11 115.17,46.47 115.34,46.47 115.5,46.31 115.5,46.14 115.14,45.79 115.14,45.62 115.3,45.46 115.46,45.46 115.82,45.82 115.98,45.82 116.31,45.5 120.37,45.5 122.5,43.36 125.36,43.36 129.1,39.63 131.9,39.63 132.01,39.51 132.01,39.11 132.13,38.99 132.36,38.99 132.47,39.11 132.47,39.51 132.59,39.63 132.81,39.63 132.93,39.51 132.93,39.11 133.04,38.99 133.27,38.99 133.39,39.11 133.39,39.51 133.5,39.63 133.73,39.63 133.84,39.51 133.84,39.11 133.96,38.99 134.19,38.99 134.3,39.11 134.3,39.51 134.42,39.63 134.64,39.63 134.76,39.51 134.76,39.11 134.87,38.99 135.1,38.99 135.22,39.11 135.22,39.51 135.33,39.63 135.56,39.63 135.67,39.51 135.67,39.11 135.79,38.99 136.02,38.99 136.13,39.11 136.13,39.51 136.24,39.63 136.47,39.63 136.59,39.51 136.59,39.11 136.7,38.99 136.93,38.99 137.04,39.11 137.04,39.51 137.16,39.63 137.39,39.63 137.5,39.51 137.5,39.11 137.62,38.99 137.84,38.99 137.96,39.11 137.96,39.51 138.07,39.63 138.3,39.63 138.42,39.51 138.42,39.11 138.53,38.99 138.76,38.99 138.87,39.11 138.87,39.51 138.99,39.63 140.42,39.63 140.53,39.51 140.53,39.26 140.65,39.15 140.88,39.15 140.99,39.26 140.99,39.51 141.11,39.63 141.33,39.63 141.45,39.51 141.45,39.26 141.56,39.15 141.79,39.15 141.91,39.26 141.91,39.51 142.02,39.63 142.25,39.63 142.36,39.51 142.36,39.26 142.48,39.15 142.71,39.15 142.82,39.26 142.82,39.51 142.93,39.63 143.41,39.63 143.84,39.2 148.08,39.2 v6(149,40.11)
  L10_SIG4 w0.109: v1(146.84,47) 147.85,47 149.99,49.13 149.99,59.09 v1(146.84,62.24)
  BOTTOM w0.173: U90.T7 v1(146.84,47) ; v1(146.84,62.24) U91.T7 147.96,61.73 148.41,62.18 R774.2
DDR2_A15: length 126.9
  TOP w0.173: v5(144.91,36.98) 144.87,36.98 144.09,37.75 144.09,38.79 143.3,39.58 143.3,40.21 143.9,40.8 143.9,42.21 142.99,43.12 142.99,45.11 143.7,45.82 143.7,46.22 143.64,46.28 v1(143.64,47) ; U1.U22 v4(99.85,76)
  L3_SIG1 w0.109: v4(99.85,76) 99.93,76 v6(100.23,75.71) ; v5(144.91,36.98) 144.17,36.98 v6(144.02,36.83)
  L4_SIG2 w0.114: v6(144.02,36.83) 143.89,36.83 143.2,36.14 142.93,36.14 142.82,36.03 142.82,35.58 142.71,35.47 142.48,35.47 142.36,35.58 142.36,36.03 142.25,36.14 142.02,36.14 141.9,36.03 141.9,35.53 141.82,35.45 141.56,35.45 141.45,35.56 141.45,36.03 141.33,36.14 141.1,36.14 140.99,36.03 140.99,35.47 140.88,35.36 140.65,35.36 140.53,35.47 140.53,36.03 140.42,36.14 140.19,36.14 140.08,36.03 140.08,35.47 139.96,35.36 139.73,35.36 139.62,35.47 139.62,36.03 139.5,36.14 139.28,36.14 139.16,36.03 139.16,35.47 139.05,35.36 138.82,35.36 138.7,35.47 138.7,36.03 138.59,36.14 138.36,36.14 138.25,36.03 138.25,35.47 138.13,35.36 137.9,35.36 137.79,35.47 137.79,36.03 137.68,36.14 137.45,36.14 137.33,36.03 137.33,35.47 137.22,35.36 136.99,35.36 136.88,35.47 136.88,36.03 136.76,36.14 136.53,36.14 136.42,36.03 136.42,35.47 136.3,35.36 136.08,35.36 135.96,35.47 135.96,36.03 135.85,36.14 135.62,36.14 135.5,36.03 135.5,35.47 135.39,35.36 135.16,35.36 135.05,35.47 135.05,36.03 134.93,36.14 134.7,36.14 134.59,36.03 134.59,35.42 134.48,35.31 134.25,35.31 134.13,35.42 134.13,36.03 134.02,36.14 133.79,36.14 133.68,36.03 133.68,35.66 133.55,35.53 125.5,35.53 122.05,38.99 115.42,38.99 106.81,47.6 106.81,50 99.16,57.64 99.16,66.69 99.04,66.81 99.04,73.14 99.23,73.33 99.23,74.59 100.23,75.59 v6(100.23,75.71)
  L10_SIG4 w0.109: v1(143.64,62.24) 143.62,62.21 143.62,60.75 143.51,60.64 143.34,60.64 143.2,60.77 143.2,61.11 143.1,61.21 142.93,61.21 142.8,61.08 142.8,58.83 142.49,58.52 142.49,55.99 141.93,55.43 141.93,54.17 143.22,52.88 143.22,50.73 143.67,50.29 143.67,49.45 143.26,49.04 143.26,47.88 143.64,47.49 v1(143.64,47)
  BOTTOM w0.173: U90.M7 v1(143.64,47) ; R807.2 143.23,57.9 143.23,61.31 U91.M7 v1(143.64,62.24)
DDR2_BA0: length 127.4
  TOP w0.173: v5(153.08,37.27) 153.08,45.56 149.55,49.08 146.69,49.08 146.34,48.74 145.87,48.74 144.97,49.64 144.6,49.64 144.11,50.13 v1(143.28,50.13) ; U1.U23 99.96,75.09 99.96,75.13 v4(99.92,75.13)
  L3_SIG1 w0.109: v1(143.28,50.13) 143.28,51.03 143,51.31 143,52.51 143.36,52.86 143.36,53.28 143.25,53.39 142.98,53.39 142.88,53.5 142.88,53.72 142.98,53.83 143.25,53.83 143.36,53.94 143.36,54.15 143.25,54.26 142.98,54.26 142.88,54.37 142.88,54.59 142.98,54.7 143.25,54.7 143.36,54.81 143.36,55.03 143.25,55.14 142.98,55.14 142.88,55.25 142.88,55.47 142.98,55.57 143.25,55.57 143.36,55.68 143.36,56.19 143.64,56.47 143.64,58.81 144.03,59.2 144.03,59.86 143.65,60.24 143.65,61.09 143.26,61.49 143.26,62.47 143.46,62.67 143.46,63.23 143.26,63.43 143.26,65.34 v1(143.28,65.37) ; v4(99.92,75.13) 100.28,74.77 v6(100.29,74.77) ; v5(153.08,37.27) v6(152.45,37.27)
  L4_SIG2 w0.114: v6(152.45,37.27) 144.21,37.27 144.2,37.27 143.37,37.27 142.77,36.68 126.16,36.68 123.5,39.35 116,39.35 107.39,47.96 107.39,50.13 99.61,57.91 99.61,66.69 99.62,66.7 99.62,74.1 v6(100.29,74.77)
  BOTTOM w0.173: U90.M2 v1(143.28,50.13) ; U91.M2 v1(143.28,65.37) 143.28,65.37 143.23,65.42 143.23,67.87 145.03,69.68 R777.2
DDR2_BA1: length 126.9
  TOP w0.102: 144.06,44.66 144.06,43.9
  TOP w0.173: U1.U27 v4(100.66,72.04) ; 144.06,44.66 144.06,45.31 v1(144.08,45.33) ; v5(145.31,39.78) 145.31,42.07 144.06,43.32 144.06,43.9
  L3_SIG1 w0.109: v5(145.31,39.78) v6(144.65,39.78) ; v6(101.02,71.68) v4(100.66,72.04)
  L9_SIG3 w0.114: v6(101.02,71.68) 101.06,71.64 101.06,58.51 101.28,58.29 101.44,58.29 101.96,58.81 102.13,58.81 102.29,58.65 102.29,58.49 101.76,57.97 101.76,57.8 101.93,57.64 102.09,57.64 102.61,58.17 102.77,58.17 102.93,58 102.93,57.84 102.41,57.32 102.41,57.16 102.57,57 102.73,57 103.26,57.52 103.42,57.52 103.58,57.36 103.58,57.2 103.06,56.67 103.06,56.51 103.22,56.35 103.38,56.35 103.9,56.87 104.07,56.87 104.23,56.71 104.23,56.55 103.7,56.03 103.7,55.86 103.87,55.7 104.03,55.7 104.55,56.23 104.71,56.23 104.87,56.06 104.87,55.9 104.35,55.38 104.35,55.22 104.51,55.06 104.67,55.06 105.2,55.58 105.36,55.58 105.52,55.42 105.52,55.26 105,54.73 105,54.57 105.16,54.41 105.32,54.41 105.84,54.93 106.01,54.93 106.17,54.77 106.17,54.61 105.64,54.09 105.64,53.92 105.81,53.76 105.97,53.76 106.49,54.29 106.65,54.29 106.81,54.12 106.81,53.96 106.29,53.44 106.29,53.28 106.45,53.12 106.61,53.12 107.14,53.64 107.3,53.64 107.46,53.48 107.46,53.32 106.94,52.79 106.94,52.63 107.1,52.47 107.26,52.47 107.78,52.99 107.95,52.99 108.11,52.83 108.11,52.67 107.58,52.15 107.58,51.98 107.75,51.82 107.91,51.82 108.43,52.35 108.59,52.35 108.75,52.18 108.75,52.02 108.23,51.5 108.23,51.34 108.39,51.18 108.55,51.18 109.08,51.7 109.24,51.7 109.4,51.54 109.4,51.38 108.88,50.85 108.88,50.69 109.04,50.53 109.2,50.53 109.72,51.05 109.89,51.05 110.05,50.89 110.05,50.73 109.52,50.21 109.52,50.04 109.69,49.88 109.85,49.88 110.37,50.41 110.53,50.41 110.69,50.24 110.69,50.08 110.17,49.56 110.17,49.4 110.33,49.24 110.49,49.24 110.94,49.68 111.1,49.68 111.26,49.52 111.26,49.36 110.82,48.91 110.82,48.75 111.27,48.3 122.56,48.3 125.09,45.76 125.09,42.83 128.3,39.63 140.21,39.63 140.79,39.04 143.92,39.04 v6(144.65,39.78)
  L10_SIG4 w0.109: v1(144.08,45.33) 144.06,45.35 144.06,50.33 143.69,50.69 143.69,51.3 144.03,51.64 144.03,52.37 143.56,52.84 143.56,53.31 142.82,54.05 142.48,54.05 142.37,54.16 142.37,54.37 142.48,54.48 142.82,54.48 142.93,54.59 142.93,54.81 142.82,54.92 142.48,54.92 142.37,55.03 142.37,55.25 142.48,55.36 142.82,55.36 142.93,55.47 142.93,58.31 143.24,58.62 143.24,59.79 144.02,60.57 v1(144.08,60.57)
  BOTTOM w0.102: 144.4,58.88 144.06,59.22 144.06,60.55 v1(144.08,60.57)
  BOTTOM w0.173: U91.N8 v1(144.08,60.57) ; 144.4,58.88 147.83,58.88 148.08,59.14 R776.2 ; U90.N8 v1(144.08,45.33)
DDR2_BA2: length 127.8
  TOP w0.102: 143.99,45.77 143.26,45.05 143.26,43.68
  TOP w0.173: 143.26,43.68 143.47,43.47 143.47,43.22 144.6,42.09 144.6,39.55 145.03,39.12 v5(145.03,38.21) ; R779.2 148.97,64.22 148.34,64.85 145.54,64.85 144.37,63.68 v1(143.64,63.68) ; U1.U26 v4(99.84,72.02) ; 143.99,45.77 144.17,45.95 144.17,47.26 143.64,47.79 v1(143.64,48.44)
  L3_SIG1 w0.109: v5(145.03,38.21) v6(143.94,38.21) ; v1(143.64,48.44) 143.69,48.49 143.69,51.08 143.26,51.52 143.26,52.13 144.45,53.32 144.45,53.98 144.34,54.09 144.23,54.09 144.12,54.2 144.12,54.42 144.23,54.53 144.34,54.53 144.45,54.64 144.45,56.76 144.34,56.87 144.1,56.87 143.99,56.98 143.99,57.19 144.1,57.3 144.34,57.3 144.45,57.41 144.45,57.63 144.34,57.74 144.1,57.74 143.99,57.85 143.99,58.07 144.1,58.18 144.34,58.18 144.45,58.29 144.45,58.79 144.83,59.17 144.83,60.41 144.39,60.85 144.39,61.69 144.17,61.9 144.17,62.25 143.69,62.74 143.69,63.64 v1(143.64,63.68) ; v6(100.2,71.66) 100.19,71.66 99.84,72.01 v4(99.84,72.02)
  L9_SIG3 w0.114: v6(100.2,71.66) 99.67,71.12 99.67,58.01 111.52,46.16 120.35,46.16 122.55,43.96 122.55,40.05 126.03,36.58 127.07,36.58 127.66,36 128.03,36 128.61,36.58 128.84,36.58 128.96,36.47 128.96,35.91 129.07,35.79 129.3,35.79 129.41,35.91 129.41,36.47 129.53,36.58 129.76,36.58 129.87,36.47 129.87,35.91 129.99,35.79 130.21,35.79 130.33,35.91 130.33,36.47 130.44,36.58 130.67,36.58 130.79,36.47 130.79,35.91 130.9,35.79 131.13,35.79 131.24,35.91 131.24,36.47 131.36,36.58 131.59,36.58 131.7,36.47 131.7,35.91 131.82,35.79 132.04,35.79 132.16,35.91 132.16,36.47 132.27,36.58 132.5,36.58 132.62,36.47 132.62,35.91 132.73,35.79 132.96,35.79 133.07,35.91 133.07,36.47 133.19,36.58 133.42,36.58 133.53,36.47 133.53,35.91 133.64,35.79 133.87,35.79 133.99,35.91 133.99,36.47 134.1,36.58 134.33,36.58 134.44,36.47 134.44,35.91 134.56,35.79 134.79,35.79 134.9,35.91 134.9,36.47 135.02,36.58 135.24,36.58 135.36,36.47 135.36,35.91 135.47,35.79 135.7,35.79 135.82,35.91 135.82,36.47 135.93,36.58 136.16,36.58 136.27,36.47 136.27,35.93 136.39,35.82 136.62,35.82 136.73,35.93 136.73,36.47 136.84,36.58 137.07,36.58 137.19,36.47 137.19,35.96 137.3,35.84 137.53,35.84 137.64,35.96 137.64,36.47 137.76,36.58 137.99,36.58 138.1,36.47 138.1,35.96 138.22,35.84 138.44,35.84 138.56,35.96 138.56,36.47 138.67,36.58 138.9,36.58 139.02,36.47 139.02,35.96 139.13,35.84 139.36,35.84 139.47,35.96 139.47,36.28 141.41,38.21 143.94,38.21 v6(143.94,38.21)
  BOTTOM w0.173: U91.M3 v1(143.64,63.68) ; U90.M3 v1(143.64,48.44)
DDR2_CASN: length 129.9
  TOP w0.173: v1(142.04,48.44) 142.04,47.59 142.34,47.29 142.34,46.82 142.11,46.59 142.11,45.75 141.63,45.26 141.63,42.24 141.05,41.66 v5(141.05,38.69) ; U1.U28 100.24,71.03 100.06,71.2 v4(100,71.2) ; R759.2 147.96,66.25 147.38,65.67 146.23,65.67 146.12,65.78 144.57,65.78 143.26,64.47 143.26,64.25 142.7,63.68 v1(142.04,63.68)
  L3_SIG1 w0.109: v6(100.37,70.84) 100.36,70.84 100,71.2 v4(100,71.2) ; v5(141.05,38.69) v6(139.09,38.69) ; v1(142.04,48.44) 142.04,49.95 142.09,49.99 142.09,51.11 141.55,51.64 141.55,52.18 140.49,53.24 140.49,56.67 140.16,57 140.16,57.4 140.05,57.51 139.78,57.51 139.67,57.62 139.67,57.83 139.78,57.94 140.05,57.94 140.16,58.05 140.16,58.27 140.05,58.38 139.78,58.38 139.67,58.49 139.67,58.71 139.78,58.82 140.05,58.82 140.16,58.93 140.16,59.24 140.49,59.57 140.49,62.13 v1(142.04,63.68)
  L9_SIG3 w0.114: v6(100.37,70.84) 100.12,70.59 100.12,58.19 111.67,46.64 121.21,46.64 123.72,44.12 123.72,43.1 123.61,42.98 123.36,42.98 123.24,42.87 123.24,42.64 123.36,42.53 123.61,42.53 123.72,42.41 123.72,42.18 123.61,42.07 123.36,42.07 123.24,41.95 123.24,41.73 123.36,41.61 123.61,41.61 123.72,41.5 123.72,41.27 123.61,41.15 123.36,41.15 123.24,41.04 123.24,40.81 123.36,40.7 123.61,40.7 123.72,40.58 123.72,39.71 123.96,39.47 124.12,39.47 124.62,39.96 124.78,39.96 124.95,39.8 124.95,39.64 124.45,39.14 124.45,38.98 124.61,38.82 124.77,38.82 125.27,39.32 125.43,39.32 125.59,39.16 125.59,38.99 125.09,38.5 125.09,38.33 126.4,37.03 126.81,37.03 126.92,37.14 126.92,37.81 127.04,37.93 127.26,37.93 127.38,37.81 127.38,37.14 127.49,37.03 127.72,37.03 127.84,37.14 127.84,37.81 127.95,37.93 128.18,37.93 128.29,37.81 128.29,37.14 128.41,37.03 128.64,37.03 128.75,37.14 128.75,37.81 128.86,37.93 129.09,37.93 129.21,37.81 129.21,37.14 129.32,37.03 129.55,37.03 129.66,37.14 129.66,37.81 129.78,37.93 130.01,37.93 130.12,37.81 130.12,37.14 130.24,37.03 130.46,37.03 130.58,37.14 130.58,37.81 130.69,37.93 130.92,37.93 131.04,37.81 131.04,37.14 131.15,37.03 131.38,37.03 131.49,37.14 131.49,37.81 131.61,37.93 131.84,37.93 131.95,37.81 131.95,37.14 132.06,37.03 132.29,37.03 132.41,37.14 132.41,37.81 132.52,37.93 132.75,37.93 132.86,37.81 132.86,37.14 132.98,37.03 133.21,37.03 133.32,37.14 133.32,37.81 133.44,37.93 133.66,37.93 133.78,37.81 133.78,37.14 133.89,37.03 134.12,37.03 134.24,37.14 134.24,37.81 134.35,37.93 134.58,37.93 134.69,37.81 134.69,37.14 134.81,37.03 135.04,37.03 135.15,37.14 135.15,37.81 135.26,37.93 135.49,37.93 135.61,37.81 135.61,37.14 135.72,37.03 135.95,37.03 136.06,37.14 136.06,37.81 136.18,37.93 136.41,37.93 136.52,37.81 136.52,37.14 136.64,37.03 137.43,37.03 v6(139.09,38.69)
  BOTTOM w0.173: U91.K3 v1(142.04,63.68) ; U90.K3 v1(142.04,48.44)
DDR2_CKE: length 129.2
  TOP w0.173: v5(142.04,37.55) 141.88,37.7 141.88,41.8 142.04,41.95 v1(142.04,44.38) ; v4(99.95,74.35) 99.98,74.35 99.98,74.31 100.24,74.06 U1.U24 ; R756.2 148.72,59.14 147.6,60.25 145.95,60.25 145.74,60.04 142.46,60.04 v1(142.04,59.62)
  L3_SIG1 w0.109: v4(99.95,74.35) 100.31,73.99 v6(100.32,73.99) ; v5(142.04,37.55) v6(141.38,37.55)
  L4_SIG2 w0.114: v6(141.38,37.55) 141,37.17 127.73,37.17 127.55,37.34 127.55,37.63 127.44,37.75 127.21,37.75 127.1,37.63 127.1,37.35 126.94,37.19 126.32,37.19 123.67,39.83 116.2,39.83 114.81,41.23 114.81,42.63 108.04,49.4 108.04,50.49 107.23,51.29 107.23,51.46 107.92,52.15 107.92,52.31 107.76,52.47 107.6,52.47 106.91,51.78 106.75,51.78 106.59,51.94 106.59,52.1 107.27,52.79 107.27,52.95 107.11,53.12 106.95,53.12 106.26,52.43 106.1,52.43 105.94,52.59 105.94,52.75 106.63,53.44 106.63,53.6 106.47,53.76 106.3,53.76 105.62,53.07 105.45,53.07 105.29,53.23 105.29,53.4 105.98,54.09 105.98,54.25 105.82,54.41 105.66,54.41 104.97,53.72 104.81,53.72 104.65,53.88 104.65,54.04 105.33,54.73 105.33,54.89 105.17,55.06 105.01,55.06 104.32,54.37 104.16,54.37 104,54.53 104,54.69 104.69,55.38 104.69,55.54 104.53,55.7 104.36,55.7 103.68,55.01 103.51,55.01 103.35,55.17 103.35,55.34 104.04,56.03 104.04,56.19 103.88,56.35 103.72,56.35 103.03,55.66 102.87,55.66 102.71,55.82 102.71,55.98 103.39,56.67 103.39,56.83 103.23,57 103.07,57 102.38,56.31 102.22,56.31 102.06,56.47 102.06,56.63 102.75,57.32 102.75,57.48 102.59,57.64 102.42,57.64 101.74,56.95 101.57,56.95 101.41,57.11 101.41,57.28 102.1,57.97 102.1,58.13 101.94,58.29 101.78,58.29 101.09,57.6 100.93,57.6 100.77,57.76 100.77,57.92 101.45,58.61 101.45,58.77 101.29,58.94 101.13,58.94 100.44,58.25 100.28,58.25 100.05,58.48 100.05,69.12 100.81,69.88 100.81,71.1 100.59,71.32 100.59,72.72 100.32,72.99 v6(100.32,73.99)
  L10_SIG4 w0.109: v1(142.04,44.38) 142.57,44.38 143.09,44.9 143.09,45.35 142.98,45.46 142.55,45.46 142.44,45.57 142.44,48.69 142.07,49.07 142.07,50.29 142.04,50.32 142.04,51.14 142.49,51.59 142.49,52.02 141.4,53.12 141.4,53.68 141.29,53.79 140.93,53.79 140.82,53.9 140.82,54.12 141.05,54.35 141.05,55.83 141.4,56.18 141.4,58.98 v1(142.04,59.62)
  BOTTOM w0.173: U91.K9 v1(142.04,59.62) ; U90.K9 v1(142.04,44.38)
DDR2_CLK: length 141
  TOP w0.108: v1(127.93,52.53) 128.11,52.71 128.68,52.71 129.08,53.11 129.08,54.24 128.35,54.97 126.57,54.97 126.32,54.71 126.32,51.75 126.21,51.64 125.99,51.64 125.88,51.75 125.88,54.71 125.63,54.97 125.2,54.97 124.94,54.71 124.94,51.75 124.84,51.64 124.62,51.64 124.51,51.75 124.51,54.71 124.26,54.97 123.83,54.97 123.57,54.71 123.57,51.75 123.46,51.64 123.25,51.64 123.14,51.75 123.14,54.71 122.88,54.97 122.46,54.97 122.2,54.71 122.2,51.75 122.09,51.64 121.88,51.64 121.77,51.75 121.77,54.71 121.51,54.97 121.09,54.97 120.83,54.71 120.83,51.75 120.72,51.64 120.51,51.64 120.4,51.75 120.4,54.71 120.14,54.97 119.71,54.97 119.46,54.71 119.46,51.75 119.35,51.64 119.13,51.64 119.03,51.75 119.03,54.71 118.77,54.97 118.34,54.97 118.09,54.71 118.09,51.75 117.98,51.64 117.76,51.64 117.65,51.75 117.65,54.71 117.4,54.97 116.97,54.97 116.71,54.71 116.71,51.75 116.61,51.64 116.39,51.64 116.28,51.75 116.28,54.71 116.03,54.97 115.6,54.97 115.34,54.71 115.34,51.75 115.23,51.64 115.02,51.64 114.91,51.75 114.91,54.71 114.65,54.97 113.79,54.97 107.46,61.3 107.46,61.45 107.59,61.58 107.59,61.73 107.44,61.89 107.28,61.89 107.16,61.76 107,61.76 106.85,61.91 106.85,62.07 106.95,62.17 106.95,62.32 106.8,62.47 106.65,62.47 106.54,62.37 106.39,62.37 103.48,65.29 103.48,65.87 102.69,66.65 102.69,67.84 101.04,69.5 U1.T28 ; v1(141.36,62.36) 141.52,62.51 141.52,62.78 140.59,63.71 140.59,65.18 141.35,65.94 141.35,70.06 R780.2
  L10_SIG4 w0.083: v1(141.36,47.12) 141.49,47.24 141.49,47.53 140.52,48.49 140.52,49.96 141.29,50.73 141.29,51.72 139.7,53.31 139.7,58.7 141.31,60.31 141.31,60.68 140.96,61.04 140.96,61.52 141.49,62.05 141.49,62.24 v1(141.36,62.36)
  BOTTOM w0.108: U90.J7 141.52,46.76 141.52,46.97 v1(141.36,47.12) 141.52,47.27 141.52,47.58 140.75,48.34 134.06,48.34 131.71,50.69 129.69,52.71 128.11,52.71 v1(127.93,52.53) ; v1(141.36,62.36) 141.52,62.21 141.52,62 U91.J7
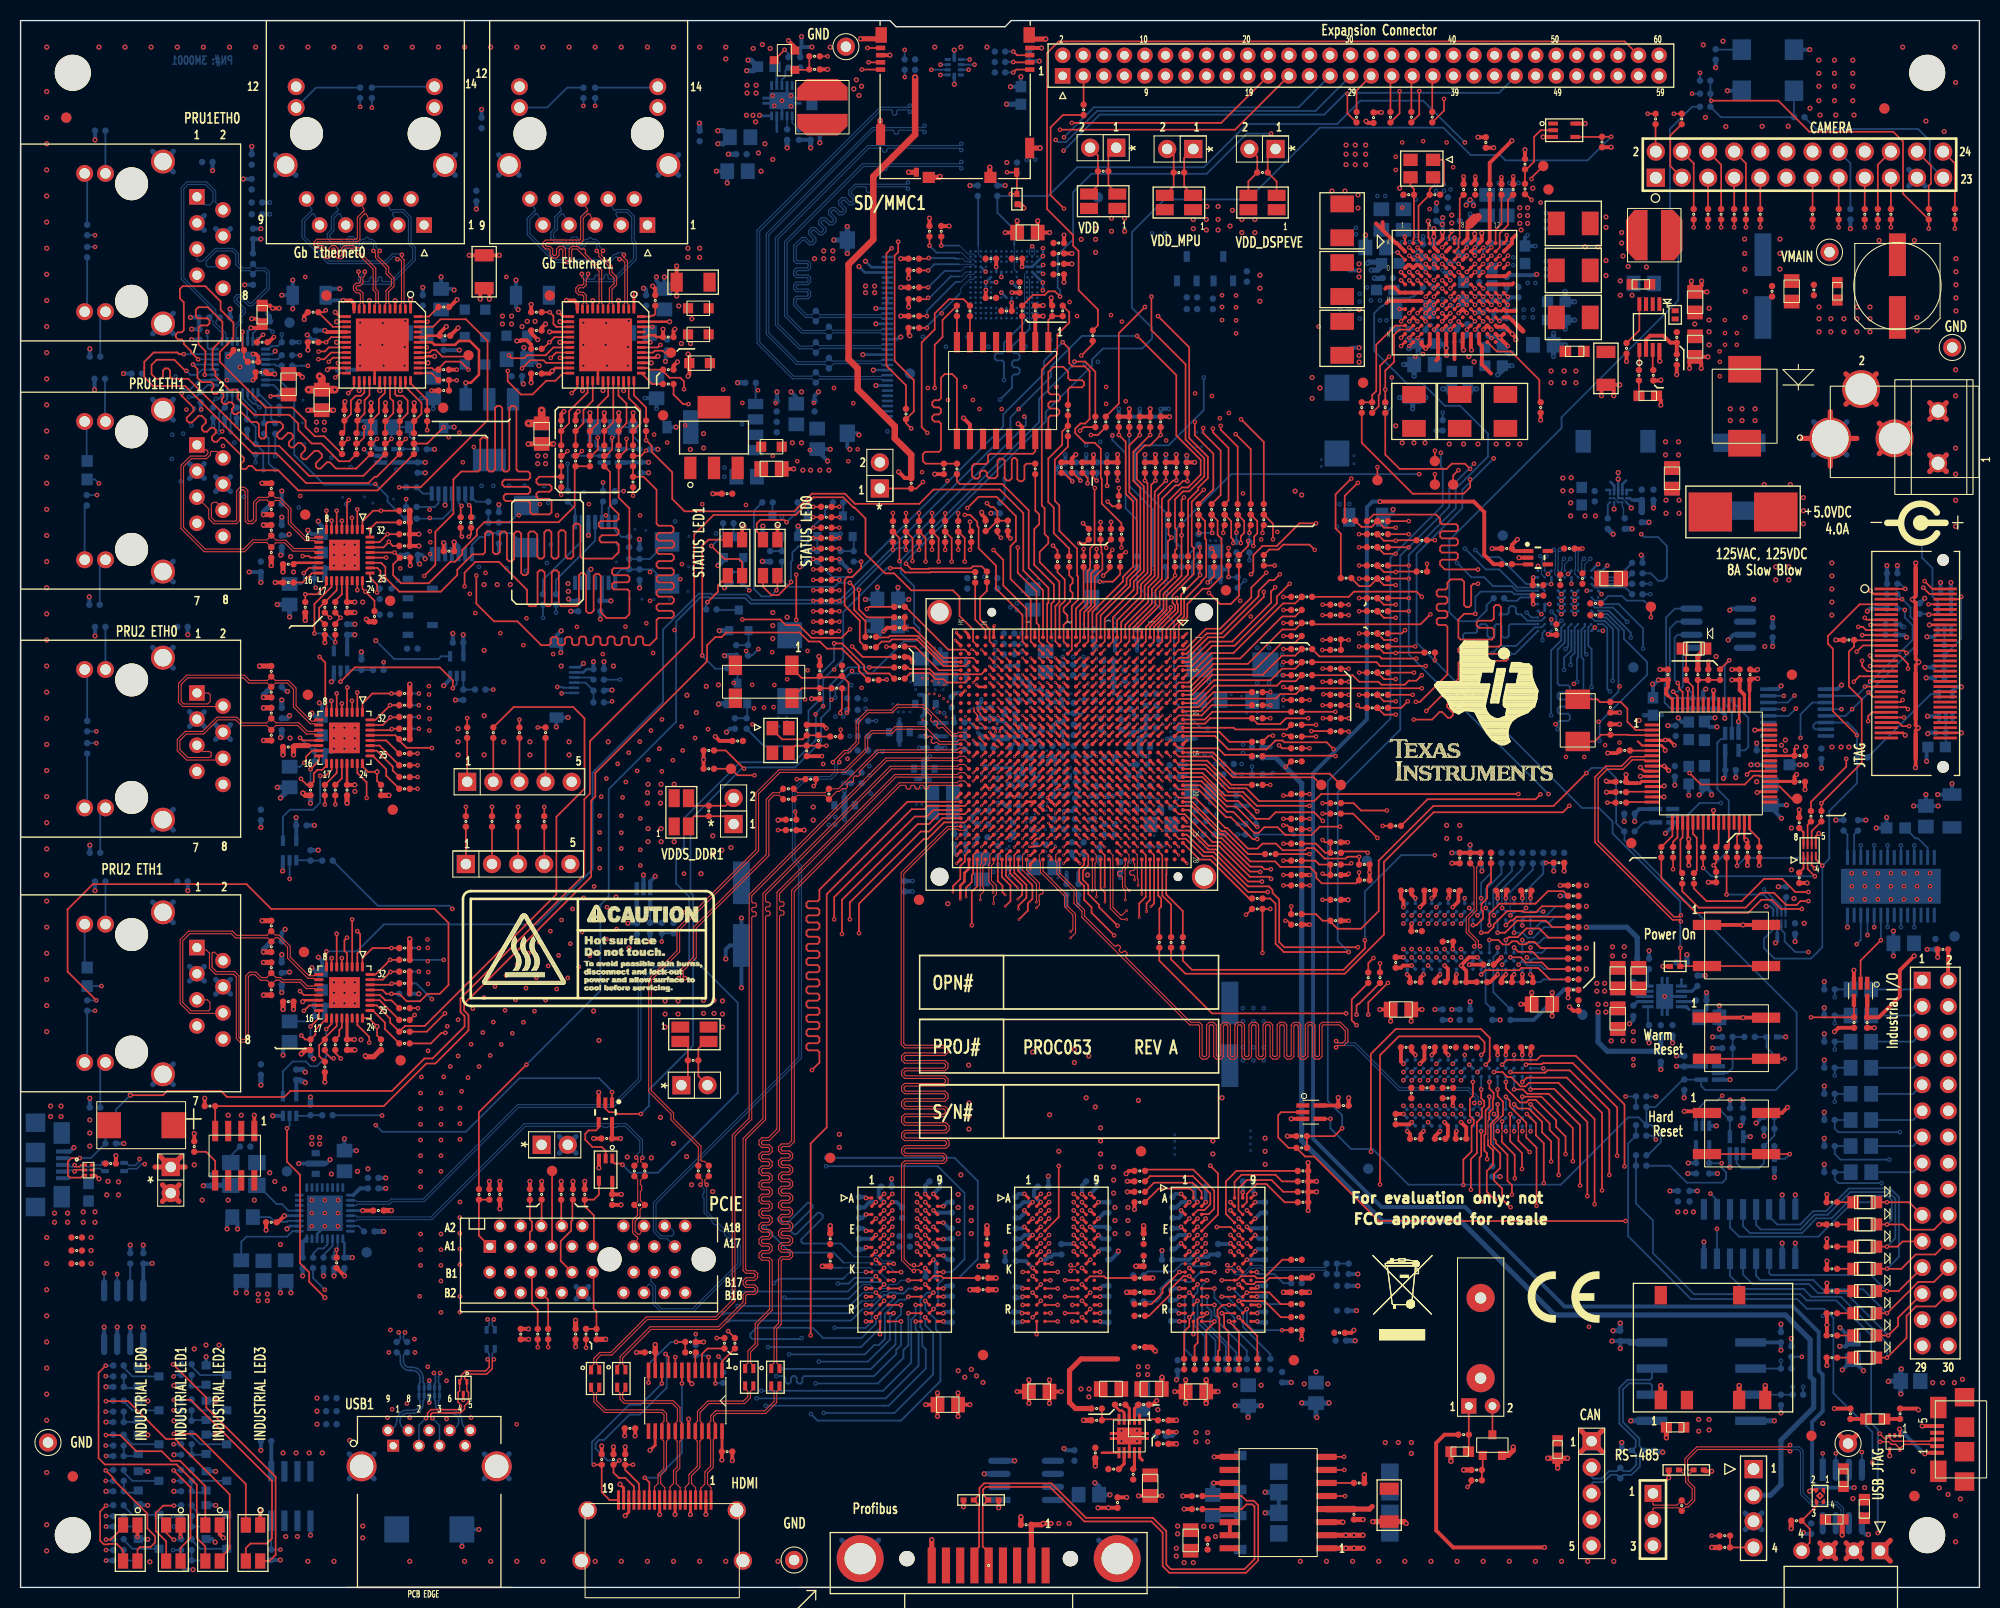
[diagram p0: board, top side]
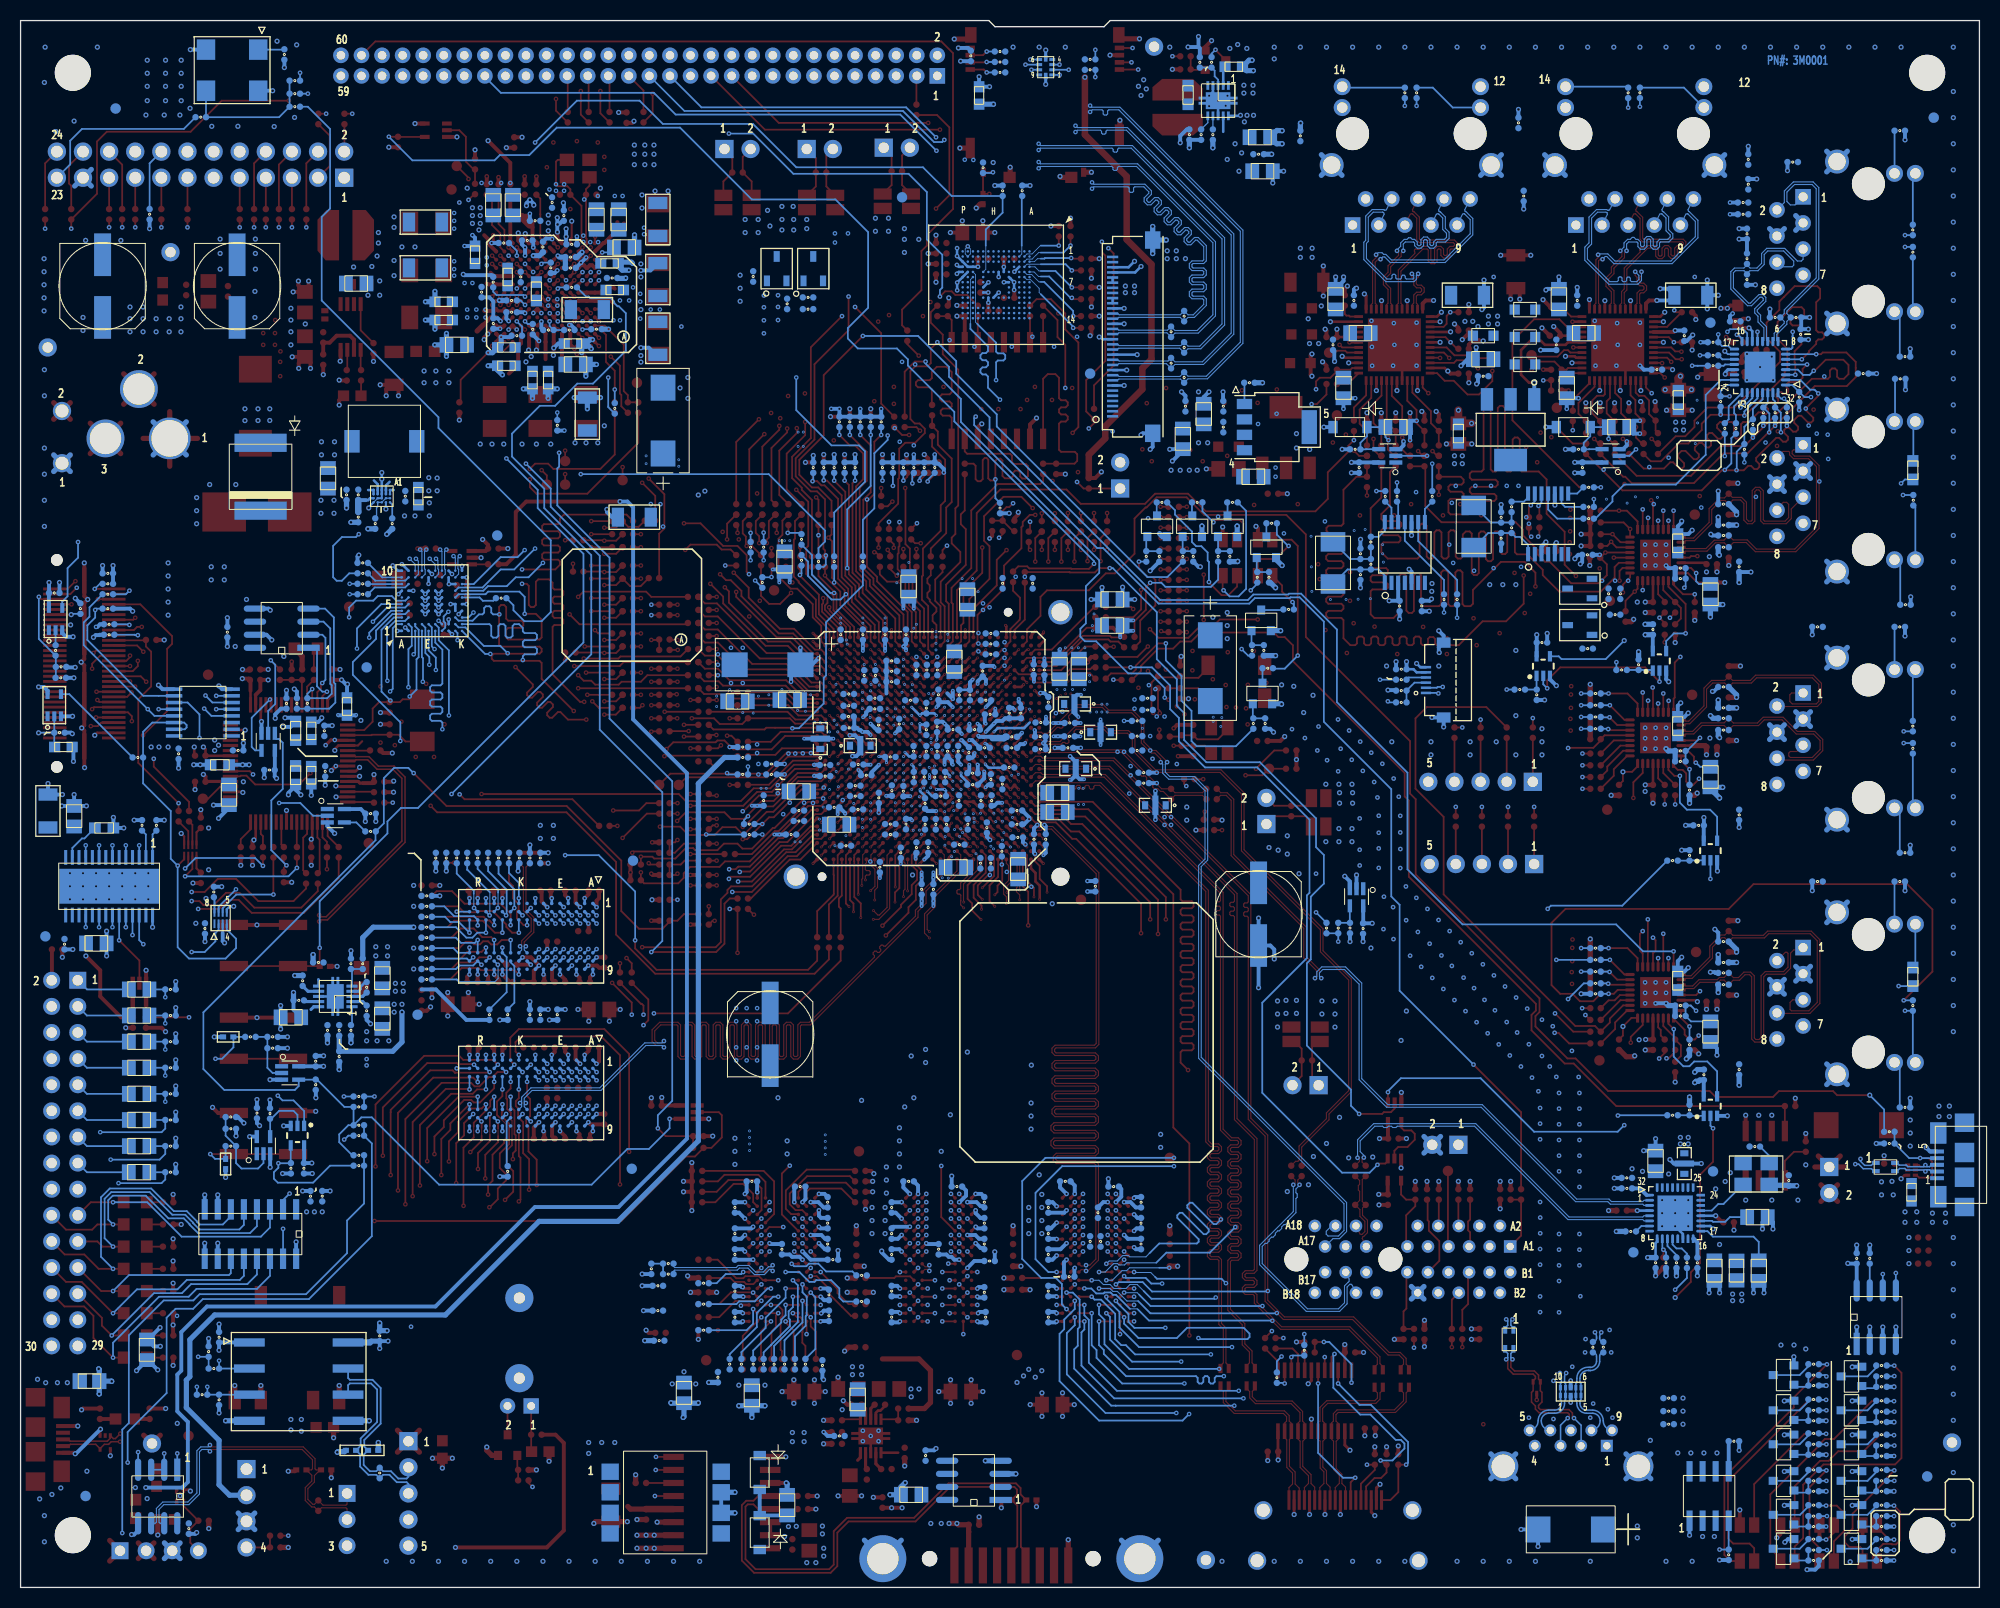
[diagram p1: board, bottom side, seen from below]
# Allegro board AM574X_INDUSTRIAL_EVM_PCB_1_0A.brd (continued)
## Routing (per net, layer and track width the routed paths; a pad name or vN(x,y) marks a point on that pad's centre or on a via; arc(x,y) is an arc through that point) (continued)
MMC2_CLK: length 68.3
  TOP w0.173: U1.J7 v4(107.03,88.01)
  L3_SIG1 w0.099: 108.57,90.77 108.57,93.75 110.8,95.97 ; 107.16,88.09 107.54,88.47 107.9,88.47 108.34,88.91 ; 108.34,88.91 108.34,90.54
  L3_SIG1 w0.102: 108.34,90.54 108.57,90.77
  L3_SIG1 w0.109: 108.34,88.91 108.34,88.91 ; v4(107.03,88.01) 107.16,88.09 ; v6(93.6,110.62) 95.6,110.62 98.48,107.74 101.42,107.74 102.12,107.05 103.06,107.05 103.69,106.43 106.77,106.43 111.14,102.06 111.14,96.99 110.8,96.65 110.8,95.97
  L10_SIG4 w0.109: v9(95.25,115.52) 93.6,113.87 93.6,113.29 93.72,113.17 95.26,113.17 95.38,113.06 95.38,112.89 95.26,112.78 93.72,112.78 93.6,112.66 93.6,112.5 93.72,112.38 95.26,112.38 95.38,112.26 95.38,112.1 95.26,111.98 93.72,111.98 93.6,111.87 93.6,111.7 93.72,111.59 95.26,111.59 95.38,111.47 95.38,111.31 95.26,111.19 93.72,111.19 93.6,111.08 v6(93.6,110.62)
  BOTTOM w0.083: 98.13,122.89 98.13,127.2 U43.M6
  BOTTOM w0.173: v9(95.25,115.52) 96.42,116.69 96.42,117.78 96.62,117.98 96.95,117.98 97.16,118.18 97.16,118.47 96.95,118.67 96.62,118.67 96.42,118.88 96.42,119.16 96.62,119.36 96.95,119.36 97.16,119.57 97.16,119.85 96.95,120.05 96.62,120.05 96.42,120.26 96.42,120.71 98.13,122.42 98.13,122.89
MMC2_CMD: length 64.1
  TOP w0.173: U1.H6 v4(107.83,88.81)
  L3_SIG1 w0.099: v4(107.83,88.81) 107.83,89.2 107.54,89.49 107.54,91.37 107.72,91.55 107.72,94.3
  L3_SIG1 w0.109: v6(95.7,108.45) 96.34,108.45 98.06,106.73 100.36,106.73 102.29,104.81 106.93,104.81 110.11,101.63 110.11,98.37 109.14,97.4 109.14,95.73 107.72,94.3
  L4_SIG2 w0.114: v6(95.7,108.45) 95.63,108.52 95.63,111.48 95.49,111.62 94.88,111.62 94.74,111.76 94.74,111.95 94.88,112.09 95.49,112.09 95.63,112.23 95.63,112.42 95.49,112.56 94.88,112.56 94.74,112.69 94.74,112.89 94.88,113.02 95.49,113.02 95.63,113.16 95.63,113.35 95.49,113.49 94.88,113.49 94.74,113.63 94.74,113.82 94.88,113.96 95.49,113.96 95.63,114.1 95.63,114.29 95.49,114.43 94.88,114.43 94.74,114.56 94.74,114.76 94.88,114.89 95.49,114.89 95.63,115.03 95.63,115.22 95.49,115.36 94.88,115.36 94.74,115.5 94.74,115.69 94.88,115.83 95.49,115.83 95.63,115.96 v6(95.63,116.79)
  L10_SIG4 w0.109: v6(95.7,108.45) v9(95.7,107.78) ; v9(95.63,117.43) v6(95.63,116.79)
  BOTTOM w0.083: U43.M5 97.63,127.7 97.63,123.06 97.46,122.89
  BOTTOM w0.173: R513.1 95.7,105.94 v9(95.7,107.78) ; v9(95.63,117.43) 95.63,119.17 95.46,119.34 94.91,119.34 94.74,119.51 94.74,119.86 94.91,120.03 95.46,120.03 95.63,120.2 95.63,121.06 97.46,122.89
MMC2_DAT0: length 62.3
  TOP w0.173: R505.1 88.27,129.24 v1(88.33,129.3) ; U1.J4 v4(107.03,90.41)
  L3_SIG1 w0.099: 107.07,95.26 107.07,91.93 106.74,91.61 106.74,91.09 107.03,90.8 v4(107.03,90.41)
  L3_SIG1 w0.109: v6(90.8,110.32) 92.48,108.64 94.39,108.64 95.38,107.65 96.09,107.65 97.74,106 100.13,106 102.03,104.09 106.68,104.09 109.4,101.38 109.4,98.62 108.46,97.68 108.46,96.65 107.07,95.26
  L4_SIG2 w0.114: v1(88.33,129.3) 87.25,128.22 87.25,115.78 87.66,115.37 87.66,111.43 88.77,110.32 v6(90.8,110.32)
  BOTTOM w0.083: 91.27,129.24 91.61,129.24 91.9,128.95 U43.A3
  BOTTOM w0.173: 91.27,129.24 90.93,129.24 90.87,129.3 v1(88.33,129.3)
MMC2_DAT1: length 62.6
  TOP w0.173: R506.1 v1(88.27,126.45) ; U1.J6 v4(107.03,88.81)
  L3_SIG1 w0.099: v4(107.03,88.81) 107.03,89.2 106.74,89.49 106.74,90.81 106.54,91.01 106.54,91.73 106.27,92 106.27,92.95 106.8,93.47 106.8,95.37
  L3_SIG1 w0.109: 106.8,95.37 108.12,96.69 108.12,97.88 109,98.76 109,101.29 107.23,103.06 102.56,103.06 99.97,105.64 97.61,105.64 95.96,107.29 95.25,107.29 94.26,108.29 v6(92.1,108.29)
  L4_SIG2 w0.114: v6(92.1,108.29) 93.16,109.34 93.16,115.2 92.33,116.03 92.33,116.75 92.19,116.88 91.83,116.88 91.69,117.02 91.69,117.21 91.83,117.35 92.19,117.35 92.33,117.49 92.33,117.68 92.19,117.82 91.83,117.82 91.69,117.96 91.69,118.15 91.83,118.29 92.19,118.29 92.33,118.42 92.33,121.76 90.04,124.05 90.04,124.67 v1(88.27,126.45)
  BOTTOM w0.083: 91.27,128.04 91.45,128.04 91.86,128.45 U43.A4
  BOTTOM w0.173: v1(88.27,126.45) 89.86,128.04 91.27,128.04
MMC2_DAT2: length 62.2
  TOP w0.173: R507.1 88.14,125.3 v1(88.27,125.43) ; U1.H4 v4(107.83,90.41)
  L3_SIG1 w0.099: 110.01,95.83 108.15,93.97 108.15,91.05 107.83,90.73
  L3_SIG1 w0.109: v4(107.83,90.41) 107.83,90.73 ; v6(92.71,110.32) 92.71,109.71 93.07,109.35 95.92,109.35 98.2,107.07 100.51,107.07 102.41,105.16 107.07,105.16 110.46,101.77 110.46,98.23 109.84,97.61 109.84,97.25 110.01,97.08 110.01,95.83
  L4_SIG2 w0.114: v1(88.27,125.43) 88.27,125.3 91.06,122.51 91.06,121.38 91.2,121.25 91.81,121.25 91.95,121.11 91.95,120.92 91.81,120.78 91.2,120.78 91.06,120.64 91.06,120.45 91.2,120.31 91.81,120.31 91.95,120.17 91.95,119.98 91.81,119.84 91.2,119.84 91.06,119.71 91.06,119.51 91.2,119.38 91.81,119.38 91.95,119.24 91.95,119.05 91.81,118.91 91.2,118.91 91.06,118.77 91.06,116.16 92.71,114.51 v6(92.71,110.32)
  BOTTOM w0.083: 91.27,127.51 91.49,127.51 91.93,127.95 U43.A5
  BOTTOM w0.173: v1(88.27,125.43) 88.39,125.43 90.47,127.51 91.27,127.51
MMC2_DAT3: length 62.1
  TOP w0.173: R508.1 v1(89.53,130.51) ; U1.H5 v4(107.83,89.61)
  L3_SIG1 w0.099: 108.36,93.83 108.36,90.84 108.13,90.62 ; 108.36,93.83 110.31,95.79
  L3_SIG1 w0.102: 108.13,89.91 108.13,90.62
  L3_SIG1 w0.109: 108.36,93.83 108.36,93.83 ; 110.31,95.79 110.54,96.02 110.54,96.87 110.8,97.13 110.8,101.91 106.64,106.07 103.57,106.07 102.92,106.71 101.98,106.71 101.29,107.41 98.34,107.41 95.91,109.83 v6(93.62,109.83) ; v4(107.83,89.61) 108.13,89.91
  L4_SIG2 w0.114: v6(93.62,109.83) 94.23,110.44 94.23,120.6 90.8,124.03 90.8,124.8 89.53,126.07 v1(89.53,130.51)
  BOTTOM w0.083: 91.27,130.51 91.32,130.51 92.13,129.7 92.63,129.7 U43.B2
  BOTTOM w0.173: v1(89.53,130.51) 91.27,130.51
MMC2_DAT4: length 68.9
  TOP w0.173: R509.1 v1(88.39,130.51) ; U1.K7 v4(106.23,88.01)
  L3_SIG1 w0.099: 106.58,95.58 106.58,93.53 106.07,93.03 106.07,91.92 106.22,91.77 106.22,91.05 106.53,90.74 106.53,88.31 v4(106.23,88.01)
  L3_SIG1 w0.109: v6(90.8,109.43) 90.8,108.95 91.97,107.78 94.28,107.78 95.15,106.91 95.86,106.91 97.51,105.26 99.8,105.26 100.61,104.45 100.61,103.81 101.7,102.72 107.06,102.72 108.64,101.15 108.64,98.88 107.78,98.03 107.78,96.78 106.58,95.58
  L4_SIG2 w0.114: v1(88.39,130.51) 88.27,130.51 85.09,127.34 85.09,115.52 87.22,113.39 87.22,111.23 89.03,109.43 v6(90.8,109.43)
  BOTTOM w0.083: 91.27,129.83 91.49,129.83 91.77,129.56 92.13,129.2 92.63,129.2 U43.B3
  BOTTOM w0.173: v1(88.39,130.51) 89.07,129.83 91.27,129.83
MMC2_DAT5: length 63.9
  TOP w0.173: U1.M7 v4(104.63,88.01) ; R510.1 v1(88.27,128.1)
  L3_SIG1 w0.099: 106.09,96.05 106.09,94.17 105.3,93.38 105.3,92.71 105.64,92.37 105.64,91.72 105.73,91.63 105.73,89.49 105.56,89.32 105.31,89.32 105.19,89.44 104.88,89.44 104.54,89.11 104.51,89.11 104.34,88.94 104.34,88.69 104.63,88.4 v4(104.63,88.01)
  L3_SIG1 w0.109: 106.09,96.05 107.06,97.02 107.06,98.36 107.92,99.23 107.92,100.9 106.81,102.01 101.42,102.01 99.87,103.56 99.87,103.99 99.34,104.53 97.18,104.53 95.5,106.2 94.89,106.2 93.92,107.17 91.51,107.17 89.94,108.74 89.94,110.04 v6(88.39,111.59)
  L4_SIG2 w0.114: v1(88.27,128.1) 87.68,127.52 87.68,116.22 88.39,115.51 v6(88.39,111.59)
  BOTTOM w0.083: 91.27,128.7 92.63,128.7 U43.B4
  BOTTOM w0.173: v1(88.27,128.1) 88.87,128.7 91.27,128.7
MMC2_DAT6: length 61.8
  TOP w0.173: U1.J5 v4(107.03,89.61) ; R511.1 v1(88.14,123.65)
  L3_SIG1 w0.099: v4(107.03,89.61) 107.03,90 107.34,90.31 107.34,91.46 107.49,91.61 107.49,94.57
  L3_SIG1 w0.109: v6(92.27,109.56) 92.83,109 94.51,109 95.5,108.01 96.31,108.01 97.96,106.35 100.25,106.35 102.16,104.45 106.81,104.45 109.75,101.5 109.75,98.49 108.8,97.54 108.8,95.87 107.49,94.57
  L4_SIG2 w0.114: v6(92.27,109.56) 92.27,114.1 89.85,116.52 89.85,118.93 89.99,119.06 90.54,119.06 90.68,119.2 90.68,119.39 90.54,119.53 89.99,119.53 89.85,119.67 89.85,119.86 89.99,120 90.54,120 90.68,120.14 90.68,120.33 90.54,120.47 89.99,120.47 89.85,120.6 89.85,120.8 89.99,120.93 90.54,120.93 90.68,121.07 90.68,121.26 90.54,121.4 89.99,121.4 89.85,121.54 89.85,121.94 v1(88.14,123.65)
  BOTTOM w0.083: 91.27,126.98 91.45,126.98 92.17,127.7 92.63,127.7 U43.B5
  BOTTOM w0.173: 91.27,126.98 90.96,126.98 88.14,124.16 v1(88.14,123.65)
MMC2_DAT7: length 61.8
  TOP w0.173: v1(88.14,122.51) R512.1 ; U1.K6 v4(106.23,88.81)
  L3_SIG1 w0.099: 106.33,95.8 106.33,94.12 105.5,93.29 105.5,92.79 105.87,92.42 105.87,91.83 105.94,91.76 105.94,89.49 106.23,89.2 v4(106.23,88.81)
  L3_SIG1 w0.109: v6(89.03,111.84) 90.28,110.58 90.28,108.93 91.74,107.48 94.1,107.48 95.02,106.56 95.73,106.56 97.38,104.91 99.59,104.91 100.25,104.25 100.25,103.66 101.54,102.37 106.93,102.37 106.95,102.35 106.96,102.35 108.24,101.06 108.24,101.06 108.28,101.02 108.28,99.03 107.43,98.18 107.43,96.91 106.33,95.8
  L4_SIG2 w0.114: v1(88.14,122.51) 88.14,121.11 88.27,120.97 88.76,120.97 88.9,120.83 88.9,120.64 88.76,120.5 88.27,120.5 88.14,120.36 88.14,120.17 88.27,120.03 88.76,120.03 88.9,119.9 88.9,119.7 88.76,119.57 88.27,119.57 88.14,119.43 88.14,119.24 88.27,119.1 88.76,119.1 88.9,118.96 88.9,118.77 88.76,118.63 88.27,118.63 88.14,118.49 88.14,116.29 89.03,115.4 v6(89.03,111.84)
  BOTTOM w0.083: 91.27,125.78 91.44,125.94 91.44,126.36 92.28,127.2 92.63,127.2 U43.B6
  BOTTOM w0.173: 91.27,125.78 88.14,122.64 v1(88.14,122.51)
MMC_CD: length 55.4
  TOP w0.173: v5(96.29,135.54) 96.29,135.54 U84.1 96.9,137.61 J15.10 95.94,137.65 v1(95.93,137.65) ; R409.1 v5(77.09,99.01)
  L3_SIG1 w0.109: v5(77.09,99.01) v6(76.45,99.01) ; v5(96.29,135.54) v6(95.71,135.54)
  L4_SIG2 w0.114: v6(95.71,135.54) 95,134.83 87.88,134.83 83.82,130.76 83.82,116.26 79.32,111.76 79.32,101.78 76.56,99.01 v6(76.45,99.01)
  BOTTOM w0.173: R408.1 96.01,137.58 v1(95.93,137.65)
MMC_CLK: length 65
  TOP w0.173: J15.5 v1(82.36,149.74) ; R405.1 v5(77.09,105.11)
  L3_SIG1 w0.109: v5(77.09,105.11) v6(76.45,105.11)
  L4_SIG2 w0.114: v6(76.45,105.11) 74.77,105.11 72.2,107.68 72.2,118.41 81.65,127.86 81.94,127.86 82.68,128.61 82.68,138.42 89.45,145.19 v1(89.45,147.11)
  L10_SIG4 w0.109: v1(82.36,149.74) 82.36,149.2 82.02,148.85 82.02,148.16 82.3,147.88 87.13,147.88 87.9,147.11 v1(89.45,147.11)
  BOTTOM w0.173: U30.1 v1(89.45,147.11)
MMC_CMD: length 66.9
  TOP w0.173: J15.3 96.9,149.04 v1(96.55,149.39) ; R404.1 v5(77.09,104.09)
  L3_SIG1 w0.109: v5(77.09,104.09) v6(76.45,104.09)
  L4_SIG2 w0.114: v6(76.45,104.09) 76.86,104.09 77.54,104.77 77.54,105.29 76.91,105.92 74.48,105.92 72.57,107.83 72.57,118.26 81.82,127.51 82.09,127.51 83.07,128.49 83.07,138.28 90.34,145.56 90.34,146.74 91.72,148.11 v1(92.78,148.11)
  L10_SIG4 w0.109: v1(96.55,149.39) 95.38,149.39 94.81,148.82 93.49,148.82 v1(92.78,148.11)
  BOTTOM w0.173: U30.7 v1(92.78,148.11) ; R398.1 v1(96.55,149.39)
MMC_D0: length 69.4
  TOP w0.173: R406.1 v5(77.09,101.05) ; J15.7 v1(82.47,148.34)
  L3_SIG1 w0.109: v5(77.09,101.05) v6(76.45,101.05)
  L4_SIG2 w0.114: v1(88.57,147.61) 88.57,145.36 80.9,137.69 80.9,129.37 71.46,119.93 71.46,105.03 72.69,103.79 72.69,102.8 74.45,101.05 v6(76.45,101.05)
  L10_SIG4 w0.109: v1(88.57,147.61) 87.23,148.95 86.58,148.95 v1(85.98,149.55) 84.76,148.34 v1(82.47,148.34)
  BOTTOM w0.173: R399.1 v1(85.98,149.55) ; U30.2 v1(88.57,147.61)
MMC_D1: length 76.4
  TOP w0.173: R407.1 v5(77.09,102.06) ; J15.8 v1(81.82,147.64)
  L3_SIG1 w0.109: v5(77.09,102.06) v6(76.45,102.06)
  L4_SIG2 w0.114: v6(76.45,102.06) 75.31,102.06 74.06,103.31 74.06,103.33 71.83,105.57 71.83,119.72 81.41,129.3 81.41,137.67 89.01,145.28 89.01,147.66 v1(89.46,148.11)
  L10_SIG4 w0.109: v1(85.99,146.9) 82.55,146.9 v1(81.82,147.64) 81.56,147.89 81.56,149.66 82.35,150.45 87.13,150.45 v1(89.46,148.11)
  BOTTOM w0.173: U30.3 v1(89.46,148.11) ; v1(85.99,146.9) 85.98,146.91 R400.1
MMC_D2: length 74.7
  TOP w0.173: J15.1 96.83,147.64 v1(96.55,147.36) ; R402.1 v5(77.09,100.03)
  L3_SIG1 w0.109: v5(77.09,100.03) v6(76.45,100.03)
  L4_SIG2 w0.114: v1(92.3,148.61) 88.76,148.61 87.46,147.32 87.46,144.77 79.76,137.07 79.76,128.76 71.09,120.09 71.09,103.65 74.7,100.03 v6(76.45,100.03)
  L10_SIG4 w0.109: v1(96.55,147.36) 95.75,146.56 92.23,146.56 91.64,147.15 91.64,147.95 v1(92.3,148.61)
  BOTTOM w0.173: R401.1 v1(96.55,147.36) ; U30.6 v1(92.3,148.61)
MMC_D3: length 72.6
  TOP w0.173: R403.1 v5(77.09,103.08) ; J15.2 96.58,148.34 v1(96.55,148.37)
  L3_SIG1 w0.109: v5(77.09,103.08) v6(76.45,103.08)
  L4_SIG2 w0.114: v6(76.45,103.08) 77.95,104.58 77.95,105.57 77.23,106.29 74.64,106.29 74.02,106.91 74.02,111.99 74.14,112.11 74.99,112.11 75.11,112.22 75.11,112.45 74.99,112.56 74.14,112.56 74.02,112.68 74.02,112.91 74.14,113.02 74.99,113.02 75.11,113.14 75.11,113.36 74.99,113.48 74.14,113.48 74.02,113.59 74.02,113.82 74.14,113.94 74.99,113.94 75.11,114.05 75.11,114.28 74.99,114.39 74.14,114.39 74.02,114.51 74.02,114.74 74.14,114.85 74.99,114.85 75.11,114.96 75.11,115.19 74.99,115.31 74.31,115.31 74.19,115.42 74.19,119.36 81.99,127.15 82.37,127.15 83.44,128.22 83.44,138.13 92.2,146.89 v1(92.2,147.61)
  L10_SIG4 w0.109: v1(96.55,148.37) 95.79,147.61 v1(92.2,147.61)
  BOTTOM w0.173: U30.8 v1(92.2,147.61) ; R397.1 v1(96.55,148.37)
OSC0_OUT: length 6.4
  TOP w0.173: R5.2 77.72,82.76 R4.1 C1.1 76.06,82.49 74.05,82.49 73.11,83.43 Y1.1
PCI_CONN_REFN: length 35.6
  TOP w0.108: C436.1 60.3,41.43 60.3,41.61 v1(60.48,41.79)
  BOTTOM w0.108: v1(60.48,41.79) 60.48,43.54 58.91,45.11 48.99,45.11 39.91,36.03 32.74,36.03 32.62,36.15 U45.5
PCI_CONN_REFP: length 35.5
  TOP w0.108: C437.1 60.03,41.37 60.03,41.65 v1(59.87,41.82)
  BOTTOM w0.108: U45.6 32.62,35.65 32.74,35.78 40.01,35.78 49.09,44.86 56.62,44.86 56.75,44.73 57.06,44.73 57.18,44.86 57.49,44.86 57.61,44.73 57.92,44.73 58.04,44.86 58.8,44.86 60.22,43.43 60.22,42.39 59.87,42.03 v1(59.87,41.82)
PCIE_CRDPRESENT: length 128.6
  TOP w0.173: R650.1 44.58,46.23 v1(49.2,50.85)
  L3_SIG1 w0.109: v1(97.61,113.88) 98.15,113.34 103.66,113.34 104.95,112.04 v1(106.17,112.04)
  BOTTOM w0.173: v1(106.17,112.04) 106.17,111.61 107.47,110.31 107.47,104.95 108.58,103.84 R664.1 ; v1(97.61,113.88) 97.76,113.73 97.76,113.06 85.8,101.1 85.23,101.1 79.83,95.69 71,95.69 70.47,96.23 67.08,96.23 67,96.31 66.11,96.31 63.75,93.95 63.75,84.2 57.2,77.65 57.2,67.21 56.39,66.4 56.39,58.04 v1(49.2,50.85)
PCIE_PERSTN: length 7.9
  TOP w0.173: U44.4 56.25,38.21 55.75,37.72 54.86,37.72 54.86,37.08 55.75,36.2 55.75,33.28 J22.A11
PCIE_REFCLKN: length 7.7
  TOP w0.108: C436.2 60.27,39.57 60.27,39.21 60.4,39.08 60.4,38.65 60.27,38.53 60.27,37.64 R580.2 60.25,36.75 60.25,36.09 59.77,35.61 59.77,34.6 60.01,34.36 60.09,34.32 60.24,34.37 J22.A14
PCIE_REFCLKP: length 7.8
  TOP w0.108: J22.A13 60.03,33.95 59.98,34.1 59.86,34.16 59.52,34.5 59.52,35.72 59.99,36.2 59.99,36.91 R580.1 60.02,37.54 60.02,39.67 C437.2
PCIE_RESETN: length 235.3
  TOP w0.173: U85.1 v1(57.52,48.17)
  L3_SIG1 w0.109: v1(57.52,48.17) 62.58,43.12 62.58,40.04 68.91,33.71 68.91,27.76 66.75,25.6 63.42,25.6 62.26,24.44 62.26,21.28 64.46,19.08 64.46,15.39 62.75,13.68 v6(62.74,13.68) ; v6(164.59,45.59) 163.2,46.99 161.16,46.99 159.26,48.89 157.23,48.89 v1(156.08,47.75)
  L4_SIG2 w0.114: v6(62.74,13.68) 62.77,13.71 72.31,13.71 72.73,13.29 98.39,13.29 99.73,11.95 102.77,11.95 103.24,12.42 105.06,12.42 106.16,11.31 116.66,11.31 117.29,11.94 129.3,11.94 140.6,23.24 147.29,23.24 152.27,28.21 156.88,28.21 165.23,36.55 165.23,38.81 164.34,39.7 164.34,45.34 v6(164.59,45.59)
  L9_SIG3 w0.114: v1(34.54,44.96) 37.08,42.42 37.08,30.1 35.94,28.96 v1(29.59,28.96)
  BOTTOM w0.173: R568.2 28.45,30.1 v1(29.59,28.96) ; v1(34.54,44.96) 35.18,44.32 43.31,44.32 48.51,49.53 56.26,49.53 57.52,48.27 v1(57.52,48.17) ; 157.1,46.74 157.1,47.75 v1(156.08,47.75)
PCIE_SMB_CLK: length 5.8
  TOP w0.173: R652.1 50.29,27 49.73,27.56 49.73,30.56 J22.B5
PCIE_SMB_DATA: length 3.8
  TOP w0.173: R653.1 51.31,27.98 J22.B6
PCIE_TCK: length 4.8
  TOP w0.173: J22.A5 49.53,33.26 49.53,34.54 49.73,34.74 49.73,35.58 49.53,35.79 49.53,37.72
PCIE_TDI: length 2.6
  TOP w0.173: J22.A6 50.67,35.2 50.67,37.72
PCIE_TDO: length 7.4
  TOP w0.173: TP20.1 51.69,33.22 J22.A7
PCIE_TMS: length 2.6
  TOP w0.173: J22.A8 52.58,35.21 52.58,37.72
PCIE_TRSTN: length 8
  TOP w0.173: J22.B9 52.53,31.77 52.53,33.68 53.54,34.7 53.54,35.6 53.66,35.72 53.66,37.66 53.72,37.72
PCIE_WAKEN: length 145.7
  TOP w0.173: R665.1 104.52,118.24 103.53,119.23 v1(102.49,119.23) ; R655.1 v1(54.99,23.32)
  L3_SIG1 w0.109: v6(59.36,52.07) 55.58,48.29 55.58,45.31 56.95,43.94 56.95,41.45 59.44,38.96 63.25,38.96 68.4,33.81 68.4,28.17 66.29,26.06 57.73,26.06 v1(54.99,23.32)
  L10_SIG4 w0.109: v9(79.23,86.55) 78.56,85.88 78.56,79.76 78.11,79.3 78.11,73.87 65.66,61.42 65.66,59.01 64.77,58.12 64.77,55.48 61.37,52.07 v6(59.36,52.07)
  BOTTOM w0.173: v1(102.49,119.23) 102.49,119.04 99.05,115.6 99.05,113.35 85.6,99.9 85.6,98.68 86.9,97.38 86.9,93.78 87.44,93.24 87.44,92.47 87,92.03 85.91,92.03 82.78,88.9 80.64,88.9 79.23,87.49 v9(79.23,86.55)
PCIECONN_PETN0: length 24
  TOP w0.108: v1(66.12,39.16) 66.29,39.34 66.29,39.62 C477.2
  BOTTOM w0.108: v1(66.12,39.16) 66.12,39.12 66.47,38.76 66.47,38.4 66.34,38.27 66.34,37.95 66.47,37.82 66.47,36.45 67.25,35.68 67.25,35.52 67.47,35.29 67.63,35.29 67.86,35.06 67.86,34.91 68.09,34.68 68.24,34.68 68.47,34.45 68.47,34.3 68.7,34.07 68.85,34.07 69.08,33.84 69.08,33.69 69.31,33.46 69.46,33.46 69.75,33.17 69.75,31.5 65.35,27.1 62.33,27.1 61.75,27.69 61.75,29.33 61.4,29.67 61.3,29.78 61.3,29.99 J22.B15
PCIECONN_PETP0: length 24
  TOP w0.108: C478.2 66.55,39.62 66.55,39.34 v1(66.73,39.16)
  BOTTOM w0.108: v1(66.73,39.16) 66.73,36.56 70,33.28 70,31.39 65.46,26.85 62.23,26.85 61.49,27.58 61.49,29.23 61.23,29.48 61.09,29.48 61,29.39 J22.B14
PHY0_LED_ACTN: length 29.8
  TOP w0.173: R321.2 v1(29.72,121.11) 30.21,121.61 U21.17
  L9_SIG3 w0.114: v1(29.72,121.11) 28.45,122.38 28.45,127.08 33.02,131.65 33.02,133.8 33.87,134.65 33.87,143.17 v1(33.02,144.02)
  BOTTOM w0.173: R293.1 v1(33.02,144.02)
PHY0_LED_LINKN: length 28.7
  TOP w0.173: U21.15 30.38,122.61 R319.2 29.49,124.03 v1(29.68,124.22)
  L9_SIG3 w0.114: v1(34.16,143.93) 34.17,143.93 34.17,133.88 35.43,132.62 35.43,128.22 34.03,126.82 32.28,126.82 v1(29.68,124.22)
  BOTTOM w0.173: R296.1 v1(34.16,143.93)
PHY1_LED_ACTN: length 29.7
  TOP w0.173: U24.17 51.93,121.61 v1(51.43,121.11) 50.8,120.48 R364.2
  L9_SIG3 w0.114: v1(54.74,144.1) 55.37,143.47 55.37,137.19 53.64,135.45 53.64,134.18 52.37,132.91 52.37,131.06 51.02,129.72 51.02,123.72 52,122.74 52,121.68 v1(51.43,121.11)
  BOTTOM w0.173: R337.1 v1(54.74,144.1)
PHY1_LED_LINKN: length 26.5
  TOP w0.173: U24.15 52.11,122.61 51.82,122.9 51.82,123.68 v1(51.46,124.03) R363.2
  L9_SIG3 w0.114: v1(51.46,124.03) 51.46,129.25 54.31,132.11 54.31,133.13 55.88,134.7 v1(55.88,144.1)
  BOTTOM w0.173: v1(55.88,144.1) R340.1
PHY_RESETN: length 359.2
  TOP w0.173: v7(29.59,28.19) 28.07,29.72 28.07,30.65 27.18,31.54 27.18,40.13 25.91,41.4 v1(25.91,44.66) ; v1(31.12,88.09) 32.51,89.49 40.77,89.49 42.04,88.22 v1(42.04,87.46)
  L9_SIG3 w0.114: v1(42.04,87.46) 42.04,89.36 40.39,91.01 40.39,102.06 33.4,109.05 v1(33.4,110.7) 38.89,110.7 39.84,109.75 43.63,109.75 44.51,110.63 47.41,110.63 48.69,111.91 51.87,111.91 52.58,111.21 v6(52.58,110.7) ; v7(29.59,28.19) 31.62,28.19 32.45,27.37 37.99,27.37 56.49,8.86 59.41,8.86 59.94,9.4 71.63,9.4 71.86,9.17 96.21,9.17 98.19,11.15 112.58,11.15 121.71,2.03 178.51,2.03 179.51,3.02 179.51,4.19 v1(180.61,5.29) ; v1(25.91,44.66) 25.91,48.04 22.86,51.09 22.86,65.61 v1(26.16,68.92) 26.16,79.71 29.91,83.46 29.91,84.24 30.81,85.14 30.81,86.36 31.19,86.74 31.19,88.02 v1(31.12,88.09)
  L10_SIG4 w0.109: v9(53.72,110.06) 53.21,110.06 v6(52.58,110.7)
  BOTTOM w0.173: U71.2 26.16,44.91 v1(25.91,44.66) ; 157.1,42.04 157.1,37.34 158.75,35.69 158.75,32.51 162.74,28.52 173.09,28.52 173.7,27.91 176.58,27.91 179.97,24.52 179.97,15.99 180.61,15.35 v1(180.61,5.29) ; U70.2 v1(26.16,68.92) ; v1(33.4,110.7) 34.04,110.06 U22.2 ; v1(42.04,87.46) 42.42,87.84 U68.2 ; U26.2 v9(53.72,110.06) ; U69.2 v1(31.12,88.09)
PMIC_EN: length 67.7
  TOP w0.173: R645.1 93.98,102.74 R929.1 ; U3.E5 v1(137.45,127.14) ; R928.2 R929.1 ; R929.1 95,104.7 94.61,105.08 94.35,105.08 v1(93.98,105.45)
  L10_SIG4 w0.109: v1(137.45,127.14) 136.22,125.91 136.22,125.35 134.65,123.77 134.65,121.82 133.96,121.13 130.81,121.13 130.66,121.28 130.05,121.9 122.53,121.9 111.91,111.28 111.91,106.51 112.57,105.85 112.57,103.86 112.29,103.59 109.04,103.59 106.04,106.58 100.48,106.58 99.35,105.45 v1(93.98,105.45)
PMIC_INT: length 71.2
  TOP w0.173: U3.K1 v5(134.25,123.14)
  L3_SIG1 w0.109: v5(134.25,123.14) 131.57,123.14 129.54,121.11 129.54,110.74 133.3,106.98 136.83,106.98 v6(140.46,103.35)
  L9_SIG3 w0.114: v6(140.46,103.35) 140.46,101.35 132.97,93.85 132.97,91.78 128.24,87.05 128.24,83.11 125.73,80.6 125.73,76.66 v6(123.83,74.76)
  L10_SIG4 w0.109: v9(123.83,73.23) v6(123.83,74.76)
  BOTTOM w0.173: R666.1 v9(123.83,73.23)
PMIC_RESET_IN: length 1.4
  TOP w0.173: U3.K9 v1(141.44,123.14)
  BOTTOM w0.173: R794.1 141.18,122.89 v1(141.44,123.14)
PMIC_RESET_OUTN: length 21.7
  TOP w0.173: U3.G6 v1(138.25,126.33)
  L10_SIG4 w0.109: v1(138.25,126.33) 138.27,126.33 138.67,126.73 142.4,126.73 143.44,125.69 143.44,121.84 143.26,121.66 143.26,119.61 140.84,117.2 140.84,116.54 139.29,114.99 139.01,114.99 v9(138.3,114.27)
  BOTTOM w0.173: R9.1 138.14,126.45 v1(138.25,126.33) ; R814.2 v9(138.3,114.27)
PORZN: length 255
  TOP w0.173: v1(147.8,77.14) 147.32,76.66 136.83,76.66 134.24,74.07 ; R499.1 v5(75.49,78.61)
  L3_SIG1 w0.109: v1(159.05,47.75) 159.05,46.18 162.31,42.93 163.76,42.93 v1(165.43,41.26) 164.7,41.26 146.43,22.99 141.73,22.99 140.87,22.12 110.77,22.12 110.46,22.43 107.59,22.43 107.29,22.12 73.28,22.12 69.37,26.03 69.37,33.66 62.86,40.16 62.86,47.71 61.74,48.83 61.74,61.35 64.02,63.62 64.02,65.16 v1(64.52,65.66) 64.9,65.66 73.02,73.79 73.02,76.15 75.48,78.61 v5(75.49,78.61)
  L4_SIG2 w0.114: v1(165.43,41.26) 165.81,41.64 165.81,45.68 164.93,46.55 164.93,49.28 166.6,50.95 166.6,60.62 161.02,66.2 159.79,66.2 149.34,76.66 148.29,76.66 v1(147.8,77.14)
  BOTTOM w0.173: 164.23,41.29 U98.4 ; 164.23,41.29 C213.1 ; 164.23,41.29 164.26,41.26 v1(165.43,41.26) 165.43,40.82 165.86,40.39 165.86,39.75 165.48,39.37 162.05,39.37 160.4,41.02 R921.2 ; R926.1 v1(64.52,65.66) ; R920.2 v1(159.05,47.75)
PR1_EDC_LATCH0: length 77.6
  TOP w0.173: v5(125.98,103.5) 124.37,103.5 122.17,101.3 120.78,101.3 119.89,100.41 119.89,98.79 v1(119.66,98.56) ; v5(111.86,95.33) 111.81,95.28 111.81,95.01 110.24,93.44 110.24,92.02 U1.E2 ; v5(101.47,134.11) 100.17,135.41 100.17,142.01 101.37,143.21 R743.2
  L3_SIG1 w0.109: v5(101.47,134.11) 103.32,134.11 105.11,132.33 105.11,131.77 111.05,125.82 111.05,123.8 123.32,111.54 123.32,106.55 125.98,103.88 v5(125.98,103.5) ; v5(111.86,95.33) 112.24,95.33 113.59,96.68 v6(113.59,97.46)
  L10_SIG4 w0.109: v1(119.66,98.56) 118.82,98.56 117.56,97.29 113.76,97.29 v6(113.59,97.46)
PR1_EDC_SYNC0: length 18.6
  TOP w0.173: v5(112.45,96.22) 112.45,95.72 112.55,95.62 112.55,94.9 111.03,93.39 111.03,92.01 U1.D2 ; v1(121.97,99.4) R744.2
  L3_SIG1 w0.109: v5(112.45,96.22) 112.49,96.22 113.14,96.87 113.14,97.65 113.41,97.92 v6(114.35,97.92)
  L10_SIG4 w0.109: v1(121.97,99.4) 117.86,99.4 117.73,99.52 115.11,99.52 114.15,98.56 114.15,98.13 v6(114.35,97.92)
PR1_EDIO_DATA_OUT1: length 4.3
  TOP w0.173: R119.1 J4.4
PR1_EDIO_DATA_OUT3: length 4.3
  TOP w0.173: R118.1 J4.3
PR1_EDIO_DATA_OUT4: length 3.6
  TOP w0.173: R198.1 48.39,70.36
PR1_EDIO_DATA_OUT6: length 3.6
  TOP w0.173: R199.1 50.93,70.36
PR2_EDC_LATCH0: length 214.7
  TOP w0.173: R910.1 v5(137.54,101.85) ; R748.1 v5(30.61,91.93)
  L3_SIG1 w0.109: v5(137.54,101.85) 134.87,101.85 134.49,102.23 134.49,103.12 133.48,104.14 132.46,104.14 129.67,106.93 127.67,106.93 126.1,108.5 126.1,111.79 115.19,122.71 115.19,125.73 110.24,130.68 110.24,135.13 112.65,137.54 112.65,141.22 113.35,141.92 J21.13 112.36,148.01 104.9,148.01 104.37,147.48 104.37,146.46 100.08,142.17 75.54,142.17 69.33,135.96 61.97,135.96 61.14,136.78 48.97,136.78 43.03,130.84 25.33,130.84 22.36,127.87 19.09,127.87 16,124.78 16,121.28 15.44,120.71 15.44,118.39 16.19,117.65 16.19,115.3 15.93,115.05 15.93,115.05 15.45,114.57 15.45,113.89 14.99,113.42 14.99,102.47 25.2,92.26 28.66,92.26 28.81,92.41 30.12,92.41 v5(30.61,91.93)
PR2_EDC_LATCH1: length 70.6
  TOP w0.173: R911.1 128.78,106.17 v5(130.05,107.44)
  L3_SIG1 w0.109: J21.15 115.35,143.86 116.59,142.62 116.59,140.18 111.12,134.72 111.12,130.3 115.72,125.7 115.72,122.86 126.39,112.2 126.39,108.62 127.64,107.37 v6(128.6,107.37) 129.98,107.37 v5(130.05,107.44)
  L10_SIG4 w0.109: v6(128.6,107.37) 127.28,107.37 125.63,105.72 124.28,105.72 122.48,103.92 122.48,100.97 121.41,99.9 v9(119.51,99.9)
  BOTTOM w0.173: R749.1 v9(119.51,99.9)
PR2_EDC_SYNC0: length 77.1
  TOP w0.173: R908.1 128.4,102.49 127.89,103 127.89,106.33 v5(129.41,107.85)
  L3_SIG1 w0.109: v5(129.41,107.85) v6(127.79,107.85) 128.37,108.44 128.37,110.74 116.1,123.01 116.1,125.83 111.66,130.28 111.66,134.04 117.35,139.72 J21.17
  L10_SIG4 w0.109: v9(118.24,99.9) 118.87,99.9 119.33,100.36 121.21,100.36 122.12,101.27 122.12,105.77 123.65,107.29 125.65,107.29 126.21,107.85 v6(127.79,107.85)
  BOTTOM w0.173: R750.1 v9(118.24,99.9)
PR2_EDC_SYNC1: length 122.6
  TOP w0.173: v6(127.38,91.19) v5(126.59,91.19)
  L3_SIG1 w0.109: J21.19 117.73,145.41 117.73,139.27 112.39,133.93 v6(112.39,130.18) 113.72,128.85 115.85,128.85 119.43,125.27 119.43,120.45 133.35,106.53 136.47,106.53 v6(139.17,103.84) ; v5(126.59,91.19) v6(127.38,91.19)
  L4_SIG2 w0.114: v6(139.17,103.84) 139.17,102.58 128.71,92.12 128.71,92.11 127.79,91.19 v6(127.38,91.19) ; v6(112.22,97.08) 110.92,98.38 110.92,103.35 111.66,104.08 111.66,105.31 111.02,105.94 111.02,106.53 111.89,107.4 111.89,108.29 112.9,109.3 112.9,114.53 111.6,115.83 111.6,122.57 112.39,123.36 v6(112.39,130.18)
  L10_SIG4 w0.109: v6(112.22,97.08) 111.86,96.73 v9(111.38,96.73)
  BOTTOM w0.173: v9(111.38,96.73) 111.76,96.73 113.54,98.51 113.54,100.41 R751.1
PR2_MII0_RXDV: length 3.6
  TOP w0.173: R197.1 45.85,70.36
PR2_MII0_TXEN: length 3.6
  TOP w0.173: R196.1 J7.1
PR2_MII1_RXDV: length 4.3
  TOP w0.173: R117.1 J4.2
PR2_MII1_TXEN: length 4.3
  TOP w0.173: R115.1 J4.1
PR2_UART0_RXD: length 62
  TOP w0.173: R906.1 v5(136.78,99.57)
  L3_SIG1 w0.109: v5(136.78,99.57) v6(136.78,98.93)
  L4_SIG2 w0.114: J21.54 152.37,148.05 152.37,144.45 150.52,142.6 150.52,136.2 148.3,133.98 148.3,123.69 147.15,122.55 147.15,117.35 148.81,115.7 148.81,113.53 147.54,112.26 147.54,105.75 143.97,102.18 140.03,102.18 v6(136.78,98.93)
PR2_UART0_TXD: length 68.8
  TOP w0.173: R907.1 v5(137.54,90.17)
  L3_SIG1 w0.109: v5(137.54,90.17) v6(138.18,90.17)
  L4_SIG2 w0.114: J21.56 154.32,147.99 154.32,145.43 150.81,141.92 150.81,137.54 150.88,137.48 150.88,136.14 148.59,133.86 148.59,123.57 147.45,122.43 147.45,117.47 149.1,115.82 149.1,113.41 147.83,112.14 147.83,103 138.18,93.34 v6(138.18,90.17)
PROFIBUS_A: length 52
  TOP w0.173: J14.3 94.15,3.41 93.57,3.99 93.57,7.96 U81.1 93.6,9.02 93.6,9.53 93.85,9.78 100.1,9.78 103.46,6.42 109.98,6.42 111.07,5.33 111.07,2.07 111.72,1.42 119.17,1.42 120.36,2.61 120.36,8 119.93,8.43 119.22,8.43 118.76,8.89 U74.12 114.94,8.89
PROFIBUS_B: length 51.3
  TOP w0.173: J14.8 92.76,3.48 93.22,3.94 93.22,7.99 U80.1 93.25,9.06 93.25,9.67 93.71,10.13 100.25,10.13 103.61,6.77 110.12,6.77 111.42,5.47 111.42,2.22 111.86,1.77 119.02,1.77 120,2.76 120,7.86 119.78,8.08 119.22,8.08 118.76,7.62 U74.13 114.94,7.62
PRU1ETH0_25MHZCLK: length 23
  BOTTOM w0.173: U9.23 25.15,117.45 26.62,115.98 26.62,110.16 29.51,107.27 34.54,107.27 35.69,106.13 35.69,105.62 37.35,103.95 R310.2
PRU1ETH0_COL: length 143.5
  TOP w0.173: R105.1 86.11,116.92 84.2,118.83 84.2,129.75 v1(84.71,130.26)
  L3_SIG1 w0.109: v1(84.71,130.26) 83.76,131.21 80.43,131.21 79.31,132.33 63.94,132.33 58.21,126.6 45.87,126.6 45.34,127.13 41.55,127.13 39.02,124.6 31.16,124.6 29.52,126.23 24.54,126.23 20.7,122.4 20.7,116.54 20.22,116.06 20.22,111.05 20.95,110.32 20.95,108.92 21.46,108.41 v6(22.1,108.41)
  L9_SIG3 w0.114: v1(7.24,130.38) 8.89,130.38 15.75,123.53 15.75,121.49 14.99,120.73 14.99,116.18 21.21,109.96 21.21,109.3 v6(22.1,108.41)
  L10_SIG4 w0.109: v6(22.1,108.41) 22.35,108.67 v9(23.62,108.67)
  BOTTOM w0.173: R106.2 v1(7.24,130.38) ; v9(23.62,108.67) 23.6,108.69 23.6,110.46 R95.1 22.86,112.89 22.13,113.62 R104.2 22.03,114.61 21.09,115.56 U9.29
PRU1ETH0_CRS: length 109.5
  TOP w0.173: R94.1 v5(88.65,100.92)
  L3_SIG1 w0.109: v5(88.65,100.92) v6(88.65,101.55)
  L10_SIG4 w0.109: v6(88.65,101.55) 88.65,101.58 87.3,102.93 83.85,102.93 80.01,106.76 78.75,106.76 78.64,106.87 78.64,107.29 78.53,107.4 78.31,107.4 78.21,107.29 78.21,106.87 78.1,106.76 77.88,106.76 77.77,106.87 77.77,107.29 77.66,107.4 77.44,107.4 77.33,107.29 77.33,106.87 77.22,106.76 77,106.76 76.89,106.87 76.89,107.29 76.79,107.4 76.57,107.4 76.46,107.29 76.46,106.87 76.35,106.76 76.13,106.76 76.02,106.87 76.02,107.29 75.91,107.4 75.69,107.4 75.58,107.29 75.58,106.87 75.48,106.76 75.26,106.76 75.15,106.87 75.15,107.29 75.04,107.4 74.82,107.4 74.71,107.29 74.71,106.87 74.6,106.76 74.23,106.76 74.09,106.9 74.09,107.99 73.95,108.13 73.75,108.13 73.61,107.99 73.61,106.9 73.47,106.76 73.27,106.76 73.13,106.9 73.13,107.99 72.99,108.13 72.74,108.13 72.52,107.91 72.52,106.98 72.38,106.84 72.18,106.84 72.04,106.98 72.04,107.84 71.9,107.98 71.7,107.98 71.56,107.84 71.56,106.98 71.42,106.84 71.22,106.84 71.08,106.98 71.08,107.84 70.94,107.98 70.74,107.98 70.6,107.84 70.6,106.98 70.46,106.84 70.26,106.84 70.12,106.98 70.12,107.84 69.98,107.98 69.78,107.98 69.64,107.84 69.64,106.98 69.5,106.84 69.3,106.84 69.16,106.98 69.16,107.46 69.02,107.6 68.82,107.6 68.68,107.46 68.68,106.98 68.54,106.84 68.34,106.84 68.2,106.98 68.2,107.46 68.05,107.6 67.86,107.6 67.72,107.46 67.72,107.03 67.57,106.89 67.38,106.89 67.24,107.03 67.24,107.84 67.09,107.98 66.9,107.98 66.76,107.84 66.76,106.98 66.61,106.84 66.42,106.84 66.28,106.98 66.28,107.84 66.13,107.98 65.94,107.98 65.8,107.84 65.8,106.98 65.65,106.84 65.46,106.84 65.32,106.98 65.32,107.84 65.17,107.98 64.98,107.98 64.84,107.84 64.84,106.98 64.69,106.84 64.5,106.84 64.36,106.98 64.36,107.84 64.21,107.98 64.02,107.98 63.88,107.84 63.88,106.86 63.73,106.72 63.54,106.72 63.4,106.86 63.4,107.84 63.25,107.98 63.06,107.98 62.92,107.84 62.92,106.87 62.79,106.74 62.59,106.74 62.43,106.9 62.43,107.84 62.29,107.98 61.98,107.98 61.57,108.39 61.57,108.64 61.34,108.87 58.86,108.87 57.8,109.93 54.84,109.93 53.73,111.03 52.95,111.03 52.27,111.71 48.77,111.71 48.23,111.18 44.27,111.18 44.17,111.07 44.17,110.78 44.06,110.67 43.84,110.67 43.73,110.78 43.73,111.07 43.62,111.18 43.4,111.18 43.29,111.07 43.29,110.78 43.18,110.67 42.96,110.67 42.86,110.78 42.86,111.07 42.75,111.18 42.53,111.18 42.42,111.07 42.42,110.78 42.31,110.67 42.09,110.67 41.98,110.78 41.98,111.07 41.87,111.18 41.65,111.18 41.54,111.07 41.54,110.78 41.44,110.67 41.22,110.67 41.11,110.78 41.11,111.07 41,111.18 39.6,111.18 39.42,111 35.64,111 33.88,112.76 32.68,112.76 32.57,112.86 32.57,113.41 32.46,113.52 32.24,113.52 32.13,113.41 32.13,112.86 32.02,112.76 31.8,112.76 31.69,112.86 31.69,113.41 31.59,113.52 31.37,113.52 31.26,113.41 31.26,112.86 31.15,112.76 30.86,112.76 29.74,113.87 27.3,113.87 27.05,113.62 24.38,113.62 v9(23.24,114.76)
  BOTTOM w0.173: v9(23.24,114.76) 22.86,115.14 22.62,115.14 22.09,115.68 U9.27
PRU1ETH0_INTN: length 131.5
  TOP w0.173: v1(110.62,123.65) 113.64,120.62 113.64,111.79 115.47,109.96 115.47,107.9 114.53,106.96 114.53,106.76 113.54,105.77 R669.2
  L3_SIG1 w0.109: v1(110.62,123.65) 110.62,125.71 105.26,131.07 105.26,131.13 104.76,131.63 104.33,131.63 102.36,133.61 97.33,133.61 97.21,133.73 87.45,133.73 87.44,133.74 49.07,133.74 44.34,129.01 39.52,129.01 37.95,127.44 32.66,127.44 32.21,127.89 27.87,127.89 27.87,127.9 27.51,127.9 27.5,127.89 25.2,127.89 19.43,122.13 v1(18.16,122.13)
  BOTTOM w0.173: U9.8 18.32,120.45 18.18,120.58 18.18,121.69 18.16,121.71 v1(18.16,122.13)
PRU1ETH0_LINKLED: length 27.1
  L9_SIG3 w0.114: v1(7.24,131.53) 8.76,131.53 15.44,124.85 22.55,124.85 25.4,122 v6(25.4,121.11)
  L10_SIG4 w0.109: v9(25.4,121.87) v6(25.4,121.11)
  BOTTOM w0.173: v9(25.4,121.87) v6(25.4,121.11) 25.04,120.75 24.41,120.75 24.11,120.45 U9.17 ; R93.2 v1(7.24,131.53)
PRU1ETH0_MDC: length 1.6
  BOTTOM w0.173: R96.1 24.87,118.83 24.75,118.95 U9.20
PRU1ETH0_MDIO: length 1.8
  BOTTOM w0.173: R98.1 25.01,119.45 U9.19
PRU1ETH0_RESETN: length 43
  L9_SIG3 w0.114: v7(34.54,92.09) 32.14,92.09 32.13,92.1 31.68,92.1 29.16,94.61 29.16,100.64 26.4,103.4 26.4,107 25.61,107.78 25.61,118.02 24.77,118.87 v7(24.77,120.24)
  BOTTOM w0.173: U9.18 24.47,119.95 v7(24.77,120.24) ; v7(34.54,92.09) 36.34,90.3 40.64,90.3 40.91,90.57 U68.4
PRU1ETH0_RXCLK: length 3.7
  BOTTOM w0.173: R83.1 24.38,113.62 24.38,114.89 23.09,116.19 U9.25
PRU1ETH0_RXD0: length 106.4
  TOP w0.173: R88.1 v5(86.11,100.92)
  L3_SIG1 w0.109: v5(86.11,100.92) v6(86.11,101.55)
  L10_SIG4 w0.109: v9(20.45,112.35) 22.56,112.35 23.25,111.65 28.83,111.65 28.94,111.54 28.94,111.06 29.04,110.95 29.26,110.95 29.37,111.06 29.37,111.54 29.48,111.65 29.7,111.65 29.81,111.54 29.81,111.06 29.92,110.95 30.14,110.95 30.25,111.06 30.25,111.54 30.36,111.65 30.57,111.65 30.68,111.54 30.68,111.06 30.79,110.95 31.01,110.95 31.12,111.06 31.12,111.54 31.23,111.65 31.82,111.65 33.4,110.07 37.91,110.07 39.04,108.95 40.11,108.95 40.25,109.09 40.25,109.64 40.37,109.76 40.53,109.76 40.65,109.64 40.65,109.09 40.76,108.97 40.93,108.97 41.04,109.09 41.04,109.64 41.16,109.76 41.32,109.76 41.44,109.64 41.44,109.09 41.56,108.97 41.72,108.97 41.84,109.09 41.84,109.64 41.95,109.76 42.12,109.76 42.23,109.64 42.23,109.09 42.35,108.97 42.83,108.97 42.94,109.09 42.94,109.64 43.06,109.76 43.22,109.76 43.34,109.64 43.34,109.09 43.46,108.97 43.62,108.97 43.74,109.09 43.74,109.64 43.85,109.76 44.02,109.76 44.13,109.64 44.13,109.09 44.25,108.97 44.41,108.97 44.53,109.09 44.53,109.64 44.64,109.76 44.81,109.76 44.92,109.64 44.92,109.09 45.04,108.97 45.2,108.97 45.32,109.09 45.32,109.67 45.41,109.76 45.58,109.76 45.72,109.62 45.72,109.09 45.83,108.97 46.09,108.97 46.21,109.09 46.21,109.64 46.33,109.76 46.49,109.76 46.61,109.64 46.61,109.09 46.72,108.97 47.65,108.97 48.26,108.36 54.97,108.36 55.09,108.48 55.09,108.8 55.2,108.92 55.37,108.92 55.48,108.8 55.48,108.48 55.6,108.36 57.58,108.36 59.19,106.75 59.19,106.19 60.37,105.01 60.93,105.01 61.65,104.29 71.29,104.29 71.79,104.79 71.79,105.69 71.93,105.83 72.13,105.83 72.27,105.69 72.27,104.74 72.41,104.6 72.61,104.6 72.75,104.74 72.75,105.69 72.89,105.83 73.09,105.83 73.23,105.69 73.23,104.66 73.34,104.55 73.54,104.55 73.71,104.71 73.71,105.69 73.85,105.83 74.05,105.83 74.19,105.69 74.19,104.64 74.33,104.5 74.53,104.5 74.67,104.64 74.67,105.66 74.84,105.84 77.45,105.84 77.59,105.69 77.59,104.43 77.74,104.28 77.94,104.28 78.07,104.41 78.07,105.69 78.21,105.84 78.41,105.84 78.55,105.69 78.55,104.41 78.68,104.27 78.88,104.27 79.03,104.42 79.03,105.69 79.17,105.84 79.37,105.84 79.51,105.69 79.51,104.4 79.64,104.28 79.91,104.28 80.06,104.43 80.06,104.86 80.16,104.96 80.54,104.96 83.49,102.01 85.65,102.01 v6(86.11,101.55)
  BOTTOM w0.173: v9(20.45,112.35) 20.43,112.37 20.43,114.17 21.02,114.76 R111.2 20.59,115.19 U9.30
PRU1ETH0_RXD1: length 115.9
  TOP w0.173: R90.1 v5(91.19,100.92)
  L3_SIG1 w0.109: v5(91.19,100.92) v6(91.19,101.55)
  L10_SIG4 w0.109: v6(91.19,101.55) 88.9,103.84 84.23,103.84 80.39,107.67 80.39,109.33 79.52,110.2 74.11,110.2 74,110.31 74,111.27 73.89,111.38 73.67,111.38 73.56,111.27 73.56,110.31 73.45,110.2 73.23,110.2 73.12,110.31 73.12,111.27 73.01,111.38 72.8,111.38 72.69,111.27 72.69,110.31 72.58,110.2 72.36,110.2 72.25,110.31 72.25,111.27 72.14,111.38 71.92,111.38 71.81,111.27 71.81,110.31 71.7,110.2 71.49,110.2 71.38,110.31 71.38,111.27 71.27,111.38 71.05,111.38 70.94,111.27 70.94,110.31 70.83,110.2 70.61,110.2 70.5,110.31 70.5,111.27 70.39,111.38 70.18,111.38 70.07,111.27 70.07,110.31 69.96,110.2 69.74,110.2 69.63,110.31 69.63,111.27 69.52,111.38 69.3,111.38 69.19,111.27 69.19,110.31 69.08,110.2 68.86,110.2 68.76,110.31 68.76,111.27 68.65,111.38 68.43,111.38 68.32,111.27 68.32,110.31 68.21,110.2 67.99,110.2 67.88,110.31 67.88,111.27 67.77,111.38 67.55,111.38 67.44,111.27 67.44,110.31 67.34,110.2 63.24,110.2 62.23,111.21 61.24,111.21 60.93,110.9 55.43,110.9 54.25,112.07 53.44,112.07 52.81,112.7 48.26,112.7 47.65,112.09 47.17,112.09 47.06,112.2 47.06,112.87 46.95,112.98 46.78,112.98 46.67,112.87 46.67,112.21 46.56,112.1 46.4,112.1 46.27,112.23 46.27,112.87 46.15,112.98 45.99,112.98 45.87,112.87 45.87,112.21 45.76,112.1 45.61,112.1 45.48,112.23 45.48,112.87 45.36,112.98 45.2,112.98 45.08,112.87 45.08,112.21 44.97,112.1 44.82,112.1 44.69,112.23 44.69,112.87 44.57,112.98 44.41,112.98 44.29,112.87 44.29,112.23 44.15,112.09 43.89,112.09 43.78,112.2 43.78,112.9 43.67,113.01 43.5,113.01 43.39,112.9 43.39,112.21 43.27,112.1 39.34,112.1 37.6,113.83 34.23,113.83 33.33,114.74 31.5,114.74 30.43,115.8 28.04,115.8 27.35,116.5 25.65,116.5 25.53,116.38 25.53,115.94 25.42,115.83 25.25,115.83 25.14,115.94 25.14,116.38 25.02,116.5 19.06,116.5 18.54,115.98 18.54,115.12 19.3,114.36 v9(19.3,112.35)
  BOTTOM w0.173: U9.31 20.09,115.56 19.87,115.35 R110.2 19.81,114.76 19.32,114.27 19.32,112.36 v9(19.3,112.35)
PRU1ETH0_RXD2: length 109.6
  TOP w0.173: R91.1 v5(89.92,100.92)
  L3_SIG1 w0.109: v5(89.92,100.92) v6(89.92,101.55)
  L10_SIG4 w0.109: v6(89.92,101.55) 89.87,101.55 88.04,103.38 84.02,103.38 79.5,107.9 75.31,107.9 73.66,109.55 72.27,109.55 72.12,109.4 72.12,108.6 71.98,108.46 71.78,108.46 71.64,108.6 71.64,109.6 71.5,109.74 71.3,109.74 71.16,109.6 71.16,108.6 71.02,108.46 70.82,108.46 70.68,108.6 70.68,109.61 70.54,109.75 70.34,109.75 70.2,109.61 70.2,108.6 70.06,108.46 69.86,108.46 69.72,108.6 69.72,109.61 69.58,109.75 69.38,109.75 69.24,109.61 69.24,109.37 69.1,109.23 68.9,109.23 68.76,109.37 68.76,109.61 68.62,109.75 68.42,109.75 68.28,109.61 68.28,109.37 68.13,109.23 67.94,109.23 67.8,109.37 67.8,109.61 67.65,109.75 67.46,109.75 67.32,109.61 67.32,108.6 67.17,108.46 66.98,108.46 66.84,108.6 66.84,109.61 66.69,109.75 66.5,109.75 66.36,109.61 66.36,108.6 66.21,108.46 66.02,108.46 65.88,108.6 65.88,109.61 65.73,109.75 65.54,109.75 65.4,109.61 65.4,108.6 65.25,108.46 65.06,108.46 64.92,108.6 64.92,109.61 64.77,109.75 64.58,109.75 64.44,109.61 64.44,108.6 64.29,108.46 64.1,108.46 63.96,108.6 63.96,109.61 63.81,109.75 63.62,109.75 63.48,109.61 63.48,108.6 63.33,108.46 63.14,108.46 63,108.6 63,109.61 62.85,109.75 62.66,109.75 62.51,109.61 62.51,108.6 62.37,108.46 62.18,108.46 62.03,108.6 62.03,109.61 61.68,109.96 58.62,109.96 58.13,110.46 55.08,110.46 54.03,111.51 53.28,111.51 52.57,112.22 48.59,112.22 48.01,111.64 37.54,111.64 37.35,111.83 37.35,111.99 37.8,112.44 37.8,112.6 37.65,112.75 37.49,112.75 37.04,112.3 36.88,112.3 36.73,112.45 36.73,112.61 37.18,113.06 37.18,113.22 37.03,113.37 36.87,113.37 36.42,112.91 36.26,112.91 35.8,113.38 35.38,113.38 35.26,113.26 35.26,112.49 35.15,112.37 34.98,112.37 34.87,112.49 34.87,113.26 34.75,113.38 33.87,113.38 33.21,114.04 31.55,114.04 30.47,115.12 24.07,115.12 23.57,115.63 22.4,115.63 22.29,115.52 22.29,115.1 22.19,114.99 21.97,114.99 21.86,115.1 21.86,115.52 21.75,115.63 21.53,115.63 21.42,115.52 21.42,115.1 21.31,114.99 21.09,114.99 20.98,115.1 20.98,115.52 20.87,115.63 20.66,115.63 20.55,115.52 20.55,115.1 20.44,114.99 20.22,114.99 20.11,115.1 20.11,115.52 20,115.63 v9(19,115.63)
  BOTTOM w0.173: R109.2 18.73,115.36 v9(19,115.63) 19,115.62 19.28,115.62 19.59,115.92 U9.32
PRU1ETH0_RXD3: length 104.8
  TOP w0.173: R92.1 v5(84.84,100.92)
  L3_SIG1 w0.109: v5(84.84,100.92) v6(84.84,101.55)
  L10_SIG4 w0.109: v6(84.84,101.55) 83.13,101.55 82.75,101.94 82.59,101.94 82.12,101.47 81.97,101.47 81.82,101.63 81.82,101.78 82.28,102.25 82.28,102.4 81.15,103.54 76.17,103.54 75.85,103.86 75.43,103.86 74.73,103.15 74.24,103.15 73.54,103.86 71.62,103.86 71.45,103.69 69.89,103.69 69.34,103.13 60.9,103.13 60.05,103.99 59.43,103.99 59.32,104.1 59.32,104.37 59.21,104.48 58.99,104.48 58.88,104.37 58.88,104.1 58.77,103.99 58.37,103.99 58.12,104.24 58.12,104.44 58.76,105.08 58.76,105.28 58.62,105.42 58.42,105.42 57.78,104.78 57.58,104.78 57.29,105.07 57.29,105.27 57.91,105.9 57.91,106.1 57.77,106.24 57.57,106.24 56.95,105.61 56.75,105.61 56.61,105.75 56.61,105.95 57.23,106.58 57.23,106.78 57.09,106.92 56.89,106.92 56.27,106.29 56.07,106.29 54.74,107.62 44.35,107.62 44,107.28 44,106.5 43.89,106.38 43.72,106.38 43.61,106.5 43.61,107.79 43.49,107.9 43.33,107.9 43.21,107.79 43.21,106.5 43.09,106.38 42.93,106.38 42.81,106.5 42.81,107.79 42.7,107.9 42.53,107.9 42.42,107.79 42.42,106.52 42.3,106.41 42.14,106.41 42.02,106.52 42.02,107.79 41.91,107.9 41.74,107.9 41.63,107.79 41.63,106.52 41.51,106.41 41.35,106.41 41.23,106.52 41.23,107.79 41.11,107.9 40.95,107.9 40.83,107.79 40.83,106.55 40.72,106.43 40.55,106.43 40.44,106.55 40.44,107.79 40.32,107.9 40.16,107.9 40.04,107.79 40.04,106.55 39.92,106.43 39.76,106.43 39.64,106.55 39.64,107.79 39.53,107.9 38.1,107.9 36.58,109.43 28.57,109.43 27.17,110.82 19.84,110.82 16.38,114.28 v9(16.38,115.78)
  BOTTOM w0.173: U9.1 18.19,116.95 R108.2 17.02,115.78 v9(16.38,115.78)
PRU1ETH0_RXDV: length 3.8
  BOTTOM w0.173: U9.26 22.59,115.7 22.87,115.42 23.32,115.42 23.85,114.89 23.85,114.2 23.68,114.04 R86.1
PRU1ETH0_RXERR: length 106.4
  TOP w0.173: R87.1 v5(87.38,100.92)
  L3_SIG1 w0.109: v5(87.38,100.92) v6(87.38,101.55)
  L10_SIG4 w0.109: v6(87.38,101.55) 86.46,102.47 83.67,102.47 79.85,106.29 71.54,106.29 71.23,105.98 71.23,105.01 71,104.78 70.64,104.78 70.53,104.9 70.53,106.1 70.41,106.21 70.25,106.21 70.13,106.1 70.13,104.9 70.02,104.78 69.85,104.78 69.73,104.9 69.73,106.1 69.62,106.21 69.45,106.21 69.34,106.1 69.34,104.9 69.22,104.78 69.06,104.78 68.94,104.9 68.94,105.95 68.83,106.06 68.66,106.06 68.55,105.95 68.55,104.9 68.43,104.78 68.27,104.78 68.15,104.9 68.15,105.95 68.03,106.06 67.87,106.06 67.75,105.95 67.75,104.9 67.64,104.78 66.65,104.78 66.51,104.92 66.51,106.15 66.37,106.29 66.17,106.29 66.03,106.15 66.03,104.92 65.89,104.78 65.69,104.78 65.55,104.92 65.55,106.15 65.41,106.29 65.21,106.29 65.07,106.15 65.07,104.92 64.93,104.78 64.73,104.78 64.59,104.92 64.59,106.15 64.45,106.29 64.25,106.29 64.11,106.15 64.11,104.92 63.97,104.78 63.7,104.78 63.58,104.9 63.58,106.13 63.46,106.25 63.3,106.25 63.18,106.13 63.18,104.9 63.07,104.78 62.9,104.78 62.79,104.9 62.79,106.18 62.67,106.3 62.51,106.3 62.39,106.18 62.39,105.14 62.23,104.98 61.72,104.98 60.98,105.72 60.98,106.05 61.62,106.68 61.62,106.88 61.48,107.02 61.28,107.02 60.58,106.32 60.38,106.32 60.24,106.46 60.24,106.66 60.94,107.36 60.94,107.56 60.83,107.67 60.66,107.67 59.87,106.88 59.72,106.88 57.17,109.43 54.23,109.43 53.62,108.82 48.49,108.82 47.09,110.22 39.8,110.22 39.5,110.52 34.26,110.52 33.19,111.59 32.72,111.59 32.21,112.1 28.27,112.1 28.16,112.2 28.16,112.6 28.06,112.7 27.84,112.7 27.73,112.6 27.73,112.2 27.62,112.1 27.4,112.1 27.29,112.2 27.29,112.6 27.18,112.7 26.96,112.7 26.85,112.6 26.85,112.21 26.74,112.1 26.57,112.1 26.46,112.21 26.46,112.6 26.35,112.71 26.14,112.71 26.03,112.6 26.03,112.21 25.92,112.1 24.73,112.1 v9(22.86,113.97)
  BOTTOM w0.173: U9.28 21.59,115.66 22.86,114.38 v9(22.86,113.97)
PRU1ETH0_TXCLK: length 38
  TOP w0.173: v1(15.67,116.13) 15.67,115.9 16.84,114.74 16.84,114.45 16.16,113.77 16.16,113.51 16.36,113.3 16.67,113.3 17.33,113.96 17.61,113.96 18.01,113.56 18.01,113.28 17.64,112.9 17.64,112.62 17.84,112.42 18.13,112.42 18.5,112.79 18.79,112.79 18.99,112.59 18.99,112.3 18.62,111.93 18.62,111.64 18.82,111.44 19.1,111.44 19.48,111.81 19.76,111.81 21.71,109.86 21.71,109.58 21.4,109.27 21.4,108.98 21.61,108.78 21.89,108.78 22.2,109.09 22.49,109.09 22.92,108.66 25.05,108.66 27.01,106.7 34.71,106.7 R79.1
  BOTTOM w0.173: v1(15.67,116.13) 16.03,116.49 16.46,116.49 17.42,117.45 U9.2
PRU1ETH0_TXD0: length 37.3
  TOP w0.173: R81.1 33.34,108.12 28.05,108.12 25.16,111.01 22.84,111.01 16.3,117.56 14.74,117.56 14.54,117.76 14.54,118.36 14.33,118.56 14.05,118.56 13.85,118.36 13.85,117.76 13.64,117.56 13.19,117.56 12.74,118.01 12.74,118.91 13.24,119.41 14.95,119.41 16.02,118.33 v1(16.11,118.33)
  BOTTOM w0.173: v1(16.11,118.33) 16.51,117.94 17.14,117.94 17.66,118.45 U9.4
PRU1ETH0_TXD1: length 37
  TOP w0.173: R84.1 32.65,108.83 30.68,108.83 30.07,109.44 29.79,109.44 29.18,108.83 28.92,108.83 28.72,109.03 28.72,109.34 29.3,109.92 29.3,110.21 28.97,110.54 28.59,110.54 27.78,109.73 27.49,109.73 27.29,109.94 27.29,110.22 27.68,110.61 27.68,110.9 27.26,111.32 26.98,111.32 26.54,110.88 26.3,110.88 26.1,111.08 26.1,111.42 26.48,111.79 26.48,112.08 26.28,112.28 25.99,112.28 25.44,111.73 25.16,111.73 24.96,111.93 24.96,112.23 25.51,112.78 25.51,113.07 25.23,113.35 24.07,113.35 23.87,113.15 23.87,111.94 23.68,111.75 23.4,111.75 23.18,111.96 23.18,113.15 22.98,113.35 22.43,113.35 21.49,114.3 21.2,114.3 21.03,114.13 20.75,114.13 20.55,114.33 20.55,114.62 20.71,114.78 20.71,115.07 20.51,115.27 20.22,115.27 20.06,115.11 19.77,115.11 19.57,115.31 19.57,115.6 19.73,115.76 19.73,116.05 19.53,116.25 19.24,116.25 19.08,116.09 18.79,116.09 18.59,116.29 18.59,116.57 18.76,116.74 18.76,117.03 18.54,117.24 17.61,117.24 17.2,117.66 17.2,118.51 v1(16.76,118.95)
  BOTTOM w0.173: U9.5 v1(16.76,118.95)
PRU1ETH0_TXD2: length 37.8
  TOP w0.173: R85.1 29.54,111.97 28.61,111.97 27.71,112.86 27.71,113.49 26.44,114.76 23.83,114.76 19.38,119.21 19.38,120.18 20.7,121.5 20.7,123.02 19.45,124.26 19.45,125.08 19.02,125.51 17.97,126.57 15.77,126.57 15.49,126.29 15.49,125.38 15.88,125 15.88,122.28 15.67,122.08 15.3,122.08 15.1,121.87 15.1,121.59 15.3,121.39 15.67,121.39 15.88,121.18 15.88,120.95 16.58,120.24 16.58,120.14 v1(17.27,119.45)
  BOTTOM w0.173: U9.6 v1(17.27,119.45)
PRU1ETH0_TXD3: length 39
  TOP w0.173: R82.1 34.65,108.03 34.44,108.03 33.83,107.42 27.76,107.42 24.87,110.31 22.55,110.31 16.01,116.85 12.9,116.85 12.03,117.72 12.03,118.62 12.03,119.2 12.94,120.11 15.24,120.11 15.41,119.95 v1(15.88,119.95)
  BOTTOM w0.173: U9.7 v1(15.88,119.95)
PRU1ETH0_TXEN: length 36.9
  TOP w0.173: R80.1 31.96,109.53 30.98,109.53 29.25,111.26 28.32,111.26 27.01,112.57 27.01,113.2 26.15,114.06 22.72,114.06 21.11,115.67 21.11,115.95 21.18,116.02 21.18,116.31 20.98,116.51 20.69,116.51 20.62,116.44 20.34,116.44 18.95,117.83 18.95,118.25 18.68,118.52 18.68,120.47 19.63,121.42 19.63,123.09 18.2,124.52 17.3,124.52 17.04,124.27 17.04,123.64 17.25,123.44 18.18,123.44 18.38,123.23 18.38,122.95 18.18,122.75 17.51,122.75 17.31,122.54 17.31,120.91 17.98,120.24 17.98,119.16 17.92,119.09 17.92,117.96 v1(17.91,117.95)
  BOTTOM w0.173: U9.3 v1(17.91,117.95)
PRU1ETH1_25MHZCLK: length 12.5
  TOP w0.173: U13.23 v1(32.75,97)
  L4_SIG2 w0.114: v1(32.75,97) 37.5,101.75 v1(37.5,105.86)
  BOTTOM w0.173: R313.2 v1(37.5,105.86)
PRU1ETH1_COL: length 68.4
  TOP w0.173: U13.29 v5(36.38,100.66) R152.1 36.24,99.51 36.24,98.45 37.01,97.67 39.7,97.67 41.79,99.76 42.25,99.76 42.95,100.47 42.95,100.9 44.37,102.32 44.37,102.87 45.11,103.61 52.32,103.61 53.89,105.18 53.89,108.96 R150.1 R148.1
  L3_SIG1 w0.109: v5(36.38,100.66) v6(35.94,101.1)
  L4_SIG2 w0.114: v1(7.43,106.25) 10.67,106.25 20.8,96.12 30.04,96.12 35.01,101.1 v6(35.94,101.1)
  BOTTOM w0.173: R151.2 v1(7.43,106.25)
PRU1ETH1_CRS: length 81.5
  TOP w0.173: R139.1 57.33,108.49 57.33,105.24 58.16,104.4 58.16,103.92 57.96,103.72 56.43,103.72 56.23,103.52 56.23,103.23 56.43,103.03 57.96,103.03 58.16,102.83 58.16,102.54 57.96,102.34 56.54,102.34 56.31,102.11 56.31,101.82 56.48,101.65 57.96,101.65 58.16,101.44 58.16,100.69 57.54,100.07 54.65,100.07 54.44,100.27 54.44,103.26 54.24,103.46 53.96,103.46 53.75,103.26 53.75,100.27 53.55,100.07 53.21,100.07 53.01,100.27 53.01,102.62 52.8,102.82 52.52,102.82 52.32,102.62 52.32,100.27 52.11,100.07 51.83,100.07 51.62,100.27 51.62,102.62 51.42,102.82 51.14,102.82 50.93,102.62 50.93,100.27 50.73,100.07 50.45,100.07 50.24,100.27 50.24,102.41 49.95,102.71 49.58,102.71 49.37,102.5 49.37,98.68 49.17,98.47 48.88,98.47 48.68,98.67 48.68,102.5 48.48,102.71 48.2,102.71 47.99,102.5 47.99,100.02 47.79,99.81 47.5,99.81 47.3,100.01 47.3,102.5 47.1,102.71 46.81,102.71 46.61,102.5 46.61,100.72 46.41,100.51 46.12,100.51 45.92,100.72 45.92,102.5 45.72,102.71 45.38,102.71 45.18,102.5 45.18,100.69 44.98,100.48 43.97,100.48 42.47,98.99 42.47,98.46 40.86,96.86 36.83,96.86 35.48,98.21 35.48,99.25 35.07,99.66 U13.27
PRU1ETH1_INTN: length 156.7
  TOP w0.173: R670.2 112.27,100.86 112.42,101.02 112.42,102.9 112.27,103.05 112.27,105.83 113.04,106.61 113.65,106.61 115.12,108.07 115.12,109.82 113.29,111.64 113.29,118.97 109.98,122.29 v1(109.98,125.56) ; U13.8 v1(29.75,104.73)
  L3_SIG1 w0.109: v1(27.69,127.46) 28.22,126.93 38.13,126.93 39.83,128.63 58.78,128.63 63.6,133.46 87.32,133.46 88.16,132.62 88.62,132.62 89.16,133.15 95.9,133.15 96.69,132.37 99.15,132.37 99.4,132.61 102.49,132.61 103.91,131.2 103.91,129.76 104.97,128.71 106.83,128.71 v1(109.98,125.56)
  L4_SIG2 w0.114: v1(29.75,104.73) 24.64,104.73 21.18,108.18 21.18,111.61 18.72,114.08 18.72,121.62 23.47,126.36 26.59,126.36 v1(27.69,127.46)
PRU1ETH1_LINKLED: length 29.5
  TOP w0.173: U13.17 29.75,97.52 28.83,96.6 v1(27.69,96.6) R131.1
  L4_SIG2 w0.114: v1(27.69,96.6) 21.46,96.6 10.68,107.38 v1(7.62,107.38)
  BOTTOM w0.173: v1(7.62,107.38) 7.24,107.77 R138.2
PRU1ETH1_MDC: length 2.4
  TOP w0.173: R140.1 30.61,95.97 31.25,96.61 U13.20
PRU1ETH1_MDIO: length 5.2
  TOP w0.173: R120.1 29.03,94.24 29.03,95.28 29.59,95.83 R142.1 30.75,96.99 U13.19
PRU1ETH1_RESETN: length 9
  TOP w0.173: v1(28.58,92.79) 28.58,95.66 30.25,97.33 U13.18
  BOTTOM w0.173: U69.4 30.47,92.04 29.72,92.79 v1(28.58,92.79)
PRU1ETH1_RXCLK: length 176.6
  TOP w0.173: U13.25 33.97,98.24 34.67,97.54 v5(34.67,96.77) ; R129.1 118.24,103.21 v1(118.24,102.6)
  L3_SIG1 w0.109: v5(34.67,96.77) 34.67,97.54 34.25,97.96 34.25,101.38 34.54,101.67 34.54,103.12 34.08,103.59 32.05,103.59 31.39,104.25 29.49,104.25 29.16,104.58 28.72,104.58 28.6,104.69 28.6,105.05 28.49,105.16 28.32,105.16 28.21,105.05 28.21,104.69 28.09,104.58 27.93,104.58 27.81,104.69 27.81,105.05 27.7,105.16 27.28,105.16 26.79,105.65 26.79,106 26.68,106.11 26.08,106.11 25.96,106.23 25.96,106.39 26.08,106.51 26.65,106.51 26.77,106.63 26.77,106.79 26.65,106.91 26.08,106.91 25.96,107.02 25.96,107.19 26.08,107.3 26.55,107.3 26.67,107.42 26.67,107.77 26.55,107.89 25.25,107.89 25.14,108 25.14,108.17 25.25,108.28 26.55,108.28 26.67,108.4 26.67,108.56 26.55,108.68 25.25,108.68 25.14,108.8 25.14,108.96 25.25,109.08 26.55,109.08 26.67,109.19 26.67,109.36 26.55,109.47 25.25,109.47 25.14,109.59 25.14,109.75 25.25,109.87 26.55,109.87 26.67,109.99 26.67,110.15 26.55,110.27 25.25,110.27 25.14,110.38 25.14,110.55 25.25,110.66 26.55,110.66 26.67,110.78 26.67,110.94 26.55,111.06 25.25,111.06 25.14,111.17 25.14,111.34 25.25,111.45 26.55,111.45 26.67,111.57 26.67,111.73 26.55,111.85 25.25,111.85 25.14,111.97 25.14,112.13 25.25,112.25 26.68,112.25 26.79,112.36 26.79,112.53 26.68,112.64 25.25,112.64 25.14,112.76 25.14,112.92 25.25,113.04 26.77,113.04 26.87,113.15 26.87,113.31 26.75,113.44 25.25,113.44 25.14,113.55 25.14,113.72 25.25,113.83 26.68,113.83 26.79,113.95 26.79,114.48 26.68,114.6 26.32,114.6 26.2,114.71 26.2,114.88 26.32,114.99 26.68,114.99 26.79,115.11 26.79,115.35 27.12,115.68 27.44,115.68 27.59,115.54 27.59,115.14 27.7,115.03 27.87,115.03 27.98,115.14 27.98,115.56 28.1,115.68 28.26,115.68 28.38,115.56 28.38,114.94 28.49,114.82 28.66,114.82 28.78,114.94 28.78,115.56 28.89,115.68 29.06,115.68 29.17,115.56 29.17,114.94 29.29,114.82 29.45,114.82 29.57,114.94 29.57,115.56 29.68,115.68 29.85,115.68 29.96,115.56 29.96,115.14 30.08,115.03 30.24,115.03 30.36,115.14 30.36,115.57 30.47,115.68 30.99,115.68 31.42,116.11 31.42,116.52 32.17,117.27 32.57,117.27 32.69,117.15 32.69,117 32.8,116.89 32.97,116.89 33.08,117 33.08,117.15 33.2,117.27 33.36,117.27 33.48,117.15 33.48,116.62 33.6,116.51 33.76,116.51 33.88,116.62 33.88,117.15 33.99,117.27 34.16,117.27 34.27,117.15 34.27,117 34.39,116.89 34.55,116.89 34.67,117 34.67,117.15 34.78,117.27 34.95,117.27 35.06,117.15 35.06,117 35.18,116.89 35.34,116.89 35.46,117 35.46,117.15 35.58,117.27 35.74,117.27 35.86,117.15 35.86,116.6 35.97,116.48 36.14,116.48 36.25,116.6 36.25,117.15 36.37,117.27 36.53,117.27 36.65,117.15 36.65,117 36.76,116.89 36.93,116.89 37.05,117 37.05,117.15 37.16,117.27 37.33,117.27 37.44,117.15 37.44,117 37.56,116.89 37.72,116.89 37.84,117 37.84,117.15 37.95,117.27 38.12,117.27 38.23,117.15 38.23,117 38.35,116.89 38.51,116.89 38.63,117 38.63,117.15 38.75,117.27 38.91,117.27 39.03,117.15 39.03,117 39.14,116.89 39.31,116.89 39.42,117 39.42,117.15 39.54,117.27 40.2,117.27 41.38,116.09 43.25,116.09 43.53,115.81 43.68,115.81 43.86,115.99 44.01,115.99 44.16,115.83 44.16,115.68 43.99,115.5 43.99,115.35 44.14,115.2 44.3,115.2 44.47,115.37 44.63,115.37 44.78,115.22 44.78,115.06 44.61,114.89 44.61,114.73 44.76,114.58 44.92,114.58 45.09,114.75 45.25,114.75 45.4,114.6 45.4,114.44 45.23,114.27 45.23,114.11 45.38,113.96 45.53,113.96 45.71,114.13 45.86,114.13 46.02,113.98 46.02,113.83 45.84,113.65 45.84,113.5 46,113.34 46.15,113.34 46.33,113.52 46.48,113.52 46.64,113.36 46.64,113.21 46.46,113.03 46.46,112.88 46.62,112.72 46.77,112.72 46.95,112.9 47.1,112.9 47.26,112.74 47.26,112.59 47.08,112.41 47.08,112.26 47.42,111.92 47.42,110.9 49.86,108.46 51.45,108.46 51.79,108.8 60.01,108.8 60.89,107.92 64.38,107.92 70.13,113.67 84.18,113.67 84.66,114.15 89.99,114.15 91.26,112.88 96.16,112.88 98.37,110.67 106.86,110.67 109.4,108.13 112.61,108.13 113.01,107.72 113.01,107.44 114.16,106.29 114.16,106.06 116.64,103.58 117.25,103.58 v1(118.24,102.6)
  BOTTOM w0.173: R750.2 v1(118.24,102.6)
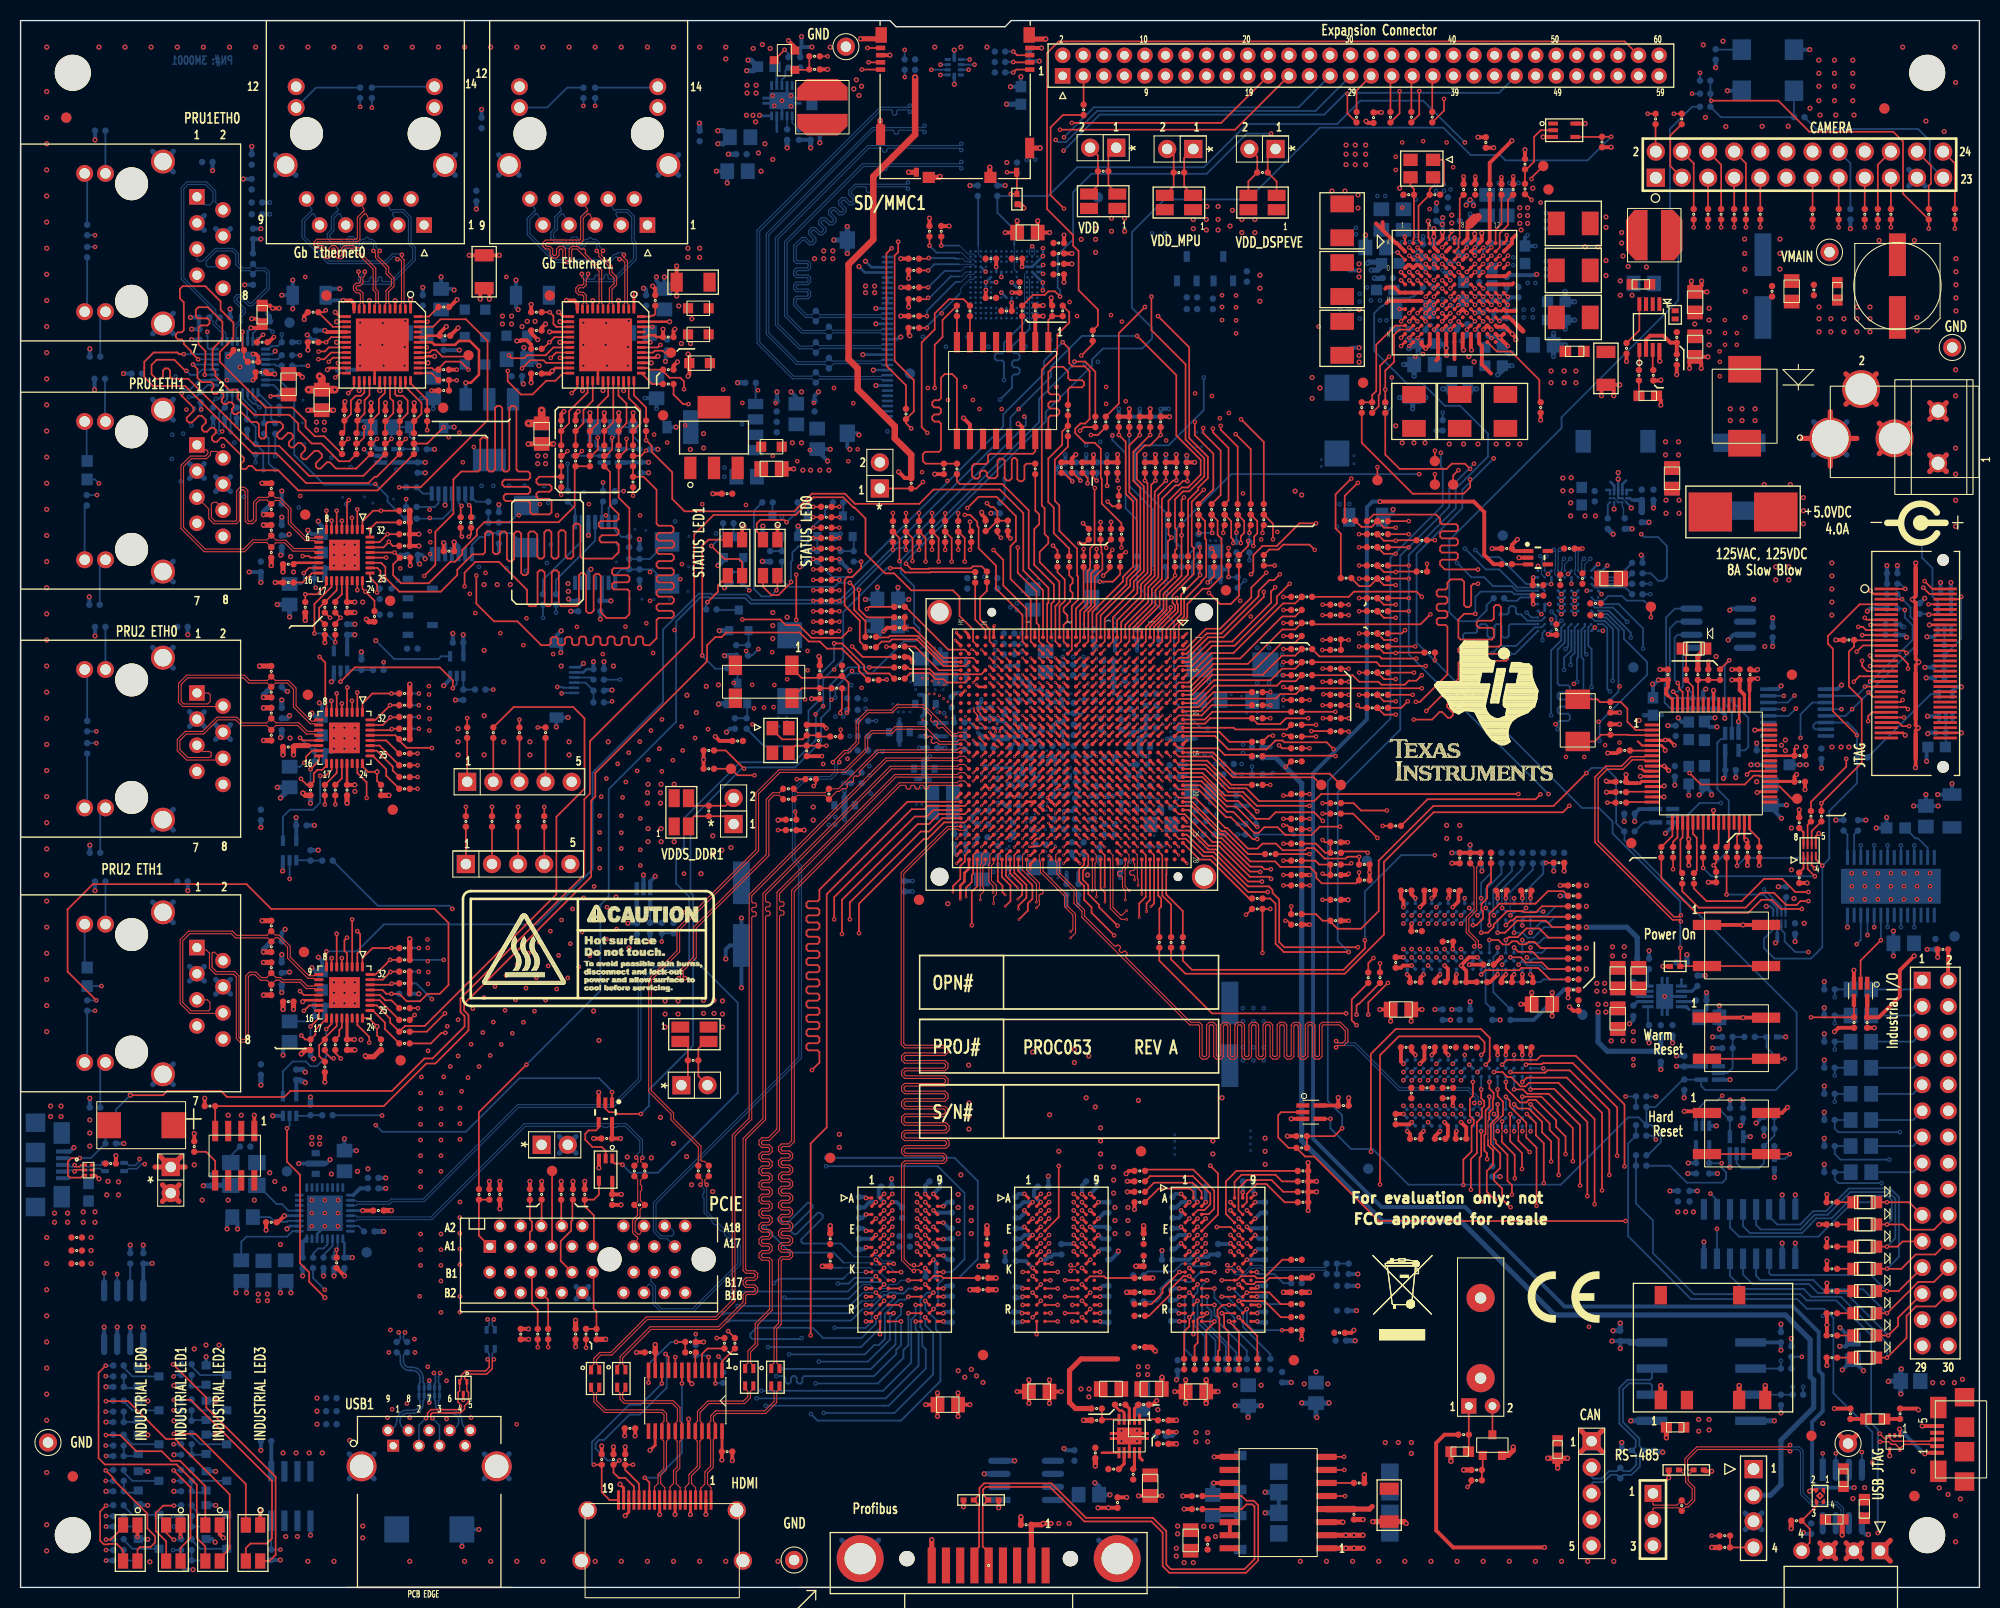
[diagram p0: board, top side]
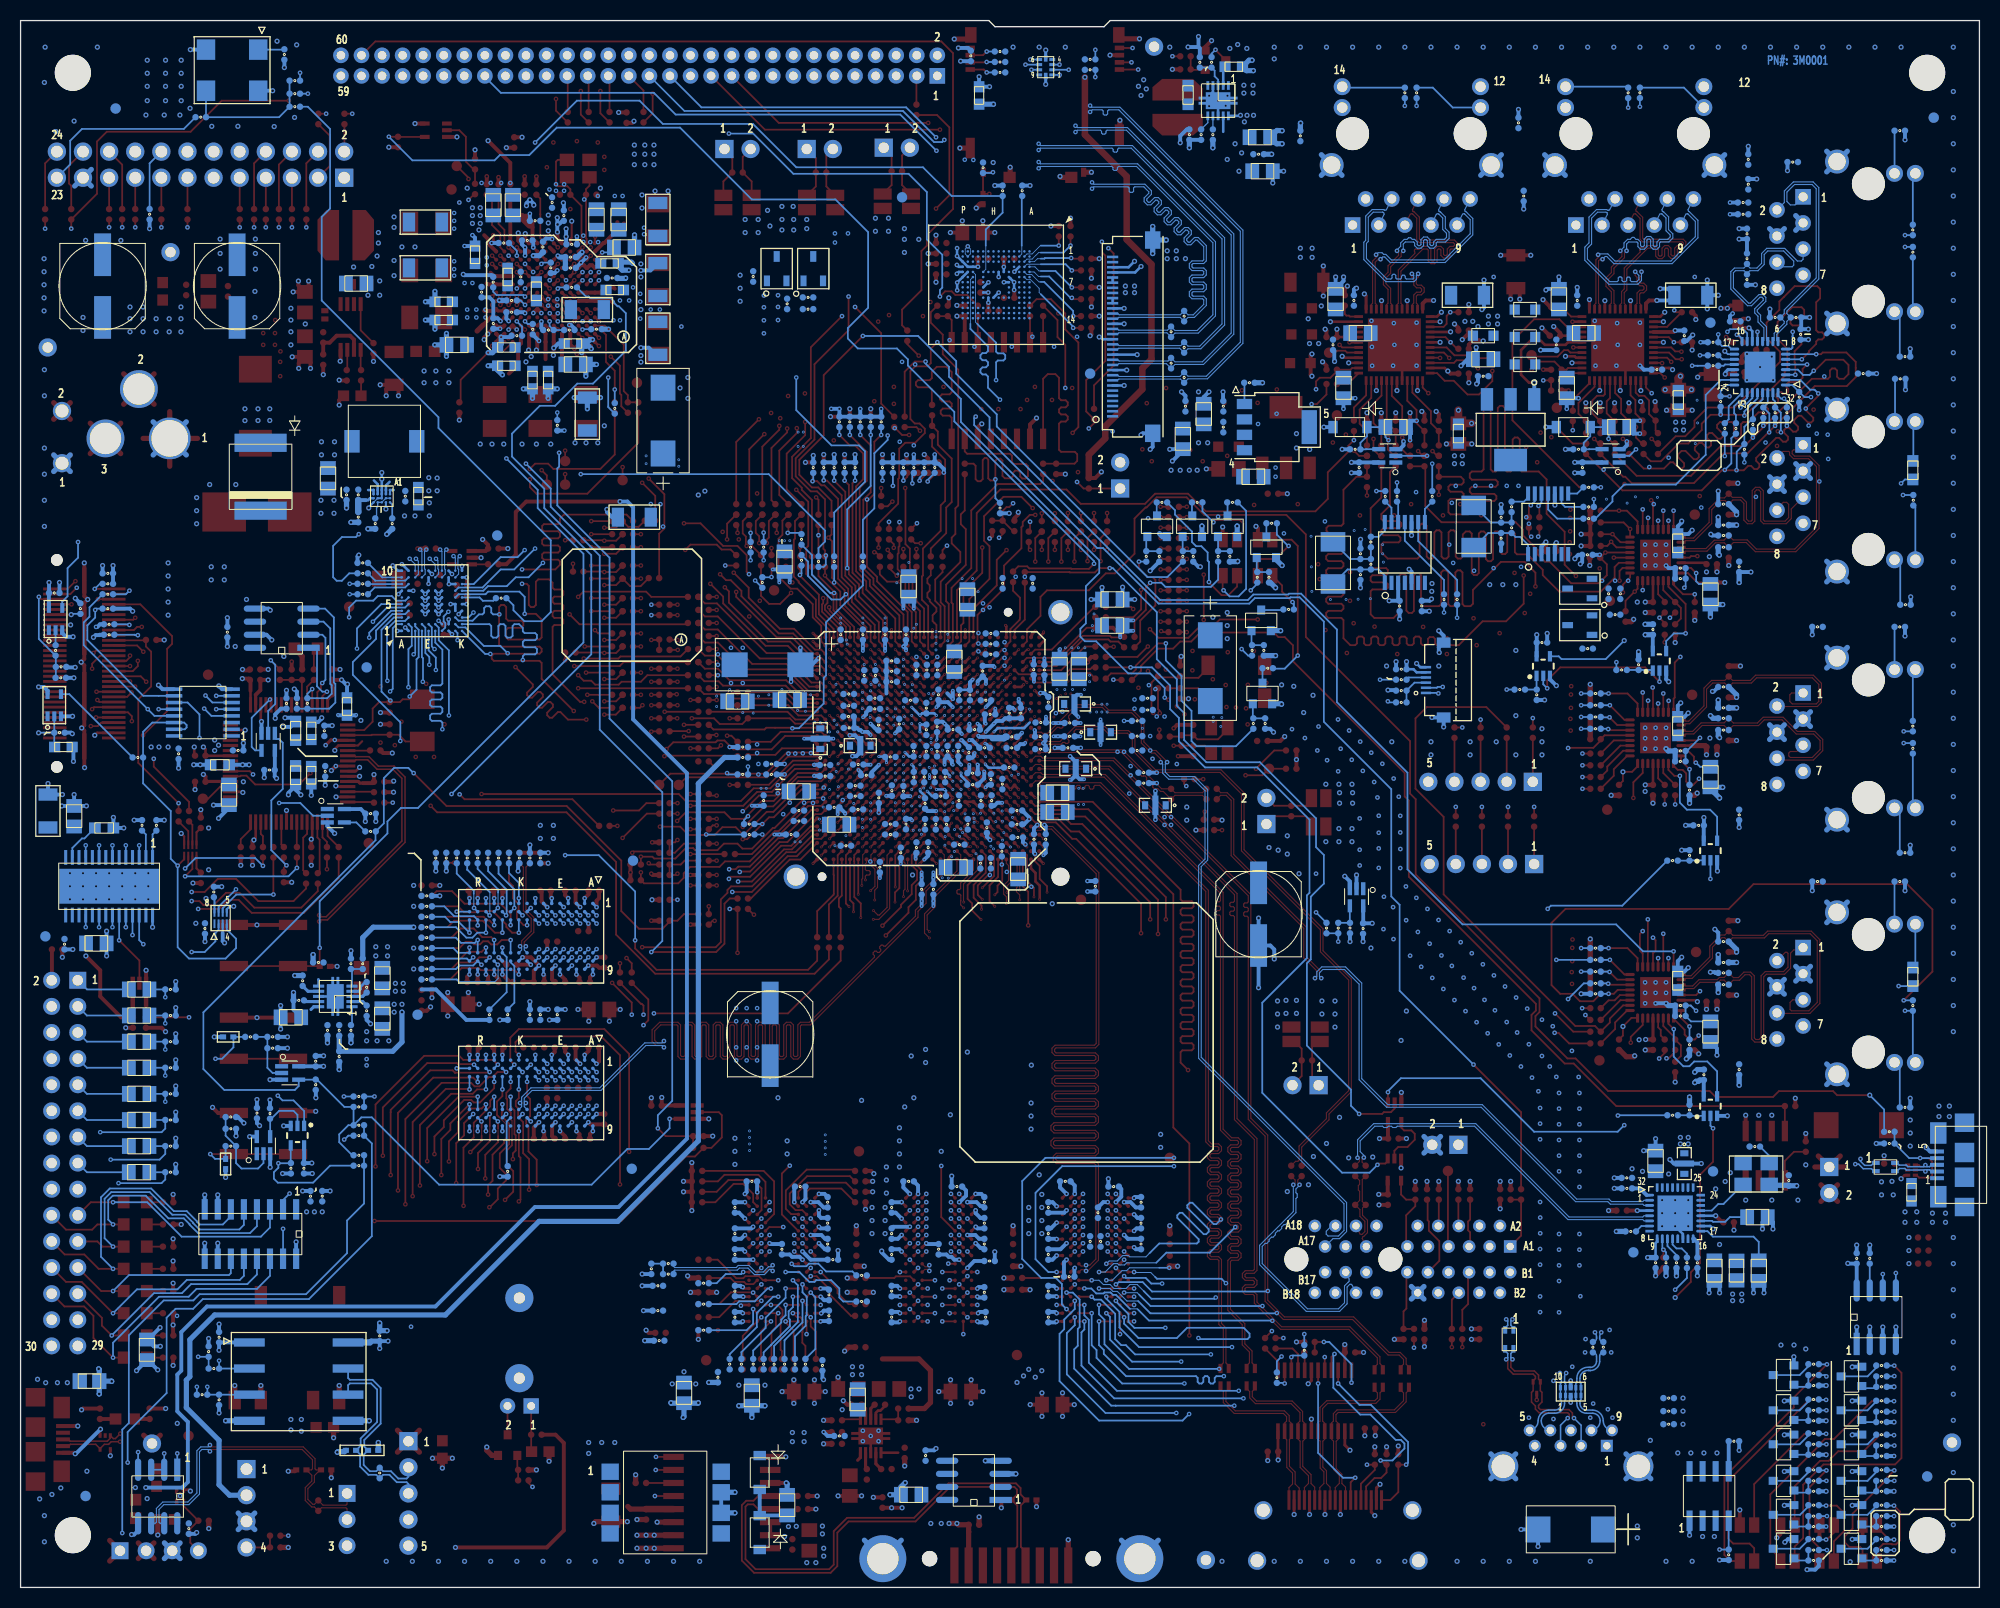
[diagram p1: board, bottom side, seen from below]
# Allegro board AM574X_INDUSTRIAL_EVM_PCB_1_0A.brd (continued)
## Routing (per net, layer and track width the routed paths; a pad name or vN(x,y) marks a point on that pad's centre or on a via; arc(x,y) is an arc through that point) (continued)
PRU1ETH1_RXD0: length 83
  TOP w0.173: 35.81,101.68 35.29,101.16 U13.30 ; 35.81,101.68 v5(35.81,101.71) ; 35.81,101.68 36.2,101.3 R158.2 ; v5(43.18,97.36) 43.18,98.7 44.23,99.75 46.53,99.75 49.25,97.03 49.25,95.68 49.49,95.44 50.07,95.44 50.27,95.65 50.27,98.72 50.48,98.92 50.76,98.92 50.97,98.72 50.97,95.65 51.17,95.44 51.45,95.44 51.66,95.65 51.66,98.72 51.86,98.92 52.14,98.92 52.35,98.72 52.35,95.65 52.55,95.44 54.1,95.44 54.31,95.65 54.31,98.45 54.51,98.66 54.79,98.66 55,98.45 55,94.98 55.19,94.78 55.51,94.78 55.73,95.01 55.73,98.38 55.93,98.58 56.22,98.58 56.42,98.38 56.42,94.85 56.98,94.29 58.84,94.29 59.21,94.66 59.21,96.9 59.03,97.07 57.7,97.07 57.53,97.24 57.53,97.59 57.7,97.76 59.03,97.76 59.21,97.93 59.21,98.28 59.03,98.45 57.7,98.45 57.53,98.62 57.53,98.97 57.7,99.14 59.03,99.14 59.21,99.31 59.21,104.96 58.17,106 R133.1
  L3_SIG1 w0.109: v5(35.81,101.71) 36.45,101.71 36.81,101.34 36.81,100.32 36.35,99.85 36.35,99.08 36.87,98.56 38.53,98.56 38.95,98.98 40.3,98.98 41.91,97.36 v5(43.18,97.36)
PRU1ETH1_RXD1: length 83
  TOP w0.173: R157.2 v5(35.69,102.44) 34.9,101.66 U13.31 ; v5(44.32,98.42) 44.32,95.68 46.04,93.97 48.32,93.97 50.64,91.65 51.38,91.65 51.56,91.82 51.56,92.26 51.73,92.44 52.07,92.44 52.25,92.26 52.25,91.82 52.42,91.65 52.76,91.65 52.94,91.82 52.94,92.26 53.11,92.44 53.46,92.44 53.63,92.26 53.63,91.82 53.8,91.65 54.15,91.65 54.32,91.82 54.32,92.31 54.49,92.49 54.84,92.49 55.01,92.31 55.01,91.82 55.18,91.65 55.53,91.65 55.7,91.82 55.7,92.31 55.87,92.49 56.22,92.49 56.39,92.31 56.39,91.82 56.56,91.65 56.91,91.65 57.08,91.82 57.08,92.31 57.26,92.49 57.6,92.49 57.77,92.31 57.77,91.82 57.95,91.65 58.29,91.65 58.46,91.82 58.46,92.31 58.64,92.49 58.98,92.49 59.16,92.31 59.16,91.82 59.33,91.65 59.67,91.65 59.85,91.82 59.85,92.31 60.02,92.49 60.36,92.49 60.54,92.31 60.54,91.82 60.71,91.65 61.18,91.65 61.85,92.32 61.85,94.09 62.05,94.3 63.33,94.3 63.53,94.5 63.53,94.79 63.33,94.99 62.05,94.99 61.85,95.19 61.85,95.48 62.05,95.68 63.33,95.68 63.53,95.88 63.53,96.17 63.33,96.37 62.05,96.37 61.85,96.57 61.85,96.86 62.05,97.06 63.33,97.06 63.53,97.26 63.53,97.55 63.33,97.75 62.05,97.75 61.85,97.95 61.85,98.24 62.05,98.44 63.33,98.44 63.53,98.64 63.53,98.93 63.33,99.13 62.05,99.13 61.85,99.34 61.85,99.62 62.05,99.82 63.33,99.82 63.53,100.03 63.53,100.31 63.33,100.51 62.05,100.51 61.85,100.72 61.85,100.92 62.05,101.13 63.37,101.13 63.56,101.32 63.56,101.6 63.34,101.82 62.05,101.82 61.85,102.02 61.85,102.37 62.05,102.57 63.31,102.57 63.5,102.77 63.5,103.06 63.29,103.27 62.05,103.27 61.85,103.47 61.85,106.76 60.58,108.03 R752.2 R135.1
  L3_SIG1 w0.109: v5(44.32,98.42) 43.25,99.5 41.62,99.5 40.12,101 39.42,101 39.24,100.82 38.05,100.82 36.42,102.44 v5(35.69,102.44)
PRU1ETH1_RXD2: length 176.2
  TOP w0.173: R136.1 120.78,103.21 v5(120.78,102.57) ; R156.2 34.61,103.59 v5(33.97,102.95) U13.32
  L3_SIG1 w0.109: v5(33.97,102.95) 32.91,101.89 29.86,101.89 29.7,101.73 24.74,101.73 24.62,101.84 24.62,102.24 24.5,102.36 24.34,102.36 24.22,102.24 24.22,101.84 24.11,101.73 23.94,101.73 23.83,101.84 23.83,102.32 23.71,102.43 23.55,102.43 23.43,102.32 23.43,101.84 23.32,101.73 22.83,101.73 22.37,102.18 22.37,102.83 22.26,102.94 20.99,102.94 20.87,103.06 20.87,103.22 20.99,103.34 22.26,103.34 22.37,103.46 22.37,103.62 22.26,103.74 20.99,103.74 20.87,103.85 20.87,104.02 20.99,104.13 22.26,104.13 22.37,104.25 22.37,104.41 22.26,104.53 20.99,104.53 20.87,104.64 20.87,104.81 20.99,104.92 22.26,104.92 22.37,105.04 22.37,105.21 22.26,105.32 20.99,105.32 20.87,105.44 20.87,105.6 20.99,105.72 22.26,105.72 22.37,105.83 22.37,106 22.26,106.11 20.99,106.11 20.87,106.23 20.87,106.39 20.99,106.51 22.26,106.51 22.37,106.63 22.37,106.79 22.26,106.91 20.99,106.91 20.87,107.02 20.87,107.19 20.99,107.3 22.26,107.3 22.37,107.42 22.37,107.85 22.88,108.36 22.88,110.74 22.77,110.85 21.52,110.85 21.41,110.96 21.41,111.18 21.52,111.29 22.77,111.29 22.88,111.4 22.88,111.61 22.77,111.72 21.52,111.72 21.41,111.83 21.41,112.05 21.52,112.16 22.77,112.16 22.88,112.27 22.88,112.49 22.77,112.6 21.52,112.6 21.41,112.71 21.41,112.92 21.52,113.03 22.77,113.03 22.88,113.14 22.88,113.36 22.77,113.47 21.52,113.47 21.41,113.58 21.41,113.8 21.52,113.91 22.77,113.91 22.88,114.02 22.88,114.23 22.77,114.34 21.52,114.34 21.41,114.45 21.41,114.67 21.52,114.78 22.77,114.78 22.88,114.89 22.88,115.11 22.77,115.22 21.67,115.22 21.56,115.33 21.56,115.55 21.67,115.65 22.77,115.65 22.88,115.76 22.88,116.1 23.95,117.18 30.76,117.18 31.65,118.06 40.82,118.06 41.02,117.86 43.48,117.86 48.77,112.58 48.77,111.1 49.33,110.55 51.66,110.55 52.63,109.58 60.48,109.58 60.83,109.94 63.63,109.94 65.45,111.76 66.91,111.76 69.89,114.74 83.65,114.74 83.86,114.95 91.83,114.95 93.04,113.75 97.1,113.75 99.31,111.54 107.14,111.54 109.73,108.95 113.26,108.95 113.69,108.51 115.34,108.51 120.78,103.08 v5(120.78,102.57)
PRU1ETH1_RXD3: length 184.6
  TOP w0.173: U13.1 33.25,103.69 34.29,104.73 v5(35.05,104.73) R155.2 ; R137.1 115.82,102.64 v1(115.89,102.57)
  L3_SIG1 w0.109: v5(35.05,104.73) 37.9,101.88 39.22,101.88 39.45,102.11 41.35,102.11 41.68,101.79 41.68,100.73 42.03,100.37 42.31,100.37 42.56,100.62 42.56,101.23 42.67,101.35 42.84,101.35 42.95,101.23 42.95,100.08 43.09,99.94 43.24,99.94 43.35,100.05 43.35,101.23 43.47,101.35 43.63,101.35 43.75,101.23 43.75,100.05 43.88,99.92 44.03,99.92 44.14,100.03 44.14,100.92 44.26,101.03 44.42,101.03 44.54,100.92 44.54,99.94 44.65,99.83 44.85,99.83 44.98,99.95 44.98,100.29 45.09,100.41 45.26,100.41 45.37,100.29 45.37,99.94 45.48,99.83 45.65,99.83 45.77,99.95 45.77,100.29 45.88,100.41 46.05,100.41 46.17,100.29 46.17,99.94 46.27,99.83 46.44,99.83 46.56,99.95 46.56,100.29 46.68,100.41 46.84,100.41 46.96,100.29 46.96,99.94 47.07,99.83 47.25,99.83 47.37,99.95 47.37,100.31 47.49,100.43 47.65,100.43 47.77,100.31 47.77,99.94 47.88,99.83 48.04,99.83 48.16,99.95 48.16,100.31 48.28,100.43 48.44,100.43 48.56,100.31 48.56,99.94 48.67,99.83 48.79,99.83 48.92,99.95 48.92,100.2 49.03,100.32 49.2,100.32 49.31,100.2 49.31,100.02 49.43,99.9 49.57,99.9 49.79,100.12 49.79,100.6 49.62,100.77 45.09,100.77 44.12,101.73 42.77,101.73 42.43,102.07 42.43,102.68 42.31,102.8 41.86,102.8 41.74,102.91 41.74,103.08 41.86,103.19 42.31,103.19 42.43,103.31 42.43,103.48 42.33,103.59 41.58,103.59 41.47,103.47 41.47,102.54 41.35,102.42 41.19,102.42 41.07,102.54 41.07,104.73 40.95,104.85 40.79,104.85 40.68,104.74 40.68,102.54 40.56,102.42 40.4,102.42 40.28,102.54 40.28,103.45 40.16,103.56 39.75,103.56 39.64,103.45 39.64,103.19 39.52,103.08 39.36,103.08 39.24,103.19 39.24,103.97 39.12,104.1 38.95,104.1 38.84,103.99 38.84,103.19 38.73,103.08 38.56,103.08 38.45,103.19 38.45,103.47 38.33,103.59 38.04,103.59 35.78,105.85 34.95,105.85 34.83,105.96 34.83,106.75 34.72,106.87 34.55,106.87 34.44,106.75 34.44,105.66 34.32,105.54 33.96,105.54 33.85,105.66 33.85,107.69 33.73,107.81 33.57,107.81 33.45,107.69 33.45,105.64 33.34,105.53 33.05,105.53 32.93,105.65 32.93,108.15 32.81,108.27 32.65,108.27 32.53,108.15 32.53,105.7 32.09,105.26 31.65,105.26 30.86,106.05 30.86,112.5 32.91,114.54 42.51,114.54 45.57,111.48 45.57,111.28 49.3,107.55 53.09,107.55 53.67,106.96 54.2,106.96 54.31,107.07 54.31,107.39 54.42,107.5 54.63,107.5 54.74,107.39 54.74,107.07 54.85,106.96 58.16,106.96 58.31,107.11 60.28,107.11 60.73,106.66 64.41,106.66 70.46,112.7 84.58,112.7 85.12,113.24 89.59,113.24 90.86,111.97 95.84,111.97 98.6,109.2 106.4,109.2 109.15,106.45 112.02,106.45 v1(115.89,102.57)
  BOTTOM w0.173: v1(115.89,102.57) 114.68,102.57 R751.2
PRU1ETH1_RXDV: length 177.5
  TOP w0.173: v5(116.97,102.57) 116.97,103.21 R130.1 ; U13.26 34.7,99.16 35,98.86 v5(35,97.92)
  L3_SIG1 w0.109: v5(35,97.92) 35.02,97.93 35.02,104.07 34.79,104.3 33.83,104.3 33.72,104.41 33.72,104.8 33.6,104.92 33.44,104.92 33.32,104.8 33.32,104.41 33.18,104.27 32.61,104.27 32.11,104.78 31.42,104.78 30.37,105.83 30.37,106.68 30.25,106.79 29.74,106.79 29.62,106.68 29.62,105.72 29.51,105.61 29.34,105.61 29.23,105.72 29.23,106.68 29.11,106.79 28.95,106.79 28.83,106.68 28.83,105.72 28.71,105.61 28.55,105.61 28.43,105.72 28.43,106.68 28.32,106.79 28.15,106.79 28.04,106.68 28.04,105.72 27.92,105.61 27.76,105.61 27.64,105.72 27.64,106.68 27.53,106.79 27.32,106.79 27.21,106.91 27.21,107.07 27.32,107.19 30.25,107.19 30.37,107.3 30.37,107.47 30.25,107.58 27.32,107.58 27.21,107.7 27.21,107.86 27.32,107.98 30.25,107.98 30.37,108.1 30.37,108.26 30.25,108.38 27.32,108.38 27.21,108.49 27.21,108.66 27.32,108.77 30.25,108.77 30.37,108.89 30.37,109.05 30.25,109.17 27.32,109.17 27.21,109.29 27.21,109.45 27.32,109.57 30.25,109.57 30.37,109.68 30.37,109.85 30.25,109.96 27.32,109.96 27.21,110.08 27.21,110.24 27.32,110.36 30.25,110.36 30.37,110.47 30.37,110.64 30.25,110.75 27.32,110.75 27.21,110.87 27.21,111.03 27.32,111.15 30.25,111.15 30.37,111.27 30.37,111.43 30.25,111.55 27.32,111.55 27.21,111.66 27.21,111.83 27.32,111.94 30.25,111.94 30.37,112.06 30.37,113.45 32.83,115.92 38.8,115.92 39.22,115.5 39.51,115.5 39.63,115.39 39.63,115.11 39.75,115 39.91,115 40.03,115.11 40.03,115.41 40.14,115.53 40.31,115.53 40.42,115.41 40.42,115.11 40.54,115 40.7,115 40.82,115.11 40.82,115.41 40.94,115.53 41.1,115.53 41.22,115.41 41.22,115.11 41.33,115 41.5,115 41.61,115.11 41.61,115.39 41.73,115.5 42.31,115.5 42.52,115.3 42.67,115.3 42.85,115.47 43,115.47 43.16,115.32 43.16,115.17 42.98,114.99 42.98,114.84 43.13,114.68 43.29,114.68 43.46,114.86 43.62,114.86 43.77,114.7 43.77,114.55 43.6,114.37 43.6,114.22 43.75,114.06 43.91,114.06 44.08,114.24 44.24,114.24 44.39,114.08 44.39,113.93 44.22,113.75 44.22,113.6 44.37,113.44 44.53,113.44 44.7,113.62 44.86,113.62 45.01,113.46 45.01,113.31 44.83,113.13 44.83,112.98 44.99,112.83 45.14,112.83 45.32,113 45.47,113 45.63,112.85 45.63,112.69 45.45,112.52 45.45,112.36 45.61,112.21 45.76,112.21 45.94,112.38 46.09,112.38 46.25,112.23 46.25,112.07 46.07,111.9 46.07,111.74 46.23,111.59 46.38,111.59 46.56,111.76 46.71,111.76 46.86,111.61 46.86,111.46 46.69,111.28 46.69,111.13 46.85,110.97 46.85,110.69 49.53,108.01 60.02,108.01 60.63,107.4 64.52,107.4 70.28,113.16 84.3,113.16 84.84,113.7 89.79,113.7 91.06,112.43 96,112.43 98.74,109.68 106.55,109.68 109.02,107.21 112.6,107.21 113.71,106.11 113.71,105.83 v5(116.97,102.57)
PRU1ETH1_RXERR: length 82.1
  TOP w0.173: R132.1 R753.2 50.44,108.03 50.16,107.75 50.16,107.47 50.37,107.27 51.44,107.27 51.64,107.06 51.64,106.78 51.44,106.58 50.37,106.58 50.16,106.37 50.16,106.09 50.37,105.88 51.44,105.88 51.64,105.68 51.64,104.57 51.44,104.37 49.77,104.37 49.57,104.57 49.57,105.47 49.36,105.67 47.18,105.67 46.98,105.87 46.98,106.16 47.18,106.36 49.36,106.36 49.57,106.56 49.57,106.85 49.36,107.05 47.05,107.05 46.85,107.25 46.85,107.54 47.05,107.74 49.36,107.74 49.57,107.94 49.57,108.34 49.36,108.54 48.42,108.54 48.22,108.74 48.22,114.72 48.02,114.92 47.73,114.92 47.53,114.72 47.53,108.74 47.33,108.54 47.04,108.54 46.84,108.74 46.84,114.72 46.64,114.92 46.35,114.92 46.15,114.72 46.15,108.74 45.95,108.54 45.6,108.54 45.39,108.74 45.39,111.65 45.19,111.85 44.91,111.85 44.7,111.65 44.7,108.74 44.5,108.54 42.86,108.54 42.09,107.77 42.09,104.43 40.34,102.68 40.34,99.47 v5(39.24,98.38) ; U13.28 v5(35.56,100.16)
  L3_SIG1 w0.109: v5(35.56,100.16) 35.56,99.13 36.58,98.1 38.96,98.1 v5(39.24,98.38)
PRU1ETH1_TXCLK: length 187.5
  TOP w0.173: R123.1 v5(114.68,101.17) ; U13.2 v1(32.75,104.86)
  L3_SIG1 w0.109: v5(114.68,101.17) 114.68,101.9 111.09,105.49 v6(109.47,105.49)
  L10_SIG4 w0.109: v6(109.47,105.49) 108.23,106.73 108.23,107.5 106.14,109.59 106.14,111.07 104.77,112.44 104.77,118.41 101.44,121.75 99.1,121.75 98.5,121.15 83.03,121.15 80.33,123.85 75.96,123.85 75.85,123.74 75.85,122.34 75.74,122.23 75.57,122.23 75.45,122.35 75.45,123.74 75.33,123.85 75.17,123.85 75.05,123.74 75.05,122.34 74.94,122.22 74.77,122.22 74.66,122.34 74.66,123.74 74.54,123.85 74.38,123.85 74.26,123.74 74.26,122.34 74.14,122.22 73.98,122.22 73.86,122.34 73.86,123.74 73.75,123.85 72.18,123.85 72.06,123.74 72.06,122.09 71.95,121.97 71.78,121.97 71.67,122.09 71.67,123.74 71.55,123.85 71.39,123.85 71.27,123.74 71.27,122.09 71.16,121.97 70.99,121.97 70.88,122.09 70.88,123.74 70.76,123.85 70.6,123.85 70.48,123.74 70.48,122.09 70.36,121.97 70.2,121.97 70.08,122.09 70.08,123.74 69.97,123.85 69.8,123.85 69.69,123.74 69.69,122.09 69.57,121.97 69.41,121.97 69.29,122.09 69.29,123.74 69.17,123.85 69.01,123.85 68.89,123.74 68.89,122.09 68.78,121.97 68.61,121.97 68.5,122.09 68.5,123.74 68.38,123.85 68.22,123.85 68.1,123.74 68.1,122.09 67.99,121.97 67.82,121.97 67.71,122.09 67.71,123.74 67.59,123.85 67.43,123.85 67.31,123.74 67.31,122.09 67.19,121.97 67.03,121.97 66.91,122.09 66.91,123.74 66.8,123.85 66.63,123.85 66.52,123.74 66.52,122.09 66.4,121.97 66.24,121.97 66.12,122.09 66.12,123.74 65.98,123.88 60.57,123.88 58.54,125.91 42.54,125.91 42.34,125.71 38.73,125.71 38.58,125.86 37.01,125.86 36.86,125.71 28.55,125.71 24.97,122.13 24.97,121.95 23.57,120.55 19.89,120.55 17.06,117.73 16.12,117.73 15.19,116.8 15.19,115.48 15.26,115.41 15.26,108.62 16.56,107.32 17.87,107.32 19.11,108.56 20.31,108.56 23.32,105.55 30.67,105.55 31.37,104.86 v1(32.75,104.86)
PRU1ETH1_TXD0: length 182.5
  TOP w0.173: U13.4 31.75,105.56 v5(31.93,105.75) ; v5(114.64,102.56) 114.55,102.65 R125.1
  L3_SIG1 w0.109: v5(114.64,102.56) 114.58,102.56 111.13,106.01 108.96,106.01 106.22,108.74 98.44,108.74 95.67,111.51 90.68,111.51 89.41,112.78 87.3,112.78 86.81,112.28 86.81,111.95 86.92,111.84 87.7,111.84 87.82,111.72 87.82,111.56 87.7,111.44 86.92,111.44 86.81,111.33 86.81,111.01 86.92,110.9 87.74,110.9 87.85,110.78 87.85,110.62 87.74,110.5 86.92,110.5 86.81,110.39 86.81,109.79 86.69,109.67 86.52,109.67 86.41,109.78 86.41,112.04 86.29,112.15 86.13,112.15 86.01,112.04 86.01,110.52 85.9,110.41 85.73,110.41 85.62,110.52 85.62,112.04 85.5,112.15 84.99,112.15 84.87,112.04 84.87,111.56 84.75,111.45 84.59,111.45 84.47,111.56 84.47,112.04 84.36,112.15 84.19,112.15 84.08,112.04 84.08,111.62 83.96,111.5 83.8,111.5 83.68,111.62 83.68,112.04 83.56,112.15 83.4,112.15 83.28,112.04 83.28,111.62 83.17,111.5 80.09,111.5 79.76,111.17 79.59,111.17 79.48,111.29 79.48,111.88 79.36,111.99 79.2,111.99 79.08,111.88 79.08,111.29 78.97,111.17 78.8,111.17 78.69,111.29 78.69,111.88 78.57,111.99 78.41,111.99 78.29,111.88 78.29,111.29 78.17,111.17 78.01,111.17 77.89,111.29 77.89,111.88 77.78,111.99 77.61,111.99 77.5,111.88 77.5,111.29 77.38,111.17 77.22,111.17 77.1,111.29 77.1,111.88 76.99,111.99 74.2,111.99 73.85,111.64 72.78,111.64 72.67,111.52 72.67,110.89 72.55,110.78 72.39,110.78 72.27,110.89 72.27,111.65 72.15,111.77 71.99,111.77 71.87,111.65 71.87,110.89 71.76,110.78 71.59,110.78 71.48,110.89 71.48,111.65 71.36,111.77 71.2,111.77 71.08,111.65 71.08,110.89 70.96,110.78 70.8,110.78 70.68,110.89 70.68,111.65 70.57,111.77 70.2,111.77 69.65,111.22 69.65,111.06 71.11,109.6 71.11,109.44 70.99,109.32 70.82,109.32 69.37,110.78 69.21,110.78 69.09,110.66 69.09,110.5 70.54,109.04 70.54,108.88 70.43,108.76 70.26,108.76 68.81,110.21 68.64,110.21 68.53,110.1 68.53,109.93 69.98,108.48 69.98,108.31 69.87,108.2 69.7,108.2 68.25,109.65 68.08,109.65 67.97,109.54 67.97,109.37 69.42,107.92 69.42,107.75 69.31,107.64 69.14,107.64 67.69,109.09 67.52,109.09 67.41,108.98 67.41,108.81 68.86,107.36 68.86,107.19 68.75,107.08 68.58,107.08 67.13,108.53 66.96,108.53 66.59,108.16 66.59,108 67.23,107.36 67.23,107.2 67.11,107.08 66.95,107.08 66.31,107.72 66.15,107.72 66.03,107.6 66.03,107.44 66.67,106.8 66.67,106.64 66.55,106.52 66.39,106.52 65.75,107.16 65.59,107.16 65.47,107.04 65.47,106.88 66.11,106.24 66.11,106.08 65.99,105.96 65.83,105.96 65.19,106.6 65.03,106.6 64.56,106.13 60.63,106.13 60.1,106.66 59.33,106.66 58.67,106 57.57,106 57.46,106.11 57.46,106.37 57.36,106.48 57.14,106.48 57.03,106.37 57.03,106.11 56.92,106 56.7,106 56.59,106.11 56.59,106.37 56.48,106.48 56.26,106.48 56.15,106.37 56.15,106.11 56.04,106 55.83,106 55.72,106.11 55.72,106.37 55.61,106.48 55.39,106.48 55.28,106.37 55.28,106.11 55.17,106 53.67,106 52.68,106.99 48.89,106.99 45.01,110.88 45.01,111.39 42.87,113.52 38.99,113.52 38.46,114.05 33.16,114.05 31.32,112.21 31.32,110.6 31.94,109.97 34.78,109.97 39.29,105.47 39.29,105.14 38.59,104.44 37.89,104.44 35.53,106.8 35.53,106.97 36.02,107.46 36.02,107.61 35.9,107.72 35.73,107.72 35.25,107.25 35.09,107.25 34.97,107.36 34.97,107.53 35.52,108.08 35.52,108.25 35.41,108.36 35.24,108.36 34.69,107.81 34.52,107.81 34.41,107.93 34.41,108.09 34.96,108.64 34.96,108.81 34.84,108.92 34.68,108.92 34.13,108.37 33.96,108.37 33.58,108.76 31.96,108.76 31.75,108.54 31.75,105.93 v5(31.93,105.75)
PRU1ETH1_TXD1: length 175.6
  TOP w0.173: R126.1 119.51,103.21 v1(119.51,102.57) ; U13.5 31.25,103.75 v1(31.25,103.75)
  L3_SIG1 w0.109: v1(119.51,102.57) 119.51,103.52 114.97,108.06 113.52,108.06 113.08,108.5 109.51,108.5 106.93,111.08 98.45,111.08 96.29,113.24 91.47,113.24 90.2,114.51 84.38,114.51 84,114.13 69.93,114.13 67.09,111.29 66.23,111.29 65.7,110.75 65.7,109.9 64.69,108.89 60.58,108.89 60.33,109.14 51.61,109.14 51.28,108.82 50.01,108.82 47.96,110.88 47.96,112.76 44.13,116.58 41.47,116.58 40.44,117.61 31.84,117.61 31.04,116.8 31.04,116.26 30.81,116.03 26.8,116.03 26.32,115.55 26.16,115.55 25.79,115.92 25.64,115.92 25.51,115.79 25.51,115.64 25.87,115.27 25.87,115.11 25.76,114.99 25.59,114.99 25.23,115.36 25.08,115.36 24.95,115.23 24.95,115.07 25.44,114.59 25.44,114.42 25.32,114.31 25.16,114.31 24.75,114.72 24.56,114.72 24.44,114.6 24.44,114.46 24.75,114.15 24.75,113.99 24.53,113.77 24.53,113.36 24.42,113.25 23.45,113.25 23.33,113.13 23.33,112.97 23.45,112.85 24.57,112.85 24.69,112.73 24.69,112.56 24.58,112.45 23.45,112.45 23.33,112.34 23.33,112.17 23.45,112.06 24.42,112.06 24.53,111.94 24.53,111.78 24.42,111.66 23.45,111.66 23.33,111.55 23.33,111.38 23.45,111.27 24.42,111.27 24.53,111.15 24.53,110.99 24.42,110.87 23.45,110.87 23.33,110.75 23.33,110.59 23.45,110.47 24.42,110.47 24.53,110.36 24.53,110.19 24.42,110.08 23.45,110.08 23.33,109.96 23.33,109.8 23.45,109.68 24.42,109.68 24.53,109.56 24.53,109.4 24.42,109.28 23.45,109.28 23.33,109.17 23.33,109 23.45,108.89 24.42,108.89 24.53,108.77 24.53,108.61 24.42,108.49 23.45,108.49 23.33,108.38 23.33,108.21 23.45,108.1 24.42,108.1 24.53,107.98 24.53,107.61 24.65,107.5 25.46,107.5 25.57,107.38 25.57,107.22 25.46,107.1 24.65,107.1 24.53,106.99 24.53,106.8 24.42,106.68 22.93,106.68 22.81,106.57 22.81,106.4 22.93,106.29 24.42,106.29 24.53,106.17 24.53,106.01 24.42,105.89 22.93,105.89 22.81,105.78 22.81,105.61 22.93,105.5 24.42,105.5 24.53,105.38 24.53,105.08 24.65,104.96 24.89,104.96 25.01,105.08 25.01,106 25.12,106.12 25.29,106.12 25.4,106 25.4,105.08 25.52,104.96 26.13,104.96 26.24,104.85 26.24,104.68 26.13,104.57 24.65,104.57 24.53,104.45 24.53,103.11 24.73,102.91 24.91,102.91 25.02,103.03 25.02,103.5 25.14,103.62 25.3,103.62 25.42,103.5 25.42,103.03 25.53,102.91 25.7,102.91 25.81,103.03 25.81,103.53 25.93,103.65 26.09,103.65 26.21,103.53 26.21,103.03 26.33,102.91 26.48,102.91 26.6,103.03 26.6,104.78 26.71,104.89 26.88,104.89 26.99,104.78 26.99,103.03 27.11,102.91 27.38,102.91 27.55,103.07 27.55,104.05 27.7,104.2 28.15,104.2 28.29,104.06 28.29,103.26 28.42,103.12 28.5,103.12 28.61,103.01 28.61,102.29 28.72,102.18 28.88,102.18 29.01,102.31 29.01,103.01 29.13,103.12 29.36,103.12 29.48,103.01 29.48,102.44 29.6,102.32 29.76,102.32 29.88,102.44 29.88,103.15 29.98,103.26 30.15,103.26 30.27,103.14 30.27,102.47 30.39,102.35 30.55,102.35 30.67,102.47 30.67,103.01 30.78,103.12 31.06,103.12 31.25,103.32 v1(31.25,103.75)
  BOTTOM w0.173: R749.2 v1(119.51,102.57)
PRU1ETH1_TXD2: length 180.5
  TOP w0.173: R127.1 116.08,100.79 v5(115.82,101.05) ; U13.6 v1(30.75,104.73)
  L3_SIG1 w0.109: v6(109.98,104.98) 111.11,104.98 113.95,102.14 113.95,101.12 114.35,100.72 115.49,100.72 v5(115.82,101.05)
  L10_SIG4 w0.109: v6(109.98,104.98) 109.98,106.38 108.89,107.47 108.89,109.02 108.33,109.58 108.33,116.62 102.2,122.75 89.72,122.75 89.46,123.01 85.35,123.01 83.44,124.92 81.91,124.92 80.21,126.62 76.62,126.62 76.51,126.51 76.51,125.35 76.39,125.24 76.23,125.24 76.11,125.35 76.11,126.51 75.99,126.62 75.83,126.62 75.71,126.51 75.71,125.25 75.6,125.13 75.43,125.13 75.32,125.25 75.32,126.51 75.2,126.62 75.04,126.62 74.92,126.51 74.92,125.25 74.81,125.13 74.64,125.13 74.53,125.25 74.53,126.51 74.41,126.62 74.25,126.62 74.13,126.51 74.13,125.43 74.01,125.31 73.85,125.31 73.73,125.43 73.73,126.64 72.4,127.97 61.49,127.97 61.19,127.67 56.39,127.67 56.03,127.31 53.49,127.31 52.83,127.97 39.57,127.97 39.07,127.46 28.68,127.46 28.14,128 26.01,128 18.78,120.76 15.34,120.76 14.1,119.52 9.46,119.52 5.13,115.19 5.13,112.68 12.95,104.86 18.14,104.86 19.05,105.77 20.14,105.77 21.08,104.83 25.31,104.83 25.59,104.55 29.29,104.55 29.55,104.29 30.3,104.29 v1(30.75,104.73)
PRU1ETH1_TXD3: length 176.1
  TOP w0.173: v1(30.25,103.75) 30.25,103.75 U13.7 ; R128.1 v5(117.47,101.1)
  L3_SIG1 w0.109: v5(117.47,101.1) 116.66,100.28 114.24,100.28 112.46,102.06 112.46,102.68 v6(110.82,104.32)
  L10_SIG4 w0.109: v6(110.82,104.32) 110.82,106.16 109.89,107.08 109.89,111.24 109.37,111.76 109.37,116.16 102.36,123.17 90.32,123.17 88.93,124.56 87.3,124.56 86.03,125.83 84.51,125.83 83.19,127.15 80.73,127.15 80.62,127.26 80.62,127.45 80.51,127.56 80.29,127.56 80.18,127.45 80.18,127.26 80.07,127.15 79.85,127.15 79.74,127.26 79.74,127.45 79.63,127.56 79.41,127.56 79.31,127.45 79.31,127.26 79.2,127.15 78.98,127.15 78.87,127.26 78.87,127.45 78.76,127.56 78.54,127.56 78.43,127.45 78.43,127.26 78.32,127.15 77.31,127.15 77.19,127.26 77.19,127.57 77.08,127.68 76.91,127.68 76.8,127.57 76.8,127.26 76.68,127.15 76.52,127.15 76.4,127.26 76.4,127.57 76.28,127.68 76.12,127.68 76,127.57 76,127.26 75.89,127.15 75.72,127.15 75.61,127.26 75.61,127.57 75.49,127.68 75.33,127.68 75.21,127.57 75.21,127.26 75.09,127.15 74.93,127.15 73.61,128.47 64.65,128.47 64.01,129.11 63.25,129.11 62.46,128.33 57.41,128.33 57.2,128.54 39.58,128.54 39.21,128.17 35.71,128.17 35.43,128.45 25.99,128.45 20.12,122.58 17.6,122.58 16.89,121.87 15.8,121.87 14.3,120.38 9.8,120.38 4.78,115.35 4.78,112.04 12.32,104.5 18.03,104.5 18.77,103.76 21.26,103.76 21.36,103.87 24.31,103.87 24.71,103.46 25.86,103.46 26.59,104.2 29.16,104.2 29.6,103.75 v1(30.25,103.75)
PRU1ETH1_TXEN: length 178
  TOP w0.173: U13.3 32.25,104.03 v1(32.23,104.03) ; v5(119.38,101.78) 119.38,101.3 R124.1
  L3_SIG1 w0.109: v5(119.38,101.78) 119.05,102.11 115.73,102.11 112.04,105.8 v6(111.96,105.8)
  L10_SIG4 w0.109: v1(32.23,104.03) 30.89,102.7 28.91,102.7 28.3,103.31 26.19,103.31 25.3,102.42 21.69,102.42 20.75,103.36 18.8,103.36 17.73,102.29 13.82,102.29 4.37,111.74 4.37,115.47 9.81,120.91 14.25,120.91 16.23,122.89 16.89,122.89 17.32,123.32 20.32,123.32 25.81,128.81 35.74,128.81 35.86,128.68 38.18,128.68 38.51,129.01 57.38,129.01 57.71,128.68 62.08,128.68 62.92,129.52 64.08,129.52 64.69,128.91 73.86,128.91 74.68,128.09 80.78,128.09 81.03,127.84 83.44,127.84 84.05,127.23 85.6,127.23 86.08,126.75 86.77,126.75 87.58,125.93 88.75,125.93 90.53,124.15 101.92,124.15 110.34,115.73 110.34,111.8 110.94,111.2 110.94,110.39 110.92,110.38 110.92,106.84 v6(111.96,105.8)
PRU1ETHER0_RDN: length 23.1
  BOTTOM w0.108: U9.9 19.71,121.3 19.71,121.88 18.73,122.85 18.73,123.14 R99.2 18.73,123.91 18.73,124.15 15.62,127.26 15.62,136.15 16.18,136.71 18.09,136.71 18.97,135.82 18.97,134.7 J3.2
PRU1ETHER0_RDP: length 23.2
  BOTTOM w0.108: J3.1 17.93,134.47 18.39,134.47 18.72,134.8 18.72,135.72 17.98,136.45 16.28,136.45 15.88,136.05 15.88,127.36 18.98,124.26 18.98,123.91 R100.2 18.98,123.14 18.98,122.96 19.96,121.98 19.96,121.3 U9.10
PRU1ETHER0_TDN: length 21.1
  BOTTOM w0.108: 19.69,128.91 19.24,128.45 18.21,128.45 18.06,128.61 18.06,129.01 19.04,129.99 20.58,129.99 20.93,129.64 20.93,128.68 21.54,128.07 22.33,128.07 22.61,127.79 ; 22.61,127.79 22.89,128.07 23.72,128.07 23.93,127.87 23.93,126.4 22.45,124.92 22.27,124.92 21.44,125.75 21.05,125.75 20.77,125.48 20.77,125.09 21.61,124.25 21.61,124.07 21.28,123.75 21.28,123.2 20.71,122.62 20.71,121.3 U9.11 ; 22.61,127.79 R101.2
PRU1ETHER0_TDP: length 21.3
  BOTTOM w0.108: J3.5 17.15,129.18 17.32,129.01 17.7,129.01 18.94,130.24 20.69,130.24 21.18,129.75 21.18,128.78 21.64,128.33 22.3,128.33 22.61,128.63 ; 22.61,128.63 R102.2 ; 22.61,128.63 22.91,128.33 23.83,128.33 24.18,127.97 24.18,126.29 22.55,124.66 22.17,124.66 21.33,125.5 21.15,125.5 21.03,125.37 21.03,125.19 21.86,124.36 21.86,123.97 21.54,123.64 21.54,123.08 20.96,122.51 20.96,121.3 U9.12
PRU1ETHER1_RDN: length 24.3
  TOP w0.108: U13.9 28.7,102.16 28.6,102.06 27.81,102.06 26.29,103.59 26.29,104.94 25.26,105.97 24.79,105.97 R143.2 24.03,106.02 23.13,106.02 22.66,105.55 22.66,103.92 22.45,103.71 22.2,103.71 22.1,103.82 22.1,106.69 21.78,107 21.35,107 21.02,106.67 21.02,103.84 20.89,103.71 18.9,103.71 18.55,104.06 18.55,105.35 18.75,105.54 19.08,105.54 19.69,104.93 J5.6
PRU1ETHER1_RDP: length 24.3
  TOP w0.108: J5.5 18.3,104.9 18.3,103.96 18.8,103.46 20.99,103.46 21.27,103.74 21.27,106.57 21.45,106.75 21.68,106.75 21.84,106.58 21.84,103.71 22.1,103.46 22.56,103.46 22.91,103.81 22.91,105.45 23.24,105.77 23.98,105.77 R144.2 24.74,105.72 25.15,105.72 26.03,104.83 26.03,103.48 27.71,101.81 28.58,101.81 28.72,101.66 U13.10
PRU1ETHER1_TDN: length 26
  TOP w0.108: J5.2 19.68,109.87 19.68,109.92 19.1,110.49 18.55,110.49 18.46,110.41 18.46,110.16 18.08,109.78 16.61,109.78 15.85,109.02 15.85,103.1 17.96,101 21.69,101 22.58,101.88 23.95,101.88 R145.2 24.84,101.86 25.78,101.86 26.6,101.05 28.58,101.05 28.69,101.16 U13.11
PRU1ETHER1_TDP: length 26.3
  TOP w0.108: J5.1 17.63,110.65 18.08,110.65 18.21,110.52 18.21,110.27 17.98,110.04 16.51,110.04 15.6,109.13 15.6,103 17.85,100.74 21.79,100.74 22.68,101.63 23.93,101.63 R146.2 24.82,101.6 25.68,101.6 26.49,100.79 28.58,100.79 28.71,100.66 U13.12
PRU2ETH0_25MHZCLK: length 38.1
  TOP w0.173: U15.23 32.75,79.22 33.66,78.31 v5(33.66,76.79)
  L3_SIG1 w0.109: v5(33.66,76.79) v6(34.42,76.79)
  L9_SIG3 w0.114: v6(34.42,76.79) 35.31,77.68 35.31,86.82 39.24,90.76 v6(39.24,94.82)
  L10_SIG4 w0.109: v9(52.07,94.82) v6(39.24,94.82)
  BOTTOM w0.173: R354.2 v9(52.07,94.82)
PRU2ETH0_COL: length 365.4
  TOP w0.173: v1(40,81.64) 39.98,81.66 37.54,81.66 36.83,82.38 R187.2 36.45,82.88 U15.29 ; R188.1 v5(121.54,78.06)
  L3_SIG1 w0.109: v1(40,81.64) 36.22,81.64 33.69,84.17 22.77,84.17 20.57,81.97 18.8,81.97 17.81,82.96 16.23,82.96 15.39,82.12 v1(7.37,82.12) ; v5(121.54,78.06) v6(123.99,78.06)
  L4_SIG2 w0.114: v6(123.99,78.06) 124.53,77.52 129.7,77.52 130.37,78.19 149.46,78.19 160.28,67.37 161.5,67.37 168.61,60.26 168.61,46.58 168.02,45.99 168.02,44.66 167.64,44.28 167.64,35.74 158.28,26.37 155.45,26.37 144.61,15.53 138.89,15.53 132.94,9.58 122.08,9.58 121.24,8.74 114.73,8.74 113.49,9.99 105.6,9.99 104.96,9.35 98.5,9.35 97.9,9.95 93.26,9.95 92.52,10.69 69.25,10.69 68.46,11.48 56.74,11.48 56.18,10.92 55.56,10.92 50.8,6.15 34.3,6.15 33.49,5.34 33.06,5.34 32.11,4.39 30.11,4.39 22.85,11.65 22.85,24.89 24.56,26.59 24.56,34.1 25.14,34.68 25.14,39.12 25.41,39.39 25.41,49.05 28.84,52.48 28.84,60.49 28.44,60.89 28.44,70.47 29.47,71.5 29.47,72.59 38.52,81.64 v1(40,81.64)
  BOTTOM w0.173: R189.2 v1(7.37,82.12)
PRU2ETH0_CRS: length 3.7
  TOP w0.173: R177.1 34.91,81.88 U15.27
PRU2ETH0_INTN: length 180.7
  TOP w0.173: U15.8 29.75,86.44 29.63,86.56 29.63,89.96 v1(29.08,90.51)
  L3_SIG1 w0.109: v6(115.06,118.29) 115.06,118.93 112.24,121.75 111.84,121.75 110.11,123.47 110.11,124.42 106.56,127.97 104.62,127.97 103.48,129.11 103.48,130.12 103.12,130.48 100.38,130.48 98.98,131.88 96.45,131.88 95.99,132.34 91.01,132.34 90.53,131.86 87.56,131.86 86.45,132.96 63.76,132.96 59.07,128.27 40.09,128.27 38.46,126.64 38.45,126.64 37.56,125.76 30.63,125.76 29.87,126.52 24.42,126.52 19.56,121.66 19.56,117.65 19.55,117.64 19.55,117.22 19.56,117.21 19.56,114.28 18.52,113.24 18.52,107.84 18.49,107.81 18.49,101.74 18.5,101.73 18.5,100.81 24.26,95.04 31.15,95.04 31.67,94.52 31.67,92.21 30.8,91.33 29.91,91.33 v1(29.08,90.51)
  L10_SIG4 w0.109: v9(115.06,117.68) v6(115.06,118.29)
  BOTTOM w0.173: R671.2 111.38,104.55 108.38,107.55 108.38,110.49 108.97,111.08 111.63,111.08 115.06,114.51 v9(115.06,117.68)
PRU2ETH0_LINKLED: length 26.9
  TOP w0.173: v1(27.27,78.65) 27.38,78.54 27.38,78.52 27.84,78.06 R159.1 28.52,78.38 28.52,79.17 28.86,79.52 29.34,79.52 29.75,79.93 U15.17
  L4_SIG2 w0.114: v1(7.37,83.27) 16.64,83.27 16.65,83.25 17.41,83.25 18.85,81.81 23.27,81.81 26.42,78.65 v1(27.27,78.65)
  BOTTOM w0.173: R176.2 v1(7.37,83.27)
PRU2ETH0_MDC: length 2.4
  TOP w0.173: R179.1 31.25,78.7 U15.20
PRU2ETH0_MDIO: length 2.6
  TOP w0.173: U15.19 30.75,79.21 R181.1
PRU2ETH0_RESETN: length 11.1
  TOP w0.173: v1(29.13,78.94) 29.66,78.94 30.25,79.52 U15.18
  BOTTOM w0.173: v1(29.13,78.94) 29.13,76.33 28.45,75.65 26.2,75.65 25.51,74.96 U70.4
PRU2ETH0_RXCLK: length 4.6
  TOP w0.173: R165.1 35.56,78.95 35.56,79.58 34.26,80.88 U15.25
PRU2ETH0_RXD0: length 3.7
  TOP w0.173: U15.30 36,83.38 v1(36.1,83.49) 36.13,83.52 R194.2
  BOTTOM w0.173: R194.2 36.13,83.52 v1(36.1,83.49)
PRU2ETH0_RXD1: length 4.1
  TOP w0.173: U15.31 35.22,83.88 v1(35.97,84.63) 36.8,84.63 R193.2
  BOTTOM w0.173: v1(35.97,84.63) 36.8,84.63 R193.2
PRU2ETH0_RXD2: length 4.3
  TOP w0.173: U15.32 34.52,84.38 v1(35.94,85.81) R192.2
  BOTTOM w0.173: R192.2 v1(35.94,85.81)
PRU2ETH0_RXD3: length 5.6
  TOP w0.173: R191.2 v1(36.07,86.95) 34.23,86.95 33.25,85.97 U15.1
  BOTTOM w0.173: R191.2 v1(36.07,86.95)
PRU2ETH0_RXDV: length 4.1
  TOP w0.173: U15.26 34.65,81.38 36.2,79.84 36.2,79.46 R166.1
PRU2ETH0_RXERR: length 3.4
  TOP w0.173: R170.1 35.56,82.38 U15.28
PRU2ETH0_TXCLK: length 297.9
  TOP w0.173: 124.59,82.76 v5(125.98,82.76) ; U15.2 v1(32.75,87.05)
  L3_SIG1 w0.109: v6(130.86,82.73) 130.63,82.5 129.06,82.5 128.47,83.09 126.67,83.09 126.34,82.76 v5(125.98,82.76)
  L10_SIG4 w0.109: v6(130.86,82.73) 130.86,81.54 130.3,80.98 130.3,77.55 133.35,74.5 135.74,74.5 136.09,74.85 152.96,74.85 160.76,67.06 160.76,61.7 162.43,60.03 162.43,47.37 162.05,46.99 161.67,46.99 161.3,46.63 161.15,46.63 160.84,46.94 160.68,46.94 160.53,46.79 160.53,46.63 160.84,46.32 160.84,46.16 160.69,46.01 160.53,46.01 160.22,46.32 160.06,46.32 159.91,46.17 159.91,46.01 160.22,45.7 160.22,45.55 160.07,45.39 159.91,45.39 159.6,45.7 159.45,45.7 159.29,45.55 159.29,45.39 159.6,45.08 159.6,44.93 158.27,43.59 158.27,34.12 148.41,24.26 138.81,24.26 131.82,17.27 126.15,17.27 125.88,17 125.87,17 125.6,16.73 125.6,16.47 119.75,10.62 108.43,10.62 107.72,11.33 104.44,11.33 103.38,10.27 75.11,10.27 74.22,11.15 63.68,11.15 63.68,11.15 63.32,11.15 63.32,11.15 59.61,11.15 59,11.77 57.76,11.77 51.49,18.03 47.09,18.03 34.34,30.78 34.34,33.86 31.84,36.36 31.84,37.71 30.96,38.59 28.96,38.59 24.99,42.55 24.99,47.91 22.58,50.32 22.58,63.07 33.22,73.72 33.22,86.57 v1(32.75,87.05)
PRU2ETH0_TXD0: length 297.6
  TOP w0.173: v1(31.78,87.53) 31.75,87.5 U15.4 ; 124.59,81.62 v5(125.35,81.62)
  L3_SIG1 w0.109: v5(125.35,81.62) 126.64,81.62 127.38,82.35 128.17,82.35 128.83,81.69 v6(130.16,81.69)
  L10_SIG4 w0.109: v1(31.78,87.53) 33.17,87.53 33.66,87.05 33.66,73.41 23.01,62.77 23.01,50.63 25.35,48.29 25.35,43.72 30.06,39.01 31.17,39.01 32.33,37.85 32.33,36.37 34.68,34.03 34.68,30.93 47.07,18.54 52.23,18.54 52.91,17.86 54.91,17.86 58.24,14.53 58.24,13.54 58.8,12.98 60.55,12.98 62.03,11.51 93.09,11.51 93.25,11.66 95.66,11.66 95.96,11.36 102.79,11.36 103.73,12.3 104.95,12.3 105.44,11.81 107.98,11.81 108.81,10.98 119.38,10.98 125.26,16.86 125.26,16.87 125.73,17.33 125.74,17.33 126.86,18.45 132.16,18.45 138.61,24.9 148.39,24.9 155.26,31.77 155.26,31.93 155.04,32.16 155.04,32.31 155.19,32.46 155.35,32.46 155.57,32.24 155.73,32.24 155.88,32.39 155.88,32.55 155.66,32.77 155.66,32.93 155.81,33.08 155.97,33.08 156.19,32.86 156.35,32.86 156.5,33.01 156.5,33.17 156.27,33.39 156.27,33.55 156.43,33.7 156.58,33.7 156.81,33.47 156.96,33.47 157.12,33.63 157.12,33.78 156.89,34.01 156.89,34.16 157.05,34.32 157.2,34.32 157.43,34.09 157.58,34.09 157.91,34.42 157.91,45.01 162.05,49.15 162.05,59.75 160.4,61.4 160.4,66.88 153.8,73.49 133.86,73.49 133.35,74 131.93,74 129.92,76 129.92,81.46 v6(130.16,81.69)
PRU2ETH0_TXD1: length 302.4
  TOP w0.173: 124.59,83.9 v5(125.98,83.9) ; v1(31.25,85.97) 31.25,85.97 U15.5
  L3_SIG1 w0.109: v6(131.95,82.86) 131.39,83.42 129.67,83.42 129.39,83.7 126.19,83.7 v5(125.98,83.9)
  L10_SIG4 w0.109: v6(131.95,82.86) 132.59,82.22 132.59,77.29 134.11,75.77 153.04,75.77 163.22,65.59 163.22,44.15 162.87,43.8 162.72,43.8 162.25,44.26 162.1,44.26 161.94,44.11 161.94,43.96 162.41,43.49 162.41,43.34 162.25,43.18 162.1,43.18 161.63,43.65 161.48,43.65 161.32,43.49 161.32,43.34 161.79,42.87 161.79,42.72 161.63,42.56 161.48,42.56 161.01,43.03 160.86,43.03 160.7,42.87 160.7,42.72 161.17,42.25 161.17,42.1 161.01,41.94 160.86,41.94 160.4,42.41 160.24,42.41 160.09,42.26 160.09,42.1 160.55,41.64 160.55,41.48 160.4,41.33 160.24,41.33 159.78,41.79 159.62,41.79 159.47,41.64 159.47,41.48 159.93,41.02 159.93,40.86 159.05,39.98 159.05,33.84 148.11,22.89 139.07,22.89 132.59,16.41 127.3,16.41 119.76,8.87 114.12,8.87 113.39,9.6 105.23,9.6 104.64,9.02 72.57,9.02 72.01,9.58 59.8,9.58 58.57,10.8 55.67,10.8 49.76,16.71 47.45,16.71 33.52,30.64 33.52,32.95 32.05,34.42 29.46,34.42 28.93,34.95 28.93,36.66 28.58,37.01 28.04,37.01 27.3,37.75 27.3,38.97 23.6,42.68 23.6,46.64 21.82,48.42 21.82,65.28 31.25,74.71 31.25,80.97 31.01,81.21 31.01,84.66 31.25,84.89 v1(31.25,85.97)
PRU2ETH0_TXD2: length 305.8
  TOP w0.173: R168.1 121.37,82.84 v5(121.79,82.84) ; U15.6 v1(30.75,86.95)
  L3_SIG1 w0.109: v6(132.14,81.92) 130.89,81.92 130.66,82.15 128.88,82.15 128.32,82.71 127.11,82.71 126.65,82.25 125.68,82.25 125.46,82.47 122.64,82.47 122.27,82.84 v5(121.79,82.84)
  L10_SIG4 w0.109: v1(30.75,86.95) 32.16,86.95 32.77,86.34 32.77,84.66 32.03,83.93 32.03,77.04 32.54,76.54 32.54,74.1 25.09,66.65 24.16,66.65 22.2,64.7 22.2,48.67 24.03,46.84 24.03,42.85 28.95,37.93 28.95,37.55 29.46,37.04 29.89,37.04 30.35,36.58 30.35,36.07 30.61,35.81 31.88,35.81 33.86,33.83 33.86,30.78 47.22,17.42 51.59,17.42 53.86,15.16 53.86,14.6 57.17,11.28 58.85,11.28 59.99,10.14 73.91,10.14 74.66,9.4 104.46,9.4 105.13,10.07 114.09,10.07 114.48,9.68 120.05,9.68 127.3,16.94 132.2,16.94 138.84,23.58 148.23,23.58 158.67,34.02 158.67,41.79 159.84,42.95 159.84,43.11 159.53,43.42 159.53,43.58 159.68,43.73 159.83,43.73 160.15,43.42 160.3,43.42 160.46,43.57 160.46,43.73 160.14,44.04 160.14,44.2 160.3,44.35 160.45,44.35 160.77,44.04 160.92,44.04 161.08,44.19 161.08,44.35 160.76,44.66 160.76,44.81 160.92,44.97 161.07,44.97 161.39,44.65 161.54,44.65 162.86,45.98 162.86,65.44 152.99,75.31 135.66,75.31 135.23,74.88 133.48,74.88 131.62,76.74 131.62,80.62 132.14,81.14 v6(132.14,81.92)
PRU2ETH0_TXD3: length 302.9
  TOP w0.173: U15.7 30.25,86.22 v1(30.23,86.24) ; 124.59,85.17 v5(127.86,85.17)
  L3_SIG1 w0.109: v6(132.94,84.05) 131.65,85.35 128.04,85.35 v5(127.86,85.17)
  L10_SIG4 w0.109: v1(30.23,86.24) 28.68,84.69 28.68,75.62 20.9,67.85 20.9,41.76 26.95,35.72 26.95,35.06 28.83,33.18 29.49,33.18 36.58,26.09 37.11,26.09 47.62,15.57 48.67,15.57 55.6,8.64 70.94,8.64 72.55,7.04 95.73,7.04 96.19,7.5 100.43,7.5 100.84,7.09 118.87,7.09 119.5,7.72 122.44,7.72 129.77,15.04 144.15,15.04 159.84,30.74 159.84,36.63 161.42,38.21 161.58,38.21 161.81,37.98 161.96,37.98 162.11,38.14 162.11,38.29 161.89,38.52 161.89,38.67 164.08,40.87 164.08,56.16 165.18,57.26 165.18,64.73 156.46,73.44 156.46,76.03 154.53,77.96 135.97,77.96 133.81,80.12 133.81,83.19 v6(132.94,84.05)
PRU2ETH0_TXEN: length 305.9
  TOP w0.173: v1(32.23,86.25) 32.25,86.25 U15.3 ; R167.1 v5(121.54,84.54)
  L3_SIG1 w0.109: v6(132.23,83.7) 130.94,84.99 128.55,84.99 128.25,84.69 127.3,84.69 126.64,85.35 123.72,85.35 122.91,84.54 v5(121.54,84.54)
  L10_SIG4 w0.109: v6(132.23,83.7) 132.99,82.94 132.99,78.14 134.44,76.69 152.61,76.69 152.84,76.46 152.84,76.45 164.47,64.83 164.47,57.43 163.7,56.67 163.7,43.77 159.44,39.5 159.44,33.66 148.13,22.36 139.4,22.36 132.89,15.85 129.11,15.85 121.56,8.31 109.04,8.31 108.79,8.06 106.65,8.06 106.27,8.44 90.4,8.44 89.97,8 72.62,8 71.54,9.08 55.64,9.08 48.51,16.21 47.47,16.21 33.19,30.49 33.19,32.73 32.02,33.89 28.88,33.89 27.53,35.23 27.53,36.02 22.05,41.51 22.05,47.5 21.36,48.19 21.36,66.78 27.91,73.33 29.39,73.33 30.1,74.05 30.1,79.99 29.39,80.7 29.39,84.74 31.14,86.49 31.98,86.49 v1(32.23,86.25)
PRU2ETH1_25MHZCLK: length 61.3
  TOP w0.173: U17.23 32.75,54.71 33.91,53.55 v5(33.91,52.99)
  L3_SIG1 w0.109: v5(33.91,52.99) v6(33.91,52.41)
  L9_SIG3 w0.114: v6(38.48,94.32) 38.48,90.63 34.86,87.01 34.86,80.99 33.4,79.53 33.4,67.77 33.91,67.26 v6(33.91,52.41)
  L10_SIG4 w0.109: v9(50.8,94.32) v6(38.48,94.32)
  BOTTOM w0.173: R357.2 v9(50.8,94.32)
PRU2ETH1_COL: length 351.7
  TOP w0.173: U17.29 35.18,58.12 35.56,57.74 v1(36.07,57.74) 36.83,57.74 37.55,57.02 38.85,57.02 39.58,57.74 40.77,57.74 41.62,58.59 41.62,64.64 40.26,65.99 24.38,65.99 21.97,68.41 7.03,68.41 4.57,65.95 4.57,59.9 v1(7.37,57.1) ; 124.59,74.76 v5(125.35,74.76)
  L3_SIG1 w0.109: v5(125.35,74.76) 124.71,74.76 v6(124.59,74.63)
  L4_SIG2 w0.114: v1(36.07,57.74) 36.07,52.66 30.9,47.49 30.9,43.77 28.95,41.82 28.95,27.81 24.89,23.76 24.89,11.33 29.15,7.07 50.48,7.07 53.55,10.15 53.55,10.36 56.15,12.95 56.85,12.95 57.06,13.16 60.12,13.16 61.08,14.12 72.31,14.12 72.85,13.58 98.99,13.58 100.21,12.36 102.33,12.36 102.73,12.76 105.12,12.76 106.28,11.6 116.54,11.6 117.17,12.23 128.82,12.23 128.86,12.26 128.89,12.26 129.14,12.52 129.14,12.55 140.33,23.74 146.5,23.74 151.51,28.75 156.78,28.75 164.78,36.74 164.78,38.66 164.03,39.4 164.03,54.19 166.02,56.17 166.02,60.38 160.78,65.62 159.55,65.62 149.32,75.85 146.44,75.85 145.02,77.27 131.41,77.27 130.64,76.49 123.97,76.49 123.6,76.12 123.6,75.61 124.59,74.63 v6(124.59,74.63)
  BOTTOM w0.173: R231.1 v1(7.37,57.1) ; R232.1 v1(36.07,57.74)
PRU2ETH1_CRS: length 3.7
  TOP w0.173: R219.1 34.91,57.12 U17.27
PRU2ETH1_INTN: length 138.2
  TOP w0.173: v1(108.58,121.72) 112.39,117.91 112.39,112.05 114.77,109.67 114.77,108.22 113.54,106.99 112.93,106.99 111.63,105.7 R672.2 ; U17.8 v1(29.75,61.87)
  BOTTOM w0.173: v1(108.58,121.72) 103.21,121.72 100.21,118.72 100.21,117.75 96.27,113.81 96.27,112.63 79.68,96.04 71.14,96.04 70.61,96.58 67.22,96.58 67.14,96.66 65.97,96.66 62.48,93.17 62.48,86.11 55.63,79.25 55.63,69.85 50.27,64.49 35.34,64.49 32.72,61.87 v1(29.75,61.87)
PRU2ETH1_LINKLED: length 26.6
  TOP w0.173: v1(27.3,53.68) 27.69,53.29 R200.1 28.67,53.77 28.67,54.24 29.75,55.31 U17.17
  L4_SIG2 w0.114: v1(27.3,53.68) 24.76,53.68 21.34,57.1 18.89,57.1 17.5,58.49 v1(7.86,58.49)
  BOTTOM w0.173: R218.2 v1(7.86,58.49)
PRU2ETH1_MDC: length 2.4
  TOP w0.173: U17.20 31.25,54.48 30.99,54.22 30.99,53.68 R221.1
PRU2ETH1_MDIO: length 5.2
  TOP w0.173: R201.1 29.03,51.69 29.03,52.73 29.59,53.29 R223.1 29.59,53.45 30.75,54.61 U17.19
PRU2ETH1_RESETN: length 11.6
  TOP w0.173: U17.18 30.25,54.82 v1(29.73,54.3)
  BOTTOM w0.173: U71.4 25.51,50.2 26.47,51.16 27.74,51.16 28.2,50.69 28.8,50.69 29.73,51.62 v1(29.73,54.3)
PRU2ETH1_RXCLK: length 4.6
  TOP w0.173: U17.25 34.26,56.12 35.43,54.95 35.43,54.31 R209.1
PRU2ETH1_RXD0: length 3.7
  TOP w0.173: R238.2 36.13,58.76 v1(36.1,58.72) 36,58.62 U17.30
  BOTTOM w0.173: v1(36.1,58.72) 36.13,58.76 R238.2
PRU2ETH1_RXD1: length 4.1
  TOP w0.173: R237.2 36.01,59.9 v1(35.97,59.87) 35.22,59.12 U17.31
  BOTTOM w0.173: R237.2 36.01,59.9 v1(35.97,59.87)
PRU2ETH1_RXD2: length 4.3
  TOP w0.173: U17.32 34.52,59.62 v1(35.94,61.04) R236.2
  BOTTOM w0.173: v1(35.94,61.04) R236.2
PRU2ETH1_RXD3: length 5.6
  TOP w0.173: R235.2 v1(36.07,62.18) 34.23,62.18 33.25,61.2 U17.1
  BOTTOM w0.173: R235.2 v1(36.07,62.18)
PRU2ETH1_RXDV: length 53.3
  TOP w0.173: U17.26 34.65,56.62 35.94,55.33 35.94,54.95 R211.1 37.39,54.61 39.31,54.61 52.11,67.41 52.11,74.95 54.84,77.69 54.84,84.53 53.75,85.63 47.96,85.63 R117.2
PRU2ETH1_RXERR: length 3.4
  TOP w0.173: R212.1 36.07,57.1 35.47,57.1 34.96,57.62 U17.28
PRU2ETH1_TXCLK: length 113.3
  TOP w0.173: U17.2 32.75,61.66 33.02,61.93 33.02,63.56 v1(32.75,63.84) ; R204.1 v5(77.09,95.97)
  L3_SIG1 w0.109: v5(77.09,95.97) v6(76.45,95.97)
  L10_SIG4 w0.109: v1(32.75,63.84) 35.2,66.29 35.2,66.78 42.53,74.11 53.33,74.11 55.68,76.46 56.71,76.46 56.82,76.35 56.82,76.02 56.93,75.9 57.1,75.9 57.21,76.02 57.21,76.73 57.33,76.84 57.49,76.84 57.61,76.73 57.61,76.02 57.73,75.9 57.89,75.9 58.01,76.02 58.01,76.35 58.12,76.46 58.29,76.46 58.4,76.35 58.4,75.89 58.52,75.77 58.68,75.77 58.8,75.89 58.8,76.45 58.94,76.59 59.28,76.59 59.45,76.42 59.45,75.62 59.59,75.48 59.78,75.48 59.93,75.62 59.93,76.75 60.06,76.89 60.32,76.89 60.48,76.73 60.48,75.65 60.7,75.43 63.1,75.43 63.21,75.54 63.21,76.7 63.35,76.84 66.99,76.84 67.1,76.95 67.1,77.88 66.96,78.02 64.3,78.02 64.16,78.16 64.16,78.36 64.3,78.5 66.96,78.5 67.1,78.64 67.1,78.84 66.96,78.98 64.3,78.98 64.16,79.12 64.16,79.32 64.3,79.46 66.96,79.46 67.1,79.6 67.1,79.8 66.96,79.94 64.3,79.94 64.16,80.08 64.16,80.28 64.3,80.42 65.82,80.42 65.96,80.56 65.96,80.76 65.82,80.9 64.95,80.9 64.81,81.04 64.81,81.24 64.96,81.38 66.48,81.38 66.62,81.52 66.62,81.72 66.48,81.86 64.38,81.86 64.24,82 64.24,82.89 64.4,83.06 66.27,83.06 66.42,83.2 66.42,83.66 67.6,84.85 68.04,84.85 69.02,85.84 69.02,86 68.42,86.61 68.42,86.76 68.57,86.91 68.73,86.91 69.33,86.31 69.49,86.31 69.64,86.46 69.64,86.62 69.03,87.22 69.03,87.38 69.19,87.53 69.34,87.53 69.95,86.92 70.11,86.92 70.26,87.08 70.26,87.23 69.65,87.84 69.65,88 69.81,88.15 69.96,88.15 70.57,87.54 70.72,87.54 70.88,87.7 70.88,87.85 70.27,88.46 70.27,88.61 70.43,88.77 70.58,88.77 71.19,88.16 71.34,88.16 71.5,88.32 71.5,88.47 70.89,89.08 70.89,89.23 71.04,89.39 71.2,89.39 71.81,88.78 71.96,88.78 72.12,88.93 72.12,89.09 71.51,89.7 71.51,89.85 71.66,90.01 71.82,90.01 72.43,89.4 72.58,89.4 73.13,89.94 73.13,90.14 72.57,90.69 72.57,90.89 72.71,91.03 72.91,91.03 73.34,90.61 73.54,90.61 73.68,90.75 73.68,90.95 73.25,91.37 73.25,91.57 73.66,91.98 73.66,94.7 74.3,95.33 75.82,95.33 v6(76.45,95.97)
PRU2ETH1_TXD0: length 112.7
  TOP w0.173: v1(31.75,63.2) 31.5,62.95 31.5,61.93 31.75,61.68 U17.4 ; R206.1 v5(77.09,94.95)
  L3_SIG1 w0.109: v5(77.09,94.95) v6(76.45,94.95)
  L10_SIG4 w0.109: v1(31.75,63.2) 32.97,63.2 36.08,66.31 36.08,66.75 42.89,73.56 55.83,73.56 55.94,73.66 55.94,74.39 56.05,74.5 57.1,74.5 57.21,74.39 57.21,73.66 57.32,73.56 57.8,73.56 57.97,73.72 57.97,74.48 58.11,74.62 58.3,74.62 58.45,74.48 58.45,73.95 58.59,73.81 58.78,73.81 58.93,73.95 58.93,74.99 59.07,75.13 59.26,75.13 59.41,74.99 59.41,73.67 59.52,73.56 60.33,73.56 60.44,73.67 60.44,74.35 60.66,74.56 62.31,74.56 62.75,74.12 63.58,74.12 63.76,74.3 63.76,76.34 63.9,76.48 64.1,76.48 64.24,76.34 64.24,73.99 64.38,73.85 64.58,73.85 64.72,73.99 64.72,76.34 64.86,76.48 65.06,76.48 65.2,76.34 65.2,73.99 65.34,73.85 65.54,73.85 65.68,73.99 65.68,76.34 65.82,76.48 66.02,76.48 66.16,76.34 66.16,73.99 66.3,73.85 67.26,73.85 68.83,75.43 69.55,75.43 70.81,76.69 70.81,77.88 70.67,78.02 67.84,78.02 67.7,78.16 67.7,78.36 67.84,78.5 70.67,78.5 70.81,78.64 70.81,78.84 70.67,78.98 67.84,78.98 67.7,79.12 67.7,79.32 67.84,79.46 70.67,79.46 70.81,79.6 70.81,79.8 70.67,79.94 67.84,79.94 67.7,80.08 67.7,80.28 67.84,80.42 70.67,80.42 70.81,80.56 70.81,80.76 70.67,80.9 70.03,80.9 69.88,81.04 69.88,81.24 70.03,81.38 70.67,81.38 70.81,81.52 70.81,87.02 74.04,90.25 74.04,91.82 74.15,91.93 74.69,91.93 74.8,92.04 74.8,92.25 74.69,92.36 74.15,92.36 74.04,92.47 74.04,94.54 74.45,94.95 v6(76.45,94.95)
PRU2ETH1_TXD1: length 115.7
  TOP w0.173: R208.1 v5(77.09,92.92) ; U17.5 31.25,61.21 v1(31.25,61.21)
  L3_SIG1 w0.109: v5(77.09,92.92) v6(76.45,92.92)
  L10_SIG4 w0.109: v1(31.25,61.21) 32.25,61.21 43.64,72.6 43.82,72.6 43.96,72.46 43.96,71.71 44.1,71.57 44.3,71.57 44.44,71.71 44.44,72.46 44.58,72.6 44.78,72.6 44.92,72.46 44.92,71.71 45.06,71.57 45.26,71.57 45.4,71.71 45.4,72.46 45.54,72.6 45.74,72.6 45.88,72.46 45.88,71.71 46.02,71.57 46.22,71.57 46.36,71.71 46.36,72.46 46.5,72.6 46.7,72.6 46.84,72.46 46.84,71.71 46.98,71.57 47.18,71.57 47.32,71.71 47.32,72.46 47.46,72.6 47.66,72.6 47.8,72.46 47.8,71.71 47.94,71.57 48.14,71.57 48.28,71.71 48.28,72.46 48.42,72.6 48.62,72.6 48.76,72.46 48.76,71.71 48.9,71.57 49.1,71.57 49.24,71.71 49.24,72.46 49.38,72.6 49.58,72.6 49.72,72.46 49.72,71.71 49.86,71.57 50.06,71.57 50.2,71.71 50.2,72.46 50.34,72.6 50.54,72.6 50.68,72.46 50.68,71.71 50.82,71.57 51.02,71.57 51.16,71.71 51.16,72.46 51.3,72.6 51.5,72.6 51.64,72.46 51.64,71.71 51.78,71.57 51.98,71.57 52.12,71.71 52.12,72.46 52.26,72.6 52.46,72.6 52.6,72.46 52.6,71.71 52.74,71.57 52.94,71.57 53.08,71.71 53.08,72.46 53.22,72.6 53.42,72.6 53.56,72.46 53.56,71.71 53.7,71.57 53.9,71.57 54.04,71.71 54.04,72.46 54.18,72.6 54.38,72.6 54.52,72.46 54.52,71.43 54.66,71.29 54.86,71.29 55,71.43 55,72.46 55.14,72.6 55.69,72.6 55.83,72.46 55.83,70.53 55.97,70.38 56.17,70.38 56.31,70.53 56.31,71.26 56.45,71.4 56.65,71.4 56.79,71.26 56.79,70.47 56.93,70.33 57.13,70.33 57.27,70.47 57.27,71.26 57.41,71.4 57.61,71.4 57.75,71.26 57.75,70.42 57.89,70.28 58.09,70.28 58.23,70.42 58.23,71.29 58.37,71.43 58.57,71.43 58.71,71.29 58.71,70.32 58.85,70.18 59.05,70.18 59.19,70.32 59.19,71.29 59.33,71.43 59.53,71.43 59.67,71.29 59.67,70.73 59.81,70.59 60.01,70.59 60.15,70.73 60.15,71.16 60.29,71.3 60.49,71.3 60.63,71.16 60.63,70.47 60.77,70.33 60.97,70.33 61.11,70.47 61.11,71.16 61.25,71.3 61.45,71.3 61.59,71.16 61.59,69.97 61.73,69.83 61.93,69.83 62.07,69.97 62.07,71.9 62.24,72.06 62.56,72.06 62.72,71.9 62.72,69.27 63.08,68.92 63.46,68.92 63.6,69.06 63.6,69.69 63.71,69.81 63.88,69.81 63.99,69.69 63.99,69.01 64.11,68.89 64.94,68.89 65.06,69.01 65.06,69.65 65.18,69.77 65.34,69.77 65.46,69.65 65.46,69.08 65.65,68.89 66.45,68.89 66.66,69.11 66.66,69.63 66.8,69.77 68.68,69.77 69.15,70.25 69.31,70.25 69.53,70.02 69.69,70.02 69.84,70.18 69.84,70.33 69.62,70.56 69.62,70.71 69.77,70.87 69.93,70.87 70.15,70.64 70.31,70.64 70.46,70.8 70.46,70.95 70.24,71.18 70.24,71.33 71.9,72.99 72.9,72.99 73.2,73.29 73.2,75.45 74.16,76.41 74.16,89.13 76.45,91.42 v6(76.45,92.92)
PRU2ETH1_TXD2: length 112.5
  TOP w0.173: R210.1 v5(77.09,96.98) ; U17.6 v1(30.75,63.58)
  L3_SIG1 w0.109: v5(77.09,96.98) v6(76.45,96.98)
  L10_SIG4 w0.109: v1(30.75,63.58) 31.46,63.58 31.94,64.06 32.18,64.06 34.65,66.53 34.65,66.83 42.32,74.5 52.83,74.5 55.37,77.04 55.37,78.82 56.18,79.63 58.26,79.63 59.9,77.98 60.1,77.98 60.24,78.12 60.24,78.32 58.52,80.05 58.52,80.24 58.66,80.39 58.86,80.39 59.47,79.78 59.66,79.78 59.81,79.92 59.81,80.12 59.38,80.55 59.38,80.77 59.52,80.91 59.69,80.91 60.22,80.38 60.44,80.38 60.59,80.52 60.59,80.7 59.02,82.27 59.02,82.47 59.16,82.61 59.35,82.61 59.53,82.43 59.73,82.43 59.87,82.58 59.87,82.77 59.69,82.95 59.69,83.15 60,83.45 60.2,83.45 61.69,81.95 61.89,81.95 62.03,82.09 62.03,82.29 61.58,82.75 61.58,82.97 61.72,83.11 61.89,83.11 63.11,81.9 63.3,81.9 63.45,82.04 63.45,82.23 62.05,83.63 62.05,83.83 62.19,83.97 62.39,83.97 63.53,82.83 63.73,82.83 63.87,82.97 63.87,83.17 62.83,84.21 62.83,84.4 62.97,84.55 63.17,84.55 63.7,84.02 63.9,84.02 64.04,84.16 64.04,84.36 62.57,85.83 62.57,86.02 62.71,86.16 62.91,86.16 64.76,84.31 64.96,84.31 65.1,84.45 65.1,84.65 63.25,86.5 63.25,86.7 64.63,88.08 64.79,88.08 65.46,87.41 65.61,87.41 65.77,87.56 65.77,87.72 65.09,88.39 65.09,88.55 65.25,88.7 65.4,88.7 66.08,88.03 66.23,88.03 66.39,88.18 66.39,88.34 65.71,89.01 65.71,89.16 65.87,89.32 66.02,89.32 66.7,88.64 66.85,88.64 67.01,88.8 67.01,88.95 66.33,89.63 66.33,89.78 66.49,89.94 66.64,89.94 67.32,89.26 67.47,89.26 67.62,89.42 67.62,89.57 66.95,90.25 66.95,90.4 67.1,90.56 67.26,90.56 67.93,89.88 68.09,89.88 68.24,90.04 68.24,90.19 67.57,90.86 67.57,91.02 68.83,92.28 69.24,92.28 69.35,92.17 69.35,90.79 69.46,90.68 69.68,90.68 69.79,90.79 69.79,92.17 69.9,92.28 70.12,92.28 70.22,92.17 70.22,90.79 70.33,90.68 70.55,90.68 70.66,90.79 70.66,92.17 70.77,92.28 70.99,92.28 71.87,93.16 71.87,94.65 72.9,95.69 75.16,95.69 v6(76.45,96.98)
PRU2ETH1_TXD3: length 117.1
  TOP w0.173: v1(30.25,61.21) 30.25,61.21 U17.7 ; R207.1 v5(77.09,93.93)
  L3_SIG1 w0.109: v5(77.09,93.93) v6(76.45,93.93)
  L10_SIG4 w0.109: v6(76.45,93.93) 75.9,93.38 75.9,91.47 73.33,88.91 73.33,87.23 73.22,87.12 72.07,87.12 71.96,87.01 71.96,86.79 72.07,86.68 73.22,86.68 73.33,86.57 73.33,86.35 73.22,86.24 72.07,86.24 71.96,86.14 71.96,85.92 72.07,85.81 73.22,85.81 73.33,85.7 73.33,85.48 73.22,85.37 72.07,85.37 71.96,85.26 71.96,85.04 72.07,84.93 73.22,84.93 73.33,84.83 73.33,84.61 73.22,84.5 72.07,84.5 71.96,84.39 71.96,84.17 72.07,84.06 73.22,84.06 73.33,83.95 73.33,83.73 73.22,83.62 72.07,83.62 71.96,83.51 71.96,83.3 72.07,83.19 73.22,83.19 73.33,83.08 73.33,82.86 73.22,82.75 72.07,82.75 71.96,82.64 71.96,82.42 72.07,82.31 73.22,82.31 73.33,82.2 73.33,81.99 73.22,81.88 72.07,81.88 71.96,81.77 71.96,81.55 72.07,81.44 73.22,81.44 73.33,81.33 73.33,81.11 73.22,81 72.07,81 71.96,80.89 71.96,80.67 72.07,80.57 73.22,80.57 73.33,80.46 73.33,80.24 73.22,80.13 72.07,80.13 71.96,80.02 71.96,79.8 72.07,79.69 73.22,79.69 73.33,79.58 73.33,79.36 73.22,79.25 72.07,79.25 71.96,79.15 71.96,78.93 72.07,78.82 73.22,78.82 73.33,78.71 73.33,78.49 73.22,78.38 72.07,78.38 71.96,78.27 71.96,78.05 72.07,77.94 73.22,77.94 73.33,77.83 73.33,77.62 73.22,77.51 72.07,77.51 71.96,77.4 71.96,77.18 72.07,77.07 73.22,77.07 73.33,76.96 73.33,76.06 72.93,75.66 72.38,75.66 71.47,76.57 71.29,76.57 71.15,76.43 71.15,76.21 72.62,74.73 72.62,74.54 72.48,74.39 72.28,74.39 70.76,75.92 70.59,75.92 70.45,75.78 70.45,75.55 72.07,73.93 72.07,73.73 71.83,73.49 71.63,73.49 71.05,74.08 70.85,74.08 70.71,73.94 70.71,73.74 71.3,73.15 71.3,72.95 71.15,72.81 70.96,72.81 70.37,73.4 70.17,73.4 70.03,73.26 70.03,73.06 70.62,72.47 70.62,72.28 68.49,70.15 63.29,70.15 63.11,70.33 63.11,72.38 62.29,73.2 59.18,73.2 58.93,72.95 58.19,72.95 57.94,73.2 56.97,73.2 56.74,72.97 55.93,72.97 55.7,73.2 43.76,73.2 32.66,62.11 31.15,62.11 v1(30.25,61.21)
PRU2ETH1_TXEN: length 112.4
  TOP w0.173: U17.3 v1(32.25,64.98) ; v1(43.43,84.55) R115.2 ; R205.1 v5(77.09,98)
  L3_SIG1 w0.109: v5(77.09,98) v6(76.45,98)
  L10_SIG4 w0.109: v6(76.45,98) 75.9,98 74.07,96.17 68.23,96.17 65.24,93.18 65.24,93.02 66.34,91.92 66.34,91.77 66.19,91.61 66.03,91.61 64.93,92.71 64.77,92.71 64.62,92.56 64.62,92.4 65.72,91.3 65.72,91.15 65.57,90.99 65.41,90.99 64.31,92.1 64.16,92.1 64,91.94 64,91.79 65.1,90.68 65.1,90.53 64.95,90.37 64.79,90.37 63.69,91.48 63.54,91.48 63.38,91.32 63.38,91.17 64.49,90.07 64.49,89.91 64.33,89.76 64.18,89.76 63.07,90.86 62.92,90.86 62.76,90.7 62.76,90.55 63.87,89.45 63.87,89.29 63.71,89.14 63.56,89.14 62.46,90.24 62.3,90.24 62.15,90.09 62.15,89.93 63.25,88.83 63.25,88.67 63.09,88.52 62.94,88.52 61.84,89.62 61.68,89.62 61.53,89.47 61.53,89.31 62.63,88.21 62.63,88.06 62.48,87.9 62.32,87.9 61.22,89 61.06,89 60.91,88.85 60.91,88.7 62.01,87.59 62.01,87.44 61.86,87.28 61.7,87.28 60.6,88.39 60.45,88.39 60.29,88.23 60.29,88.08 61.39,86.97 61.39,86.82 61.24,86.67 61.08,86.67 59.98,87.77 59.83,87.77 59.67,87.61 59.67,87.46 60.78,86.36 60.78,86.2 60.62,86.05 60.47,86.05 59.36,87.15 59.21,87.15 59.05,86.99 59.05,86.84 60.16,85.74 60.16,85.58 60,85.43 59.85,85.43 58.75,86.53 58.59,86.53 56.87,84.81 56.05,84.81 55.16,85.7 44.58,85.7 v1(43.43,84.55) 47.19,80.8 47.19,75.57 46.51,74.88 42.15,74.88 v1(32.25,64.98)
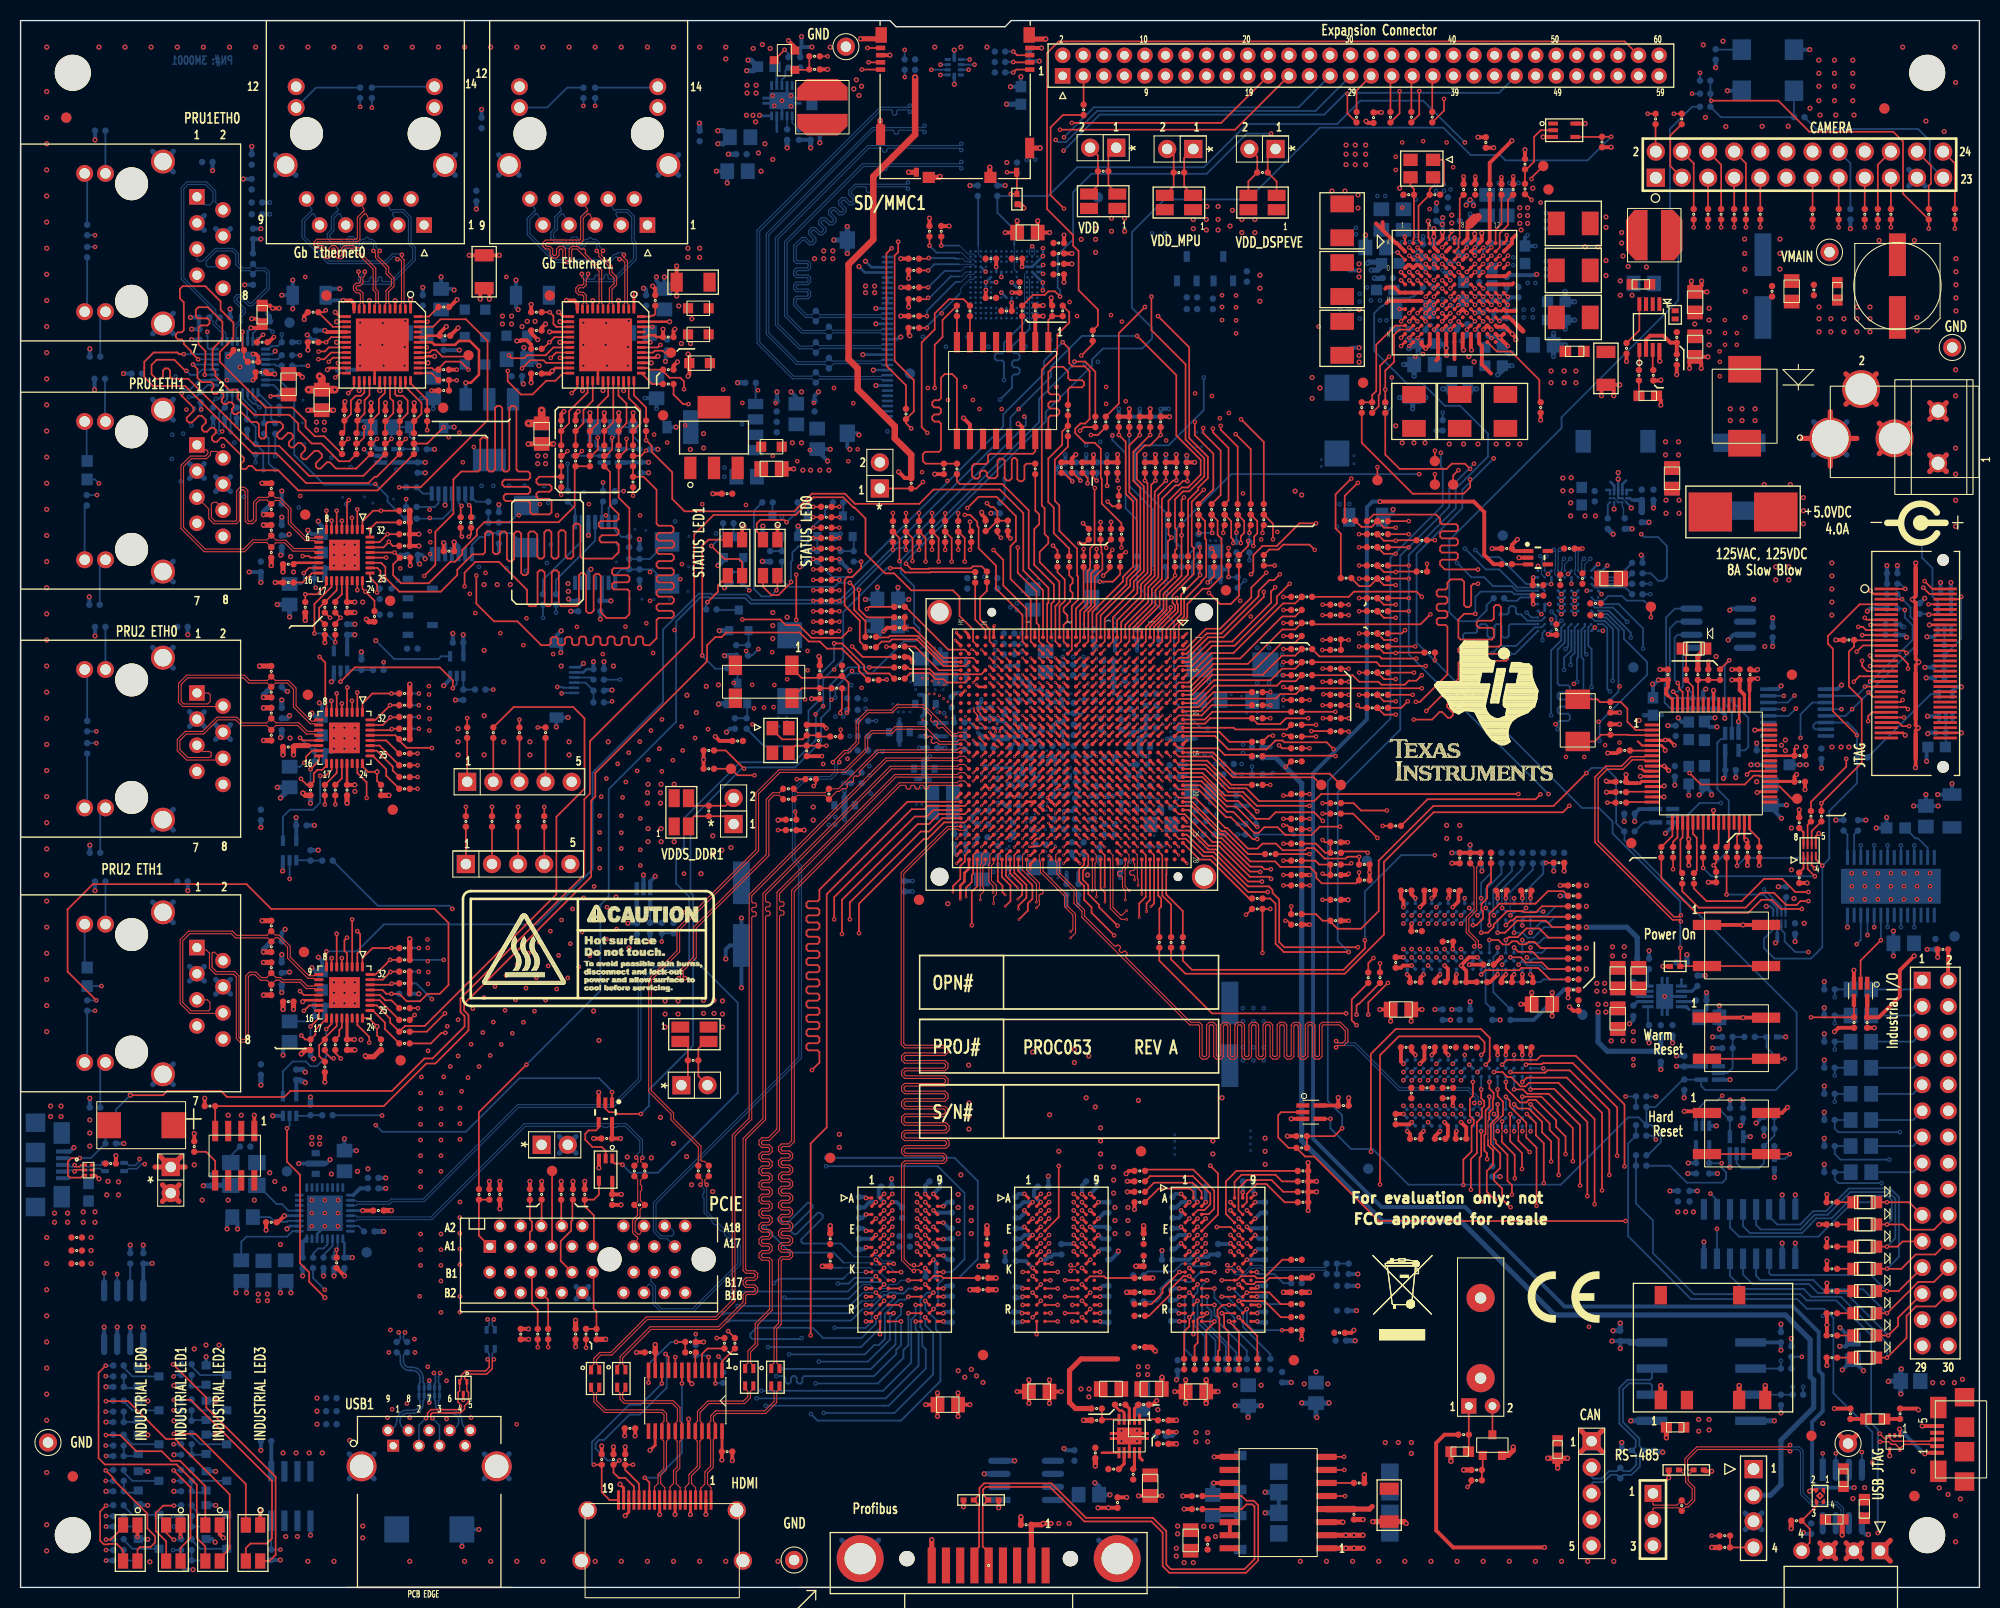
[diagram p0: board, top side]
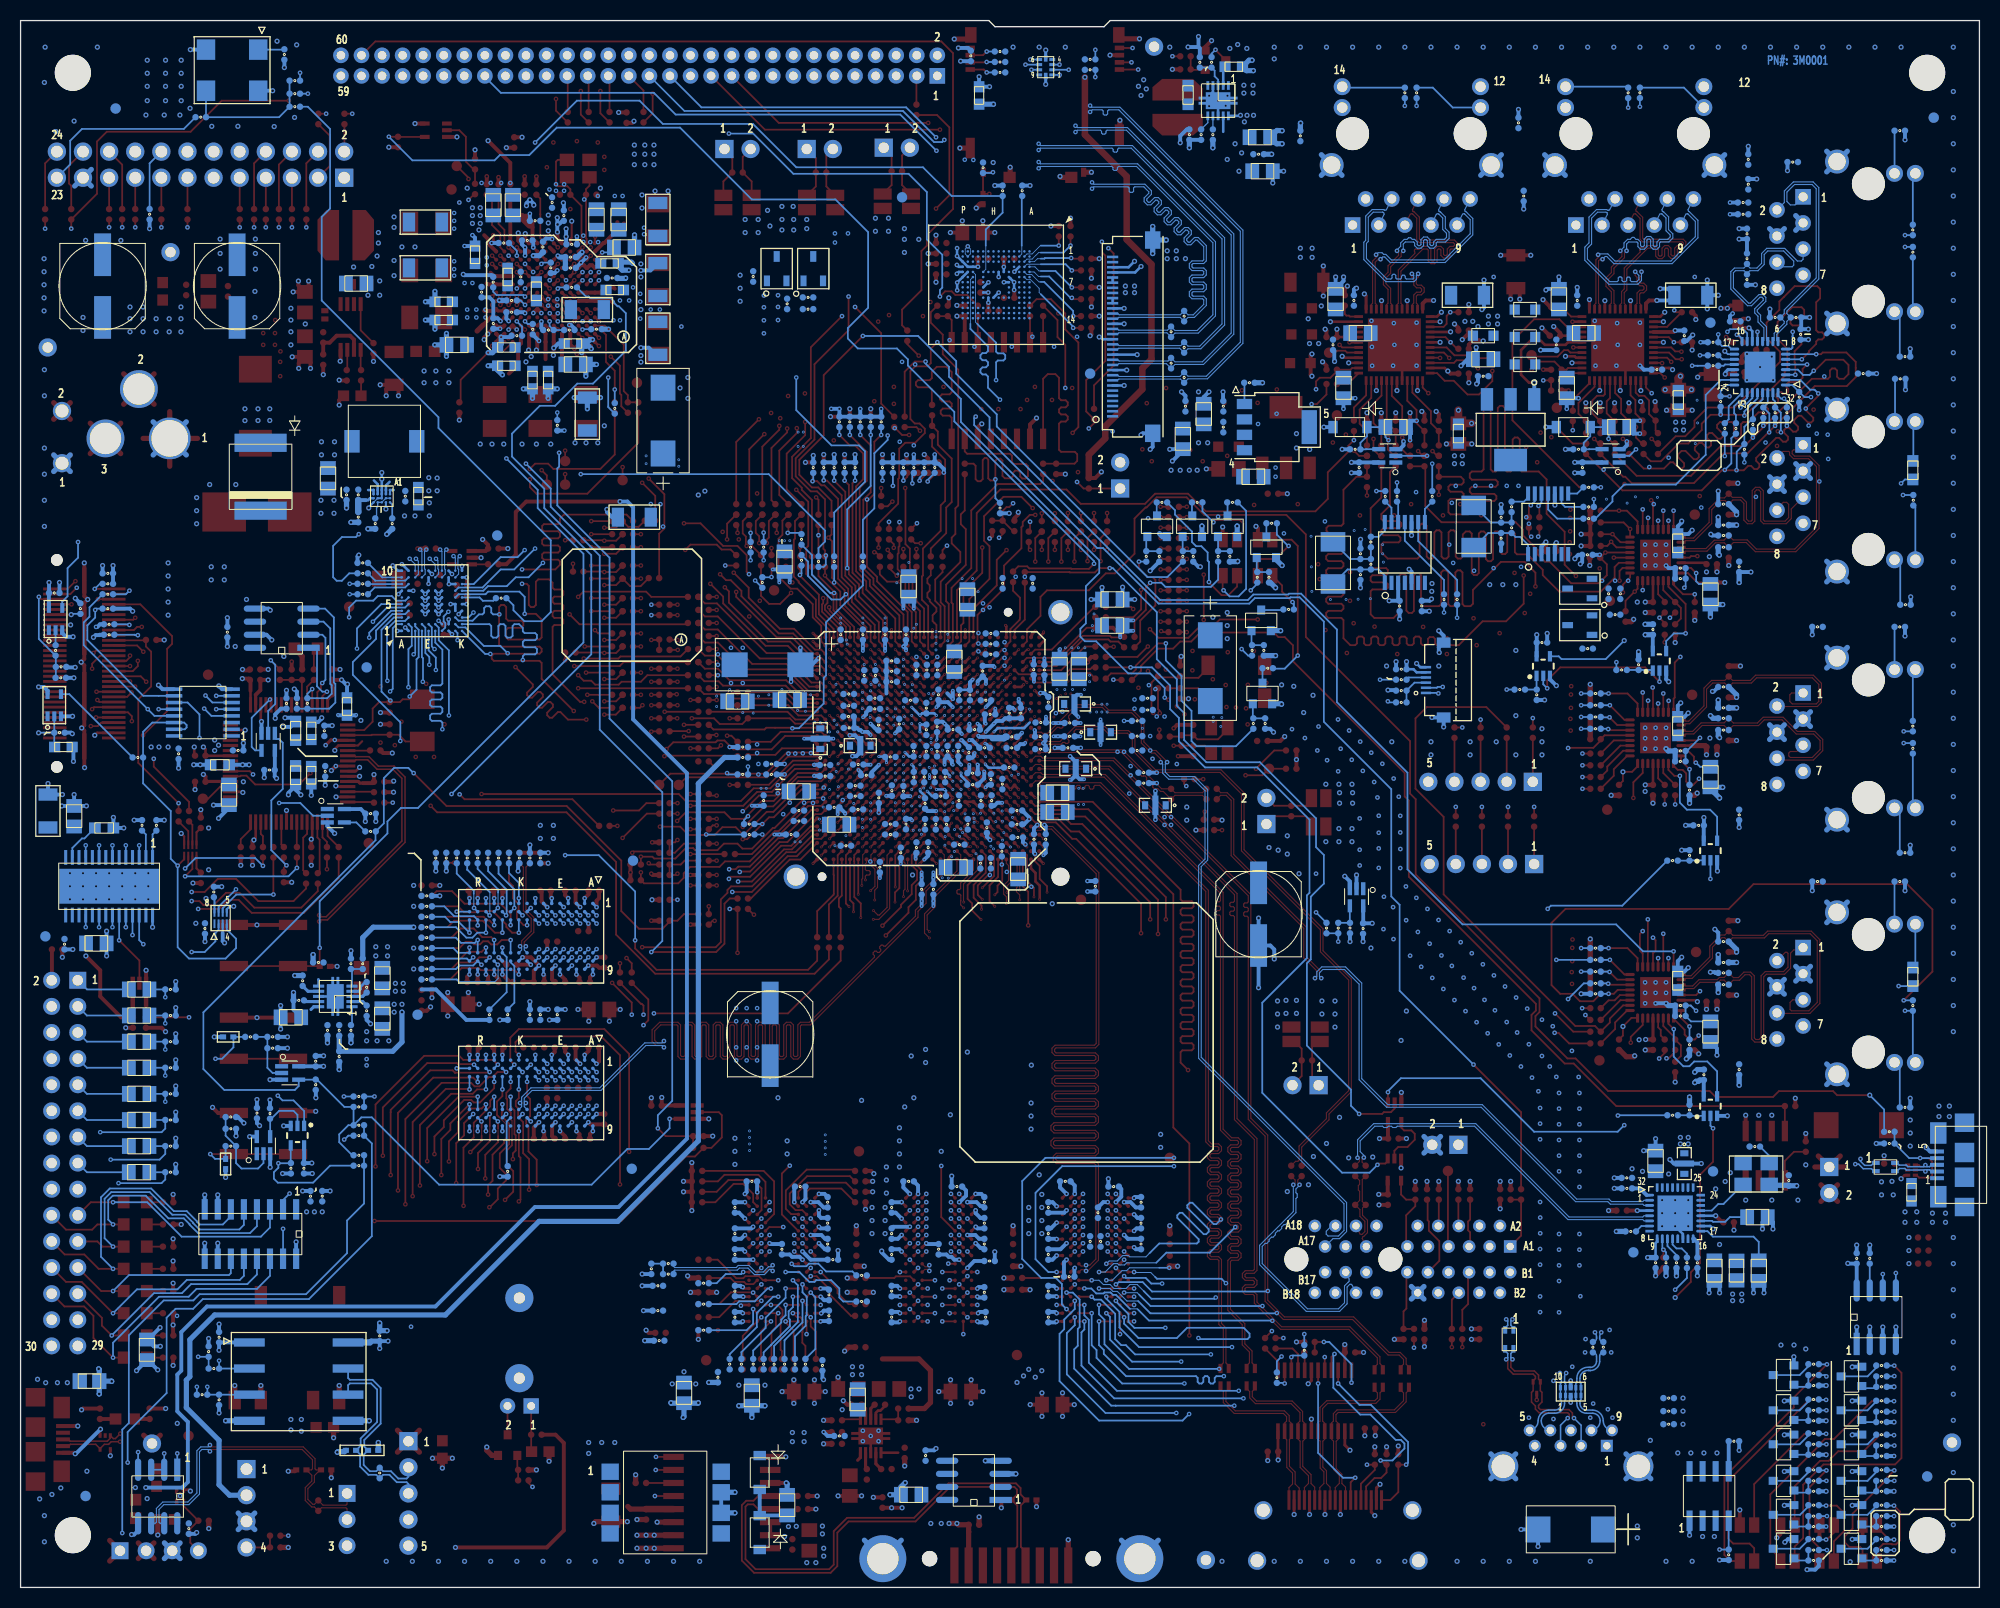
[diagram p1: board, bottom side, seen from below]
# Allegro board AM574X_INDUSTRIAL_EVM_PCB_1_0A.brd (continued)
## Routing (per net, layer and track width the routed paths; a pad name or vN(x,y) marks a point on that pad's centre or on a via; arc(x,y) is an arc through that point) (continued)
PRU2ETHER0_RDN: length 23.6
  TOP w0.108: U15.9 28.67,84.38 28.55,84.26 28.27,84.26 26.79,85.74 26.79,87.47 26.05,88.22 24.77,88.22 R182.2 24,88.22 22.28,88.22 21.77,88.73 16.15,88.73 15.37,87.94 15.37,86.08 15.77,85.68 19.64,85.68 J6.2
PRU2ETHER0_RDP: length 23.6
  TOP w0.108: J6.1 18.27,87 18.44,86.82 18.44,86.17 18.2,85.93 15.88,85.93 15.62,86.19 15.62,87.84 16.26,88.47 21.67,88.47 22.17,87.97 24,87.97 R183.2 24.4,87.58 24.78,87.97 25.94,87.97 26.54,87.37 26.54,85.63 28.17,84 28.55,84 28.67,83.88 U15.10
PRU2ETHER0_TDN: length 21.7
  TOP w0.108: J6.6 19.52,80.47 16.15,80.47 15.24,81.38 15.24,82.48 16.02,83.26 17.71,83.26 18.39,83.94 18.39,83.94 19.09,84.64 21.03,84.64 21.59,84.08 23.93,84.08 R184.2 24.83,84.09 27.06,84.09 27.89,83.27 28.55,83.27 28.66,83.38 U15.11
PRU2ETHER0_TDP: length 21.7
  TOP w0.108: J6.5 17.76,81.31 18.39,81.31 18.54,81.16 18.54,80.88 18.39,80.73 16.26,80.73 15.49,81.49 15.49,82.38 16.12,83 17.81,83 18.49,83.68 19.19,84.38 20.93,84.38 21.48,83.82 23.95,83.82 R185.2 24.83,83.84 26.96,83.84 27.78,83.01 28.55,83.01 28.68,82.88 U15.12
PRU2ETHER1_RDN: length 27.5
  TOP w0.108: J8.6 19.64,55.83 16.48,55.83 15.52,56.8 15.52,63 16.35,63.84 20.6,63.84 21.01,63.43 23.98,63.43 R224.2 24.77,63.45 25.15,63.45 26.22,62.38 26.22,61.31 28.04,59.49 28.55,59.49 28.67,59.62 U17.9
PRU2ETHER1_RDP: length 27.4
  TOP w0.108: J8.5 18.16,57.15 18.41,56.9 18.41,56.22 18.29,56.09 16.59,56.09 15.77,56.9 15.77,62.9 16.46,63.58 20.5,63.58 20.9,63.17 24.03,63.17 R225.2 24.4,62.82 24.78,63.2 25.04,63.2 25.97,62.27 25.97,61.21 27.94,59.24 28.55,59.24 28.67,59.12 U17.10
PRU2ETHER1_TDN: length 26.9
  TOP w0.108: U17.11 28.66,58.62 28.55,58.5 27.89,58.5 27.28,59.11 25.5,59.11 25.29,59.33 24.83,59.33 R226.2 23.93,59.31 23.43,59.31 22.9,59.85 22.25,59.85 21.89,59.49 21.89,53.45 21.74,53.29 21.44,53.29 21.23,53.5 21.23,59.49 20.83,59.9 19.05,59.9 18.62,60.33 18.62,61.68 18.72,61.78 18.87,61.78 J8.2
PRU2ETHER1_TDP: length 27.3
  TOP w0.108: U17.12 28.68,58.12 28.55,58.25 27.78,58.25 27.17,58.86 25.4,58.86 25.18,59.07 24.83,59.07 R227.2 23.95,59.06 23.33,59.06 22.79,59.59 22.36,59.59 22.15,59.39 22.15,53.34 21.85,53.04 21.33,53.04 20.98,53.39 20.98,59.39 20.72,59.64 18.94,59.64 18.36,60.22 18.36,61.7 18.06,62.01 17.38,62.01 J8.1
QSPI_CLK: length 15.3
  TOP w0.173: R24.1 101.98,101.05 100.48,102.54 100.48,105.03 99.95,105.57 99.95,109.8 101.3,111.15 101.3,112.43 R23.1 R31.2
RS485_A: length 33.2
  TOP w0.108: J39.1 158.75,8.11 158.86,8 161.08,8 R729.2 161.93,8.08 162.08,8.08 162.56,8.56 162.56,9.61 161.93,10.24 161.93,10.88 161.37,11.43 ; U82.1 161.37,11.43 ; 161.37,11.43 161.75,11.43 161.86,11.54 161.86,12.53 163,13.67 171.91,13.67 v1(172.09,13.85)
  BOTTOM w0.108: U77.6 177.4,6.24 177.29,6.35 177.29,7.68 176.67,8.31 174.23,8.31 173.36,9.19 173.36,13.29 172.97,13.67 172.26,13.67 v1(172.09,13.85)
RS485_B: length 32.7
  TOP w0.108: J39.2 158.75,7.64 158.86,7.75 161.24,7.75 R729.1 161.93,7.83 162.18,7.83 162.81,8.46 162.81,9.71 162.18,10.35 162.18,10.91 U83.1 162.22,11.43 162.12,11.54 162.12,12.42 163.11,13.42 171.91,13.42 v1(172.09,13.24)
  BOTTOM w0.108: U77.7 176.93,6.24 177.04,6.35 177.04,7.58 176.56,8.05 174.13,8.05 173.1,9.08 173.1,13.18 172.87,13.42 172.26,13.42 v1(172.09,13.24)
RSTOUTTOPMIC: length 95.2
  TOP w0.173: v1(128.52,44.66) 127.76,43.9 R793.2 R36.1 ; U3.E6 v1(139.04,127.14)
  L4_SIG2 w0.114: v1(138.13,110.36) 137.41,111.07 137.41,111.83 137.2,112.04 137.2,118.85 137.82,119.47 137.82,123.91 137.5,124.23 137.5,126.65 138,127.14 v1(139.04,127.14)
  BOTTOM w0.173: v1(128.52,44.66) 128.52,45.93 127.13,47.33 127.13,78.41 133.22,84.51 133.22,100.16 138.3,105.24 138.3,108.84 138.13,109.02 v1(138.13,110.36)
RTCK: length 92.3
  TOP w0.173: 124.59,73.74 v5(125.35,73.74) ; J18.7 178.85,95.62 175.77,92.54 175.77,91.78 176.25,91.29 176.25,85.22 v5(178.59,82.89)
  L3_SIG1 w0.109: v5(125.35,73.74) 127.03,73.74 128.59,75.31 128.75,75.31 129.47,74.59 129.62,74.59 129.78,74.74 129.78,74.9 129.06,75.62 129.06,75.77 129.21,75.93 129.37,75.93 130.09,75.21 130.24,75.21 130.4,75.36 130.4,75.51 129.68,76.24 129.68,76.39 129.83,76.55 129.98,76.55 130.71,75.82 130.86,75.82 131.02,75.98 131.02,76.13 130.29,76.86 130.29,77.01 130.45,77.16 130.6,77.16 131.32,76.44 131.48,76.44 131.63,76.6 131.63,76.75 130.91,77.47 130.91,77.63 131.07,77.78 131.22,77.78 131.94,77.06 132.1,77.06 132.25,77.22 132.25,77.37 131.53,78.09 131.53,78.25 131.69,78.4 131.84,78.4 132.56,77.68 132.72,77.68 132.87,77.83 132.87,77.99 132.15,78.71 132.15,78.86 133.12,79.83 148.46,79.83 149.99,81.36 152.4,81.36 153.14,80.62 155.14,80.62 158.17,83.65 159.21,83.65 159.92,84.36 160.68,84.36 161.87,83.16 165.25,83.16 167.11,85.02 169.57,85.02 170.69,83.9 173.61,83.9 174.62,82.89 v5(178.59,82.89)
SERDES_REF_CLKN: length 70.8
  TOP w0.108: C438.1 73.79,77.04 73.26,77.04 72.77,76.56 72.77,71.18 65.71,64.11 65.71,61.24 64.44,59.97 64.44,59.44 v1(64.62,59.26)
  BOTTOM w0.108: U45.2 32.62,37.65 32.74,37.53 35.79,37.53 36.03,37.77 39.17,37.77 48.35,46.96 57.54,46.96 60.07,49.48 60.07,58.78 61.64,60.36 63.96,60.36 64.44,59.88 64.44,59.44 v1(64.62,59.26)
SERDES_REF_CLKP: length 70.8
  TOP w0.108: C439.1 73.79,77.3 73.15,77.3 72.52,76.66 72.52,71.28 65.46,64.22 65.46,61.35 64.18,60.07 64.18,59.44 v1(64.01,59.26)
  BOTTOM w0.108: U45.3 32.62,37.15 32.74,37.28 35.89,37.28 36.14,37.52 39.27,37.52 48.46,46.7 57.65,46.7 60.32,49.38 60.32,58.68 61.75,60.1 63.86,60.1 64.19,59.77 64.19,59.44 v1(64.01,59.26)
SPI2_CS0N: length 127.8
  TOP w0.173: v1(120.72,68.66) 120.72,68.66 119.38,68.66 116.26,71.79 115.49,71.79 113.66,73.62 112.63,73.62 U1.B24
  L4_SIG2 w0.114: v6(143.46,132.14) 143.46,134.9 149.23,140.67 v6(149.23,143.21)
  L9_SIG3 w0.114: v6(143.46,132.14) 143.46,129.73 143.48,129.71 143.48,126.71 146.02,124.16 147.08,124.16 148.23,123 148.23,114.38 148.82,113.8 148.82,111.81 145.45,108.45 145.17,108.45 145.17,108.45 140.92,104.2 140.92,100.53 133.38,92.99 133.38,91.63 128.83,87.08 128.83,81.95 126.59,79.71 126.59,76.02 124.05,73.47 122.89,73.47 120.85,71.43 120.85,70.52 120.02,69.68 120.02,69.36 v1(120.72,68.66)
  L10_SIG4 w0.109: J21.30 130.32,149.99 131.78,149.99 132.33,149.43 132.33,148.6 132.92,148.01 133.83,148.01 134.32,147.53 134.32,146.31 136.63,144 148.44,144 v6(149.23,143.21)
SPI2_DIN: length 143.3
  TOP w0.173: U1.G17 v4(108.63,79.22)
  L3_SIG1 w0.109: v4(108.63,79.22) v6(109.03,78.97)
  L4_SIG2 w0.114: v6(163.7,116.03) 161.16,113.49 154.31,113.49 148.37,107.55 148.37,101.37 142.56,95.56 142.56,92.78 139.43,89.65 131.31,89.65 129.11,87.45 129.11,86.67 125.39,82.95 123.26,82.95 122.96,83.26 118.43,83.26 117.37,82.2 117.37,80.94 116.01,79.58 114.99,79.58 114.76,79.35 109.42,79.35 v6(109.03,78.97)
  L10_SIG4 w0.109: v6(163.7,116.03) 164.08,116.41 164.08,118.7 163.48,119.31 163.48,126.33 163.99,126.85 163.99,131.79 160.4,135.38 160.4,139.84 158.38,141.86 149.81,141.86 148.03,143.64 135.96,143.64 133.62,145.98 127.01,145.98 126.36,146.63 126.36,148 J21.26
SPI2_DOUT: length 126.9
  TOP w0.173: U1.B22 112.23,75.61 112.63,75.22 113.21,75.22 115.93,72.5 116.69,72.5 119.56,69.63 120.53,69.63 v1(120.57,69.59)
  L4_SIG2 w0.114: v1(147.83,134.7) 147.92,134.79 147.92,137.81 150.11,140.01 v6(150.11,143.72)
  L9_SIG3 w0.114: v1(120.57,69.59) 121.6,70.62 121.6,71.39 123.19,72.98 123.97,72.98 129.73,78.73 129.73,80.29 129.21,80.8 129.21,87 133.67,91.46 133.67,92.78 141.3,100.41 141.3,103.66 142.21,104.57 142.21,105.05 145.31,108.15 145.64,108.15 149.45,111.96 149.45,124.5 148.21,125.75 148.21,128.73 147.83,129.11 v1(147.83,134.7)
  L10_SIG4 w0.109: v6(150.11,143.72) 149.4,144.43 138.23,144.43 136.35,146.31 136.35,147.43 135.76,148.01 134.92,148.01 134.34,148.59 134.34,149.48 133.43,150.4 128.72,150.4 J21.28
SPI2_SCLK: length 144.7
  TOP w0.173: R684.2 121.54,67.01 122.05,66.5 122.05,62.61 122.85,61.8 v1(129.16,61.8)
  L3_SIG1 w0.109: J21.24 122.35,148.03 122.35,144.78 120.83,143.26 120.83,138.97 122.98,136.82 135.55,136.82 138.79,140.06 139.36,140.06 140.28,140.98 140.67,140.98 141.4,140.25 142.23,140.25 142.64,140.66 144.18,140.66 150.75,134.09 150.75,114.25 145.42,108.92 141.73,108.92 v1(141.35,109.3)
  BOTTOM w0.173: v1(141.35,109.3) 138.94,106.89 138.94,105.12 134.18,100.35 134.18,83.43 128.09,77.35 128.09,62.87 v1(129.16,61.8)
SPIMEM_CLK: length 18.2
  TOP w0.173: U4.16 99.95,113.77 100.15,113.97 100.81,113.97 101.02,114.18 101.02,114.46 100.81,114.66 100.15,114.66 99.95,114.87 99.95,115.15 100.15,115.35 100.89,115.35 101.09,115.56 101.09,115.84 100.89,116.05 100.15,116.05 99.95,116.25 99.95,118.22 100.46,118.72 101.4,118.72 101.88,118.24 101.88,117.62 102.08,117.42 103.23,117.42 103.43,117.22 103.43,116.93 103.23,116.73 102.08,116.73 101.88,116.53 101.88,115.04 R31.1
SPIMEM_CSN: length 2.5
  TOP w0.173: R30.1 92.33,121.11
SPIMEM_D0: length 25.6
  TOP w0.173: R25.1 97.83,109.3 97.62,109.1 97.62,107.79 97.42,107.59 97.14,107.59 96.93,107.8 96.93,109.66 96.74,109.85 96.56,109.85 96.39,109.69 96.39,107.87 96.19,107.67 95.9,107.67 95.7,107.87 95.7,109.59 95.49,109.79 95.21,109.79 95.01,109.6 95.01,108.11 94.78,107.88 94.2,107.88 93.98,108.11 93.98,108.42 93.77,108.63 93.49,108.63 93.29,108.42 93.29,108.06 93.08,107.85 92.78,107.85 92.53,108.1 92.53,109.07 92.74,109.27 93.89,109.27 94.09,109.47 94.09,110.09 94.26,110.26 98.44,110.26 98.68,110.5 U4.15
SPIMEM_D1: length 2.5
  TOP w0.173: R26.1 U4.8
SPIMEM_D2: length 23.2
  TOP w0.173: U4.9 91.06,117.56 90.6,118.01 89.86,118.01 89.51,117.66 89.51,115.67 89.31,115.47 88.86,115.47 88.66,115.27 88.66,114.98 88.86,114.78 89.31,114.78 89.51,114.58 89.51,114.29 89.31,114.09 88.86,114.09 88.66,113.89 88.66,113.6 88.86,113.4 89.31,113.4 89.51,113.2 89.51,110.65 89.31,110.45 87.97,110.45 87.74,110.22 87.74,109.57 88.01,109.3 R22.1 R27.1
SPIMEM_D3: length 3.7
  TOP w0.173: U4.1 99.95,123.27 R799.1 R28.1
SRCCLK: length 66.3
  BOTTOM w0.173: R276.1 162.56,144.02 160.4,141.86 160.4,134.11 161.21,133.3 161.21,125.17 149.86,113.82 149.86,112.78 138.94,101.85 138.94,94.87 139.83,93.98 141.5,93.98 142.57,95.05 142.57,95.53 R586.2
SYS_RESETN: length 291
  TOP w0.173: R29.2 98.45,125.71 99.59,125.71 99.95,126.07 100.58,126.07 v1(101.09,125.56)
  L3_SIG1 w0.109: v1(121.62,141.41) 121.62,143.29 J21.25
  L9_SIG3 w0.114: v1(180.09,12.15) 180.09,19.51 182.65,22.07 182.65,41.81 182.22,42.24 182.22,52.02 182.65,52.45 182.65,64.05 182.63,64.07 182.63,78.82 186.18,82.38 186.18,96.86 181.36,101.68 158.37,101.68 v1(157.61,102.44) 157.61,108.38 151.89,114.1 151.89,118.75 150.88,119.76 150.88,125.6 150.11,126.36 150.11,137.54 145.75,141.91 128.32,141.91 126.87,140.46 123.88,140.46 122.93,141.41 v1(121.62,141.41)
  BOTTOM w0.173: v1(157.61,102.44) 157.89,102.16 159.24,102.16 160.11,101.3 160.11,98.26 159.76,97.91 159.26,97.91 158.54,98.63 R566.2 ; 157.1,44.96 157.1,43.94 156.34,43.18 156.34,34.16 162.45,28.05 172.77,28.05 173.72,27.1 175.43,27.1 176.3,26.23 176.3,18.9 180.09,15.11 v1(180.09,12.15) ; v1(101.09,125.56) 101.09,126.19 100.86,126.42 100.86,129.62 102.36,131.12 102.36,135.72 104.14,137.5 115.34,137.5 119.25,141.41 v1(121.62,141.41)
SYS_WARMRESETN: length 198.9
  TOP w0.173: v1(152.27,79.2) 149.08,76.01 137.39,76.01 132.08,70.69 132.08,65.79 130.36,64.07 128.07,64.07 127.38,64.76 R2.1 126.62,64.85 125.98,65.49 124.59,65.49 ; U47.4 v1(127.38,45.58)
  L3_SIG1 w0.109: v6(158.62,100.92) 159.39,101.68 v1(184.91,101.68)
  L10_SIG4 w0.109: v1(152.27,79.2) 154.69,79.2 158.26,82.77 158.26,85.31 159.12,86.18 159.12,87.35 159.13,87.36 159.13,87.39 160.3,88.56 160.3,98.02 158.62,99.7 v6(158.62,100.92)
  BOTTOM w0.173: U78.4 186.45,95.89 185.93,96.4 185.93,99.14 184.91,100.16 v1(184.91,101.68) ; R918.2 158.62,44.96 159.51,44.07 159.51,43.31 158.24,42.04 R915.2 ; R918.2 R919.2 159,46.74 161.67,49.4 C570.1 161.81,49.39 U97.4 163.45,49.38 163.45,48.77 163.83,48.39 170.69,48.39 172.72,50.42 172.72,55.93 155.98,72.67 155.98,73.51 R473.1 155.17,74.32 155.17,78.72 154.18,79.71 152.78,79.71 v1(152.27,79.2) ; R918.2 157.35,45.72 156.34,45.72 149.79,39.17 134.97,39.17 131.49,42.65 129.39,42.65 127.38,44.66 v1(127.38,45.58)
TCK: length 3.4
  TOP w0.173: J18.3 180.24,96.62 v1(179.91,96.95)
  BOTTOM w0.173: R3.1 180.26,96.6 v1(179.91,96.95)
TOUCH_INT: length 36.4
  TOP w0.173: R802.2 82.51,95.38 v5(82.3,95.17)
  L3_SIG1 w0.109: v6(57.53,92.54) 57.53,92.84 59.02,94.33 67.99,94.33 68.61,93.71 70.44,93.71 72.35,95.62 75.85,95.62 76.03,95.43 77.6,95.43 78.59,94.44 79.74,94.44 80.46,95.17 v5(82.3,95.17)
  L10_SIG4 w0.109: v6(57.53,92.54) 57.53,90.63 58.29,89.87 v9(58.29,88.29)
  BOTTOM w0.173: R418.2 v9(58.29,88.29)
TSC_INT: length 2
  BOTTOM w0.173: R418.1 55.5,88.51 J17.4
TSC_RESETN: length 3.4
  BOTTOM w0.173: R792.1 R420.2 54.94,88.01 J17.3
UARTX_RXD: length 73.7
  TOP w0.173: v5(150.62,76.03) 149.99,75.39 137.41,75.39 132.59,70.57 132.59,63.5 128.78,59.69 113.28,59.69 111.89,61.09 R487.2 ; v5(162.31,79.2) 163.41,78.1 167.68,78.1 168.54,78.96 169.08,78.96 169.15,78.89 U37.38
  L3_SIG1 w0.109: v5(162.31,79.2) 161.4,79.2 160.81,78.61 159.37,78.61 157.84,77.09 155.67,77.09 154.49,75.9 154.12,75.9 153.23,76.79 151.38,76.79 v5(150.62,76.03)
UARTX_TXD: length 69.9
  TOP w0.173: v1(130.73,62.95) 130.73,62.15 128.65,60.07 113.92,60.07 113.03,60.96 R486.2 ; v1(167.89,79.08) 168.21,79.39 U37.39
  L3_SIG1 w0.109: v1(137.54,71.22) 138.46,72.14 140.17,72.14 140.9,72.87 142.67,72.87 143.69,73.89 154.62,73.89 155.81,75.08 163.02,75.08 164.26,76.33 165.15,76.33 v1(167.89,79.08)
  BOTTOM w0.173: v1(130.73,62.95) 130.73,67.69 134.27,71.22 v1(137.54,71.22)
USB1_3_0_STDA_SSRX+: length 110.4
  TOP w0.15: U1.AE12 93.44,84.01 93.37,84.01 v4(93.32,84.06)
  L3_SIG1 w0.109: v4(93.32,84.06) arc(92.94,84.23) 92.53,84.29 92.38,84.29 arc(91.83,84.4) 91.37,84.71 91.35,84.74 arc(89.41,86.08) 87.12,86.65 arc(86.91,86.66) 86.7,86.66 82.34,86.66 arc(81.97,86.74) 81.66,86.94 arc(81.33,87.17) 80.93,87.25 79.02,87.25 arc(78.51,87.14) 78.07,86.85 77.3,86.08 arc(75.89,85.14) 74.23,84.81 68.84,84.81 arc(66.66,84.37) 64.8,83.13 60.59,78.92 arc(59.74,77.65) 59.44,76.16 59.44,69.4 arc(58.97,67.03) 57.63,65.01 43.27,50.66 arc(42.23,49.1) 41.87,47.26 41.87,27.11 arc(41.71,25.97) 41.24,24.93 arc(40.51,23.19) 40.35,21.32 arc(40.32,21.07) v1(40.19,20.85)
  BOTTOM w0.15: v1(40.19,20.85) arc(40.31,20.68) 40.35,20.48 40.35,19.93 40.25,19.83 U95.2 40.25,18.27 40.35,18.17 40.35,17.9 arc(40.63,17.22) 41.3,16.94 41.9,16.94 arc(42.4,16.72) 42.61,16.21 arc(42.36,15.57) J23.6
USB1_3_0_STDA_SSRX-: length 110.4
  TOP w0.15: v4(92.66,83.99) U1.AF12
  L3_SIG1 w0.109: v4(92.66,83.99) 92.38,83.99 arc(91.72,84.12) 91.16,84.5 91.13,84.52 arc(89.28,85.8) 87.1,86.35 arc(86.9,86.36) 86.69,86.36 86.29,86.36 arc(86.17,86.31) 86.13,86.2 86.13,86.04 arc(85.96,85.87) 85.8,86.04 85.8,86.2 arc(85.63,86.36) 85.47,86.2 85.47,86.04 arc(85.31,85.87) 85.14,86.04 85.14,86.2 arc(85.09,86.31) 84.98,86.36 82.34,86.36 arc(81.85,86.46) 81.45,86.73 arc(81.21,86.89) 80.93,86.94 79.02,86.94 arc(78.62,86.86) 78.29,86.64 77.52,85.87 arc(76.01,84.86) 74.23,84.5 68.84,84.5 arc(66.77,84.09) 65.02,82.92 60.8,78.7 arc(60.02,77.54) 59.75,76.16 59.75,69.4 arc(59.25,66.91) 57.84,64.8 43.49,50.45 arc(42.51,48.98) 42.17,47.26 42.17,27.11 arc(42,25.89) 41.5,24.77 arc(40.81,23.11) 40.65,21.33 arc(40.69,21.08) v1(40.8,20.85)
  BOTTOM w0.15: v1(40.8,20.85) arc(40.69,20.68) 40.65,20.48 40.65,19.93 40.75,19.83 U95.1 40.75,18.27 40.65,18.17 40.65,17.9 arc(40.84,17.44) 41.3,17.25 41.9,17.25 arc(42.62,16.93) 42.92,16.21 arc(43.15,15.59) J23.5
USB1_3_0_STDA_SSTX+: length 11.1
  BOTTOM w0.15: C555.2 arc(36.83,22.76) 36.93,22.5 36.93,21.99 arc(37.21,21.36) 37.84,21.1 37.85,21.1 arc(37.86,21.1) 37.87,21.1 38,21.11 38,21.11 arc(38.6,20.91) 38.85,20.33 38.85,19.93 38.75,19.83 U95.5 38.75,18.27 38.85,18.17 38.85,17.9 arc(38.66,17.44) 38.2,17.25 37.6,17.25 arc(36.88,16.93) 36.58,16.21 arc(36.34,15.58) J23.9
USB1_3_0_STDA_SSTX-: length 11.1
  BOTTOM w0.15: J23.8 arc(37.13,15.58) 36.89,16.21 arc(37.1,16.72) 37.61,16.94 38.2,16.94 arc(38.87,17.22) 39.15,17.9 39.15,18.17 39.25,18.27 U95.4 39.25,19.83 39.15,19.93 39.15,20.33 arc(38.8,21.13) 37.97,21.41 37.85,21.4 37.85,21.4 arc(37.42,21.57) 37.24,22 37.24,22.5 arc(37.34,22.76) C554.2
USB1_CONN_DM: length 15.5
  TOP w0.15: v1(45.42,22.19) 45.57,22.03 45.57,21.41 45.21,21.06 43.28,21.06 42.88,20.65 42.88,20.27 42.7,20.1 U64.2 42.7,19.13 42.55,18.97 42.55,18.03 42.88,17.7 42.88,17.48 42.7,17.3 39.91,17.3 39.58,16.97 39.58,16.62 v1(39.43,16.47)
  BOTTOM w0.15: v1(39.43,16.47) 38.74,15.77 J23.2 ; v1(45.42,22.19) 45.57,22.34 45.57,22.76 45.32,23.01 L11.4
USB1_CONN_DP: length 15.6
  TOP w0.15: v1(40.04,16.47) 39.89,16.62 39.89,16.84 40.04,16.99 42.82,16.99 43.18,17.35 43.18,17.65 43.56,18.03 43.56,18.97 43.4,19.13 U64.1 43.4,20.1 43.18,20.32 43.18,20.52 43.41,20.75 45.34,20.75 45.87,21.29 45.87,22.03 v1(46.02,22.19)
  BOTTOM w0.15: v1(46.02,22.19) 45.87,22.34 45.87,22.76 46.12,23.01 L11.3 ; J23.3 40.74,15.77 v1(40.04,16.47)
USB1_OVRCURN: length 2.9
  BOTTOM w0.381: U66.5 R551.1
USB1_VBUS_EN: length 179.4
  TOP w0.173: R557.1 81.89,90.51 v5(80.88,91.52)
  L3_SIG1 w0.109: v5(80.88,91.52) 80.62,91.26 78.12,91.26 77.52,91.86 74.53,91.86 73.6,92.79 71.34,92.79 70.63,92.08 68.86,92.08 68.52,91.74 59.52,91.74 58.42,90.63 v6(58.42,90.63)
  L4_SIG2 w0.114: v1(25.27,3.68) 23.95,2.36 13.85,2.36 9.8,6.41 8.21,6.41 7.61,7.01 7.61,25.73 5.19,28.15 5.19,39.91 4.19,40.91 4.19,43.64 5.19,44.64 5.19,56.85 7.93,59.59 12.52,59.59 27.47,74.54 27.47,76.43 28.26,77.22 28.26,78.84 28.92,79.51 28.92,83.61 30.29,84.98 32.69,84.98 37.58,89.87 47.75,89.87 51.18,86.44 54.23,86.44 56.26,88.47 57.53,88.47 58.42,89.36 v6(58.42,90.63)
  BOTTOM w0.173: v1(25.27,3.68) R553.1 U66.4
USB2_CONN_DM: length 5.5
  TOP w0.15: v1(5.26,40.47) 5.41,40.62 6.2,40.62 U93.2
  BOTTOM w0.15: J45.2 4.68,40.45 4.85,40.62 5.11,40.62 v1(5.26,40.47) 5.39,40.6 7.1,40.6 7.25,40.75 7.76,40.75 8.02,40.49 L33.3
USB2_CONN_DP: length 5.6
  TOP w0.15: U93.1 5.88,41.09 5.71,40.92 5.41,40.92 v1(5.26,41.08)
  BOTTOM w0.15: J45.3 4.67,41.1 4.86,40.92 5.1,40.92 v1(5.26,41.08) 5.41,40.92 6.96,40.92 7.12,41.08 7.8,41.08 8.02,41.29 L33.4
USB2_ID: length 10.3
  TOP w0.173: U93.3 6.1,40.09 5.87,39.86 4.83,39.86 4.6,40.09 4.6,41.41 4.95,41.76 v1(5.77,41.76)
  BOTTOM w0.173: J45.4 5.76,41.75 v1(5.77,41.76) 6.84,41.76 R808.1 R788.1
USB2_OVRCURN: length 4.3
  TOP w0.173: U94.5 18.92,41.48 18.03,42.37 R790.1
USB2_VBUS_EN: length 95.9
  TOP w0.173: U94.4 R791.1 35.32,46.82 39.46,50.96 40.33,50.96 43.56,54.19 43.56,55.68 43.13,56.11 43.13,56.77 55.49,69.12 55.49,76.53 55.89,76.93 55.89,79.21 66.76,90.08 66.76,91.63 67.56,92.43 68.17,92.43 68.62,92.88 75.78,92.88 76.65,92 77.72,92 78.41,91.31 79.86,91.31 81.53,89.64 81.53,89.15 R787.1
USBJTAG_ENN: length 39.1
  TOP w0.173: U65.4 174.59,70.83 v1(175.22,70.2)
  BOTTOM w0.173: U63.15 174.52,83.47 174.35,83.64 174.35,83.88 174.59,84.12 U63.14 177.68,84.12 178.59,83.22 R677.2 178.59,78.21 175.9,75.52 175.9,70.88 v1(175.22,70.2) 175.22,62.27 174.12,61.17 170.56,61.17 169.55,62.18 169.55,63.1 170.44,64 U75.4
VADD33_PRU1ETH0: length 3.9
  TOP w0.381: v7(22.41,122.51) 23.11,122.51 23.48,122.88 R97.2 22.98,123.4 v7(22.48,123.4)
  BOTTOM w0.254: v7(22.41,122.51) 22.09,122.19 U9.14
VADD33_PRU1ETH1: length 2.5
  TOP w0.254: 26.54,99.52 26.68,99.66 U13.14
  vias: v7(26.26,100.26) v7(26.54,98.77)
VADD33_PRU2ETH0: length 3.3
  TOP w0.254: 27.97,81.88 U15.14
  TOP w0.508: 27.97,81.88 26.68,81.88 26.54,81.74 v7(26.54,80.99)
  vias: v7(26.21,82.61)
VADD33_PRU2ETH1: length 2.4
  TOP w0.254: v7(27.43,56.98) 27.57,57.12 U17.14
  TOP w0.508: 26.54,56.98 v7(26.54,56.23)
VAM572X_DDR1: length 25.8
  TOP w0.254: v4(91.39,66.93) 91.39,68.25 91.8,68.66 91.8,69.49 92.24,69.93 U1.AG28 ; U1.AA22 v4(96.64,75.22) ; U1.AH27 v11(91.04,71.22) ; U1.AA21 v4(96.64,76.02) ; U1.AD26 v11(94.24,72.02) ; U1.W16 v11(98.24,80.02) ; U1.AG20 v4(91.84,76.82) ; v4(98.04,71.21) 98.23,71.21 U1.W27 ; U1.AB22 v4(95.84,75.22) ; U1.AC22 v4(95.04,75.22) ; U1.AB21 v4(95.84,76.02) ; U1.AB25 v4(95.84,72.82) ; U1.AB24 v4(95.84,73.62)
  L3_SIG1 w0.254: v11(98.24,80.02) v6(97.84,79.77) ; v4(95.84,75.22) v6(95.44,74.97) ; v11(91.04,71.22) v6(90.64,70.97) ; v4(98.04,71.21) v6(97.64,70.83) ; v4(95.04,75.22) v6(94.64,74.97) ; v4(96.64,75.22) v6(96.24,74.97) ; v4(95.84,73.62) v6(95.44,73.37) ; v4(91.84,76.82) v6(91.44,76.57) ; v4(95.84,72.82) v6(95.59,72.42) ; v11(94.24,72.02) v6(93.84,71.77) ; v4(95.84,76.02) v6(95.44,75.77) ; v4(91.39,66.93) v6(91.06,66.6) ; v4(96.64,76.02) v6(96.24,75.77)
  L10_SIG4 w0.254: v11(95.01,74.53) 95.01,74.54 v6(95.44,74.97) ; v11(95.04,75.52) v6(95.44,75.77) ; v6(97.64,70.83) 97.62,70.83 97.7,71.18 v11(97.59,71.37) ; v11(91.04,71.22) v6(90.64,70.97) ; v11(95,72.69) 95.27,72.42 v6(95.59,72.42) ; v11(94.88,73.41) 94.93,73.37 v6(95.44,73.37) ; v6(96.24,75.77) 96.18,75.51 v11(95.85,75.31) ; v11(94.24,72.02) v6(93.84,71.77) ; v11(95.67,74.49) 95.76,74.49 v6(96.24,74.97) ; v11(94.04,74.9) 94.11,74.97 v6(94.64,74.97) ; v11(98.24,80.02) v6(97.84,79.77)
  BOTTOM w0.381: C114.1 98.24,79.39 v11(98.24,80.02) ; v11(91.04,71.22) 90.8,71.45 C12.1
  vias: v7(61.02,78.12) v7(60.96,77.3) v7(60.96,76.28) v7(62.23,77.3) v7(62.23,76.28) v7(62.29,78.12) v7(63.56,78.12) v7(66.17,69.42) v7(67.31,71.33) v7(68.2,71.71) v7(69.09,71.96) v10(95.89,71.84) v10(96.14,72.09) v11(95.89,71.84) v11(96.14,72.09)
VAM572X_DDR2: length 19.8
  TOP w0.254: U1.H20 v4(107.83,76.82) ; U1.T25 v4(100.64,72.82) ; U1.H21 v4(107.83,76.02) ; U1.M21 v4(104.63,76.02) ; U1.E24 v4(110.23,73.62) ; U1.H22 v4(107.83,75.22) ; U1.G23 v4(108.63,74.42) ; U1.L20 v4(105.43,76.82) ; U1.J27 v4(107.03,71.22) ; U1.G22 v4(108.63,75.22) ; U1.M20 v4(104.63,76.82) ; U1.L21 v4(105.43,76.02) ; U1.T24 v4(100.64,73.62)
  L3_SIG1 w0.254: v4(107.83,75.22) v6(108.23,74.97) ; v6(101,73.26) 100.65,73.62 v4(100.64,73.62) ; v4(110.23,73.62) v6(110.63,73.37) ; v4(108.63,74.42) v6(109.03,74.17) ; v4(105.43,76.02) v6(105.83,75.77) ; v4(104.63,76.02) v6(105.03,75.77) ; v4(108.63,75.22) v6(109.03,74.97) ; v4(107.83,76.02) v6(108.23,75.77) ; v6(101,72.46) 100.65,72.82 v4(100.64,72.82) ; v4(107.83,76.82) v6(108.23,76.57) ; v4(105.43,76.82) v6(105.83,76.57) ; v4(104.63,76.82) v6(105.03,76.57) ; v4(107.03,71.22) v6(107.43,70.97)
  L10_SIG4 w0.254: v11(105.43,76.32) v6(105.83,76.57) ; v11(107.83,76.32) v6(108.23,76.57) ; v6(101,72.46) v11(100.61,72.19) ; v11(104.62,76.23) v6(105.03,76.57) ; v11(107.83,74.72) v6(108.23,74.97) ; v11(105.43,75.52) v6(105.83,75.77) ; v11(108.63,73.92) v6(109.03,74.17) ; v6(101,73.26) v11(100.58,73.03) ; v11(107.83,75.52) v6(108.23,75.77) ; v11(104.63,75.52) v6(105.03,75.77) ; v11(108.63,74.72) v6(109.03,74.97) ; v11(110.23,73.12) v6(110.63,73.37) ; v9(107.86,70.61) v6(107.43,70.97)
  vias: v6(113.92,56.22) v6(113.92,54.56) v6(115.32,54.56) v6(116.84,56.22) v6(117.86,55.07) v7(66.42,57.1) v7(66.42,55.83) v7(67.44,57.1) v7(67.44,55.83) v7(68.26,57.04) v7(68.26,55.77) v7(68.26,54.5) v8(118.87,56.34) v8(118.87,55.07) v8(119.89,56.34) v8(119.89,55.07) v8(120.9,56.34) v8(120.9,55.07) v9(118.87,56.34) v9(118.87,55.07) v9(119.89,56.34) v9(119.89,55.07) v9(120.9,56.34) v9(120.9,55.07)
VANA_OUT: length 1.6
  TOP w0.381: U3.C8 v1(140.64,129.53)
  BOTTOM w0.508: C302.1 140.04,129.53 v1(140.64,129.53)
VCAN1: length 10.7
  TOP w0.508: 151.71,15.29 J38.1 ; J38.1 153.85,15.29 ; J38.1 153.85,13.16 ; J38.1 151.71,13.16
  BOTTOM w0.381: v7(154.76,23.96) C252.1 v7(155.58,23.25)
  BOTTOM w0.508: C252.1 156.4,23.96 156.53,23.83
  BOTTOM w0.635: 156.53,23.83 U41.8
VETH0_AVDDH: length 7.7
  TOP w0.254: U21.47 v5(39.57,123.11)
  TOP w0.305: U21.1 v7(37.93,125.26)
  TOP w0.381: U21.12 32.43,124.88 32.13,125.18 v7(31.37,125.18)
  L3_SIG1 w0.381: v5(39.57,123.11) v6(40.16,123.11)
  BOTTOM w0.381: v7(31.04,126.32) 30.3,126.32 C157.1 30.17,125.18 v7(31.37,125.18)
  vias: v7(46.86,123.65) v7(46.86,122.89) v7(47.75,123.65) v7(47.75,122.89)
VETH0_AVDDL: length 1.6
  TOP w0.254: U21.9 v7(33.93,125.16) ; U21.4 v7(36.43,125.16)
VETH0_AVDDL_PLL: length 3.3
  TOP w0.254: U21.44 39.49,121.61 39.62,121.75 C165.1
  TOP w0.381: C165.1 40.77,122 v7(41.4,122.64)
VETH0_AVDDL_PMOS: length 2.5
  TOP w0.381: v7(44.7,125.3) 44.7,125.99 C158.1 45.59,125.86 v7(45.59,125.3)
VETH0_DVDDH: length 20.2
  TOP w0.254: U21.40 39.23,119.61 39.36,119.74 v7(40.26,119.74) ; U21.34 v7(36.93,116.41)
  TOP w0.381: v6(41.66,118.45) v5(42.42,118.45) ; R279.2 v5(39.95,116.41) ; R299.1 v7(35.48,115.22) ; R309.1 31.5,115.3 v7(31.55,115.35) ; R306.1 32.77,115.17 v7(32.94,115.35) ; U21.16 29.74,122.11 v7(29.59,122.26) ; R301.1 v7(34.09,115.22)
  TOP w0.762: C156.1 v7(30.57,116.5) ; C156.1 29.29,117.61 v7(29.08,117.81) ; C156.1 v7(28.01,116.5)
  L3_SIG1 w0.381: v5(42.42,118.45) v6(41.66,118.45) ; v5(39.95,116.41) v6(39.37,116.41)
  BOTTOM w0.381: U22.5 36.71,109.43 C171.1 v7(39.36,109.43) ; R280.2 v7(40.26,110.7) ; D3.1 v7(42.16,112.86) ; C155.1 v7(29.59,122.26)
VETH0_DVDDL: length 6.8
  TOP w0.254: U21.30 v7(34.93,116.41) ; U21.23 30.19,118.61 30.18,118.6 30,118.6 v7(29.84,118.45) ; U21.18 v7(30.73,121.11) ; U21.26 v7(32.93,116.41) ; U21.14 v7(30.73,123.11) ; U21.39 v7(39.62,119.11)
VETH1_AVDDH: length 10.9
  TOP w0.254: U24.47 v7(63.12,123.11)
  TOP w0.305: v7(59.82,125.81) 59.65,125.64 U24.1
  TOP w0.381: U24.12 54.15,124.88 53.85,125.18 v7(53.09,125.18)
  L4_SIG2 w0.381: v7(59.82,125.81) 60.15,125.81 60.29,125.67 61.35,125.67 62.86,124.16 62.86,123.36 v7(63.12,123.11)
  vias: v7(64.9,130.26) v7(64.9,129.37) v7(66.04,130.26) v7(66.04,129.37)
VETH1_AVDDL: length 1.6
  TOP w0.254: U24.4 v7(58.15,125.16) ; U24.9 v7(55.65,125.16)
  vias: v7(64.01,124.64) v7(65.28,123.4)
VETH1_AVDDL_PLL: length 3
  TOP w0.254: U24.44 60.9,121.61 61.09,121.8 61.67,121.8 61.85,121.62 C186.1
  TOP w0.381: C186.1 v7(62.48,122.38)
  vias: v7(64.26,120.99) v7(65.15,120.99)
VETH1_DVDDH: length 18.7
  TOP w0.254: U24.34 v7(58.65,116.41) ; U24.16 51.46,122.11 v7(51.43,122.13) ; U24.40 61.74,119.61 61.87,119.74 v7(61.98,119.74)
  TOP w0.381: R342.2 63.5,118.83 v7(63.88,119.21) ; R353.1 52.58,114.13 v7(52.83,114.38) ; v7(54.23,114.38) 53.98,114.13 R352.1 ; v7(48.26,121.24) 48.59,121.24 48.66,121.3 49.24,121.3 49.66,120.88 R364.1 ; R345.1 v7(55.37,114.25) ; C174.1 50.67,122.51 v7(51.05,122.89) ; R343.1 v7(56.77,114.25)
  TOP w0.762: v7(50.67,114.5) C175.1 v7(49.39,113.22)
  BOTTOM w0.381: v7(61.07,109.43) C192.1 58.43,109.43 U26.5 ; R324.2 v7(61.98,110.7) ; 62.86,112.86 v7(63.75,112.86)
VETH1_DVDDL: length 10.1
  TOP w0.254: v7(51.7,118.31) 52,118.61 U24.23 ; U24.14 v7(52.45,123.11) ; U24.39 v7(61.34,119.11) ; U24.18 v7(52.45,121.11) ; U24.26 v7(54.65,116.41) ; U24.30 v7(56.65,116.41)
  TOP w0.381: C181.1 51.46,118.06 v7(51.7,118.31) ; v7(64.91,119.97) 65.04,119.84 FB7.2 65.04,117.94 v7(64.91,117.81)
VLDO1_OUT: length 2.4
  TOP w0.254: U3.C6 v1(138.25,129.53)
  BOTTOM w0.381: v1(138.25,129.53) 138.11,129.39
  BOTTOM w0.508: 138.11,129.39 C383.1 R657.2
VLDO2_OUT: length 1.6
  TOP w0.173: 138.94,131.02 138.94,131.49 139.18,131.73 v7(139.18,131.95)
  TOP w0.381: U3.B6 139.05,130.34
  vias: v7(139.18,133.48) v7(139.18,132.72)
VLED+: length 6.9
  BOTTOM w0.254: 73.54,141.58 U32.9 ; v7(81.53,128.48) 82.11,127.9 J16.29 ; v7(82.17,128.99) 82.75,128.4 J16.30
  vias: v7(71.75,139.53) v7(72.01,137.75) v7(72.39,140.42) v7(73.15,138.89)
VLED-: length 1
  BOTTOM w0.254: J16.23 J16.24 ; J16.28 J16.27
  vias: v7(81.03,145.75) v7(81.28,146.64) v7(81.53,145.12) v7(81.79,146) v7(82.17,126.57) v7(82.17,125.94) v7(83.06,126.57) v7(83.06,125.94)
VMAIN: length 201.1
  TOP w0.203: U3.A6 v5(138.25,130.34)
  TOP w0.254: U3.J2 v5(135.05,123.94) ; U3.C5 v5(137.45,129.53) ; U3.E2 v1(135.05,127.93) ; U3.F1 v1(134.25,127.13) ; U3.C7 v5(139.84,129.53) ; U3.H13 v5(144.64,124.74) ; U3.J3 v5(135.85,123.94) ; U3.H12 v5(143.84,124.74) ; U3.D13 v5(144.64,128.73) ; U3.C4 v5(136.65,129.53) ; U3.G13 v5(144.64,125.54) ; U3.E3 v1(135.85,127.93) ; U3.D12 v5(143.84,128.73) ; U3.H11 v5(143.04,124.74) ; U3.F3 v1(135.85,127.13) ; U3.E1 v1(134.25,127.93) ; U3.F2 v1(135.05,127.13) ; U3.J1 v5(134.09,124.34) ; U3.D11 v5(143.04,128.73) ; U3.G12 v5(143.84,125.54) ; U3.G11 v5(143.04,125.54)
  TOP w0.381: U76.1 145.27,100.81 C407.1 145.03,101.4 v7(145.56,101.93) ; R20.2 142.88,138.56 v7(145.03,140.72) ; U3.M9 U3.N9 141.05,120.4 v7(141.1,120.35) ; v7(148.21,3.89) 139.32,3.89 137.67,5.54 137.67,14.05 138.48,14.86 R113.2 ; U3.M8 U3.N8 140.25,120.44 v7(140.34,120.35) ; v7(145.42,121.37) 145.42,121.57 v7(145.07,121.91) U3.L13 144.12,122.61 143.58,122.61 U3.L12 ; v7(138.68,119.84) 138.65,119.88 v7(138.65,120.56) U3.N6 U3.M6 ; U96.5 v7(152.15,142.38) ; U3.M4 U3.N4 137.05,120.89 v5(136.65,120.49) 136.25,120.89 U3.N3 ; U3.A10 142.1,130.99 v7(142.1,131.73) ; v7(141.42,131.67) 141.42,131.11 U3.A9 ; v7(130.85,142.61) 131.01,142.45 C152.1 ; R19.2 v7(141.73,141.05)
  L3_SIG1 w0.381: v7(176.05,123.4) 176.05,129.75 TP1.1
  L4_SIG2 w0.381: v7(148.21,3.89) 149.64,3.89 151.64,1.89 168.68,1.89 170.94,4.16 170.94,10.5 182.26,21.81 182.26,53.68 176.78,59.16 176.78,69.93 177.18,70.32 177.18,79.7 175.13,81.74 175.13,90.49 169.53,96.09 v7(168.53,96.09)
  L6_PWR1 w0.508: 158.22,136.31 J9.1 ; J9.1 159.84,137.92 ; J9.1 158.22,137.92 ; J9.1 159.84,136.31
  BOTTOM w0.203: U62.A2 U62.A1
  BOTTOM w0.254: U62.A1 154.24,106.74 154.24,106.74 ; U32.2 73.54,147.73 C217.1
  BOTTOM w0.381: v7(138.65,120.56) 138.22,120.99 C272.1
  BOTTOM w0.508: R411.2 v7(74.55,140.03)
  vias: v2(135.64,119.72) v2(136.4,119.97) v5(135.64,119.72) v5(136.4,119.97) v6(132.72,124.67) v6(132.72,124.03) v6(133.35,124.67) v6(133.35,124.03) v6(133.99,132.42) v6(134.62,132.42) v6(135.26,132.42) v6(135.77,132.09) v6(136.14,119.33) v6(136.67,121.05) v6(136.94,119.83) v6(139.19,130.54) v6(139.86,130.7) v6(140.23,131.25) v6(145.77,125.81) v6(145.92,129.37) v6(145.92,128.73) v6(145.9,125.13) v6(146.53,125.81) v6(146.69,129.37) v6(146.69,128.73) v6(146.66,125.13) v6(147.29,125.81) v6(147.42,125.13) v7(71.25,149.69) v7(72.14,150.07) v7(72.9,149.69) v7(76.07,108.67) v7(76.83,108.67) v7(77.22,129.24) v7(77.72,108.67) v7(78.11,130) v7(78.11,129.24) v7(78.61,108.67) v7(78.99,130) v7(78.99,129.24) v7(140.84,119.72) v7(141.35,119.21) v7(149.99,107.9) v7(149.99,106.66) v7(150.8,107.93) v7(150.8,106.66) v7(155.7,131.78) v7(155.7,130.76) v7(155.83,129.49) v7(156.34,128.48) v7(158.12,128.43) v7(166.27,114.64) v7(166.27,113.5) v7(167.41,114.64) v7(167.41,113.5) v7(168.68,114.64) v7(168.68,113.49) v7(174.9,124.54) v7(174.9,123.4) v7(174.9,122.13) v7(176.05,122.13) v7(177.32,123.4) v7(177.32,122.13) v7(178.59,124.54) v7(178.59,123.4) v7(178.59,122.13) v7(179.86,124.54) v7(179.86,123.4) v7(179.86,122.13) v7(184.43,123.53) v7(184.43,122.26) v8(134.34,130.85) v8(135.1,130.85) v8(135.77,131.48) v8(135.77,130.87) v8(145.16,129.37) v8(145.16,128.61) v8(145.29,124.29) v8(145.29,123.53) v8(146.18,124.29) v8(146.18,123.53) v8(147.07,124.29) v8(147.07,123.53) v9(134.34,130.85) v9(135.1,130.85) v9(135.77,131.48) v9(135.77,130.87) v9(145.16,129.37) v9(145.16,128.61) v9(145.29,124.29) v9(145.29,123.53) v9(146.18,124.29) v9(146.18,123.53) v9(147.07,124.29) v9(147.07,123.53)
VPP_CONN: length 115.7
  BOTTOM w0.508: R797.1 122.05,80.73 124.59,78.19 124.59,43.44 132.42,35.6 140.08,35.6 149.18,26.5 171.63,26.5 174.04,24.09 174.04,20.51 174.38,20.17 174.38,17.49 171.2,14.31 171.2,9.99 170.18,8.97 J46.2
VPP_EN: length 6.1
  TOP w0.173: U1_1.3 174.66,7.94 R2_1.1 174,5.7 174,4.36 J1_1.4
VPROFI: length 12.8
  TOP w0.381: R577.2 v7(113.03,8.89)
  TOP w0.508: J14.6 98.3,5.39 98.3,5.4 C430.1 99.31,6.1 v7(99.44,6.22) v7(100.2,6.22)
  L9_SIG3 w0.381: v7(112.39,3.81) 111.63,4.57 111.63,7.49 v7(113.03,8.89)
  vias: v7(100.97,6.22) v7(101.98,6.22) v7(112.39,3.05) v7(113.16,2.41) v7(114.05,2.41)
VPROFI_SRC: length 5.2
  BOTTOM w0.381: D15.1 D14.1 118.6,7 C433.1
VPWRIN_JCK: length 28.8
  TOP w0.508: 185.67,108.54 J2.1 ; J2.1 187.28,110.15 ; J2.1 185.67,110.15 ; J2.1 187.28,108.54 ; J1.1 175.99,114.37 ; J1.1 175.99,109.05 ; J1.1 173.29,111.76 ; J1.1 178.58,111.76
  BOTTOM w0.508: 185.67,108.54 J2.1 ; J2.1 187.28,110.15 ; J2.1 185.67,110.15 ; J2.1 187.28,108.54 ; 174.38,113.37 J1.1 ; J1.1 177.61,110.15 ; J1.1 174.38,110.15 ; J1.1 177.61,113.37
VPWRIN_PREFUSE:
  vias: v7(169.57,107.27) v7(172.11,107.27) v7(173.38,106) v7(173.38,104.73) v7(173.38,103.46)
VRTC_OUT: length 32.7
  TOP w0.381: U3.A8 140.72,131.21 140.72,132.29 ; 140.72,132.29 140.72,132.8 141.35,133.43 ; 140.72,132.29 140.97,132.54 ; v7(93.47,104.57) 93.47,104.37 93.85,103.99 R645.2
  TOP w0.762: 141.73,133.3 140.97,132.54
  L10_SIG4 w0.381: v7(140.97,134.96) 141.42,135.41 142.93,135.41 144.17,134.17 144.17,129.93 141.85,127.6 141.14,127.6 140.93,127.39 139.89,127.39 139.62,127.66 138.71,127.66 136.87,125.82 136.87,123.05 v9(137.13,122.78) 138.68,121.24 v9(140.08,121.24)
  BOTTOM w0.381: v7(141.3,134.4) 141.3,134.63 v7(140.97,134.96) 140.59,134.57 v7(140.59,134.45) ; R794.2 140.69,121.85 v9(140.08,121.24) ; v9(137.13,122.78) 136.97,122.78 136.63,122.44 R17.2
VSDMMC: length 97.2
  TOP w0.254: U1.W8 v4(98.24,87.21) ; U1.Y8 v4(97.44,87.21)
  TOP w0.381: R644.2 85.99,107.9 v7(85.39,108.5)
  TOP w0.635: R644.2 86.61,110.16 85.01,111.76 85.01,112.93 81.41,116.54 81.41,118.57 80.52,119.46 80.52,128.69 82.93,131.1 82.93,137.24 87,141.31 v7(87,146.88)
  L3_SIG1 w0.254: v4(97.44,87.21) v6(97.04,87.46) ; v4(98.24,87.21) v6(97.84,87.46)
  L10_SIG4 w0.254: v11(97.45,87.08) v6(97.84,87.46) ; v11(96.65,87.08) v6(97.04,87.46)
  L10_SIG4 w0.635: 97.82,138.87 v9(98.68,138.87) 100.18,138.87 102.38,136.66 107.43,136.66 110.03,134.06 v9(110.03,131.7) ; 97.82,138.87 96.19,138.87 v7(95.91,138.59) ; 97.82,138.87 v9(97.84,138.84) ; v9(111.3,131.7) 113.28,131.7 113.85,131.13 116.04,131.13 116.76,130.42 131.82,130.42 133.11,129.13 134.36,129.13 134.58,129.35 v9(135.49,129.35) v9(136,128.84)
  BOTTOM w0.381: v7(86.39,96.09) C483.1 v7(85.33,97.26) ; v9(135.49,129.35) v9(136,128.84) R657.1
  vias: v6(92.96,91.27) v6(93.47,90.63) v6(95.17,92.48) v8(94.81,91.94) v8(94.81,91.17) v8(94.81,90.41) v8(94.81,89.65) v8(111.3,130.81) v9(94.81,91.94) v9(94.81,91.17) v9(94.81,90.41) v9(94.81,89.65) v9(111.3,130.81)
VSMPS1_2:
  vias: v7(114.05,133.05) v7(114.05,132.16) v7(115.32,133.05) v7(115.32,132.03) v7(115.37,134.32) v7(116.46,134.32) v7(116.46,133.05) v7(116.46,132.03) v7(152.15,130.38) v7(153.42,130.38) v7(154.18,133.3) v7(154.18,132.29) v7(154.18,129.06) v7(154.18,127.59)
VSMPS1_SW: length 2.3
  TOP w0.381: 144.79,127.88 144.45,127.54 U3.E13 U3.E12 U3.E11
VSMPS2_SW: length 2.6
  TOP w0.381: 145.17,126.85 145.05,126.74 144.65,126.74 144.65,126.74 U3.F13 U3.F12 U3.F11
VSMPS3_SW: length 3.1
  TOP w0.305: U3.J11 142.82,124.16 143.27,124.16 U3.J12 143.62,124.16 144.07,124.16 U3.J13
  TOP w0.381: 145.42,124.16 144.42,124.16 U3.J13
VSMPS4_5: length 3.9
  BOTTOM w0.381: v7(130.18,120.58) 129.41,120.58 128.73,119.89 C280.1 ; v7(130.18,128.1) 129.23,128.1 C279.1
  vias: v7(130.18,128.73) v7(130.18,127.46) v7(130.18,119.82) v7(130.18,119.18)
VSMPS4_SW: length 3.8
  TOP w0.381: 132.72,126.32 132.84,126.45 133.62,126.45 134.13,125.94 U3.G1 U3.G2 U3.G3
VSMPS5_SW: length 3.5
  TOP w0.381: 132.84,124.92 133.06,125.14 U3.H1 U3.H2 U3.H3
VSMPS6_SW: length 2.7
  TOP w0.381: U3.M5 U3.N5 137.85,119.51 137.67,119.33
VSMPS7:
  vias: v7(106.1,133.18) v7(106.1,131.91) v7(107.37,133.18) v7(107.37,131.91) v7(127.53,135.82) v7(128.8,135.82) v7(130.07,135.44) v7(130.07,134.17)
VSMPS7_SW: length 2.1
  TOP w0.381: U3.D3 136.25,128.38 136.02,128.61 135.71,128.61 U3.D2 135.39,128.34 135.13,128.61 134.91,128.61 U3.D1
VSMPS8_SW: length 4.4
  TOP w0.381: 143,118.06 142.11,118.95 142.11,120.73 141.85,121 U3.N10 U3.M10
VSMPS9: length 0.8
  L10_SIG4 w0.381: 139.95,125.43 v6(139.95,126.19)
  vias: v6(138.05,125.81) v6(138.61,125.89) v6(140.72,126.19) v7(138.94,111.21) v7(140.34,111.21) v7(141.73,111.21) v8(138.3,125.3) v8(138.3,124.67) v8(139.19,125.3) v8(139.19,124.67) v9(138.3,125.3) v9(138.3,124.67) v9(139.19,125.3) v9(139.19,124.67)
VSMPS9_SW: length 2.5
  TOP w0.381: 139.45,119.46 U3.N7 U3.M7
VUSB_FTDI: length 88.6
  TOP w0.381: C226.1 FB9.2
  TOP w0.508: D13.2 163.12,90.57 R491.2
  L10_SIG4 w0.381: v7(164.9,90.56) 164.9,88.88 166.88,86.9 166.88,84.99 166.4,84.51 166.4,81.92 164.96,80.48 164.96,78.43 170.43,72.96 170.43,69.54 170.18,69.3 170.18,67.39 170.43,67.14 170.43,63.38 170.02,62.96 170.02,61.33 171.87,59.47 171.87,55.41 172.67,54.62 172.67,43.97 171.32,42.63 171.32,39.62 170.56,38.86 170.56,28.53 173.6,25.49 173.6,23.69 172.61,22.69 172.61,20.66 171.71,19.77 171.71,18.87 174.62,15.96 v7(175.26,15.96)
VUSB_JTAG: length 6.8
  TOP w0.254: U36.1 182.77,15.35 v7(182.73,15.39)
  TOP w0.381: C225.1 FB9.1 ; J19.1 185.28,13.1 v7(185.19,13)
  BOTTOM w0.381: v7(182.73,15.39) 185.11,13 v7(185.19,13)
VUSB_VBUS1: length 2.5
  L10_SIG4 w0.508: J23.1 36.83,13.19 ; J23.1 36.83,14.37 ; J23.1 35.65,13.19
  vias: v7(25.53,13.08) v7(26.8,13.08) v7(28.07,13.08) v7(29.34,13.08) v7(33.27,5.97) v7(33.27,4.83) v7(37.85,2.54)
VUSB_VBUS2: length 240.6
  TOP w0.508: 13.8,39.16 J50.2 ; J50.2 15.41,39.16 ; J50.2 15.41,37.55 ; J50.2 13.8,37.55
  L9_SIG3 w0.381: v6(18.19,124.05) 19.18,123.06 19.18,113.56 24.51,108.23 24.51,102.84 25.73,101.63 26.49,101.63 28.19,99.92 28.19,98.25 27.05,97.1 27.05,95.81 34.19,88.67 34.19,82.27 28.96,77.04 28.96,75.44 27.51,73.99 27.51,69.34 24.59,66.42 24.59,50.7 26.7,48.59 26.7,42.09 25.65,41.05 v7(25.65,38.76)
  L10_SIG4 w0.381: v9(138.3,128.1) 137.67,128.1 136.93,127.36 136.93,127.11 134.26,124.45 134.26,122.5 133.52,121.76 131.07,121.76 130.04,122.79 128.4,122.79 122.79,128.4 119.76,128.4 117.67,126.31 111.85,126.31 111.02,127.14 102.45,127.14 100.2,129.39 100.2,130.48 99.21,131.47 97.38,131.47 96.32,130.4 93.73,130.4 92.05,128.73 87.27,128.73 86.87,128.32 84.28,128.32 82.8,129.79 81.64,129.79 79.22,132.21 76.53,132.21 75.23,130.91 32.79,130.91 31.67,129.79 25.91,129.79 21.11,124.99 19.13,124.99 v6(18.19,124.05)
  BOTTOM w0.381: R21.2 138.56,127.84 v9(138.3,128.1)
  vias: v7(8.38,38.18) v7(8.51,39.5) v7(9.53,39.45) v7(9.53,38.18)
XTIN: length 9.2
  TOP w0.173: Y5.1 153.34,86.38 153.61,86.11 C243.1 155.63,86.11 156.26,85.48 156.26,84.2 157.07,83.39 U37.2
XTOUT: length 7.5
  TOP w0.173: U37.3 156.38,82.89 156.34,82.94 C244.1 153.72,82.94 153.07,82.28 Y5.2
N10692191: length 11.9
  TOP w0.173: SW2.3 SW2.4 v1(171.54,51.42)
  BOTTOM w0.173: v1(171.54,51.42) 170.91,51.42 169.8,52.53 169.8,53.54 U48.1 R11.2
N10692247: length 5.7
  BOTTOM w0.173: R11.1 C5.1 R914.1 166.5,50.55 165.99,50.04 U97.2
N11217419: length 2.2
  BOTTOM w0.173: C85.1 R46.1 R47.1
N11219802: length 1.8
  TOP w0.305: 106.81,11.51 107.32,12.03 U8.7
N11219922: length 1.6
  TOP w0.305: R56.1 108.32,11.63 U8.9
N11219986: length 2.9
  TOP w0.173: R69.1 C101.1 105.26,16.36 U8.5
N11220684: length 1.8
  TOP w0.173: U8.1 110.52,16.36 C86.1
N12123192: length 7
  BOTTOM w0.173: R293.2 28.74,145.88 J10.11
N12123204: length 6.1
  BOTTOM w0.173: J10.14 34.26,145.97 R296.2
N12138943: length 2.4
  TOP w0.173: U21.48 39.71,123.61 R298.1
N12139138: length 5.3
  TOP w0.173: U21.41 39.78,120.11 40.01,120.34 40.4,120.34 41.02,119.72 43.43,119.72 TP16.1
N12220066: length 22.6
  TOP w0.173: C109.1 21.72,119.59 C111.1 21.59,120.48 v1(21.59,122.13) ; v1(24.31,115.85) 24.37,115.91 25.95,115.91 C110.1
  L9_SIG3 w0.114: v1(24.31,115.85) 24.31,117.25 21.59,119.97 v1(21.59,122.13)
  L10_SIG4 w0.109: v1(21.59,122.13) 21.84,121.87 22.61,121.87 23.09,122.36 24.28,122.36 v9(24.51,122.13)
  BOTTOM w0.173: v1(24.31,115.85) C108.1 25.17,116.39 24.61,116.95 U9.24 ; U9.15 22.59,121.98 22.99,122.38 24.26,122.38 v9(24.51,122.13) ; U9.13 v1(21.59,122.13)
N12225140: length 4.2
  BOTTOM w0.173: J5.11 8.21,113.46 R122.1
N12225158: length 11.1
  TOP w0.173: U13.15 28.05,99.16 v1(27.55,98.66) ; C123.1 34.42,95.97 v5(33.53,96.86) 33.25,97.14 U13.24 ; v5(27.43,100.31) 28.05,100.31 28.19,100.16 U13.13
  BOTTOM w0.173: C124.1 C126.1 28.58,97.36 v1(28.7,97.24) ; v1(27.55,98.66) 27.55,97.86 27.29,97.6 C125.1
N12225278: length 5.4
  BOTTOM w0.173: R151.1 6.23,105.03 J5.10
N12226470: length 4.6
  BOTTOM w0.173: R134.1 7.7,99.4 J5.9
N12226568: length 2.6
  BOTTOM w0.173: U69.1 31.83,89.24 R153.1 R154.1
N12957779: length 2.5
  TOP w0.173: R482.2 166.14,72.24 U37.28
N12957783: length 9.5
  TOP w0.173: R482.1 v1(165.91,67.39)
  BOTTOM w0.173: U75.6 170.84,66.07 169.52,67.39 v1(165.91,67.39)
N12957791: length 2.8
  TOP w0.173: R489.2 169.09,72.78 168.14,73.72 U37.32
N12957851: length 4.6
  TOP w0.173: R492.2 R494.2 R491.1 163.14,88.25 U37.59
N12958009: length 2.6
  TOP w0.173: U37.14 156.18,77.39 R485.1
N12958129: length 2.2
  TOP w0.173: R493.2 161.98,90.95 D13.1
N12958219: length 15.1
  BOTTOM w0.173: R496.1 R495.2 160.48,85.48 159.89,86.07 159.89,87.88 160.03,88.02 160.03,94.35 160.89,95.2 U38.4
N12958339: length 3.2
  TOP w0.173: U37.36 171.08,77.89 172.26,76.71 TP18.1
N12958347: length 2.7
  TOP w0.173: R493.1 162.64,87.61 U37.60
N12958879: length 28.2
  TOP w0.173: R474.1 v1(154.31,76.33)
  L9_SIG3 w0.114: v1(172.64,85.48) 172.19,85.93 160.66,85.93 155.62,80.9 155.62,77.65 v1(154.31,76.33)
  BOTTOM w0.173: v1(172.64,85.48) 171.94,84.77 U63.4
N12958935: length 35.5
  TOP w0.173: R476.1 162.74,67.98 163.96,66.76 167.39,66.76 169.55,68.92 171.32,68.92 172.59,67.65 v1(173.86,67.65)
  L10_SIG4 w0.109: v1(173.86,67.65) 174.25,68.03 174.25,68.72 173.86,69.11 173.86,75.9 172.14,77.62 172.14,86.13 171.55,86.72 v1(171.47,86.72)
  BOTTOM w0.173: U63.7 v1(171.47,86.72)
N12958939: length 39.9
  TOP w0.173: R481.1 161.59,67.72 163.2,66.12 167.77,66.12 169.2,67.56 170.52,67.56 171.7,66.38 172.72,66.38 173.1,66.76 v1(173.86,66.76)
  L10_SIG4 w0.109: v1(172.52,86.75) 174.24,85.02 174.24,76.21 175.77,74.68 175.77,69.55 174.75,68.53 174.75,67.65 v1(173.86,66.76)
  BOTTOM w0.173: U63.6 171.84,86.07 v1(172.52,86.75)
N12958943: length 14.1
  TOP w0.173: R480.1 v5(160.71,69.85)
  L3_SIG1 w0.109: v5(160.71,69.85) 160.73,69.85 161.29,69.3 168.78,69.3 v6(169.55,68.53)
  L10_SIG4 w0.109: v9(169.55,67.9) v6(169.55,68.53)
  BOTTOM w0.173: v9(169.55,67.9) 171.24,66.21 U75.7
N12958955: length 40.2
  TOP w0.173: R475.1 159.56,68.99 162.94,65.61 168.02,65.61 169.29,66.88 170.31,66.88 171.2,65.99 v1(173.23,65.99)
  L10_SIG4 w0.109: v1(173.23,65.99) 173.23,67.51 172.85,67.89 172.85,74.38 172.34,74.88 172.34,76.41 170.73,78.01 170.73,84.68 v1(171.47,85.42)
  BOTTOM w0.173: U63.5 v1(171.47,85.42)
N15911835: length 2.9
  TOP w0.173: 26.54,97.74 27.43,97.74 28.35,98.66 U13.16
N16251668: length 72.5
  TOP w0.173: v5(131.01,71.46) 130.89,71.58 128.52,71.58 R385.1
  L3_SIG1 w0.109: v5(131.01,71.46) v6(131.62,71.46)
  L9_SIG3 w0.114: v6(131.62,71.46) 131.97,71.81 133.73,71.81 135,73.08 138.18,73.08 138.47,73.37 151.5,73.37 166.76,58.11 166.76,47.24 166.74,47.22 166.74,37.53 164.97,35.76 v1(164.97,34.88)
  BOTTOM w0.173: v1(164.97,34.88) U73.15
N16251678: length 64.8
  TOP w0.173: R387.1 129.29,70.31 v5(129.41,70.44)
  L3_SIG1 w0.109: v6(133.48,71.2) 132.49,70.21 129.64,70.21 v5(129.41,70.44)
  L9_SIG3 w0.114: v6(133.48,71.2) 133.54,71.2 134.52,72.19 140.03,72.19 140.82,72.97 149.15,72.97 163.04,59.08 163.04,39.6 v1(164.34,38.31)
  BOTTOM w0.173: U73.2 164.97,37.67 v1(164.34,38.31)
N16700927: length 3.9
  BOTTOM w0.173: J5.12 6.43,113.2 6.43,109.61 R138.1
N16818596: length 4.6
  BOTTOM w0.173: J3.9 7.75,123.57 R89.1
N16818719: length 2.5
  BOTTOM w0.173: U68.1 43.07,87.35 R107.1 R112.1
N16819128: length 1.9
  TOP w0.173: R103.2 22.99,121.24 v1(23.59,121.84)
  BOTTOM w0.173: U9.16 23.09,121.47 23.46,121.84 v1(23.59,121.84)
N16839202: length 3.9
  BOTTOM w0.173: U72.13 185.46,71.92 184.53,72.85 184.29,72.85 R382.2
N16839209: length 2.8
  BOTTOM w0.173: U72.2 178.31,73.24 R381.2
N16839216: length 2.8
  BOTTOM w0.173: U72.1 177.66,73.24 R380.2
N16844891: length 1.6
  TOP w0.173: R388.2 D6.2
N16844892: length 1.6
  TOP w0.173: R395.2 D11.2
N16844893: length 1.6
  TOP w0.173: R396.2 D12.2
N16844894: length 1.6
  TOP w0.173: R391.2 D9.2
N16844899: length 1.6
  TOP w0.173: R392.2 D10.2
N16844909: length 1.6
  TOP w0.173: R386.2 D5.2
N16844924: length 1.6
  TOP w0.173: R390.2 D8.2
N16844930: length 1.6
  TOP w0.173: R389.2 D7.2
N17007255: length 68.2
  TOP w0.173: R377.1 v5(125.35,71.33) ; v1(174.12,55.45) R366.1 178.31,57.09 U28.4
  L3_SIG1 w0.109: v5(125.35,71.33) 126.45,70.22 v6(128.54,70.22)
  L9_SIG3 w0.114: v1(174.12,55.45) 167.39,62.18 164.29,62.18 151.83,74.64 136.14,74.64 133.67,72.16 131.7,72.16 130.59,71.05 129.37,71.05 v6(128.54,70.22)
N17074741: length 5.4
  BOTTOM w0.173: R106.1 6.48,124.33 J3.10
N17120040: length 2.8
  TOP w0.173: J21.3 103.38,146.99 R743.1
N17120055: length 62
  TOP w0.173: R744.1 121.44,100.95 122.32,100.95 122.8,101.43 125.35,101.43 v5(125.86,100.92)
  L3_SIG1 w0.109: v5(125.86,100.92) 126.29,100.92 127.71,102.34 127.71,104.83 124.46,108.08 124.46,112.07 113.64,122.89 113.64,124.87 108.03,130.48 108.03,135.18 105.35,137.86 J21.5
N17120061: length 60.4
  L3_SIG1 w0.109: v6(111.38,128.27) 108.89,130.76 108.89,136.68 109.35,137.14 J21.9
  L4_SIG2 w0.114: v6(111.38,128.27) 111.38,123.24 111.01,122.87 111.01,113.13 111.67,112.47 111.67,111.5 110.85,110.68 110.85,107.32 110.54,107.01 110.54,105.87 111.3,105.1 111.3,104.15 110.62,103.46 110.62,97.77 v6(110.27,97.43)
  L10_SIG4 w0.109: v6(110.27,97.43) 110.27,96.64 v9(110.24,96.6)
  BOTTOM w0.173: v9(110.24,96.6) 110.74,96.09 111.63,96.09 113.92,98.38 113.92,99.78 R746.1
N17120072: length 67.1
  L3_SIG1 w0.109: v6(129,106.45) 127.61,106.45 125.15,108.92 125.15,112.34 114.81,122.68 114.81,125.53 109.47,130.87 109.47,136.07 110.16,136.75 110.16,141.58 111.35,142.77 J21.11
  L10_SIG4 w0.109: v6(129,106.45) 127.66,106.45 126.59,105.39 124.59,105.39 122.86,103.66 122.86,99.62 121.92,98.68 120.45,98.68 119.7,97.93 v9(119.06,97.93)
  BOTTOM w0.173: R747.1 v9(119.06,97.93)
N17120087: length 93.3
  TOP w0.173: R752.1 v5(59.56,106.2) ; v5(102.23,142.45) 116.76,142.45 121.34,147.02 J21.21
  L3_SIG1 w0.109: v5(102.23,142.45) 102.23,141.05 101.39,140.21 100.06,140.21 99.34,140.92 80.01,140.92 76.51,137.42 v6(74.02,137.42) ; v5(59.56,106.2) 59.87,106.2 v6(60.12,105.95)
  L4_SIG2 w0.114: v6(60.12,105.95) 63.38,105.95 67.48,110.05 67.48,130.88 74.02,137.41 v6(74.02,137.42)
N17120090: length 102.6
  TOP w0.173: J21.23 123.34,147.02 118.11,141.79 v5(101.09,141.79) ; R753.1 v5(52.58,106.28)
  L3_SIG1 w0.109: v5(101.09,141.79) 77.29,141.79 v6(72.97,137.47) ; v5(52.58,106.28) 51.84,106.28 v6(51.82,106.3)
  L4_SIG2 w0.114: v6(51.82,106.3) 53.49,107.98 58.88,107.98 59.18,107.68 64.47,107.68 67.19,110.39 67.19,131 72.97,136.79 v6(72.97,137.47)
N17144335: length 2.5
  TOP w0.173: R29.1 97.41,121.11
N17156111: length 7.3
  BOTTOM w0.173: U23.1 43.89,101.41 44.66,102.18 45.12,102.18 R305.2 C172.2 47.77,102.56 Y3.2
N17156113: length 5.4
  BOTTOM w0.173: Y3.1 47.51,103.57 C173.2 R305.1 R308.2
N17156222: length 2.2
  BOTTOM w0.173: R308.1 44.3,105.6 43.89,106.02 U23.14
N17156522: length 5.4
  BOTTOM w0.173: R310.1 41.05,103.95 41.94,104.84 U23.11
N17156525: length 3.2
  BOTTOM w0.173: R313.1 40.29,105.1 40.64,105.45 U23.9
N17156528: length 1.7
  BOTTOM w0.173: R315.1 39.12,106.4 U23.8
N17156983: length 2.5
  TOP w0.173: R314.1 42.8,105.11 v1(42.88,105.19)
  BOTTOM w0.173: v1(42.88,105.19) 42.59,105.49 U23.12
N17156986: length 2.5
  TOP w0.173: v1(43.63,105.26) 43.81,105.07 R312.1
  BOTTOM w0.173: v1(43.63,105.26) 43.24,105.65 U23.13
N17569906: length 7
  BOTTOM w0.173: R337.2 53.16,145.88 51.22,143.94 J12.11
N17569909: length 6.1
  BOTTOM w0.173: R340.2 61.88,145.88 J12.14
N17569918: length 2.3
  TOP w0.173: U24.48 61.22,123.61 61.31,123.7 61.56,123.7 61.72,123.86 R341.1
N17569921: length 3
  TOP w0.173: U24.41 61.5,120.11 61.68,120.29 62.46,120.29 62.65,120.1 TP17.1
N17570093: length 6.6
  BOTTOM w0.173: U25.1 57.83,98.42 58.42,99.01 R349.2 C193.2 61.45,99.01 Y4.2
N17570094: length 5.5
  BOTTOM w0.173: R351.2 R349.1 C194.2 61.2,100.03 Y4.1
N17570107: length 2.4
  BOTTOM w0.173: R351.1 58.42,102.19 57.83,102.78 U25.14
N17570112: length 8.6
  BOTTOM w0.173: R354.1 52.07,98 55.88,101.81 U25.11
N17570113: length 8.6
  BOTTOM w0.173: R357.1 50.8,98 54.58,101.78 U25.9
N17570114: length 2.3
  BOTTOM w0.173: R359.1 53.93,104.9 U25.8
N17570122: length 2
  BOTTOM w0.173: R358.1 56.53,105.51 U25.12
N17570123: length 2.3
  BOTTOM w0.173: R356.1 57.18,105.01 U25.13
N17594977: length 12
  TOP w0.173: C135.1 34.67,78.44 34.67,79.33 v7(34.67,79.33) 34.67,79.33 33.78,79.33 33.25,79.86 U15.24 ; v1(27.18,82.63) 27.43,82.38 U15.13 ; v1(27.58,80.22) 27.76,80.4 27.76,80.8 28.34,81.38 U15.15
  BOTTOM w0.173: v1(27.18,82.63) 28.45,81.36 C138.1 C134.1 ; v1(27.58,80.22) 27.56,80.22 27.16,79.82 C136.1
N17595008: length 4.6
  BOTTOM w0.173: J6.9 7.75,75.31 R172.1
N17595032: length 2.5
  BOTTOM w0.173: R195.1 R190.1 28.16,70.73 U70.1
N17595048: length 3.2
  TOP w0.173: v1(28.19,79.58) 29.02,80.41 U15.16
  BOTTOM w0.173: v1(28.19,79.58) R186.2
N17595072: length 5.4
  BOTTOM w0.173: J6.10 6.48,76.07 R189.1
N17595076: length 4.2
  BOTTOM w0.173: R161.1 8.25,89.28 J6.11
N17595078: length 5.1
  BOTTOM w0.173: J6.12 6.48,89.03 R176.1
N17596821: length 4.2
  BOTTOM w0.173: J8.11 8.26,68.66 R203.1
N17596823: length 11.7
  TOP w0.173: v1(27.18,57.99) 27.55,57.62 U17.13 ; C147.1 34.67,53.68 v7(34.67,54.56) 33.84,55.39 U17.24 ; U17.15 28.09,56.62 v1(27.56,56.09)
  BOTTOM w0.173: v1(27.56,56.09) 28.07,56.6 C148.1 C150.1 28.05,55.06 C149.1
N17596838: length 305.6
  TOP w0.173: 124.59,77.17 v5(125.35,77.17)
  L3_SIG1 w0.109: v6(125.2,78.16) 125.35,78.01 v5(125.35,77.17)
  L4_SIG2 w0.114: v6(125.2,78.16) 125.55,77.81 129.58,77.81 130.25,78.48 149.58,78.48 160.4,67.66 161.62,67.66 169.3,59.99 169.3,44.95 168.85,44.5 168.85,36.53 156.29,23.97 155.53,23.97 154.5,22.94 153.04,22.94 145.1,15.01 138.78,15.01 132.22,8.45 114.61,8.45 113.36,9.7 105.72,9.7 105.04,9.02 98.42,9.02 97.78,9.66 93.14,9.66 92.46,10.34 69.19,10.34 68.37,11.16 56.83,11.16 56.3,10.62 55.93,10.62 50.17,4.86 42.55,4.86 41.79,4.1 29.98,4.1 21.9,12.19 21.9,24.95 18.49,28.36 18.49,32.06 10.67,39.88 10.67,43.81 15.46,48.6 15.46,50.58 9.95,56.09 v1(7.24,56.09)
  BOTTOM w0.173: J8.10 6.48,51.31 R231.2 v1(7.24,56.09)
N17596842: length 14.7
  TOP w0.173: R220.2 v5(122.81,74.76) ; U1.D18 v4(111.03,78.42)
  L3_SIG1 w0.109: v5(122.81,74.76) 122.38,74.76 119.44,77.69 116.22,77.69 116.08,77.55 114.17,77.55 113.84,77.88 111.91,77.88 111.38,78.42 v4(111.03,78.42)
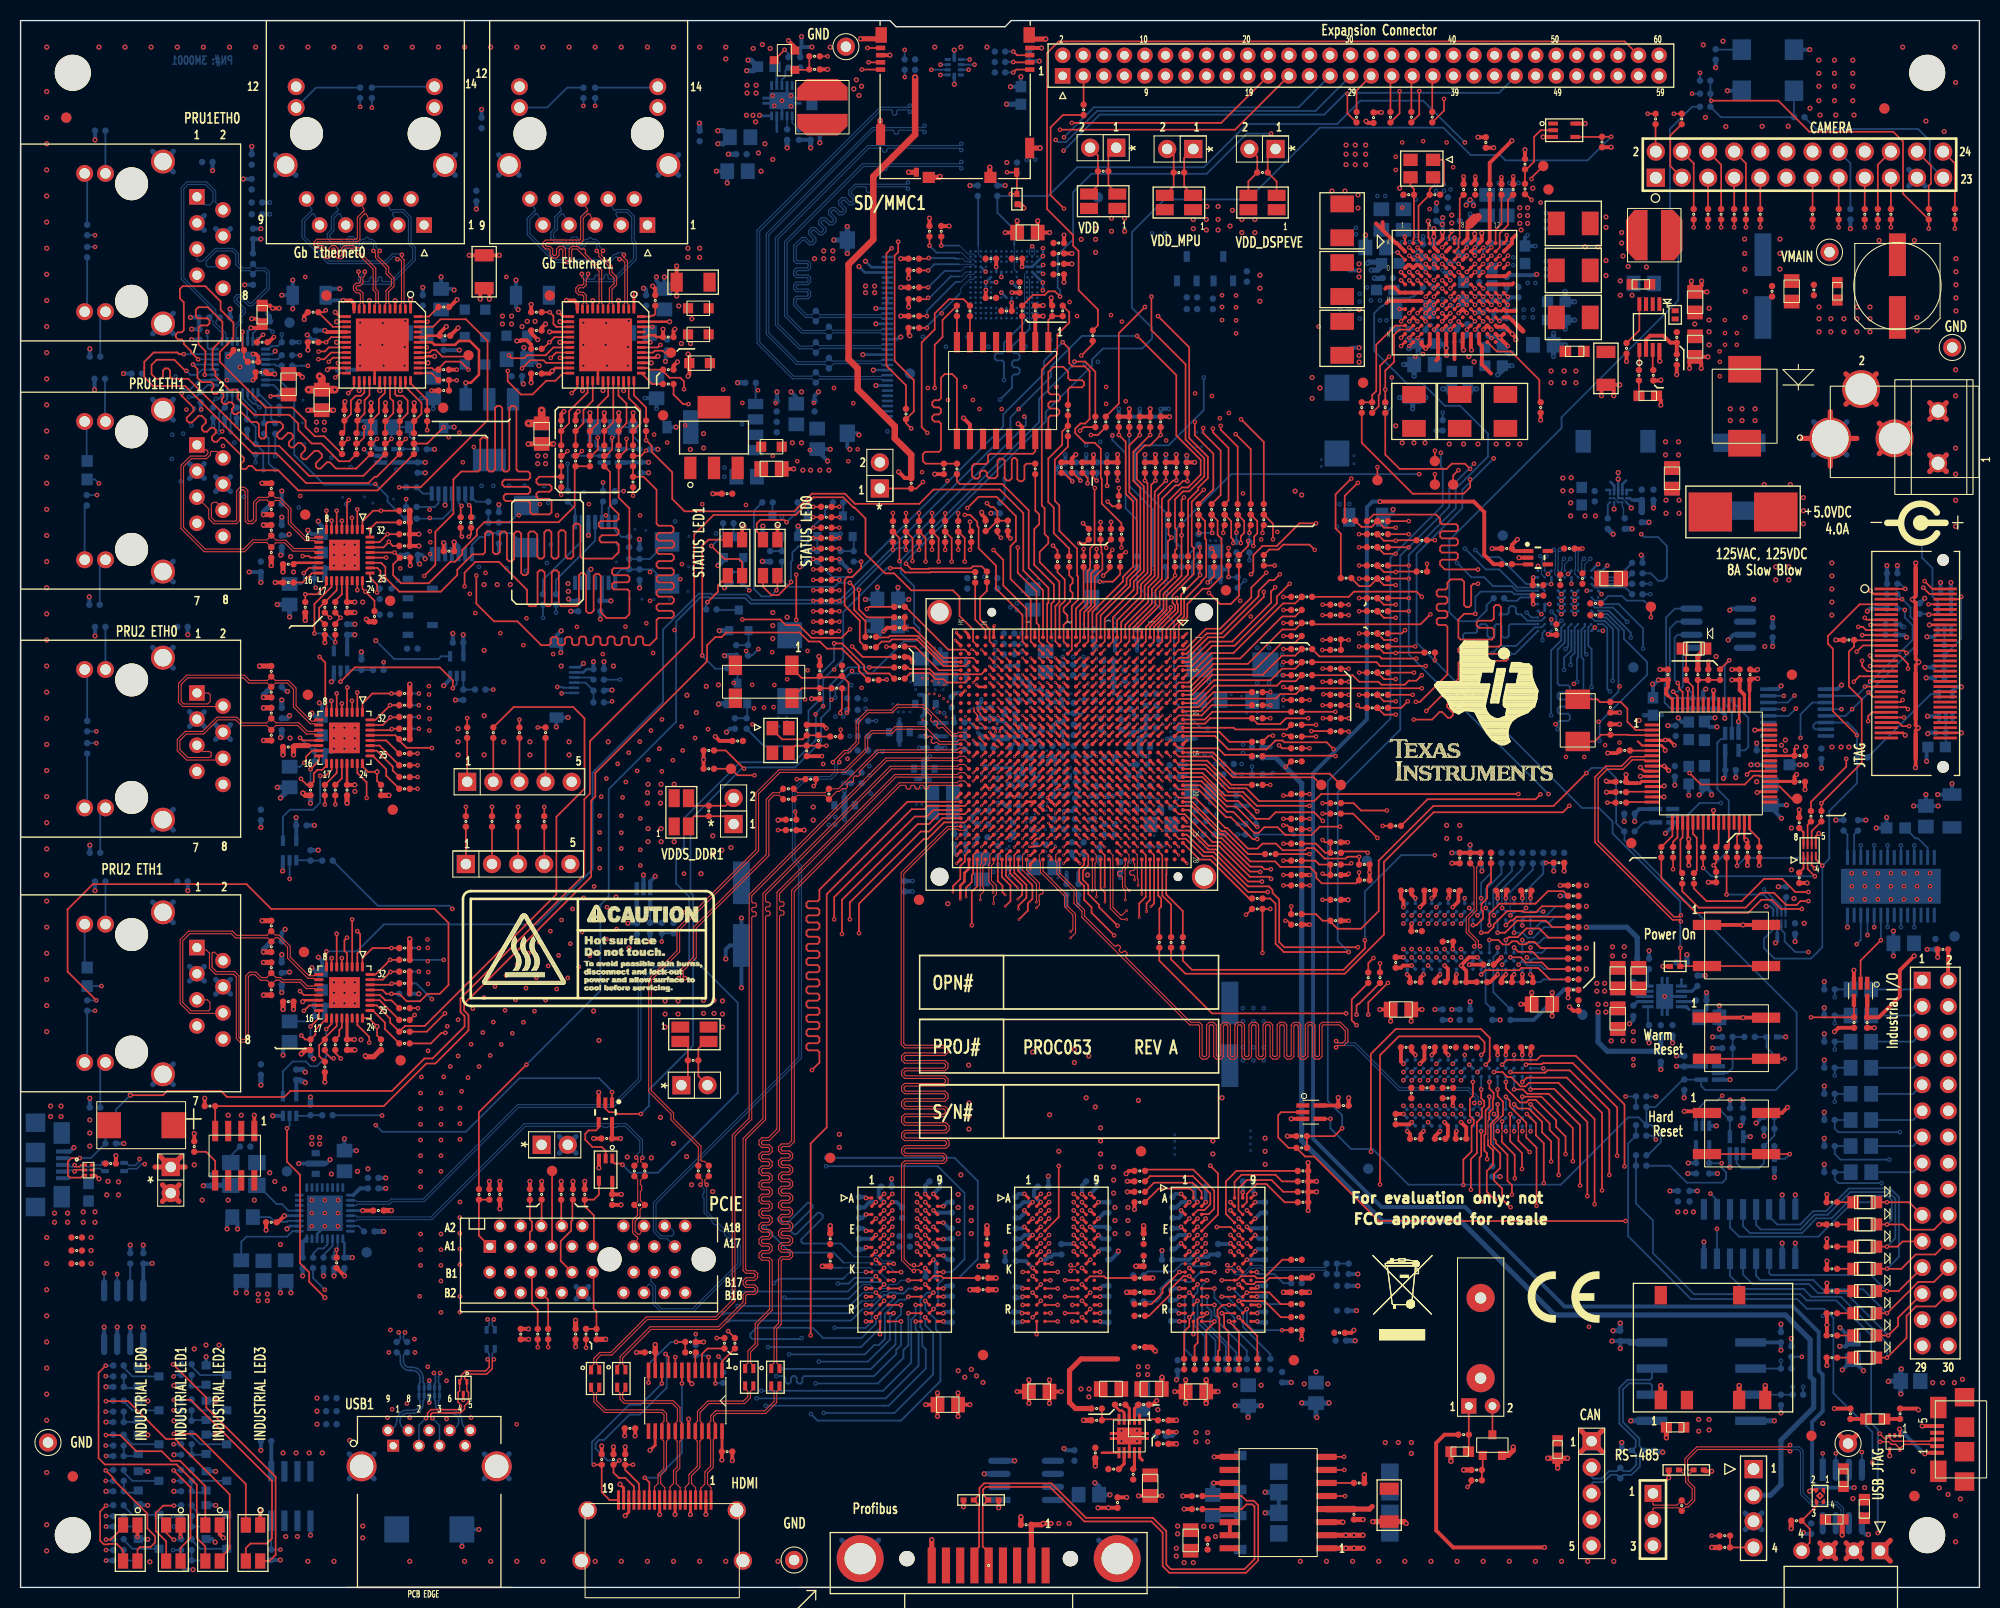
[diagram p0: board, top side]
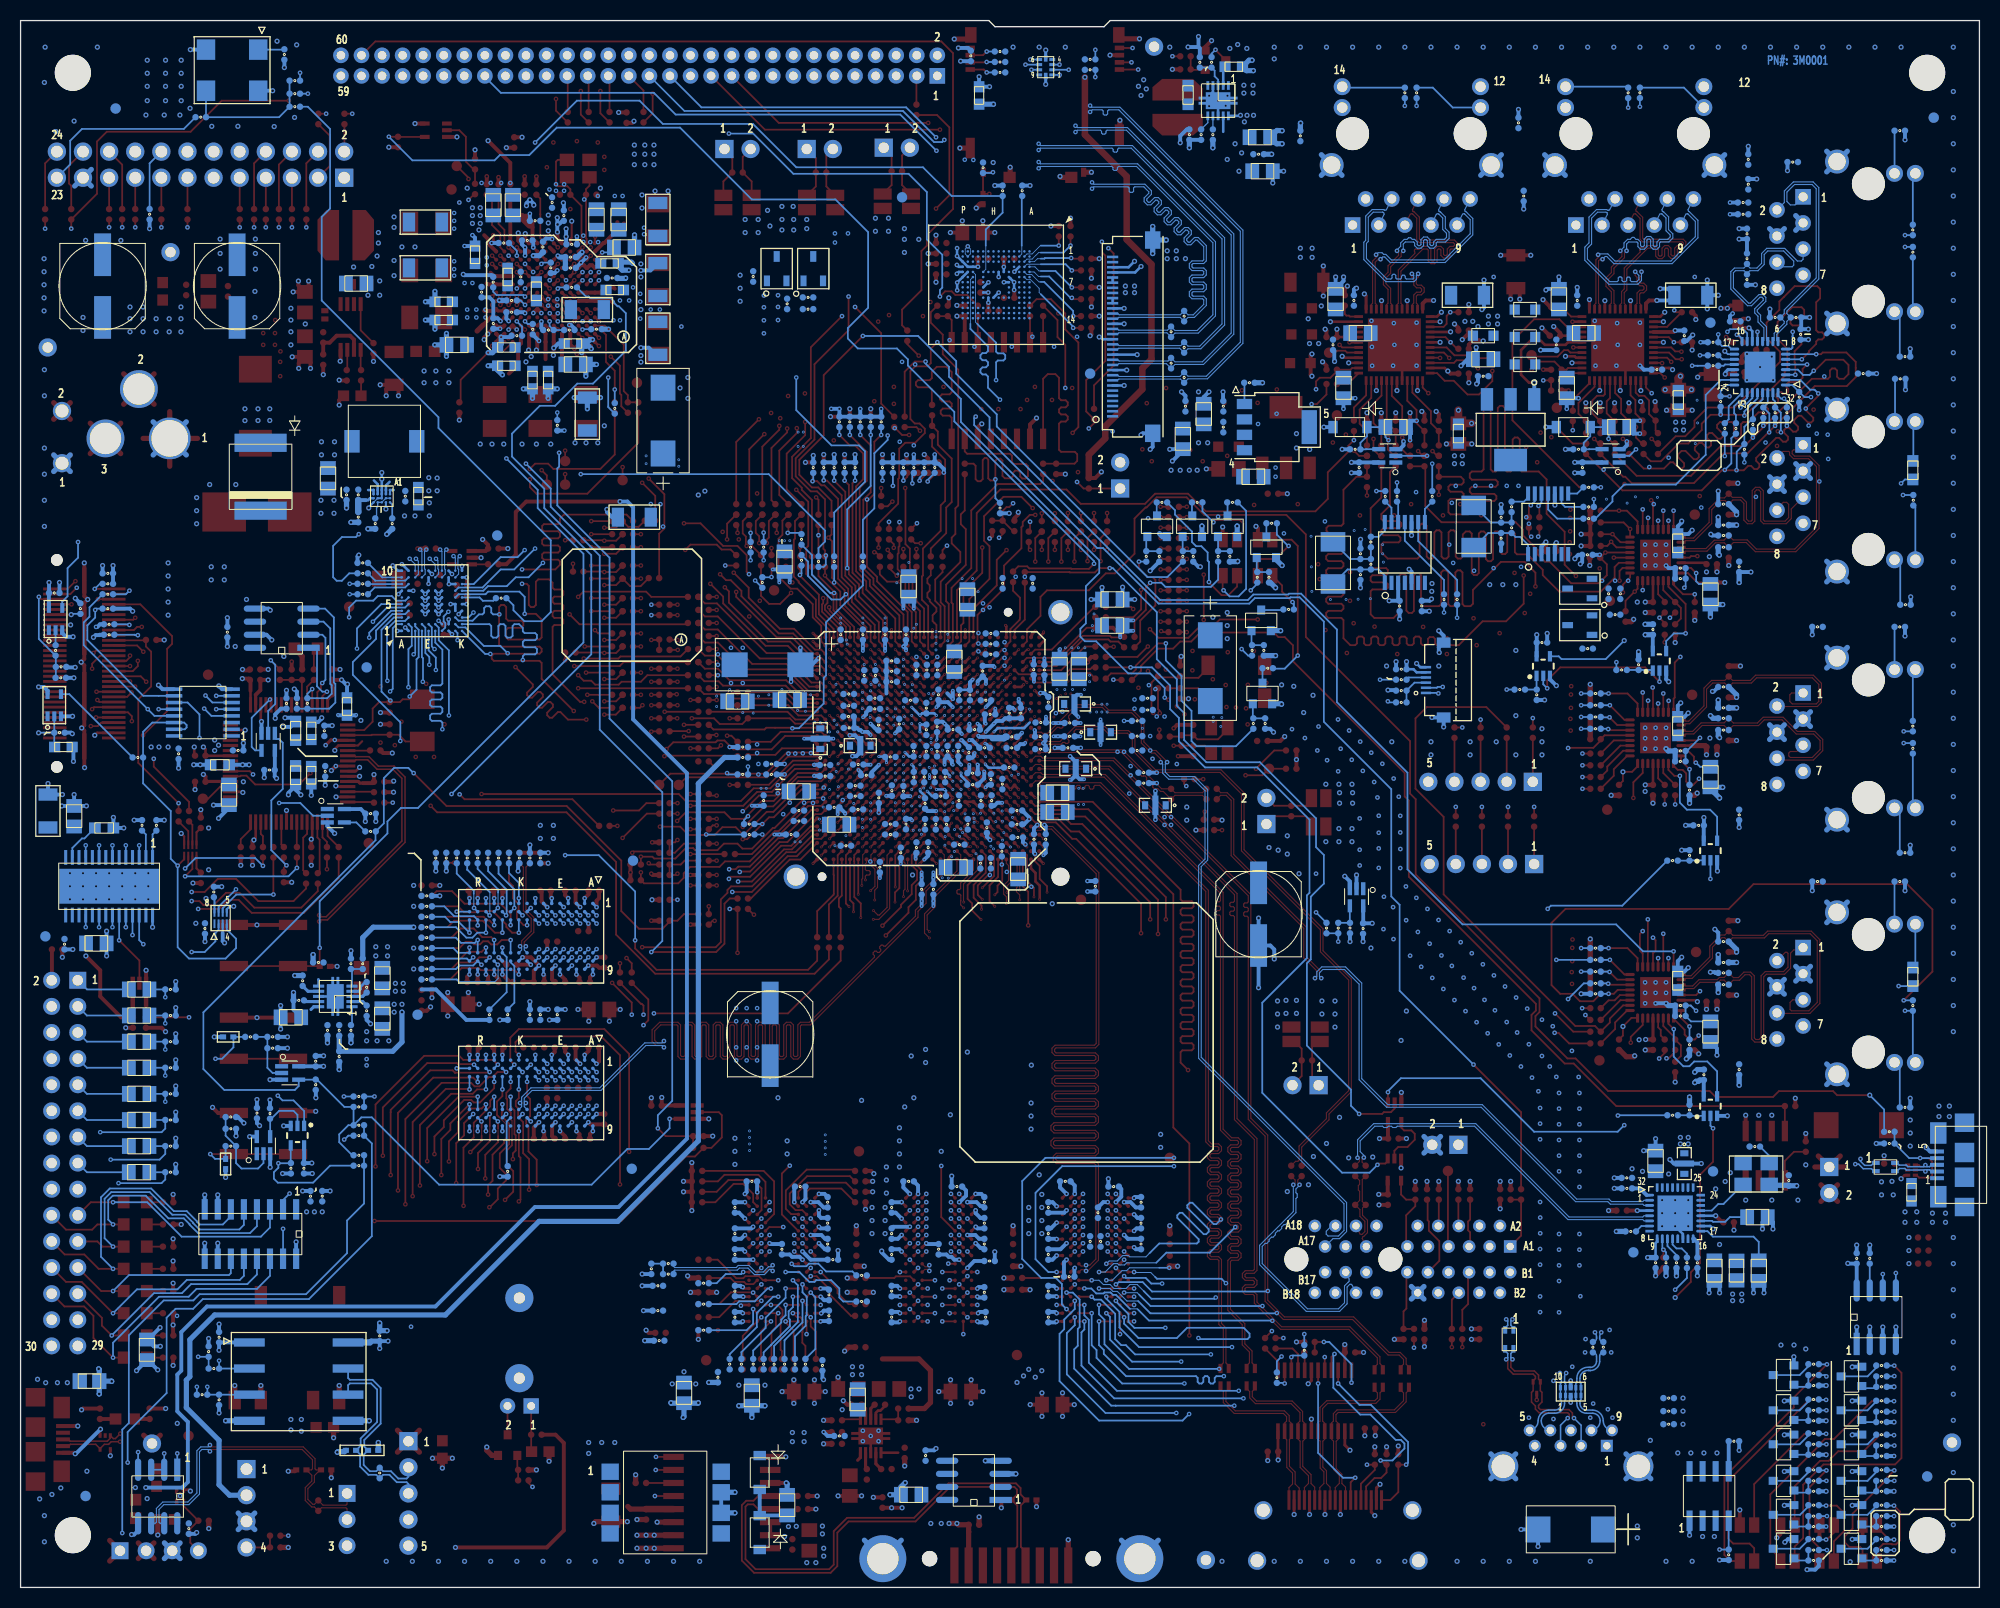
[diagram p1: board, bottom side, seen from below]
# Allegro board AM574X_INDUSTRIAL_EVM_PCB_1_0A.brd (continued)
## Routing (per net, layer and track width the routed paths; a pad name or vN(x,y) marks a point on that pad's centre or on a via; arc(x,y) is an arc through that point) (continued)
N17596847: length 13.4
  TOP w0.173: U1.C17 v4(111.83,79.22) ; R230.2 123.42,77.02 v5(122.81,77.02)
  L3_SIG1 w0.109: v4(111.83,79.22) 114.77,79.22 115.29,78.69 115.73,78.69 115.88,78.84 120.05,78.84 121.28,77.6 122.22,77.6 v5(122.81,77.02)
N17596886: length 4.6
  BOTTOM w0.173: J8.9 7.75,50.55 R214.1
N17596899: length 2.6
  BOTTOM w0.173: R234.1 R233.1 28.13,45.87 U71.1
N17596973: length 294.5
  TOP w0.173: R219.2 v1(38.32,55.68) ; U1.E17 v4(110.23,79.22)
  L3_SIG1 w0.099: 112.04,78.71 110.74,78.71 v4(110.23,79.22)
  L3_SIG1 w0.109: 112.04,78.71 113.75,78.71 114.37,78.08 115.87,78.08 116.05,78.26 119.73,78.26 121.97,76.03 123.96,76.03 124.18,75.82 v6(124.26,75.82)
  L4_SIG2 w0.114: v6(124.26,75.82) 124.51,76.06 130.97,76.06 131.88,76.97 144.76,76.97 146.27,75.46 149.29,75.46 159.43,65.33 160.66,65.33 165.73,60.26 165.73,56.3 163.74,54.31 163.74,36.29 156.58,29.13 150.95,29.13 145.9,24.08 139.95,24.08 129.01,13.14 117.66,13.14 116.42,11.89 106.41,11.89 105.1,13.2 102.17,13.2 101.96,12.99 100.61,12.99 99.72,13.87 72.97,13.87 72.43,14.41 60.28,14.41 60.06,14.19 57.44,14.19 57.03,13.77 57.03,13.54 56.73,13.24 56.02,13.24 53.26,10.48 53.26,10.27 50.36,7.37 29.49,7.37 26.16,10.69 26.16,22.86 32.13,28.83 32.13,30.4 31.45,31.08 31.45,42.7 32.09,43.34 32.09,48.26 38.32,54.5 v1(38.32,55.68)
N17596976: length 3.2
  TOP w0.173: v1(28.19,54.56) 29.02,55.39 U17.16
  BOTTOM w0.173: R228.2 v1(28.19,54.56)
N17596979: length 4.3
  BOTTOM w0.173: J8.12 6.23,60.54 R218.1
N17731118: length 2.5
  BOTTOM w0.173: Q1.G 11.24,2.62 R245.2 R241.1
N17731139: length 2.5
  BOTTOM w0.173: Q5.G 11.24,5.92 R255.2 R253.2
N17732522: length 1.6
  BOTTOM w0.127: U32.6 75.04,142.46 R410.1
N17732526: length 3.2
  BOTTOM w0.173: U32.3 74.04,146.65 74.38,146.98 74.38,147.53 R413.2 R414.2
N17732536: length 2.3
  TOP w0.173: v1(74.3,149.56) 74.3,149.55 Q9.D
  BOTTOM w0.173: R413.1 74.68,149.18 v1(74.3,149.56)
N17732560: length 1.3
  BOTTOM w0.127: R411.1 74.54,141.82 U32.7
N17745676: length 6.2
  TOP w0.173: J9.22 185.79,138.29 185.79,136.55 185.57,136.33 R275.2
N17745678: length 6.1
  TOP w0.173: R277.2 188.11,138.51 J9.24
N17745710: length 17.3
  BOTTOM w0.173: J9.23 185.67,138.41 185.67,140.72 184.53,141.86 174.62,141.86 R903.1
N17863265: length 4.2
  BOTTOM w0.173: J3.11 8.25,137.54 R78.1
N17863276: length 5.1
  BOTTOM w0.173: R93.1 6.48,137.29 J3.12
N18733248: length 19.6
  TOP w0.173: U1.AD14 v4(95.03,81.75) ; R497.1 79.88,85.43 79.73,85.28 79.73,85.05 v5(79.71,85.04)
  L3_SIG1 w0.109: v4(95.03,81.75) 94.57,82.22 94.04,82.22 93.84,82.41 93.05,82.41 92.93,82.54 92.93,82.54 92.76,82.71 92.71,82.76 91.21,82.76 90.84,83.13 89.22,83.13 89.07,83.28 87.74,83.28 87.58,83.44 81.37,83.44 79.88,84.93 79.82,84.93 v5(79.71,85.04)
N18733249: length 4.3
  TOP w0.173: Y6.4 75.98,87.46 C247.1 R497.2
N18733252: length 24.4
  TOP w0.173: Y6.1 75.01,89.41 75.95,88.47 77.55,88.47 C246.1 77.85,88.52 79.76,88.52 R927.2 80.52,88.01 80.52,85.55 80.52,85.55 80.52,85.3 80.36,85.14 v5(80.36,85.07) ; U1.AE14 93.23,82.62 v4(93.23,82.71)
  L3_SIG1 w0.109: v4(93.23,82.71) 93.23,82.7 92.93,83 91.27,83 90.92,83.35 89.31,83.35 89.04,83.62 87.91,83.62 87.8,83.72 81.7,83.72 v5(80.36,85.07)
N18733262: length 25.2
  TOP w0.173: U1.AF14 v4(92.64,82.41) ; v1(77.13,77.95) 77.34,78.16 77.34,78.61
  L3_SIG1 w0.109: v6(90.74,82.51) 90.77,82.51 90.86,82.41 v4(92.64,82.41)
  L9_SIG3 w0.114: v1(77.13,77.95) 77.13,79.9 79.18,81.95 82.79,81.95 84.67,80.06 91.47,80.06 92.25,80.85 92.25,82.07 91.81,82.51 v6(90.74,82.51)
N18733263: length 2.8
  BOTTOM w0.173: U39.4 61.23,64.66 R498.1 R500.1
N18733273: length 45
  TOP w0.173: U1.AB17 v4(95.84,79.22)
  L3_SIG1 w0.109: v1(62.36,62.82) 62.36,64.51 71.76,73.91 v6(72.52,73.91) ; v4(95.84,79.22) v6(95.44,78.97)
  L9_SIG3 w0.114: v6(95.44,78.97) 95.44,78.91 94.69,78.16 94.69,78.03 94.25,77.6 94.25,77.23 94,76.98 92.31,76.98 92.1,77.19 90.25,77.19 87.35,74.3 79.63,74.3 78.36,73.02 73.41,73.02 v6(72.52,73.91)
  BOTTOM w0.173: R926.2 R500.2 v1(62.36,62.82)
N18733274: length 21.2
  TOP w0.173: U1.Y11 v4(97.44,84.81) ; R929.2 95,102.44 v1(95.34,102.1)
  L3_SIG1 w0.109: v4(97.44,84.81) v6(97.04,85.06)
  L4_SIG2 w0.114: v1(95.34,102.1) 96.39,101.05 96.39,91.02 94.89,89.52 94.89,87.46 95.28,87.08 95.6,87.08 95.85,86.83 95.85,86.5 96.08,86.28 96.37,86.28 96.63,86.03 96.63,85.45 97.01,85.06 v6(97.04,85.06)
N18733276: length 28.4
  TOP w0.173: R923.1 TP19.1 69.72,78.99 v5(71.37,78.99) ; U1.AD17 v4(94.24,79.22)
  L3_SIG1 w0.099: v4(94.24,79.22) 93.85,79.22 93.56,79.51 93.31,79.51 93.2,79.39 92.88,79.39 92.33,79.94 92.05,79.94
  L3_SIG1 w0.109: 92.05,79.94 81.09,79.94 80.27,79.12 72.39,79.12 72.26,78.99 v5(71.37,78.99)
N18868530: length 10.4
  TOP w0.173: R14.1 R572.2 131.44,115.97 131.84,116.36 131.84,120.87 133.7,122.73 134.64,122.73 U3.L1
N18868533: length 10.5
  TOP w0.173: R15.1 v1(132.72,116.51) 132.72,118.34 133.57,119.2 133.57,121.84 134.07,122.34 135.05,122.34 U3.L2
  BOTTOM w0.173: R588.2 R15.1 v1(132.72,116.51)
N18913166: length 21.8
  TOP w0.173: TP7.1 v5(131.95,108.97) ; U3.J5 v5(137.45,123.94)
  L3_SIG1 w0.109: v5(131.95,108.97) 131.95,109.81 130.43,111.33 130.43,118.71 131.95,120.24 131.95,120.6 134.08,122.73 135.97,122.73 136.26,123.01 136.26,123.3 136.51,123.56 137.07,123.56 v5(137.45,123.94)
N18913202: length 2.6
  TOP w0.173: U3.K7 v1(139.05,123.14)
  BOTTOM w0.173: v1(139.05,123.14) 139.05,122.69 R934.1 R17.1
N18913205: length 1.4
  TOP w0.173: U3.L3 v1(135.85,122.34)
  BOTTOM w0.173: 135,122.38 135.81,122.38 v1(135.85,122.34)
N18913322: length 4.3
  TOP w0.173: U3.G9 v1(141.44,125.54)
  BOTTOM w0.173: R18.1 144.54,126.02 144.22,125.7 141.6,125.7 v1(141.44,125.54)
N18913403: length 10.8
  TOP w0.173: Y2.1 138.26,138.85 138.43,138.68 138.43,136.48 138.24,136.29 137.33,136.29 137.03,135.99 C26.2 135.95,134.38 135.95,131.03 U3.A3
N18913412: length 6.6
  TOP w0.173: Y2.3 135.17,136.34 135.51,136 C25.2 135.51,131.23 135.45,131.16 U3.A2
N18913758: length 5.9
  TOP w0.173: C27.2 139.96,135.09 139.96,133.56 139.95,133.56 139.95,131.25 139.85,131.14 139.85,130.34 U3.B7
N18914093: length 2.3
  TOP w0.173: U3.C1 v1(133.93,129.85)
  BOTTOM w0.173: v1(133.93,129.85) 133.27,129.85 C578.1
N18914190: length 17.8
  TOP w0.173: v5(143.05,121.5) 142.65,121.9 U3.M11 ; TP2.1 v5(137.54,110.57)
  L3_SIG1 w0.109: v5(143.05,121.5) 143.05,118.11 142.37,117.43 139.57,117.43 135.96,113.82 135.96,112.68 137.54,111.1 v5(137.54,110.57)
N18914214: length 28
  TOP w0.173: U3.J7 v5(139.84,124.73) ; TP3.1 v5(137.54,108.29)
  L3_SIG1 w0.109: v5(137.54,108.29) 136.4,109.43 135.89,109.43 134.9,110.42 134.9,111.59 134.49,111.99 133.9,111.99 130.72,115.18 130.72,118.59 134.05,121.93 136.07,121.93 136.35,122.2 136.35,122.48 136.63,122.76 139.21,122.76 139.45,122.99 U3.J7 v5(139.84,124.73)
N18914339: length 91.3
  TOP w0.173: v1(161.41,62.21) U50.1 161.44,60.44 SW3.3 SW3.4 ; U3.G8 v5(140.64,125.54)
  L3_SIG1 w0.109: v1(143.26,109.81) 144.02,110.57 144.02,113.23 143.44,113.81 143.44,123.34 143.23,123.56 142.08,123.56 141.82,123.81 141.82,124.1 141.6,124.33 141.31,124.33 141.06,124.58 141.06,125.13 v5(140.64,125.54)
  BOTTOM w0.173: v1(143.26,109.81) 140.21,106.76 140.21,104.98 135.76,100.54 135.76,91.9 151.85,75.81 153.51,75.81 154.82,74.5 154.82,73.34 161.41,66.75 v1(161.41,62.21)
N18914524: length 37.7
  TOP w0.173: U3.C11 v1(143.04,129.53) ; v5(139.83,108.67) 139.32,108.16 TP6.1
  L3_SIG1 w0.109: v1(143.04,129.53) 142.66,129.92 142.08,129.92 141.82,129.66 141.82,127.75 142.19,127.38 145.16,127.38 145.67,126.87 147.91,126.87 148.72,126.07 148.72,123.02 149.36,122.38 149.36,113.87 144.78,109.3 142.62,109.3 142.11,109.81 140.97,109.81 v5(139.83,108.67)
N18915671: length 20.3
  TOP w0.254: U3.B3 v5(135.85,130.33)
  TOP w0.381: R19.1 v7(143.26,140.04)
  L3_SIG1 w0.381: v7(143.26,140.04) 142.65,139.43 139.05,139.43 134.58,134.96 133.35,134.96 132.59,134.19 132.59,132.42 134.15,130.85 135.33,130.85 v5(135.85,130.33)
N18915723: length 4.8
  TOP w0.381: U3.A11 142.88,130.97 R20.1
N18915943: length 1.5
  TOP w0.173: U3.D8 v1(139.85,128.73)
  BOTTOM w0.173: R21.1 139.73,128.86 v1(139.85,128.73)
N19120663: length 5
  TOP w0.173: R41.2 89.73,30.1 89.53,30.3 88.8,30.3 U5.L8
N19120749: length 4.9
  TOP w0.173: U7.L8 104,30.26 105.37,30.26 105.53,30.1 R44.2
N19127709: length 5.1
  TOP w0.173: R42.2 121.46,30.1 121.08,29.72 120.14,29.72 119.93,29.5 119.23,29.5 U6.L8
N19139994: length 11.8
  TOP w0.173: U6.D7 118.06,35.48 117.22,36.32 117.22,39.5 118.24,40.51 R32.1
N19139997: length 10.9
  TOP w0.173: U6.C3 114.9,36.31 115.56,36.31 116.08,36.83 116.08,38.61 114.05,40.64 109.47,40.64 R33.1
N19140025: length 9.3
  TOP w0.173: R34.1 122.81,38.48 121.67,39.62 119.25,39.62 118.44,38.81 118.44,36.7 U6.C8
N19140027: length 10.4
  TOP w0.173: R35.1 109.86,40 114,40 115.7,38.31 115.7,37.27 115.13,36.7 114.48,36.7 U6.C2
N19140065: length 8.3
  TOP w0.173: U6.A7 118.06,39.45 118.75,40.13 122.05,40.13 122.68,39.5 R37.1
N19140067: length 6
  TOP w0.173: R38.1 110.68,38.79 113.75,38.79 114.06,38.48 U6.A2
N19140105: length 7.5
  TOP w0.173: R39.1 122.94,37.46 121.16,39.24 120.22,39.24 119.25,38.28 119.25,37.47 U6.B8
N19140107: length 6.9
  TOP w0.173: R40.1 110.24,39.37 113.97,39.37 114.86,38.48 U6.A3
N19258097: length 1.6
  BOTTOM w0.173: U45.7 32.87,35.15 R546.1
N19258128: length 5.1
  BOTTOM w0.173: U45.21 26.04,36.65 25.4,37.29 24.89,37.29 23.07,39.11 Y7.3
N19258198: length 1.9
  BOTTOM w0.173: R547.1 20.45,41.99 Y7.1
N19258383: length 2.2
  BOTTOM w0.173: R548.1 29.46,32.34 30.34,33.22 U45.11
N19258403: length 2.8
  TOP w0.173: R550.1 v1(30.73,32.85)
  BOTTOM w0.173: R549.1 30.48,32.59 v1(30.73,32.85) 30.84,32.95 U45.10
N19258622: length 7.9
  BOTTOM w0.173: C305.1 21.46,33.61 21.97,34.12 25.91,34.12 26.45,34.65 U45.17
N19258627: length 4.8
  BOTTOM w0.173: U45.19 25.99,35.65 25.9,35.56 24.73,35.56 24.27,36.02 C306.1
N19290398: length 2.6
  BOTTOM w0.173: R421.1 U33.7
N19388440: length 4.4
  BOTTOM w0.173: R566.1 156.01,97.93 153.08,97.93 U89.B9
N19415733: length 2.7
  BOTTOM w0.173: R568.1 28.45,32.47 28.96,32.97 29.46,32.97 29.84,33.35 U45.12
N19425975: length 19.2
  TOP w0.173: R7.1 v5(123.57,66.25) ; U1.E23 v4(110.23,74.42)
  L3_SIG1 w0.099: v4(110.23,74.42) 110.6,74.42 111.11,73.91 112.36,73.91
  L3_SIG1 w0.109: 112.36,73.91 112.78,73.49 115.34,73.49 118.31,70.51 118.31,68.58 120.27,66.62 121.67,66.62 122.05,66.25 v5(123.57,66.25)
N19426030: length 16.3
  TOP w0.173: R8.1 v5(122.81,69.3) ; U1.D21 v4(111.03,76.02)
  L3_SIG1 w0.109: v4(111.03,76.02) 111.42,76.02 111.89,75.54 115.85,75.54 120.02,71.38 121.38,71.38 122.81,69.95 v5(122.81,69.3)
N19426454: length 17.4
  TOP w0.173: U1.AC15 v4(95.07,80.85)
  L3_SIG1 w0.099: v4(95.07,80.85) 95.42,80.5 95.48,80.5
  L3_SIG1 w0.109: v6(95.5,80.48) 95.48,80.5
  L10_SIG4 w0.109: v9(83.19,84.28) 83.19,83.06 84.96,81.28 86.7,81.28 87.25,80.73 87.8,80.73 88.7,79.83 91.05,79.83 92.19,80.97 95.06,80.97 95.5,80.52 v6(95.5,80.48)
  BOTTOM w0.173: 82.42,84.28 v9(83.19,84.28)
N19438966: length 267.5
  TOP w0.173: U1.AB9 v4(95.84,86.41) ; v5(120.78,61.72) R582.1 v1(121.54,65.99) ; v5(132.97,58.8) 131.06,56.9 v1(131.06,55.71)
  L3_SIG1 w0.109: v5(120.78,61.72) 122.11,60.39 131.38,60.39 v5(132.97,58.8) ; v4(95.84,86.41) v6(95.44,86.66) ; v6(134.05,110.63) 135.86,108.82 136.12,108.82 140.11,104.83 153.92,104.83 154.41,104.35 156.46,104.35 157.73,103.08 159,103.08 v6(159.13,103.21) ; v1(121.54,65.99) 121.72,65.81 131.42,65.81 135.54,69.93 140.13,69.93 143.79,73.59 157.58,73.59 v6(158.5,74.5)
  L4_SIG2 w0.114: v6(95.44,86.66) 95.23,86.66 94.64,87.25 94.64,89.79 95.99,91.13 95.99,95.64 95,96.63 95,101.09 94.61,101.47 v6(94.61,102.9)
  L9_SIG3 w0.114: v1(179.07,13.16) 179.07,16.46 173.74,21.8 171.7,21.8 158.52,34.98 158.52,51.11 157.73,51.9 152.27,51.9 149.99,54.18 132.59,54.18 v1(131.06,55.71)
  L10_SIG4 w0.109: v6(158.5,74.5) 157.73,75.27 157.73,77.68 156.89,78.52 156.89,80.35 158.55,82 158.55,85.2 159.41,86.06 159.41,87.23 160.72,88.55 160.72,98.58 159.89,99.41 159.89,101.4 159.13,102.16 v6(159.13,103.21) ; v6(134.05,110.63) 130.55,114.13 121.72,114.13 113.87,106.28 113.87,103.94 112.55,102.62 94.89,102.62 v6(94.61,102.9)
  BOTTOM w0.173: U77.4 v1(179.07,13.16)
N19438972: length 97.8
  TOP w0.173: v1(128.91,55.83) 115.87,55.83 110.74,60.96 R583.1
  L9_SIG3 w0.114: v1(128.91,55.83) 128.91,54.44 130.56,52.79 148.21,52.79 151.26,49.74 155.19,49.74 157.73,47.2 157.73,34.75 172.09,20.4 172.09,16.21 v1(175.26,13.04)
  BOTTOM w0.173: v1(175.26,13.04) U77.1
N19438984: length 203
  TOP w0.173: R584.1 92.33,102.82 v1(92.33,103.66)
  L3_SIG1 w0.109: v6(176.66,102.19) 166.5,102.19 161.51,107.18 147.84,107.18 146.53,105.87 141.28,105.87 136.04,111.1 136.04,111.72 135.54,112.22 v6(135.13,112.22)
  L10_SIG4 w0.109: v6(135.13,112.22) 135.13,112.83 130.4,117.56 126.36,117.56 125.86,117.05 119.25,117.05 115.32,113.11 115.32,108.82 113.04,106.54 113.04,103.92 112.39,103.28 108.76,103.28 105.94,106.1 100.74,106.1 98.29,103.66 v1(92.33,103.66) ; v1(176.53,13.04) 176.04,13.53 176.04,16.2 175.15,17.08 175.15,25.46 173.68,26.93 173.68,55.63 173.74,55.69 173.74,59.01 173.23,59.52 173.23,62.31 175.51,64.6 175.51,66.12 176.56,67.16 176.56,73.66 179.71,76.81 179.71,93.22 178.65,94.27 178.65,100.2 v6(176.66,102.19)
  BOTTOM w0.173: v1(176.53,13.04) U77.2 U77.3
N19634423: length 2.7
  TOP w0.173: U74.6 R579.2
N19634430: length 184.7
  TOP w0.173: U74.8 v1(128.71,12.7)
  L3_SIG1 w0.109: v1(136.02,108.29) 140.49,103.81 149.02,103.81 149.25,103.59 155.32,103.59 156.9,102.01 158.19,102.01 158.5,102.32 v6(160.4,102.32)
  L10_SIG4 w0.109: v6(160.4,102.32) 160.4,101.55 161.71,100.23 161.71,89.13 159.97,87.39 159.97,85.77 158.87,84.67 158.87,79.27 158.12,78.51 158.12,76.28 159.02,75.38 159.02,75.04 160.4,73.66 162.51,73.66 166.52,69.65 166.52,50.7 164.85,49.02 164.85,46.18 165.48,45.54 165.48,44.58 164.85,43.94 164.85,43.44 167.08,41.2 167.08,37.14 165.84,35.9 165.84,31.1 145.33,10.6 134.65,10.6 132.54,12.7 v1(128.71,12.7)
  BOTTOM w0.173: v1(136.02,108.29) 117.75,108.29 112.27,102.81 112.27,101.73 112.9,101.09 R574.1
N19634431: length 202.5
  TOP w0.173: U74.5 v1(128.81,8.89) ; R575.1 112.9,105.8 v5(113.13,106.02)
  L3_SIG1 w0.109: v6(136.4,113.11) 138.15,111.36 138.15,111.03 139.12,110.06 139.12,108.44 141.05,106.51 146.69,106.51 149.23,109.05 156.08,109.05 156.51,108.62 161.09,108.62 v6(162.81,106.89) ; v6(112.43,106.7) 112.49,106.7 113.13,106.06 v5(113.13,106.02)
  L10_SIG4 w0.109: v1(128.81,8.89) 147.9,8.89 151.91,12.9 153.33,12.9 154.85,14.42 154.85,16.74 168.4,30.29 168.4,41.48 166.5,43.39 166.5,45.67 168.53,47.71 168.53,70.44 163.2,75.77 162.59,75.77 161.54,76.81 161.54,83.06 162.05,83.57 162.05,86.34 162.64,86.92 162.64,101.12 162.81,101.3 v6(162.81,106.89) ; v6(136.4,113.11) 135.43,113.11 129.97,118.57 119.63,118.57 112.9,111.84 112.9,107.17 v6(112.43,106.7)
N19634433: length 204.8
  TOP w0.173: R576.1 106.17,105.16 v5(105.71,105.61) ; U74.7 v1(128.73,11.43)
  L3_SIG1 w0.109: v5(105.71,105.61) 105.71,105.62 v6(104.24,105.62) ; v6(161.42,102.44) 160.66,103.21 160.02,103.21 159,104.22 158.55,104.22 156.62,106.15 147.88,106.15 147.12,105.39 140.72,105.39 138.18,107.93 138.18,108.51 136.09,110.6 v6(135.39,110.6)
  L10_SIG4 w0.109: v6(135.39,110.6) 134.98,111.01 134.98,111.54 134.49,112.02 133.91,112.02 131.09,114.84 121.84,114.84 113.41,106.41 113.41,103.89 112.5,102.98 108.53,102.98 105.89,105.62 v6(104.24,105.62) ; v6(161.42,102.44) 162,101.86 162,88.04 161.26,87.3 161.26,85.68 159.16,83.57 159.16,79.15 158.57,78.56 158.57,76.26 160.1,74.73 163.09,74.73 167.39,70.44 167.39,65.61 168.15,64.85 168.15,49.53 166.98,48.37 166.98,47.05 165.92,45.98 165.92,43.1 167.64,41.38 167.64,36.53 166.37,35.26 166.37,29.7 146.01,9.34 140.54,9.34 140.15,9.73 130.43,9.73 v1(128.73,11.43)
N19700674: length 2.8
  TOP w0.173: J18.1 v1(183.29,97.12)
  BOTTOM w0.173: v1(183.29,97.12) 182.79,97.62 R730.1
N19700725: length 2.5
  TOP w0.173: v7(185.57,94.62) J18.12
  BOTTOM w0.173: R731.1 185.5,94.7 v7(185.57,94.62)
N19707292: length 3
  TOP w0.173: J18.15 v1(179.92,93.62)
  BOTTOM w0.173: R587.1 179.98,93.68 v1(179.92,93.62)
N19708748: length 1.5
  BOTTOM w0.173: U78.2 R429.1
N19795587: length 6.2
  TOP w0.173: R425.1 144.65,134.96 144.65,132.52 143.85,131.71 143.85,130.34 U3.B12
N19795594: length 8.4
  TOP w0.173: v1(146.94,134.96) 146.39,135.51 R428.1 ; U3.C13 v5(144.64,129.53)
  L3_SIG1 w0.109: v5(144.64,129.53) 144.64,130.62 145.16,131.15 145.16,134.21 145.91,134.96 v1(146.94,134.96)
N19795604: length 5
  TOP w0.173: U3.A12 143.45,132.05 144.02,132.62 R430.1
N19795606: length 1.5
  TOP w0.173: U3.H9 v1(141.44,124.74)
  BOTTOM w0.173: R431.1 141.87,125.18 v1(141.44,124.74)
N19795618: length 2.1
  TOP w0.173: U3.C10 v1(142.24,129.53)
  BOTTOM w0.173: v1(142.24,129.53) 142.24,130 R570.1
N19795620: length 8.8
  TOP w0.173: R571.1 147.7,115.4 147.7,117.45 144.93,120.22 143.56,120.22 U3.N11
N19795629: length 2.2
  TOP w0.173: U3.K10 v1(142.24,123.14)
  BOTTOM w0.173: v1(142.24,123.14) 141.73,122.64 R432.1
N19796448: length 10.6
  TOP w0.173: R572.1 132.08,114.89 132.08,115.99 132.21,116.12 132.21,118.83 v5(133.1,119.72) ; U3.M3 135.86,121.56 v5(135.86,121.52)
  L3_SIG1 w0.109: v5(133.1,119.72) 133.1,120.35 133.87,121.13 135.47,121.13 v5(135.86,121.52)
N19796451: length 16
  TOP w0.173: U3.H8 v5(140.64,124.74)
  L3_SIG1 w0.109: v1(133.35,117.68) 133.35,118.46 136.65,121.76 136.76,121.87 139.45,121.87 140.24,122.66 140.24,124.34 v5(140.64,124.74)
  BOTTOM w0.173: R588.1 133.35,114.81 v1(133.35,117.68)
N19923823: length 1
  TOP w0.254: U1.J10 v4(107.03,85.61)
  L3_SIG1 w0.254: v6(107.43,85.86) v4(107.03,85.61)
  vias: v6(110.62,93.05) v6(110.62,92.41) v10(110.11,91.75) v10(110.19,92.16) v11(110.11,91.75) v11(110.19,92.16)
N19923824: length 2.1
  TOP w0.254: U1.J9 v4(107.03,86.41)
  L3_SIG1 w0.254: v6(107.43,86.66) v4(107.03,86.41)
  BOTTOM w0.381: v11(108.58,91.09) v11(108.58,91.55) C287.1
  vias: v6(108.97,92.66) v6(108.96,92)
N19923825: length 2.2
  TOP w0.254: U1.J16 v4(107.03,80.02)
  L3_SIG1 w0.254: v4(107.03,80.02) v6(107.43,79.77)
  L10_SIG4 w0.254: v11(107.83,80.02) v6(107.43,79.77)
  BOTTOM w0.381: v11(107.83,80.02) 108.51,80.02 C288.1
N19923831: length 1
  TOP w0.254: U1.K19 v4(106.23,77.62)
  L3_SIG1 w0.254: v4(106.23,77.62) v6(106.63,77.37)
  vias: v6(119.1,77.2) v10(117.98,77.72) v10(118.49,77.72) v11(117.98,77.72) v11(118.49,77.72)
N19923832: length 2.8
  TOP w0.254: U1.K16 v4(106.23,80.02)
  L3_SIG1 w0.254: v4(106.23,80.02) v6(106.63,79.77)
  L10_SIG4 w0.254: v11(107.03,80.02) v6(106.63,79.77)
  BOTTOM w0.381: C291.1 107.75,79.28 107.03,79.99 v11(107.03,80.02)
N19923833: length 2.1
  TOP w0.254: U1.K9 v4(106.23,86.41)
  L3_SIG1 w0.254: v6(106.63,86.66) v4(106.23,86.41)
  BOTTOM w0.381: v11(106.43,91.09) v11(106.43,91.55) C290.1
  vias: v6(106.65,92.79) v6(106.65,92.16)
N19923834: length 1
  TOP w0.254: U1.J19 v4(107.03,77.62)
  L3_SIG1 w0.254: v4(107.03,77.62) v6(107.43,77.37)
  vias: v6(114.25,74.63) v6(114.63,74.15) v10(114.68,72.52) v10(115.19,72.52) v11(114.68,72.52) v11(115.19,72.52)
N19923844: length 2.8
  TOP w0.254: U1.L9 v4(105.43,86.41)
  L3_SIG1 w0.254: v6(105.83,86.66) v4(105.43,86.41)
  L4_SIG2 w0.381: v6(105.83,86.66) 105.8,86.66 105.46,87
  BOTTOM w0.381: v11(104.39,91.14) 104.39,91.27 v11(104.65,91.52) 104.39,91.78 C293.1
  vias: v6(104.27,92.66) v6(104.27,92.03)
N19923845: length 2.6
  TOP w0.254: U1.P19 v4(103.03,77.62)
  L3_SIG1 w0.254: v4(103.03,77.62) v6(103.43,77.37)
  L10_SIG4 w0.254: v11(103.02,77.6) 103.06,77.6 v6(103.43,77.37)
  BOTTOM w0.254: C294.1 102.54,76.97 103.02,77.45 v11(103.02,77.6)
N19923846: length 2.8
  TOP w0.254: U1.R20 v4(101.44,76.82)
  L10_SIG4 w0.381: v6(103.25,69.93) v11(102.87,69.55) v11(102.87,69.04)
  BOTTOM w0.381: C295.1 v11(102.87,69.04) v11(102.87,69.55)
N19923850: length 11
  TOP w0.254: U1.Y15 v4(97.44,80.82)
  L3_SIG1 w0.254: v4(97.44,80.82) v6(96.9,81.36)
  L9_SIG3 w0.635: v6(88.9,84.08) v6(88.21,84.08)
  L10_SIG4 w0.381: v6(88.9,84.08) v6(88.21,84.08)
  L10_SIG4 w0.635: 90.65,83.52 92.13,82.04 92.13,82.02 92.57,81.59 92.88,81.59 92.88,81.59 95.83,81.59 96.06,81.36 v6(96.9,81.36)
  BOTTOM w0.381: C299.1 v11(89.59,84.08) v11(90.09,84.08)
N19923851: length 7.8
  TOP w0.254: U1.Y14 v4(97.44,82.41)
  L3_SIG1 w0.254: v6(97.19,82.02) v4(97.44,82.41)
  L10_SIG4 w0.381: v11(91.9,83.39) 92.71,82.58 93.33,82.58 93.6,82.31 96.35,82.31 96.54,82.5 96.9,82.5 97.19,82.21 v6(97.19,82.02)
  BOTTOM w0.381: v11(91.9,83.39) 91.85,83.34 C298.1
N19923852: length 4.7
  TOP w0.254: U1.Y13 v4(97.44,83.21)
  L3_SIG1 w0.254: v6(97.04,83.46) v4(97.44,83.21)
  L10_SIG4 w0.254: v6(97.04,83.46) 97.36,83.26 v11(97.36,82.83)
  BOTTOM w0.381: 95.96,82.61 96.09,82.73 96.84,82.73 96.84,82.73 97.26,82.73 v11(97.36,82.83)
  BOTTOM w0.635: 95.96,82.61 94.85,82.61 94.73,82.73 C297.1
N19923853: length 2.2
  TOP w0.254: U1.T20 v4(100.64,76.82)
  L3_SIG1 w0.254: v4(100.64,76.82) 100.95,76.5 100.95,76.48 v6(100.97,76.48)
  BOTTOM w0.381: C296.1 v11(101.73,69.04) v11(101.73,69.55)
N19923865: length 3.5
  TOP w0.254: U1.Y16 v4(97.44,80.02)
  L3_SIG1 w0.254: v4(97.44,80.02) v6(97.04,79.77)
  L10_SIG4 w0.254: v6(97.04,79.77) 97.02,79.77 v11(96.69,80.1)
  BOTTOM w0.254: v11(96.69,80.1) 96.69,80.05 96.37,79.73 94.89,79.73 C300.1
N20127658: length 9.1
  TOP w0.254: U1.AB15 v4(95.84,80.82)
  L3_SIG1 w0.254: v4(95.84,80.82) 95.53,81.12
  L3_SIG1 w0.381: v6(89.97,82.26) 90.16,82.26 90.45,81.97 93.79,81.97 94.46,81.31 95.34,81.31 95.53,81.12
  L10_SIG4 w0.381: v11(90.04,82.78) v11(89.61,82.78) v6(89.03,82.78)
  BOTTOM w0.381: v11(90.04,82.78) v11(89.61,82.78) C403.1
  vias: v6(82.68,85.85) v6(83.44,85.85) v6(88.37,82.78) v8(82.17,86.36) v8(82.17,85.47) v9(82.17,86.36) v9(82.17,85.47)
N20128389: length 5.4
  TOP w0.254: U1.AB13 v4(95.84,83.21)
  L3_SIG1 w0.254: v4(95.84,83.21) 96.15,82.9 v6(96.2,82.9)
  L10_SIG4 w0.254: v11(95.84,83.22) 96.16,82.9 v6(96.2,82.9)
  BOTTOM w0.254: 92.35,84.13 92.9,83.58 95.47,83.58 v11(95.84,83.22)
N20144297: length 3.9
  BOTTOM w0.173: U89.A9 155.32,98.24 156.72,99.64 R637.2
N20190363: length 5.3
  TOP w0.173: R639.4 64.96,76.34 65.28,76.03 C454.2 68.58,76.03 J40.2
N20190375: length 5.4
  TOP w0.173: J40.1 68.58,75.01 C454.1 65.53,75.01 64.96,74.44 R639.3
N20190748: length 5.2
  TOP w0.173: J41.1 105.79,139.27 C455.2 105.79,136.39 R640.3
N20190772: length 5.2
  TOP w0.173: R640.4 104.77,136.39 C455.1 104.77,139.27 J41.2
N20190931: length 5.2
  TOP w0.173: J42.1 113.16,139.02 C456.2 113.16,136.27 R641.3
N20190955: length 5.1
  TOP w0.173: J42.2 112.14,139.27 C456.1 112.14,136.27 R641.4
N20191205: length 5.2
  TOP w0.173: R642.3 122.15,136.76 C457.2 121.28,139.15 J43.1
N20191229: length 5.2
  TOP w0.173: 119.51,139.91 120.27,139.15 C457.1 119.4,136.76 R642.4
N20202943: length 15.7
  TOP w0.173: U3.F8 v5(140.64,127.13) ; TP21.1 146.94,137.11 v5(146.94,136.99)
  L3_SIG1 w0.109: v5(146.94,136.99) 146.18,136.99 142.82,133.63 142.82,131.48 141.82,130.48 141.82,130.17 141.6,129.95 141.3,129.95 141.02,129.68 141.02,129.37 140.27,128.61 140.27,127.5 v5(140.64,127.13)
N20204523: length 27.3
  TOP w0.173: v6(74.42,73.66) v5(73.66,73.66) ; U1.AC17 v4(95.04,79.22)
  L3_SIG1 w0.109: v5(73.66,73.66) v6(74.42,73.66) ; v4(95.04,79.22) v6(94.64,78.97)
  L9_SIG3 w0.114: v6(94.64,78.97) 94.09,78.97 93.13,78 89.05,78 86.72,75.67 78.77,75.67 77.48,76.96 75.56,76.96 74.42,75.82 v6(74.42,73.66)
N20275163: length 4.3
  TOP w0.173: U79.8 157.43,122.27 C460.1
N20287248: length 5.6
  TOP w0.381: U79.2 158.08,121.37 158.46,121.75 159.77,121.75 160.44,121.07 R647.1 R648.2
N20287275: length 2
  TOP w0.173: R646.2 157.43,118.44 U79.1
N20287568: length 1.5
  TOP w0.173: R646.1 157.39,115.91 C463.1
N20301491: length 6
  TOP w0.173: 45.59,37.72 44.58,37.72 44.58,34.22 J22.A1
N20338433: length 6.7
  TOP w0.173: R655.2 R654.1 56.01,26.85 55.73,27.13 55.73,30.56 J22.B11
N20537306: length 5.8
  TOP w0.173: U44.2 56.9,42.47 56.53,42.84 55.62,42.84 54.91,43.54 54.91,44.12 55.24,44.45 55.96,44.45 56.22,44.71 U85.4
N20594970: length 2.1
  BOTTOM w0.173: R678.1 71.48,117.15 U86.1
N20595300: length 2
  TOP w0.173: R679.1 158.73,118.46 U79.3
N20631200: length 2.5
  TOP w0.173: 142.11,10.41 142.11,11.43 142.19,11.51 Q16.G
N20664562: length 1.3
  BOTTOM w0.254: 154.61,107.54 154.97,107.18 U62.B1 U62.B2
N20664572: length 3
  BOTTOM w0.102: U62.C4 U62.B3
  BOTTOM w0.13: U62.C4 U62.D4 155.77,105.12 155.88,105.01 155.88,104.11 C417.1 ; U62.B3 U62.A3
N20665027: length 1.5
  BOTTOM w0.254: U62.D2 U62.D1 155.77,107.3 156.13,107.66
N20706534: length 2.4
  TOP w0.173: U65.7 173.79,74.18 R554.2
N20706536: length 2.7
  TOP w0.173: R555.2 174.19,73.56 U65.6
N20706626: length 14.5
  TOP w0.173: v1(174.5,69.17) 173.79,69.88 U65.2 ; R477.1 v1(163.63,69.98)
  BOTTOM w0.173: v1(163.63,69.98) 164.44,69.17 v1(174.5,69.17)
N20706635: length 10.4
  TOP w0.173: U65.3 174.19,70.24 v1(174.5,69.93) ; v1(166.93,70.19) R483.1
  BOTTOM w0.173: v1(166.93,70.19) 167.69,70.95 173.48,70.95 v1(174.5,69.93)
N20721609: length 2.6
  BOTTOM w0.173: Q3.G 11.24,9.23 10.03,9.23 R251.2 R247.2
N20721766: length 4
  BOTTOM w0.173: R242.1 10.03,11.22 10.88,10.37 Q3.D
N20721850: length 3.9
  BOTTOM w0.173: Q1.D 10.88,3.76 10.03,4.61 10.03,4.7
N20722196: length 12.9
  TOP w0.173: v1(8.28,11.38) 8.97,10.7 8.97,10.54 12.34,7.17 12.34,5.73 13.09,4.97 13.09,4.38 12.65,3.94 11.61,3.94 11.37,3.7 D16.3
  BOTTOM w0.173: v1(8.28,11.38) 8.97,11.38 9.02,11.43
N20722199: length 3.9
  BOTTOM w0.173: R249.1 10.03,7.92 10.88,7.07 Q5.D
N20722204: length 8.1
  TOP w0.173: v1(8.31,7.96) 7.74,7.39 7.74,4.56 8.11,4.19 8.5,4.19 8.55,4.23 9.36,4.23 9.97,3.62 D16.4
  BOTTOM w0.173: 9.02,8 8.97,7.96 v1(8.31,7.96)
N20722213: length 3.1
  TOP w0.173: D16.2 9.97,5.85 8.77,4.65 v1(8.31,4.65)
  BOTTOM w0.173: 9.02,4.7 8.97,4.65 v1(8.31,4.65)
N20722605: length 2.5
  BOTTOM w0.173: Q2.G 17.84,2.62 R246.2 R243.1
N20722618: length 2.5
  BOTTOM w0.173: Q6.G 17.84,5.92 R256.2 R254.2
N20722739: length 2.6
  BOTTOM w0.173: Q4.G 17.84,9.23 16.64,9.23 R252.2 R248.2
N20722773: length 4
  BOTTOM w0.173: Q4.D 17.48,10.37 16.64,11.21 R244.1
N20722790: length 3.9
  BOTTOM w0.173: Q2.D 17.48,3.76 16.64,4.6 16.64,4.7
N20722809: length 10.7
  TOP w0.173: v1(14.88,11.38) 16.53,9.74 16.53,4.82 15.56,3.85 D17.3
  BOTTOM w0.173: R244.2 15.58,11.38 v1(14.88,11.38)
N20722811: length 3.9
  BOTTOM w0.173: Q6.D 17.44,7.07 16.64,7.87 R250.1
N20722815: length 7.9
  TOP w0.173: D17.4 14.16,4.48 13.16,5.48 13.16,7.24 13.87,7.96 v1(14.91,7.96)
  BOTTOM w0.173: v1(14.91,7.96) 15.58,7.96 R250.2
N20722821: length 2.5
  TOP w0.173: v1(14.91,4.65) 14.83,4.65 14.16,5.32 D17.2
  BOTTOM w0.173: R240.2 15.58,4.65 v1(14.91,4.65)
N20723137: length 2.5
  BOTTOM w0.173: R600.1 R599.2 11.24,12.78 Q11.G
N20723150: length 2.6
  BOTTOM w0.173: Q10.G 11.24,19.39 10.03,19.39 R595.2 R594.2
N20723271: length 2.5
  BOTTOM w0.173: Q15.G 11.24,16.08 R591.2 R590.2
N20723305: length 3.9
  BOTTOM w0.173: Q15.D 10.88,17.23 10.03,18.08 R589.1
N20723322: length 3.9
  BOTTOM w0.173: R596.1 10.03,14.77 10.88,13.92 Q11.D
N20723341: length 23.4
  TOP w0.173: v1(8.31,18.12) 10.46,18.12 14.14,14.44 15.03,14.44 15.35,14.12 15.35,14.04 20.34,9.05 20.34,3.78 19.37,2.81 D18.3
  BOTTOM w0.173: v1(8.31,18.12) 8.97,18.12 9.02,18.16
N20723343: length 4
  BOTTOM w0.173: Q10.D 10.88,20.53 10.03,21.38 R601.1
N20723347: length 28.4
  TOP w0.173: D18.4 17.97,3.98 17.14,4.8 17.14,9.99 15.17,11.96 8.2,11.96 7.58,12.58 7.58,20.87 v1(8.28,21.57)
  BOTTOM w0.173: 9.02,21.59 9,21.57 v1(8.28,21.57)
N20723353: length 16.2
  TOP w0.173: v1(8.31,14.81) 9.7,14.81 11.26,13.25 13.73,13.25 14.66,12.31 15.5,12.31 17.97,9.84 D18.2
  BOTTOM w0.173: 9.02,14.86 8.97,14.81 v1(8.31,14.81)
N20723697: length 2.5
  BOTTOM w0.173: R514.1 R597.2 17.97,12.91 Q13.G
N20723710: length 2.5
  BOTTOM w0.173: R598.2 R515.2 16.71,16.29 Q12.G
N20723831: length 2.6
  BOTTOM w0.173: Q14.G 17.84,19.51 16.64,19.51 R592.2 R593.2
N20723865: length 4
  BOTTOM w0.173: Q14.D 17.49,20.66 16.64,21.51 R603.1
N20723882: length 4
  BOTTOM w0.173: Q13.D 17.49,13.92 16.64,14.77 R604.1
N20723901: length 25.2
  TOP w0.173: D19.3 24.21,2.57 24.81,3.16 24.81,10.75 18.06,17.5 18.06,18.47 v1(14.83,21.7)
  BOTTOM w0.173: v1(14.83,21.7) 15.6,21.7 R603.2
N20723903: length 4
  BOTTOM w0.173: Q12.D 17.49,17.23 16.64,18.08 R602.1
N20723907: length 23.3
  TOP w0.173: D19.4 21.91,3.82 22.35,4.27 23.95,4.27 24.46,4.77 24.46,10.34 16.56,18.24 v1(14.91,18.24)
  BOTTOM w0.173: v1(14.91,18.24) 15.58,18.24 R602.2
N20723913: length 13.7
  TOP w0.173: D19.2 21.91,10.05 17.01,14.94 v1(14.91,14.94)
  BOTTOM w0.173: v1(14.91,14.94) 15.58,14.94 R604.2
N20729664: length 1.3
  BOTTOM w0.173: R699.1 80.01,104.25 Q20.D
N20729666: length 14.4
  TOP w0.173: v1(74.93,97.79) 74.93,97.74 73.7,96.51 73.03,96.51 72.2,97.35 D22.4
  BOTTOM w0.173: R699.2 78.23,104.77 78.23,104.35 76.58,102.7 76.58,101.68 76.17,101.27 75.67,101.27 75.06,100.67 75.06,99.88 74.93,99.75 v1(74.93,97.79)
N20729672: length 7.3
  TOP w0.173: v1(74.5,103.61) 74.28,103.82 71.94,103.82 71.59,103.48 71.59,102.73 72.2,102.13 D22.2
  BOTTOM w0.173: v1(74.5,103.61) 75.56,104.68 R696.2
N20729903: length 2.4
  BOTTOM w0.173: R697.2 R698.1 77.49,100.81 Q21.G
N20729915: length 2.7
  BOTTOM w0.173: R695.2 R694.2 81.03,102.11 Q20.G
N20730029: length 2.6
  BOTTOM w0.173: R700.2 R701.2 74.04,102.19 Q22.G
N20730054: length 1.3
  BOTTOM w0.173: Q22.D 73.12,105.51 R693.1
N20730079: length 1.3
  BOTTOM w0.173: Q21.D 76.58,104.25 R696.1
N20730095: length 12.9
  TOP w0.173: v1(73.51,96.98) 73.6,97.07 D22.3
  BOTTOM w0.173: R693.2 71.32,104.72 71.32,97.12 72.05,96.39 72.92,96.39 v1(73.51,96.98)
N20730773: length 2.2
  BOTTOM w0.173: R708.1 67.75,95.06 Q23.D
N20730775: length 4.2
  TOP w0.173: D23.4 67.82,97.46 67.82,96.86 v1(66.8,95.84)
  BOTTOM w0.173: v1(66.8,95.84) 66.69,95.72 66.69,95.56 66.67,95.55 R708.2
N20730781: length 16.4
  TOP w0.173: v1(66.29,90.63) 66.29,101.3 66.9,101.91 D23.2
  BOTTOM w0.173: R705.2 68.66,89.36 67.56,89.36 v1(66.29,90.63)
N20730789: length 2.6
  BOTTOM w0.173: Q24.G 70.66,84.59 R707.1 R706.2
N20730805: length 2.6
  BOTTOM w0.173: Q23.G 70.79,91.7 R703.2 R704.2
N20730910: length 2.6
  BOTTOM w0.173: R709.2 R710.2 70.28,98.81 Q25.G
N20730936: length 1.3
  BOTTOM w0.173: R702.1 Q25.D
N20730961: length 1.5
  BOTTOM w0.173: Q24.D R705.1
N20730985: length 7.7
  TOP w0.173: v1(67.18,101.3) 68.45,100.03 69.85,100.03 70.17,99.71 D23.3
  BOTTOM w0.173: v1(67.18,101.3) 67.23,101.3 68.33,102.4 R702.2
N20825141: length 7.4
  TOP w0.173: U1.N1 103.43,94.86 104.11,95.54 104.11,98.6 104.65,99.14 R690.2
N20825143: length 14.7
  TOP w0.173: U1.M5 v4(104.63,89.61) ; R691.2 105.92,99.04 v5(105.28,98.4)
  L3_SIG1 w0.099: v4(104.63,89.61) 104.63,89.51 104.13,89 104.13,88.69 103.96,88.52 103.71,88.52 103.33,88.91 103.33,91.34 103.2,91.46 103.2,94.08 103.05,94.23 103.05,94.75 103.56,95.26 103.56,96.93 104.37,97.74
  L3_SIG1 w0.109: v5(105.28,98.4) 104.75,98.4 104.37,98.02 104.37,97.74
N20825145: length 16.9
  TOP w0.173: R692.2 103.52,101.57 v5(102.96,101.57) ; U1.M3 v4(104.63,91.21)
  L3_SIG1 w0.099: 106.05,97.92 104.27,96.14 104.27,94.22 103.87,93.82 103.87,91.85 104.26,91.46 104.39,91.46 v4(104.63,91.21)
  L3_SIG1 w0.109: 106.05,97.92 106.05,99.5 106.62,100.07 106.62,101.11 106.16,101.57 v5(102.96,101.57)
N20825147: length 13.5
  TOP w0.173: v5(104.95,97.83) 106.23,97.83 106.93,98.53 R732.2 ; U1.N6 v4(103.83,88.81)
  L3_SIG1 w0.099: v4(103.83,88.81) 103.83,89.2 103.53,89.51 103.53,91.42 103.4,91.54 103.4,94.16 103.25,94.31 103.25,94.65 103.76,95.15 103.76,96.64 v5(104.95,97.83)
N20825149: length 13.7
  TOP w0.173: R733.2 105.58,101.47 v5(105.58,101.12) ; U1.M4 v4(104.63,90.41)
  L3_SIG1 w0.099: 105.74,98.01 104.01,96.28 104.01,94.25 103.6,93.84 103.6,91.83 104.63,90.8 v4(104.63,90.41)
  L3_SIG1 w0.109: v5(105.58,101.12) 105.58,98.94 105.74,98.79 105.74,98.01
N20825151: length 11.1
  TOP w0.173: R734.2 105.03,101.28 105.12,101.2 105.12,100.6 105.2,100.51 105.2,99.04 104.46,98.29 104.46,95.5 103.83,94.87 103.83,92.01 U1.N2
N20962931: length 6.1
  TOP w0.173: J18.58 v7(188.75,83.12)
  BOTTOM w0.173: C421.1 187.22,81.78 R149.1 ; U19.2 R149.1 ; R149.1 188.73,83.14 v7(188.75,83.12)
N21013400: length 8
  TOP w0.173: U1.B14 112.64,81.62 116.46,81.62 117.09,80.98 119.63,80.98 R662.2
N21013403: length 46
  TOP w0.173: v5(104.09,112.1) 104.77,112.1 R663.2 ; U1.J14 v4(107.03,82.41)
  L3_SIG1 w0.109: v6(99.29,112.7) 99.54,112.96 103.23,112.96 v5(104.09,112.1) ; v6(107.43,82.66) 107.43,82.66 107.03,82.42 v4(107.03,82.41)
  L4_SIG2 w0.114: v6(107.43,82.66) 107.82,83.05 107.82,84.43 107.59,84.65 103.3,84.65 102.26,85.69 102.26,91.64 100.36,93.55 100.36,99.95 100.9,100.49 100.9,101.72 97.83,104.79 97.83,111.24 v6(99.29,112.7)
N21013406: length 27.9
  TOP w0.173: U1.G13 v4(108.63,83.21)
  L3_SIG1 w0.109: v6(109.03,83.46) v4(108.63,83.21)
  L4_SIG2 w0.114: v6(109.03,83.46) 109.69,82.8 112.8,82.8 113.16,83.16 114.94,83.16 v6(115.44,82.65)
  L10_SIG4 w0.109: v6(115.44,82.65) v9(115.44,83.57)
  BOTTOM w0.173: v9(115.44,83.57) 114.81,83.57 112.39,85.98 112.39,88.47 112.17,88.7 112.17,93.88 108.58,97.46 R664.2
N21013409: length 40.1
  TOP w0.173: v5(103.03,112.51) 103.38,112.86 R665.2 ; U1.J11 v4(107.03,84.81)
  L3_SIG1 w0.109: v6(99.92,112.1) 102.62,112.1 v5(103.03,112.51) ; v4(107.03,84.81) v6(107.43,85.06)
  L4_SIG2 w0.114: v6(99.92,112.1) 98.12,110.29 98.12,105.08 101.19,102.01 101.19,100.36 100.81,99.98 100.81,93.45 102.54,91.72 102.54,86.21 103.29,85.45 107.04,85.45 v6(107.43,85.06)
N21036279: length 58.9
  TOP w0.173: v6(104.65,100.28) v5(104.65,101)
  L3_SIG1 w0.109: v5(104.65,101) v6(104.65,100.28)
  L4_SIG2 w0.114: v6(104.65,100.28) 104.65,100.68 102.79,102.54 101.6,102.54 98.71,105.43 98.71,109.79 100.69,111.76 100.69,114.19 98.31,116.56 98.31,129.31 98.91,129.9 98.91,132.18 99.47,132.74 99.47,133.58 102.67,136.78 102.67,140.62 106.37,144.33 106.37,148.05 J21.8
N21036281: length 60.3
  TOP w0.173: R691.1 105.92,100.59 106.17,100.84 v5(106.17,100.92)
  L3_SIG1 w0.109: v6(106.17,100.28) v5(106.17,100.92)
  L4_SIG2 w0.114: J21.10 108.32,147.99 108.32,145.71 105.16,142.55 105.16,138.77 100.62,134.23 100.62,131.48 99.98,130.83 99.98,127.69 99.59,127.3 99.26,127.3 98.88,126.93 98.88,121.9 100.99,119.79 100.99,111.64 99.01,109.65 99.01,105.82 101.94,102.88 102.86,102.88 105.46,100.28 v6(106.17,100.28)
N21036293: length 55.9
  TOP w0.173: v1(103.33,103.51) R692.1
  L4_SIG2 w0.114: v1(103.33,103.51) 102.9,103.94 101.4,103.94 99.3,106.03 99.3,109.52 101.3,111.51 101.3,119.98 100.2,121.08 100.2,124.69 99.69,125.2 99.69,125.72 100.42,126.45 100.42,130.86 100.92,131.35 100.92,134.02 105.24,138.34 106.52,138.34 107.9,139.71 107.9,141.99 110.32,144.41 110.32,147.99 J21.12
N21036295: length 62.4
  TOP w0.173: R732.1 107.34,100.69 v5(107.47,100.69)
  L3_SIG1 w0.109: v6(107.35,100.02) 107.35,100.56 v5(107.47,100.69)
  L4_SIG2 w0.114: J21.14 112.32,147.99 112.32,145.99 108.25,141.93 108.25,139.65 106.64,138.04 105.39,138.04 101.99,134.64 101.99,131.31 100.96,130.28 100.96,126.37 101.6,125.73 101.6,123.66 100.91,122.97 100.91,120.79 101.63,120.07 101.63,111.41 99.6,109.38 99.6,106.27 101.57,104.29 103.17,104.29 104.92,102.54 105.36,102.54 107.35,100.56 v6(107.35,100.02)
N21036304: length 59.5
  TOP w0.173: v1(106.05,103.64) R733.1
  L4_SIG2 w0.114: v1(106.05,103.64) 105.3,102.9 104.98,102.9 103.23,104.65 101.7,104.65 99.89,106.46 99.89,109.24 101.99,111.34 101.99,127.47 101.3,128.17 101.3,130.2 102.28,131.19 102.28,134.52 105.51,137.75 106.77,137.75 108.61,139.59 108.61,141.87 110.96,144.22 111.92,144.22 114.32,146.62 114.32,147.99 J21.16
N21036390: length 7.4
  TOP w0.173: R686.2 100.84,98.75 101.55,98.03 101.55,95.96 101.04,95.45 U1.T1
N21036392: length 7.2
  TOP w0.173: U1.P1 102.64,95.2 103.38,95.95 R688.2
N21036394: length 44.7
  TOP w0.173: U1.P7 v4(103.03,88.01) ; v5(103.15,119.81) 104.27,120.92 R689.2
  L3_SIG1 w0.109: v5(103.15,119.81) 103.5,119.81 v6(103.79,120.1) ; v4(103.03,88.01) 103.43,88.26 v6(103.43,88.26)
  L4_SIG2 w0.114: v6(103.43,88.26) 103,88.7 103,90.78 102.97,90.78 102.77,90.98 102.77,94.97 103.07,95.28 103.07,97.2 104.96,99.09 107.49,99.09 108.1,99.69 108.1,100.97 106.78,102.29 106.78,104.22 106.35,104.65 104.52,104.65 103.53,105.64 102.71,105.64 101.52,106.83 101.52,108.37 103.13,109.98 103.13,118.05 103.79,118.71 v6(103.79,120.1)
N21036619: length 96.3
  TOP w0.173: v1(105.03,103.62) R734.1
  L4_SIG2 w0.114: v1(105.03,103.62) 104.71,103.62 103.35,104.98 101.88,104.98 100.46,106.4 100.46,109.4 102.28,111.22 102.28,118.03 103.05,118.8 103.05,119.91 102.28,120.68 102.28,127.66 101.59,128.36 101.59,130.08 102.58,131.07 102.58,134.28 105.75,137.45 106.89,137.45 108.92,139.48 108.92,141.76 111.08,143.92 113.62,143.92 116.32,146.62 116.32,150.11 117.28,151.07 149.29,151.07 J21.52
N21099488: length 6
  BOTTOM w0.083: U43.C2 93.13,129.7 93.13,130.51
  BOTTOM w0.173: 93.13,130.51 93.13,135.29 C265.1
N21180149: length 15.6
  TOP w0.173: TP22.1 125.76,78.8 117.89,78.8 115.87,80.81 112.64,80.81 U1.B15
N21180152: length 16.7
  TOP w0.173: TP23.1 127.3,79.15 118.03,79.15 115.97,81.21 U1.A15
N21306186: length 8.5
  TOP w0.173: TP24.1 v1(158.55,94.37)
  BOTTOM w0.173: v1(158.55,94.37) 158.55,95.31 157.87,95.98 156.2,95.98 155.75,96.42 154.39,96.42 153.95,95.98 153.08,95.98 U89.B6
N21306311: length 3.3
  BOTTOM w0.173: U89.A8 156.69,97.59 R567.1
N21306314: length 4.4
  BOTTOM w0.173: U89.B8 153.1,97.26 156.06,97.26 R585.1
N21307911: length 3.5
  BOTTOM w0.173: U89.K6 145.87,96.29 145.54,95.97 144.53,95.97 R586.1
N21519094: length 4.9
  BOTTOM w0.173: R754.2 143.23,41.07 143.23,45.3 U90.L8
N21519152: length 5.1
  BOTTOM w0.173: R755.2 142.48,56.86 142.48,60.44 142.84,60.8 U91.L8
N21552786: length 1.8
  BOTTOM w0.173: U92.1 158.27,54.79 C544.1
N21553219: length 2
  TOP w0.173: 140.84,71.46 R780.1
  TOP w0.381: R781.1 R780.1 ; C529.1 140.84,71.46
N21553307: length 1.8
  BOTTOM w0.305: U92.7 162.55,57.99 R783.1
N21553371: length 1.5
  BOTTOM w0.305: U92.9 162.82,56.98 R782.1
N21553379: length 2.9
  BOTTOM w0.173: R784.1 C533.1 158.27,60.05 U92.5
N21605448: length 5.9
  TOP w0.508: 13.54,41.96 J50.1 ; J50.1 15.67,41.96 ; J50.1 13.08,40.89 ; J50.1 16,40.89
N21620210: length 19.3
  L10_SIG4 w0.109: v9(178.96,72.18) 177.13,70.35 177.13,65.81 176.43,65.11 v9(176.43,57.4)
  BOTTOM w0.173: U72.3 v9(178.96,72.18) ; R368.1 C197.1 v9(176.43,57.4)
N21620213: length 22.4
  L10_SIG4 w0.109: v9(180.26,72.18) 178.69,70.61 178.69,66.38 177.15,64.84 177.15,64 177.17,63.99 177.17,55.6 v9(176.43,54.86)
  BOTTOM w0.173: R370.1 C198.1 v9(176.43,54.86) ; U72.5 v9(180.26,72.18)
N21620216: length 26
  L10_SIG4 w0.109: v9(181.56,72.18) 180.11,70.73 180.11,66.5 178.31,64.7 178.31,63.84 177.67,63.2 177.67,58.88 178.31,58.25 178.31,54.2 v9(176.43,52.32)
  BOTTOM w0.173: v9(176.43,52.32) C199.1 R372.1 ; U72.7 v9(181.56,72.18)
N21620219: length 28.5
  L10_SIG4 w0.109: v9(176.43,49.78) 179.18,52.53 179.18,64.32 181.25,66.4 181.25,70.57 v9(182.86,72.18)
  BOTTOM w0.173: v9(176.43,49.78) C200.1 R374.1 ; U72.9 v9(182.86,72.18)
N21620222: length 31.6
  L10_SIG4 w0.109: v9(184.16,72.18) 182.5,70.52 182.5,66.12 180.98,64.6 180.98,63.96 180.34,63.33 180.34,55.22 179.71,54.59 179.71,50.52 v9(176.43,47.24)
  BOTTOM w0.173: U72.11 v9(184.16,72.18) ; v9(176.43,47.24) C201.1 R373.1
N21620225: length 30.6
  L10_SIG4 w0.109: v9(184.16,64.22) 183.39,63.44 183.39,51.66 182.75,51.03 v9(182.75,44.28)
  BOTTOM w0.173: R375.1 C202.1 176.43,44.63 176.78,44.28 v9(182.75,44.28) ; U72.18 v9(184.16,64.22)
N21620228: length 32.1
  L10_SIG4 w0.109: v9(181.74,41.61) 181.74,50.63 182.86,51.76 v9(182.86,64.22)
  BOTTOM w0.173: v9(181.74,41.61) 176.98,41.61 176.43,42.16 C203.1 R376.1 ; U72.20 v9(182.86,64.22)
N21620231: length 33.3
  L10_SIG4 w0.109: v9(180.98,39.32) 180.98,50.88 181.56,51.47 v9(181.56,64.22)
  BOTTOM w0.173: R378.1 C204.1 176.43,39.68 176.78,39.32 v9(180.98,39.32) ; U72.22 v9(181.56,64.22)
N21685968: length 1
  TOP w0.173: U1.K14 v4(106.23,82.41)
  L3_SIG1 w0.254: v4(106.23,82.41) v6(106.63,82.66)
  vias: v6(116.84,82) v6(117.86,82) v8(118.87,82) v8(118.87,81.15) v9(118.87,82) v9(118.87,81.15)
N21685998: length 3.4
  TOP w0.173: R638.1 R798.2 J46.4
N21823186: length 5.2
  TOP w0.173: J47.2 65.91,49.74 65.91,52.4 66.61,53.1 R801.4
N21823194: length 5
  TOP w0.173: R801.3 64.45,53.1 64.9,52.66 C549.1 64.9,49.48 J47.1
N21877717: length 8.3
  TOP w0.173: U1.AE5 93.83,89.21 93.43,88.82 88.92,88.82 88.41,89.32 86.46,89.32 86.29,89.49 R659.2
N21877759: length 5.7
  TOP w0.173: R660.2 92.84,94.13 93.83,93.14 U1.AE1
N21905162: length 8.1
  TOP w0.173: U1.AG3 91.84,91.21 90.22,91.21 86.06,95.38 R802.1
N21905296: length 6.4
  TOP w0.173: U1.AH5 89.3,89.21 87,91.52 R803.1
N22373548: length 7
  TOP w0.173: R809.2 93.98,96.94 93.31,96.27 93.31,94.3 93.34,94.11 94.24,93.22 94.24,92.01 U1.AD2
N22373612: length 7.1
  TOP w0.173: 146.3,136.53 R810.1 146.43,137.92 147.19,138.68 147.19,141.1 147.83,141.73 U96.2
N22427447: length 28
  TOP w0.173: v5(131.57,61.21) 131.06,60.71 R739.1 ; U1.C26 v4(111.83,72.02)
  L3_SIG1 w0.099: 113.16,72.31 112.13,72.31 v4(111.83,72.02)
  L3_SIG1 w0.109: 113.16,72.31 114.74,72.31 117.14,69.91 117.14,68.13 119.63,65.64 119.63,65.11 123.53,61.21 v5(131.57,61.21)
N22427459: length 27.4
  TOP w0.173: U1.B27 v4(112.63,71.22) ; R740.1 v5(132.21,60.71)
  L3_SIG1 w0.099: 114.48,70.72 114.35,70.59 113.68,70.59 113.51,70.75 113.47,70.79 113.06,70.79 v4(112.63,71.22)
  L3_SIG1 w0.109: 114.48,70.72 115.72,70.72 116.66,69.78 116.66,66.5 122.46,60.71 v5(132.21,60.71)
N22642197: length 13.7
  BOTTOM w0.173: R905.1 R300.2 R276.2 165.35,143 R903.2 X1.3
N22644059: length 4.3
  TOP w0.254: U3.K12 143.81,123.17 v1(143.83,123.17)
  BOTTOM w0.381: v1(143.83,123.17) 144.1,123.44 C562.1 144.53,125.09 144.91,125.48 R854.2
N22691021: length 21.9
  TOP w0.173: U1.F4 v4(109.43,90.41) ; R576.2 v5(106.81,106.93)
  L3_SIG1 w0.099: v4(109.43,90.41) 109.43,90.76 109.73,91.06 109.73,94.09
  L3_SIG1 w0.109: v5(106.81,106.93) 107.29,106.93 108.86,105.36 108.86,104.82 111.48,102.2 111.48,101.83 112.73,100.58 112.73,99.51 111.77,98.56 111.77,96.64 111.54,96.4 111.54,95.9 109.73,94.09
N22729003: length 4.1
  TOP w0.173: R861.1 129.92,145.6 J21.31
N22729012: length 3.6
  TOP w0.173: J21.33 133.22,146.9 R862.1
N22729021: length 3.5
  TOP w0.173: R863.1 135.26,146.93 J21.35
N22729030: length 3.5
  TOP w0.173: R864.1 137.29,146.96 J21.37
N22729576: length 7
  TOP w0.173: U1.AG6 91.83,88.01 90.08,88.01 89.75,88.34 89,88.34 88.42,88.93 86.51,88.93 R738.1
N22730116: length 10.6
  TOP w0.173: U1.AG4 91.84,89.62 89.75,89.62 87.16,92.2 84.71,92.2 84.5,92 83.74,92 R737.1
N22730128: length 9.4
  TOP w0.173: R736.1 83.24,92.41 84.4,92.41 84.55,92.55 87.2,92.55 89.74,90.02 U1.AH4
N22734288: length 6
  BOTTOM w0.173: U2.4 166.23,45.58 R917.1 166.12,45.59 165.35,46.35 163.96,46.35 163.58,45.97 U98.2
N22734327: length 8.9
  BOTTOM w0.173: U2.2 166.88,41.27 167.41,40.75 169.02,40.75 169.55,41.27 R916.1 170.56,43.94 170.56,45.76
N22734777: length 11
  TOP w0.173: v1(172.05,42.15) SW1.4 SW1.3
  BOTTOM w0.173: v1(172.05,42.15) 171.59,41.68 U49.1 170.56,42.93
N22735118: length 111.1
  L4_SIG2 w0.114: v1(148.59,77.17) 149.24,77.17 159.91,66.49 161.14,66.49 166.94,60.7 166.94,50.87 165.48,49.41 v1(165.48,47.83)
  BOTTOM w0.173: v1(165.48,47.83) 165.02,47.37 163.96,47.37 162.93,46.34 U98.1 ; R9.2 135.51,125.56 135.26,125.56 135.1,125.4 133.1,125.4 132.78,125.07 132.78,124.94 132.44,124.61 132.31,124.61 131.64,123.93 131.64,120.28 134.83,117.09 136.36,117.09 138.52,114.93 140,114.93 142.71,112.22 142.71,110 139.57,106.86 139.57,104.98 135,100.41 135,90.76 v1(148.59,77.17)
N22762383: length 29.5
  TOP w0.173: v5(70.36,79.63) 68.58,81.41 R925.1 ; U1.AC16 v4(95.04,80.02)
  L3_SIG1 w0.099: v4(95.04,80.02) 94.65,80.02 94.43,80.24 94.41,80.27 94.4,80.27 94.36,80.31 93.14,80.31 92.98,80.15
  L3_SIG1 w0.109: v5(70.36,79.63) 70.99,79.63 71.12,79.5 80.14,79.5 80.9,80.26 87.12,80.26 87.24,80.15 92.98,80.15
N22762388: length 25.2
  TOP w0.173: R924.1 75.39,74.73 75.39,75.41 v5(75.34,75.46) ; U1.AB16 v4(95.84,80.02)
  L3_SIG1 w0.109: v5(75.34,75.46) v6(75.34,76.07) ; v4(95.84,80.02) v6(95.44,79.77)
  L9_SIG3 w0.114: v6(95.44,79.77) 95.05,79.38 95.05,78.83 94.47,78.25 94.47,78.24 93.98,77.75 92.66,77.75 92.51,77.6 89.64,77.6 87.22,75.18 76.23,75.18 v6(75.34,76.07)
N24440306: length 2.6
  BOTTOM w0.173: X1.1 164.88,149.57 R902.1

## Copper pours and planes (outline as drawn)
AGND_GBETH0 on BOTTOM: 23.51,136.72 42.67,136.72 43.92,135.46 44.58,135.46 44.83,135.72 44.83,136.48 43.89,137.42 43.89,140.47 43.31,141.05 25.02,141.05 22.73,138.77 22.35,138.77 22.1,138.51 22.1,138.13
AGND_GBETH1 on BOTTOM: 45.72,136.72 64.9,136.72 66.55,138.37 66.55,140.78 66.29,141.03 46.48,141.03 45.21,142.3 44.58,142.3 44.32,142.05 44.32,138.11
AGND_PROFI on BOTTOM: 79.37,1.27 77.72,2.92 77.72,4.95 79.76,6.99 85.72,6.99 87.38,5.33 103.12,5.33 103.76,5.97 103.76,7.49 104.37,8.1 106.96,8.1 109.47,5.59 109.47,1.78 108.97,1.27
AGNDFRAME_PRU1ETH0 on BOTTOM: 12.07,120.86 14.61,120.86 15.11,121.37 15.11,137.37 16,138.26 17.78,138.26 18.03,138.51 18.03,140.8 16.64,142.19 12.32,142.19 11.68,141.56 11.68,121.24
AGNDFRAME_PRU1ETH1 on BOTTOM: 13.08,97.11 15.05,97.11 15.56,97.62 15.49,115.02 15.49,118.13 15.18,118.45 12.57,118.45 12.52,118.5 11.76,118.5 11.51,118.24 11.51,117.33 12.12,116.72 12.13,116.72 12.13,98.06
AGNDFRAME_PRU2ETH0 on BOTTOM: 12.45,72.85 14.8,72.85 15.3,73.36 15.3,90.76 15.56,91.01 15.56,93.87 15.24,94.19 12.19,94.19 11.87,93.87 11.87,73.42
AGNDFRAME_PRU2ETH1 on BOTTOM: 12.57,48.47 14.86,48.47 15.37,48.98 15.37,66.38 15.62,66.63 15.62,69.17 14.99,69.8 12.57,69.8 11.94,69.17 11.94,49.1
DGND on TOP: 155.45,127.46 157.1,127.46 157.35,127.21 157.35,125.94 156.72,125.3 155.45,125.3 155.19,125.56 155.19,127.21
DGND on TOP: 172.97,14.9 174.45,13.59 175.16,15.43 178.33,15.43 180.69,13.08 182.07,13.08 182.73,12.42 182.73,9.92 182.4,8.89 182.73,7.86 182.73,1.79 182.26,1.31 171.78,1.31 171.3,1.79 171.3,11.47 172.61,12.78 172.61,14.54 ; 2 cut-outs
DGND on TOP: 58.93,109.43 58.93,108.23 60.93,106.23 60.93,94.39 60.35,93.81 50.42,93.81 49.66,94.57 48.51,94.57 45.85,97.24 45.85,99.01 45.47,99.4 44.2,99.4 43.43,98.63 43.43,94.7 46.1,92.03 47.75,92.03 49.53,90.25 62.23,90.25 64.77,92.79 64.77,103.71 62.48,106 62.48,107.4 60.32,109.56 59.05,109.56 ; 2 cut-outs
DGND on TOP: 134.14,141.3 138.98,141.3 139.55,140.73 139.55,136.09 137.54,134.08 137.54,131.11 136.94,130.51 136.78,130.51 136.21,131.08 134.43,131.08 134.04,131.46 134.04,135.53 133.55,136.02 133.55,137.02 132.89,137.68 132.89,140.06
DGND on TOP: 147.96,97.87 152.15,97.87 152.53,97.49 152.53,96.47 152.91,96.09 152.91,94.32 152.65,94.06 150.37,94.06 149.61,93.3 149.1,93.3 148.59,93.81 148.59,95.2 147.7,96.09 147.7,97.62
DGND on TOP: 94.23,128.61 94.61,128.22 95.5,128.22 95.89,128.61 95.89,129.49 96.14,129.75 96.52,129.75 96.77,129.49 96.77,128.1 97.66,127.21 97.66,126.83 97.41,126.57 96.9,126.57 95.76,125.43 95.76,123.91 95.5,123.65 94.74,123.65 94.49,123.91 94.49,126.95 93.34,128.1 93.34,129.49 93.6,129.75 93.98,129.75 94.23,129.49
DGND on TOP: 37.57,63.5 39.88,63.5 40.49,62.9 40.49,57.87 40.11,57.49 37.8,57.49 37.72,57.41 37.24,57.89 37.24,63.17
DGND on TOP: 154.56,62.57 158.24,62.57 158.62,62.18 158.62,59.9 158.24,59.52 154.56,59.52 154.31,59.77 154.31,62.31
DGND on TOP: 106.55,17.4 106.05,17.4 105.28,18.16 103.5,18.16 102.87,18.8 102.87,19.94 103.12,20.19 105.54,20.19 105.79,19.94 105.79,18.67 106.55,17.91
DGND on TOP: 181,109.43 179.86,110.57 179.86,112.41 176.43,115.84 176.43,118.7 177.06,119.33 188.75,119.33 189.13,118.95 189.13,114.51 187.73,113.11 185.32,113.11 184.43,112.22 184.43,110.44 183.41,109.43 ; 2 cut-outs
DGND on TOP: 5.76,42.93 5.76,46.78 6.35,47.37 9.4,47.37 9.82,46.94 9.82,42.93 9.32,42.42 6.27,42.42
DGND on TOP: 95.58,82.47 101.07,82.47 101.37,82.78 101.37,82.88 100.51,83.74 100.51,85.67 100.69,85.85 101.07,85.85 101.3,85.62 101.3,84.48 101.68,84.1 102.13,84.1 102.36,83.87 102.36,81.94 102.57,81.74 102.67,81.74 103.5,82.58 104.5,82.58 104.5,82.63 105.26,83.39 105.61,83.39 105.7,83.3 105.7,83.07 105.51,82.88 105.51,82.58 105.71,82.37 105.71,81.89 105.79,81.81 106.96,81.81 107.31,81.46 107.31,80.67 107.29,80.64 102.49,80.64 102.13,81 101.57,81 101.22,80.64 94.82,80.64 94.06,81.41 94.06,82.09 93.52,82.63 93.52,83.06 94.03,83.57 94.49,83.57
DGND on TOP: 37.69,88.14 40,88.14 40.61,87.53 40.61,82.5 40.23,82.12 37.77,82.12 37.46,82.43 37.46,87.91
DGND on TOP: 67.44,91.52 78.99,91.52 82.04,88.47 82.04,85.85 80.61,84.42 79,84.42 78.38,85.04 67.69,85.04 67.31,85.43 67.31,91.39
DGND on TOP: 139.45,53.04 140.59,53.04 140.84,52.79 140.84,51.39 141.1,51.14 141.1,50.75 140.94,50.6 139.22,50.6 138.94,50.88 138.94,51.39 139.19,51.64 139.19,52.79
DGND on TOP: 176.64,5.23 176.64,7.14 176.81,7.31 177.74,7.31 177.91,7.15 177.91,5.4 177.34,4.83 177.04,4.83
DGND on TOP: 154.56,55.07 156.72,55.07 157.23,54.56 157.23,53.17 156.84,52.79 154.69,52.79 154.43,53.04 154.43,54.95
DGND on TOP: 25.78,105.87 23.88,107.78 21.54,107.78 17.27,112.04 16.13,112.04 15.49,112.68 15.49,114.97 14.97,115.49 14.97,116.33 15.17,116.53 15.98,116.53 16.38,116.14 16.38,116.03 22.38,110.04 24.89,110.04 27.66,107.27 34.04,107.27 37.46,110.7 38.48,110.7 38.73,110.44 38.73,109.68 34.92,105.87 ; 2 cut-outs
DGND on TOP: 5.97,38.82 7.41,38.82 7.62,38.61 7.62,35.39 7.37,35.13 5.97,35.13 5.71,35.39 5.71,38.56
DGND on TOP: 37.77,105.31 40.08,105.31 40.69,104.7 40.69,99.67 40.31,99.29 38,99.29 37.92,99.22 37.44,99.7 37.44,104.98
DGND on TOP: 137.16,63.2 138.43,63.2 138.68,62.95 138.68,61.42 138.18,60.91 136.65,60.91 136.4,61.17 136.4,62.44
DGND on TOP: 149.53,88.14 157.91,88.14 159.82,86.24 159.82,83.95 159.44,83.57 159.18,83.57 157.4,81.79 156.26,81.79 154.86,80.4 149.91,80.4 148.89,81.41 148.89,87.51
DGND on TOP: 5.84,34.54 6.99,34.54 7.24,34.29 7.24,31.24 6.99,30.99 5.84,30.99 5.59,31.24 5.59,34.29
